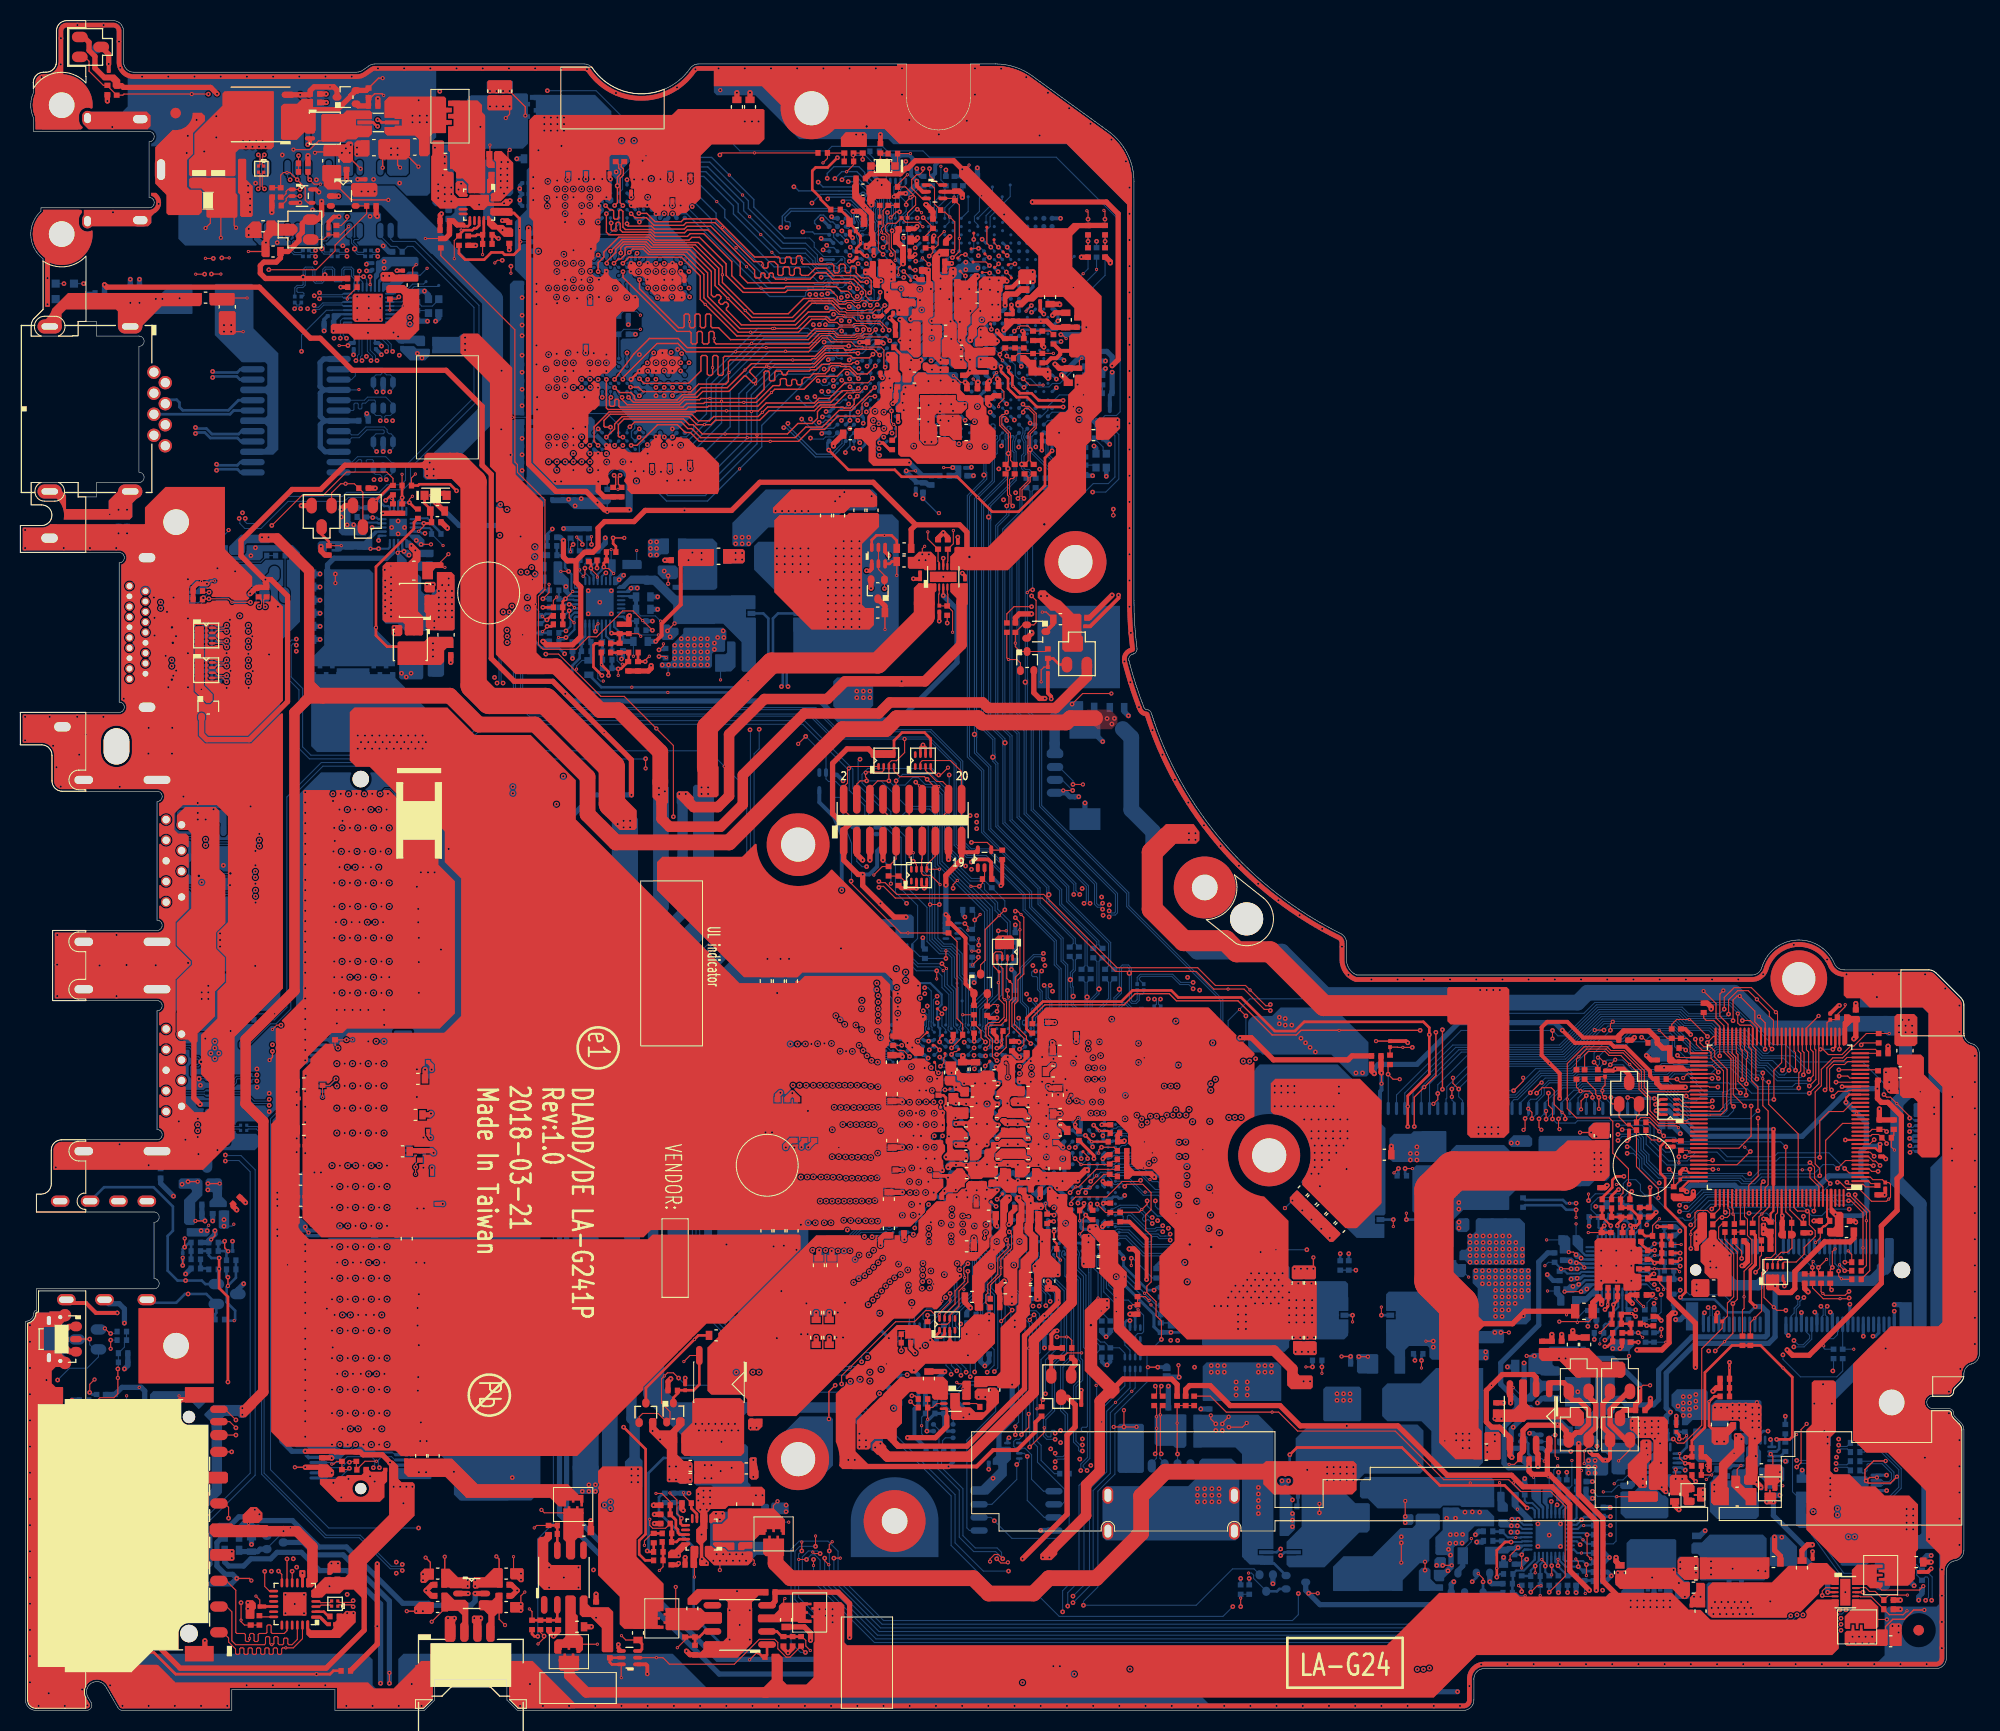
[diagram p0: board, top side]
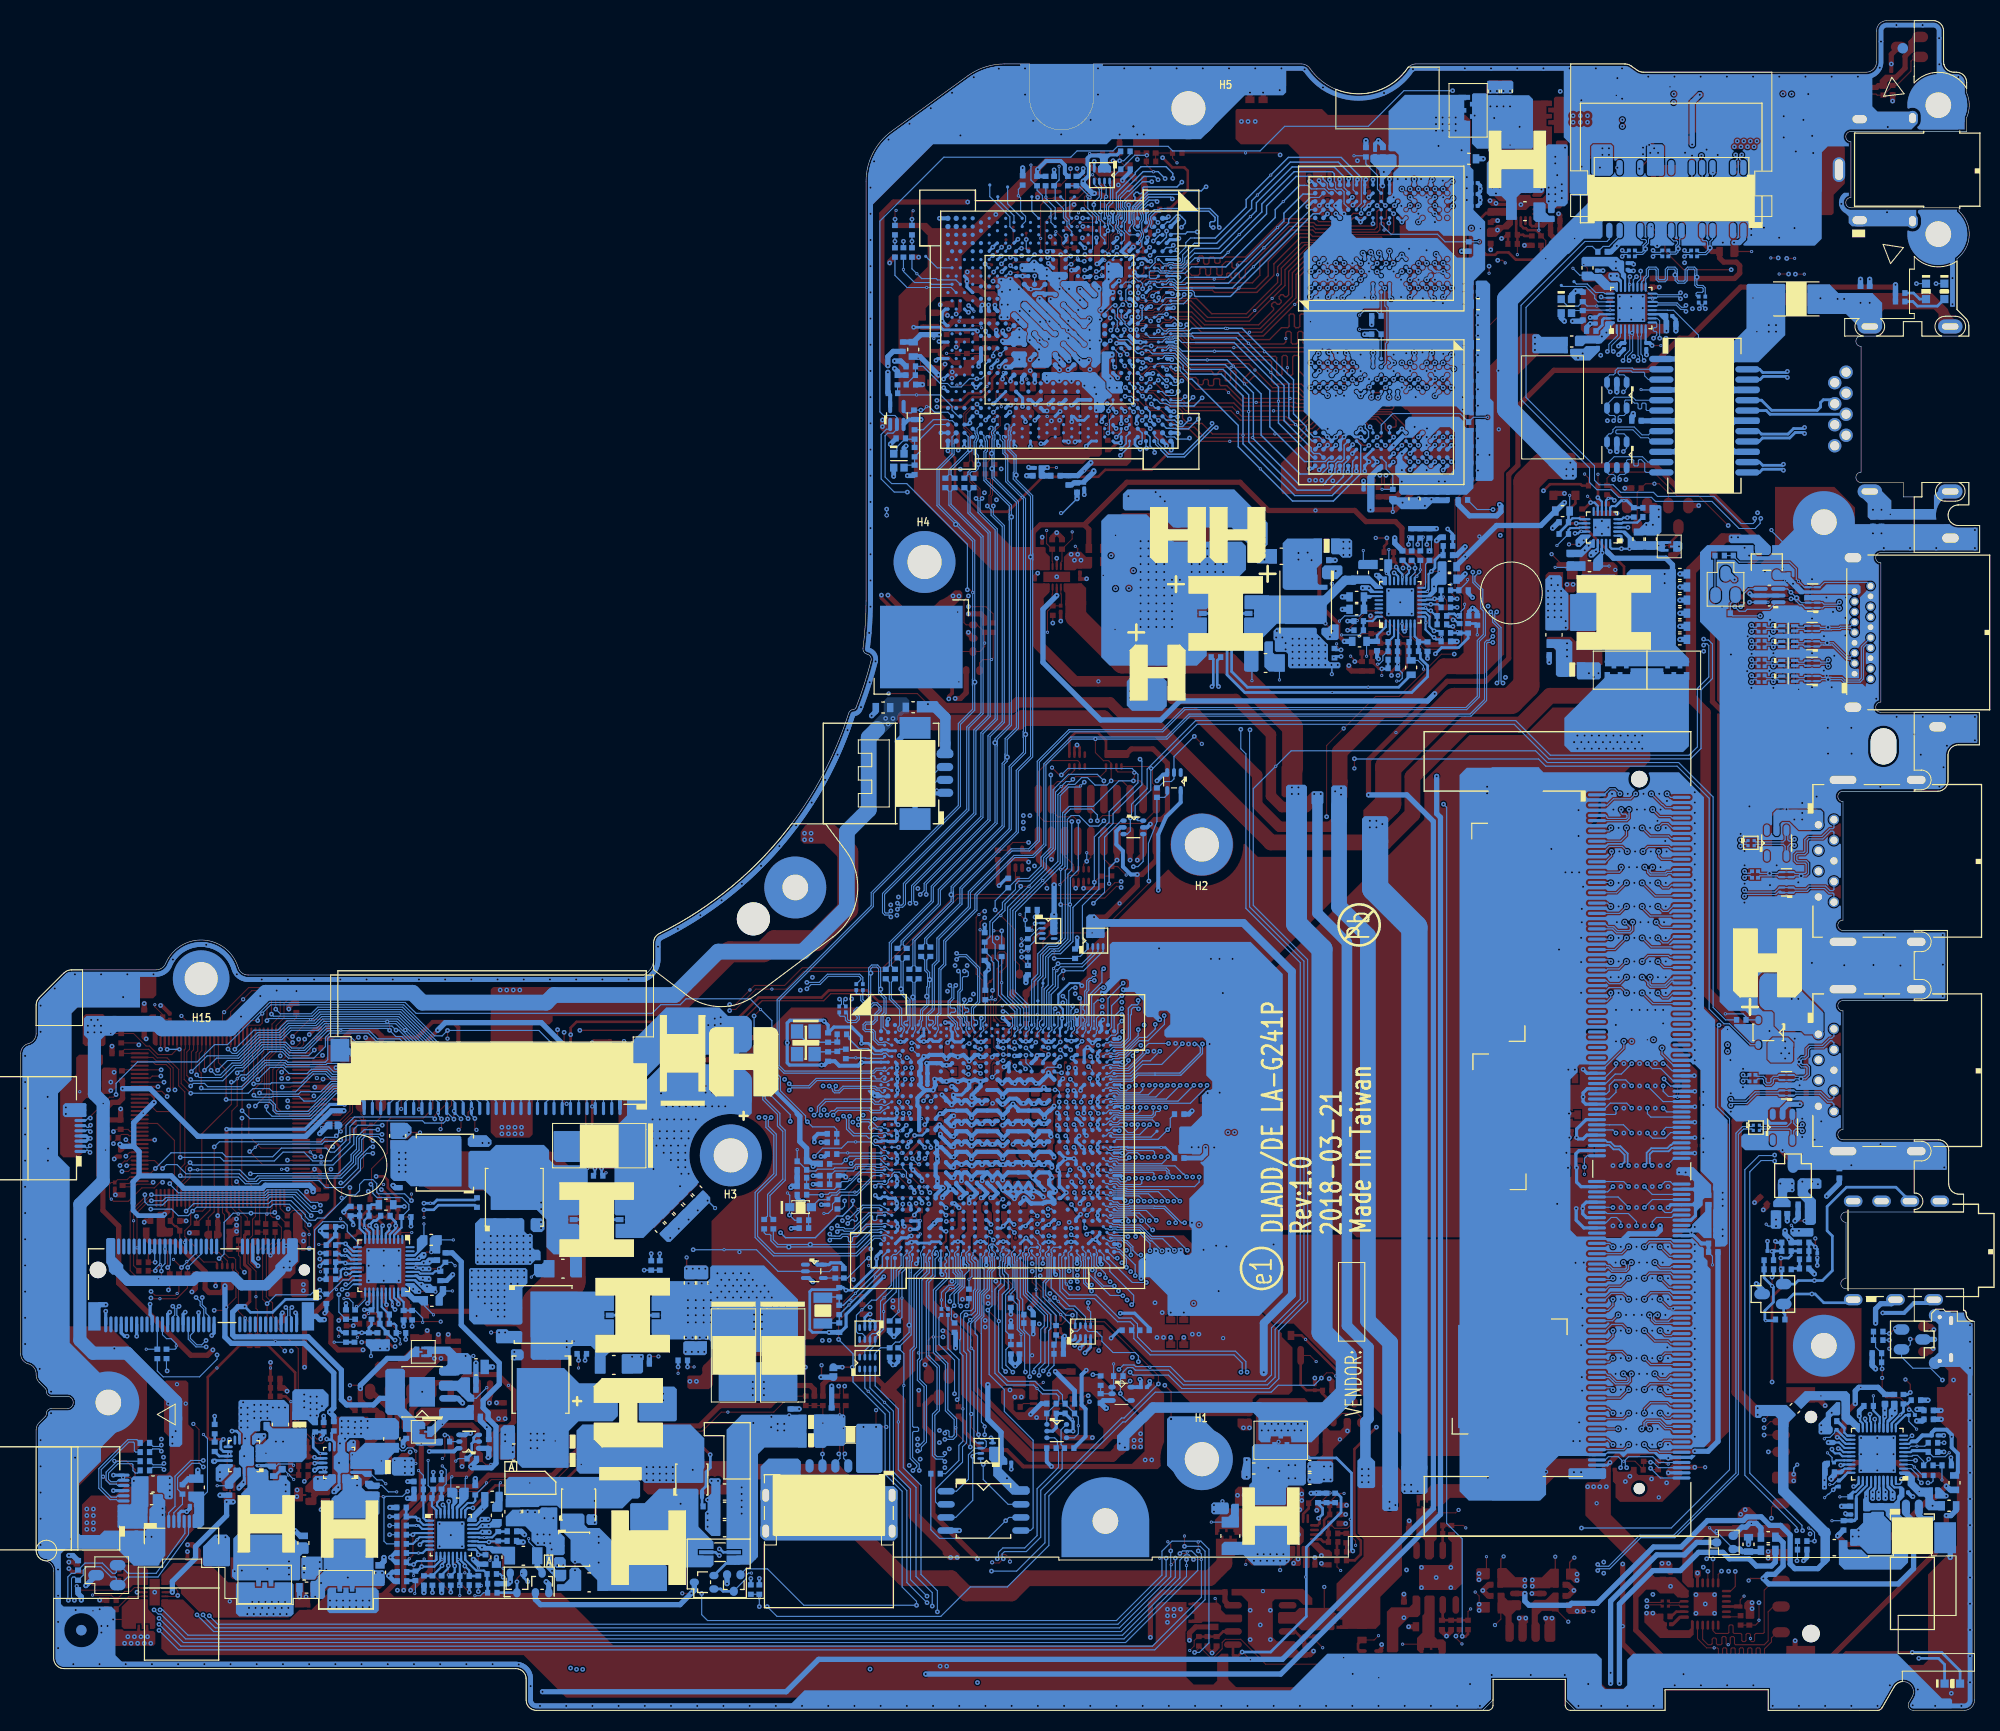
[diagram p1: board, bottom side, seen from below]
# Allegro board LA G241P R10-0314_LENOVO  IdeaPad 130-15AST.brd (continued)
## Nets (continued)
GND: C179.2 C180.2 C181.2 C182.2 C183.2 C187.1 C189.2 C190.2 C191.2 C193.2 C201.2 C202.2 C203.2 C204.2 C205.2 C216.1 C217.2 C232.2 C237.2 C238.2 C239.2 C243.2 C244.2 C271.2 C272.2 C275.2 C280.2 C281.2 C282.2 C303.2 C304.2 C305.2 C371.1 C823.2 C831.2 C832.2 C833.2 C834.2 C835.2 C836.2 C837.2 C838.1 C843.2 C844.2 C845.2 C846.2 C847.2 C848.2 C849.2 C850.2 C851.2 C852.2 C853.1 C854.1 C855.2 C856.2 C857.2 C858.2 C859.2 C860.2 C861.2 C2147.2 C2148.2 C2149.2 C2150.2 C2151.2 C2152.2 C2153.2 C2154.2 C2155.1 CA1.1 CA40.1 CA44.2 CA45.2 CA47.2 CA48.2 CA49.2 CA51.1 CA52.2 CA53.2 CA62.2 CA66.1 CA67.2 CA70.2 CA71.2 CC7.2 CC8.1 CC9.2 CC10.2 CC11.2 CC12.2 CC13.2 CC14.2 CC15.2 CC16.2 CC18.2 CC19.2 CC20.2 CC21.2 CC22.2 CC23.2 CC24.2 CC25.2 CC26.2 CC27.2 CC28.2 CC29.2 CC30.2 CC31.2 CC32.2 CC33.2 CC34.2 CC35.2 CC36.2 CC37.2 CC38.2 CC39.2 CC40.2 CC41.2 CC42.2 CC43.2 CC44.2 CC45.2 CC46.2 CC47.2 CC48.2 CC49.2 CC50.2 CC51.2 CC52.2 CC53.2 CC54.2 CC55.2 CC56.2 CC57.2 CC58.2 CC59.2 CC60.2 CC61.2 CC62.2 CC63.2 CC64.2 CC65.2 CC66.2 CC67.2 CC68.2 CC69.2 CC70.2 CC71.2 CC72.2 CC73.2 CC74.2 CC75.2 CC76.2 CC112.1 CC113.1 CC114.1 CC115.1 CC129.1 CC130.1 CC131.1 CC132.2 CC133.2 CC134.1 CC135.1 CC162.1 CD201.1 CD202.1 CD203.2 CD204.2 CD205.2 CD206.2 CD207.2 CD208.2 CD210.1 CD211.1 CD212.1 CD213.1 CD214.2 CD215.2 CD216.2 CD217.2 CD218.2 CD219.2 CD220.2 CD221.2 CD222.2 CD223.2 CD224.2 CD225.2 CD226.2 CD227.2 CD228.2 CD229.2 CD230.2 CD231.2 CH11.2 CH12.2 CL1.1 CL2.2 CL3.2 CL4.2 CL5.2 CL6.2 CL7.2 CL8.2 CL10.2 CL13.1 CL14.1 CL15.2 CL18.1 CL20.2 CL21.2 CLRP1.2 CR1.2 CR2.2 CR3.2 CR4.1 CR5.1 CR6.2 CR7.2 CV11.2 CV15.2 CV17.2 CV18.2 CV19.2 CV20.2 CV21.2 CV26.2 CV27.2 CV28.2 CV29.2 CV30.2 CV31.1 CV32.1 CV33.2 CV36.2 CV37.2 CV38.2 CV39.2 CV40.2 CV41.2 CV42.2 CV43.2 CV44.2 CV45.2 CV46.2 CV47.2 CV48.2 CV49.2 CV50.2 CV51.2 CV52.2 CV53.2 CV54.2 CV55.2 CV56.2 CV57.2 CV58.2 CV59.2 CV60.2 CV61.2 CV62.2 CV63.2 CV64.2 CV65.2 CV66.2 CV80.2 CV81.2 CV82.2 CV83.2 CV84.2 CV85.2 CV86.2 CV90.1 CV91.2 CV92.2 CV93.2 CV94.2 CV95.2 CV96.2 CV97.2 CV120.2 CV121.2 CV122.2 CV123.2 CV124.2 CV160.2 CV161.2 CV162.2 CV163.2 CV164.2 CV165.2 CV166.2 CV167.2 CV168.2 CV169.2 CV170.2 CV171.2 CV172.2 CV173.2 CV174.2 CV175.2 CV176.2 CV177.2 CV178.2 CV179.2 CV181.2 CV187.2 CV188.2 CV271.2 CV281.2 CV291.2 CV301.2 CV373.2 CV374.2 CV375.2 CV376.2 CV377.2 CV378.2 CV379.2 CV380.2 CV381.2 CV382.2 CV383.2 CV384.2 CV385.2 CV386.2 CV387.2 CV388.2 CV389.2 CV391.2 CV392.2 CV1380.2 D1.1 D281.1 D301.3 D302.2 D303.1 D304.3 D305.2 DA3.2 DA8.1 DA9.1 DH1.3 DH2.3 DH3.3 DL1.2 DL2.2 H1.1(TP-1) H2.1(TP-1) H3.1(TP-1) H4.1(TP-1) H5.1(TP-1) H6.1(TP-1) H7.1(TP-1) H8.1(TP-1) H10.1(TP-1) H12.1(TP-1) H13.1(TP-1) H15.1(TP-1) J1.1 J2.1 JBAT1.7 JBAT1.8 JBAT1.9 JBAT1.10 JBAT1.11 JBAT1.12 JDCIN1.2 JDCIN1.3 JDCIN1.4 JDCIN1.5 JDIMM1.1 JDIMM1.2 JDIMM1.5 JDIMM1.6 JDIMM1.9 JDIMM1.10 JDIMM1.14 JDIMM1.15 JDIMM1.18 JDIMM1.19 JDIMM1.22 JDIMM1.23 JDIMM1.26 JDIMM1.27 JDIMM1.30 JDIMM1.31 JDIMM1.35 JDIMM1.36 JDIMM1.39 JDIMM1.40 JDIMM1.43 JDIMM1.44 JDIMM1.47 JDIMM1.48 JDIMM1.51 JDIMM1.52 JDIMM1.56 JDIMM1.57 JDIMM1.60 JDIMM1.61 JDIMM1.64 JDIMM1.65 JDIMM1.68 JDIMM1.69 JDIMM1.72 JDIMM1.73 JDIMM1.77 JDIMM1.78 JDIMM1.81 JDIMM1.82 JDIMM1.85 JDIMM1.86 JDIMM1.89 JDIMM1.90 JDIMM1.93 JDIMM1.94 JDIMM1.98 JDIMM1.99 JDIMM1.102 JDIMM1.103 JDIMM1.106 JDIMM1.107 JDIMM1.167 JDIMM1.168 JDIMM1.171 JDIMM1.172 JDIMM1.175 JDIMM1.176 JDIMM1.180 JDIMM1.181 JDIMM1.184 JDIMM1.185 JDIMM1.188 JDIMM1.189 JDIMM1.192 JDIMM1.193 JDIMM1.196 JDIMM1.197 JDIMM1.201 JDIMM1.202 JDIMM1.205 JDIMM1.206 JDIMM1.209 JDIMM1.210 JDIMM1.213 JDIMM1.214 JDIMM1.217 JDIMM1.218 JDIMM1.222 JDIMM1.223 JDIMM1.226 JDIMM1.227 JDIMM1.230 JDIMM1.231 JDIMM1.234 JDIMM1.235 JDIMM1.238 JDIMM1.239 JDIMM1.243 JDIMM1.244 JDIMM1.247 JDIMM1.248 JDIMM1.251 JDIMM1.252 JDIMM1.261 JDIMM1.262 JEDP1.5 JEDP1.6 JEDP1.11 JEDP1.14 JEDP1.17 JEDP1.23 JEDP1.24 JEDP1.31 JEDP1.32 JFAN1.1 JFAN1.5 JFAN1.6 JHDD1.7 JHDD1.10 JHDD1.11 JHDD1.12 JHDMI1.2 JHDMI1.5 JHDMI1.8 JHDMI1.11 JHDMI1.17 JHDMI1.20 JHDMI1.21 JHDMI1.22 JHDMI1.23 JHDT1.3 JHDT1.5 JHDT1.7 JHDT1.17 JKB1.32 JKB1.33 JKB1.34 JODD2.3 JODD2.4 JODD2.11 JODD2.12 JRTC1.2 JRTC1.3 JRTC1.4 JSD1.3 JSD1.6 JSD1.12 JSD1.14 JSD1.15 JSPK1.5 JSPK1.6 JTP1.3 JTP1.7 JTP1.8 JUSB1.4 JUSB1.7 JUSB1.10 JUSB1.11 JUSB1.12 JUSB1.13 JUSB2.4 JUSB2.7 JUSB2.10 JUSB2.11 JUSB2.12 JUSB2.13 JWLAN1.1 JWLAN1.7 JWLAN1.18 JWLAN1.33 JWLAN1.39 JWLAN1.45 JWLAN1.51 JWLAN1.57 JWLAN1.63 JWLAN1.69 JWLAN1.75 JWLAN1.76 JWLAN1.77 L21.1 PC101.2 PC102.2 PC103.2 PC104.2 PC201.2 PC202.2 PC403.2 PC404.2 PC405.2 PC407.2 PC408.2 PC409.2 PC410.2 PC411.2 PC412.2 PC414.2 PC415.2 PC416.2 PC417.2 PC419.2 PC420.2 PC421.2 PC422.2 PC423.2 PC424.2 PC425.2 PC426.2 PC427.2 PC428.2 PC429.2 PC451.2 PC501.2 PC502.2 PC503.2 PC504.2 PC506.2 PC507.2 PC508.1 PC509.2 PC510.2 PC511.2 PC512.2 PC513.2 PC514.2 PC515.2 PC516.2 PC517.2 PC518.2 PC519.2 PC601.2 PC602.2 PC604.2 PC605.2 PC606.2 PC609.2 PC610.2 PC611.2 PC612.2 PC613.2 PC614.2 PC705.2 PC715.2 PC748.2 PC751.2 PC752.2 PC757.1 PC760.2 PC761.2 PC762.2 PC765.2 PC767.2 PC768.2 PC769.2 PC775.2 PC776.2 PC801.2 PC802.2 PC803.2 PC806.2 PC807.2 PC808.2 PC811.1 PC815.2 PC816.2 PC817.2 PC819.2 PC822.2 PC823.2 PC824.2 PC827.2 PC828.2 PC831.2 PC832.2 PC833.2 PC834.2 PC835.2 PC836.2 PC837.2 PC902.2 PC903.2 PC904.2 PC905.2 PC906.2 PC908.2 PC909.2 PC910.2 PC911.2 PC912.2 PC913.2 PC943.2 PC944.2 PC986.1 PC987.2 PC988.2 PC1001.2 PC1002.2 PC1003.2 PC1004.2 PC1005.2 PC1006.2 PC1007.2 PC1008.2 PC1009.2 PC1010.2 PC1012.2 PC1013.1 PC1014.1 PC1015.2 PC1016.2 PC1017.2 PC1018.2 PC1019.2 PC1020.2 PC1021.2 PC1022.2 PC1023.2 PC1025.2 PC1027.2 PC1028.2 PC1029.1 PC1030.2 PC1031.2 PC1032.1 PC1033.2 PC1034.2 PC1035.2 PC1037.2 PC1038.2 PC1039.2 PC1040.2 PC1041.2 PC1042.2 PC1043.2 PC1045.2 PC1046.2 PC1047.2 PC1048.2 PC1049.2 PC1050.2 PC1051.2 PC1052.2 PC1053.2 PC1054.2 PC1055.2 PC1056.2 PC2001.2 PC2002.2 PC2003.2 PC2006.2 PC2007.2 PC2008.2 PC2009.2 PC2010.2 PC9001.2 PC9002.2 PC9003.2 PC9004.2 PC9005.2 PC9006.2 PC9007.2 PC9008.2 PC9009.2 PC9010.2 PC9011.2 PC9012.2 PC9013.2 PC9014.2 PC9015.2 PC9016.2 PC9017.2 PC9018.2 PC9019.2 PC9020.2 PC9029.2 PC9030.2 PC9031.2 PC9033.2 PC9034.2 PC9038.2 PC9039.2 PC9040.2 PC9041.2 PC9042.2 PC9043.2 PC9044.2 PC9045.2 PC9056.2 PC9057.2 PC9058.2 PC9059.2 PC9060.2 PC9062.2 PC9063.2 PC9064.2 PC9065.2 PC9067.2 PC9068.2 PC9070.2 PC9071.2 PC9082.2 PC9084.2 PC9085.2 PC9086.2 PC9088.2 PC9089.2 PC11213.2 PC11214.2 PC11215.1 PC11216.2 PC11217.2 PC11224.2 PC11225.2 PC11226.2 PC11227.1 PD501.2 PQ502.1 PQ502.2 PQ502.3 PQ706.1 PQ706.2 PQ706.3 PQ711.3 PQ741.3 PQ802.1 PQ802.2 PQ802.3 PQ804.1 PQ804.2 PQ804.3 PQ1001.3 PQ1001.4 PQ1001.5 PR107.2 PR404.2 PR412.2 PR452.2 PR509.2 PR601.2 PR609.2 PR610.2 PR727.2 PR731.2 PR732.2 PR738.1 PR751.2 PR752.2 PR753.2 PR755.2 PR757.2 PR820.2 PR823.1 PR828.2 PR834.2 PR836.1 PR903.2 PR907.2 PR1007.1 PR1019.2 PR1023.1 PR1459.2 PR2002.2 PR2006.2 PR2007.2 PR2008.2 PU401.7 PU401.8 PU401.18 PU401.21 PU402.7 PU402.8 PU402.18 PU402.21 PU501.1 PU501.3 PU501.14 PU501.21 PU601.7 PU601.8 PU601.18 PU601.21 PU703.33 PU801.41 PU901.7 PU901.8 PU901.18 PU901.21 PU903.2 PU903.9 PU1001.33 PU2001.8 PU2001.9 PU2002.8 PU2002.9 Q83.3 Q84.3 Q401.1 Q401.4 Q411.3 Q412.3 QC22.4 QH17.3 QV11.3 QV17.3 QV18.3 QV21.1 QV21.4 R202.2 R205.1 R209.2 R210.1 R251.1 R930.2 R944.1 R948.1 R949.1 RA43.1 RA60.1 RA61.1 RA65.1 RA66.1 RC2.2 RC16.2 RC17.2 RC22.2 RC24.2 RC26.2 RC38.1 RC39.1 RC40.1 RC49.1 RC52.2 RC53.2 RC54.2 RC76.2 RC78.2 RC80.2 RC82.2 RC84.2 RC86.2 RC88.2 RC94.1 RC100.2 RC108.2 RC112.1 RC134.1 RC157.1 RC159.1 RC160.1 RC161.1 RD205.2 RD206.2 RD207.2 RD209.1 RD210.1 RH137.2 RH138.1 RL4.1 RL5.1 RL6.1 RL7.1 RL9.1 RL10.2 RP4.4 RPC2.1 RPC2.2 RPC2.3 RPC2.4 RPC3.6 RPC3.7 RPC5.2 RPC5.3 RPC5.4 RPC9.1 RPC9.2 RPC9.3 RPC11.4 RPC12.2 RPC12.4 RPC13.1 RPC13.2 RPV34.4 RR1.2 RV2.1 RV4.2 RV9.2 RV12.2 RV13.2 RV16.2 RV17.1 RV21.1 RV29.1 RV34.2 RV35.2 RV38.2 RV39.1 RV40.1 RV41.1 RV59.1 RV83.2 RV88.1 RV89.1 RV116.2 RV117.2 RV118.2 RV119.2 RV120.2 RV121.2 RV151.1 RV163.2 RV369.2 RV379.2 RV3152.1 RV3153.2 SW1.1 SW1.3 SW1.4 SW1.5 SW1.6 SW1.7 U11.11 U11.24 U11.35 U11.94 U11.113 U18.5 U18.9 U202.2 U203.3 U282.1 U301.2 U381.11 U381.15 U1895V.11 U1895V.15 UA1.41 UC1.A2 UC1.A8 UC1.A13 UC1.A18 UC1.A23 UC1.A32 UC1.A35 UC1.A39 UC1.AA1 UC1.AA2 UC1.AA3 UC1.AA5 UC1.AA10 UC1.AA39 UC1.AC3 UC1.AC7 UC1.AC10 UC1.AC11 UC1.AC13 UC1.AC15 UC1.AC17 UC1.AC19 UC1.AC21 UC1.AC23 UC1.AC25 UC1.AC27 UC1.AC29 UC1.AC31 UC1.AC38 UC1.AC39 UC1.AC41 UC1.AE3 UC1.AE5 UC1.AE10 UC1.AE39 UC1.AG3 UC1.AG7 UC1.AG10 UC1.AG11 UC1.AG13 UC1.AG15 UC1.AG17 UC1.AG19 UC1.AG21 UC1.AG23 UC1.AG25 UC1.AG27 UC1.AG29 UC1.AG31 UC1.AG39 UC1.AG41 UC1.AJ3 UC1.AJ5 UC1.AJ10 UC1.AJ29 UC1.AJ31 UC1.AJ39 UC1.AL1 UC1.AL2 UC1.AL3 UC1.AL7 UC1.AL10 UC1.AL31 UC1.AL39 UC1.AL41 UC1.AM25 UC1.AM27 UC1.AM29 UC1.AM31 UC1.AN3 UC1.AN5 UC1.AN39 UC1.AR3 UC1.AR11 UC1.AR19 UC1.AR23 UC1.AR27 UC1.AR31 UC1.AR39 UC1.AR41 UC1.AU3 UC1.AU9 UC1.AU21 UC1.AU25 UC1.AU29 UC1.AU39 UC1.AW3 UC1.AW5 UC1.AW7 UC1.AW9 UC1.AW11 UC1.AW13 UC1.AW15 UC1.AW17 UC1.AW19 UC1.AW21 UC1.AW23 UC1.AW25 UC1.AW27 UC1.AW29 UC1.AW31 UC1.AW33 UC1.AW35 UC1.AW37 UC1.AW39 UC1.AW41 UC1.AY1 UC1.AY11 UC1.B8 UC1.B13 UC1.B32 UC1.B39 UC1.BA7 UC1.BA11 UC1.BA15 UC1.BA19 UC1.BA23 UC1.BA31 UC1.BA35 UC1.BA39 UC1.C3 UC1.C5 UC1.C7 UC1.C9 UC1.C11 UC1.C13 UC1.C15 UC1.C17 UC1.C19 UC1.C21 UC1.C23 UC1.C25 UC1.C27 UC1.C29 UC1.C31 UC1.C33 UC1.C35 UC1.C37 UC1.C39 UC1.C41 UC1.E1 UC1.E2 UC1.E3 UC1.E21 UC1.E25 UC1.E29 UC1.E35 UC1.E38 UC1.E39 UC1.G1 UC1.G2 UC1.G3 UC1.G11 UC1.G13 UC1.G23 UC1.G27 UC1.G31 UC1.G35 UC1.G37 UC1.G39 UC1.G41 UC1.H23 UC1.J3 UC1.J8 UC1.J39 UC1.L3 UC1.L8 UC1.L13 UC1.L19 UC1.L21 UC1.L23 UC1.L25 UC1.L27 UC1.L29 UC1.L31 UC1.L39 UC1.L41 UC1.N1 UC1.N2 UC1.N3 UC1.N39 UC1.R3 UC1.R11 UC1.R13 UC1.R15 UC1.R17 UC1.R19 UC1.R21 UC1.R23 UC1.R25 UC1.R27 UC1.R29 UC1.R31 UC1.R39 UC1.R41 UC1.U1 UC1.U2 UC1.U3 UC1.U10 UC1.U39 UC1.W3 UC1.W10 UC1.W11 UC1.W13 UC1.W15 UC1.W17 UC1.W19 UC1.W21 UC1.W23 UC1.W25 UC1.W27 UC1.W29 UC1.W31 UC1.W39 UC1.W41 UC2.4 UC21.3 UC22.3 UC23.3 UC24.3 UC25.2 UC26.4 UH1.2 UL2.33 UR1.24 UR1.25 UV1.A3 UV1.A30 UV1.AA11 UV1.AA13 UV1.AA16 UV1.AA27 UV1.AB6 UV1.AB10 UV1.AB15 UV1.AB24 UV1.AB32 UV1.AC9 UV1.AC17 UV1.AC24 UV1.AC26 UV1.AC27 UV1.AD6 UV1.AD8 UV1.AD25 UV1.AD32 UV1.AE7 UV1.AE14 UV1.AE27 UV1.AF32 UV1.AG12 UV1.AG27 UV1.AH10 UV1.AH28 UV1.AH32 UV1.B6 UV1.B8 UV1.B10 UV1.B12 UV1.B14 UV1.B16 UV1.B18 UV1.B20 UV1.B22 UV1.B24 UV1.B26 UV1.C1 UV1.C32 UV1.E28 UV1.F2 UV1.F6 UV1.F8 UV1.F10 UV1.F12 UV1.F14 UV1.F16 UV1.F18 UV1.F20 UV1.F22 UV1.F24 UV1.F26 UV1.G8 UV1.G10 UV1.G27 UV1.G31 UV1.H2 UV1.H6 UV1.H14 UV1.H17 UV1.H20 UV1.J7 UV1.J27 UV1.J31 UV1.K2 UV1.K6 UV1.K11 UV1.K22 UV1.K28 UV1.K32 UV1.L27 UV1.M6 UV1.M12 UV1.M32 UV1.N11 UV1.N13 UV1.N16 UV1.N18 UV1.N21 UV1.N25 UV1.N27 UV1.P6 UV1.P9 UV1.P25 UV1.P32 UV1.R11 UV1.R12 UV1.R15 UV1.R17 UV1.R20 UV1.R27 UV1.T6 UV1.T11 UV1.T13 UV1.T16 UV1.T18 UV1.T21 UV1.T25 UV1.T32 UV1.U9 UV1.U15 UV1.U17 UV1.U20 UV1.U25 UV1.U27 UV1.V11 UV1.V13 UV1.V16 UV1.V18 UV1.V32 UV1.W25 UV1.W26 UV1.W27 UV1.Y10 UV1.Y15 UV1.Y17 UV1.Y20 UV1.Y25 UV1.Y32 UV2.3 UV7.A1 UV7.A3 UV7.A12 UV7.A14 UV7.B5 UV7.B10 UV7.C1 UV7.C3 UV7.C4 UV7.C11 UV7.C12 UV7.C14 UV7.D10 UV7.E1 UV7.E3 UV7.E12 UV7.E14 UV7.F5 UV7.F10 UV7.G5 UV7.G10 UV7.H1 UV7.H2 UV7.H13 UV7.H14 UV7.K1 UV7.K2 UV7.K13 UV7.K14 UV7.L5 UV7.L10 UV7.M5 UV7.M10 UV7.N1 UV7.N3 UV7.N12 UV7.N14 UV7.P10 UV7.R1 UV7.R3 UV7.R4 UV7.R11 UV7.R12 UV7.R14 UV7.T5 UV7.T10 UV7.U1 UV7.U3 UV7.U12 UV7.U14 UV8.A1 UV8.A3 UV8.A12 UV8.A14 UV8.B5 UV8.B10 UV8.C1 UV8.C3 UV8.C4 UV8.C11 UV8.C12 UV8.C14 UV8.D10 UV8.E1 UV8.E3 UV8.E12 UV8.E14 UV8.F5 UV8.F10 UV8.G5 UV8.G10 UV8.H1 UV8.H2 UV8.H13 UV8.H14 UV8.K1 UV8.K2 UV8.K13 UV8.K14 UV8.L5 UV8.L10 UV8.M5 UV8.M10 UV8.N1 UV8.N3 UV8.N12 UV8.N14 UV8.P10 UV8.R1 UV8.R3 UV8.R4 UV8.R11 UV8.R12 UV8.R14 UV8.T5 UV8.T10 UV8.U1 UV8.U3 UV8.U12 UV8.U14 YL1.2 YL1.4 YV2.2 YV2.4
GNDA: CA43.2 CA50.2 CA55.2 CA56.1 CA58.2 CA59.1 CA60.2 CA61.1 CA63.2 CA64.1 CA65.2 CA68.2 H9.1(TP-1) JHP1.5 JHP1.7 JSD1.13 RA44.1 RA47.2 RA57.1 RA60.2 RA61.2 RA62.2 RA65.2 RA66.2 UA1.19 UA1.31
PVCC_RT3661: PC801.1 PR801.1 PU801.34
PVCC_VGA: PC1043.1 PR1033.1 PU1001.27
VBAT_CHG: PR745.1 PU703.26
VCC_5V: PC419.1 PU402.16 PU402.17
VCC_RT3661: PC822.1 PR837.1 PU801.17
VCC_VGA: PC1047.1 PR1029.1 PU1001.5 PU1001.6 PU1001.14
VCCSENSE_VGA: PR1024.1 UV1.AC20
VDD_CHG: PC768.1 PR741.1 PR749.1 PR750.1 PR760.1 PU703.19
VDD_DDR: PC516.1 PR502.1 PR504.2 PU501.11
VDDIO_RT3661: PC816.1 PR818.1 PU801.22
VDDIO_VGA: PC1002.1 PR1005.2 PU1001.19
VDDP_CHG: PC769.1 PR760.2 PU703.20
VDDR4: UV1.U12 UV1.V12 UV1.Y12
VIN_0.775VALW: PC11215.2 PJ1000.2 PR1458.1 PU903.1
VIN_RT3661: PC808.1 PR806.2 PU801.28
VSS_MECH: UV1.A32 UV1.AM1 UV1.AM32
VSSSENSE_VGA: PR1014.1 UV1.AD20
32K_X1: CC11.1 RC87.2 UC1.BA2 YC32.1
32K_X2: CC12.1 RC87.1 UC1.AY2 YC32.2
48M_X1: RC104.2 UC1.F2
48M_X1_R: CC15.1 RC103.1 RC104.1 YC48.1
48M_X2: RC105.2 UC1.F1
48M_X2_R: CC16.1 RC103.2 RC105.1 YC48.3
+0.775MOS: QC22.1 R944.2 UC26.2 UC26.5
+APU_CORE: PC817.1 PC9001.1 PC9002.1 PC9003.1 PC9004.1 PC9005.1 PC9006.1 PC9007.1 PC9008.1 PC9009.1 PC9010.1 PC9029.1 PC9030.1 PC9031.1 PC9033.1 PC9034.1 PC9038.1 PC9056.1 PC9057.1 PC9058.1 PC9059.1 PC9060.1 PC9062.1 PC9063.1 PC9084.1 PC9085.1 PC9086.1 PL803.4 PR816.1 UC1.AA25 UC1.AA27 UC1.AA29 UC1.AA31 UC1.K21 UC1.K23 UC1.K25 UC1.K27 UC1.K29 UC1.K31 UC1.N21 UC1.N23 UC1.N25 UC1.N27 UC1.N29 UC1.N31 UC1.U23 UC1.U25 UC1.U27 UC1.U29 UC1.U31
+APU_CORE_NB: CC72.1 CC73.1 CC74.1 CC75.1 CC129.2 PC815.1 PC9011.1 PC9012.1 PC9013.1 PC9014.1 PC9015.1 PC9016.1 PC9017.1 PC9018.1 PC9019.1 PC9020.1 PC9039.1 PC9040.1 PC9041.1 PC9042.1 PC9043.1 PC9044.1 PC9045.1 PC9064.1 PC9065.1 PC9067.1 PC9068.1 PC9070.1 PC9071.1 PC9082.1 PC9088.1 PC9089.1 PC11213.1 PL804.4 PR812.2 QC18.1 UC1.AA11 UC1.AA13 UC1.AA15 UC1.AA17 UC1.AA19 UC1.AA21 UC1.AA23 UC1.AE11 UC1.AE13 UC1.AE15 UC1.AE17 UC1.AE19 UC1.AE21 UC1.AE23 UC1.AE25 UC1.AE27 UC1.AE29 UC1.AE31 UC1.E9 UC1.E11 UC1.E13 UC1.E15 UC1.E17 UC1.E19 UC1.G7 UC1.J7 UC1.K11 UC1.K13 UC1.K15 UC1.K17 UC1.K19 UC1.L7 UC1.L10 UC1.L15 UC1.L17 UC1.N7 UC1.N11 UC1.N13 UC1.N15 UC1.N17 UC1.N19 UC1.R7 UC1.U7 UC1.U11 UC1.U13 UC1.U15 UC1.U17 UC1.U19 UC1.U21 UC1.W7 UC26.3
+BIF_VDDC: CV80.1 CV122.1 CV181.1 RV31.2 UV1.R21 UV1.U21
+CARD_3V3: CR6.1 CR7.1 JSD1.4 UR1.7
+CHGRTC: PD101.2 PR107.1 PR108.1
+CHGRTC_R: JRTC1.1 PR109.2
+EC_VCCA: C184.1 L20.2 PR206.1 R364.1 R365.1 R368.1 U11.67
+FBA_VREFC0: CV391.1 CV392.1 RV379.1 RV380.2 UV7.J14 UV8.J14
+IOVDD_CODEC: CA48.1 RA6.1 UA1.8
+LAN_SROUT1.05: CL15.1 RL11.1 UL2.24
+LAN_VDD: CL4.1 CL5.1 CL6.1 CL7.1 CL8.1 RL11.2 UL2.3 UL2.8 UL2.22 UL2.30
+LAN_VDDREG: CL10.1 RL1.2 UL2.23
+LCDVDD: R211.1 U202.1
+LCDVDD_CONN: C201.1 JEDP1.18 JEDP1.20 R211.2
+LEDVDD: C205.1 JEDP1.28 JEDP1.30 R203.1
+LINE1-VREFO-R: RA36.1 RA49.1 UA1.24
+MIC2-VREFO: RA54.1 RA58.1 UA1.23
+MPLL_PVDD: CV81.1 CV82.1 CV124.1 LV6.2 UV1.L8
+MVREFDA: CV94.1 RV33.2 RV34.1 UV1.K26
+MVREFSA: CV95.1 RV32.2 RV35.1 UV1.J26
+RTC_BATT: CLRP1.1 RC111.2 RC113.1 UC1.AM11
+RTCBATT: CC19.1 PD101.1 UC25.1
+RTCBATT_R: CC18.1 RC113.2 UC25.3
+SPLL_PVDD: CV84.1 CV85.1 CV86.1 LV7.2 UV1.H7
+SPLL_VDDC: CV91.1 CV92.1 CV93.1 LV8.2 UV1.H8
+TP_VCC: C280.1 JTP1.6 R279.2
+TSVDD: CV19.1 CV20.1 CV21.1 LV2.2 UV1.AD17
+USB3_VCCA: C303.1 C304.1 D302.5 D305.5 JUSB1.1 JUSB2.1 U301.1
+V_DAC: CL18.2 TL1.1 TL1.4 TL1.7 TL1.10
+VGA_CORE: PC1001.1 PC1004.1 PC1005.1 PC1007.1 PC1009.1 PC1012.1 PC1015.1 PC1017.1 PC1018.1 PC1019.1 PC1022.1 PC1023.1 PC1025.1 PC1027.1 PC1028.1 PC1029.2 PC1030.1 PC1031.1 PC1033.1 PC1035.1 PC1037.1 PC1038.1 PC1039.1 PC1040.1 PC1041.1 PC1045.1 PC1046.1 PC1050.1 PC1051.1 PC1052.1 PC1053.1 PC1054.1 PC1055.1 PC1056.1 PL1001.4 PR1027.2 RV45.2 UV1.AA12 UV1.AA15 UV1.AB11 UV1.AB12 UV1.AB13 UV1.AC11 UV1.AC13 UV1.AC14 UV1.M11 UV1.M13 UV1.M15 UV1.M16 UV1.M17 UV1.M18 UV1.M20 UV1.M21 UV1.N12 UV1.N15 UV1.N17 UV1.N20 UV1.R13 UV1.R16 UV1.R18 UV1.T10 UV1.T12 UV1.T15 UV1.T17 UV1.T20 UV1.U10 UV1.U11 UV1.U13 UV1.U16 UV1.U18 UV1.V15 UV1.V17 UV1.V20 UV1.V21 UV1.W9 UV1.W10 UV1.Y9 UV1.Y13 UV1.Y16 UV1.Y18 UV1.Y21
+VL: PJP404.2 R376.2 R378.2 U381.4 U1895V.4
ACIN_CHG: PC715.1 PR729.2 PR732.1 PU703.1
ACLIM_CHG: PR749.2 PR751.1 PR779.2 PU703.16
ADP_I: PC748.1 PR780.1 U11.65
AGPIO3: RC81.2 RC82.1 UC1.AJ7
AGPIO11: RC69.2 UC1.AJ8
AMON_ISL95520: PR780.2 PU703.6
APDIN: JDCIN1.1 PF101.1
APU_ALERT#: RPC1.3 UC1.A30
APU_BT_OFF#: R247.2 RC41.2 RC129.2
APU_DBRDY: JHDT1.14 UC1.A26
APU_DBREQ#: JHDT1.16 RPC4.4 UC1.A25
APU_DGPU_PWRGD: RC164.1 UC1.BA16
APU_DP1_AUXN: QH15.4 RH30.2 UC1.H17
APU_DP1_AUXP: QH15.1 RH29.2 UC1.G17
APU_DP1_HPD: QH5.3 RH137.1 UC1.D17
APU_DP1_N0: CH20.1 UC1.B14
APU_DP1_N1: CH18.1 UC1.B15
APU_DP1_N2: CH16.1 UC1.B16
APU_DP1_N3: CH14.1 UC1.B17
APU_DP1_P0: CH19.1 UC1.A14
APU_DP1_P1: CH17.1 UC1.A15
APU_DP1_P2: CH15.1 UC1.A16
APU_DP1_P3: CH13.1 UC1.A17
APU_ENVDD: R202.1 RC20.2 U202.4
APU_FCH_PWRGD_R: RC63.2 RC64.2 UC1.AE2 UC24.4
APU_INVT_PWM: JEDP1.8 RC21.1 UC21.4
APU_MA_VREFDQ: T1.1(TP-1) UC1.Y41
APU_PCIE_RST#: R250.2 RC73.2 UC23.4 UL2.19 UV2.2
APU_PCIE_RST#_R: RC71.1 UC1.AE4
APU_PCIE_WAKE#: T31.1(TP-1) UC1.AE7
APU_PWRGD: CC114.2 JHDT1.10 PR835.1 PU801.18 RC13.2 UC1.G25
APU_RST#: CC115.2 JHDT1.12 RC14.2 RC30.1 UC1.D29 UC22.4
APU_RST#_EC: RC30.2 U11.25 UC22.2
APU_SCLK0: JDIMM1.253 RC163.1 UC1.AY33
APU_SDATA0: JDIMM1.254 RC162.1 UC1.BA32
APU_SIC: QC2.4 RPC1.4 UC1.B30
APU_SID: QC2.1 RPC1.2 UC1.B29
APU_SPI_CLK: RC102.2 UC1.AY17
APU_SPI_CLK_R: RC102.1 UC2.6
APU_SPI_CS1#: RPC11.6 UC1.AY21 UC2.1
APU_SPI_CS2#: RPC11.5 UC1.AY19
APU_SPI_HOLD#: RPC11.8 UC1.BA18 UC2.7
APU_SPI_MISO: UC1.BA17 UC2.2
APU_SPI_MOSI: UC1.AY20 UC2.5
APU_SPI_WP#: RPC11.7 UC1.BA20 UC2.3
APU_SPKR: RA55.1 UC1.AP29
APU_SVC: PR833.2 RPC14.2 UC1.E27
APU_SVD: PR829.2 RPC14.3 UC1.D27
APU_SVT: PC819.1 PR824.2 RPC14.1 UC1.H27
APU_TCK: JHDT1.2 RPC4.1 UC1.B27
APU_TDI: JHDT1.6 RPC4.3 UC1.B25
APU_TDO: JHDT1.8 UC1.A27
APU_TEST0: RC34.2 RC38.2 UC1.AF2
APU_TEST1: RC36.2 RC39.2 UC1.AE1
APU_TEST2: RC35.2 RC40.2 UC1.AC8
APU_TEST4: T2.1(TP-1) UC1.H29
APU_TEST5: T3.1(TP-1) UC1.G29
APU_TEST6: T4.1(TP-1) UC1.H25
APU_TEST9: T5.1(TP-1) UC1.R32
APU_TEST10: T6.1(TP-1) UC1.N32
APU_TEST14: RPC2.5 T7.1(TP-1) UC1.G21
APU_TEST15: T8.1(TP-1) UC1.H21
APU_TEST16: RPC2.6 T9.1(TP-1) UC1.D23
APU_TEST17: RPC2.7 T10.1(TP-1) UC1.E23
APU_TEST18: JHDT1.20 RPC3.2 T11.1(TP-1) UC1.A28
APU_TEST19: JHDT1.18 RPC3.3 T12.1(TP-1) UC1.B28
APU_TEST28_H: T13.1(TP-1) UC1.N8
APU_TEST28_L: T14.1(TP-1) UC1.N10
APU_TEST31: T16.1(TP-1) UC1.H31
APU_TEST36: RC25.1 RC26.1 UC1.D25
APU_TEST41: T18.1(TP-1) UC1.B31
APU_TMS: JHDT1.4 RPC4.2 UC1.B26
APU_TRST#: CC7.1 RC27.1 RPC3.4 UC1.A29
APU_TRST#_R: JHDT1.9 RC27.2
APU_VDD_RUN_FB_L: PR827.1 UC1.D33
APU_VDD_SEN: PR814.1 T15.1(TP-1) UC1.D31
APU_VDDNB_SEN: PR808.2 T19.1(TP-1) UC1.E33
APU_VDDP_RUN_FB_H: PR2222.2 T61.1(TP-1) UC1.AM21
APU_WL_OFF#: R248.2 RC130.2
ASGATE_CHG: PR762.2 PU703.30
ASGATE_CHG_R: PQ707.1 PQ712.4 PQ740.4 PR762.1
B+: PJ602.1 PJ901.1 PL301.1 PL401.1 PL403.1 PL501.1 PL801.2 PL802.2 PL1002.2 PQ705.5 PR402.1 PR703.4 R203.2
B+_1.35V: PC904.1 PC905.1 PC906.1 PJ901.2 PU901.2 PU901.3 PU901.4 PU901.5
BA: PD703.2 PQ710.1
BATT_CHG_LED#: LED3.1 U11.90
BATT_LOW_LED#: LED4.1 U11.93
BEEP#: RA41.1 U11.23
BEEP_N: CA43.1 CA69.2 RA41.2 RA47.1 RA55.2
BGATE_CHG: PC779.1 PQ705.4 PU703.25
BKOFF#: R204.1 U11.105 U203.1
BP_0: RV82.1 UV1.U1
BP_1: RV81.1 UV1.U3
BST1_APU: PR803.1 PU801.38
BST1_APU_R: PC804.1 PR803.2
BST1_VGA: PR1031.1 PU1001.23
BST1_VGA_R: PC1044.1 PR1031.2
BST_1.35V: PR901.1 PU901.1
BST_1.35V_R: PC901.1 PR901.2
BST_1V: PR606.1 PU601.1
BST_1V_R: PC603.1 PR606.2
BST_3V: PR401.1 PU401.1
BST_3V_R: PC401.1 PR401.2
BST_5V: PR408.1 PU402.1
BST_5V_R: PC418.1 PR408.2
BST_CHG: PR771.1 PU703.24
BST_CHG_R: PC721.1 PR771.2
BST_DDR: PR501.2 PU501.18
BST_DDR_R: PC505.1 PR501.1
BST_NB: PR841.1 PU801.30
BST_NB_R: PC825.1 PR841.2
BT_DISABLE_R: JWLAN1.54 R247.1
BT_OFF#: RC129.1 UC1.AY14
CAPS_LED#: C271.1 R274.1 U11.91
CAPS_LED#_R: JKB1.2 R274.2
CCLIM_CHG: PR750.2 PR752.1 PU703.11
CLK_PCIE_LAN: UC1.M2 UL2.15
CLK_PCIE_LAN#: UC1.M1 UL2.16
CLK_PCIE_WLAN: JWLAN1.47 UC1.K2
CLK_PCIE_WLAN#: JWLAN1.49 UC1.K1
CLK_PEG_VGA: UC1.H2 UV1.AK30
CLK_PEG_VGA#: UC1.H1 UV1.AK32
CLK_REQ3#: RPC12.5 UC1.AP31
CMOS_ON#: R201.1 U11.34
CMOS_ON#_R: C204.1 Q201.2 R201.2
CMSRC_CHG: PR763.2 PU703.29
COMP_APU: PC813.2 PR807.2 PU801.5
COMP_CHG: PC751.1 PR754.1 PU703.10
COMP_NB: PC809.1 PR810.1 PU801.27
COMP_VGA: PC1024.2 PR1028.2 PU1001.3
CORE_NB_GATE: QC18.2 QC19.2 RC150.2 UC26.1 UC26.6
CPVEE: CA70.1 UA1.27
CS_DDR: PR502.2 PU501.13
CSIN_CHG: PC747.2 PR740.2 PU703.31
CSIN_CHG_R: PR703.3 PR740.1
CSIP_CHG: PC747.1 PR772.2 PU703.32
CSIP_CHG_R: PR703.2 PR772.1
CSON_CHG: PC708.2 PR776.1 PU703.14
CSON_CHG_R: PR765.3 PR776.2
CSOP_CHG: PC708.1 PR742.1 PU703.15
CSOP_CHG_R: PR742.2 PR765.2
CUST_TEMP1: R364.2 R366.1 U11.73
CUST_TEMP2: R365.2 R367.1 U11.76
CUST_TEMP3: R368.2 R369.1 U11.66
DDR_A_ALERT#: JDIMM1.116 RD201.2
DDR_A_CKE0: JDIMM1.109 UC1.J38
DDR_A_CKE1: JDIMM1.110 UC1.J34
DDR_A_CLK0: JDIMM1.137 UC1.AC35
DDR_A_CLK0#: JDIMM1.139 UC1.AC34
DDR_A_CLK1: JDIMM1.138 UC1.AA34
DDR_A_CLK1#: JDIMM1.140 UC1.AA32
DDR_A_EVENT#: JDIMM1.134 RC4.2 UC1.AA41
DDR_A_ODT0: JDIMM1.155 UC1.AN37
DDR_A_ODT1: JDIMM1.161 UC1.AU38
DDR_A_PAR: JDIMM1.143 RD210.2
DDR_A_RST#: CC112.2 CD231.1 JDIMM1.108 UC1.G38
DDR_A_SACT#: JDIMM1.114 UC1.L35
DDR_A_SBG0: JDIMM1.115 UC1.N34
DDR_A_SBG1: JDIMM1.113 UC1.L38
DDR_A_SBS0#: JDIMM1.150 UC1.AJ38
DDR_A_SBS1#: JDIMM1.145 UC1.AG35
DDR_A_SCAS#: JDIMM1.156 UC1.AN38
DDR_A_SCS0#: JDIMM1.149 UC1.AL35
DDR_A_SCS1#: JDIMM1.157 UC1.AR37
DDR_A_SDM0: JDIMM1.12 UC1.B35
DDR_A_SDM1: JDIMM1.33 UC1.D40
DDR_A_SDM2: JDIMM1.54 UC1.K40
DDR_A_SDM3: JDIMM1.75 UC1.T41
DDR_A_SDM4: JDIMM1.178 UC1.AE41
DDR_A_SDM5: JDIMM1.199 UC1.AL40
DDR_A_SDM6: JDIMM1.220 UC1.AU40
DDR_A_SDM7: JDIMM1.241 UC1.BA37
DDR_A_SDQ0: JDIMM1.8 UC1.A34
DDR_A_SDQ1: JDIMM1.7 UC1.B34
DDR_A_SDQ2: JDIMM1.20 UC1.A38
DDR_A_SDQ3: JDIMM1.21 UC1.B38
DDR_A_SDQ4: JDIMM1.4 UC1.A33
DDR_A_SDQ5: JDIMM1.3 UC1.B33
DDR_A_SDQ6: JDIMM1.16 UC1.A37
DDR_A_SDQ7: JDIMM1.17 UC1.B37
DDR_A_SDQ8: JDIMM1.28 UC1.B41
DDR_A_SDQ9: JDIMM1.29 UC1.C40
DDR_A_SDQ10: JDIMM1.41 UC1.F41
DDR_A_SDQ11: JDIMM1.42 UC1.G40
DDR_A_SDQ12: JDIMM1.24 UC1.A40
DDR_A_SDQ13: JDIMM1.25 UC1.B40
DDR_A_SDQ14: JDIMM1.38 UC1.E41
DDR_A_SDQ15: JDIMM1.37 UC1.F40
DDR_A_SDQ16: JDIMM1.50 UC1.J40
DDR_A_SDQ17: JDIMM1.49 UC1.J41
DDR_A_SDQ18: JDIMM1.63 UC1.N40
DDR_A_SDQ19: JDIMM1.62 UC1.N41
DDR_A_SDQ20: JDIMM1.46 UC1.H40
DDR_A_SDQ21: JDIMM1.45 UC1.H41
DDR_A_SDQ22: JDIMM1.58 UC1.M40
DDR_A_SDQ23: JDIMM1.59 UC1.M41
DDR_A_SDQ24: JDIMM1.67 UC1.R40
DDR_A_SDQ25: JDIMM1.70 UC1.T40
DDR_A_SDQ26: JDIMM1.83 UC1.W40
DDR_A_SDQ27: JDIMM1.84 UC1.Y40
DDR_A_SDQ28: JDIMM1.66 UC1.P40
DDR_A_SDQ29: JDIMM1.71 UC1.P41
DDR_A_SDQ30: JDIMM1.79 UC1.V40
DDR_A_SDQ31: JDIMM1.80 UC1.V41
DDR_A_SDQ32: JDIMM1.174 UC1.AD41
DDR_A_SDQ33: JDIMM1.173 UC1.AD40
DDR_A_SDQ34: JDIMM1.187 UC1.AH41
DDR_A_SDQ35: JDIMM1.186 UC1.AH40
DDR_A_SDQ36: JDIMM1.170 UC1.AB40
DDR_A_SDQ37: JDIMM1.169 UC1.AC40
DDR_A_SDQ38: JDIMM1.183 UC1.AF40
DDR_A_SDQ39: JDIMM1.182 UC1.AG40
DDR_A_SDQ40: JDIMM1.195 UC1.AK41
DDR_A_SDQ41: JDIMM1.194 UC1.AK40
DDR_A_SDQ42: JDIMM1.207 UC1.AP41
DDR_A_SDQ43: JDIMM1.208 UC1.AP40
DDR_A_SDQ44: JDIMM1.191 UC1.AJ41
DDR_A_SDQ45: JDIMM1.190 UC1.AJ40
DDR_A_SDQ46: JDIMM1.203 UC1.AN41
DDR_A_SDQ47: JDIMM1.204 UC1.AN40
DDR_A_SDQ48: JDIMM1.216 UC1.AT40
DDR_A_SDQ49: JDIMM1.212 UC1.AU41
DDR_A_SDQ50: JDIMM1.228 UC1.AY40
DDR_A_SDQ51: JDIMM1.229 UC1.BA40
DDR_A_SDQ52: JDIMM1.211 UC1.AR40
DDR_A_SDQ53: JDIMM1.215 UC1.AT41
DDR_A_SDQ54: JDIMM1.224 UC1.AW40
DDR_A_SDQ55: JDIMM1.225 UC1.AY41
DDR_A_SDQ56: JDIMM1.237 UC1.BA38
DDR_A_SDQ57: JDIMM1.236 UC1.AY37
DDR_A_SDQ58: JDIMM1.249 UC1.BA34
DDR_A_SDQ59: JDIMM1.250 UC1.BA33
DDR_A_SDQ60: JDIMM1.232 UC1.AY39
DDR_A_SDQ61: JDIMM1.233 UC1.AY38
DDR_A_SDQ62: JDIMM1.245 UC1.AY35
DDR_A_SDQ63: JDIMM1.246 UC1.AY34
DDR_A_SDQS0: JDIMM1.13 UC1.B36
DDR_A_SDQS0#: JDIMM1.11 UC1.A36
DDR_A_SDQS1: JDIMM1.34 UC1.E40
DDR_A_SDQS1#: JDIMM1.32 UC1.D41
DDR_A_SDQS2: JDIMM1.55 UC1.L40
DDR_A_SDQS2#: JDIMM1.53 UC1.K41
DDR_A_SDQS3: JDIMM1.76 UC1.U41
DDR_A_SDQS3#: JDIMM1.74 UC1.U40
DDR_A_SDQS4: JDIMM1.179 UC1.AF41
DDR_A_SDQS4#: JDIMM1.177 UC1.AE40
DDR_A_SDQS5: JDIMM1.200 UC1.AM40
DDR_A_SDQS5#: JDIMM1.198 UC1.AM41
DDR_A_SDQS6: JDIMM1.221 UC1.AV40
DDR_A_SDQS6#: JDIMM1.219 UC1.AV41
DDR_A_SDQS7: JDIMM1.242 UC1.BA36
DDR_A_SDQS7#: JDIMM1.240 UC1.AY36
DDR_A_SMA0: JDIMM1.144 UC1.AG38
DDR_A_SMA1: JDIMM1.133 UC1.W35
DDR_A_SMA2: JDIMM1.132 UC1.W38
DDR_A_SMA3: JDIMM1.131 UC1.W34
DDR_A_SMA4: JDIMM1.128 UC1.U38
DDR_A_SMA5: JDIMM1.126 UC1.U37
DDR_A_SMA6: JDIMM1.127 UC1.U34
DDR_A_SMA7: JDIMM1.122 UC1.R35
DDR_A_SMA8: JDIMM1.125 UC1.R38
DDR_A_SMA9: JDIMM1.121 UC1.N38
DDR_A_SMA10: JDIMM1.146 UC1.AG34
DDR_A_SMA11: JDIMM1.120 UC1.R34
DDR_A_SMA12: JDIMM1.119 UC1.N37
DDR_A_SMA13: JDIMM1.158 UC1.AN35
DDR_A_SRAS#: JDIMM1.152 UC1.AJ37
DDR_A_SWE#: JDIMM1.151 UC1.AL38
DEVSLP0: RPC13.7 UC1.AV31
DEVSLP1: RPC13.8 UC1.AU31
DGPU_PWR_EN: PR902.2 PR1015.2 RV1642.2 RV1644.1 U11.71 UC1.BA29
DGPU_PWR_EN#: QV11.2 QV17.2 QV18.1 QV21.2 QV21.5 RV43.1 RV44.2
DGPU_PWR_EN_R: CV1380.1 RV1642.1 U1895V.3 U1895V.5
DGPU_PWRGD: PR1002.2 PR1098.1 PU1001.20 RC66.1 RC164.2
DGPU_PWRGD_R: RC66.2 UC1.AH1
DGPU_PWROK: PC11227.2 PR1098.2 PR1099.2 PU1001.15
DISPOFF#: JEDP1.10 R204.2 R205.2 U203.4
DMIC_CLK: C216.2 JEDP1.25 LA9.1
DMIC_CLK_R: LA9.2 UA1.3
DMIC_DAT: JEDP1.27 UA1.2
DP_AUX_ZVSS: RC16.1 UC1.D21
DP_VSSR: UV1.AF19 UV1.AF20 UV1.AF23 UV1.AG14 UV1.AG23 UV1.AH14 UV1.AM14 UV1.AM16 UV1.AM18 UV1.AM20 UV1.AM22 UV1.AM24
DP_ZVSS: RC17.1 UC1.B18
DRAM_RST: RV36.1 UV7.J2 UV8.J2
DRAM_RST_G: CV97.1 RV37.1 RV38.1 UV1.L10
EC_CLEAR_CMOS#: RC111.1 U11.15
EC_FAN_PWM1: JFAN1.2 U11.26
EC_FAN_SPEED1: JFAN1.3 R214.1 U11.28
EC_MUTE#: R198.1 RA43.2 RA46.2 U11.89
EC_ON: PR410.1 U11.112
EC_PCIE_WAKE#: R249.1 R931.1 U11.108 UL2.21
EC_RSMRST#: C835.1 DC3.1 RC59.1 U11.100
EC_RSMRST#_R: CC8.2 DC3.2 RC59.2 RC60.2 UC1.AG1
EC_RST#: C187.2 R192.1 U11.37
EC_RX: R244.2 U11.31
EC_SCI#: U11.20 UC1.AA8
EC_SMB_CK1: PR202.2 PR770.1 RP3.4 U11.77
EC_SMB_CK2: QC2.3 QV1.6 RP3.2 U11.79
EC_SMB_DA1: PR201.2 PR769.1 RP3.3 U11.78
EC_SMB_DA2: QC2.6 QV1.3 RP3.1 U11.80
EC_SMCA: JBAT1.3 PR202.1
EC_SMDA: JBAT1.4 PR201.1
EC_TX: R243.2 U11.30
ECAGND: C184.2 L21.2 PH201.2 R366.2 R367.2 R369.2 U11.69
EDP_AUXN: C206.1 UC1.H15
EDP_AUXN_C: C206.2 JEDP1.7
EDP_AUXP: C207.1 UC1.G15
EDP_AUXP_C: C207.2 JEDP1.9
EDP_HPD: R207.1 R209.1 UC1.D15
EDP_HPD_R: JEDP1.12 R207.2
EDP_TXN0: C209.1 UC1.B9
EDP_TXN0_C: C209.2 JEDP1.15
EDP_TXN1: C211.1 UC1.B10
EDP_TXN1_C: C211.2 JEDP1.21
EDP_TXP0: C208.1 UC1.A9
EDP_TXP0_C: C208.2 JEDP1.13
EDP_TXP1: C210.1 UC1.A10
EDP_TXP1_C: C210.2 JEDP1.19
EN_0.675VSP: PC519.1 PR510.2 PU501.7
EN_1.35V: PC902.1 PR902.1 PR903.1 PU901.11
EN_1V: PC601.1 PR601.1 PR603.2 PU601.11
EN_DDR: PC518.1 PR508.2 PU501.8
EN_RT3661: PC811.2 PR851.2 PU801.29
EN_VGA: PC1010.1 PR1015.1 PU1001.32
ENBKL: QC1.1 R210.2 RC18.1 U11.97 U203.2
ENBKL_R: QC1.3 RC22.1 UC1.B23
ENLDO_3V5V: PC429.1 PR402.2 PR404.1 PU401.11 PU402.11
ENVDD_R: RC20.1 UC1.B24
EXT_MIC_RING2: RA31.2 RA58.2 UA1.13
EXT_MIC_SLEEVE: RA42.2 RA54.2 UA1.14
FB_1.35V: PC907.2 PR905.2 PR907.1 PU901.14
FB_1V: PR608.2 PR610.1 PR612.2 PU601.14
FB_APU: PC812.2 PC813.1 PR807.1 PR809.2 PU801.6
FB_DDR: PR506.1 PR509.1 PU501.6
FB_NB: PC809.2 PC810.1 PR810.2 PR811.1 PU801.26
FB_VDDCI: T222.1(TP-1) UV1.W1
FB_VGA: PC1024.1 PC1026.1 PR1017.2 PR1028.1 PU1001.4
FSET_CHG: PR755.1 PU703.12
GATEA20: C836.1 RPC12.8 U11.1 UC1.AU35
GPIO19_CTF: RV151.2 RV152.1 UV1.M2
GPIO28: RV21.2 UV1.R5
GPU_GPIO5: DV1.2 RV195.2 RV3151.1 RV3152.2 UV1.T9
GPU_GPIO5_VGA#: DV1.1 RV195.1 U11.88
GPU_PROCHOT#: PR1016.1 PU1001.9 RV90.2 RV91.1
GPU_SVC: PC1014.2 PR1022.1 RV84.1 RV89.2 RV94.1 RV157.2
GPU_SVC_R: RV94.2 UV1.P8
GPU_SVC_RT3662: PR1022.2 PU1001.16
GPU_SVD: PC1013.2 PR1018.1 RV87.1 RV88.2 RV93.1 RV155.2
GPU_SVD_R: RV93.2 UV1.N1
GPU_SVD_RT3662: PR1018.2 PU1001.17
GPU_SVT: PC1032.2 PR1025.1 RV156.2
GPU_SVT_RT3662: PR1025.2 PU1001.18
H_PROCHOT#: C191.1 CC113.2 R923.2 R929.2 RPC1.1 UC1.A31
HDA_BITCLK: RC49.2 RPC6.5 UC1.AY6
HDA_BITCLK_AUDIO: RA50.1 RPC6.4 UA1.5
HDA_RST#: RPC9.6 UC1.AY4
HDA_SDIN0: RA52.2 RC54.1 UC1.BA6
HDA_SDIN0_AUDIO: RA52.1 UA1.7
HDA_SDIN1: RC52.1 UC1.AY5
HDA_SDIN2: RC53.1 UC1.BA5
HDA_SDOUT: RPC6.6 RPC9.8 UC1.BA4
HDA_SDOUT_AUDIO: RPC6.3 UA1.4
HDA_SYNC: RPC6.7 RPC9.7 UC1.BA3
HDA_SYNC_AUDIO: RPC6.2 UA1.9
HDD_ODD_DETECT: JODD2.7 RC158.2 RC159.2 UC1.BA14
HDMI_CLKN: CH14.2 LH1.1 RPH1.8
HDMI_CLKP: CH13.2 LH1.4 RPH1.7
HDMI_CTRL_CLK: DH1.1 DH1.9 JHDMI1.15 QH15.6 RH28.2
HDMI_CTRL_DAT: DH1.2 DH1.8 JHDMI1.16 QH15.3 RH27.2
HDMI_HPD: DH1.5 DH1.6 JHDMI1.19 RH133.2 RH138.2
HDMI_HPD_R: QH5.2 RH133.1
HDMI_L_CLKN: DH2.5 DH2.6 JHDMI1.12 LH1.2
HDMI_L_CLKP: DH2.4 DH2.7 JHDMI1.10 LH1.3
HDMI_L_TX_N0: DH3.2 DH3.8 JHDMI1.9 LH2.2
HDMI_L_TX_N1: DH2.2 DH2.8 JHDMI1.6 LH3.2
HDMI_L_TX_N2: DH3.5 DH3.6 JHDMI1.3 LH4.2
HDMI_L_TX_P0: DH3.1 DH3.9 JHDMI1.7 LH2.3
HDMI_L_TX_P1: DH2.1 DH2.9 JHDMI1.4 LH3.3
HDMI_L_TX_P2: DH3.4 DH3.7 JHDMI1.1 LH4.3
HDMI_TX_N0: CH16.2 LH2.1 RPH2.6
HDMI_TX_N1: CH18.2 LH3.1 RPH1.6
HDMI_TX_N2: CH20.2 LH4.1 RPH2.8
HDMI_TX_P0: CH15.2 LH2.4 RPH2.5
HDMI_TX_P1: CH17.2 LH3.4 RPH1.5
HDMI_TX_P2: CH19.2 LH4.4 RPH2.7
HDT_P11: JHDT1.11 RPC5.7
HDT_P13: JHDT1.13 RPC5.6
HDT_P15: JHDT1.15 RPC5.5
HGNDA: CA50.1 DA9.2 JHP1.3 RA31.1
HGNDB: CA65.1 DA9.3 JHP1.4 RA42.1 RA62.1
HP_OUTL: CA46.1 RA36.2 RA45.1 RA57.2 UA1.25
HP_OUTR: CA54.1 RA44.2 RA49.2 RA56.1 UA1.26
HPOUT_L: CA56.2 RA45.2 RA63.1
HPOUT_L1: DA8.2 JHP1.1 RA63.2
HPOUT_R: CA59.2 RA56.2 RA64.1
HPOUT_R1: DA8.3 JHP1.2 RA64.2
I2C0_SCL: C2150.1 QC17.1 RC146.2 UC1.AY22
I2C0_SCL_TP: C281.1 D281.2 JTP1.5 QC17.6 RC144.2
I2C0_SDA: C2151.1 QC17.4 RC147.2 UC1.BA22
I2C0_SDA_TP: C282.1 D281.3 JTP1.4 QC17.3 RC145.2
I2C1_SCL: RC160.2 UC1.AU19
I2C1_SDA: RC161.2 UC1.AV19
ILMT_1.35V: PR906.1 PU901.13
ILMT_1V: PR607.2 PR609.1 PU601.13
IMON_APU: PR843.1 PU801.14
IMON_NB: PR842.1 PU801.16
IMON_VGA: PR1009.2 PU1001.12
INVT_PWM_R: RC24.1 UC1.A24 UC21.2
ISEN1N_APU: PC805.2 PC807.1 PL803.3 PR852.2 PU801.10
ISEN1N_VGA: PC1020.1 PC1036.2 PL1001.3 PR1020.2 PU1001.8
ISEN1P_APU: PC805.1 PR805.2 PR852.1 PU801.9
ISEN1P_APU_R: PL803.2 PR805.1
ISEN1P_VGA: PC1036.1 PR1020.1 PR1030.2 PU1001.7
ISENN_NB: PC826.2 PC828.1 PL804.3 PR853.2 PU801.24
ISENP_NB: PC826.1 PR845.2 PR853.1 PU801.25
ISENP_NB_R: PL804.2 PR845.1
ISOLATE#: RL8.2 RL10.1 UL2.20
JTAG_TCK: RPV34.6 UV1.L3
JTAG_TDI_GPU: RPV34.8 UV1.L5
JTAG_TDO_GPU: RV369.1 UV1.K4
JTAG_TMS_GPU: RPV34.7 UV1.L1
JTAG_TRSTB: RPV34.5 UV1.L6
KBRST#: C2154.1 RC90.2 U11.2 UC1.BA30
KSI0: JKB1.15 U11.55
KSI1: JKB1.26 U11.56
KSI2: JKB1.19 U11.57
KSI3: JKB1.18 U11.58
KSI4: JKB1.22 U11.59
KSI5: JKB1.21 U11.60
KSI6: JKB1.24 U11.61
KSI7: JKB1.25 U11.62
KSO0: JKB1.20 U11.39
KSO1: JKB1.16 U11.40
KSO2: JKB1.14 U11.41
KSO3: JKB1.9 U11.42
KSO4: JKB1.13 U11.43
KSO5: JKB1.17 U11.44
KSO6: JKB1.10 U11.45
KSO7: JKB1.12 U11.46
KSO8: JKB1.11 U11.47
KSO9: JKB1.23 U11.48
KSO10: JKB1.4 U11.49
KSO11: JKB1.5 U11.50
KSO12: JKB1.8 U11.51
KSO13: JKB1.7 U11.52
KSO14: JKB1.6 U11.53
KSO15: JKB1.3 U11.54
KSO16: R275.1 U11.81
KSO16_R: JKB1.27 R275.2
KSO17: R276.1 U11.82
KSO17_R: JKB1.28 R276.2
LAN_CLKREQ#: RPC12.6 UC1.AY32 UL2.12
LAN_MDIN0: DL2.6 TL1.12 UL2.2
LAN_MDIN1: DL2.1 TL1.9 UL2.5
LAN_MDIN2: DL1.6 TL1.6 UL2.7
LAN_MDIN3: DL1.1 TL1.3 UL2.10
LAN_MDIP0: DL2.4 TL1.11 UL2.1
LAN_MDIP1: DL2.3 TL1.8 UL2.4
LAN_MDIP2: DL1.4 TL1.5 UL2.6
LAN_MDIP3: DL1.3 TL1.2 UL2.9
LANGAN: CL19.2 DL3.1 JLAN1.9 JLAN1.10 RL4.2 RL5.2
LANGAN1: JLAN1.11 JLAN1.12 RL6.2 RL7.2
LDO1: CA61.2 UA1.21
LDO2: CA64.2 UA1.32
LDO3: CA51.2 UA1.6
LDO_3V: PC613.1 PU601.16 PU601.17
LDO_3V_1.35V: PC912.1 PR906.2 PU901.16 PU901.17
LED1_GPIO: RL17.1 UL2.26
LG1_APU: PQ802.4 PU801.35
LG1_VGA: PQ1001.6 PU1001.26
LG_CHG: PQ706.4 PU703.21
LG_DDR: PQ502.4 PU501.15
LG_NB: PQ804.4 PU801.33
LID_SW#: C838.2 C2153.1 R273.1 U11.115 U282.3
LINE1-L: CA46.2 UA1.18
LINE1-R: CA54.2 UA1.17
LPC_AD0: U11.10 UC1.BA26
LPC_AD1: U11.8 UC1.AY28
LPC_AD2: U11.7 UC1.AY25
LPC_AD3: U11.5 UC1.AY23
LPC_CLK0_EC: R921.1 RC77.2 RC78.1 U11.12 UC1.BA25
LPC_CLK1: RC79.2 RC80.1 UC1.BA24
LPC_CLKRUN#: R428.1 UC1.AY26
LPC_FRAME#: RC75.2 RC76.1 U11.4 UC1.AY24
LPC_PD#: RC112.2 UC1.AC1
LPC_RST#: C833.1 CC13.1 RC93.1 RC94.2 U11.13
LPC_RST#_R: RC93.2 UC1.AY27
LX1_APU: PC804.2 PL803.1 PQ801.1 PQ801.2 PQ801.3 PQ802.5 PR804.1 PU801.36
LX1_VGA: PC1044.2 PL1001.1 PQ1001.7 PR1034.1 PU1001.25
LX1_VGA_1: PL1001.2 PR1030.1
LX_1.35V: PC901.2 PL901.1 PR904.1 PU901.6 PU901.19 PU901.20
LX_1V: PC603.2 PL602.1 PR605.1 PU601.6 PU601.19 PU601.20
LX_3V: PC401.2 PL402.1 PL402.2 PR405.1 PU401.6 PU401.19 PU401.20
LX_5V: PC418.2 PL404.1 PL404.2 PR409.1 PU402.6 PU402.19 PU402.20
LX_CHG: PC721.2 PL700.1 PQ704.1 PQ704.2 PQ704.3 PQ706.5 PR766.1 PU703.22
LX_DDR: PC505.2 PL502.3 PL502.4 PQ501.1 PQ501.2 PQ501.3 PQ502.5 PR503.1 PU501.16
LX_NB: PC825.2 PL804.1 PQ803.1 PQ803.2 PQ803.3 PQ804.5 PR844.1 PU801.32
M0_MA0: UV1.K17 UV7.H4
M0_MA1: UV1.J20 UV7.H5
M0_MA2: UV1.H23 UV7.H11
M0_MA3: UV1.G23 UV7.H10
M0_MA4: UV1.G24 UV7.K11
M0_MA5: UV1.H24 UV7.K10
M0_MA6: UV1.J19 UV7.K5
M0_MA7: UV1.K19 UV7.K4
M0_MA8: UV1.G20 UV7.J5
M1_MA0: UV1.J14 UV8.H4
M1_MA1: UV1.K14 UV8.H5
M1_MA2: UV1.J11 UV8.H11
M1_MA3: UV1.J13 UV8.H10
M1_MA4: UV1.H11 UV8.K11
M1_MA5: UV1.G11 UV8.K10
M1_MA6: UV1.J16 UV8.K5
M1_MA7: UV1.L15 UV8.K4
M1_MA8: UV1.G14 UV8.J5
M_ADBI0: UV1.L18 UV7.J4
M_ADBI1: UV1.K16 UV8.J4
M_CAS#0: UV1.G19 UV7.L3
M_CAS#1: UV1.G16 UV8.L3
M_CKE0: UV1.K20 UV7.J3
M_CKE1: UV1.J17 UV8.J3
M_CLK0: RV79.2 UV1.H26 UV7.J12
M_CLK1: RV86.2 UV1.G9 UV8.J12
M_CLK#0: RV80.2 UV1.H25 UV7.J11
M_CLK#1: RV85.2 UV1.H9 UV8.J11
M_CS0B#0: UV1.H22 UV7.G12
M_CS1B#0: UV1.G13 UV8.G12
M_DA0: UV1.K27 UV7.A2
M_DA1: UV1.J29 UV7.B2
M_DA2: UV1.H30 UV7.A4
M_DA3: UV1.H32 UV7.B4
M_DA4: UV1.G29 UV7.F2
M_DA5: UV1.F28 UV7.F4
M_DA6: UV1.F32 UV7.E4
M_DA7: UV1.F30 UV7.E2
M_DA8: UV1.C30 UV7.F11
M_DA9: UV1.F27 UV7.B13
M_DA10: UV1.A28 UV7.E11
M_DA11: UV1.C28 UV7.B11
M_DA12: UV1.E27 UV7.E13
M_DA13: UV1.G26 UV7.A13
M_DA14: UV1.D26 UV7.F13
M_DA15: UV1.F25 UV7.A11
M_DA16: UV1.A25 UV7.M4
M_DA17: UV1.C25 UV7.T4
M_DA18: UV1.E25 UV7.N4
M_DA19: UV1.D24 UV7.U4
M_DA20: UV1.E23 UV7.T2
M_DA21: UV1.F23 UV7.N2
M_DA22: UV1.D22 UV7.U2
M_DA23: UV1.F21 UV7.M2
M_DA24: UV1.E21 UV7.M11
M_DA25: UV1.D20 UV7.M13
M_DA26: UV1.F19 UV7.N13
M_DA27: UV1.A19 UV7.N11
M_DA28: UV1.D18 UV7.U13
M_DA29: UV1.F17 UV7.T13
M_DA30: UV1.A17 UV7.U11
M_DA31: UV1.C17 UV7.T11
M_DA32: UV1.E17 UV8.F4
M_DA33: UV1.D16 UV8.E4
M_DA34: UV1.F15 UV8.F2
M_DA35: UV1.A15 UV8.E2
M_DA36: UV1.D14 UV8.B4
M_DA37: UV1.F13 UV8.A2
M_DA38: UV1.A13 UV8.A4
M_DA39: UV1.C13 UV8.B2
M_DA40: UV1.E11 UV8.B11
M_DA41: UV1.A11 UV8.A11
M_DA42: UV1.C11 UV8.B13
M_DA43: UV1.F11 UV8.A13
M_DA44: UV1.A9 UV8.E11
M_DA45: UV1.C9 UV8.E13
M_DA46: UV1.F9 UV8.F11
M_DA47: UV1.D8 UV8.F13
M_DA48: UV1.E7 UV8.U2
M_DA49: UV1.A7 UV8.M2
M_DA50: UV1.C7 UV8.N2
M_DA51: UV1.F7 UV8.T2
M_DA52: UV1.A5 UV8.T4
M_DA53: UV1.E5 UV8.M4
M_DA54: UV1.C3 UV8.N4
M_DA55: UV1.E1 UV8.U4
M_DA56: UV1.G7 UV8.M11
M_DA57: UV1.G6 UV8.N11
M_DA58: UV1.G1 UV8.N13
M_DA59: UV1.G3 UV8.M13
M_DA60: UV1.J6 UV8.T13
M_DA61: UV1.J1 UV8.U13
M_DA62: UV1.J3 UV8.U11
M_DA63: UV1.J5 UV8.T11
M_DBI0#: UV1.H27 UV7.D2
M_DBI1#: UV1.A27 UV7.D13
M_DBI2#: UV1.C23 UV7.P2
M_DBI3#: UV1.C19 UV7.P13
M_DBI4#: UV1.C15 UV8.D2
M_DBI5#: UV1.E9 UV8.D13
M_DBI6#: UV1.C5 UV8.P2
M_DBI7#: UV1.H4 UV8.P13
M_EDC_0: UV1.H28 UV7.C2
M_EDC_1: UV1.C27 UV7.C13
M_EDC_2: UV1.A23 UV7.R2
M_EDC_3: UV1.E19 UV7.R13
M_EDC_4: UV1.E15 UV8.C2
M_EDC_5: UV1.D10 UV8.C13
M_EDC_6: UV1.D6 UV8.R2
M_EDC_7: UV1.G5 UV8.R13
M_RAS#0: UV1.G22 UV7.G3
M_RAS#1: UV1.G17 UV8.G3
M_WCKA0_0: UV1.E32 UV7.D4
M_WCKA0_0#: UV1.E30 UV7.D5
M_WCKA0_1: UV1.A21 UV7.P4
M_WCKA0_1#: UV1.C21 UV7.P5
M_WCKA1_0: UV1.E13 UV8.D4
M_WCKA1_0#: UV1.D12 UV8.D5
M_WCKA1_1: UV1.E3 UV8.P4
M_WCKA1_1#: UV1.F4 UV8.P5
M_WE#0: UV1.G25 UV7.L12
M_WE#1: UV1.H10 UV8.L12
MCT: DL3.2 RL19.1 TL1.15 TL1.18 TL1.21 TL1.24
MEM_MA_ZVDDIO: RC3.1 UC1.AB41
MODEL_ID#: RC156.2 RC157.2 UC1.AY16
NOVO#: D1.3 RP4.8 SW1.2 U11.68
NUM_LED#: R277.1 U11.117
NUM_LED#_R: C275.1 JKB1.29 R277.2
ON/OFF#: C837.1 J1.2 J2.2 R283.1 RP4.7 U11.114
OPCN_CHG: PC750.2 PU703.28
OPCP_CHG: PC750.1 PU703.27
P_ZVDDP: RC1.2 UC1.U8
P_ZVSS: RC2.1 UC1.W8
PBTN_OUT#: RC44.2 U11.122 UC1.AD2
PC_BEEP: CA69.1 UA1.11
PCC_GPIO_6: CV90.2 RV90.1 UV1.T8
PCIE_ARX_C_DTX_N0: CL12.1 UL2.18
PCIE_ARX_C_DTX_P0: CL11.1 UL2.17
PCIE_ARX_C_GTX_N0: CV2.1 UV1.AG31
PCIE_ARX_C_GTX_N1: CV4.1 UV1.AF28
PCIE_ARX_C_GTX_N2: CV6.1 UV1.AF26
PCIE_ARX_C_GTX_N3: CV8.1 UV1.AD26
PCIE_ARX_C_GTX_P0: CV1.1 UV1.AH30
PCIE_ARX_C_GTX_P1: CV3.1 UV1.AG29
PCIE_ARX_C_GTX_P2: CV5.1 UV1.AF27
PCIE_ARX_C_GTX_P3: CV7.1 UV1.AD27
PCIE_ARX_DTX_N0: CL12.2 UC1.U5
PCIE_ARX_DTX_N2: JWLAN1.43 UC1.R4
PCIE_ARX_DTX_P0: CL11.2 UC1.U4
PCIE_ARX_DTX_P2: JWLAN1.41 UC1.R5
PCIE_ARX_GTX_N0: CV2.2 UC1.L4
PCIE_ARX_GTX_N1: CV4.2 UC1.J4
PCIE_ARX_GTX_N2: CV6.2 UC1.G4
PCIE_ARX_GTX_N3: CV8.2 UC1.E7
PCIE_ARX_GTX_P0: CV1.2 UC1.L5
PCIE_ARX_GTX_P1: CV3.2 UC1.J5
PCIE_ARX_GTX_P2: CV5.2 UC1.G5
PCIE_ARX_GTX_P3: CV7.2 UC1.D7
PCIE_ATX_C_DRX_N0: CC2.2 UL2.14
PCIE_ATX_C_DRX_N2: CC4.2 JWLAN1.37
PCIE_ATX_C_DRX_P0: CC1.2 UL2.13
PCIE_ATX_C_DRX_P2: CC3.2 JWLAN1.35
PCIE_ATX_C_GRX_N0: CC105.2 UV1.AE31
PCIE_ATX_C_GRX_N1: CC107.2 UV1.AD28
PCIE_ATX_C_GRX_N2: CC109.2 UV1.AC31
PCIE_ATX_C_GRX_N3: CC111.2 UV1.AB28
PCIE_ATX_C_GRX_P0: CC104.2 UV1.AF30
PCIE_ATX_C_GRX_P1: CC106.2 UV1.AE29
PCIE_ATX_C_GRX_P2: CC108.2 UV1.AD30
PCIE_ATX_C_GRX_P3: CC110.2 UV1.AC29
PCIE_ATX_DRX_N0: CC2.1 UC1.D1
PCIE_ATX_DRX_N2: CC4.1 UC1.B1
PCIE_ATX_DRX_P0: CC1.1 UC1.D2
PCIE_ATX_DRX_P2: CC3.1 UC1.B2
PCIE_ATX_GRX_N0: CC105.1 UC1.B4
PCIE_ATX_GRX_N1: CC107.1 UC1.B5
PCIE_ATX_GRX_N2: CC109.1 UC1.B6
PCIE_ATX_GRX_N3: CC111.1 UC1.B7
PCIE_ATX_GRX_P0: CC104.1 UC1.A4
PCIE_ATX_GRX_P1: CC106.1 UC1.A5
PCIE_ATX_GRX_P2: CC108.1 UC1.A6
PCIE_ATX_GRX_P3: CC110.1 UC1.A7
PDB: RA46.1 UA1.40
PGOOD: PR603.1 PR2009.2 PU2001.1
PLL_ANALOG_IN: T221.1(TP-1) UV1.AA1
PLL_ANALOG_OUT: RV83.1 UV1.AA3
PLT_RST_VGA#: PR1006.1 PR1099.1 RV4.1 UV1.AL27 UV2.4
PLUG_IN: JHP1.6 RA23.2
PLUG_IN_R: RA23.1 RA51.1 UA1.12
PM_CLKRUN#: R428.2 U11.38
PM_SLP_S3#: U11.6 UC1.AC2
PM_SLP_S5#: PQ711.2 PR2003.1 U11.123 UC1.AG4
PROCHOT#: PR777.1 PU801.11 R929.1
PROG_CHG: PR753.1 PU703.9
PS_0: CV29.1 RV8.2 RV9.1 UV1.AC19
PS_1: CV28.1 RV11.2 RV12.1 UV1.AD19
PS_2: CV11.1 RV13.1 RV28.2 UV1.AE17
PS_3: CV15.1 RV15.2 RV16.1 UV1.AE20
PWR_CAPS_LED: JKB1.1 R271.1 R278.1
PWR_LED#: LED2.1 R272.1 U11.92
PX_EN: T218.1(TP-1) UV1.AB16
PXS_RST#: RV3153.1 UC1.AY15 UV2.1
RGND_RT3661: PC814.2 PC818.2 PC987.1 PR820.1 PR823.2 PR827.2 PU801.4
RGND_VGA: PC1006.1 PC1011.1 PR1014.2 PR1019.1 PU1001.2
RJ45_RX1+: JLAN1.3 TL1.17
RJ45_RX1-: JLAN1.6 TL1.16
RJ45_TX0+: JLAN1.1 TL1.14
RJ45_TX0-: JLAN1.2 TL1.13
RJ45_TX2+: JLAN1.4 TL1.20
RJ45_TX2-: JLAN1.5 TL1.19
RJ45_TX3+: JLAN1.7 TL1.23
RJ45_TX3-: JLAN1.8 TL1.22
RNC1N__NB: PH804.1 PR842.2 PR847.1
RNC1N_APU: PH803.1 PR843.2 PR846.1
RNC1P__NB: PH804.2 PR849.2
RNC1P_APU: PH803.2 PR848.1
RREF: RR1.1 UR1.2
RTC_CLK: R245.2 RC83.2 RC84.1 UC1.AN4
S5_MUX_CTRL: QC22.5 RC152.1 UC1.AA7
SA0_DIM1: JDIMM1.256 RD202.2 RD205.1
SA1_DIM1: JDIMM1.260 RD203.2 RD206.1
SA2_DIM1: JDIMM1.166 RD204.2 RD207.1
SATA_ACT#: RPC12.7 UC1.AY30
SATA_ARX_C_DTX_N0: C235.2 JHDD1.6
SATA_ARX_C_DTX_P0: C236.2 JHDD1.5
SATA_ARX_DTX_N0: C235.1 UC1.AY12
SATA_ARX_DTX_N1: JODD2.5 UC1.BA8
SATA_ARX_DTX_P0: C236.1 UC1.BA12
SATA_ARX_DTX_P1: JODD2.6 UC1.AY8
SATA_ATX_C_DRX_N0: C234.2 JHDD1.8
SATA_ATX_C_DRX_P0: C233.2 JHDD1.9
SATA_ATX_DRX_N0: C234.1 UC1.AY10
SATA_ATX_DRX_N1: JODD2.2 UC1.BA9
SATA_ATX_DRX_P0: C233.1 UC1.BA10
SATA_ATX_DRX_P1: JODD2.1 UC1.AY9
SATA_ZVDDP: RC89.1 UC1.AP11
SATA_ZVSS: RC88.1 UC1.AU11
SD_CD_N: JSD1.10 UR1.10
SD_CLK: CR3.1 JSD1.5 RR5.2
SD_CLK_R: RR5.1 UR1.18
SD_CMD: JSD1.2 UR1.20
SD_D0: JSD1.7 UR1.13
SD_D1: JSD1.8 UR1.12
SD_D2: JSD1.9 UR1.23
SD_D3: JSD1.1 UR1.22
SD_WP: JSD1.11 UR1.11
SDREG: CR4.2 UR1.16
SERIRQ: U11.3 UC1.AV27
SET1_RT3661: PR836.2 PR839.2 PU801.13
SET_VGA: PR1004.1 PR1013.2 PU1001.11
SNB_APU: PC806.1 PR804.2
SNB_APU_NB: PC827.1 PR844.2
SNB_VGA1: PC1042.1 PR1034.2
SNUB_1.35V: PC903.1 PR904.2
SNUB_1V: PC602.1 PR605.2
SPK_L1-: LA7.1 UA1.36
SPK_L1-_CONN: CA67.1 DA3.1 JSPK1.1 LA7.2
SPK_L2+: LA8.1 UA1.35
SPK_L2+_CONN: CA45.1 DA3.3 JSPK1.2 LA8.2
SPK_R1-: LA5.1 UA1.37
SPK_R1-_CONN: CA47.1 DA3.6 JSPK1.3 LA5.2
SPK_R2+: LA6.1 UA1.38
SPK_R2+_CONN: CA71.1 DA3.4 JSPK1.4 LA6.2
SUSCLK_R: JWLAN1.50 R245.1
SUSP: Q411.2 Q412.1 R934.2
SUSP#: PR510.1 Q412.2 R941.1 RP4.5 U11.116 U381.3 U381.5
SVC_RT3661: PC837.1 PR833.1 PU801.19
SVD_RT3661: PC836.1 PR829.1 PU801.20
SVT_RT3661: PR824.1 PU801.21
SYS_PWRGD_EC: C834.1 RC64.1 U11.32 UC24.2
SYS_RST#: CC162.2 RC85.2 RC86.1 UC1.AF1
SYSON: C193.1 PR508.1 PR2223.1 R948.2 U11.95
TESTEN: RV17.2 RV154.2 UV1.K7
TON_DDR: PR507.2 PU501.9
TP_DISABLE#: JTP1.1 U11.70
TP_INT#: JTP1.2 R280.2 UC1.AR29
TSEN_APU: PH802.1 PR830.1 PU801.12
TSEN_APU_R: PC835.1 PH802.2 PR830.2 PR832.2 PR834.1
TSEN_NB: PH801.1 PR821.1 PU801.23
TSEN_NB_R: PC834.1 PH801.2 PR821.2 PR825.1 PR828.1
TSEN_VGA: PH1002.1 PR1003.2 PU1001.10
TSEN_VGA_R: PH1002.2 PR1003.1 PR1021.1 PR1026.2
UG1_APU: PQ801.4 PU801.37
UG1_VGA: PQ1001.1 PU1001.24
UG_CHG: PQ704.4 PU703.23
UG_DDR: PQ501.4 PU501.17
UG_NB: PQ803.4 PU801.31
USB3_ARX_DTX_N1: D301.1 D301.9 JUSB1.5 UC1.W1
USB3_ARX_DTX_N2: D304.1 D304.9 JUSB2.5 UC1.Y1
USB3_ARX_DTX_P1: D301.2 D301.8 JUSB1.6 UC1.W2
USB3_ARX_DTX_P2: D304.2 D304.8 JUSB2.6 UC1.Y2
USB3_ATX_C_DRX_N1: C301.2 D301.4 D301.7 JUSB1.8
USB3_ATX_C_DRX_N2: C839.2 D304.4 D304.7 JUSB2.8
USB3_ATX_C_DRX_P1: C302.2 D301.5 D301.6 JUSB1.9
USB3_ATX_C_DRX_P2: C840.2 D304.5 D304.6 JUSB2.9
USB3_ATX_DRX_N1: C301.1 UC1.R2
USB3_ATX_DRX_N2: C839.1 UC1.P2
USB3_ATX_DRX_P1: C302.1 UC1.R1
USB3_ATX_DRX_P2: C840.1 UC1.P1
USB20_CR_N3: L308.2 UR1.3
USB20_CR_P3: L308.3 UR1.4
USB20_N1: JWLAN1.5 UC1.AV2
USB20_N2: R951.1 UC1.AU2
USB20_N2_L: JEDP1.2 L307.4
USB20_N2_R: L307.3 R951.2
USB20_N3: L308.1 UC1.AT2
USB20_N5: L301.1 UC1.AP2
USB20_N5_R: D302.4 JUSB1.2 L301.2
USB20_N6: L305.1 UC1.AN2
USB20_N6_R: D305.4 JUSB2.2 L305.2
USB20_P1: JWLAN1.3 UC1.AV1
USB20_P2: R950.1 UC1.AU1
USB20_P2_L: JEDP1.4 L307.1
USB20_P2_R: L307.2 R950.2
USB20_P3: L308.4 UC1.AT1
USB20_P5: L301.4 UC1.AP1
USB20_P5_R: D302.3 JUSB1.3 L301.3
USB20_P6: L305.4 UC1.AN1
USB20_P6_R: D305.3 JUSB2.3 L305.3
USB_EN#: R194.1 U11.72 U301.4
USB_OC0#: RC45.2 UC1.AB2
USB_OC1#: R301.2 RC46.2 UC1.AG2
USB_OC1#_U301: R301.1 U301.3
USB_ZVSS: RC108.1 UC1.AN7
USBSS_ZVDD: RC101.1 UC1.W5
USBSS_ZVSS: RC100.1 UC1.W4
VCIN0_PH1: PH201.1 PR206.2 U11.109
VCIN1_AC_IN: C190.1 PQ741.2 PR731.1 PR741.2 PU703.2 R930.1 U11.110
VCIN1_BATT_DROP: PC451.1 PR451.2 PR452.1 U11.64
VCIN1_BATT_TEMP: C189.1 PR205.2 PR778.2 U11.63
VCOUT0_MAIN_PWR_ON: PR411.1 U11.104
VCOUT1_PROCHOT#: R923.1 U11.103
VGA_B+: PC1021.1 PC1034.1 PC1048.1 PC1049.1 PL1002.1 PQ1001.2 PR1032.1
VGA_CLKREQ#: RC133.2 RC134.2 UC1.AV35 UV1.N7
VGA_SMB_CK3: QV1.1 RV6.2 UV1.U7
VGA_SMB_DA3: QV1.4 RV5.2 UV1.U8
VGATE: PR813.2 PU801.3 U11.74
VMB2: JBAT1.1 JBAT1.2 PF201.1
VR_ON: PR851.1 U11.121
VREF_0.775VALW: PC11214.1 PR1458.2 PR1459.1 PU903.3
VREF_PINSET_RT3661: PR826.2 PR831.1 PR838.1 PR846.2 PR847.2 PR848.2 PR849.1 PR850.1 PU801.15
VREF_VGA: PR1001.2 PR1008.1 PR1010.2 PR1011.1 PR1012.2 PU1001.13
VSEN_APU: PC812.1 PC818.1 PC988.1 PR809.1 PR814.2 PR816.2 PU801.8
VSEN_NB: PC810.2 PC814.1 PC986.2 PR808.1 PR811.2 PR812.1 PU801.7
VSEN_VGA: PC1003.1 PC1011.2 PC1026.2 PR1017.1 PR1024.2 PR1027.1 PU1001.21
VTTREF_DDR: PC515.1 PU501.4
WAKE#_R: JWLAN1.55 R249.2
WAKEB: RV162.2 RV163.1 UV1.AJ27
WL_OFF#: RC130.1 UC1.BA13
WL_RST#: JWLAN1.52 R250.1
WLAN_CLKREQ#: R246.1 RPC13.6 UC1.AV29
WLAN_CLKREQ#_R: JWLAN1.53 R246.2
WLAN_DISABLE_R: JWLAN1.56 R248.1
XTALIN: CV17.1 RV20.1 UV1.AM28 YV2.3
XTALOUT: RV1643.1 UV1.AK28
XTALOUT_R: CV18.1 RV20.2 RV1643.2 YV2.1
XTLI: CL14.2 UL2.29 YL1.3
XTLO: CL13.2 UL2.28 YL1.1
N14140561: PC508.2 PD501.1 PR505.2 PU501.12
N14166749: PC2009.1 PJ801.2 PU2001.3
N14166761: PC2002.1 PR2005.2 PR2006.1 PU2001.2
N14166787: PC2004.2 PR2001.2 PR2007.1 PU2001.7
N15305130: JBAT1.5 PR203.1 PR204.1 PR205.1
N16741477: T212.1(TP-1) UV1.AB8
N16741489: T208.1(TP-1) UV1.AD7
N16741505: T214.1(TP-1) UV1.AB4
N16741517: T206.1(TP-1) UV1.AD9
N16741525: T216.1(TP-1) UV1.Y8
N16741803: RV29.2 UV1.AC22
N16741825: RV59.2 UV1.AB22
N16751828: T209.1(TP-1) UV1.AC8
N16751830: T205.1(TP-1) UV1.AE8
N16751834: T203.1(TP-1) UV1.AE9
N16751836: T201.1(TP-1) UV1.N9
N16751838: T215.1(TP-1) UV1.AB2
N16751842: T211.1(TP-1) UV1.AB9
N16751844: T207.1(TP-1) UV1.AC10
N16751848: T202.1(TP-1) UV1.L9
N16751852: T213.1(TP-1) UV1.AB7
N16751854: T210.1(TP-1) UV1.AC7
N16751856: T204.1(TP-1) UV1.Y11
N16751858: T217.1(TP-1) UV1.Y7
N16808781: RV157.1 UV1.AJ11
N16808782: RV155.1 UV1.AK12
N16808783: RV156.1 UV1.AL11
N17005206: PD101.3 PR109.1
N17215242: PR769.2 PU703.3
N17215261: PR727.1 PU703.8
N17215273: PC757.2 PR743.1 PU703.18
N17215298: PR757.1 PU703.17
N17215363: PQ707.2 PR737.1 PR738.2
N17215386: PC767.1 PR766.2
N17215397: PD703.1 PR743.2
N17215405: PQ710.2 PQ711.1
N17215464: PC752.1 PR754.2
N17215501: PR778.1 PU703.13
N17215508: PQ741.1 PR779.1
N17225517: PC2001.1 PR2003.2 PR2008.1 PR2223.2 PU2002.2
N17225535: PC2008.1 PJ803.2 PU2002.3
N17225564: PC2005.2 PR2002.1 PR2004.2 PU2002.7
N17268367: PC608.2 PR612.1
N17268583: PR611.2 PU601.9
N17847259: T4935.1(TP-1) UV1.AL9
N17877344: T223.1(TP-1) UV1.R1
N17877347: T224.1(TP-1) UV1.R3
N20132221: C831.1 R921.2
N20280223: LED2.2 R377.1
N20455593: LED3.2 R376.1
N20455694: LED4.2 R378.1
N22463592: T26.1(TP-1) UC1.AP27
N22797561: T60.1(TP-1) UC1.D35
N22797567: UC1.AM23 VSS_SENSE1.1(TP-1)
N22799035: CV271.1 U1895V.10
N22799039: CV281.1 U1895V.12
N22800917: QV17.1 RV42.2
N22801416: QV21.6 RV57.1
N22801421: QV21.3 RV56.1
N22801431: QV11.1 RV45.1
N22840797: RV121.1 UV8.J13
N22840814: RV117.1 UV8.J1
N22840825: RV119.1 UV8.J10
N22841005: RV120.1 UV7.J13
N22841028: RV116.1 UV7.J1
N22841062: RV118.1 UV7.J10
N23123559: Q401.3 R946.2
N23712513: JWLAN1.38 R243.1 R251.2
N23727534: Q83.1 R935.2
N23728403: R937.2 R941.2 U18.3
N23728440: C860.1 U18.6
N24107383: RL9.2 UL2.31
N24107515: CL19.1 RL19.2
N24108268: TPL1.1(TP-1) UL2.25
N24108270: TPL2.1(TP-1) UL2.27
N24222879: JWLAN1.40 R244.1
N24293759: QC18.3 QC19.3
N24293761: QC20.3 QC21.3
N24299188: QC22.2 QC22.3 RC153.1
N24380776: PR608.1 PR2221.2 PR2222.1
N24409303: CA60.1 RA53.1 UA1.33
N24409452: CA52.1 RA50.2
N24409678: CA63.1 UA1.15
N24409882: CA68.1 UA1.22
N24410711: CA57.2 UA1.30
N24410726: CA57.1 UA1.28
N24468122: C272.1 D303.2 JKB1.30 R272.2
N24468142: D303.3 JKB1.31 R283.2
N25213376: QV18.2 RV1644.2
N25219617: CR5.2 UR1.1
N28714558: PR777.2 PU703.5
N31626633: PR831.2 PR832.1
N31626674: PR838.2 PR839.1
N31627184: PR825.2 PR826.1
N31646442: PC833.1 PR850.2
N33488216: PR770.2 PU703.4
N37640332: RV2.2 UV1.N10
N37640410: RV3.1 UV1.AA22
N37828209: RV1.1 UV1.Y22
N38038746: CV96.1 RV36.2 RV37.2
N38038992: CV98.2 UV1.K8
N38038994: CV99.2 UV1.L7
N38038995: CV98.1 RV40.2
N38038996: CV99.1 RV41.2
N38349725: RV39.2 UV1.K25
N72585933: PC517.1 PR503.2
N99502843: T28.1(TP-1) UC1.AU23
N99511855: CC9.1 RC71.2 RC73.1 UC23.1 UC23.2
N102084029: Q411.1 R933.2
N110838109: QH17.1 RPH1.1 RPH1.2 RPH1.3 RPH1.4 RPH2.1 RPH2.2 RPH2.3 RPH2.4
N115820979: C847.1 U381.12
N115820982: C848.1 U381.10
N119889933: PR1004.2 PR1010.1
N119889936: PR1012.1 PR1021.2
N119896729: PR1007.2 PR1013.1
N119896747: PR1023.2 PR1026.1
N119932245: PC1016.1 PR1032.2 PU1001.1
N119936487: PC1008.1 PR1001.1
N119936846: PH1001.1 PR1008.2 PR1009.1
N119936854: PH1001.2 PR1011.2

Pads without a net: D1 2; D302 1 6; D305 1 6; DL1 5; DL2 5; FD1 1; FD2 1; FD3 1; FD4 1; JBAT1 6; JDIMM1 87 88 91 92 95 96 97 100 101 104 105 162 165; JEDP1 3 16 22 26; JHDMI1 13 14; JWLAN1 6 8 9 10 11 12 13 14 15 16 17 19 20 21 22 23 32 34 36 42 44 46 48 58 59 60 61 62 64 65 66 67 68 70 71 73; PU401 10 15; PU402 10; PU501 10; PU601 10 12; PU703 7; PU801 1 2 39 40; PU901 9 10 12; PU1001 22 28 29 30 31; PU2001 5; PU2002 1 5; RPC2 8; RPC3 1 8; RPC5 1 8; RPC6 1 8; RPC9 4 5; RPC13 4 5; RPC14 4 5; U11 14 16 17 18 19 21 27 29 36 75 83 84 85 86 87 102 106 107 118 119 120 126 127 128; U202 3; UA1 10; UC1 A3 A11 A12 A19 A20 A21 A22 AA4 AA37 AA38 AA40 AB1 AC4 AC5 AD1 AE8 AE34 AE37 AE38 AG5 AG8 AH2 AJ1 AJ2 AJ4 AJ34 AK1 AK2 AL4 AL5 AL8 AL34 AM1 AM2 AM15 AM17 AM19 AN8 AN34 AP13 AP15 AP17 AP19 AP21 AP23 AP25 AR1 AR2 AR13 AR15 AR17 AR21 AR25 AR38 AU4 AU13 AU15 AU17 AU27 AU33 AV7 AV9 AV11 AV13 AV15 AV17 AV21 AV23 AV25 AV33 AW1 AW2 AY3 AY7 AY13 AY18 AY29 AY31 B3 B11 B12 B19 B20 B21 B22 BA21 BA27 BA28 C1 C2 D9 D11 D13 D19 E4 E31 G19 H11 H13 H19 J1 J2 J37 L1 L2 L11 L34 N4 N5 R8 R10 T1 T2 V1 V2; UC21 1; UC22 1; UC24 1; UR1 9 14 15 17 19 21; UV1 AA5 AA6 AA29 AA31 AB23 AB25 AB26 AB27 AB30 AC1 AC3 AC5 AC6 AC16 AC23 AC25 AD2 AD4 AD10 AD11 AD13 AD16 AD22 AD23 AD24 AE1 AE3 AE5 AE6 AE10 AE11 AE13 AE16 AE19 AE22 AE23 AE24 AE25 AE26 AF2 AF4 AF6 AF7 AF8 AF9 AF10 AF11 AF13 AF16 AF17 AF22 AF24 AF25 AG1 AG3 AG5 AG6 AG7 AG8 AG9 AG10 AG11 AG13 AG15 AG16 AG17 AG18 AG19 AG20 AG21 AG22 AG24 AG25 AG26 AH1 AH3 AH5 AH6 AH8 AH12 AH16 AH18 AH20 AH22 AH24 AH26 AJ7 AJ9 AJ13 AJ15 AJ17 AJ19 AJ21 AJ23 AJ25 AK1 AK3 AK5 AK6 AK8 AK10 AK14 AK16 AK18 AK20 AK22 AK24 AK26 AL7 AL13 AL15 AL17 AL19 AL21 AL23 AL25 AM3 AM5 AM6 AM8 AM10 AM12 AM26 J8 J22 J25 K13 K30 L16 L17 L29 L31 M4 M27 M28 M30 N3 N5 N6 N8 N26 N29 N31 P2 P4 P7 P10 P23 P24 P26 P27 P28 P30 R6 R29 R31 T2 T4 T7 T23 T24 T26 T27 T28 T30 U5 U6 U23 U24 U26 U29 U31 V2 V4 V6 V27 V28 V30 W3 W5 W6 W7 W8 W23 W24 W29 W31 Y2 Y4 Y6 Y23 Y24 Y26 Y27 Y28 Y30; UV7 A5 A10 U5 U10; UV8 A5 A10 U5 U10; YC48 2 4

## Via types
v1: diameter 0.457, hole 0.203, TOP to BOTTOM, 4328 vias
v2: diameter 0.305, hole 0.152, TOP to BOTTOM, 508 vias
v3: diameter 0.406, hole 0.203, TOP to BOTTOM, 232 vias
v4: diameter 0.508, hole 0.254, TOP to BOTTOM, 36 vias

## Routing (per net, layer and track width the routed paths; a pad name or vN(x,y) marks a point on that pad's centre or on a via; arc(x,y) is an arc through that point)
0.95VS_GATE: length 8.3
  TOP w0.102: v2(64.29,33.83) 64.88,34.41 Q19.4
  TOP w0.254: Q84.1 63.27,30.32 63.67,30.71 R947.2 63.69,31.04 C859.1 65.24,31.04 65.79,31.59 Q19.4
0.95VS_PWR_EN#: length 171
  TOP w0.102: Q83.2 59.96,28.46 60.29,28.8 61.79,28.8 Q84.2 62.94,28.28 62.94,28.96 62.13,29.77 62.13,32.16 v2(62.4,32.43) 62.7,32.73 63.27,32.73 v1(63.78,32.22) ; RP4.6 170.33,43.52 v1(170.63,43.82) ; U11.99 165.1,48.42 v1(165.24,48.29)
  IN1 w0.127: v1(167.54,48.22) 167.54,45.13 168.6,44.07 168.6,42.25 167.67,41.32 167.67,34.48 165.5,32.31 160.73,32.31 158.24,29.82 156.11,29.82 154.11,27.82 154.11,21.07 153.15,20.11 153.15,19.52 150.56,16.93 150.56,13.58 149.84,12.86 144.5,12.86 144,13.37 141.85,13.37 141.34,12.86 141.34,12.06 139.06,9.78 119.38,9.78 118.59,10.57 118.01,10.57 v1(117.5,10.06)
  BOTTOM w0.102: v1(117.5,10.06) 116.55,9.11 100.68,9.11 97.82,11.97 94.22,11.97 90.2,15.99 90.2,20.79 83.02,27.97 82.77,27.97 79.89,30.85 68.65,30.85 67.97,31.53 64.48,31.53 v1(63.78,32.22) ; v1(165.24,48.29) 165.31,48.22 v1(167.54,48.22) 169.27,48.22 170.15,47.33 170.15,44.25 170.58,43.82 v1(170.63,43.82)
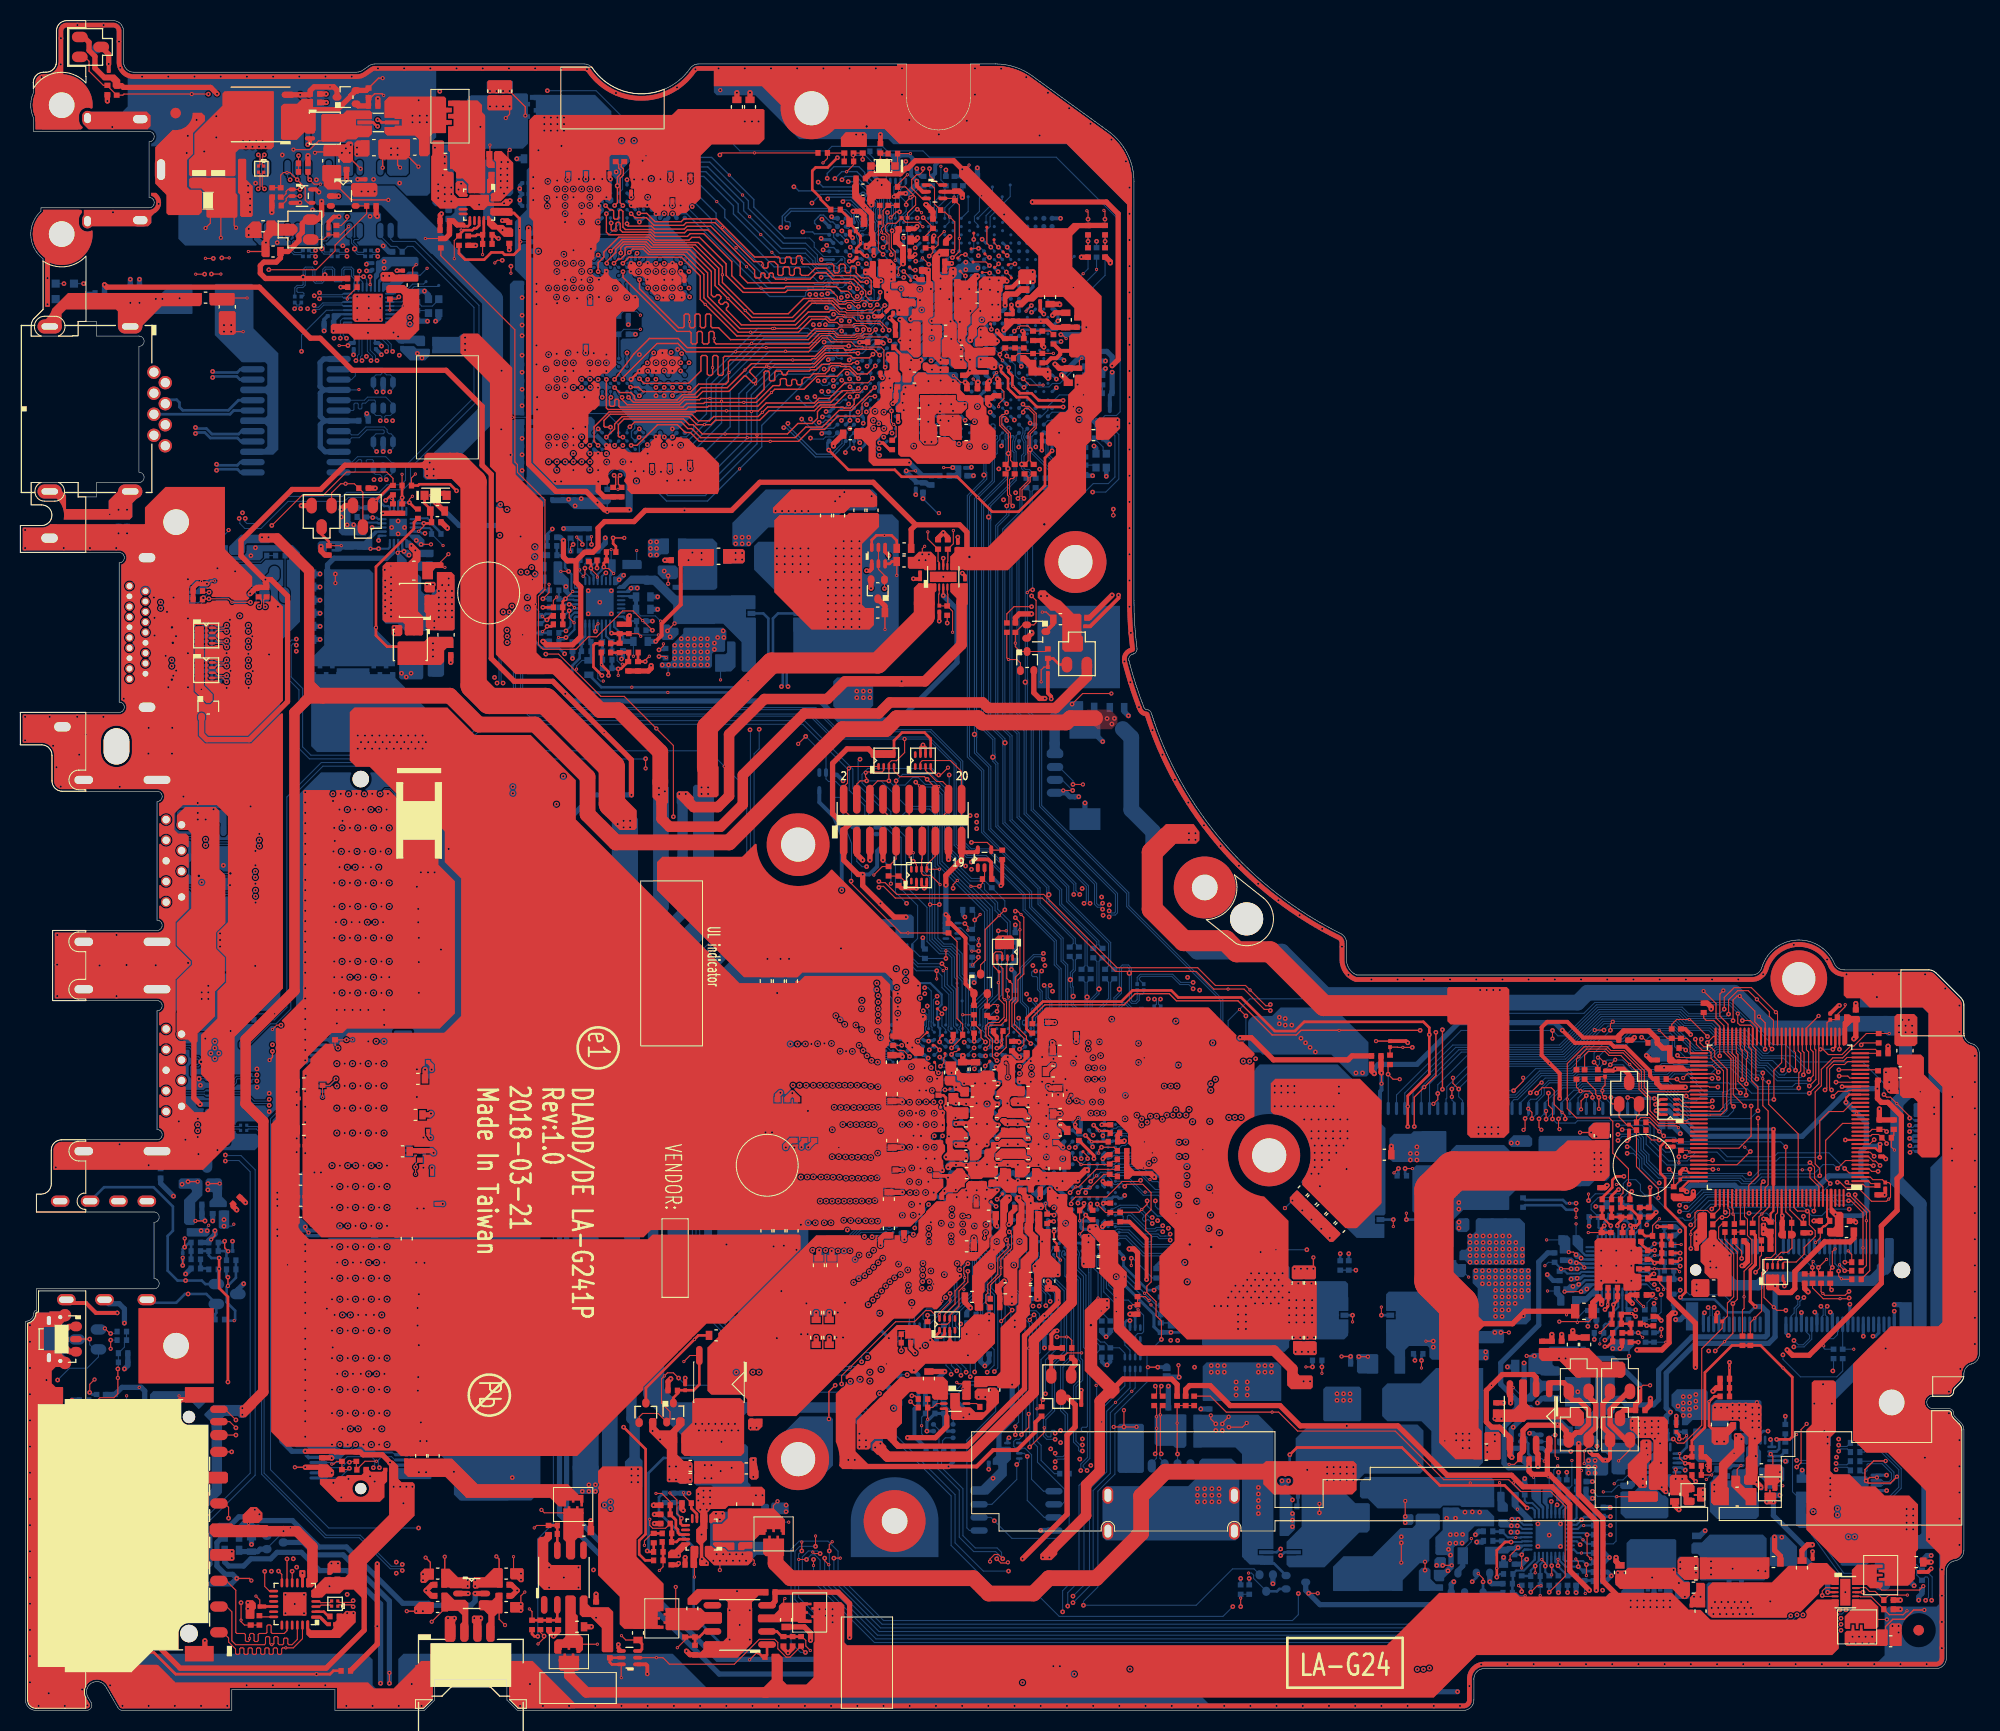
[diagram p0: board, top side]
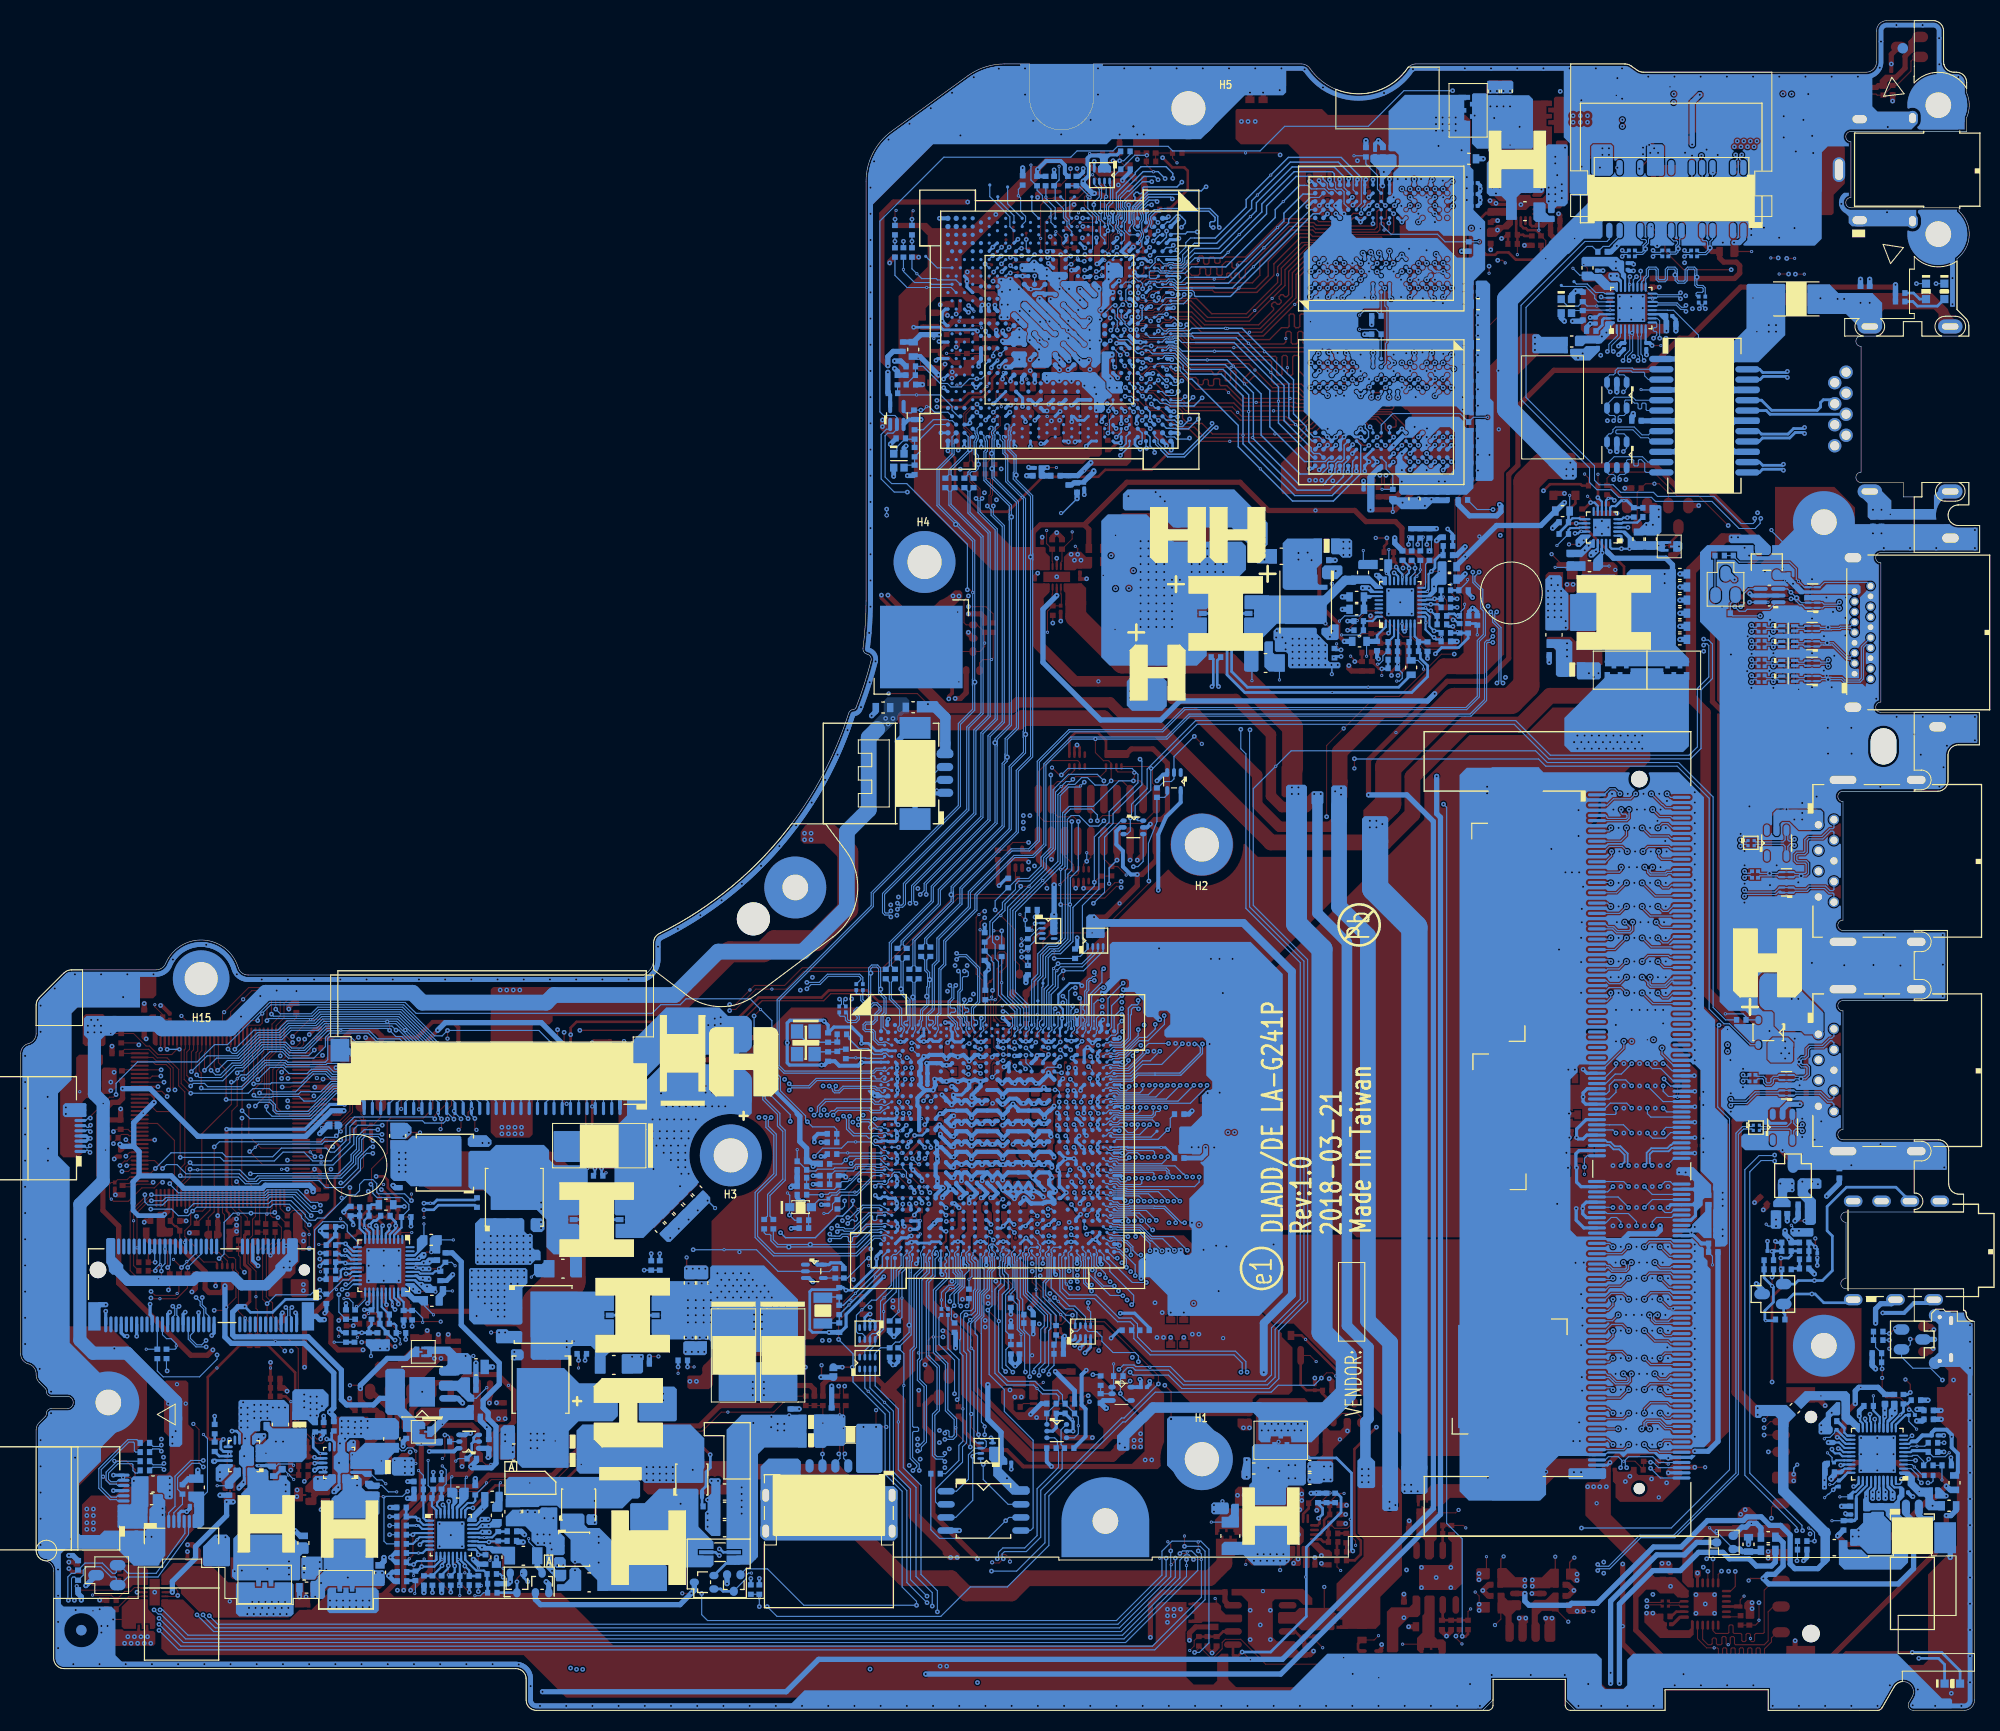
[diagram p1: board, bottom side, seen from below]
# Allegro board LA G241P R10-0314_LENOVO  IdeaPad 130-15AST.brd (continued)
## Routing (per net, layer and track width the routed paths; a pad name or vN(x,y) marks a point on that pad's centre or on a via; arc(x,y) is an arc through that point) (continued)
0.775VALW_GATE: length 19.4
  TOP w0.381: QC20.2 154.07,24.45 153.85,24.24 v2(153.61,24.24) 153.38,24.24 152.85,24.77 152.39,24.77 v1(152.11,25.05)
  TOP w0.508: QC20.2 154.07,26.78 153.38,27.46 153.38,29.75 154.07,30.43 QC21.2 ; UC26.7 146.9,25.05 147.08,24.87 RC151.2 v1(147.08,23.65)
  IN2 w0.508: v1(147.08,23.65) 147.08,24.15 149.57,26.64 151.48,26.64 151.92,26.19 151.92,25.24 v1(152.11,25.05)
1.8VALW_PWR_EN#: length 4
  TOP w0.102: Q401.6 v2(58.22,3.17)
  TOP w0.254: Q401.5 57.13,5.11 R945.2 57.11,4.67 57.32,4.46 Q401.6
1.8VS_PWR_EN: length 102.4
  TOP w0.102: U11.98 164.7,48.67 R949.2 163.99,47.99 163.5,48.48 162.55,48.48 162.31,48.24 162.31,46.91 161.9,46.5 v2(161.9,46.16) v1(161.9,44.79) ; R937.1 86.82,29.56 86.64,29.56 v1(86.26,29.94)
  IN1 w0.127: v1(86.26,29.94) 91.91,29.94 92.99,28.86 102.26,28.86 105.5,25.62 113.04,25.62 113.48,25.18 120.8,25.18 121.69,26.07 135.07,26.07 137.52,23.61 144.41,23.61 148.52,27.72 149,27.72 154.52,33.24 157.85,33.24 162.08,37.47 162.08,39.38 163.31,40.61 163.31,44.09 162.61,44.79 v1(161.9,44.79)
3V/5VALW_PG: length 180.3
  TOP w0.102: v1(76.07,5.62) 75.66,6.04 PR2005.1 74.58,5.16 74.21,5.16 73.4,5.98 73.4,6.59 73.09,6.89 71.59,6.89 69.18,4.48 62.89,4.48 62.26,5.11 v2(61.62,5.11) Q401.2 ; R922.2 164.91,47.16 164.59,46.84 164.59,45.76 166.06,44.3 166.06,40.11 165.45,39.5 165.45,38.23 C2155.2 164.94,37.05 162.96,35.07 162.96,27.64 161.23,25.91 160.6,25.91 v1(160.2,26.31)
  IN1 w0.254: v1(160.2,26.31) 160.2,27.04 160.87,27.72 165.51,27.72 165.74,27.49 167.1,27.49 167.79,26.79 169.09,26.79 v1(169.38,27.08)
  IN2 w0.127: v1(123.85,11.33) 124.51,10.68 133.07,10.68 134.33,11.94 142.51,11.94 142.92,12.35 145.94,12.35 146.2,12.1 150.76,12.1 151.67,11.18 153.55,11.18 154.9,12.53 160.23,12.53 160.56,12.86 160.68,12.86 161.38,13.56 161.38,14.44 161.95,15.02 161.95,20.8 161.57,21.18 161.57,22.53 161.21,22.89 161,22.89 160.56,23.33 160.56,25.37 160.2,25.72 v1(160.2,26.31)
  BOTTOM w0.102: v1(123.85,11.33) 123.85,9.28 123.28,8.71 83.65,8.71 79.24,13.12 79.24,15.44 78.26,16.41 75.47,16.41 74.68,15.63 74.68,6.55 75.6,5.62 v1(76.07,5.62)
  BOTTOM w0.254: v1(160.2,26.31) 160.13,26.24 159.72,26.24 ; v1(169.38,27.08) 168.92,27.08 168.65,26.82 PU402.9 ; PR406.2 159.72,26.89 159.72,26.24 ; PU401.9 159.46,25.98 159.72,26.24
3V/5VALW_PG_R: length 2.6
  TOP w0.102: U11.101 165.9,48.7 165.99,48.61 v2(165.99,48.13) 166.12,48 R922.1
3V_FB: length 2.8
  TOP w0.102: v2(160.82,24.91) 160.82,24.45 161.32,23.96 v1(161.36,23.96)
  TOP w0.254: PC402.1 161.76,23.96 v1(161.36,23.96)
  BOTTOM w0.254: PU401.13 161.29,24 161.33,23.96 v1(161.36,23.96)
3V_FB_1: length 1.9
  TOP w0.102: PR403.1 v2(163.92,22.83)
  TOP w0.254: PC402.2 PR403.1
3V_SN: length 2
  TOP w0.102: PR405.2 v2(154.73,20.73)
3VGS_EN#: length 4.9
  TOP w0.102: v2(98.92,99.74) 98.92,100.89 99.2,101.17 CV83.1
  TOP w0.254: CV83.1 RV43.2 100.09,102.01 100.69,101.41 QV16.2
5V_3V_EN: length 30.3
  TOP w0.254: v1(161.38,24.54) 161.44,24.6 PR412.1 PC428.1 162,26.18 163.26,27.44 163.26,32.76 165.89,35.39 PR411.2 PR410.2 168.66,35.39 v2(170.84,33.2) 171.73,32.31 171.73,26.52 171.49,26.28 v1(170.22,26.28)
  BOTTOM w0.254: PU402.12 170.21,25.11 170.46,25.35 170.46,26.04 v1(170.22,26.28) ; v1(161.38,24.54) 161.29,24.45 PU401.12
5V_FB: length 1.5
  BOTTOM w0.254: PC413.1 170.61,24.66 PU402.13
5V_FB_1: length 0.8
  BOTTOM w0.254: PR407.1 PC413.2
5V_SN: length 1.6
  TOP w0.102: PC426.1 166.4,23.39 v2(166.77,23.75)
+0.6V_DDR_VREFCA: length 0.7
  TOP w0.102: v1(27.59,46.88) 27.59,46.65 v3(27.9,46.33)
+0.6VS: length 97
  TOP w0.127: v1(27.59,23.58) v3(26.58,23.58)
  TOP w0.508: R933.1 29.5,112.03 29.11,112.43 v1(29.11,112.87) ; CD207.1 v1(27.59,23.58)
  IN1 w0.508: v1(27.59,23.58) 26.94,24.22 26.94,51.43 25.44,52.93 25.44,60.81 26.7,62.07 26.7,101.25 27.59,102.14 27.59,111.13 29.11,112.65 v1(29.11,112.87)
  BOTTOM w0.305: JDIMM1.258 v1(30.16,23.04)
+0.6VSP: length 4
  TOP w0.102: v3(33.91,112.65) v1(34.7,112.65)
  BOTTOM w0.203: PU501.20 35.79,112.79 35.65,112.65 v1(34.7,112.65) 33.27,112.65 PC507.1
+0.95VALW: length 137.7
  TOP w1.016: 83.47,25.18 84.04,24.6 91.98,24.6 98.21,30.84 98.21,35.91 101.88,39.58 101.88,42.13
  TOP w2.032: 87.59,107.35 87.59,106.08 83.09,101.57 72.8,101.57 66.58,95.34 66.58,91.34
  BOTTOM w0.4: v1(100.51,49.7) 100.51,49.82 UC1.AL11 100.16,50.16 v1(99.76,50.55) ; UC1.AL13 99.54,50.53 99.71,50.53 99.73,50.55 v1(99.76,50.55) ; UC1.AJ11 99.85,50.84 99.85,50.64 v1(99.76,50.55)
  BOTTOM w1.016: 81.05,28.41 80.1,29.37 69.75,29.37
  BOTTOM w2.032: 64,28.13 61.37,30.76 61.37,34.32 63.72,36.67 63.72,73.82 66.19,76.29 66.19,87.22
  vias: v1(65.43,27.78) v1(65.75,27.14) v1(66,89.5) v1(66,88.87) v1(66.07,27.78) v1(66.39,27.14) v1(66.64,89.5) v1(66.64,88.87) v1(66.7,27.78) v1(67.02,27.14) v1(67.34,27.78) v1(67.66,27.14) v1(67.97,27.78) v1(68.29,27.14) v1(68.61,27.78) v1(68.93,27.14) v1(69.24,27.78) v1(69.56,27.14) v1(82.83,25.49) v1(83.34,25.87) v3(67.93,26.04)
+0.95VALWP: length 14.4
  TOP w0.254: PC608.1 61.37,15.47 61.36,15.46 PR2221.1 60.82,15.37 v1(60.73,15.46)
  BOTTOM w0.254: 65.5,24.48 62.32,24.48 60.86,23.02 60.86,15.59 v1(60.73,15.46)
  vias: v1(66.32,23.78) v1(66.32,22.51) v1(66.96,23.78) v1(66.96,22.51) v1(68.93,23.53) v3(67.86,23.21)
+0.95VGS: length 32.6
  TOP w0.102: v2(87.63,112.88) 87.4,112.65 v1(87.4,112.11)
  TOP w0.254: LV8.1 77.56,146.51 77.56,146.65 76.74,147.48 76.74,149.29 77.07,149.62 78.23,149.62 v1(79.17,150.56)
  IN1 w0.254: v1(79.17,150.56) 79.81,150.56 81.43,148.94 83.4,148.94 84.7,147.64 97.53,147.64 98.73,146.44 98.73,144.14
  BOTTOM w0.381: v1(95.43,136.27) 95.43,135.93 UV1.AD14
  vias: v1(85.49,126.8) v1(85.62,127.65) v1(85.6,126.08) v1(85.76,128.29) v1(86.76,128.46) v1(87.09,111.54) v1(87.72,111.54) v1(88,128.9) v1(88.04,112.11) v1(89.18,128.96) v1(90.38,128.88)
+0.95VS: length 39.7
  TOP w0.305: v1(104.04,53.51) 104.04,53.8 RC1.1 ; v1(100.14,47.42) 99.72,47.42 RC89.2
  IN1 w0.381: v1(91.04,42.13) 91.29,41.88 92.1,41.88 92.43,42.2 92.43,43.88 93.4,44.85 95.71,44.85 96.19,45.33 96.19,45.7 97.46,46.97 99.19,46.97 99.64,47.42 v1(100.14,47.42)
  IN2 w0.254: v1(94.65,50.45) 94.97,50.77 99.27,50.77 100.35,51.85 102.52,51.85 102.87,52.2 102.87,52.7 103.09,52.93 103.85,52.93 104.04,53.12 v1(104.04,53.51)
  BOTTOM w0.381: v1(92.68,50.43) UC1.AL27 ; v1(92.68,50.43) UC1.AJ27 v1(91.67,50.41) ; v1(92.68,50.43) UC1.AJ25 v1(93.66,50.48) ; v1(92.68,50.43) UC1.AL25 ; UC1.AL27 v1(91.77,49.76) ; UC1.AL27 v1(91.67,50.41) ; v1(93.66,50.48) UC1.AL25 ; v1(93.66,50.48) UC1.AL23 ; v1(93.66,50.48) UC1.AJ23 v1(94.65,50.45) ; v1(94.65,50.45) UC1.AL23 ; v1(94.65,50.45) UC1.AJ21 ; UC1.AL23 v1(93.53,49.61) UC1.AL25 ; v1(91.67,50.41) UC1.AL29 v1(90.74,49.78)
  vias: v1(75.66,36.48) v1(76.16,39.46) v1(76.29,36.48) v1(79.09,36.16) v1(79.21,38.57) v1(79.72,36.16) v1(79.91,39.53) v1(88.23,47.34) v3(73.31,36.1)
+0.775VALW: length 25.6
  TOP w0.102: v1(156.94,31.21) 157.25,31.53 v3(157.95,31.53)
  TOP w0.508: QC20.1 155.03,28.73 155.41,29.11 CC130.2 156.54,29.67 156.94,30.07 v1(156.94,31.21)
  IN1 w0.381: v1(156.94,31.21) 155.41,31.21 151.67,27.46 151.67,25.56 151.22,25.11 v1(150.27,25.11)
  BOTTOM w0.381: v1(150.27,25.11) 147.86,25.11 147.55,25.42 QC22.6
  BOTTOM w0.508: v1(156.94,31.21) 156.94,31.53 154.33,34.13 152.49,34.13 151.86,34.76
+0.775VALWP: length 0.7
  TOP w0.102: v1(146.74,34.37) v3(145.99,34.37)
+1.2V: length 61.3
  BOTTOM w0.3: v1(87.12,60.11) 87.12,60.31 UC1.L37 ; v1(87.63,62.29) 87.57,62.23 UC1.J35
  BOTTOM w0.305: v1(87.99,51.26) 87.99,51.18 UC1.AJ35 ; JDIMM1.136 v1(27.59,55.54) ; v1(89.37,56.76) 89.17,56.55 UC1.W32 ; JDIMM1.160 27.96,47.54 27.52,47.97 27.52,48.99 ; JDIMM1.153 38.1,49.29 38.45,48.94 v1(38.45,48.67) 38.45,48.15 38.08,47.79 JDIMM1.159 ; JDIMM1.163 38.34,46.79 39.08,47.53 v1(39.08,48.67) ; v1(87.77,60.11) 87.57,59.91 UC1.N35 ; v1(88.6,53.49) 89.13,52.96 UC1.AE32 89.34,52.79 v1(89.34,52.37) 89.17,52.21 UC1.AG32 UC1.AJ32 89.06,50.76 v1(88.51,50.21) 89.05,49.66 UC1.AL32 ; v1(88.6,53.49) UC1.AC32 ; v1(88.6,53.49) 88.58,53.51 v1(87.77,53.51) 87.57,53.31 UC1.AE35 ; UC1.AG37 86.77,52.1 v1(87.22,52.55) ; v1(88.84,61.25) 89.17,60.92 UC1.L32 ; UC1.U35 87.48,57.36 87,56.87 v1(87,56.81) ; JDIMM1.117 38.01,60.29 38.41,59.88 v1(38.41,59.48) 38.41,59.04 38.16,58.78 JDIMM1.123 ; 27.73,49.03 JDIMM1.154 29.91,49.03 v1(30.18,48.76) ; JDIMM1.129 38.12,57.29 39.05,56.36 v1(39.05,55.55) 38.92,55.42 38.41,55.42 38.05,55.79 JDIMM1.135 ; JDIMM1.141 38.81,54.29 39.11,53.98 39.11,52.69 v1(39.05,52.63) 39.05,51.23 38.6,50.79 JDIMM1.147 ; v1(86.8,57.93) 86.8,58.43 UC1.R37 ; UC1.W37 86.77,55.95 v1(86.55,55.73) ; v1(87.19,49.13) 87.19,49.24 UC1.AL37 ; JDIMM1.112 27.65,61.54 v1(27.64,61.55) ; JDIMM1.148 27.55,50.54 27.52,50.51 ; v1(89.38,57.94) 89.17,57.72 UC1.U32 ; JDIMM1.118 v1(27.59,60.04) ; UC1.AR35 87.57,47.66 v1(87.12,48.11) ; UC1.AC37 86.77,54.41 v1(86.97,54.61) 87.52,55.16 UC1.AA35 87.57,55.41 v1(87.28,55.7) ; JDIMM1.142 v1(27.59,54.03) ; v1(38.41,62.16) 38.03,61.78 JDIMM1.111 ; JDIMM1.124 v1(27.59,58.54) ; JDIMM1.130 v1(27.59,57.03)
  BOTTOM w0.457: v1(75,54.58) 75,53.97 75.42,53.56 RC3.2 ; RC4.1 76.63,57.82 v1(76.32,58.13)
  vias: v1(28.48,52.16) v1(29.11,52.16) v1(30.18,50.79) v1(30.95,52.83) v1(31.41,62.72) v1(31.41,60.56) v1(31.41,58.4) v1(31.41,55.99) v1(31.71,50.79) v1(31.71,48.76) v1(32.47,46.98) v1(32.68,94.53) v1(32.68,93.26) v1(33,93.9) v1(32.94,62.72) v1(32.94,60.56) v1(32.94,58.4) v1(32.94,55.99) v1(33.23,52.83) v1(33.23,50.79) v1(33.23,48.76) v1(33.38,94.53) v1(33.38,93.26) v1(33.7,93.9) v1(33.7,64.88) v1(33.99,46.98) v1(34.08,94.53) v1(34.08,93.26) v1(34.39,93.9) v1(34.46,62.72) v1(34.46,60.56) v1(34.46,58.4) v1(34.46,55.99) v1(34.78,94.53) v1(34.78,93.26) v1(34.76,50.79) v1(34.76,48.76) v1(35.09,93.9) v1(35.47,94.53) v1(35.47,93.26) v1(35.52,52.83) v1(35.52,46.98) v1(35.79,93.9) v1(36.17,94.53) v1(36.17,93.26) v1(36.49,93.9) v1(36.87,94.53) v1(36.87,93.26) v1(37.19,93.9) v1(37.57,94.53) v1(37.57,93.26) v1(37.89,93.9) v1(38.27,94.53) v1(38.27,93.26) v1(38.59,93.9) v1(38.97,94.53) v1(38.97,93.26) v1(39.28,93.9) v1(72.2,56.05) v1(72.84,56.05) v1(75.63,47.09) v1(76.66,64.62) v1(77.92,64.68) v1(80.01,63.92) v3(41.49,83.53)
+1.2VP: length 17.3
  TOP w0.102: v1(30.51,110.2) v3(30.51,109.31)
  IN2 w0.203: v1(30.51,110.2) 33.11,112.81 33.11,115.16 33.62,115.66 v1(34.13,115.66)
  BOTTOM w0.203: v1(34.13,115.66) 34.51,115.66 34.66,115.51 PU501.5
  BOTTOM w0.254: v1(34.13,115.66) 34.08,115.71 PR506.2
  BOTTOM w0.508: PC514.1 29.75,111.09 30.38,111.73 35.46,111.73 35.94,112.21
+1.8VALW: length 165.6
  TOP w0.508: v1(98.77,49.69) 98.85,49.77 CC54.1 ; v1(99.6,41.62) 99.72,41.5 CC53.1 100.27,40.92 100.55,40.65 100.55,39.51 99.3,38.27 v1(99.25,38.27) 97.31,36.33 97.31,31.2 91.73,25.62 85.05,25.62 84.74,25.94
  TOP w1.016: 91.21,107.43 91.21,103.34 87.66,99.79 v3(85.4,99.79) 79.91,99.79 78.2,98.07 72.1,98.07 68.67,94.65 68.67,88.68 67.59,87.6 65.24,87.6 64.8,88.04
  IN1 w0.508: v1(99.25,38.27) 101.6,38.27 102.78,37.09 105.5,37.09 108.07,34.52 111.78,34.52 113.76,36.5 113.76,40.92 115.18,42.35 v1(115.18,46.73)
  BOTTOM w0.381: RC60.1 115.14,46.77 v1(115.18,46.73)
  BOTTOM w0.4: 98.26,50.16 98.73,49.69 v1(98.77,49.69) ; 98.26,50.16 98.34,50.16 99.17,50.99 UC1.AJ13 ; 98.26,50.16 UC1.AL15
  BOTTOM w1.016: 64.16,87.98 64.16,77.31 61.31,74.45 61.31,37.3 59.21,35.21 59.21,28.29 59.51,27.98 59.51,24.36
  vias: v1(59.21,23.4) v1(59.21,22.76) v1(59.21,22.13) v1(59.84,23.4) v1(59.84,22.76) v1(59.84,22.13) v1(63.85,88.87) v1(64.48,88.87) v1(81.31,26.83) v1(81.31,26.19) v1(81.31,25.56) v1(81.94,26.19) v1(81.94,25.56)
+1.8VALWP: length 2.3
  TOP w0.102: 63.5,9.71 v3(63.5,11.97)
+1.8VGS: length 105.7
  TOP w0.381: 101.88,131.79 101.83,131.84 100.77,131.84 ; 100.77,131.84 RV28.1 ; 100.77,131.84 100.77,131.5 100.39,131.12 99.88,131.12 99.44,130.68 RV11.1 ; v1(97.11,133.75) 97.24,133.62 RV8.1
  TOP w0.457: LV6.1 86.67,143.67 v1(86.9,143.9)
  TOP w0.508: 53.84,111.47 54.68,112.31 PR1005.1 55.48,112.31 55.97,112.81 55.97,114.65 56.61,115.28 59.46,115.28 60.54,116.36 v3(64.35,116.36) 68.93,116.36 71.66,119.09 82.64,119.09 86.77,114.97 ; 53.84,111.47 53.84,109.4 54.3,108.95 54.3,104.13 53.49,103.33 50.97,103.33 v1(50.64,103.66) ; 53.84,111.47 53,111.47 52.62,111.85 v1(52.62,113.43) ; RV57.2 86.32,114.52 86.77,114.97 ; 86.77,114.97 91.02,114.97 91.72,114.27 91.72,112.55 ; RV87.2 RV84.2 ; v1(91.28,149.45) 90.45,150.27 86.73,150.27 85.99,149.53 85.79,149.53 85.26,149 82.34,149 LV7.1
  IN1 w0.508: v1(95.34,145.06) 94.27,144 87,144 v1(86.9,143.9)
  BOTTOM w0.254: UV1.AM30 v1(100.66,123.89) ; v1(103.3,134.13) 100.69,134.13 100.44,133.88 97.24,133.88 v1(97.11,133.75)
  BOTTOM w0.305: v1(96.67,136.28) 96.78,136.17 UV1.AF14
  BOTTOM w0.381: RV152.2 88.65,149.05 88.65,149.84 89.05,150.25 90.48,150.25 v1(91.28,149.45) 91.34,149.38 RV81.2 RV82.2
  BOTTOM w0.508: PR1006.2 52.29,113.76 v1(52.62,113.43) ; RV15.1 v1(102.45,128.57) ; PR1016.2 v1(50.64,103.66)
+1.8VS: length 355.4
  TOP w0.254: RPC4.5 84.66,94.04 85.45,94.82 87.62,94.82 88.22,94.23 RPC3.5
  TOP w0.381: RC25.2 92.42,69.49 QC1.2 92.41,69.64 91.59,70.45 91.59,74.9 90.19,76.31 RC14.1 89.94,76.93 v1(89.69,77.18) ; 91.21,83.22 92.55,83.22 UC21.5
  TOP w0.508: JHDT1.19 91.21,82.49 89.69,80.97 v1(89.69,80.04) ; PR818.2 158.14,40.29 v1(158.19,40.34) ; 82.63,92.8 82.2,93.24 80.1,93.24 78.7,91.84 78.7,86.96 79.28,86.39 79.91,86.39 v1(80.36,85.95) 79.78,85.37 JHDT1.1 79.78,82.45 81.18,81.06 v1(81.63,81.06) 81.63,79.97 v3(83.34,78.25) 84.67,76.93 v1(85.82,76.93) ; v1(14.37,22.44) 14.32,22.44 13.6,23.16 12.84,23.16 11.97,24.03 7.97,24.03 6.76,22.83 3.9,22.83 3.2,22.13 v1(3.2,21.75) 4.28,20.67 4.73,20.67 9.3,16.1 12.92,16.1 v1(13.74,16.92)
  IN1 w0.508: v1(96.42,76.17) 95.47,76.17 94.01,77.63 90.13,77.63 v1(89.69,77.18) 89.44,76.93 v1(85.82,76.93) ; v1(113.79,33.28) 113.18,33.89 107.65,33.89 106.12,35.41 103.42,35.41 101.29,37.55 97.35,37.55 97.08,37.81 v1(96.37,37.81) ; v1(94.26,22.51) 92.42,22.51 v1(87.85,27.08) 87.72,27.21 83.89,27.21 82.75,28.34 82.08,28.34 79.53,30.89 78.58,30.89 77.62,31.84 70.31,31.84 v1(69.37,32.78) 69.17,32.99 62.19,32.99 59.21,30 59.21,27.27 57.62,25.68 57.62,21.49 58.57,20.54 58.57,18.06 56.45,15.94 23.31,15.94 21.05,13.68 15.2,13.68 13.74,15.14 v1(13.74,16.92)
  IN2 w0.508: v1(113.79,33.28) 115.98,35.46 125.95,35.46 126.39,35.02 126.39,34.53 127.81,33.11 133.4,33.11 135.11,31.4 146.57,31.4 147.84,32.67 154.78,32.67 156.3,34.19 157.59,34.19 158.33,34.94 158.33,38.07 157.66,38.74 157.66,39.81 v1(158.19,40.34)
  BOTTOM w0.203: 13.28,23.22 13.06,23.44 UA1.29
  BOTTOM w0.305: QC17.2 89.82,27.08 89.49,27.41 RC146.1 RC147.1 88.62,28.78 87.85,28.01 v1(87.85,27.08) QC17.5
  BOTTOM w0.381: v1(97.77,49.78) 97.92,49.62 v1(97.92,49.19) ; v1(80.36,85.95) 80.67,85.63 QC2.5 ; v1(81.63,81.06) 82.26,81.06 83.02,81.82 83.02,83.34 83.66,83.98 83.66,85.25 83.28,85.63 QC2.2 ; v1(98.9,48.73) 99.33,49.16 UC1.AM13 ; CA40.2 13.43,23.08 13.28,23.22 ; RC13.1 v1(96.42,76.17)
  BOTTOM w0.4: v1(97.77,49.78) 97.55,49.78 UC1.AL17 UC1.AJ15
  BOTTOM w0.508: v1(3.2,21.75) 2.84,21.38 RA6.2 ; v1(13.74,16.92) 13.62,17.05 13.6,17.05 RA53.2 ; v1(89.69,77.18) v1(89.69,80.04) ; v1(96.12,31.59) 96.12,28.24 94.83,26.95 94.83,24.8 ; v1(14.37,22.44) 14.38,22.45 14.38,22.51 14.05,22.84 CA40.2
  BOTTOM w0.762: v1(69.37,32.78) 69.37,37.56 66.64,40.29 66.64,71.66 71.34,76.36 85.12,76.36
  vias: v1(96.37,37.18)
+1.8VS_R: length 0.7
  TOP w0.102: 91.43,31.67 90.88,31.67 v2(90.74,31.81)
+1.35VGSP: length 18.3
  TOP w0.102: v1(47.4,155.54) 47.4,154.78 v3(47.03,154.41)
  TOP w0.254: PC907.1 PR905.1 45.81,143.1 46.17,142.73 v1(46.32,142.73)
  IN2 w0.203: v1(46.32,142.73) 47.35,142.73 49.18,144.56 49.18,153.76 v1(47.4,155.54)
  vias: v1(45.49,155.54) v1(46.13,155.54) v1(46.76,155.54)
+1.35VS_VRAM: length 30
  TOP w0.381: CV177.1 83.52,132.68 v1(83.63,132.57)
  TOP w0.508: v1(55.99,119.16) 55.99,118.25 56.56,117.68 RV80.1 RV79.1
  BOTTOM w0.127: UV7.L11 59.21,123.46 59.21,124.03 59.53,124.35 59.53,124.68 59.65,124.81
  BOTTOM w0.254: UV8.H12 58.78,146.33 v1(59.18,145.93) 59.58,145.53 UV8.G11 ; UV7.M14 60.38,120.18 v1(60.39,120.17) ; UV7.T14 63.97,120.3 63.99,120.3 v1(63.99,120.3) ; UV7.N5 v1(61.59,127.48) ; v1(60.78,121.87) 60.38,122.27 UV7.M12 ; UV8.D14 62.01,147.96 62.01,148.47 v1(62.02,148.48) ; v1(59.47,148.46) 59.58,148.35 UV8.G14 UV8.G13 ; v1(60.28,148.45) 60.35,148.38 60.35,147.96 UV8.F14 ; v1(64.01,148.36) 64.01,148.25 63.69,147.93 UV8.B14 ; UV7.T12 v1(63.18,122.69) ; UV7.N10 v1(61.59,123.48) UV7.P11 61.92,123.03 61.92,122.35 UV7.P12 ; UV7.P3 v1(61.58,129.89) ; UV8.B12 63.58,146.33 v1(63.98,145.93) ; UV8.F12 v1(60.74,145.98) ; v1(62.07,120.1) 62.07,120.19 61.98,120.28 UV7.P14 ; v1(59.58,120.17) 59.58,120.17 UV7.L14 59.2,121.07 v1(59.18,121.07) 59.58,121.47 UV7.L13 UV7.K12 ; UV7.L11 59.6,123.09 v1(59.96,123.45) 60,123.49 60.56,123.49 60.73,123.66 ; UV7.R5 v1(62.38,127.49)
  BOTTOM w0.3: UV1.H13 82.26,136.89 81.78,136.4 v1(81.78,136.28)
  BOTTOM w0.305: UV7.T3 v1(63.18,129.89) ; UV7.B12 v1(51.97,122.69) ; UV1.H19 82.86,132.57 v1(83.63,132.57)
  BOTTOM w0.381: v1(82.17,135.11) 82.17,134.7 UV1.H16
  BOTTOM w0.508: RV33.1 89.09,119.74 RV32.1 87.39,119.74 v1(86.13,121)
  vias: v1(49.68,148.68) v1(49.68,147.6) v1(49.68,146.46) v1(50,138.33) v1(50,137.57) v1(50,136.36) v1(50,132.36) v1(50,130.52) v1(50.07,127.35) v1(50.07,126.14) v1(50.19,151.29) v1(50.76,154.46) v1(50.76,153.83) v1(50.76,153.19) v1(51.4,154.46) v1(51.4,153.83) v1(51.4,153.19) v1(51.81,119.17) v1(52.01,148.35) v1(51.97,146.74) v1(52,136.46) v1(51.97,131.55) v1(52.03,154.46) v1(52.03,153.83) v1(52.03,153.19) v1(52.39,119.18) v1(52.67,154.46) v1(52.67,153.83) v1(52.67,153.19) v1(52.77,144.32) v1(52.78,138.73) v1(52.78,129.89) v1(52.78,128.29) v1(53.59,146.73) v1(53.59,141.59) v1(53.58,129.89) v1(53.55,124.31) v1(53.57,123.48) v1(53.59,122.68) v1(53.58,120.27) v1(53.95,136.93) v1(53.98,131.69) v1(54.12,148.5) v1(54.38,145.14) v1(54.36,138.73) v1(54.64,127.35) v1(54.74,124.46) v1(55.18,129.89) v1(55.28,141.73) v1(55.58,148.5) v1(55.56,131.61) v1(55.98,128.27) v1(55.98,121.87) v1(55.98,120.27) v1(56.03,145.89) v1(56.06,138.74) v1(56.06,137.05) v1(56.38,148.5) v1(56.78,146.73) v1(56.78,139.53) v1(56.78,131.47) v1(56.78,129.87) v1(56.78,122.67) v1(59.18,140.33) v1(59.16,139.53) v1(59.16,129.09) v1(59.58,137.01) v1(59.98,131.47) v1(59.98,129.87) v1(60.29,150.27) v1(60.78,140.33) v1(60.76,138.74) v1(61.59,145.12) v1(62.21,131.64) v1(62.3,136.99) v1(62.39,145.94) v1(62.39,138.72) v1(62.67,119.23) v1(63.18,140.33) v1(63.19,138.74) v1(63.18,124.28) v1(63.68,131.98) v1(63.76,119.29) v1(64.08,137) v1(64.34,119.29) v1(64.94,119.29) v1(70.2,154.08) v1(70.89,154.08) v1(71.53,154.08) v1(83.61,128.25) v1(84,137.52) v1(84.08,131.44) v1(84.23,129.16) v1(84.41,140.25) v1(84.41,139.51) v1(84.41,138.78) v1(84.33,128.26) v1(85.17,135.78) v3(52.43,151.71)
+2.5V:
  vias: v1(38.6,23.1) v1(39.3,23.1) v3(42,23.13)
+2.5VP: length 2.5
  TOP w0.102: v3(50.49,19.44) 50.76,19.16 52.86,19.16
+3V_LAN:
  vias: v1(30.33,133.77) v1(36.15,133.61) v1(36.59,133.23) v3(33.67,133.58)
+3VALW: length 466.5
  TOP w0.254: v1(160.89,40.06) 161.38,40.56 161.38,46.83 159.41,48.8 159.41,51.62 158.94,52.09 158.94,54.68 159.52,55.25 C832.1 160.91,55.25 R198.2
  TOP w0.305: R931.2 168.16,46.06 168.16,43.22 167.66,42.72 167.66,39.65 v1(168.15,39.16)
  TOP w0.381: v1(109.15,41.78) 109.15,45.73 107.48,47.39 RC83.1
  TOP w0.508: 105.69,31.08 105.76,31.02 106.86,32.12 111.58,32.12 112.11,31.6 PR204.2 ; v1(151.03,25.87) 151.03,20.97 153.38,18.62 153.38,12.54 154.71,11.21 ; v1(118.21,65.23) 119.29,65.23 121.44,63.09 128.68,63.09 129.06,63.47 R271.2 ; PR607.1 v1(61.43,19) ; 7.97,158.49 7.2,159.25 7.2,160.4 6.63,160.97 6.63,161.76 6.12,162.28 U282.2 ; v1(19.04,156.76) 18.42,157.38 9.96,157.38 9.79,157.55 R273.2 ; v1(64.23,19.4) 64.1,19.52 PR611.1
  TOP w1.016: 100.04,15.65 103.28,18.89 103.28,21.87 104.6,23.2 104.6,29.99 105.69,31.08 ; QV16.3 103.36,100.24 100.32,97.2 93.8,97.2 93.25,97.74 84.25,97.74 83.19,96.68 75.97,96.68 70,90.71 70,87.85 67.85,85.69 62.89,85.69 62.13,86.45 62.13,87.98 ; 72.29,1.74 54.83,1.74 53.18,3.4 53.18,4.41
  TOP w1.524: 49.18,101.25 51.91,101.25 56.16,96.99 57.94,96.99 62,92.93 62,90.01
  IN1 w0.127: v1(10.14,28.25) 10.14,28.02 10.57,27.59 12.08,27.59 12.85,26.81 12.85,25.24 13.24,24.86 18.57,24.86 24.35,19.08 55.78,19.08 v1(56.61,19.91)
  IN1 w0.508: 45.34,143.1 44.91,143.53 40.55,143.53 39.32,144.75 39.32,152.15 40.63,153.46 v1(40.63,157) ; 45.34,143.1 45.34,135.39 v1(43.08,133.13) ; 45.34,143.1 45.8,143.55 v1(46.71,143.55) ; v1(81.37,32.11) 81.37,31.15 82.78,29.74 83.33,29.74 84.4,28.67 88.59,28.67 91.28,25.98 94.72,25.98 95.85,24.85 95.85,18.95 99.21,15.59
  IN1 w1.016: 100.42,4.92 100.42,6.76 99.41,7.78 99.41,14.19
  IN2 w0.508: v1(40.63,157) 40.22,157.41 19.69,157.41 v1(19.04,156.76)
  BOTTOM w0.127: UA1.16 10.1,28.2 v1(10.14,28.25)
  BOTTOM w0.254: v1(168.15,39.16) 167.59,38.6 165.45,38.6 164.19,39.86 161.09,39.86 v1(160.89,40.06)
  BOTTOM w0.305: RC63.1 110.07,43.1 110.38,43.4 111.34,43.4 111.52,43.23 UC24.5
  BOTTOM w0.356: v1(81.37,32.11) 81.28,32.02 CC10.1 81.61,31.34 81.63,31.35 UC23.5
  BOTTOM w0.381: RC34.1 v1(113.06,51.85) ; 114.6,57.86 114.6,57.95 116.59,59.94 116.59,61.26 117.42,62.09 117.42,64.43 v1(118.21,65.23) ; RC46.1 114.59,49.7 114.26,49.37 v1(114.01,49.37) ; RC85.1 110.02,51.86 v1(109.88,51.72) ; UC24.5 112.63,43.23 v1(112.85,43.44)
  BOTTOM w0.4: UC1.AJ17 97.17,51.16 97.17,51.09 96.87,50.8 96.86,50.8 96.86,50.79 96.8,50.79 UC1.AL19 96.64,49.69 v1(96.77,49.69)
  BOTTOM w0.508: RC36.1 113.68,54.5 114.34,55.16 114.34,57.6 114.6,57.86 ; PU903.7 155.03,30.26 155.67,29.62 158.27,29.62 158.78,30.13 158.78,33 162,36.23 169.13,36.23 169.32,36.42 169.32,38.63 168.79,39.16 v1(168.15,39.16)
  BOTTOM w1.524: 57.11,21.81 57.11,35.65 59.27,37.81 59.27,75.15 62.07,77.94 62.07,87.72
  vias: v1(43.08,132.52) v1(43.08,131.92) v1(57.18,20.22) v1(57.18,19.59) v1(61.88,89.44) v1(61.88,88.8) v1(62.45,89.12) v1(63.78,15.02) v1(77.43,9.81) v1(78.07,9.81) v1(78.07,9.17) v1(78.7,9.81) v1(78.7,9.17) v1(78.7,8.54) v1(96.09,40.1) v1(96.09,39.46) v1(99.09,14.83) v1(99.72,14.83) v1(100.1,4.28) v1(100.74,4.28) v1(105.31,39.72) v1(105.31,39.08) v1(113.06,52.74) v1(156.07,10.65) v1(156.07,10.01) v1(156.71,10.65) v1(156.71,10.01) v1(157.34,10.65) v1(157.34,10.01) v1(157.98,10.65) v1(157.98,10.01) v1(158.61,10.65) v1(158.61,10.01) v1(159.25,10.65) v1(159.25,10.01) v1(159.88,10.65) v1(159.88,10.01) v3(46.59,124.22) v3(46.62,129.91) v3(48.47,113.84)
+3VALW_3VS: length 1.4
  TOP w0.102: 179.52,8.82 v3(180.9,8.82)
+3VALW_EC: length 74
  TOP w0.203: U11.22 177.25,59.72 176.94,59.4 v1(176.94,58.96) ; U11.96 162.67,51.31 161.67,51.31 160.94,50.58 C180.1 ; C181.1 180.01,54.3 179.79,54.52 U11.9
  TOP w0.381: C180.1 161.23,50.49 161.42,50.3 v1(161.52,50.3) ; v1(180.24,54.89) C181.1
  TOP w0.508: v1(177.7,65.12) 177.89,65.31 C182.1 ; v1(156.43,65.24) 156.18,64.99 L20.1
  IN2 w0.508: v1(176.94,58.96) 177.7,59.72 v1(177.7,65.12) 164.81,65.12 163.85,64.15 162.4,64.15 160.53,66.02 156.68,66.02 156.43,65.77 v1(156.43,65.24)
  BOTTOM w0.457: v1(175.92,48.1) 176.05,47.97 178.46,47.97 178.97,48.48 178.97,49.18
  BOTTOM w0.508: 178.97,49.18 178.97,51.25 178.39,51.83 ; 178.39,51.83 175.28,51.83 174.06,50.61 166.45,50.61 166.14,50.92 161.88,50.92 161.52,50.56 v1(161.52,50.3) ; 178.39,51.83 178.39,54.18 178.91,54.7 ; 178.91,54.7 178.91,56.99 v2(177.99,57.91) v1(176.94,58.96) ; 178.91,54.7 180.05,54.7 v1(180.24,54.89)
+3VALWP: length 21.8
  TOP w0.254: PR403.2 162,22.58 v1(162.37,22.21)
  IN1 w0.508: v1(160.24,13.62) 160.24,15.08 161.38,16.22 161.38,21.37 161.76,21.75 161.76,22.95 161.42,23.3 v1(161.36,23.3)
  IN2 w0.254: v1(160.75,12.35) 161.7,13.3 161.7,14.19 162.37,14.86 v1(162.37,22.21)
  vias: v1(154.83,13.34) v1(155.46,13.34) v1(161.32,11.02) v3(158.16,12.88)
+3VDD_CODEC: length 11.7
  IN1 w0.508: v1(4.54,19.84) 4.54,20.99 3.84,21.68 3.84,22.95 4.22,23.33 4.22,24.92 4.35,25.05 4.35,29.45 v1(4.98,30.08)
  BOTTOM w0.508: RA51.2 v1(4.98,30.08)
  vias: v2(5.83,21.23)
+3VGS: length 128.1
  TOP w0.127: v1(57.43,113.7) v3(58.51,113.7)
  TOP w0.254: PR1002.1 57.7,112.88 57.43,113.15 v1(57.43,113.7)
  TOP w0.381: RV154.1 85.18,147.11 v1(85.79,147.11) ; RV5.1 90.5,147.27 QV1.5 ; QV1.2 87.44,147.27 86.87,147.83 v1(86.87,148.29)
  TOP w0.508: RV5.1 91,147.33 91.29,147.04 v1(91.29,146.72) ; RV91.2 88.44,145.31 RV6.1 88.26,145.53 87.77,146.02 v1(87.76,146.02) ; v1(98.07,146.27) 105.25,146.27 106.39,145.13 106.39,130.98 v1(105.81,130.4)
  IN1 w0.508: v1(57.43,113.7) 57.77,114.04 65.84,114.04 67.21,115.41 84.74,115.41 85.82,114.33 85.82,110.99 86.24,110.57 90.39,110.57 91.16,111.35 97.5,111.35 ; v1(98.07,146.27) 97.63,146.72 v1(91.29,146.72) 88.46,146.72 v1(87.76,146.02) 86.65,147.13 85.82,147.13 v1(85.79,147.11)
  IN1 w1.016: 99.18,108.92 99.18,109.07 97.5,110.75 97.5,114.65 101.44,118.58 101.44,121.76 103.6,123.92 103.6,126.14 105.76,128.3 105.76,128.87
  BOTTOM w0.305: RV3151.2 83.58,150.84 84.36,150.84
  BOTTOM w0.381: UV2.5 105.58,127.54 RV162.1 ; v1(86.87,148.29) 86.32,148.84 86.32,149.76 86.45,149.89 86.45,150.51 86.18,150.78 85.18,150.78
  BOTTOM w0.508: v1(86.87,148.29) 86.87,148.01 85.97,147.11 v1(85.79,147.11) ; v1(105.81,129.76) 105.81,127.77 RV162.1 ; v1(105.81,130.4) 105.81,131.27 105.3,131.78 LV4.1
  vias: v1(98.91,108.06) v1(99.49,108.07)
+3VL: length 305.6
  TOP w0.203: C179.1 169.64,48.16 169.9,48.43 U11.111 169.9,51.02
  TOP w0.254: RP3.6 159.34,58.76 v1(158.48,58.76) 158.98,59.26 RP3.5
  TOP w0.381: v1(168.95,47.66) 169.22,47.66 169.4,47.48 169.51,47.48 C179.1 ; v1(169.9,56.35) 169.9,51.02
  TOP w0.508: v1(152.06,11.65) 150.17,13.55 150.17,19.97 148.45,21.68 145.63,21.68 144.52,22.8 138.29,22.8 133.51,27.59 v3(128.55,27.59) 124.04,27.59 122.07,29.56 117.25,29.56 115.31,31.5 113.31,31.5 112.93,31.12 PR203.2 ; v1(170.07,41.15) 170.07,40.92 170.47,40.52 171.6,40.52 171.99,40.9 171.99,42.55 174.87,45.43 177.33,45.43 177.7,45.8 R189.1
  IN1 w0.508: v1(107.53,4.01) 134.55,4.01 140.22,9.67 150.76,9.67 152.06,10.97 v1(152.06,11.65) 152.06,12.05 152.43,12.41 153.57,12.41 154.02,11.97 154.02,10.44 155.09,9.36 162.08,9.36 163.54,10.83 163.54,12.16 163.1,12.6 163.1,14.25 162.52,14.83 162.52,20.16 v1(163.1,20.73) ; v1(159.92,28.92) 159.38,28.38 159.38,26.01 160.02,25.37 161.7,25.37 163.07,24 v1(163.07,21.37)
  IN2 w0.508: v1(168.95,47.66) 168.94,47.67 168.61,47.67 168.1,47.16 168.1,45.04 170.07,43.07 v1(170.07,41.15) ; v1(34.89,2.63) 34.89,3.52 36.79,5.43 52.29,5.43 54.96,2.76 95.6,2.76 96.55,3.71 97.69,3.71 99.34,2.06 105.59,2.06 v1(107.53,4.01)
  BOTTOM w0.305: v1(169.9,56.35) 162.29,56.35 159.89,58.76 v1(158.48,58.76)
  BOTTOM w0.508: v1(34.89,2.63) 34.89,10.32 31.65,13.56 28.98,13.56 27.22,15.32 24.86,15.32 24.23,14.7 22.32,14.7 21.62,14 20.16,14 19.78,14.38 PR108.2 ; v1(170.07,41.15) 170.07,36.21 169.45,35.59 162.38,35.59 159.51,32.72 159.51,29.33 v1(159.92,28.92) 159.51,28.52 PR406.1
+3VLP: length 0.9
  TOP w0.102: v1(160.43,22.45) v3(160.43,23.36)
  vias: v1(161.06,22.45)
+3VS: length 517.6
  TOP w0.127: C852.1 180.77,8.13 181.47,8.83 182.59,8.83 183.49,9.73 v3(184.53,9.73)
  TOP w0.254: RP3.8 158.93,57.76 v1(158.54,58.15) 158.65,58.26 RP3.7 ; RPC13.3 90.07,35.84
  TOP w0.381: RC41.1 98.36,27.93 98.36,27.02 96.59,25.24 94.26,25.24 92.67,23.65 v1(89.94,23.65) ; U203.5 28.65,147.49 v1(28.92,147.22) ; v1(95.02,79.98) 95.15,80.1 RC21.2
  TOP w0.508: RL8.1 23.74,138.85 23.23,139.36 23.23,140.1 23.57,140.44 24.78,140.44 25.19,140.85 R212.1 25.92,141.47 26.98,142.52 26.98,143.01 27.29,143.33 27.29,144.18 27.69,144.57 Q201.3 28.76,144.57 29.17,144.99 v1(29.17,146.33) ; v1(160.39,38.52) 160.11,38.52 159.79,38.21 159.79,35.65 159.1,34.96 v1(156.68,34.96) ; v1(23.73,109.66) 23.73,109.34 23.84,109.23 RH29.1 RH30.1 23,108.82 22.78,108.82 v1(22.25,108.29) ; v1(23.73,109.66) 23.66,109.66 21.36,111.96 21.36,113.44 26.32,118.39 29.09,118.39 31.44,120.74 39.02,120.74 ; v1(23.73,109.66) 24.27,109.66 25.87,108.06 25.87,97.82 22.19,94.14 18.05,94.14 17.54,94.65 QH17.2 ; R214.2 179.99,61.04 v1(179.99,60.29) 179.99,59.34 180.37,58.96 181,58.96 182.31,57.65 182.31,51.97 181.89,51.55 181.89,48.48 180.37,46.96 180.37,41.43 173.37,34.43 171.76,34.43 v1(171.24,34.96) ; v1(89.94,23.65) 80.67,23.65 ; v1(27.59,25.13) 30.43,25.13 30.5,25.06 RD203.1 RD202.1 32.91,25.06 33.19,24.78 35.06,24.78 v1(35.81,24.04) ; v1(3.2,18.89) 3.2,16.35 15.46,4.09 29.62,4.09 33.3,7.78 33.3,11.08 32.73,11.65 ; RC156.1 108.27,44.39 107.91,44.75 v1(107.46,44.75)
  TOP w2.54: 41.62,120.68 42.32,120.68 43.91,119.09 43.91,99.41 45.43,97.88 50.89,97.88 57.3,91.47 57.3,87.91 57.56,87.66
  IN1 w0.305: v1(83.28,38.51) 83.28,36.99 v1(84.17,36.1)
  IN1 w0.381: v1(152.03,46.96) 152.03,46.72 152.68,46.07 154.65,46.07 155.41,45.31 155.41,40.8 155.14,40.53 155.14,36.49 v1(156.68,34.96)
  IN1 w0.457: 105.62,49.56 105.62,52.21 107.15,53.75 108.23,53.75 108.99,54.51 110.14,54.51 110.71,55.08 v1(112.3,55.08)
  IN1 w0.508: v1(59.08,85.63) 66.13,78.58 78.64,78.58 v1(79.59,79.53) 80.1,79.02 94.07,79.02 v1(95.02,79.98) ; v1(93.88,38.41) 93.88,41.88 95.85,43.85 96.04,43.85 96.69,44.49 97.09,44.49 97.45,44.85 102.09,44.85 102.5,44.43 107.14,44.43 v1(107.46,44.75) 107.46,47.72 105.62,49.56
  IN1 w0.762: v1(29.94,12.03) 28.6,12.03 v1(27.32,13.31)
  BOTTOM w0.254: v1(35.81,24.04) 36.06,23.79 JDIMM1.255 ; RPC12.1 87.65,36.07 87.81,35.91 v1(88.17,35.91) ; RPC12.3 86.65,35.66 v1(87.19,35.12)
  BOTTOM w0.305: RC162.2 83.4,36.86 v1(84.17,36.1) ; v1(83.28,38.51) 81.88,38.51 80.47,37.1 RC163.2 ; v1(95.02,79.98) 94.31,80.69 RC18.2
  BOTTOM w0.381: UC22.5 77.42,88.06 78.83,86.64 79.59,84.93 v1(79.59,79.53) ; PR813.1 v1(152.03,46.96) ; v1(91.71,36.49) RC77.1 ; RC75.1 v1(93.88,37.8) ; RC158.1 v1(112.3,55.08) ; QH15.2 QH15.5 22.07,108.11 v1(22.25,108.29) ; RC144.1 86.64,26.56 86.64,29.24 87.02,29.62 87.02,32.54 v1(86.58,32.99) ; RC79.1 v1(93.88,38.41) ; v1(160.39,38.52) 160.24,38.68 PR835.2 ; RC145.1 90.4,24.11 v1(89.94,23.65)
  BOTTOM w0.508: RD204.1 25.34,26.09 26.3,25.13 v1(27.59,25.13) ; QH5.1 24.34,110.23 23.76,109.66 v1(23.73,109.66) ; v1(158.54,58.15) 159.74,58.15 162.22,55.67 172.7,55.67 177.32,60.29 v1(179.99,60.29) ; R280.1 173.6,22.47 R279.1 172.7,22.62 v1(172.7,23.3) ; RA59.2 2.25,19.4 2.76,18.89 v1(3.2,18.89)
  BOTTOM w2.032: 40.86,121.32 45.75,126.2 45.75,136.82 39.83,142.74
  BOTTOM w2.54: 58.57,84.29 58.57,79.72 54.76,75.91 54.76,23.59
  vias: v1(33.05,147.29) v1(33.68,147.29) v1(34.32,147.29) v1(36.16,21.68) v1(36.79,21.68) v1(37.39,21.68) v1(37.98,21.68) v1(39.4,120.36) v1(39.4,119.73) v1(39.65,121) v1(40.03,120.36) v1(40.03,119.73) v1(54.45,21.24) v1(55.08,21.87) v1(55.08,21.24) v1(55.72,21.87) v1(55.72,21.24) v1(57.88,85.95) v1(58.45,86.26) v1(58.45,85.63) v1(59.08,86.26) v1(80.23,24.29) v1(80.86,24.29) v1(162.46,41.29) v1(162.46,40.71) v1(177.26,6.51) v1(177.57,7.14) v1(177.89,6.51) v1(178.21,7.14) v1(178.53,6.51) v1(178.84,7.14) v1(179.16,6.51) v1(179.48,7.14) v1(179.8,6.51) v3(37.1,20.08) v3(91.82,34.43)
+3VS_APU: length 2.3
  BOTTOM w0.4: v1(95.83,49.7) 95.63,49.7 UC1.AL21 95.82,50.81 95.87,50.81 96.17,51.1 96.17,51.16 UC1.AJ19
  vias: v2(94.34,44.66)
+3VS_CMOS: length 3.6
  TOP w0.127: R212.2 v2(22.08,141.47)
  BOTTOM w0.508: JEDP1.1 22.87,142.73 23.27,142.33 v1(23.78,142.33)
+3VS_WLAN: length 17.5
  BOTTOM w1.016: 164.67,42.64 166.08,41.23 168.46,41.23 169.27,42.04 172.81,42.04 173.19,41.66 179.47,41.66 180.62,42.82
  vias: v1(163.78,43.54) v1(163.79,42.95) v3(164.14,45.06) v3(164.37,42.94) v3(165.65,44.11)
+5V_DISPLAY: length 3.5
  TOP w0.102: v2(18.8,109.53) 18.46,109.53 18.18,109.25 v1(18.06,109.25)
  TOP w0.457: v1(18.06,109.25) 17.11,109.25 16.72,108.86 RH27.1 RH28.1
+5V_HDD: length 8
  TOP w0.127: v3(181.88,22.66) 181.26,22.04 179.11,22.04 v1(178.89,22.26) ; v3(179.94,22.59) 179.22,22.59 v1(178.89,22.26) ; v1(178.89,22.26) 178.78,22.37 178.78,23.35 179.62,24.19 v3(180.79,24.19)
+5V_ODD:
  vias: v1(185.49,58.47) v1(185.49,57.84) v2(184.14,59.99)
+5VALW: length 388
  TOP w0.127: v3(24.13,63.06) 24.41,63.34 v1(24.41,63.91)
  TOP w0.254: U18.4 89.68,29.25 89.78,29.15 C861.1
  TOP w0.381: v1(149.44,65.96) 150.68,64.72 154.09,64.72 154.46,64.36 155.58,64.36 157.95,61.99 157.95,61.53 158.26,61.22 R194.2
  TOP w0.508: R377.2 34.57,6.43 v3(34.57,8.16) v1(34.57,14.19) ; PU2001.4 72.74,10.19 73.13,10.58 PC2003.1 79.26,11.46 80.36,10.36 v1(80.36,7.08) ; v1(98,106.33) 96.8,106.33 96.42,105.95 RV44.1 ; v1(152.74,11.65) 152.74,18.33 148.26,22.8 148.26,22.81 148.19,22.89 147.92,22.89 ; v1(34.37,118.52) R934.1 ; R194.2 158.6,60.84 159.01,60.43 v1(161.36,60.43) ; 147.92,22.89 148,22.97 RC151.1 148,25.19 148.17,25.37 UC26.8 ; 147.92,22.89 146.52,22.89 146.22,23.2 v1(146.22,23.65) RC150.1 ; v1(162.35,33.28) 162.35,37.53 159.81,40.07 PR837.2 ; C861.1 89.78,27.55 88.67,26.44 v1(85.98,26.44) ; PR505.1 41.05,116.3 v1(40.22,117.12) ; R947.1 62.75,31.89 v1(63.02,32.16) ; v1(131.22,61.75) 130.95,62.02 R278.2
  IN1 w0.508: v1(98,106.33) 98,105.58 93.54,101.12 79.47,101.12 78.64,100.3 73.24,100.3 71.91,98.96 61.5,98.96 59.68,100.78 59.68,105.47 60.99,106.77 v1(61.75,106.77) 62.13,106.77 62.58,107.22 62.58,108.49 59.19,111.87 v1(49.83,111.87) ; v1(85.98,26.44) 83.75,26.44 82.49,27.7 81.77,27.7 79.28,30.19 78.26,30.19 77.43,31.02 63.65,31.02 63.08,31.59 63.08,32.1 v1(63.02,32.16) 62.51,32.16 59.97,29.62 59.97,27.02 58.32,25.37 58.32,21.81 59.34,20.79 59.34,16.67 56.29,13.62 v1(55.53,13.62) ; v1(161.36,60.43) 161.6,60.43 162.08,59.95 162.08,57.62 165.19,54.51 165.19,49.94 165.97,49.17 165.97,40.57 166.59,39.95 166.59,35.6 164.26,33.28 v1(162.35,33.28)
  IN1 w0.762: 24.41,65.31 24.41,75.32 24.88,75.79 24.88,97.53 25.43,98.07 25.43,104.26 26.82,105.66 26.82,111.49 27.57,112.23 27.57,115.04 29.77,117.24 33.09,117.24 v1(34.37,118.52) 38,118.52 39.4,117.12 v1(40.22,117.12)
  IN2 w0.508: v1(162.35,33.28) 161.74,33.28 159.3,30.84 159.3,28.66 159.73,28.22 159.73,26.83 159.54,26.64 159.54,25.43 159.73,25.24 159.73,22.28 161.48,20.52 161.48,15.94 159.67,14.13 154.14,14.13 153.35,13.33 v1(153.35,11.65)
  BOTTOM w0.508: PR1029.2 50.68,111.03 v1(49.83,111.87) 46.8,114.9 42.51,114.9 PR505.1 41.05,116.3 v1(40.22,117.12) ; RC153.2 145.68,24.19 v1(146.22,23.65) 146.09,23.53 144.24,23.53 143.79,23.97 143.79,27.53 144.55,28.29 144.55,28.86 145.04,29.34 145.04,30.06 143.47,31.63 143.47,33.69 147.16,37.37 147.16,43.49 148.03,44.37 PR801.2 ; PR1033.2 v1(61.75,106.77) ; v1(131.22,61.75) 131.22,62.26 131.6,62.64 135.35,62.64 139.4,66.69 148.71,66.69 v1(149.44,65.96)
  vias: v1(18.44,63.72) v1(18.82,64.86) v1(18.82,64.23) v1(18.82,63.21) v1(19.2,63.72) v1(24.41,64.55) v1(55.78,8.98) v1(163.92,9.94) v1(164.09,9.34) v1(164.24,10.51) v1(164.56,9.94) v1(164.72,9.34) v1(164.87,10.51) v1(165.19,9.94) v1(165.36,9.34) v1(165.51,10.51) v1(165.83,9.94) v1(165.99,9.34) v1(166.14,10.51) v1(166.46,9.94) v1(166.63,9.34) v1(166.78,10.51) v1(167.1,9.94) v1(167.26,9.34) v1(167.41,10.51) v1(167.73,9.94) v1(167.9,9.34) v3(169.6,10.57)
+5VALW_5VS: length 4.6
  TOP w0.102: v3(184.43,12.04) 184.05,11.66 180.41,11.66 180.14,11.93 180.05,11.93
+5VALWP: length 31.3
  IN1 w0.508: v1(168.43,13.56) 168.43,13.87 168.94,14.38 170.97,14.38 171.73,15.14 171.73,21.9 171.96,22.13 171.96,22.7 171.07,23.59 v1(171.07,24.16)
  IN2 w0.254: v1(169.13,13.49) 171.34,15.7 171.34,20.99 172.29,21.94 172.29,22.79 171.66,23.43 171.66,27.93 v1(171.06,28.53)
  BOTTOM w0.254: PR407.2 v1(171.06,28.53)
  vias: v1(163.86,14.44) v1(163.86,13.81) v1(163.86,13.17) v3(165.95,13.73)
+5VDDA_CODEC:
  vias: v2(15.36,30.5)
+5VLP: length 1.7
  TOP w0.102: v3(169.64,24.86) 169.85,24.64 169.85,23.3
  vias: v1(170.55,23.11) v1(170.55,22.45)
+5VS: length 460.5
  TOP w0.508: DA3.5 v1(44.06,11.33)
  TOP w1.016: 24.86,113.63 27.97,110.52 27.97,98.2 26.54,96.77 26.54,69.79 21.81,65.05 21.81,58.83 23.52,57.12 23.52,30.89 22.44,29.81
  TOP w1.524: 29.3,98.39 41.62,98.39 44.41,95.6 49.88,95.6 54.96,90.52 54.96,86.9 57.69,84.17 68.67,84.17 79.66,95.15 83.86,95.15 84.93,96.22 92.8,96.22 93.22,95.8 101.35,95.8 101.77,96.22 104.16,96.22
  IN2 w1.016: 181.17,66.39 170.16,66.39 166.94,69.6 145.61,69.6 144.68,68.67 127.6,68.67 122.7,73.58 116.73,73.58 111.72,78.58 111.72,87.98 107.63,94.66 106.84,95.45
  BOTTOM w0.508: 14.91,14.48 15.65,13.75 17.9,13.75 18.34,14.19 18.34,17.01 19.27,17.94 20.32,17.94 21.15,18.77 22.53,18.77 22.89,18.41 26.36,18.41 28.92,15.84 31.59,15.84 37.05,10.38 39.52,10.38 39.72,10.19 43.65,10.19 44.06,10.6 v1(44.06,11.33)
  BOTTOM w1.016: 19.01,27.78 19.01,21.3 14.91,17.2
  BOTTOM w1.27: 182.72,64.67 182.72,59.76 181.87,58.91 181.87,51.34 184.13,49.08 184.13,35.9 182.87,34.64 179.54,34.64 174.84,29.94 174.84,28.22
  BOTTOM w1.524: 180.94,66.58 176.6,66.58 176.15,66.13 169.57,66.13 166.11,69.59 151.88,69.59 150.93,68.64 138.92,68.64 138.18,69.37 126.47,69.37 122.27,73.58 114.05,73.58 109.78,77.84 109.78,85.21 107.66,87.33 107.66,94.34 106.83,95.17
  vias: v1(21.49,29.3) v1(21.49,28.67) v1(23.4,113.76) v1(24.03,113.76) v1(105.31,96.18) v1(105.78,95.65) v1(106.02,96.19) v1(174.84,27.08) v1(175.16,26.51) v1(175.16,25.87) v1(175.41,22.52) v1(175.41,21.93) v1(175.41,21.34) v1(175.41,20.74) v1(182.08,66.39) v1(182.08,65.75) v1(182.4,66.96) v1(182.72,66.39) v1(182.72,65.75) v1(182.82,19.52) v1(182.82,18.89) v1(182.82,18.19) v1(182.82,17.56) v1(183.03,66.96) v1(183.35,66.39) v1(183.35,65.75) v1(183.45,19.52) v1(183.45,18.89) v1(183.45,18.19) v1(183.45,17.56) v3(173.87,29.75) v3(174.72,31.63) v3(175.57,29.75)
+5VS_FAN: length 8.1
  TOP w0.102: v3(105.73,98.61) 102.95,98.61 v1(101.92,97.58)
  BOTTOM w1.016: 100.23,93.76 100.23,96.3 101.13,97.2
+5VS_PVDD: length 2.6
  BOTTOM w0.203: UA1.34 10.5,21.69 10.82,21.37 ; 7.52,21.49 7.65,21.62 8.23,21.62 8.5,21.88 UA1.39
  vias: v2(10.96,20.77)
+8.4V_VMB:
  vias: v2(110.1,28.47)
+12.6V_BATT+: length 34.9
  TOP w0.102: v1(115.85,27.78) 115.37,28.26 v3(115.37,28.61) ; v3(118.85,27.87) 118.44,27.46 v1(117.12,27.46) ; v1(116.49,27.78) 116.49,27.86 v3(117.1,28.47)
  IN2 w0.508: v1(145.8,22.47) 132.95,22.47 131.08,24.34 125.35,24.34 124.72,23.72 120.72,23.72 120.71,23.71
  BOTTOM w0.254: PR765.4 119.53,14.95 120.23,14.25 121.49,14.25 PQ710.3
  BOTTOM w0.508: PR745.2 v1(145.8,22.47)
  vias: v1(115.85,27.14) v1(116.49,27.14) v1(119.98,21.62) v1(119.98,20.99) v1(119.98,20.35) v1(119.98,19.72) v1(119.98,19.08)
+12.6VB_DDR: length 17.1
  TOP w0.254: PR507.1 38.13,115.21 38.13,114.58 34.44,110.9 v3(34.44,105) 34.44,104.23 35.52,103.15 37.11,103.15 PQ501.5
  vias: v1(39.97,103.47) v1(39.97,102.84) v1(39.97,102.2)
+17.4V_BATT_CHG: length 0.9
  TOP w0.102: v1(125.9,19.16) v3(125.9,20.03)
+19V_APDIN: length 5.4
  TOP w0.102: PC101.1 20.7,143.96 v3(20.88,143.78) ; v3(17.92,143.74) 18.39,144.21 18.39,145.03 ; v3(19.41,142.8) 19.41,145.09
+19V_P1: length 8.2
  TOP w0.127: PR737.2 34.7,158.29 v3(35.09,158.29)
  TOP w0.508: 28.2,155.22 30.7,155.22 31.99,156.51 31.99,156.56 PQ707.3 33.5,157.09 PR737.2
+19V_P2: length 3.3
  TOP w0.102: v3(26.44,151.35) 28.03,151.35 28.88,152.2 29.35,152.2
+19V_VIN: length 272.4
  IN1 w0.508: v1(152.35,22.19) 150.52,20.36 150.52,19.86 149.81,19.14 148.05,19.14 146.95,20.24 144.7,20.24 142.27,17.81 142.27,15.82 v1(138.93,12.48) 138.93,11.55 137.73,10.35 119.62,10.35 118.58,11.39 110.01,11.39 v1(102.14,3.52) ; v1(52.61,90.58) 52.16,90.58 44.77,97.97 44.77,120.11 43.65,121.22 43.65,129.27 42.13,130.79 42.13,133.82 42.83,134.52 42.83,139.85 38.62,144.07 27.07,144.07 24.73,146.41 24.73,151.07 24.17,151.63 v1(23.75,151.63)
  BOTTOM w0.457: PR729.1 v1(152.35,22.19)
  BOTTOM w0.508: v1(102.14,3.52) 67.72,3.52 52.24,19 52.24,86.59 52.61,86.96 v1(52.61,90.58) ; PD703.3 138.67,12.22 v1(138.93,12.48)
  vias: v1(21.56,152.17) v1(21.84,151.63) v1(22.2,152.17) v1(22.48,151.63) v1(22.83,152.17) v1(23.11,151.63) v1(23.47,152.17) v3(17.8,151.17) v3(18.96,154.59) v3(18.96,152.53)
+19VB_1V: length 1.2
  TOP w0.102: v3(73.37,20.27) 72.96,19.87 72.96,19.22
+19VB_3V: length 2.7
  BOTTOM w0.102: PC405.1 153.24,25.47 152.95,25.18 152.66,25.18 152.38,25.46 151.88,25.46 v2(151.56,25.14)
+19VB_5V: length 4.9
  TOP w0.254: PR451.1 164.18,30.45 v2(163.67,29.94) 163.67,27.59 164.39,26.87 PC415.1
  vias: v1(164.43,26.07) v1(165.13,26.07)
+19VB_APU: length 48.3
  TOP w0.508: PR806.1 145.82,38.7 144.62,37.5 139.41,37.5
  TOP w3.81: 150.45,53.15 149.61,52.32 138.93,52.32 137,50.39 137,41.69 139.41,39.27 139.41,29.49
  vias: v1(139.16,26.83) v1(139.16,26.19) v1(139.79,26.83) v1(139.79,26.19) v1(139.79,25.43) v1(140.43,26.83) v1(140.43,26.19) v1(140.43,25.43) v1(152.55,54.07) v1(152.55,53.46) v1(152.55,52.86) v1(152.55,52.23) v1(153.19,54.07) v1(153.19,53.46) v1(153.19,52.86) v1(153.19,52.23) v2(138.05,26.13)
+19VB_CHG:
  vias: v2(140.52,22.05)
+VCC_IO2: length 5.1
  TOP w0.102: R932.1 174.45,45.83 v2(173.99,45.38)
  TOP w0.203: U11.124 175.1,47.84 175.36,47.58 C823.1 175.36,47.41 174.91,46.96 174.78,46.96 174.45,46.63 R932.1
+VDD_CT: length 3.6
  TOP w0.102: v2(102.87,131.12) 102.63,130.88 LV3.2
  TOP w0.508: v1(100.27,130.55) 100.68,130.14 CV61.1 101.57,130.16 LV3.2
  vias: v1(93.06,131.01) v1(94.36,130.27)
+VDDCR_FCH_ALW: length 50.8
  TOP w1.016: 106.45,40.71 106.45,37.05 108.61,34.89 121.5,34.89 123.28,33.11 123.28,32.03
  IN1 w1.016: 125.88,31.91 129.12,31.91 130.33,30.7 147.47,30.7 149.32,32.54
  BOTTOM w0.305: UC1.AR5 UC1.AR7 102.77,46.86 UC1.AU7 102.98,46.65 v1(103.63,46.65) ; v1(104.21,46.93) 104.37,47.09 UC1.AR4
  vias: v1(124.36,31.91) v1(125,31.91) v1(149.13,34.13) v1(149.76,34.13) v2(107,42.03)
+VDDR3: length 10.9
  TOP w0.102: v2(101.34,133.03) 100.96,133.41 v1(100.83,133.41)
  IN1 w0.508: v1(94.67,132.78) 97.85,132.78 98.48,133.41 v1(100.83,133.41)
  BOTTOM w0.508: v1(100.83,133.41) 102.61,133.41 CV123.1 103.36,132.69 LV4.2
  vias: v1(93.06,133.9) v1(93.06,133.14)
GND: length 1655.4
  TOP w0.102: v1(105.92,116.49) v3(105.92,115.89)
  TOP w0.127: v1(125.31,42.83) v3(125.31,43.92) ; v1(78.96,31.53) 78.35,30.92 v3(78.35,28.25) ; v3(131.38,64.9) C271.2 ; v3(48.92,154.65) 48.92,155.5 v1(47.4,157.03) ; v1(152.24,56.04) v3(151.16,56.04) ; v1(128.92,34.32) v3(128.04,34.32) ; v3(112.23,33.47) 112.23,32.38 v1(112.3,32.31)
  TOP w0.203: v1(175.67,64.1) 175.9,64.34 U11.35 ; U381.11 v1(178.59,11.46) ; U1895V.11 v1(89.44,111.73) ; U11.11 v1(176.88,55.32) ; v1(176.56,60.48) 178.3,60.48 U11.24 ; v1(170.77,47.97) 170.7,48.04 U11.113 ; v1(161.38,52.48) 161.74,52.12 162.67,52.12 U11.94
  TOP w0.254: RPC3.6 87.72,93.37 v1(87.47,93.62) 87.22,93.37 RPC3.7 ; RPC5.2 v1(86.84,79.72) ; RPC13.1 89.07,36.68 v1(88.67,36.29) 88.8,36.16 89.25,36.16 89.57,36.48 RPC13.2 ; v1(89.69,58.61) 89.69,59.41 89.45,59.65 CC38.2 ; CV93.2 80.68,140.52 v1(80.33,140.52) ; RPC5.3 87.34,79.99 v1(87.6,79.73) 87.6,79.74 87.84,79.98 RPC5.4 ; PC1015.2 85.58,131.25 CV42.2 ; v1(170.97,41.15) 170.97,41.55 170.83,41.69 RP4.4
  TOP w0.305: CD226.2 39.49,55.8 v1(39.75,55.55) ; CV51.2 84.58,135.36 v1(84.25,135.03) ; v1(83.27,122.91) 83.58,122.91 84.24,122.26 RV39.1
  TOP w0.356: v1(80.64,142.81) 80.38,143.07 CV92.2 ; 87.19,109.71 CV32.1 ; 87.19,109.71 86.57,109.71 v1(86.54,109.73) ; 87.19,109.71 CV291.2 ; CV83.2 99.57,98.65 99.9,98.32 v1(99.9,98.09) ; QV21.4 83.8,112.35 v1(84.17,111.98) ; CV90.1 88.42,142.88 v1(88.53,142.99) ; CV177.2 81.33,132.68 v1(81.32,132.67) ; C2155.1 164.35,38.42 v1(164.49,38.56) ; CV301.2 91.54,110.01 v1(91.28,110.28) ; v1(173.7,15.4) 173.7,14.71 C843.2 ; v1(57.94,6.38) 57.94,6.04 Q401.4 ; Q401.1 60.62,4.46 60.75,4.34 v1(60.75,3.53) ; CV82.2 CV124.2 86.46,140.94 v1(86.71,141.18) ; v1(82.71,141.08) 82.68,141.11 CV86.2 ; CV31.1 v1(90.85,113.77) ; CV39.2 CV46.2 v1(98.99,122.2) ; v1(89.04,105.63) 89.05,105.64 CV1380.2 ; CV26.2 98.83,135.76 v1(99.19,135.41) ; UC21.3 94.09,82.22 93.79,82.52 92.42,82.52 v1(92.17,82.26) ; C271.2 134.3,64.9 v1(134.46,64.74) ; C2154.2 180.75,50.06 v1(180.69,49.99) ; CV37.2 103.69,105.12 106.43,107.87 v1(106.43,108.15) ; 90.71,28.48 C861.2 ; v1(36.48,139.62) CL10.2
  TOP w0.381: CV188.2 64.94,148.3 v1(64.92,148.28) ; v1(61.22,120.1) 61.22,120.11 CV164.2 ; RC134.1 86.27,35.1 v1(86.71,34.67) ; CV389.2 54.79,131.66 v1(54.77,131.64) ; v1(92.44,64.88) 92.42,64.9 RC26.2 ; RC22.2 93.93,67.15 v1(94.64,67.15) ; PC815.2 155.23,35.29 v1(155.03,35.08) ; RL10.2 v1(31.03,138.02) ; CC42.2 85.47,52.41 v1(85.47,52.41) ; C193.2 160.87,52.23 161.13,52.48 v1(161.38,52.48) ; CV171.2 62.99,148.45 v1(62.99,148.44) ; v1(185.19,13.75) 184.88,13.43 C846.2 ; C181.2 180.56,53.71 v1(180.8,53.47) ; CV176.2 84.86,128.21 CV175.2 84.86,127.03 v1(84.55,126.71) ; PR820.2 158.64,38.21 v1(159.03,37.81) ; CV21.2 CV20.2 96.17,135.78 96.04,135.91 v1(96.04,136.29) ; v1(57.18,148.5) 57.09,148.59 CV170.2 ; v1(76.35,54.61) 76.93,55.18 CC37.2 ; C272.2 155.91,55.43 v1(155.72,55.24) ; v1(53.03,148.46) 53.09,148.52 CV169.2 ; CD227.2 39.88,52.61 v1(39.87,52.62) ; PC817.2 158.07,47.83 v1(158.53,48.29) ; CV52.2 83.42,135.17 v1(82.75,135.17) ; v1(8.54,159.66) C2152.2 ; v1(154.59,62.2) 154.55,62.2 154.4,62.04 153.6,62.04 C275.2 ; CV388.2 55.21,137 v1(55.19,137.02) ; v1(170.77,47.97) C837.2 ; PC9064.2 100.59,55.06 v1(101.04,54.61) ; CV382.2 63.19,145.93 v1(63.18,145.93) ; PR2006.2 74.83,6 74.4,5.57 v1(74.38,5.57) 74.37,5.57 73.94,6 PC2002.2 ; CV383.2 54.8,148.51 v1(54.79,148.5) ; U203.3 v1(27.08,146.19) ; CV56.2 85.05,124.98 v1(85.06,124.97) ; v1(86.84,79.72) 85.36,79.72 CC7.2 ; C832.2 v1(159.62,54.67) ; C187.1 176.2,68.36 v1(176.3,68.36) ; CD229.2 v1(40.92,49.12) ; v1(161.89,65.54) 161.35,66.08 PC748.2 ; RC84.2 104.97,49.19 v1(104.94,49.16) ; PC1035.2 84.78,134.49 v1(84.25,135.03) ; RC108.2 103.72,48.68 v1(103.72,49.12) ; v1(32.67,148.47) C217.2 ; v1(160.49,28.54) PC429.2 ; CV380.2 v1(62.93,120.16) ; CD225.2 39.84,62.53 v1(39.84,62.13) ; v1(90.21,64.88) 90.4,65.07 CC115.1 ; v1(64.42,32.22) C859.2 ; v1(104.91,53.49) 105.31,53.89 RC40.1 ; CC34.2 75.69,54.98 v1(75.69,54.61) ; v1(63.98,139.53) 63.98,139.4 64.34,139.04 CV385.2 ; CV53.2 83.35,129.39 v1(83.53,129.21) ; v1(104.8,56.79) CC75.2 ; RC82.2 105.14,51.07 v1(104.91,51.3) ; v1(82.01,110.52) 82.32,110.52 82.5,110.7 QV21.1 ; v1(59.18,146.73) 59.17,146.74 CV173.2 ; v1(30.87,144.85) 30.36,144.85 29.85,144.34 C204.2 ; CC19.2 v1(102.81,31.04) ; v1(94.62,64.87) 94.62,65.33 94.31,65.64 RC16.2 ; v1(64.92,120.42) 64.9,120.44 CV379.2
  TOP w0.406: 95.31,133.03 94.67,133.67 v1(94.67,133.78) ; RC24.2 94.09,80.74 UC21.3
  TOP w0.457: v1(177.89,47.34) 177.76,47.46 C183.2 ; PC912.2 47.19,144.47 v1(46.7,144.47) ; CC72.2 100.22,66.72 v1(100.23,66.71) ; 95.31,133.03 CV29.2 RV9.2 ; v1(83.34,152.81) RV3152.1 ; v1(104.87,46.91) 105.18,47.22 CC57.2 ; PR2008.2 51.21,7.65 v1(51.65,7.21) 52.1,7.65 PC2001.2 ; CC74.2 96.71,64.88 v1(96.78,64.81) ; v1(94.62,46.96) 94.52,47.06 CC67.2 ; v1(102.32,64.86) 102.34,64.88 CC73.2 ; PC614.2 63.64,14.11 v1(63.78,14.25) ; C823.2 v1(173.83,47.46) ; v1(40.79,145.13) 40.66,144.99 PC902.2 PR903.2 ; v1(90.25,140.32) 89.74,140.32 PC1001.2 PC1018.2 ; v1(92.62,49.71) 92.62,49.71 CC63.2 ; CV271.2 89.88,113.76 v1(89.44,114.2) 88.93,113.7 CV281.2 ; v1(106.99,55.22) 106.91,55.15 RC2.2 106.34,55.78 RC100.2 ; v1(95.81,47.12) 95.96,47.28 CC52.2 95.96,48.15 96.37,48.56 CC76.2 ; v1(154.59,62.2) 155.36,62.2 155.92,61.64 D303.1 ; v1(99.19,132.2) 99.04,132.35 RV13.2 CV11.2 ; PC1007.2 84.78,133.42 PC1035.2 ; C191.2 167.41,45.15 167.41,43.53 166.99,43.11 v1(166.86,43.11) ; PC913.2 v1(47.37,141.64) ; PC613.2 64.4,14.81 v1(64.42,14.83) ; L21.1 158.04,63.07 v1(157.6,63.51)
  TOP w0.508: UC25.2 101.83,33.15 v1(102.2,33.52) 102.2,33.89 CC18.2 ; C2153.2 v1(8.41,156.06) ; PC1021.2 v1(62.45,111.54) ; CC65.2 77.37,44.58 v1(77.41,44.62) ; CA45.2 39.83,11.1 v1(39.31,11.63) 39.87,12.18 CA67.2 ; PC451.2 PR452.2 164.37,31.27 v1(164.05,30.95) ; C201.2 v1(31.59,148.43) ; v1(100.9,129.49) 101.55,128.85 CV61.2 ; v1(148.43,36.45) CC135.1 CC131.1 ; v1(105.63,140.37) 105.63,140.49 105.2,140.92 RV88.1 ; v1(162.14,50.3) 162.14,49.88 161.89,49.62 161.51,49.62 ; CV44.2 v1(69.43,156.88) ; CC22.2 84.5,54.61 v1(85.47,54.61) ; R202.2 34.46,145.04 34.57,144.93 v1(34.57,144.89) ; v1(59.02,106.14) 58.96,106.08 PR1019.2 PC1006.2 ; v1(173.51,46.31) C838.1 ; PR738.1 v1(34.63,156.29) ; v1(157.99,30.26) 157.99,29.64 CC130.1 ; CC33.2 74.68,55.26 74.17,54.75 v1(74.17,54.59) ; CC23.2 84.19,50.24 v1(85.47,50.24) ; CD216.2 39.21,61.31 v1(39.21,62.13) ; C834.2 v1(181.02,64.41) ; C836.2 v1(180.69,49.99) ; v1(80.7,145.37) 81.35,145.37 81.75,144.97 CV91.2 ; CC44.2 91.53,39.58 v1(92.08,39.03) ; v1(100.8,56.79) 100.91,56.79 PC9016.2 ; Q412.3 31.46,116.83 v1(31.08,116.45) ; CC66.2 92.41,45.02 v1(92.41,45.8) ; CA71.2 47.61,11.1 v1(48.14,11.63) 47.58,12.18 CA47.2 ; CC62.2 78.64,44.53 v1(78.62,44.55) ; v1(100.12,62.56) 100,62.56 PC9012.2 ; CV45.2 v1(70.7,156.88) ; CC129.1 v1(143.74,29.82) ; R209.2 v1(27.85,150.77) ; U282.1 8.54,160.59 v1(8.54,159.66) ; v1(160.75,19.46) 160.33,19.88 PC411.2 ; v1(21.8,49.24) 21.28,49.76 RA65.1 ; PC518.2 PC519.2 v1(35.13,116.08) ; JHDT1.5 v1(82.32,82.45) ; v1(100.03,135.28) 100.28,135.53 CV19.2 ; v1(180.18,58.32) C833.2 C831.2 ; v1(150.46,36.84) CC133.2 CC132.2 ; v1(30.16,24.46) 30.13,24.49 CD207.2 ; v1(105.79,108.15) 103.6,105.95 CV36.2 ; SW1.1 4.72,37.23 v1(4.41,36.92) ; UC26.4 144.36,30.51 144.43,30.45 v1(144.43,29.81) ; PC9013.2 99.77,60.35 v1(99.62,60.5) ; v1(98.01,104.54) 98.01,104.44 QV17.3 ; v1(93.91,126.57) 93.74,126.74 RV59.1 94.11,127.26 94.34,127.49 RV29.1 ; QV11.3 v1(82.44,108.82) ; C844.2 172.67,15.51 173.22,16.06 v1(173.69,16.06) ; v1(41.37,114.65) 40.79,115.22 PC508.1 ; v1(64.54,5.75) 64.89,5.4 PR2007.2 ; v1(85.47,59.01) 85.39,59.09 CC21.2 ; PR610.2 v1(61.43,18.12) ; C189.2 163.49,68.59 163.87,68.2 v1(163.87,68.01) ; v1(40.22,118.01) 41.1,118.01 PD501.2 ; v1(107.53,38.42) RC157.1 ; 99.79,136.36 100.68,136.36 v1(100.72,136.32) ; PC2010.2 v1(55.27,18.38) ; J1.1 170.74,47.25 C837.2 ; JHDT1.3 81.05,83.02 v1(81.63,82.45) ; CV43.2 78.79,122.81 v1(78.79,122.61) ; PC9007.2 v1(132.87,54.7) ; v1(173.27,40.58) 172.94,40.91 R251.1 ; JSD1.12 17.86,6.04 v1(17.86,6.75) ; v1(24.35,145.27) R210.1 24.35,146.7 R205.1 ; PC831.2 153.56,50.69 v1(153.77,50.91) ; CC20.2 85.34,63.54 v1(85.47,63.41) ; v1(4.47,35.08) 4.78,34.78 SW1.3 ; CD218.2 37.77,54.27 RD210.1 39.83,54.27 v1(40.03,54.07) ; CC24.2 83.69,46.07 83.35,45.73 v1(83.35,45.09) ; PC425.2 170.59,14.95 170.02,15.52 v1(170.02,16.79) ; PC407.2 154.65,14.44 v1(154.65,14.83) ; PC2009.2 75.97,8.09 76.57,7.5 v1(76.57,6.8) ; v1(95.34,41.62) 94.77,41.05 CC51.2 94.77,40.54 94.91,40.4 RC160.1 RC161.1 ; CC43.2 85.63,45.7 v1(85.67,45.66) ; PR609.2 61.4,19.89 61.4,19.89 v1(61.34,19.89) ; CC64.2 v1(77.12,38.57) ; CC59.2 v1(77.12,36.16) ; CC32.2 75.28,59.39 v1(74.81,59.86) 74.32,59.37 CC36.2 ; C848.2 v1(182.21,9.81) ; PC1003.2 PC1029.1 60.85,100.79 61.11,101.06 v1(61.11,101.31) ; v1(27.21,116.83) Q411.3 ; v1(99.28,98.13) 98.77,98.13 98.21,98.68 QV18.3 ; JHDT1.7 v1(83.59,82.45) ; v1(86.95,142.79) 86.74,142.59 CV81.2 ; v1(73.64,59.9) 73.37,59.63 CC35.2 ; PC9017.2 100.1,57.86 v1(100.75,57.86) ; PC1012.2 89.69,142.52 v1(90.07,142.91) ; PC9033.2 PC9031.2 91.32,62.87 91.32,63.48 91.34,63.5 v1(91.34,63.5) ; C182.2 v1(177.89,68.55) ; v1(39.78,57.88) 39.65,57.75 CD217.2 ; CC60.2 v1(78.39,38.57) ; PC428.2 PR412.2 163.31,24.6 163.68,24.23 v1(163.68,23.3) ; v1(100.02,64.75) 100.05,64.71 PC9011.2 ; DA3.2 v1(43.37,11.33) ; C845.2 v1(185.19,14.38) ; PC502.2 v1(41.7,101.63) ; C847.2 v1(182.21,10.7) ; C856.2 v1(89.58,32.86) ; PR907.2 v1(44.1,142.07) ; v1(89.94,82.52) JHDT1.17 ; PC2006.2 v1(55.78,11.27) ; RV89.1 v1(102.82,140.92) ; U202.2 v1(30.83,146.84) ; PC2008.2 v1(55.32,8.11) ; CC58.2 v1(78.39,36.16) ; CC134.1 v1(149.38,36.45)
  VCC w0.203: 10.52,155.09 JDCIN1.2 ; JDCIN1.2 12.68,154.31 ; JDCIN1.2 11.6,155.09 ; JDCIN1.2 10.52,153.53 ; JDCIN1.2 10.52,154.31 ; JDCIN1.2 12.68,155.09 ; JDCIN1.2 12.68,153.53 ; JDCIN1.2 11.6,153.53 ; 2.21,34.98 SW1.5 ; SW1.5 3.28,34.98 ; SW1.5 2.21,33.43 ; SW1.5 2.21,34.21 ; JUSB1.11 7.49,54.23 ; JUSB1.11 6.12,53.35 ; JUSB1.11 4.75,53.35 ; JUSB1.11 7.49,53.35 ; JUSB1.11 4.75,54.23 ; 4.75,69.93 JUSB1.13 ; JUSB1.13 7.49,70.81 ; JUSB1.13 4.75,70.81 ; JUSB1.13 7.49,69.93 ; JUSB1.13 6.12,70.81 ; SW1.4 3.28,37.03 ; SW1.4 2.21,37.03 ; SW1.4 2.21,37.81 ; JUSB2.12 15,91.11 ; JUSB2.12 15,90.23 ; JUSB2.12 15,89.35 ; JUSB2.12 11.44,91.11 ; JUSB2.12 11.44,90.23 ; JUSB2.12 13.22,91.11 ; JDCIN1.5 12.68,144.51 ; JDCIN1.5 10.52,144.51 ; JDCIN1.5 12.68,143.73 ; JDCIN1.5 11.6,145.29 ; JDCIN1.5 10.52,145.29 ; JDCIN1.5 12.68,145.29 ; JDCIN1.5 11.6,143.73 ; JDCIN1.5 10.52,143.73 ; JUSB2.13 7.49,90.23 ; JUSB2.13 6.12,91.11 ; JUSB2.13 4.75,91.11 ; JUSB2.13 4.75,90.23 ; JUSB2.13 7.49,91.11 ; 2.3,155.66 H6.1 ; H6.1 5.22,154.42 ; H6.1 3.98,157.34 ; H6.1 2.74,156.9 ; H6.1 5.22,156.9 ; H6.1 5.66,155.66 ; H6.1 3.98,153.98 ; H6.1 2.74,154.42 ; JBAT1.9 118.34,21.86 ; JBAT1.9 118.34,20.86 ; JBAT1.9 117.64,21.86 ; JBAT1.9 116.95,21.86 ; JBAT1.9 116.95,20.86 ; JHDMI1.17 11.01,108.49 ; JHDMI1.17 11.13,108.03 ; JHDMI1.17 10.09,108.49 ; JHDMI1.17 11.01,107.57 ; JHDMI1.17 9.97,108.03 ; JHDMI1.17 10.09,107.57 ; H4.1 103.77,112.88 ; H4.1 102.25,113.44 ; H4.1 104.33,111.36 ; H4.1 100.17,111.36 ; H4.1 100.73,109.84 ; H4.1 102.25,109.28 ; H4.1 100.73,112.88 ; H4.1 103.77,109.84 ; 104.7,21.86 JBAT1.11 ; JBAT1.11 104.7,20.86 ; JBAT1.11 106.09,20.86 ; JBAT1.11 106.09,21.86 ; JBAT1.11 105.39,21.86 ; 10.09,102.49 JHDMI1.5 ; JHDMI1.5 9.97,102.03 ; JHDMI1.5 11.01,101.57 ; JHDMI1.5 11.01,102.49 ; JHDMI1.5 10.09,101.57 ; JHDMI1.5 11.13,102.03 ; 15.07,113.55 H8.1 ; H8.1 16.75,115.23 ; H8.1 13.83,113.99 ; H8.1 16.31,116.47 ; H8.1 16.31,113.99 ; H8.1 13.39,115.23 ; 2.74,144.4 H7.1 ; H7.1 5.22,144.4 ; H7.1 2.3,143.16 ; H7.1 3.98,144.84 ; H7.1 5.66,143.16 ; H7.1 2.74,141.92 ; H7.1 5.22,141.92 ; H7.1 3.98,141.48 ; JUSB2.4 16.13,78.35 ; JUSB2.4 16.13,79.41 ; JUSB2.4 14.93,78.88 ; JUSB2.4 15.6,78.21 ; JUSB2.4 15.07,78.35 ; JUSB2.4 15.6,79.55 ; JUSB2.4 15.07,79.41 ; JUSB2.4 16.27,78.88 ; H2.1 76.89,82.44 ; H2.1 73.29,83.96 ; H2.1 75.37,86.04 ; H2.1 76.89,85.48 ; H2.1 73.85,85.48 ; H2.1 77.45,83.96 ; H2.1 73.85,82.44 ; H2.1 75.37,81.88 ; JUSB1.10 15,53.35 ; JUSB1.10 13.22,53.35 ; JUSB1.10 15,55.11 ; JUSB1.10 11.44,53.35 ; JUSB1.10 11.44,54.23 ; JUSB1.10 15,54.23 ; JHDMI1.21 5.33,94.45 ; JHDMI1.21 2.77,95.38 ; JHDMI1.21 4.05,96.31 ; JHDMI1.21 4.05,94.45 ; JHDMI1.21 5.33,96.31 ; JHDMI1.21 2.77,94.45 ; JHDMI1.21 5.33,95.38 ; JHDMI1.21 2.77,96.31 ; JUSB1.12 15,69.05 ; JUSB1.12 13.22,70.81 ; JUSB1.12 15,69.93 ; JUSB1.12 15,70.81 ; JUSB1.12 11.44,70.81 ; JUSB1.12 11.44,69.93 ; JHDMI1.22 13.53,110.85 ; JHDMI1.22 12.25,112.71 ; JHDMI1.22 10.97,112.71 ; JHDMI1.22 13.53,111.78 ; JHDMI1.22 10.97,111.78 ; JHDMI1.22 10.97,110.85 ; JHDMI1.22 13.53,112.71 ; JHDMI1.22 12.25,110.85 ; JHDMI1.8 12.68,103.53 ; JHDMI1.8 12.56,103.99 ; JHDMI1.8 11.52,103.53 ; JHDMI1.8 12.56,103.07 ; JHDMI1.8 11.64,103.07 ; JHDMI1.8 11.64,103.99 ; JDCIN1.3 7.18,154.41 ; JDCIN1.3 7.18,155.29 ; JDCIN1.3 5.78,155.29 ; JDCIN1.3 6.48,155.29 ; JDCIN1.3 6.48,153.53 ; JDCIN1.3 7.18,153.53 ; JDCIN1.3 5.78,154.41 ; JDCIN1.3 5.78,153.53 ; 172.37,68.93 H15.1 ; H15.1 170.34,70.96 ; H15.1 170.88,72.45 ; H15.1 172.37,72.99 ; H15.1 173.86,69.47 ; H15.1 174.4,70.96 ; H15.1 170.88,69.47 ; H15.1 173.86,72.45 ; 15.07,58.05 JUSB1.4 ; JUSB1.4 16.13,59.11 ; JUSB1.4 16.27,58.58 ; JUSB1.4 15.6,59.25 ; JUSB1.4 14.93,58.58 ; JUSB1.4 15.6,57.91 ; JUSB1.4 15.07,59.11 ; JUSB1.4 16.13,58.05 ; 5.78,143.53 JDCIN1.4 ; JDCIN1.4 6.48,143.53 ; JDCIN1.4 5.78,145.29 ; JDCIN1.4 7.18,145.29 ; JDCIN1.4 7.18,143.53 ; JDCIN1.4 5.78,144.41 ; JDCIN1.4 7.18,144.41 ; JDCIN1.4 6.48,145.29 ; JUSB1.7 14.1,62.75 ; JUSB1.7 14.63,62.61 ; JUSB1.7 14.63,61.55 ; JUSB1.7 14.1,61.41 ; JUSB1.7 13.57,61.55 ; JUSB1.7 13.57,62.61 ; JUSB1.7 14.77,62.08 ; 2.17,36.98 SW1.6 ; SW1.6 2.17,38.13 ; SW1.6 4.62,38.13 ; SW1.6 3.85,36.98 ; SW1.6 4.62,36.98 ; JUSB2.11 7.49,74.53 ; JUSB2.11 4.75,74.53 ; JUSB2.11 7.49,73.65 ; JUSB2.11 4.75,73.65 ; JUSB2.11 6.12,73.65 ; H12.1 182.61,31.1 ; H12.1 179.69,29.86 ; H12.1 180.13,28.62 ; H12.1 181.37,31.54 ; H12.1 183.05,29.86 ; H12.1 180.13,31.1 ; H12.1 181.37,28.18 ; H12.1 182.61,28.62 ; JHDMI1.23 2.8,114.61 ; JHDMI1.23 4.08,114.61 ; JHDMI1.23 1.52,113.68 ; JHDMI1.23 1.52,112.75 ; JHDMI1.23 4.08,112.75 ; JHDMI1.23 4.08,113.68 ; JHDMI1.23 2.8,112.75 ; 10.97,96.35 JHDMI1.20 ; JHDMI1.20 10.97,98.21 ; JHDMI1.20 13.53,98.21 ; JHDMI1.20 10.97,97.28 ; JHDMI1.20 13.53,96.35 ; JHDMI1.20 12.25,98.21 ; JHDMI1.20 12.25,96.35 ; JHDMI1.20 13.53,97.28 ; H5.1 76.67,157.44 ; H5.1 75.15,156.88 ; H5.1 74.59,155.36 ; H5.1 76.67,153.28 ; H5.1 78.75,155.36 ; H5.1 78.19,153.84 ; H5.1 75.15,153.84 ; H5.1 78.19,156.88 ; 13.57,82.91 JUSB2.7 ; JUSB2.7 14.1,81.71 ; JUSB2.7 14.77,82.38 ; JUSB2.7 13.57,81.85 ; JUSB2.7 14.1,83.05 ; JUSB2.7 14.63,81.85 ; JUSB2.7 14.63,82.91 ; 13.22,73.65 JUSB2.10 ; JUSB2.10 15,75.41 ; JUSB2.10 11.44,73.65 ; JUSB2.10 15,73.65 ; JUSB2.10 11.44,74.53 ; JUSB2.10 15,74.53 ; 11.52,100.53 JHDMI1.2 ; JHDMI1.2 12.56,100.99 ; JHDMI1.2 12.56,100.07 ; JHDMI1.2 12.1,99.95 ; JHDMI1.2 11.64,100.07 ; JHDMI1.2 12.68,100.53 ; JHDMI1.2 11.64,100.99 ; 2.17,33.1 SW1.7 ; SW1.7 4.62,33.1 ; SW1.7 2.17,33.88 ; SW1.7 4.62,33.88 ; SW1.7 4.62,35.03 ; SW1.7 2.17,35.03 ; SW1.7 3.85,35.03 ; SW1.7 3.85,33.1 ; 10.09,104.57 JHDMI1.11 ; JHDMI1.11 10.09,105.49 ; JHDMI1.11 11.01,105.49 ; JHDMI1.11 11.01,104.57 ; JHDMI1.11 11.13,105.03 ; JHDMI1.11 9.97,105.03
  GND w0.203: 2.74,156.9 H6.1 ; H6.1 5.22,156.9 ; H6.1 3.98,153.98 ; H6.1 5.22,154.42 ; H6.1 2.74,154.42 ; H6.1 5.66,155.66 ; H6.1 2.3,155.66 ; H6.1 3.98,157.34 ; 12.25,96.35 JHDMI1.20 ; JHDMI1.20 13.53,98.21 ; JHDMI1.20 10.97,97.28 ; JHDMI1.20 10.97,96.35 ; JHDMI1.20 12.25,98.21 ; JHDMI1.20 10.97,98.21 ; JHDMI1.20 13.53,97.28 ; JHDMI1.20 13.53,96.35 ; 11.44,70.81 JUSB1.12 ; JUSB1.12 15,70.81 ; JUSB1.12 15,69.05 ; JUSB1.12 15,69.93 ; JUSB1.12 13.22,70.81 ; JUSB1.12 11.44,69.93 ; JUSB2.10 15,73.65 ; JUSB2.10 11.44,74.53 ; JUSB2.10 13.22,73.65 ; JUSB2.10 15,74.53 ; JUSB2.10 15,75.41 ; JUSB2.10 11.44,73.65 ; 118.95,53.82 H3.1 ; H3.1 121.03,51.74 ; H3.1 123.11,53.82 ; H3.1 122.55,52.3 ; H3.1 121.03,55.9 ; H3.1 119.51,55.34 ; H3.1 122.55,55.34 ; H3.1 119.51,52.3 ; 4.75,90.23 JUSB2.13 ; JUSB2.13 7.49,90.23 ; JUSB2.13 7.49,91.11 ; JUSB2.13 4.75,91.11 ; JUSB2.13 6.12,91.11 ; JDCIN1.4 6.48,145.29 ; JDCIN1.4 7.18,143.53 ; JDCIN1.4 6.48,143.53 ; JDCIN1.4 7.18,144.41 ; JDCIN1.4 5.78,144.41 ; JDCIN1.4 7.18,145.29 ; JDCIN1.4 5.78,143.53 ; JDCIN1.4 5.78,145.29 ; 11.44,90.23 JUSB2.12 ; JUSB2.12 11.44,91.11 ; JUSB2.12 15,90.23 ; JUSB2.12 15,91.11 ; JUSB2.12 13.22,91.11 ; JUSB2.12 15,89.35 ; 11.44,53.35 JUSB1.10 ; JUSB1.10 13.22,53.35 ; JUSB1.10 15,53.35 ; JUSB1.10 15,54.23 ; JUSB1.10 11.44,54.23 ; JUSB1.10 15,55.11 ; JDCIN1.5 11.6,145.29 ; JDCIN1.5 12.68,144.51 ; JDCIN1.5 10.52,143.73 ; JDCIN1.5 12.68,143.73 ; JDCIN1.5 10.52,144.51 ; JDCIN1.5 10.52,145.29 ; JDCIN1.5 12.68,145.29 ; JDCIN1.5 11.6,143.73 ; 100.73,112.88 H4.1 ; H4.1 100.73,109.84 ; H4.1 102.25,109.28 ; H4.1 103.77,112.88 ; H4.1 100.17,111.36 ; H4.1 102.25,113.44 ; H4.1 103.77,109.84 ; H4.1 104.33,111.36 ; 14.93,78.88 JUSB2.4 ; JUSB2.4 16.27,78.88 ; JUSB2.4 16.13,79.41 ; JUSB2.4 15.6,78.21 ; JUSB2.4 15.6,79.55 ; JUSB2.4 16.13,78.35 ; JUSB2.4 15.07,78.35 ; JUSB2.4 15.07,79.41 ; 2.77,94.45 JHDMI1.21 ; JHDMI1.21 5.33,95.38 ; JHDMI1.21 2.77,95.38 ; JHDMI1.21 5.33,96.31 ; JHDMI1.21 2.77,96.31 ; JHDMI1.21 5.33,94.45 ; JHDMI1.21 4.05,94.45 ; JHDMI1.21 4.05,96.31 ; JHDMI1.23 4.08,113.68 ; JHDMI1.23 1.52,112.75 ; JHDMI1.23 1.52,113.68 ; JHDMI1.23 2.8,112.75 ; JHDMI1.23 2.8,114.61 ; JHDMI1.23 4.08,114.61 ; JHDMI1.23 4.08,112.75 ; JBAT1.12 105.39,18.39 ; JBAT1.12 106.09,17.38 ; JBAT1.12 106.09,16.38 ; JBAT1.12 104.7,17.38 ; JBAT1.12 105.39,16.38 ; JBAT1.12 106.09,18.39 ; JBAT1.12 104.7,16.38 ; JBAT1.12 104.7,18.39 ; H12.1 182.61,28.62 ; H12.1 183.05,29.86 ; H12.1 182.61,31.1 ; H12.1 180.13,28.62 ; H12.1 181.37,28.18 ; H12.1 181.37,31.54 ; H12.1 180.13,31.1 ; H12.1 179.69,29.86 ; H1.1 76.89,25.88 ; H1.1 73.85,22.84 ; H1.1 76.89,22.84 ; H1.1 75.37,22.28 ; H1.1 77.45,24.36 ; H1.1 73.85,25.88 ; H1.1 75.37,26.44 ; H1.1 73.29,24.36 ; JUSB1.11 7.49,53.35 ; JUSB1.11 4.75,54.23 ; JUSB1.11 7.49,54.23 ; JUSB1.11 4.75,53.35 ; JUSB1.11 6.12,53.35 ; JHDMI1.5 11.01,102.49 ; JHDMI1.5 9.97,102.03 ; JHDMI1.5 11.13,102.03 ; JHDMI1.5 10.09,101.57 ; JHDMI1.5 11.01,101.57 ; JHDMI1.5 10.09,102.49 ; JUSB2.11 7.49,73.65 ; JUSB2.11 7.49,74.53 ; JUSB2.11 6.12,73.65 ; JUSB2.11 4.75,73.65 ; JUSB2.11 4.75,74.53 ; 13.57,82.91 JUSB2.7 ; JUSB2.7 14.63,82.91 ; JUSB2.7 14.1,81.71 ; JUSB2.7 14.77,82.38 ; JUSB2.7 13.57,81.85 ; JUSB2.7 14.63,81.85 ; JUSB2.7 14.1,83.05 ; JHDMI1.2 12.56,100.07 ; JHDMI1.2 12.56,100.99 ; JHDMI1.2 11.64,100.07 ; JHDMI1.2 11.52,100.53 ; JHDMI1.2 11.64,100.99 ; JHDMI1.2 12.1,99.95 ; JHDMI1.2 12.68,100.53 ; JUSB1.13 7.49,69.93 ; JUSB1.13 7.49,70.81 ; JUSB1.13 4.75,70.81 ; JUSB1.13 4.75,69.93 ; JUSB1.13 6.12,70.81 ; 3.98,141.48 H7.1 ; H7.1 2.3,143.16 ; H7.1 3.98,144.84 ; H7.1 5.22,144.4 ; H7.1 2.74,144.4 ; H7.1 5.66,143.16 ; H7.1 5.22,141.92 ; H7.1 2.74,141.92 ; 11.52,103.53 JHDMI1.8 ; JHDMI1.8 11.64,103.99 ; JHDMI1.8 12.56,103.07 ; JHDMI1.8 11.64,103.07 ; JHDMI1.8 12.68,103.53 ; JHDMI1.8 12.56,103.99 ; H5.1 76.67,157.44 ; H5.1 75.15,156.88 ; H5.1 76.67,153.28 ; H5.1 78.19,156.88 ; H5.1 78.19,153.84 ; H5.1 78.75,155.36 ; H5.1 75.15,153.84 ; H5.1 74.59,155.36 ; JUSB1.7 14.63,62.61 ; JUSB1.7 13.57,61.55 ; JUSB1.7 14.77,62.08 ; JUSB1.7 14.63,61.55 ; JUSB1.7 14.1,61.41 ; JUSB1.7 14.1,62.75 ; JUSB1.7 13.57,62.61 ; 2.17,33.1 SW1.7 ; SW1.7 3.85,35.03 ; SW1.7 4.62,33.88 ; SW1.7 2.17,33.88 ; SW1.7 4.62,35.03 ; SW1.7 3.85,33.1 ; SW1.7 2.17,35.03 ; SW1.7 4.62,33.1 ; JHDMI1.22 13.53,110.85 ; JHDMI1.22 10.97,111.78 ; JHDMI1.22 10.97,110.85 ; JHDMI1.22 10.97,112.71 ; JHDMI1.22 13.53,112.71 ; JHDMI1.22 12.25,110.85 ; JHDMI1.22 13.53,111.78 ; JHDMI1.22 12.25,112.71 ; 2.21,33.43 SW1.5 ; SW1.5 2.21,34.98 ; SW1.5 3.28,34.98 ; SW1.5 2.21,34.21 ; 6.48,153.53 JDCIN1.3 ; JDCIN1.3 7.18,154.41 ; JDCIN1.3 6.48,155.29 ; JDCIN1.3 5.78,155.29 ; JDCIN1.3 7.18,153.53 ; JDCIN1.3 5.78,154.41 ; JDCIN1.3 5.78,153.53 ; JDCIN1.3 7.18,155.29 ; JUSB1.4 16.13,58.05 ; JUSB1.4 14.93,58.58 ; JUSB1.4 16.27,58.58 ; JUSB1.4 15.07,58.05 ; JUSB1.4 15.6,59.25 ; JUSB1.4 15.6,57.91 ; JUSB1.4 16.13,59.11 ; JUSB1.4 15.07,59.11 ; JDCIN1.2 12.68,155.09 ; JDCIN1.2 11.6,155.09 ; JDCIN1.2 11.6,153.53 ; JDCIN1.2 10.52,154.31 ; JDCIN1.2 12.68,153.53 ; JDCIN1.2 12.68,154.31 ; JDCIN1.2 10.52,155.09 ; JDCIN1.2 10.52,153.53 ; 9.97,108.03 JHDMI1.17 ; JHDMI1.17 11.01,107.57 ; JHDMI1.17 11.01,108.49 ; JHDMI1.17 10.09,108.49 ; JHDMI1.17 11.13,108.03 ; JHDMI1.17 10.09,107.57 ; JBAT1.9 117.64,21.86 ; JBAT1.9 117.64,19.86 ; JBAT1.9 116.95,20.86 ; JBAT1.9 116.95,19.86 ; JBAT1.9 118.34,21.86 ; JBAT1.9 118.34,19.86 ; JBAT1.9 118.34,20.86 ; JBAT1.9 116.95,21.86 ; JHDMI1.11 11.01,105.49 ; JHDMI1.11 10.09,105.49 ; JHDMI1.11 11.01,104.57 ; JHDMI1.11 9.97,105.03 ; JHDMI1.11 11.13,105.03 ; JHDMI1.11 10.09,104.57 ; 116.95,17.38 JBAT1.10 ; JBAT1.10 117.64,16.38 ; JBAT1.10 117.64,18.39 ; JBAT1.10 116.95,18.39 ; JBAT1.10 118.34,16.38 ; JBAT1.10 118.34,18.39 ; JBAT1.10 118.34,17.38 ; JBAT1.10 116.95,16.38 ; 2.21,37.81 SW1.4 ; SW1.4 2.21,37.03 ; SW1.4 3.28,37.03 ; 114.78,78.12 H13.1 ; H13.1 113.54,78.56 ; H13.1 116.46,79.8 ; H13.1 116.02,78.56 ; H13.1 113.1,79.8 ; H13.1 114.78,81.48 ; H13.1 116.02,81.04 ; H13.1 113.54,81.04 ; JBAT1.11 106.09,20.86 ; JBAT1.11 104.7,20.86 ; JBAT1.11 104.7,19.86 ; JBAT1.11 105.39,21.86 ; JBAT1.11 106.09,19.86 ; JBAT1.11 104.7,21.86 ; JBAT1.11 106.09,21.86 ; JBAT1.11 105.39,19.86 ; 15.07,113.55 H8.1 ; H8.1 16.75,115.23 ; H8.1 16.31,113.99 ; H8.1 16.31,116.47 ; H8.1 13.39,115.23 ; H8.1 13.83,113.99 ; H15.1 172.37,72.99 ; H15.1 174.4,70.96 ; H15.1 172.37,68.93 ; H15.1 170.88,69.47 ; H15.1 170.88,72.45 ; H15.1 173.86,72.45 ; H15.1 173.86,69.47 ; H15.1 170.34,70.96 ; 3.85,36.98 SW1.6 ; SW1.6 2.17,36.98 ; SW1.6 4.62,38.13 ; SW1.6 2.17,38.13 ; SW1.6 4.62,36.98 ; 75.37,81.88 H2.1 ; H2.1 76.89,85.48 ; H2.1 73.85,82.44 ; H2.1 75.37,86.04 ; H2.1 73.29,83.96 ; H2.1 77.45,83.96 ; H2.1 73.85,85.48 ; H2.1 76.89,82.44 ; 84.72,16.68 H10.1 ; H10.1 86.4,18.36 ; H10.1 85.96,19.6 ; H10.1 85.96,17.12 ; H10.1 83.04,18.36 ; H10.1 83.48,19.6 ; H10.1 83.48,17.12 ; H10.1 84.72,20.04
  BOTTOM w0.102: v3(20.16,114.46) 20.16,114.39 18.95,113.19 ; v1(105.92,116.49) v3(105.92,115.89)
  BOTTOM w0.127: v1(83.59,82.45) 84.36,81.69 v3(84.36,80.17) ; RV120.2 v3(56.86,116.22) ; v3(17.66,23.83) 18,23.49 v1(18,22.89) ; v1(62.8,101.38) 62.77,101.34 v3(62.77,100.49) ; v3(155.91,34.36) 155.91,34.94 155.72,35.13 ; v1(175.67,64.1) v3(174.48,64.1) ; v1(87.47,117.51) 88.87,116.11 v3(89.02,116.11) ; v3(122.56,48.71) v1(123.28,49.43)
  BOTTOM w0.152: v1(51.98,139.53) 52.21,139.53 52.78,139.53 ; UC1.A18 96.82,67.06 v1(96.75,67.13) ; UC1.AY11 UC1.BA11
  BOTTOM w0.178: v1(80.39,125.09) 80.39,125.32 80.39,125.33 80.39,125.65 80.39,125.65 80.39,125.9 UV1.F26 ; UV1.B10 77.71,139.09 v1(77.6,138.97)
  BOTTOM w0.203: UC1.BA7 102.87,43.49 v1(103.05,43.31) ; v1(87,70.27) 87.25,70.52 88.18,70.52 89.28,69.42 89.28,68.44 88.84,68 88.84,67.18 v1(88.92,67.1) 88.95,67.08 88.95,66.28 UC1.A32 UC1.B32 ; PU501.3 v1(34.06,114.71) ; UC1.B13 99.72,65.91 99.72,66.31 UC1.A13 99.82,66.71 v1(100.23,66.71) ; v1(91.95,137.83) 91.04,137.83 UV1.V11 ; PU501.1 34.83,113.91 34.7,113.78 v1(34.7,113.45) ; PU501.14 38.72,114.31 38.89,114.14 v1(39.19,114.14) ; UV1.K2 83.98,145.21 v1(84.03,145.25) ; UV1.F2 80.78,145.29 v1(80.7,145.37) ; v1(82.47,145.99) 82.4,145.92 82.4,144.31 UV1.H2 ; v1(96.75,122.51) 96.75,123.06 UV1.AF32
  BOTTOM w0.254: UV8.A3 64.38,139.13 v1(63.98,139.53) ; UV7.H1 57.18,131.08 v1(56.78,130.67) 57.16,130.29 UV7.H2 ; UC1.BA31 89.67,42.39 v1(89.54,42.26) ; v1(92.46,124.96) 92.46,125.15 92.78,125.47 UV1.AA27 ; v1(81.68,124.81) 81.72,124.86 81.72,125.35 UV1.G27 ; v1(87.7,35.4) 87.15,35.95 RPC12.2 ; v1(80.38,137.96) 80.38,137.89 UV1.F12 ; v1(85.58,142.8) 85.58,142.8 UV1.M6 ; v1(83.27,122.91) 83.81,122.91 UV1.K32 ; v1(98.33,43.08) 98.47,43.23 UC1.BA15 ; v1(58.78,131.64) 58.78,131.64 UV7.K1 UV7.K2 ; UV7.N12 61.16,122.29 60.75,122.71 v1(60.75,122.75) ; UV8.P10 v1(54.38,144.33) ; v1(54.77,131.64) 54.78,131.64 UV7.E1 ; v1(64.08,131.57) 64.38,131.27 UV7.U1 ; UV8.C4 v1(62.37,139.52) 62.39,139.52 UV8.C3 ; UV8.B5 v1(63.98,140.33) ; UV1.F18 81.3,132.69 v1(81.32,132.67) ; v1(108.36,62.83) 107.53,62.83 107.51,62.86 UC1.G1 UC1.G2 ; UV1.G8 81.48,140.79 80.88,140.79 UV1.F8 80.62,140.52 v1(80.33,140.52) ; v1(57.18,148.5) 57.18,148.5 UV8.K14 UV8.K13 ; v1(59.18,146.73) 59.18,146.73 UV8.H13 ; UC1.AW17 97.17,45.46 v1(96.82,45.46) 96.47,45.46 UC1.AW19 ; UV7.K13 58.78,121.47 v1(58.38,121.07) 58.76,120.69 UV7.K14 ; UV7.H14 v1(56.81,121.06) ; v1(88.53,142.99) 88.53,142.54 UV1.T6 ; v1(55.22,128.31) 55.58,127.95 UV7.F5 ; UV7.R4 63.17,128.3 63.21,128.3 63.21,128.29 v1(63.2,128.29) ; v1(83.68,124.31) 83.68,124.31 83.98,124.62 UV1.K28 ; UC1.AW25 92.43,45.8 v1(92.41,45.8) UC1.AW27 ; UC1.AA2 105.8,55.16 105.87,55.22 106.37,55.22 106.39,55.21 106.42,55.21 UC1.AA1 106.92,55.16 v1(106.99,55.22) ; UV7.H13 57.16,121.49 v1(56.78,121.87) ; UV1.B12 78.33,137.49 v1(78.22,137.38) ; UC1.AR19 96.21,47.56 95.81,47.16 v1(95.81,47.12) ; UV8.C1 62.99,137.32 62.99,137.29 63.12,137.16 v1(63.12,137.06) ; UV7.E14 54.8,120.69 v1(55.18,120.31) ; RPV34.4 v1(85.8,150.21) ; UV8.E14 61.14,147.97 61.14,148.53 v1(61.13,148.54) ; UV8.H2 UV8.H1 58.78,137.04 v1(58.75,137.01) ; UV7.C4 53.17,128.69 v1(52.78,129.09) UV7.C3 ; UC1.AW31 89.79,45.38 89.84,45.43 v1(90.22,45.43) 90.6,45.43 UC1.AW29 ; v1(78.3,127.91) 78.32,127.89 UV1.B24 ; UV1.AH28 98,124.69 v1(97.85,124.84) 97.85,124.83 97.85,125.22 UV1.AG27 ; UC1.U3 104.92,57.51 v1(104.92,57.92) ; UC1.U3 105.07,57.04 104.82,56.79 v1(104.8,56.79) ; UC1.U3 UC1.U2 UC1.U1 v1(107.06,57.36) ; UV8.E1 v1(61.72,136.99) ; v1(98.4,122.52) 98.38,122.54 UV1.AH32 ; UV1.R27 87.81,125.49 87.42,125.09 86.78,125.09 UV1.N27 ; UV7.A1 51.56,131.09 v1(51.18,131.47) ; UV8.R4 52.78,139.53 ; v1(82.75,135.17) 82.75,135.32 UV1.H14 ; UV1.J27 v1(83.18,124.77) ; UV1.F10 UV1.G10 81.58,139.13 v1(81.9,139.45) ; v1(60.78,146.73) 61.18,146.33 UV8.E12 ; UV7.N14 61.18,120.14 v1(61.22,120.1) ; UV8.T10 v1(52.78,145.13) UV8.R11 ; UC1.BA11 100.67,42.38 v1(100.55,42.26) ; UV8.G5 59.58,141.14 v1(59.75,141.31) ; UV7.L10 59.6,123.89 v1(59.98,124.27) 60.36,123.89 UV7.M10 ; UV8.K2 UV8.K1 57.18,137.03 v1(57.03,136.88) ; UV8.R12 53.18,146.33 v1(52.78,146.73) ; UV1.AD8 95.17,140.69 v1(94.82,141.04) ; UV7.R14 62.78,120.31 v1(62.93,120.16) ; v1(82.05,130.35) 82.38,130.68 UV1.H20 ; v1(52.78,127.47) 52.38,127.87 UV7.B5 ; v1(93.2,142.66) 93.57,142.29 UV1.AB6 ; UV7.U14 64.65,120.42 v1(64.92,120.42) ; v1(106.9,43.8) 106.9,43.1 109.26,40.75 v1(109.87,40.75) 110.12,41 CC12.2 110.72,40.8 113.18,40.8 113.38,40.61 113.38,36.92 113.11,36.66 v1(111.51,36.66) ; UV8.C11 62.78,145.53 v1(63.18,145.93) 62.78,146.33 UV8.C12 ; UV8.R3 53.18,139.13 v1(53.58,138.73) ; UV1.G31 81.85,123.22 81.85,122.74 81.41,122.3 v1(81.34,122.3) ; UC1.AU21 94.82,46.76 v1(94.62,46.96) 94.07,47.51 UC1.AR23 93.63,47.12 v1(93.57,47.12) ; UV7.U12 v1(63.98,122.69) ; UV8.R14 53.18,148.32 v1(53.03,148.46) ; UV1.Y32 v1(91.98,122.57) ; UV7.P10 v1(62.39,123.48) UV7.R11 v1(63.19,123.5) UV7.T10 ; v1(77.61,140.68) 77.69,140.68 77.7,140.69 UV1.B8 ; UV8.N12 v1(55.18,146.73) ; UV1.B18 v1(77.88,132.69) ; UV1.J31 83.18,123 83.23,122.95 ; UV8.U1 51.58,137.42 v1(51.95,137.05) ; UV7.T5 v1(63.18,127.49) ; UV8.A1 64.38,137.53 v1(64.85,137.07) ; v1(83.08,54.04) 83.1,54.06 UC1.AC41 ; UV7.C1 53.18,131.53 v1(53.07,131.64) ; UV8.A12 64.6,146.33 v1(65.1,145.83) ; v1(88.29,123) 88.38,123.09 UV1.T32 ; UC1.AW13 99.37,45.46 v1(99.02,45.46) 98.67,45.46 UC1.AW15 ; UC1.E3 UC1.E2 105.87,64.06 106.36,64.06 106.45,63.96 UC1.E1 106.97,63.96 107.7,64.69 v1(108.36,64.69) ; v1(51.01,146.63) 51.31,146.33 UV8.U12 ; UV8.T5 52.38,140.92 v1(52.66,141.2) ; UV8.U14 51.58,147.93 51.24,148.27 v1(51.1,148.27) ; v1(95.81,26.43) 95.66,26.28 RPC11.4 ; v1(80.39,128.35) 80.39,128.33 80.78,127.94 UV1.F24 ; UV7.L5 59.58,127.87 v1(59.98,127.47) 60.38,127.87 UV7.M5 ; UV1.AD32 95.18,122.72 v1(95.08,122.62) ; v1(95.58,126.69) UV1.AD25 UV1.AC24 ; v1(83.07,62.86) UC1.G41 ; RPC9.2 107.54,37.8 v1(107.53,37.8) 107.22,37.8 107.04,37.62 RPC9.1 ; UC1.A8 UC1.B8 102.52,65.41 UC1.C7 ; v1(83.12,58.49) 83.12,58.52 83.17,58.57 83.76,58.57 UC1.R41 ; UV1.P32 87.57,123.09 v1(87.66,123) ; UV1.M32 86.08,123.09 v1(86.57,122.6) ; UV8.U3 v1(51.98,139.53) ; UV8.A14 64.74,148.28 v1(64.92,148.28) ; v1(86.71,141.82) UV1.P6 ; UV7.N3 61.16,129.49 v1(60.78,129.87) ; UV1.AE27 95.98,125.47 v1(96.32,125.13) ; UV7.A14 51.58,120.67 v1(51.98,120.27) ; UV1.AE7 95.98,141.54 v1(95.63,141.89) 95.23,142.29 UV1.AD6 ; v1(55.19,138.72) 54.78,139.13 UV8.N3 ; UV7.E12 v1(55.19,121.88) ; v1(83.37,56.21) 83.42,56.26 UC1.W41 ; UV7.R1 62.78,131.42 v1(63.05,131.69) ; RPC9.3 108.04,38.1 107.71,38.42 v1(107.53,38.42) ; UV7.E3 v1(55.19,129.08) ; UV8.F10 v1(59.98,144.33) 59.58,144.73 UV8.G10 ; UV1.B22 78.48,129.49 v1(77.92,128.93) ; UV8.H14 v1(58.78,148.43) ; UV7.G5 56.38,127.33 v1(56.38,127.33) ; UC1.C13 99.7,65.06 v1(100.02,64.75) ; v1(55.19,137.02) 54.78,137.43 UV8.N1 ; v1(62.99,148.44) 62.93,148.38 62.93,148.08 UV8.C14 ; UV1.L27 85.06,125.21 v1(85.06,124.97) ; UC1.AW21 94.97,45.46 v1(94.62,45.46) 94.27,45.46 UC1.AW23 ; UV8.L5 56.38,140.73 v1(55.98,141.13) UV8.M5 ; UV7.F10 55.6,123.89 v1(55.98,124.27) 56.36,123.89 UV7.G10 ; UV8.E3 61.18,139.13 v1(60.78,139.53) ; UV8.B10 v1(63.19,145.12) ; UV8.M10 55.58,144.73 v1(55.98,144.33) UV8.L10 ; UC1.AW11 100.67,45.31 100.8,45.44 101.59,45.44 UC1.AW9 101.83,45.32 102.81,45.32 UC1.AW7 ; v1(107.03,49.94) 106.74,49.66 UC1.AL1 106.33,49.8 105.91,49.8 UC1.AL2 ; UV7.B10 v1(52.79,123.48) ; v1(83.11,60.47) 83.29,60.66 UC1.L41 ; v1(78.01,134.38) 78.1,134.29 UV1.B16 ; UC1.AR31 89.74,47.56 v1(90.22,47.08) 90.27,47.03 90.5,47.03 UC1.AU29 ; UC1.AU25 92.76,46.97 v1(92.46,46.97) 92.46,46.97 UC1.AR27 ; UV1.AB32 93.58,122.65 v1(93.47,122.55) ; UV7.A3 v1(51.99,129.08) ; v1(62.38,145.13) UV8.D10 ; v1(52.91,136.91) 53.18,137.19 UV8.R1 ; UV1.E28 79.99,124.69 v1(80.39,125.09) ; UV1.F16 80.78,134.21 v1(81.1,133.89) ; v1(86.71,34.67) 86.15,35.23 RPC12.4 ; UV7.R12 v1(62.38,122.69) ; UV7.N1 61.18,131.45 v1(61.37,131.64) ; UV8.F5 v1(59.97,140.32) ; UV7.C14 v1(52.79,121.08) ; UV7.D10 v1(54.38,123.49)
  BOTTOM w0.3: v1(86.17,54.61) 86.17,54.26 UC1.AC38 ; 92.44,64.86 92.07,64.86 UC1.C27 ; 92.44,64.86 92.77,64.86 UC1.C25 ; 92.44,64.86 v1(92.44,64.88) ; UC1.E38 86.31,64.3 86.36,64.3 86.38,64.28 v1(86.43,64.28) 86.43,64.29 86.45,64.31 86.49,64.31 86.77,64.03 UC1.G37 ; UC1.AN3 104.92,48.71 104.92,49.14 v1(104.94,49.16) 104.94,49.38 105.07,49.51 UC1.AL3 UC1.AL2 ; UC1.G39 85.47,63.06 v1(85.47,63.41) 85.47,63.76 UC1.E39 ; UC1.C19 96.52,64.81 v1(96.78,64.81) 97.12,64.81 UC1.C17 ; UC1.AE3 104.91,53.12 v1(104.91,53.49) 104.91,53.89 UC1.AC3 ; UC1.AN5 103.57,48.96 v1(103.72,49.12) ; UC1.U39 85.47,57.16 v1(85.47,56.81) 85.47,56.46 UC1.W39 ; UC1.L39 85.47,60.86 v1(85.47,61.21) 85.47,61.56 UC1.J39 ; v1(103.24,50.2) 103.24,50.43 UC1.AJ5 ; v1(90.97,122.83) 90.64,122.83 UV1.V32 ; v1(102.49,51.35) 102.49,51.58 UC1.AG7 102.82,51.86 v1(103.37,52.41) 103.57,52.61 UC1.AE5 ; UC1.W3 104.93,56.12 104.93,55.93 104.92,55.92 104.92,55.74 v1(104.91,55.73) 104.92,55.71 104.92,55.5 104.93,55.49 104.93,55.3 UC1.AA3 UC1.AA2 ; UC1.AN39 85.47,48.36 v1(85.47,48.01) 85.47,47.66 UC1.AR39 ; UC1.R13 99.19,58.18 100.15,58.18 UC1.R11 ; UC1.C3 104.84,64.83 v1(104.57,64.83) 104.2,64.83 UC1.C5 ; UC1.B13 UC1.C13 99.34,64.83 98.7,64.83 UC1.C15 ; UC1.AJ39 85.47,50.56 v1(85.47,50.24) 85.47,49.86 UC1.AL39 ; UC1.AU3 104.87,46.56 v1(104.87,46.91) 104.87,47.26 UC1.AR3 ; UC1.C37 86.03,64.72 v1(85.97,64.72) 85.88,64.72 85.54,65.06 UC1.C39 ; UC1.U10 101.17,57.44 v1(100.75,57.86) ; UC1.AW3 104.51,45.82 103.91,45.82 ; UC1.C11 100.86,64.87 101.41,64.87 101.6,65.06 UC1.C9 101.97,64.86 v1(102.32,64.86) 102.67,64.86 UC1.C7 ; UC1.E35 87.62,63.56 87.93,63.26 v1(87.97,63.26) UC1.G35 ; UC1.AA39 85.47,54.96 v1(85.47,54.61) 85.47,54.26 UC1.AC39 ; UC1.AW39 v1(85.67,45.66) ; v1(85.67,45.66) 85.97,45.66 UC1.AW37 ; v1(85.67,45.66) 85.67,45.77 85.27,46.17 UC1.AU39 ; UC1.AW5 103.83,45.26 103.7,45.39 v1(103.51,45.39) 103.49,45.39 103.45,45.44 103.05,45.44 UC1.AW7 ; UC1.C33 88.45,64.94 88.07,64.94 v1(88.02,64.89) 87.97,64.94 87.59,64.94 UC1.C35 ; UC1.C29 90.5,64.79 90.29,64.79 90.21,64.86 v1(90.21,64.88) 90.19,64.88 90.09,64.79 89.94,64.79 UC1.C31 ; UC1.C23 94.26,64.87 v1(94.62,64.87) 94.98,64.87 UC1.C21 ; UC1.G3 104.92,62.71 104.92,62.32 v1(104.91,62.3) 104.92,62.28 104.92,61.9 UC1.J3 104.87,61.57 v1(104.87,61.24) 104.87,60.86 UC1.L3 104.87,60.46 v1(104.87,60.13) 104.87,59.76 UC1.N3 ; v1(83.59,142.77) 83.61,142.74 83.61,142.62 83.95,142.29 UV1.K6 ; UC1.AG3 104.92,51.71 104.92,51.32 v1(104.91,51.3) 104.91,50.92 UC1.AJ3 ; UC1.AE39 85.47,52.76 v1(85.47,52.41) 85.47,52.06 UC1.AG39 ; UC1.AL7 102.49,49.38 v1(102.49,49.19) ; UC1.R39 85.47,58.66 v1(85.47,59.01) 85.47,59.36 UC1.N39 ; UC1.R3 104.92,58.31 v1(104.92,57.92) ; v1(95.69,63.35) 95.7,63.35 95.49,63.56 UC1.E21 ; v1(98.13,138.58) 98.13,138.84 UV1.AH10 ; UC1.G31 89.67,62.84 89.16,63.35 v1(89.09,63.35)
  BOTTOM w0.305: UV1.W25 91.06,127.09 v1(91.51,126.64) 91.96,127.09 UV1.Y25 ; v1(92.75,126.44) 92.75,127.26 UV1.AB24 ; v1(158.37,59.34) 156.92,59.34 156.57,58.99 JKB1.32 ; UV1.U27 v1(89.11,125.96) ; JODD2.4 183.5,55.7 183.26,55.47 183.25,55.47 ; v1(106.2,42.05) 109.86,38.4 109.86,37.2 110.4,36.66 CC11.2 ; v1(83.39,138.63) 83.44,138.63 UV1.K11 ; UC1.AW33 88.4,45.43 v1(88.05,45.43) 87.64,45.43 UC1.AW35 ; v1(91.55,125.11) 91.18,125.48 UV1.W27 ; UC1.AA5 103.91,54.82 v1(103.91,54.64) ; v1(183.11,55.47) 183.25,55.47 ; 183.25,55.47 183.51,55.2 JODD2.3 ; v1(164.49,38.56) 164.62,38.43 JWLAN1.7 ; UV1.AG12 98.13,138.04 v1(98.13,138.58) ; v1(51.18,122.67) 51.56,122.29 UV7.A12 ; v1(87.98,124.96) UV1.R27 ; UV7.C12 v1(52.78,122.69) ; v1(54.79,148.5) 54.78,148.49 UV8.N14 ; v1(52.79,123.48) UV7.C11 ; JWLAN1.45 174.12,38.41 v1(173.92,38.62) ; UV7.R3 v1(62.38,129.89) ; JWLAN1.69 180.12,36.61 179.8,36.28 v1(179.56,36.28) ; JWLAN1.33 171.12,36.58 v1(171.35,36.35) ; UV1.AE14 96.04,135.75 v1(96.04,136.29) ; 103.91,45.82 103.73,46 v1(103.53,46) ; JHDD1.10 v1(180.88,22.81) ; v1(175.41,38.62) 175.62,38.41 JWLAN1.51 ; UV1.Y10 92.19,139.08 v1(92.75,139.08) 92.77,139.11 93.36,139.11 UV1.AB10 ; UV1.A3 77.67,144.6 77.67,144.61 v1(77.67,144.61) ; JWLAN1.39 v1(172.62,38.57) ; JWLAN1.18 167.37,43.62 v1(166.86,43.11) ; v1(108.36,64.69) 108.36,65.31 109.31,66.26 111.04,66.26 CC15.2 111.6,66.45 v1(111.98,66.83) 112.07,66.92 115.29,66.92 115.56,66.65 v1(115.56,64.74) 115.56,62.79 115.34,62.58 v1(112.23,62.58) ; UV1.U9 89.82,139.89 v1(90.25,140.32) ; v1(177.32,39.39) 177.32,38.38 177.12,38.18 JWLAN1.57 ; v1(77.6,142.74) 77.72,142.62 78.46,142.62 UV1.B6 ; JHDD1.7 v1(180.88,21.31) ; UC1.AC7 102.77,53.55 v1(102.81,53.51) ; UV1.AC27 v1(93.98,125.89) ; JTP1.3 174.52,19.09 174.3,19.3 173.8,19.3 v1(173.76,19.27) ; UC1.H23 UC1.G23 ; v1(94.76,139.51) UV1.AC9 ; JWLAN1.75 v1(181.62,38.71) ; JWLAN1.63 v1(178.62,36.28) ; UV7.U3 v1(63.98,129.89) ; JWLAN1.1 163.12,38.45 v1(163.22,38.56) ; UV1.AC26 94.1,126.57 v1(93.91,126.57)
  BOTTOM w0.33: UV1.F14 80.54,136.13 v1(80.32,136.13) ; UV1.F22 80.65,129.62 80.14,129.62 80.14,129.65 v1(80.11,129.65) ; UV1.F6 80.64,142.43 v1(80.64,142.81) ; v1(94.07,43.06) UC1.BA23 ; v1(82.71,141.08) 83.12,141.49 UV1.J7 UV1.H6 ; v1(96.27,43.18) UC1.BA19 ; UV1.B20 78.75,131.09 78.72,131.06 78.36,131.06 v1(78.28,130.98) ; UV1.C1 78.77,144.69 v1(78.61,144.85) ; v1(83.53,129.21) 83.53,129.24 UV1.K22 ; v1(94.64,67.15) 94.07,66.58 UC1.A23 ; UC1.A2 105.87,66.92 v1(105.77,67.02) ; UC1.C41 83.48,65.11 v1(83.35,65.23) ; UC1.BA39 85.22,43.39 v1(85.1,43.28) ; v1(84.97,66.97) 85.22,66.71 UC1.A39 85.09,66.33 85.09,65.94 UC1.B39 ; UC1.AY1 106.9,44.03 v1(106.9,43.8) ; v1(83.35,45.09) 83.47,45.21 UC1.AW41 ; v1(87.47,43.34) UC1.BA35 ; v1(83.08,47.44) 83.1,47.46 UC1.AR41 ; v1(77.66,123.82) 77.73,123.89 UV1.A30 ; v1(78.79,122.61) 78.79,122.7 UV1.C32 ; 83.23,122.95 v1(83.27,122.91) ; v1(80.32,130.95) 80.36,130.95 80.5,131.09 UV1.F20 ; v1(78.12,136.02) 78.17,135.97 78.7,135.97 UV1.B14 ; v1(78.07,125.95) 78.18,125.95 78.19,125.96 78.45,125.96 UV1.B26 ; UC1.AL41 83.04,49.66 v1(82.81,49.43) ; v1(83.02,51.64) 83.02,51.64 83.24,51.86 UC1.AG41 ; v1(87.47,67.26) UC1.A35
  BOTTOM w0.35: UC1.G13 99.77,62.56 v1(100.12,62.56)
  BOTTOM w0.356: CL2.2 29.42,134.87 CL20.2 ; CC8.1 v1(112.26,49.04) ; UV1.W26 90.71,126.01 v1(90.38,126.01) ; v1(94.55,62.4) 94.43,62.4 UC1.G23 ; v1(91.95,137.83) 92.12,137.83 UV1.AA11 ; v1(88.02,126.57) 87.9,126.57 UV1.P25 UV1.N25 ; v1(80.42,31.91) 80.42,31.62 CC10.2 ; UV1.U25 90.21,126.66 v1(90.21,126.66) ; v1(92.02,130.98) 92.02,131.05 UV1.Y20 ; CV387.2 48.38,146.14 v1(48.38,146.46) 48.38,146.78 CV386.2 48.38,147.29 v1(48.38,147.57) 48.38,147.86 CV187.2 ; CL10.2 v1(36.48,139.62) ; v1(89.18,126.71) 88.96,126.71 UV1.T25 ; CC14.2 v1(93.84,23.39)
  BOTTOM w0.381: CV391.2 58.57,151.9 v1(58.26,152.22) ; v1(158.53,48.29) 158.59,48.35 158.59,48.37 158.08,48.87 PC807.2 ; v1(32.26,131.45) 32.29,131.48 CL5.2 ; v1(112.23,62.58) 111.97,62.58 CC16.2 110.95,62.95 110.52,62.51 108.68,62.51 v1(108.36,62.83) ; PC1008.2 49.55,108.34 v1(49.13,107.92) ; CL7.2 37.71,134.49 v1(37.73,134.46) ; v1(58.24,101.96) 58.38,102.1 PC1016.2 ; RC17.2 96.36,71.53 v1(96.04,71.85) 96.04,72.34 CC114.1 ; UV1.AC17 94.67,133.57 v1(94.67,133.78) ; UC1.R25 93.17,58.3 v1(93.68,58.8) 94.17,58.31 UC1.R23 ; v1(88.01,139.66) 87.61,139.66 UV1.P9 ; v1(6.44,20.73) 6.53,20.73 6.91,21.11 CA49.2 ; RC38.1 v1(113.06,51.02) ; CL6.2 33.98,139.59 v1(33.53,139.59) ; CV94.2 92.1,120.49 v1(92.17,120.55) ; PR1007.1 49.48,106.55 v1(49.13,106.9) 49.05,106.9 48.67,106.52 PR1023.1 ; v1(81.32,132.67) 81.37,132.72 81.84,132.72 82.38,133.25 UV1.H17 ; PR753.2 153.56,14.37 v1(154.02,14.83) 153.58,15.26 PR727.2 ; v1(112.93,55.11) 112.93,55.55 112.58,55.91 RC159.1 ; UC1.L29 90.95,60.16 v1(90.68,60.43) ; UC24.3 113.45,41.93 v1(113.08,41.56) ; v1(87.45,74.92) 87.45,74.03 CC113.1 ; PC835.2 160.43,46.07 160.84,46.48 v1(160.84,46.5) 160.84,46.55 160.49,46.89 PR834.2 ; PR404.2 v1(160.49,28.54) ; CV392.2 v1(59.69,119.22) ; UC1.W21 95.17,56.09 94.67,55.59 v1(94.67,55.46) 94.17,55.96 UC1.W23 ; v1(2.76,24.5) 2.76,24.15 2.71,24.1 CA52.2 ; RC112.1 111.9,53.71 v1(112.3,53.71) ; CV95.2 v1(86.77,117.89) ; CL8.2 33.62,140.34 v1(33.52,140.24) ; v1(173.76,19.27) 173.47,19.56 C280.2 ; CA51.1 v1(3.43,25.06) ; PC1020.2 v1(53.49,102.01) ; RV4.2 103.8,125.18 UV2.3 ; RC49.1 105.63,33.81 v1(105.31,33.49) 105.12,33.49 104.8,33.81 RC54.2 ; 18.7,60.62 v1(17.43,60.62) ; v1(83.06,148.35) 83.06,148.46 82.31,149.2 RV369.2 ; UC22.3 78.92,90.74 79.12,90.74 v1(79.72,90.14) ; CL4.2 34.43,132 v1(34.97,131.46) ; v1(86.87,149.51) 86.87,149.15 87.26,148.76 RV151.1 ; RC78.2 91.71,38.66 v1(92.08,39.03) ; PC819.2 v1(158.33,39.46) ; UC1.L19 UC1.L21 ; PC1010.2 v1(61.24,105.63) ; 18.7,80.29 v1(17.55,80.29) ; UC1.G27 91.87,62.77 91.45,63.19 91.34,63.5 v1(91.34,63.5) 91.34,63.5 91.28,63.56 UC1.E29 ; RC52.2 105.63,36.63 v1(105.22,36.23) 104.8,36.64 RC53.2 ; CA48.2 v1(3.46,26.66) ; PC837.2 91.33,77.13 v1(91.53,76.93) ; RV21.1 v1(89.69,149.38) ; PC811.1 v1(152.75,37.24)
  BOTTOM w0.4: v1(100.12,62.56) 100.47,62.56 UC1.G11 101.08,62.76 101.08,62.77 v1(102.04,62.77) 102.04,62.69 101.97,62.62 UC1.J8 101.96,61.75 101.96,61 101.97,60.99 UC1.L8 ; v1(101.04,54.61) 100.62,54.61 UC1.AC11 99.67,53.66 v1(99.43,53.66) 99.17,53.92 UC1.AC13 UC1.AC15 97.71,53.7 97.71,53.62 ; v1(101.04,54.61) 101.04,54.19 UC1.AC10 101.02,53.91 101.02,53.49 ; v1(101.04,54.61) 101.04,55.03 UC1.AA10 ; UC1.W23 UC1.W25 UC1.W27 91.64,55.63 v1(91.64,55.49) 91.17,55.96 UC1.W29 UC1.W31 90.04,56.03 90.04,55.73 89.98,55.67 v1(89.98,55.66) ; 95.67,51.65 v1(95.67,51.4) ; 95.67,51.65 UC1.AG19 ; 95.67,51.65 95.67,51.66 UC1.AG21 94.67,51.66 ; 97.71,53.62 UC1.AC17 UC1.AC19 UC1.AC21 94.67,53.66 ; 97.71,53.62 v1(97.71,53.48) ; 101.02,53.49 100.98,53.46 100.98,53.14 UC1.AE10 UC1.AG10 101,51.69 v1(101,51.32) 101,50.93 UC1.AJ10 100.55,50.76 v1(100.46,50.67) 101.17,49.96 UC1.AL10 ; 101.02,53.49 v1(101.02,53.49) ; 94.67,51.66 UC1.AG23 UC1.AG25 UC1.AG27 92.17,52.07 v1(91.74,51.64) 91.72,51.62 ; 94.67,51.66 v1(94.67,51.42) ; UC1.L21 94.68,59.67 94.68,59.65 ; UC1.E25 93.07,63.46 v1(93.54,63.46) ; UC1.L13 99.51,60.5 v1(99.62,60.5) ; UC1.W21 UC1.W19 UC1.W17 97.68,55.65 ; 98.67,51.92 v1(98.67,51.35) ; 98.67,51.92 98.43,52.16 UC1.AG15 97.71,51.7 97.71,51.62 ; 98.67,51.92 98.91,52.16 UC1.AG13 v1(99.43,51.66) 99.67,51.66 UC1.AG11 ; UC1.AU9 v1(101.3,47.23) 100.97,47.56 UC1.AR11 ; UC1.R11 100.47,57.86 v1(100.75,57.86) ; 94.68,59.65 v1(94.68,59.46) ; 94.68,59.65 UC1.L23 UC1.L25 UC1.L27 UC1.L29 ; 91.72,51.62 91.18,52.16 UC1.AG29 UC1.AG31 v1(89.9,51.66) 90.17,51.39 UC1.AJ31 90.17,51.02 89.66,50.51 89.66,50.51 89.55,50.4 v1(89.55,50.37) 89.55,50.33 89.68,50.2 90.13,50.2 UC1.AL31 90.17,49.95 89.67,49.45 UC1.AM31 89.77,49.16 89.93,49.32 90.45,49.32 90.52,49.25 90.68,49.25 UC1.AM29 UC1.AM27 91.93,49.16 91.96,49.19 91.98,49.19 92.5,49.71 v1(92.62,49.71) 92.62,49.51 UC1.AM25 ; 91.72,51.62 91.26,51.16 UC1.AJ29 91.17,51 v1(90.65,50.48) ; v1(89.69,58.61) 89.69,58.56 90.09,58.16 UC1.R31 90.62,57.71 90.62,57.61 ; UC1.AG19 96.67,51.66 v1(96.67,51.36) ; UC1.AG19 UC1.AG17 97.71,51.62 ; 97.69,57.64 v1(97.69,57.46) ; 97.69,57.64 97.69,57.68 UC1.R15 UC1.R13 ; 97.69,57.64 UC1.R17 UC1.R19 UC1.R21 94.65,57.65 ; v1(89.7,53.65) 89.7,53.76 90.1,54.16 UC1.AC31 UC1.AC29 91.64,53.69 91.64,53.63 ; 90.62,57.61 UC1.R29 UC1.R27 UC1.R25 ; 90.62,57.61 v1(90.62,57.47) ; v1(90.68,60.43) 90.41,60.16 UC1.L31 ; 97.71,51.62 v1(97.71,51.5) ; UC1.R23 94.65,57.68 94.65,57.65 ; 94.67,53.66 UC1.AC23 UC1.AC25 UC1.AC27 91.64,53.63 ; 94.67,53.66 v1(94.67,53.52) ; v1(97.68,55.44) 97.68,55.65 ; 97.68,55.65 97.68,55.67 UC1.W15 UC1.W13 99.17,55.94 v1(99.44,55.67) 99.68,55.67 UC1.W11 v1(100.8,56.79) 101.17,56.42 UC1.W10 ; 94.65,57.65 v1(94.65,57.46) ; 91.64,53.63 v1(91.64,53.53)
  BOTTOM w0.457: v1(104.04,122.61) 104.24,122.41 YV2.4 ; RL9.1 38.08,134.12 v1(37.73,134.46) ; YV2.2 v1(105.24,119.67) ; RV3153.2 99.24,36.56 v1(99.24,35.15) ; PC11217.2 152.8,26.07 v1(152.8,25.62) ; JEDP1.17 30.87,142.39 v1(31.23,142.03) ; RC94.1 CC13.2 88.79,36.17 v1(88.67,36.29) ; QC22.4 146.76,26.72 146.6,26.88 v1(146.26,26.88) ; CC9.2 84.93,30.05 UC23.3 ; C2151.2 87.71,30.99 v1(89.58,32.86) ; v1(111.51,36.66) CC11.2 ; PC751.2 153.82,13.42 v1(154.19,13.05) 153.67,12.53 PC752.2 ; CV17.2 103.33,119.73 v1(103.91,119.73) ; v1(17.05,14.51) 16.72,14.84 RA43.1 ; v1(147.98,42.26) 148.57,41.67 PC801.2 ; v1(91.96,28.72) 90.93,29.75 C2150.2 ; v1(105.57,122.78) CV18.2 ; v1(64.79,21.06) PC601.2 PR601.2 ; RC80.2 93.06,33.82 v1(93.47,33.41) 93.88,33.82 RC76.2
  BOTTOM w0.508: PC1032.1 PC1013.1 PC1014.1 v1(52.63,114.6) ; PC502.2 v1(41.7,101.63) ; PR752.2 v1(150.78,11.42) ; RV16.2 104.84,129.48 RV163.2 104.87,129.82 v1(105.16,130.12) ; PQ711.3 v1(121.39,12.29) ; CL14.1 38.56,134.71 v1(39.44,134.71) ; YL1.4 39.53,137.25 v1(39.14,137.63) 38.56,137.63 CL13.1 ; v1(107.38,96.45) 106.97,96.86 C371.1 ; PR732.2 PC715.2 v1(152.36,20.57) ; RV379.2 57.81,151.77 v1(58.26,152.22) ; JWLAN1.77 182.72,38.81 182.18,39.34 v1(181.62,39.34) ; PC831.2 153.56,50.69 v1(153.77,50.91) ; PC419.2 v1(170.54,20.87) ; JRTC1.2 5.87,18.95 5.51,18.59 v1(4.6,18.59) ; RV121.2 v1(59.46,152.22) ; PR757.2 145.52,14.18 v1(145.99,14.65) ; v1(92.42,70.58) 92.42,71.14 PC836.2 ; J2.1 160.07,56.74 v1(160.88,55.93) ; v1(84.62,29.31) 84.69,29.31 CC9.2 ; 28.35,108.93 v1(29.02,108.93) ; DL1.2 v1(35.14,127.86) ; 28.35,106.39 v1(29.02,106.39) ; v1(141.15,16.32) 141.68,16.32 PC768.2 ; v1(145.74,33.69) PC11214.2 PR1459.2 ; v1(147.03,29.81) 147.47,30.26 PU903.2 ; DA8.1 21.05,40.81 v1(21.62,41.37) ; 28.35,110.2 v1(29.02,110.2) ; v1(102.61,125.18) RV4.2 ; RV119.2 v1(50.19,141.5) ; v1(100.9,129.49) 102.7,131.28 CV123.2 ; RL5.1 v1(10.63,138.78) ; C282.2 184.8,15.02 v1(185.19,15.02) ; v1(49.85,110.2) 50.36,109.69 PC1047.2 ; JFAN1.6 103.56,95.28 v1(104.89,93.95) ; PC202.2 v1(114.4,29.23) ; 28.35,105.12 v1(29.02,105.12) ; 28.35,103.85 v1(29.02,103.85) ; PC420.2 162.78,16.92 v1(163.29,17.43) ; RL7.1 v1(10.31,114.14) ; PC1043.2 v1(61.75,107.98) ; PC11215.1 145.3,28.08 v1(144.68,27.46) 144.49,27.27 R944.1 ; C281.2 184.3,11.33 183.99,11.02 v1(183.99,10.7) ; v1(141.02,17.04) 141.35,17.37 PC769.2 ; RV83.2 v1(92.74,149.57) ; PC11216.2 v1(144.12,33.3) ; v1(33.56,125.76) 33.56,125.57 33.7,125.43 CL18.1 ; PR107.2 v1(22.38,16.1) ; RV34.2 v1(92.36,119.73) ; v1(183.54,12.1) 182.55,13.09 D281.1 ; JEDP1.32 v1(36.74,148.11) ; PC508.1 40.79,115.22 v1(41.37,114.65) ; CV381.2 v1(48.1,150.46) ; PC757.1 v1(143.75,14.84) ; v1(40.22,134.71) 40.53,135.02 YL1.2 ; DL2.2 v1(35.14,122.08) ; JFAN1.1 101.32,88.98 101.71,88.6 102.18,88.6 102.19,88.6 v1(102.57,88.6) ; PR755.2 v1(149.06,11.42) ; PC409.2 v1(162.84,11.02) ; D1.1 v1(4.35,35.97) ; RC39.1 RC86.2 CC162.1 115.09,50.83 v1(115.22,50.7) ; PC407.2 154.65,14.44 v1(154.65,14.83) ; PR751.2 142.6,12.29 v1(142.41,12.48) PQ741.3 ; JFAN1.5 103.17,87.99 v1(103.17,87.99) ; RV117.2 v1(58.91,134.38) ; D305.2 v1(19.65,81.95) ; v1(35.14,142.02) 35.71,141.44 C216.1 ; JRTC1.3 2.82,16.25 v1(2.82,14.83) ; RL6.1 v1(9.49,114.14) ; v1(34.76,44.95) 34.76,45.42 33.97,46.21 31.3,46.21 30.95,46.57 v1(30.95,46.98) ; RA60.1 v1(3.72,29.09) ; UC2.4 v1(98.88,17.44) ; PC1002.2 56.67,113.19 v1(56.67,113.7) ; v1(49.85,112.83) 50.66,112.02 PC11227.1 ; v1(29.42,133.77) CL20.2 ; RA66.1 v1(3.7,28.22) ; PC1021.2 v1(62.45,111.54) ; PC201.2 v1(111.25,31.44) ; JWLAN1.76 161.2,38.21 160.88,37.89 v1(160.43,37.89) ; 77.11,56.23 77.11,55.34 77.09,55.34 77.09,55.12 76.58,54.61 v1(76.35,54.61) ; CLRP1.2 v1(112.3,32.31) ; JEDP1.5 v1(24.87,142.33) ; v1(105.16,130.85) 104.56,130.85 CV15.2 ; RV116.2 v1(59.59,133.44) ; RL4.1 v1(11.52,138.78) ; PR731.2 v1(154.08,19.68) ; v1(157.6,63.51) 158.11,64.02 JKB1.34 ; RV35.2 v1(87.47,117.51) ; 28.35,107.66 v1(29.02,107.66) ; PC827.2 v1(128.92,34.32) ; D302.2 v1(19.08,54.33)
  vias: v1(0.43,114.47) v1(0.43,112.71) v1(0.43,96.34) v1(0.43,94.06) v1(0.9,37.36) v1(0.9,35.74) v1(0.9,33.2) v1(0.9,30.66) v1(0.9,28.12) v1(0.9,25.58) v1(0.9,23.04) v1(0.9,20.5) v1(0.9,17.96) v1(0.9,15.42) v1(0.9,12.88) v1(0.9,10.34) v1(0.9,7.8) v1(0.9,5.26) v1(0.9,2.72) v1(1.74,0.43) v1(2.03,158.39) v1(2.5,32.03) v1(2.6,138.89) v1(2.6,136.35) v1(2.72,1.66) v1(2.82,96.35) v1(3.15,93.54) v1(3.2,20.79) v1(3.4,52.65) v1(3.47,91.46) v1(3.55,75.19) v1(3.54,72.32) v1(3.55,69.27) v1(3.9,162.16) v1(3.88,159.62) v1(3.88,89.59) v1(4.18,112.71) v1(4.28,0.43) v1(5.5,163.43) v1(5.48,96.35) v1(5.68,92.68) v1(5.97,2.02) v1(6.31,94.65) v1(6.47,0.49) v1(6.72,112.71) v1(7.65,72.23) v1(8.04,163.43) v1(8.02,96.35) v1(8.32,26.42) v1(8.32,24.84) v1(8.32,23.27) v1(8.67,2.43) v1(8.88,153.54) v1(8.95,145.28) v1(9.26,112.71) v1(9.29,75.2) v1(9.29,69.26) v1(9.54,161.83) v1(9.6,89.56) v1(9.59,54.9) v1(9.65,159.29) v1(9.9,26.42) v1(9.9,24.84) v1(9.9,23.27) v1(9.87,0.44) v1(10,98.1) v1(10.26,72.28) v1(11.47,26.42) v1(11.47,24.84) v1(11.47,23.27) v1(11.71,17.45) v1(11.7,16.86) v1(11.78,158.43) v1(12.28,16.86) v1(12.41,95.28) v1(12.39,92.78) v1(12.41,52.86) v1(12.41,0.43) v1(12.92,107.92) v1(12.98,105.95) v1(12.98,104.23) v1(13.38,146.09) v1(14.06,102.27) v1(14.19,106.52) v1(14.32,158.43) v1(14.32,99.22) v1(14.7,95.28) v1(14.67,92.78) v1(14.82,107.92) v1(15.01,22.32) v1(15.01,21.68) v1(14.95,0.43) v1(15.06,104.17) v1(15.08,100.83) v1(15.33,57.12) v1(15.78,88.61) v1(15.97,55.34) v1(16.22,109.69) v1(16.22,105.88) v1(16.22,102.52) v1(16.22,99.22) v1(16.86,158.43) v1(17.17,87.99) v1(17.17,57.38) v1(17.17,55.6) v1(17.24,53.94) v1(17.49,0.43) v1(17.9,65.14) v1(18,22.26) v1(19.08,110.75) v1(19.4,158.43) v1(19.33,75.34) v1(19.33,74.71) v1(19.33,74.07) v1(19.97,102.52) v1(19.97,99.15) v1(20.03,0.44) v1(20.28,105.76) v1(20.3,80.03) v1(20.35,104.17) v1(20.35,100.8) v1(20.35,65.88) v1(20.47,15.4) v1(20.47,14.76) v1(20.79,110.46) v1(21.5,116.13) v1(21.91,2.43) v1(21.94,158.43) v1(22.05,147.85) v1(22.05,147.21) v1(22.11,143.67) v1(22.11,143.07) v1(22.08,102.46) v1(22.1,99.15) v1(22.04,10.44) v1(22.04,9.86) v1(22.24,146.58) v1(22.24,145.94) v1(22.24,145.31) v1(22.32,111.98) v1(22.46,104.16) v1(22.51,100.78) v1(22.7,19.46) v1(22.77,148.1) v1(22.76,112.74) v1(22.76,83.34) v1(22.76,81.95) v1(22.76,80.17) v1(22.77,78.34) v1(22.91,62.21) v1(22.92,60.43) v1(23.14,84.99) v1(23.14,19.02) v1(24.09,59.84) v1(24.09,58.06) v1(24.31,13.49) v1(24.48,158.43) v1(24.45,2.43) v1(24.88,50.2) v1(24.88,49.56) v1(24.88,48.93) v1(24.88,46.64) v1(24.88,46) v1(24.95,107.03) v1(25.36,150.83) v1(25.67,11.22) v1(25.67,9.42) v1(26.43,14.7) v1(26.57,10.32) v1(26.72,102.71) v1(26.76,59.97) v1(26.76,58.7) v1(26.76,55.47) v1(26.76,54.13) v1(26.76,13.89) v1(27.02,158.43) v1(26.99,2.43) v1(27.47,11.22) v1(27.47,9.42) v1(27.59,89.04) v1(27.59,88.04) v1(27.59,87.04) v1(27.59,86.04) v1(27.59,85.04) v1(27.59,84.04) v1(27.59,83.04) v1(27.59,82.04) v1(27.59,80.54) v1(27.59,79.54) v1(27.59,78.54) v1(27.59,77.54) v1(27.59,76.54) v1(27.59,75.54) v1(27.59,74.54) v1(27.59,73.54) v1(27.59,72.54) v1(27.59,71.54) v1(27.59,70.04) v1(27.59,69.04) v1(27.59,68.04) v1(27.59,67.04) v1(27.59,66.04) v1(27.59,65.04) v1(27.59,64.04) v1(27.59,63.04) v1(27.59,45.18) v1(27.59,44.54) v1(27.59,43.54) v1(27.59,42.54) v1(27.59,41.54) v1(27.59,40.54) v1(27.59,39.54) v1(27.59,38.54) v1(27.59,37.03) v1(27.59,36.03) v1(27.59,35.03) v1(27.59,34.03) v1(27.59,33.03) v1(27.59,32.03) v1(27.59,31.03) v1(27.59,30.03) v1(27.59,29.03) v1(27.59,28.03) v1(27.59,26.54) v1(27.82,135.92) v1(28.29,145.51) v1(28.46,137.18) v1(28.58,140.38) v1(28.67,148.43) v1(29.56,158.43) v1(29.53,2.43) v1(30.18,44.95) v1(30.18,41.9) v1(30.18,39.87) v1(30.18,36.82) v1(30.18,34.16) v1(30.18,31.11) v1(30.18,28.82) v1(30.18,25.77) v1(30.13,14.25) v1(30.28,88.19) v1(30.25,35.2) v1(30.32,22.06) v1(30.38,133.06) v1(30.4,85.58) v1(30.32,83.29) v1(30.4,80.24) v1(30.4,77.96) v1(30.4,74.91) v1(30.4,72.62) v1(30.4,71.1) v1(30.4,69.57) v1(30.45,84.31) v1(30.44,38.35) v1(30.56,76.43) v1(30.65,67.92) v1(30.65,66.62) v1(30.69,43.43) v1(30.69,32.63) v1(30.76,14.25) v1(30.91,87.35) v1(30.91,81.77) v1(31.08,115.73) v1(31.03,88.88) v1(31.2,86.26) v1(31.16,71.1) v1(31.2,27.3) v1(31.41,67.92) v1(31.57,0.43) v1(31.65,114.97) v1(31.71,44.95) v1(31.71,41.9) v1(31.71,39.87) v1(31.71,36.82) v1(31.71,34.16) v1(31.71,31.11) v1(31.71,28.82) v1(31.71,25.77) v1(31.65,11.24) v1(31.65,9.43) v1(31.78,22.45) v1(31.85,83.29) v1(31.92,85.58) v1(31.92,80.24) v1(31.92,77.96) v1(31.92,74.91) v1(31.92,72.62) v1(31.92,69.57) v1(32.1,158.43) v1(32.09,76.43) v1(32.18,67.92) v1(32.22,43.43) v1(32.22,32.63) v1(32.29,114.97) v1(32.26,9.43) v1(32.43,87.35) v1(32.6,151.54) v1(32.6,150.91) v1(32.56,88.88) v1(32.63,137.1) v1(32.63,135.98) v1(32.63,134.87) v1(32.72,38.35) v1(32.85,76.43) v1(32.94,67.92) v1(32.98,43.43) v1(32.98,32.63) v1(33.19,87.35) v1(33.19,81.77) v1(33.23,44.95) v1(33.23,41.9) v1(33.23,39.87) v1(33.23,36.82) v1(33.23,34.16) v1(33.23,31.11) v1(33.23,28.82) v1(33.23,25.77) v1(33.37,83.29) v1(33.52,131.3) v1(33.45,85.58) v1(33.45,80.24) v1(33.45,77.96) v1(33.45,74.91) v1(33.45,72.62) v1(33.45,71.1) v1(33.45,69.57) v1(33.49,38.35) v1(33.7,67.92) v1(33.75,137.1) v1(33.75,135.98) v1(33.75,134.87) v1(33.87,144.88) v1(33.87,22.7) v1(33.95,81.77) v1(34.08,88.88) v1(34.11,0.43) v1(34.2,148.47) v1(34.25,119.35) v1(34.25,38.35) v1(34.25,27.3) v1(34.32,22.19) v1(34.64,159.23) v1(34.76,41.9) v1(34.76,39.87) v1(34.76,36.82) v1(34.76,34.16) v1(34.76,31.11) v1(34.76,28.82) v1(34.76,25.77) v1(34.86,137.1) v1(34.86,135.98) v1(34.86,134.87) v1(34.89,83.29) v1(34.97,85.58) v1(34.97,80.24) v1(34.97,77.96) v1(34.97,74.91) v1(34.97,72.62) v1(34.97,71.1) v1(34.97,69.57) v1(35.14,76.43) v1(35.22,67.92) v1(35.24,66.47) v1(35.22,64.88) v1(35.26,43.43) v1(35.26,32.63) v1(35.48,87.35) v1(35.61,88.88) v1(35.73,71.1) v1(35.97,114.71) v1(36.06,125.06) v1(36.41,14.38) v1(36.41,13.3) v1(36.59,115.33) v1(36.59,114.09) v1(36.71,131.41) v1(36.65,0.43) v1(37.18,159.23) v1(37.21,114.71) v1(37.91,2.56) v1(38.41,79.87) v1(38.35,43.43) v1(38.46,131.59) v1(38.48,39.02) v1(38.48,37.32) v1(38.51,31) v1(38.54,77.72) v1(38.54,76.43) v1(38.6,74.91) v1(38.6,72.57) v1(38.6,69.58) v1(38.6,40.36) v1(38.6,35.42) v1(38.54,32.32) v1(38.79,81.26) v1(38.79,27.92) v1(38.73,26.12) v1(38.9,131.15) v1(38.86,87.3) v1(38.86,84.79) v1(38.86,0.43) v1(39.14,43.4) v1(39.36,26.12) v1(39.49,81.26) v1(39.72,159.23) v1(40.1,105.63) v1(40.1,105) v1(40.16,151.54) v1(40.13,81.26) v1(40.19,3.43) v1(40.48,147.99) v1(40.48,147.35) v1(40.48,146.65) v1(40.54,108.55) v1(40.54,107.92) v1(40.54,107.28) v1(40.54,106.65) v1(40.54,106.01) v1(40.86,109.12) v1(40.92,148.87) v1(41.11,150.65) v1(41.11,150.02) v1(41.11,147.67) v1(41.11,147.03) v1(41.11,146.33) v1(41.18,108.55) v1(41.18,107.92) v1(41.18,107.28) v1(41.18,106.65) v1(41.18,106.01) v1(41.49,109.76) v1(41.49,109.12) v1(41.75,147.67) v1(41.75,147.03) v1(41.75,146.33) v1(41.81,108.55) v1(41.81,107.92) v1(41.81,107.28) v1(41.81,106.65) v1(41.81,106.01) v1(42.26,159.23) v1(43.49,3.43) v1(44.45,146.02) v1(44.8,159.23) v1(45.49,157.03) v1(45.94,100.17) v1(46.13,157.03) v1(46.76,157.03) v1(46.86,146.14) v1(47.14,104.74) v1(47.27,3.43) v1(47.34,159.23) v1(47.43,146.4) v1(47.63,107.08) v1(47.72,89.57) v1(47.72,88.93) v1(47.65,22.57) v1(48.41,0.43) v1(48.61,137) v1(48.61,135.29) v1(48.61,134.33) v1(48.61,133.32) v1(48.61,131.41) v1(48.61,129.76) v1(48.61,128.11) v1(48.61,126.52) v1(48.61,123.35) v1(48.61,121.76) v1(48.61,120.24) v1(49.37,2.56) v1(49.53,110.81) v1(49.88,159.23) v1(50.62,0.43) v1(51.23,13.86) v1(51.23,11.9) v1(52.42,159.23) v1(52.66,12.88) v1(53.11,117.44) v1(53.16,0.43) v1(53.75,116.81) v1(54.08,13.86) v1(54.08,11.9) v1(54.34,117.5) v1(54.9,159.15) v1(55.02,108.57) v1(55.02,106.34) v1(55.7,0.43) v1(56.14,107.45) v1(57.26,108.57) v1(57.26,106.34) v1(57.71,156.84) v1(58.24,0.43) v1(60.78,0.43) v1(61.26,27.1) v1(62.19,101.38) v1(62.89,23.65) v1(62.89,22.38) v1(63.4,103.28) v1(63.4,102.65) v1(63.4,102.01) v1(63.4,101.38) v1(63.32,0.43) v1(63.53,23.65) v1(63.53,22.38) v1(63.63,157.39) v1(64.04,103.92) v1(64.04,103.28) v1(64.04,102.65) v1(64.04,102.01) v1(64.04,101.38) v1(64.67,103.92) v1(64.67,103.28) v1(64.67,102.65) v1(64.67,102.01) v1(64.67,101.38) v1(64.9,23.65) v1(64.9,22.38) v1(65.31,103.92) v1(65.31,103.28) v1(65.31,102.65) v1(65.31,102.01) v1(65.31,101.38) v1(65.41,159.14) v1(65.69,20.99) v1(65.69,20.35) v1(65.88,19.46) v1(65.86,0.43) v1(65.94,103.92) v1(65.94,103.28) v1(65.94,102.65) v1(65.94,102.01) v1(65.94,101.38) v1(66,17.05) v1(66.04,14.67) v1(66.19,21.3) v1(66.19,20.67) v1(66.19,20.03) v1(66.51,19.46) v1(66.47,14.27) v1(66.58,103.92) v1(66.58,103.28) v1(66.58,102.65) v1(66.58,102.01) v1(66.58,101.38) v1(66.83,21.3) v1(66.83,20.67) v1(66.83,20.03) v1(67.25,103.5) v1(67.25,102.89) v1(67.57,104.04) v1(67.66,159.23) v1(68.1,104.68) v1(68.16,104.04) v1(68.4,0.43) v1(68.73,9.71) v1(68.73,6.86) v1(69.31,113.76) v1(69.31,113.12) v1(69.31,112.23) v1(69.31,111.6) v1(69.7,8.29) v1(69.94,113.76) v1(69.94,113.12) v1(69.94,112.23) v1(69.94,111.6) v1(70.2,159.23) v1(70.58,113.76) v1(70.58,113.12) v1(70.68,9.71) v1(70.68,6.86) v1(70.75,27.4) v1(70.94,0.43) v1(71.02,24.29) v1(71.02,22.64) v1(71.27,20.86) v1(71.34,27.4) v1(71.91,20.86) v1(72.39,72.87) v1(72.74,159.23) v1(72.99,44.99) v1(73.18,116.3) v1(73.48,0.43) v1(73.66,72.87) v1(73.81,116.3) v1(73.98,45.06) v1(74.2,19.91) v1(74.2,19.27) v1(74.45,116.3) v1(74.49,72.87) v1(74.62,64.62) v1(75.08,116.3) v1(75.2,44.66) v1(75.28,159.23) v1(75.5,60.62) v1(75.72,116.3) v1(76.02,0.43) v1(76.25,51.72) v1(76.35,116.3) v1(76.33,47.28) v1(76.84,60.62) v1(77.59,51.72) v1(77.82,159.23) v1(78.11,60.62) v1(78.08,49.38) v1(78.55,47.28) v1(78.56,0.43) v1(78.86,58.48) v1(78.96,117.25) v1(79.31,60.62) v1(79.31,53.7) v1(79.25,49.38) v1(79.4,117.7) v1(79.38,51.7) v1(79.44,66.97) v1(79.81,44.55) v1(79.85,118.14) v1(80.36,159.23) v1(80.39,49.38) v1(80.46,60.62) v1(80.46,47.5) v1(80.57,53.63) v1(80.58,51.6) v1(80.76,58.46) v1(80.89,43.72) v1(80.99,152.81) v1(80.97,66.46) v1(81,56.81) v1(81.05,98.84) v1(81.05,98.2) v1(81.1,0.43) v1(81.28,64.49) v1(81.25,41.88) v1(81.55,49.4) v1(81.63,152.81) v1(81.69,98.84) v1(81.69,98.2) v1(81.79,60.62) v1(81.82,53.64) v1(81.79,51.6) v1(81.79,45.95) v1(81.91,47.48) v1(81.98,58.46) v1(82.04,63.48) v1(82.17,56.81) v1(82.27,42.55) v1(82.32,98.84) v1(82.32,98.2) v1(82.62,39.79) v1(82.68,44.62) v1(82.9,159.23) v1(83,69.89) v1(83.12,68.68) v1(83.12,67.48) v1(83.12,43.41) v1(83.47,147.92) v1(83.45,40.67) v1(83.64,0.43) v1(84.27,41.57) v1(85.03,69.51) v1(85.03,68.24) v1(85.28,42.27) v1(85.44,159.23) v1(85.44,156.69) v1(86.15,154.23) v1(86.21,130.03) v1(86.18,0.43) v1(86.28,134.92) v1(86.32,130.93) v1(87.18,136.75) v1(87.24,130.95) v1(87.38,40.93) v1(87.44,42.17) v1(87.65,69.5) v1(88.08,41.57) v1(88.24,137.84) v1(88.31,133.85) v1(88.72,0.43) v1(88.85,68.62) v1(89,152.83) v1(89.18,130.96) v1(89.44,109.92) v1(91.1,136.89) v1(91.04,134.65) v1(91.1,132.88) v1(91.26,0.43) v1(91.39,28.4) v1(91.72,154.14) v1(92.01,129.92) v1(92.07,135.7) v1(92.04,86.77) v1(92.51,159.22) v1(92.5,156.68) v1(92.86,30.38) v1(93.18,134.85) v1(93.5,30.38) v1(93.8,0.43) v1(93.97,31.07) v1(94.82,120.39) v1(95.05,159.2) v1(95.21,74.9) v1(95.28,117.39) v1(95.65,58.87) v1(96.34,0.43) v1(96.45,118.08) v1(97.48,158.38) v1(97.51,69.46) v1(98.1,139.49) v1(98.12,72.23) v1(98.58,39.87) v1(98.78,120.36) v1(98.88,0.43) v1(99.29,72.23) v1(99.58,156.86) v1(99.57,129.79) v1(99.6,129.19) v1(99.85,25.36) v1(100.03,69.74) v1(100.28,23.54) v1(100.81,27.14) v1(100.81,25.97) v1(101.42,0.43) v1(101.64,155.36) v1(102.67,24.37) v1(102.9,79.7) v1(102.92,26.32) v1(103.71,153.86) v1(103.74,23.75) v1(103.96,0.43) v1(104.78,78.87) v1(104.93,77.11) v1(105.53,78.11) v1(105.74,152.32) v1(106.33,125.13) v1(106.33,124.49) v1(106.5,0.43) v1(107,101.72) v1(107.08,59.64) v1(107.14,150.21) v1(107.49,147.67) v1(107.49,145.13) v1(107.49,142.59) v1(107.49,140.05) v1(107.49,137.51) v1(107.49,134.97) v1(107.49,132.43) v1(107.49,129.89) v1(107.49,127.35) v1(107.49,124.81) v1(107.49,122.27) v1(107.49,119.73) v1(107.49,117.19) v1(107.49,114.65) v1(107.49,112.11) v1(107.49,109.57) v1(107.49,107.03) v1(107.62,104.49) v1(107.57,99.7) v1(108.21,57.72) v1(108.41,97.29) v1(109.04,0.43) v1(109.2,57.04) v1(109.31,68.99) v1(109.72,95.05) v1(110.21,47.49) v1(110.68,92.68) v1(110.67,57.32) v1(111.25,46.75) v1(111.58,0.43) v1(111.89,90.24) v1(111.99,58.23) v1(112.08,60.55) v1(113.12,71.09) v1(113.19,88.03) v1(113.26,58.26) v1(114.07,21.49) v1(114.07,20.86) v1(114.07,20.22) v1(114.12,0.43) v1(114.29,69.84) v1(114.7,85.83) v1(114.77,21.49) v1(114.77,20.86) v1(114.77,20.22) v1(115.41,33.43) v1(115.41,32.8) v1(115.47,21.49) v1(115.47,20.86) v1(115.47,20.22) v1(115.81,61.19) v1(116.04,33.43) v1(116.04,32.8) v1(116.17,21.49) v1(116.17,20.86) v1(116.17,20.22) v1(116.32,83.81) v1(116.68,33.43) v1(116.68,32.8) v1(116.66,0.43) v1(117.82,31.84) v1(117.82,31.21) v1(117.82,30.57) v1(118.1,81.9) v1(118.3,57.5) v1(118.9,31.84) v1(118.9,31.21) v1(118.9,30.57) v1(119.2,0.43) v1(119.71,63.19) v1(119.96,80.15) v1(119.98,33.43) v1(119.98,32.8) v1(120.61,33.43) v1(120.61,32.8) v1(121.25,33.43) v1(121.25,32.8) v1(121.74,0.43) v1(121.92,78.55) v1(122.01,67.21) v1(122.01,66.58) v1(122.27,22.26) v1(122.58,67.09) v1(122.58,66.45) v1(122.9,22.26) v1(123.22,66.45) v1(123.28,20.41) v1(123.28,19.08) v1(123.28,18.45) v1(123.28,17.81) v1(123.5,42.83) v1(123.6,34.76) v1(123.98,77.11) v1(124.11,65.18) v1(124.11,42.83) v1(124.2,34.76) v1(124.23,48.48) v1(124.28,0.43) v1(124.55,64.74) v1(124.72,42.83) v1(124.81,34.76) v1(125,64.29) v1(125.12,47.59) v1(125.4,34.76) v1(125.5,63.85) v1(126.08,46.7) v1(126.16,75.79) v1(126.9,45.81) v1(126.82,0.43) v1(127.6,30.7) v1(127.6,30.07) v1(128.09,74.06) v1(128.23,30.7) v1(128.23,30.07) v1(128.71,71.33) v1(128.87,30.7) v1(128.87,30.07) v1(129.36,0.43) v1(129.44,61.82) v1(130.08,61.82) v1(130.94,70.88) v1(131.9,0.43) v1(133.48,70.88) v1(134.44,0.43) v1(134.71,54.01) v1(134.71,53.37) v1(135.35,54.64) v1(135.35,54.01) v1(135.35,53.37) v1(136.02,70.88) v1(136.98,0.43) v1(138.23,18.64) v1(138.41,15.61) v1(138.36,13.53) v1(138.56,70.88) v1(138.58,17.04) v1(138.53,16.2) v1(138.61,15.05) v1(139.09,18.64) v1(139.12,16.22) v1(139.17,17.06) v1(139.52,0.43) v1(139.78,17.06) v1(139.73,16.22) v1(140.01,19.22) v1(140.49,46) v1(140.49,45.37) v1(140.49,44.73) v1(140.49,44.1) v1(140.49,43.46) v1(140.44,2.35) v1(140.72,19.25) v1(141.1,70.88) v1(141.06,42.64) v1(141.06,42) v1(141.12,46) v1(141.12,45.37) v1(141.12,44.73) v1(141.12,44.1) v1(141.12,43.46) v1(141.43,19.22) v1(141.58,4.45) v1(141.7,42.64) v1(141.7,42) v1(141.7,41.37) v1(141.76,46) v1(141.76,45.37) v1(141.76,44.73) v1(141.76,44.1) v1(141.76,43.46) v1(142.17,25.68) v1(142.17,25.05) v1(142.39,46) v1(142.39,45.37) v1(142.39,44.73) v1(142.39,44.1) v1(142.39,43.46) v1(142.33,42.64) v1(142.33,42) v1(142.33,41.37) v1(142.9,26.74) v1(142.9,26.1) v1(142.97,42.64) v1(142.97,42) v1(142.97,41.37) v1(142.97,40.73) v1(142.97,40.1) v1(142.97,39.46) v1(142.97,38.83) v1(142.97,38.19) v1(143.03,46) v1(143.03,45.37) v1(143.03,44.73) v1(143.03,44.1) v1(143.03,43.46) v1(143.6,42.64) v1(143.6,42) v1(143.6,41.37) v1(143.6,40.73) v1(143.6,40.1) v1(143.6,39.46) v1(143.6,38.83) v1(143.6,38.19) v1(143.64,70.88) v1(143.66,46) v1(143.66,45.37) v1(143.66,44.73) v1(143.66,44.1) v1(143.66,43.46) v1(144.12,4.48) v1(144.3,46) v1(144.3,45.37) v1(144.3,44.73) v1(144.3,44.1) v1(144.3,43.46) v1(144.24,42.64) v1(144.24,42) v1(144.24,41.37) v1(144.24,40.73) v1(144.24,40.1) v1(144.24,39.46) v1(144.24,38.83) v1(144.87,42.64) v1(144.87,42) v1(144.87,41.37) v1(144.87,40.73) v1(144.87,40.1) v1(144.87,39.46) v1(144.93,45.37) v1(144.93,44.73) v1(144.93,44.1) v1(144.93,43.46) v1(145.51,42.64) v1(145.51,42) v1(145.51,41.37) v1(145.51,40.73) v1(145.51,40.1) v1(145.57,44.73) v1(145.57,44.1) v1(145.57,43.46) v1(146.18,70.88) v1(146.14,42.64) v1(146.14,42) v1(146.14,41.37) v1(146.14,40.73) v1(146.66,4.48) v1(147.08,18.09) v1(147.08,15.9) v1(148.17,16.99) v1(148.72,70.88) v1(149.2,4.48) v1(149.26,18.09) v1(149.26,15.9) v1(150.95,30.89) v1(151.26,70.88) v1(151.74,4.48) v1(152.75,55.66) v1(153.21,44.58) v1(153.21,43.12) v1(153.21,41.66) v1(153.8,70.88) v1(154.28,4.48) v1(154.33,35.08) v1(154.67,44.58) v1(154.67,43.12) v1(154.67,41.66) v1(156.13,44.58) v1(156.13,43.12) v1(156.13,41.66) v1(156.24,28.06) v1(156.24,27.4) v1(156.34,70.88) v1(156.87,28.06) v1(156.87,27.41) v1(156.87,26.83) v1(156.82,4.48) v1(157.48,27.4) v1(157.48,26.79) v1(158.12,28.06) v1(158.12,27.46) v1(158.12,26.85) v1(158.42,26.34) v1(158.75,28.06) v1(158.75,27.46) v1(158.75,26.85) v1(158.88,70.88) v1(159.01,24) v1(159.08,21.63) v1(159.36,4.48) v1(159.49,21.2) v1(160.87,14.38) v1(160.87,13.75) v1(161.42,70.88) v1(161.9,4.48) v1(162.21,11.02) v1(162.4,14) v1(162.4,13.37) v1(162.45,46.14) v1(162.45,45.51) v1(163.63,34.85) v1(163.96,70.88) v1(164.24,29.37) v1(164.44,4.48) v1(164.84,29.37) v1(165.42,29.37) v1(165.95,29.62) v1(165.95,28.99) v1(165.95,28.35) v1(166.5,70.88) v1(166.59,29.62) v1(166.59,28.99) v1(166.59,28.35) v1(166.98,4.48) v1(167.22,29.62) v1(167.22,28.99) v1(167.22,28.35) v1(167.87,29.34) v1(167.87,28.71) v1(167.87,28.07) v1(167.87,27.44) v1(168.2,24.66) v1(168.26,22.12) v1(168.51,29.34) v1(168.51,28.71) v1(168.51,28.07) v1(168.51,27.44) v1(168.68,21.61) v1(168.91,71.38) v1(168.94,47.05) v1(168.94,46.45) v1(169.52,4.48) v1(170.72,16.79) v1(171.88,74.24) v1(172.06,4.48) v1(174.6,4.48) v1(175.11,72.81) v1(176.02,24.55) v1(176.11,19.58) v1(176.11,18.95) v1(176.23,26.31) v1(176.88,11.46) v1(176.99,71.38) v1(177.18,16.83) v1(177.14,4.48) v1(177.78,16.83) v1(179.53,71.38) v1(179.68,4.48) v1(180.81,61.88) v1(181.13,60.93) v1(181.13,60.1) v1(181.45,8.18) v1(182.07,71.38) v1(182.04,8.18) v1(182.04,7.55) v1(182.22,4.48) v1(184.61,71.38) v1(184.59,24.51) v1(184.76,4.48) v1(185,16.61) v1(186.24,13.66) v1(186.24,11.12) v1(186.24,8.58) v1(186.24,6.04) v1(186.57,70) v1(186.92,30.9) v1(186.92,28.82) v1(187.21,54.48) v1(187.25,59.49) v1(187.23,53.31) v1(187.94,68.34) v1(187.94,65.8) v1(187.94,26.21) v1(187.94,23.67) v1(187.94,21.13) v1(187.94,18.59) v1(187.94,16.05) v1(188.02,33.11) v1(189.44,63.47) v1(189.44,60.93) v1(189.44,58.39) v1(189.44,55.85) v1(189.44,53.31) v1(189.44,50.77) v1(189.44,48.23) v1(189.44,45.69) v1(189.44,43.15) v1(189.44,40.61) v1(189.44,38.07) v1(189.44,35.53) v3(13.1,72.26) v3(14.8,100.34) v3(16.23,72.48) v3(22.29,87.66) v3(22.74,72.19) v3(24.08,102.39) v3(29.68,38.96) v3(31.08,20.66) v3(40.74,73.78) v3(47.49,121.75) v3(61.99,26.28) v3(67.82,157.12) v3(68.42,45.18) v3(69.45,11.56) v3(73.33,69.56) v3(73.74,40.66) v3(79.52,73.89) v3(82.01,153.6) v3(82.01,153.6) v3(82.49,117.75) v3(98.77,152.72) v3(145.67,38.24) v3(157.44,27.97) v3(158.92,25.89) v3(168.11,26.37) v3(168.3,29.88) v3(179.94,69.17) v3(180.79,35.1)
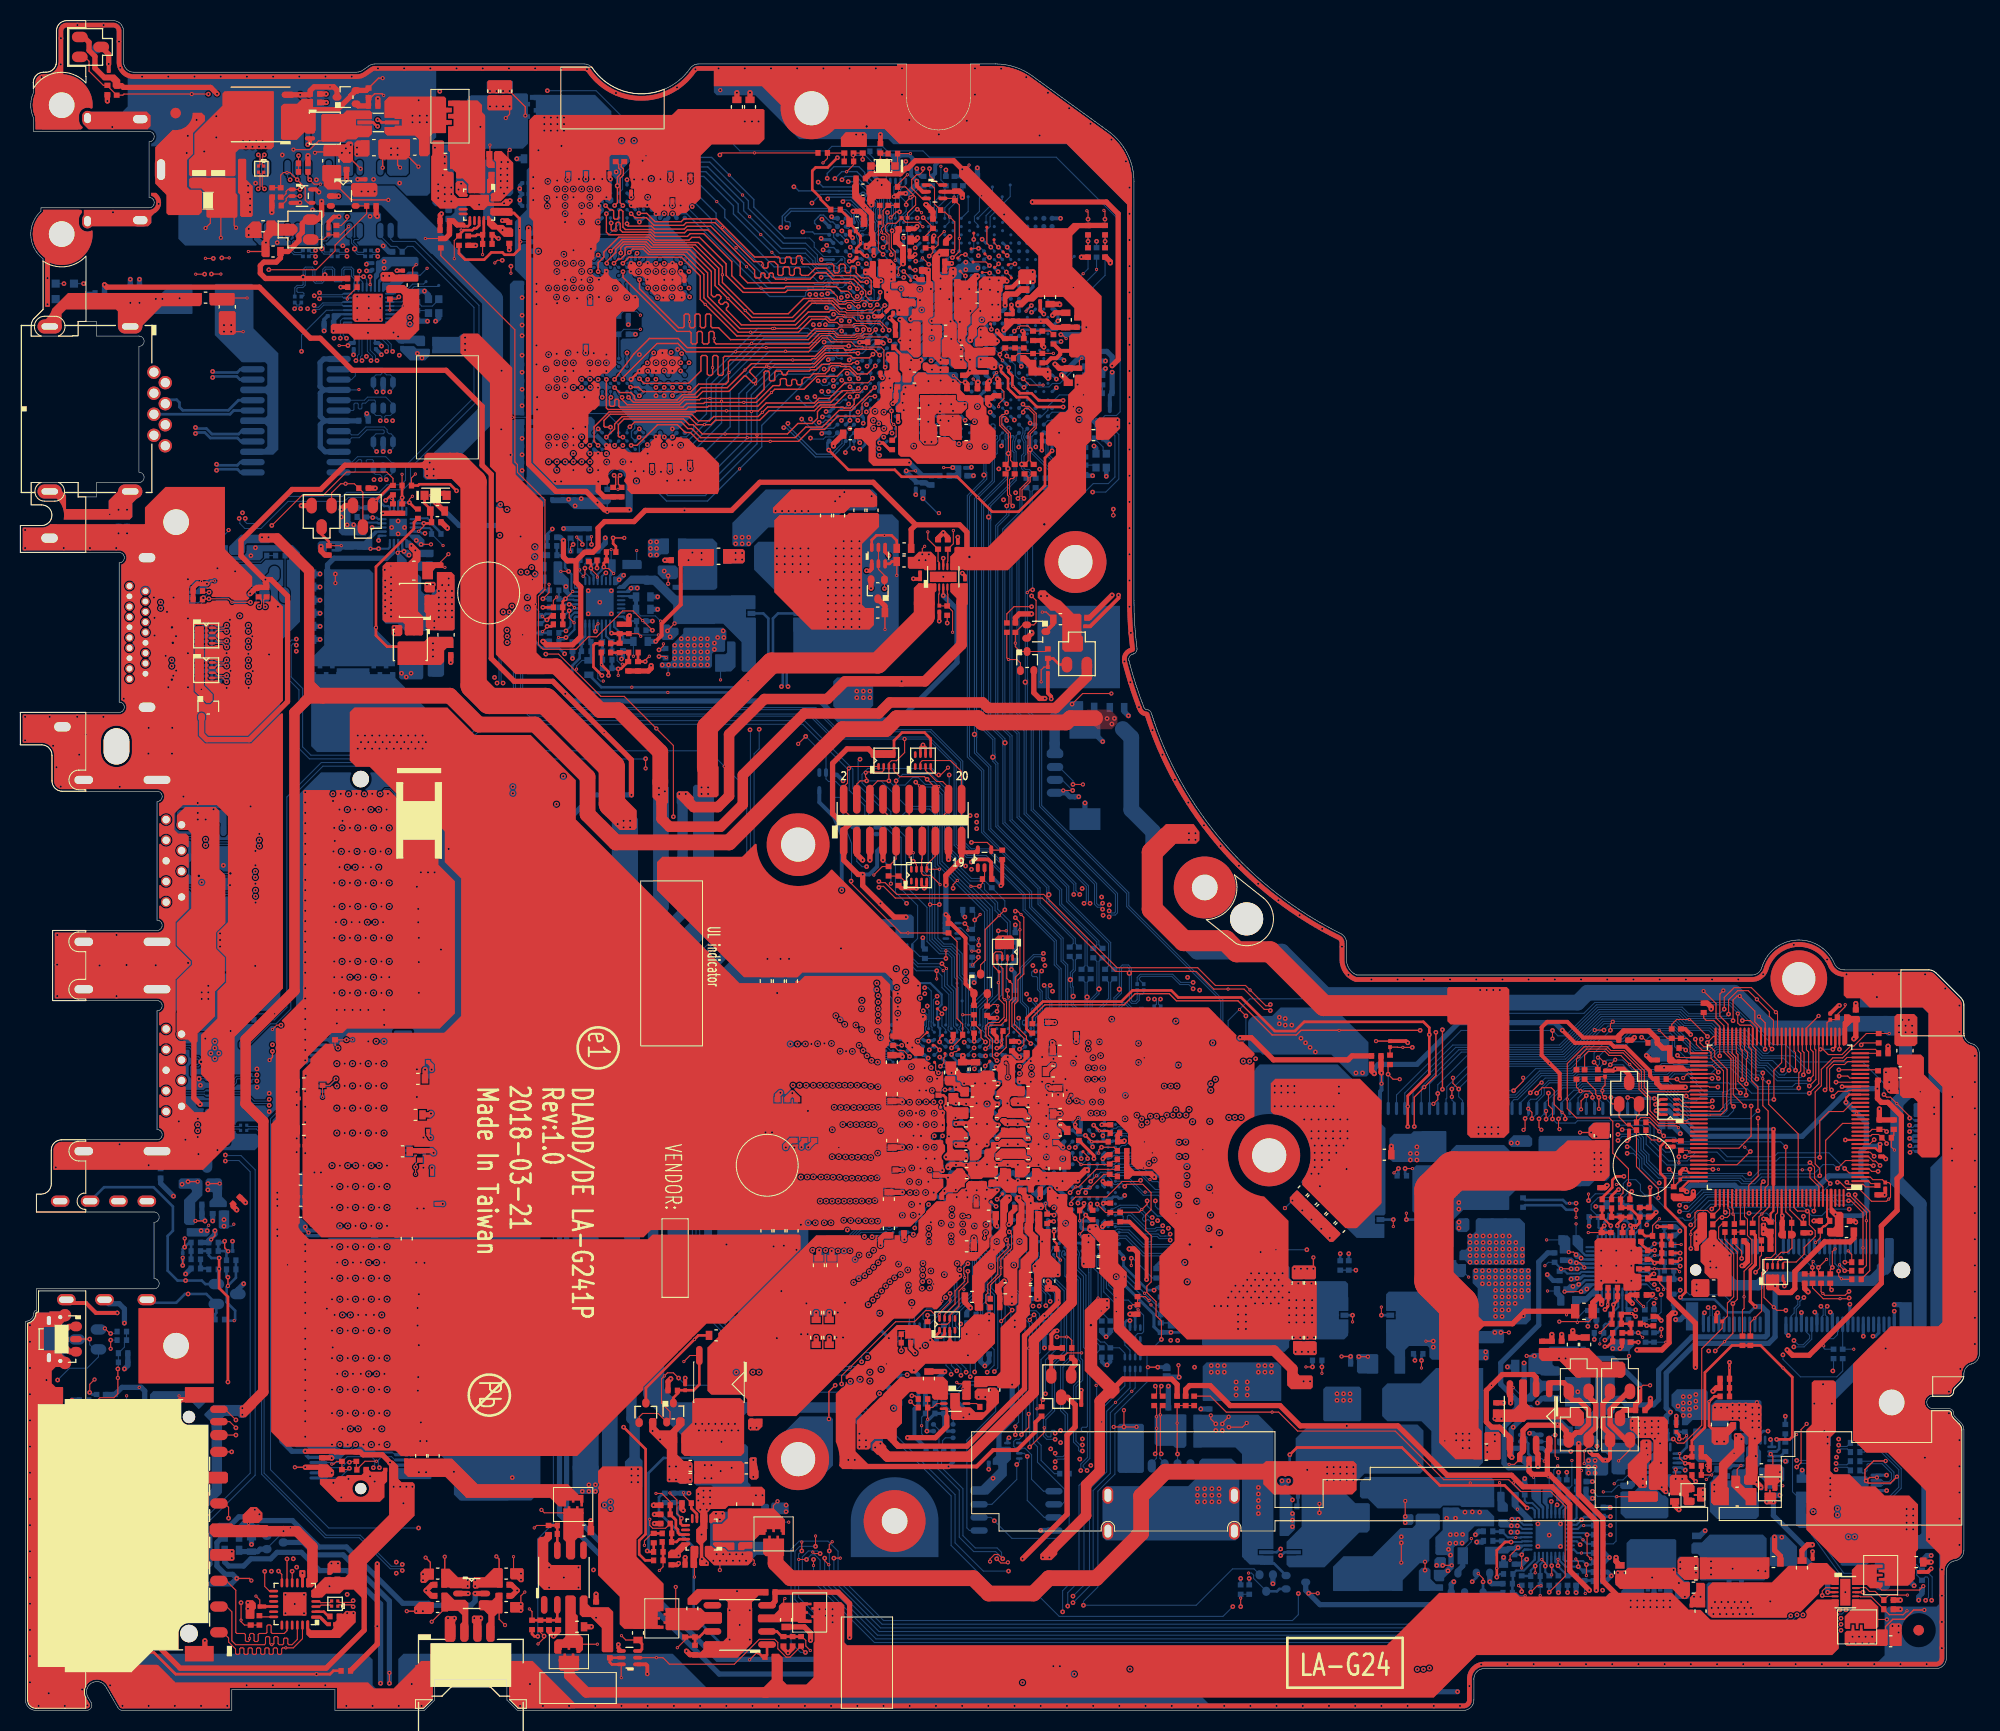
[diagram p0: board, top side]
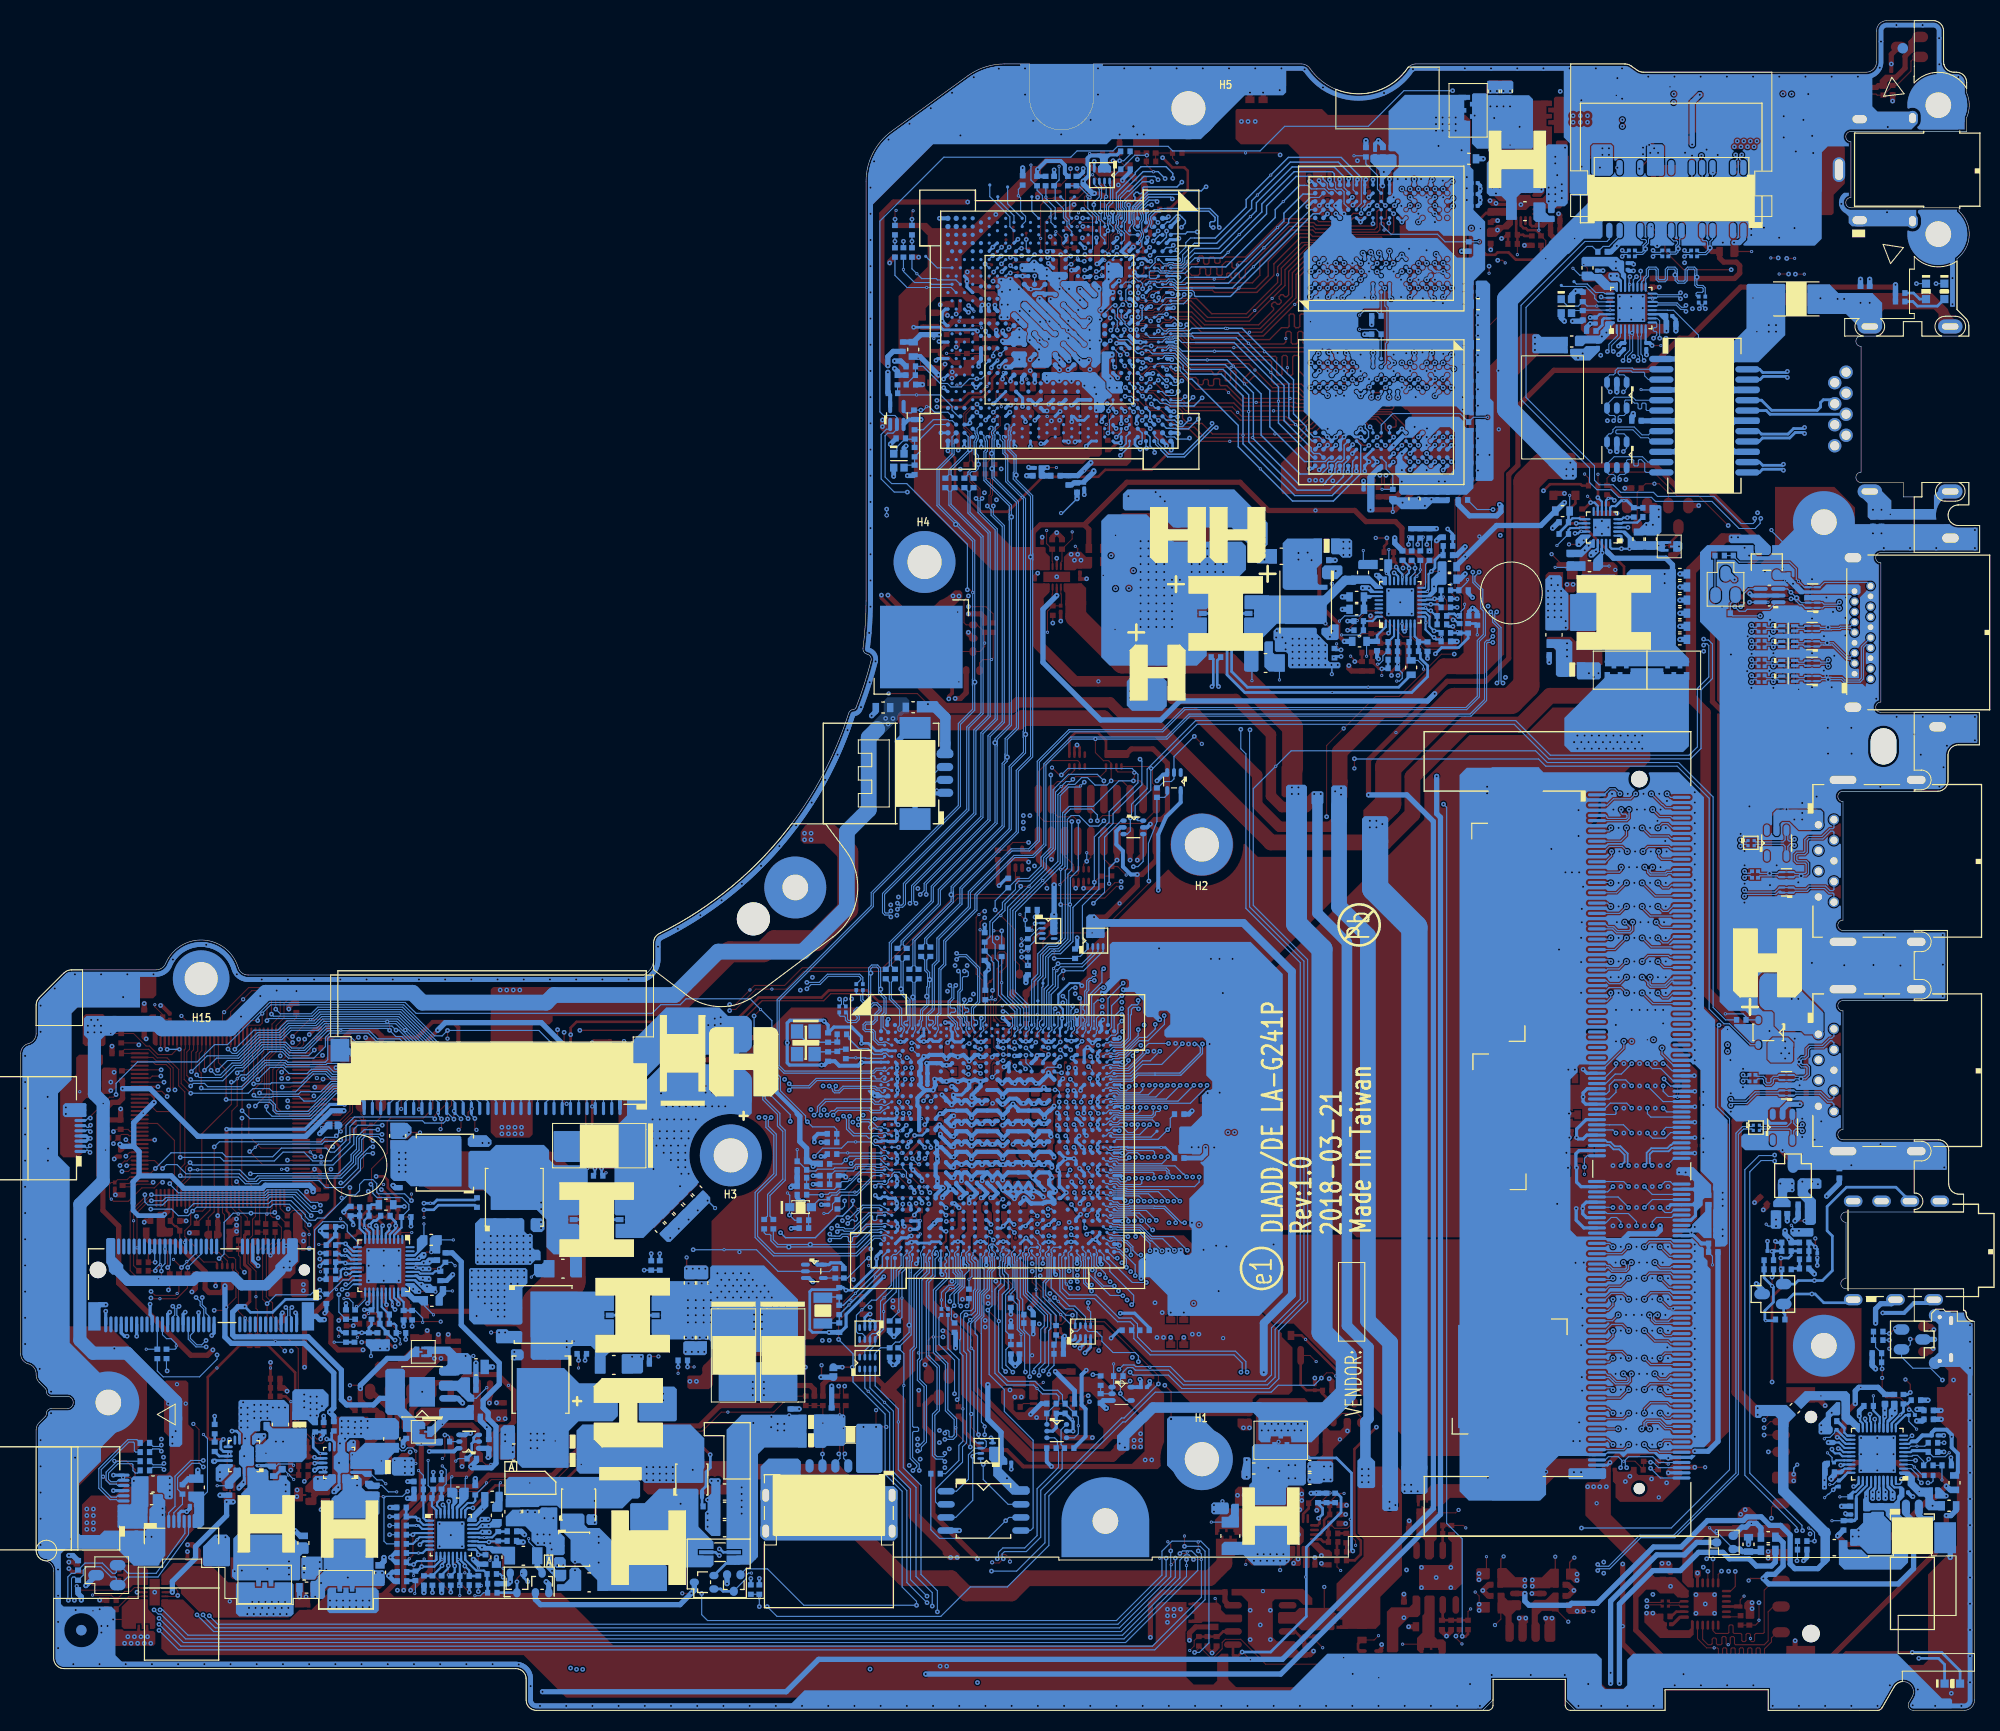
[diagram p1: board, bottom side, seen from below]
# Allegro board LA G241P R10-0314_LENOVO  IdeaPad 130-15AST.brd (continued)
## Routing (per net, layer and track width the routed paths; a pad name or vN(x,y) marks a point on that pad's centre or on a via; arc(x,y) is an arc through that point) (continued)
GNDA: length 89
  TOP w0.127: v3(18.47,45.66) 18.84,46.03 v1(18.84,46.51) ; v1(20.09,42) v3(20.09,41.15) ; v1(17.87,47.46) v3(16.94,47.46)
  TOP w0.508: v1(20.95,48.54) 20.6,48.88 RA65.2 ; v1(14.95,29.56) 15.52,30.13 16.85,30.13 JSD1.13
  VCC w0.203: 7.05,39.1 JHP1.7 ; JHP1.7 9.21,39.83 ; JHP1.7 7.05,39.83 ; JHP1.7 9.21,39.1 ; JHP1.7 8.13,40.55 ; JHP1.7 7.05,40.55 ; JHP1.7 8.13,39.1 ; JHP1.7 9.21,40.55 ; 12.23,48.65 JHP1.5 ; JHP1.5 11.15,48.65 ; JHP1.5 12.23,50.1 ; JHP1.5 13.31,48.65 ; JHP1.5 13.31,49.38 ; JHP1.5 11.15,49.38 ; JHP1.5 11.15,50.1 ; JHP1.5 13.31,50.1 ; H9.1 16.31,34.12 ; H9.1 13.83,36.6 ; H9.1 16.75,35.36 ; H9.1 16.31,36.6 ; H9.1 13.83,34.12 ; H9.1 15.07,33.68 ; H9.1 15.07,37.04 ; H9.1 13.39,35.36
  GND w0.203: 15.07,33.68 H9.1 ; H9.1 13.83,36.6 ; H9.1 16.75,35.36 ; H9.1 13.39,35.36 ; H9.1 16.31,34.12 ; H9.1 15.07,37.04 ; H9.1 13.83,34.12 ; H9.1 16.31,36.6 ; 11.15,50.1 JHP1.5 ; JHP1.5 11.15,48.65 ; JHP1.5 13.31,50.1 ; JHP1.5 13.31,49.38 ; JHP1.5 11.15,49.38 ; JHP1.5 13.31,48.65 ; JHP1.5 12.23,50.1 ; JHP1.5 12.23,48.65 ; 7.05,39.83 JHP1.7 ; JHP1.7 9.21,40.55 ; JHP1.7 7.05,40.55 ; JHP1.7 9.21,39.83 ; JHP1.7 7.05,39.1 ; JHP1.7 8.13,39.1 ; JHP1.7 8.13,40.55 ; JHP1.7 9.21,39.1
  BOTTOM w0.203: UA1.31 11.7,22.02 12,21.71 v1(12.19,21.71) ; UA1.19 11.3,27.81 11.56,28.07 11.56,28.45 v1(11.65,28.54)
  BOTTOM w0.254: v1(20.09,42) 19.95,42.14 CA56.1
  BOTTOM w0.381: CA60.2 12.89,18.99 v1(12.98,19.08)
  BOTTOM w0.457: CA63.2 11.65,29.06 v1(11.65,28.54)
  BOTTOM w0.508: v1(6.04,29.19) 5.48,29.19 RA60.2 ; v1(10.06,33.11) 10.39,33.44 RA47.2 CA43.2 ; JHP1.7 8.52,39.44 9.55,39.44 10.06,38.93 v1(10.06,37.56) ; v1(18.84,46.51) 18.84,46.18 18.24,45.58 RA57.1 RA44.1 ; CA65.2 RA62.2 17.57,47.77 v1(17.87,47.46) ; v1(15.99,42.32) CA59.1 ; RA66.2 5.53,28.07 v1(6.08,28.07) ; v1(18.62,47.46) CA50.2 ; v1(14.81,49.87) 13.57,51.11 RA61.2 ; CA64.1 v1(13.36,19.79)
  vias: v1(14.32,28.86) v1(15.33,27.65) v1(15.33,27.02)
PVCC_RT3661: length 5.2
  BOTTOM w0.102: PR801.1 148.08,43.45 v2(147.75,43.12)
  BOTTOM w0.203: PR801.1 149.19,42.96 PC801.1 149.68,42.59 149.91,42.36 151.13,42.36 151.29,42.52 PU801.34
PVCC_VGA: length 5.6
  BOTTOM w0.102: v2(62.03,105.63) 61.52,106.14 60.1,106.14 59.65,106.58 PR1033.1
  BOTTOM w0.203: 59.08,107.98 59.01,108.05 PU1001.27
  BOTTOM w0.381: 59.08,107.98 PC1043.1 PR1033.1
VBAT_CHG: length 4.3
  BOTTOM w0.102: PR745.1 144.72,21.98 v2(144.72,22.06)
  BOTTOM w0.203: PR745.1 145.8,20.31 146,20.11 146.53,20.11 147.17,19.47 PU703.26
VCC_5V: length 1.2
  BOTTOM w0.102: PC419.1 v2(170.82,21.79)
VCC_RT3661: length 4.5
  TOP w0.102: PR837.1 158.89,41.39 159.25,41.03 v2(159.25,40.81)
  TOP w0.254: PR837.1 158.79,41.78 157.81,41.78 PC822.1 158.18,42.34 158.31,42.34 v1(158.33,42.33)
  BOTTOM w0.203: PU801.17 157.74,42.52 157.93,42.33 v1(158.33,42.33)
VCC_VGA: length 8.9
  TOP w0.102: v2(55.97,105.38) 55.72,105.12 v1(55.72,104.64)
  IN1 w0.381: v1(55.72,104.64) 54.29,104.64 53.98,104.96 53.98,107.87 v1(52.86,108.98)
  BOTTOM w0.203: PU1001.6 55.54,104.82 v1(55.72,104.64) 55.77,104.64 55.94,104.81 PU1001.5
VCCSENSE_VGA: length 76.6
  TOP w0.254: v1(101.06,126.4) 98.52,126.4 97.56,127.35 96.55,127.35 95.71,128.18 95.71,129.15 95.03,129.84 v1(95.03,130.3) ; PR1024.1 56.28,101.43 v2(56.3,101.4) 56.99,100.72 v1(56.99,100.36)
  IN2 w0.254: v1(101.06,126.4) 101.31,126.14 101.31,117.12 93.88,109.69 93.88,103.28 92.52,101.92 75.39,101.92 74.34,100.87 72.99,100.87 72.16,100.04 57.3,100.04 v1(56.99,100.36)
  BOTTOM w0.254: v1(95.03,130.3) 94.45,130.89 UV1.AC20
VDD_CHG: length 26.6
  TOP w0.254: v1(144.48,16.32) 143.89,16.32 143.09,15.52 v2(143.09,13.77) v1(143.09,12.92)
  IN1 w0.254: v1(143.09,12.92) 143.94,12.07 149.1,12.07 149.75,11.42 v1(149.95,11.42) 152.68,14.15 152.68,17.37 v1(154.1,18.79)
  BOTTOM w0.203: v1(143.09,12.92) 143.4,13.23 PR749.1 ; PR760.1 143.61,16.39 144.41,16.39 v1(144.48,16.32) 145.48,16.32 145.55,16.39 PU703.19
  BOTTOM w0.254: PR741.1 v1(154.1,18.79) ; PC768.1 142.73,16.43 PR760.1 ; PR750.1 v1(149.95,11.42)
VDD_DDR: length 6.1
  BOTTOM w0.102: v2(39.72,117.82) PR504.2
  BOTTOM w0.203: PU501.11 38.67,115.51 38.76,115.6 39.45,115.6 PC516.1
  BOTTOM w0.254: PR504.2 39.83,116.18 PC516.1 39.83,115.1 40.74,114.18 PR502.1
VDDIO_RT3661: length 4.3
  TOP w0.102: v2(157.32,39.17) 156.67,39.82 PR818.1
  TOP w0.457: PR818.1 156,40.29 PC816.1 155.79,39.91 v1(156.24,39.46)
  BOTTOM w0.203: v1(156.24,39.46) 156.07,39.63 PU801.22
VDDIO_VGA: length 4.2
  TOP w0.102: v1(55.29,110.76) 55.29,110.67 55.91,110.05 v2(55.91,109.9)
  TOP w0.254: v1(55.29,110.76) 55.29,111.19 PR1005.2
  BOTTOM w0.203: PC1002.1 55.89,111.52 55.29,110.92 v1(55.29,110.76) 55.29,110.32 55.54,110.06 PU1001.19
VDDP_CHG: length 3.7
  BOTTOM w0.203: PU703.20 145.46,16.79 145.42,16.76 v2(144.93,16.76) 144.68,16.76 144.65,16.78 144.16,16.78 143.6,17.34 PR760.2
  BOTTOM w0.254: PC769.1 142.73,17.34 PR760.2
VDDR4: length 2.2
  BOTTOM w0.356: UV1.U12 89.68,137.38 90.49,137.38 UV1.V12 90.73,137.43 91.44,137.43 UV1.Y12
VIN_0.775VALW:
  vias: v2(148.99,27.74)
VIN_RT3661: length 7.8
  TOP w0.102: v3(149.15,37.7) 152.01,37.7 152.39,38.08 PR806.2
  TOP w0.508: v1(153.25,39.4) 153.25,39.77 PC808.1 152.39,39.54 PR806.2
  BOTTOM w0.203: PU801.28 153.67,40.01 153.25,39.59 v1(153.25,39.4)
VSS_MECH: length 56.5
  TOP w0.254: v1(99.98,122.14) 99.29,121.45 99.29,118.79 96.74,116.24 94.17,116.24 v2(92.76,117.65) 90.78,119.63 85.41,119.63 84.74,120.3 80.25,120.3 v1(78.34,122.21)
  IN1 w0.254: v1(100.8,144.69) 100.8,138.71 103.83,135.69 103.83,128.44 101.7,126.32 101.7,123.49 100.36,122.14 v1(99.98,122.14)
  BOTTOM w0.254: UV1.A32 78.21,122.91 78.21,122.34 v1(78.34,122.21)
  BOTTOM w0.305: UV1.AM32 v1(99.98,122.14)
  BOTTOM w0.381: UV1.AM1 v1(100.8,144.69)
VSSSENSE_VGA: length 80
  TOP w0.254: v1(56.35,100.36) 55.53,101.19 55.53,103.28 55.72,103.47 PR1014.1 ; v1(95.77,130.2) 95.77,129.77 96.14,129.41 96.14,128.45 v2(96.2,128.39) 96.86,127.73 97.98,127.73 98.68,127.03 v1(101.06,127.03)
  IN2 w0.254: v1(56.35,100.36) 56.35,100.04 56.86,99.53 72.48,99.53 73.31,100.36 74.64,100.36 75.64,101.36 92.85,101.36 94.39,102.9 94.39,109.44 101.82,116.87 101.82,126.46 101.25,127.03 v1(101.06,127.03)
  BOTTOM w0.254: v1(95.77,130.2) 95.77,130.3 UV1.AD20
32K_X1: length 9.8
  BOTTOM w0.127: UC1.BA2 105.87,43.02 v2(109.57,39.32) RC87.2 CC11.1 112.05,37.57 YC32.1
32K_X2: length 9.9
  BOTTOM w0.127: UC1.AY2 106.33,44 106.33,43.06 v2(108.95,40.45) 110.11,39.29 RC87.1 CC12.1 112.03,40.09 YC32.2
48M_X1: length 5.5
  BOTTOM w0.127: RC104.2 109.57,65.32 109.57,65.12 108.61,64.17 107.72,64.17 107.17,63.61 106.37,63.61 106.25,63.73 105.99,63.73 105.67,63.41 UC1.F2
48M_X1_R: length 5.2
  BOTTOM w0.127: YC48.1 114.61,65.71 113.68,64.79 CC15.1 110.73,64.79 RC103.1 110.71,65.55 RC104.1
48M_X2: length 3.9
  BOTTOM w0.127: UC1.F1 106.12,63.35 106.25,63.22 107.92,63.22 107.98,63.28 v2(108.92,63.28) 109.81,63.28 RC105.2
48M_X2_R: length 3.2
  BOTTOM w0.127: RC105.1 110.49,64.11 RC103.2 110.75,63.86 CC16.1 112.68,63.86 YC48.3
+0.775MOS: length 16.5
  TOP w0.508: UC26.2 146.9,32.29 146.62,32.57 143.63,32.57 v2(142.58,31.52) 142.08,31.02 142.08,27.97 142.59,27.46 143.35,27.46 144.36,26.45 UC26.5 144.36,24.73 v1(144.55,24.54)
  BOTTOM w0.508: v1(144.55,24.54) 144.49,24.6 R944.2 144.55,25.42 QC22.1
+APU_CORE: length 68.6
  TOP w0.254: v1(157.95,50.7) 157.95,48.87 PC817.1 PR816.1
  IN2 w0.254: v1(125.95,50.83) 125.95,50.96 132.55,57.56 136.93,57.56 138.51,59.13 148.3,59.13 149,59.83 149.37,59.83 149.8,59.41 149.8,59.04 151.29,57.55 153.71,57.55 153.95,57.31 155.01,57.31 157.95,54.36 v1(157.95,50.7)
  BOTTOM w0.381: UC1.N25 93.33,59.32 94.01,59.32 UC1.N23
  BOTTOM w0.4: UC1.AA31 90.41,55.16 v1(90.67,54.9) 90.93,55.16 UC1.AA29 91.55,54.78 v1(91.64,54.78) 91.79,54.78 UC1.AA27 92.43,54.9 v1(92.67,54.9) 92.93,55.16 UC1.AA25 93.4,55.16 v1(93.67,54.89) ; UC1.U31 90.46,56.87 v1(90.68,56.87) 90.88,56.87 UC1.U29 91.58,56.75 v1(91.64,56.75) 91.76,56.75 UC1.U27 92.38,57.16 v1(92.66,56.88) 92.94,57.16 UC1.U25 93.38,57.16 v1(93.68,56.86) 93.87,56.86 UC1.U23 94.17,57.16 94.59,56.74 v1(94.68,56.74) ; UC1.N21 94.77,58.76 v1(94.66,58.76) 94.59,58.83 94.5,58.83 UC1.N23 ; UC1.K31 90.17,61.66 90.17,61.76 v1(90.24,61.83) 90.24,61.69 UC1.K29 91.13,60.8 v1(91.46,60.8) 91.82,61.16 UC1.K27 92.17,61.16 v1(92.52,60.81) 92.57,60.86 92.67,60.86 UC1.K25 93.2,61.16 93.5,60.87 v1(93.5,60.8) 93.56,60.87 93.78,60.87 UC1.K23 94.33,61.16 94.7,60.8 v1(94.73,60.8) 94.95,61.02 94.96,61.02 95.1,61.16 UC1.K21 ; UC1.N25 92.88,58.87 v1(92.67,58.87) 92.46,58.87 UC1.N27 91.83,58.82 v1(91.65,58.82) 91.51,58.82 UC1.N29 90.88,58.87 v1(90.65,58.87) 90.46,58.87 UC1.N31
  vias: v1(121.57,60.55) v1(121.57,59.91) v1(121.57,58.58) v1(122.2,60.55) v1(122.2,59.91) v1(122.2,58.58) v1(122.84,60.55) v1(122.84,59.91) v1(122.84,58.58) v1(123.47,60.55) v1(123.47,59.91) v1(123.47,58.58) v1(124.11,58.58) v1(124.42,57.31) v1(124.74,58.58) v1(125.12,57.31) v1(125.12,56.16) v1(125.12,55.47) v1(125.12,52.04) v1(125.38,58.58) v1(125.44,54.77) v1(125.44,54.07) v1(125.44,53.37) v1(125.44,52.67) v1(125.82,57.31) v1(125.82,56.16) v1(125.82,55.47) v1(125.82,52.04) v1(126.01,58.58) v1(126.14,54.77) v1(126.14,54.07) v1(126.14,53.37) v1(126.14,52.67) v1(126.52,57.31) v1(126.52,56.16) v1(126.52,55.47) v1(126.65,58.58) v1(126.84,54.77) v1(126.84,54.07) v1(126.84,53.37) v1(127.22,57.31) v1(127.22,56.16) v1(127.22,55.47) v1(127.28,58.58) v1(127.54,54.77) v1(127.54,54.07) v1(127.79,60.48) v1(127.79,59.83) v1(127.92,57.31) v1(127.92,56.16) v1(127.92,55.47) v1(128.23,54.77) v1(128.62,57.31) v1(128.62,56.16) v1(128.62,55.47) v3(128.53,52.49)
+APU_CORE_NB: length 132.3
  TOP w0.254: v1(153.57,35.27) 153.81,35.27 PC815.1 PR812.2
  TOP w0.457: v1(96.82,63.36) 96.71,63.36 CC74.1
  IN1 w0.254: v1(123.41,36.16) 123.41,35.65 123.09,35.34 123.09,30.89 124.68,29.3 148.11,29.3 149.57,30.76 149.57,31.59 152.24,34.26 152.55,34.26 v1(153.57,35.27)
  IN1 w1.016: 142.2,28.35 123.98,28.35 122.2,30.13 122.2,35.84
  BOTTOM w0.3: 101.25,61.22 100.72,61.22 UC1.K11 ; UC1.L15 98.64,59.68 99.45,59.68 v1(99.46,59.68)
  BOTTOM w0.4: v1(97.92,60.96) 97.92,60.41 UC1.L15 ; v1(97.92,60.96) UC1.K15 v1(99.02,60.96) UC1.K13 v1(100.12,60.99) 100.5,60.99 UC1.K11 ; v1(97.92,60.96) UC1.K17 v1(96.82,60.96) ; 102.25,60.14 102.25,60.08 UC1.N7 102.94,59.39 102.94,58.63 UC1.R7 UC1.U7 UC1.W7 ; 102.25,60.14 v1(101.41,60.14) UC1.L10 101.25,60.74 101.25,61.22 v1(101.27,61.22) ; 102.25,60.14 UC1.L7 102.62,60.81 102.62,61.44 102.77,61.6 UC1.J7 102.77,61.93 102.62,62.08 102.62,62.71 UC1.G7 102.32,63.31 v1(102.32,63.42) 102.31,63.42 101.91,63.42 UC1.E9 UC1.E11 100.49,63.56 v1(100.12,63.18) 99.74,63.56 UC1.E13 v1(99.02,63.36) UC1.E15 97.92,63.01 ; UC1.N19 96.4,59.16 v1(96.69,58.87) 96.98,59.16 UC1.N17 ; v1(99.42,57.65) 99.6,57.65 100.09,57.16 UC1.U11 99.67,56.66 v1(99.42,56.66) 99.42,56.91 UC1.U13 98.94,57.16 v1(98.67,56.89) 98.4,57.16 UC1.U15 97.76,56.75 v1(97.69,56.75) 97.58,56.75 UC1.U17 96.88,56.87 v1(96.66,56.87) 96.37,57.16 UC1.U19 95.97,57.16 v1(95.67,56.86) 95.37,57.16 UC1.U21 ; UC1.AA23 94.53,54.8 94.62,54.8 v1(94.66,54.76) 94.77,54.76 UC1.AA21 95.44,54.89 95.67,54.89 v1(95.67,54.9) 95.91,54.9 UC1.AA19 96.43,54.9 v1(96.67,54.9) 96.93,55.16 UC1.AA17 97.6,54.73 97.69,54.73 v1(97.69,54.73) 97.76,54.73 98.17,55.13 UC1.AA15 98.41,55.16 v1(98.67,54.9) 98.93,55.16 UC1.AA13 99.44,54.89 v1(99.44,54.66) 99.67,54.66 UC1.AA11 100.71,55.7 v1(100.71,55.88) ; 97.92,63.01 v1(97.92,62.97) ; 97.92,63.01 97.88,63.01 97.37,63.52 UC1.E17 97.02,63.56 v1(96.82,63.36) 96.47,63.36 UC1.E19 ; UC1.AE11 100.17,53.13 99.7,52.66 v1(99.44,52.66) 99.44,52.89 UC1.AE13 98.69,52.91 v1(98.67,52.91) 98.65,52.91 UC1.AE15 97.84,52.83 97.71,52.83 v1(97.67,52.78) 97.55,52.78 UC1.AE17 96.94,53.16 96.69,52.91 v1(96.67,52.91) 96.65,52.91 96.4,53.16 UC1.AE19 95.93,52.92 v1(95.68,52.92) 95.63,52.92 95.4,53.16 UC1.AE21 94.92,52.91 v1(94.64,52.91) 94.42,52.91 UC1.AE23 93.96,52.95 v1(93.68,52.95) 93.62,52.95 93.41,53.16 UC1.AE25 92.93,53.16 v1(92.67,52.9) 92.41,53.16 UC1.AE27 91.91,52.9 v1(91.66,52.9) 91.43,52.9 UC1.AE29 90.91,52.9 v1(90.67,52.9) 90.41,53.16 UC1.AE31 89.9,52.89 v1(89.9,52.66) ; UC1.N13 99.46,59.45 v1(99.46,59.68) ; UC1.N13 98.96,59.16 v1(98.67,58.87) 98.38,59.16 UC1.N15 97.72,58.71 v1(97.67,58.71) 97.62,58.71 UC1.N17 ; UC1.N13 v1(99.62,58.71) 100.06,59.16 UC1.N11 100.17,59.3 v1(100.57,59.7) ; UC1.N17 97.45,59.44 v1(97.67,59.44) 97.67,59.66 UC1.L17 96.82,60.51 v1(96.82,60.96) ; v1(96.82,60.96) UC1.K19
  vias: v1(115.72,39.21) v1(116.36,39.21) v1(116.99,39.21) v1(117.06,40.04) v1(117.38,40.61) v1(117.76,41.18) v1(117.76,40.04) v1(118.01,39.21) v1(118.01,38.38) v1(118.01,37.69) v1(118.01,36.99) v1(118.14,40.61) v1(118.52,41.18) v1(118.52,40.04) v1(118.77,39.21) v1(118.77,38.38) v1(118.77,37.69) v1(118.77,36.99) v1(118.9,41.75) v1(118.9,40.61) v1(119.28,42.38) v1(119.28,41.18) v1(119.28,40.04) v1(119.66,41.75) v1(119.66,40.61) v1(119.66,39.46) v1(120.04,42.38) v1(120.04,41.18) v1(120.04,40.04) v1(120.42,41.75) v1(120.42,40.61) v1(120.42,39.46) v1(120.8,42.38) v1(120.8,41.18) v1(120.8,40.04) v1(121.19,41.75) v1(121.19,40.61) v1(121.19,39.46) v1(121.57,42.38) v1(121.57,41.18) v1(121.57,40.04) v1(121.95,41.75) v1(121.95,40.61) v1(121.95,39.46) v1(122.33,42.38) v1(122.33,41.18) v1(122.33,40.04) v1(122.96,40.54) v1(122.96,39.78) v1(122.96,39.02) v1(122.96,38.32) v1(122.96,37.62) v1(123.22,41.41) v1(123.66,39.78) v1(123.66,39.02) v1(123.66,38.32) v1(123.66,37.62) v1(123.85,41.41) v1(124.04,36.16) v1(124.49,41.41) v1(124.42,39.78) v1(124.42,39.02) v1(124.42,38.32) v1(124.42,37.62) v1(124.74,36.16) v1(125.12,41.41) v1(125.19,39.78) v1(125.19,39.02) v1(125.19,38.32) v1(125.19,37.62) v1(125.38,36.16) v1(142.9,28.29) v1(143.54,28.29) v3(120.2,44.44)
+BIF_VDDC: length 1.4
  BOTTOM w0.356: UV1.R21 88.26,130.01 v1(88.34,130.01)
  BOTTOM w0.381: v1(89.16,129.98) 89.58,130.4 UV1.U21
  vias: v1(89.16,125.11) v1(89.95,125.04) v2(90.36,125.47)
+CARD_3V3: length 7.6
  TOP w1.016: 23.75,17.38 v3(25.48,17.38) 26.77,17.38 28.29,15.87 28.29,13.43
+CHGRTC: length 6
  BOTTOM w0.102: v2(26.15,17.7) 25.5,17.06 25.22,17.06 23.87,15.7 PD101.2
  BOTTOM w0.508: PR108.1 21.3,15.4 PR107.1 22.98,15.4 23.22,15.64 PD101.2
+CHGRTC_R: length 28.8
  TOP w0.127: v1(20.94,12.79) 22.16,12.79 v3(22.37,12.59)
  BOTTOM w0.508: PR109.2 19.55,16.79 19.03,16.27 19.03,14 19.84,13.19 20.55,13.19 v1(20.94,12.79) 20.41,12.26 7.86,12.26 6.38,13.75 6.38,18.32 7.12,19.06 JRTC1.1
+EC_VCCA: length 109.1
  TOP w0.203: U11.67 160.76,62.92 C184.1
  TOP w0.381: L20.2 154.67,65.24 151.45,65.24 149.93,66.77 147.97,66.77 147.44,66.24 147.44,63.52 v2(148.2,62.76) 149.19,61.77 v1(149.19,59.34)
  TOP w0.508: L20.2 154.92,65.42 155.4,65.89 157.84,65.89 158.65,65.08 158.65,64.75 R365.1 159.17,64.23 PR206.1 159.84,63.24 159.98,63.1
  IN2 w0.254: v1(149.19,59.34) 148.54,58.69 138.64,58.69 137.06,57.12 133.06,57.12 127.92,51.97 v1(127.92,44.29) 127.73,44.1 117.73,44.1 115.17,41.54 115.17,40.75 114.75,40.33 114.75,36.45 111.04,32.75 109.96,32.75 108.36,31.15 108.36,22.7 v1(118.26,12.79)
  BOTTOM w0.254: R368.1 v1(127.92,44.29) ; R364.1 v1(118.26,12.79)
+FBA_VREFC0: length 48.1
  TOP w0.508: v1(49.24,143.73) 49.24,120.87 51.91,118.2 54.83,118.2 v3(55.91,117.12) 56.61,116.43 v1(59.02,116.43)
  IN1 w0.508: v1(57.73,149.19) 56.95,149.96 51.72,149.96 50.38,148.62 50.38,144.87 v1(49.24,143.73)
+IOVDD_CODEC: length 9.9
  BOTTOM w0.203: 6.56,26.09 6.8,25.84 UA1.8
  BOTTOM w0.381: 6.56,26.09 6.1,26.09 5.53,26.66 CA48.1 4.62,26.92 4.32,27.22 3.18,27.22 2.68,26.73 v3(2.68,26.54) 2.68,25.5 2.09,24.9 2.09,23.1 RA6.1
+LAN_SROUT1.05: length 1.7
  BOTTOM w0.102: v2(39.4,139.84) 38.73,139.17 RL11.1
+LAN_VDD: length 7.1
  TOP w0.102: v1(31.73,132.35) v2(30.88,132.35)
  BOTTOM w0.203: 34.38,132.59 34.35,132.63 UL2.3 ; UL2.8 32.35,132.65 CL5.1 ; UL2.30 36.82,135.38 37.14,135.07 CL7.1
  BOTTOM w0.381: CL5.1 31.97,132.59 v1(31.73,132.35) ; v1(37.73,135.07) CL7.1 ; v1(34.98,132.3) 34.69,132.59 CL4.1 34.38,132.59
  vias: v1(35.23,140.49) v1(35.23,139.86)
+LAN_VDDREG: length 1.4
  TOP w0.102: RL1.2 38,139.86 v2(38.34,140.2)
  vias: v1(35.14,139.11) v1(35.73,139.11)
+LCDVDD: length 5.5
  TOP w0.127: 30.72,147.78 32.03,146.47 v3(35.64,146.47)
+LCDVDD_CONN: length 3.3
  TOP w0.127: v3(32.96,149.5) 32.11,150.35 C201.1 ; v3(28.53,151.05) 28.6,151.12 R211.2
  vias: v1(31.14,151.03) v1(31.52,151.48) v1(31.9,151.03) v3(32.01,151.81)
+LEDVDD: length 4.8
  TOP w0.127: v3(38.56,149.7) 37.63,150.63 37.42,150.63 ; v3(36.78,149.61) 36.54,149.85 v1(36.54,150.84) ; C205.1 v3(35.09,149.6)
  vias: v1(35.91,151.48) v1(35.91,150.84) v1(36.54,151.48)
+LINE1-VREFO-R: length 26.4
  TOP w0.254: v1(19.24,43.86) v3(19.24,42.82) 19.24,40.95 20.09,40.1 v1(20.09,31.84)
  IN1 w0.381: v1(20.09,31.84) 19.35,31.84 17.4,29.89 16.17,29.89 14.64,28.36 v1(14.64,25.98)
  BOTTOM w0.203: 14.15,25.98 13.6,25.98 13.07,25.44 UA1.24
  BOTTOM w0.254: RA49.1 RA36.1 18.24,44.11 18.49,43.86 v1(19.24,43.86)
  BOTTOM w0.508: 14.15,25.98 v1(14.64,25.98)
+MIC2-VREFO: length 11
  TOP w0.508: v1(13.78,26.48) 13.78,26.66 13.11,27.34 13.11,28.67 v1(12.03,29.75)
  BOTTOM w0.203: v1(13.78,26.48) 13.77,26.47 13.6,26.47 13.23,26.11 13.04,25.91 13.02,25.91 12.95,25.84 UA1.23
  BOTTOM w0.508: RA58.1 RA54.1 9.83,31.32 v2(11.5,31.32) 11.69,31.32 12.03,30.98 v1(12.03,29.75)
+MPLL_PVDD: length 2
  TOP w0.102: v1(85.53,140.27) 85.5,140.27 85.08,139.84 v2(85.08,139.21)
  BOTTOM w0.381: v1(85.53,140.27) 85.4,140.27 UV1.L8
+MVREFDA: length 11.9
  TOP w0.102: v1(90.36,120.52) v2(89.47,120.52)
  IN1 w0.381: v1(83.68,125.88) 84.08,125.49 85.37,125.49 85.91,124.95 85.91,122.23 86.8,121.34 89.53,121.34 v1(90.36,120.52)
  BOTTOM w0.254: UV1.K26 83.98,126.19 v1(83.68,125.88)
+MVREFSA: length 9.5
  TOP w0.102: v1(85.85,120.2) v2(86.76,120.2)
  IN1 w0.508: v1(85.85,120.2) 85.18,120.86 85.18,123.98 84.26,124.9 83.88,124.9 83.42,125.36 83.38,125.36 82.82,125.92 v1(82.82,125.96)
  BOTTOM w0.254: v1(82.82,125.96) 83.14,126.29 UV1.J26
  BOTTOM w0.508: v1(85.85,120.2) 85.85,120.09 86.36,119.58
+RTC_BATT: length 29.6
  TOP w0.127: v1(110.23,33.28) v3(109.27,33.28)
  TOP w0.381: v1(100.47,36.81) 100.28,36.81 99.91,36.44 RC113.1 99.93,35.15 RC111.2
  IN1 w0.381: v1(100.47,36.81) 100.85,36.81 102.96,34.7 105.69,34.7 107.11,33.28 v1(110.23,33.28)
  IN2 w0.381: v1(100.17,48.73) 100.48,48.73 100.72,48.5 100.72,48.26 100.72,48.25 100.72,47.8 100.72,47.8 100.72,46.77 101.12,46.37 101.12,41.94 100.38,41.2 100.38,36.9 v1(100.47,36.81)
  BOTTOM w0.254: UC1.AM11 100.57,49.16 100.17,48.76 v1(100.17,48.73)
  BOTTOM w0.381: CLRP1.1 v1(110.23,33.28)
+RTCBATT: length 116.3
  TOP w0.127: v1(35.75,2.63) v3(35.75,3.64)
  TOP w0.508: UC25.1 101.49,30.36 CC19.1 102.22,27.49 101.44,26.7 101.44,19.02 v1(97.12,14.7)
  IN1 w0.508: v1(97.12,2.7) v1(97.12,14.7)
  IN2 w0.508: v1(97.12,2.7) 96.42,2 54.64,2 51.84,4.79 37.37,4.79 35.75,3.17 v1(35.75,2.63)
  BOTTOM w0.508: v1(35.75,2.63) 35.75,10.6 31.27,15.08 28.6,15.08 27.4,16.29 PD101.1
+RTCBATT_R: length 5
  TOP w0.102: v2(102.85,34.66) 101.46,34.66 100.99,34.19 CC18.1
  TOP w0.381: UC25.3 99.9,34.23 RC113.2 99.93,34.26 100.92,34.26 CC18.1
+SPLL_PVDD: length 4.8
  TOP w0.508: LV7.2 80.98,147.53 CV84.1 ; 81.65,145.94 v2(81.88,145.7) 82.49,145.1 82.49,143.19
  BOTTOM w0.381: UV1.H7 82.38,141.54 v1(82.01,141.92)
+SPLL_VDDC: length 6.7
  TOP w0.254: LV8.2 80.36,144.63 CV91.1 80.36,144.2 80.97,143.59 CV92.1 81.41,142.97 v2(81.41,142.46) 81.41,142.17 81.02,141.79 CV93.1 81.37,141.45 81.77,141.04 v1(82.03,141.04)
  BOTTOM w0.305: UV1.H8 v1(82.03,141.04)
+TP_VCC: length 7.1
  BOTTOM w0.102: v2(172.15,26.75) 171.76,26.36 171.76,21.2 172.19,20.77 R279.2 172.93,20.77
+TSVDD: length 6.5
  TOP w0.508: LV2.2 102.39,134.13 CV19.1 101.29,134.1 100.08,134.1 99.47,134.71 v2(98.9,134.71) 96.74,134.71
  BOTTOM w0.381: UV1.AD17 95.3,133.41 v1(95.3,133.84)
+USB3_VCCA: length 9
  TOP w0.508: 16.79,65.19 16.79,59.39 v1(17.4,58.78)
  BOTTOM w0.508: v1(17.4,58.78) 18.57,58.78 19.08,58.27 D302.5
  vias: v1(17.17,87.03) v1(17.17,86.39) v1(17.55,69.63) v1(17.55,68.99) v1(17.93,86.39) v1(18.19,70.26) v1(18.19,69.63) v1(18.19,68.99) v3(18.7,87.38)
+V_DAC: length 19.5
  BOTTOM w0.102: TL1.4 32.76,128.05 v2(32.79,128.08)
  BOTTOM w0.508: TL1.1 29.38,131.05 29.02,130.69 29.02,128.39 29.36,128.05 ; CL18.2 32.77,125.05 TL1.7 29.47,125.05 ; 29.36,128.05 TL1.4 ; 29.36,128.05 29.05,127.73 29.05,125.47 29.47,125.05 ; TL1.10 29.52,122.05 29.05,122.52 29.05,124.68 29.42,125.05 29.47,125.05
+VGA_CORE: length 26.2
  TOP w0.127: v2(60.95,102.23) 60.54,101.82 v1(60.54,101.71)
  TOP w0.254: v1(60.54,101.71) PC1029.2 59.84,102.57 PR1027.2
  IN1 w0.254: v1(60.54,101.71) 60.54,101 61.81,99.73 71.4,99.73 72.86,101.19 78.07,101.19 79.78,102.9 v1(79.78,105.06)
  vias: v1(73.31,112.68) v1(73.31,111.92) v1(73.31,111.16) v1(73.31,110.39) v1(74.07,112.68) v1(74.07,111.92) v1(74.07,111.16) v1(74.07,110.39) v1(74.83,112.68) v1(74.83,111.92) v1(74.83,111.16) v1(74.83,110.39) v1(75.59,112.68) v1(75.59,111.92) v1(75.59,111.16) v1(75.59,110.39) v1(76.35,112.68) v1(76.35,111.92) v1(76.35,111.16) v1(76.35,110.39) v1(77.5,109.63) v1(78.26,109.63) v1(78.26,108.87) v1(78.26,108.11) v1(78.26,107.35) v1(78.26,106.58) v1(78.26,105.82) v1(78.26,105.06) v1(79.02,112.68) v1(79.02,111.92) v1(79.02,111.16) v1(79.02,110.39) v1(79.02,109.63) v1(79.02,108.87) v1(79.02,108.11) v1(79.02,107.35) v1(79.02,106.58) v1(79.02,105.82) v1(79.02,105.06) v1(79.78,113.38) v1(79.78,112.68) v1(79.78,111.92) v1(79.78,111.16) v1(79.78,110.39) v1(79.78,109.63) v1(79.78,108.87) v1(79.78,108.11) v1(79.78,107.35) v1(79.78,106.58) v1(79.78,105.82) v1(80.55,113.38) v1(80.55,112.68) v1(80.55,111.92) v1(80.55,111.16) v1(80.55,110.39) v1(80.55,109.63) v1(80.55,108.87) v1(80.55,108.11) v1(80.55,107.35) v1(80.55,106.58) v1(80.55,105.82) v1(80.55,105.06) v1(81.31,113.38) v1(81.31,112.68) v1(81.31,111.92) v1(81.31,111.16) v1(81.31,110.39) v1(81.31,109.63) v1(81.31,108.87) v1(81.31,108.11) v1(81.31,107.35) v1(81.31,106.58) v1(81.31,105.82) v1(81.31,105.06) v1(85.24,134.87) v1(85.27,132.84) v1(85.34,137.85) v1(86.21,132.04) v1(86.26,133.88) v1(86.23,132.86) v1(87.16,137.81) v1(87.35,135.81) v1(88.31,134.74) v1(88.31,133.07) v1(88.25,130.88) v1(89.05,141.17) v1(89.18,138.86) v1(89.16,137.84) v1(90.02,136.85) v1(90.14,134.69) v1(90.2,132.99) v1(90.4,139.72) v1(90.4,139.11) v1(91.15,131.99) v1(91.16,130.98) v1(91.62,140.43) v1(91.62,139.71) v1(92.05,132.88) v1(92.79,139.87) v1(92.84,141.07) v1(93.02,135.7) v1(93.11,137.82) v1(93.93,138.78) v1(93.97,137.75) v1(94.18,136.32) v1(94.21,135.1) v1(94.82,138.67) v1(94.74,137.56) v1(94.77,136.32) v1(94.82,135.1) v1(95.61,138.6)
+VL: length 361.1
  TOP w0.203: U1895V.4 v1(89.44,108.11) ; U381.4 v1(175.16,11.46)
  TOP w0.508: v1(59.21,88.78) 59.21,92.17 v2(56.56,94.82) v1(52.8,98.58) 51.59,99.79 47.84,99.79 45.62,102.01 45.62,119.85 44.73,120.74 44.73,126.46 41.24,129.95 32.16,129.95 29.05,133.06 28.09,133.06 23.14,138.02 8.36,138.02 v1(8.13,138.24)
  IN1 w0.508: v1(139.28,1.81) 139.28,4.89 140.14,5.75 171.41,5.75 175.35,9.68 175.35,11.27 v1(175.16,11.46)
  BOTTOM w0.508: R376.2 R378.2 v1(8.13,138.24) ; v1(59.21,88.78) 55.5,88.78 52.92,86.2 52.92,19.59 67.57,4.95 112.52,4.95 115.66,1.81 v1(139.28,1.81) ; v1(52.8,98.58) 53.49,97.88 77.5,97.88 79.34,96.04 85.18,96.04 90.77,101.63 90.77,106.77 v1(89.44,108.11) ; v1(175.16,11.46) 175.16,12.51 172.91,14.75 172.91,15.88 169.9,18.89 v1(169.9,20.22) v1(169.27,20.22)
ACIN_CHG: length 5.5
  BOTTOM w0.102: PR729.2 150.83,22.79 v2(151.3,23.26)
  BOTTOM w0.203: PU703.1 150.56,18.39 150.83,18.66 PC715.1
  BOTTOM w0.254: PR729.2 PR732.1 PC715.1
ACLIM_CHG: length 6.2
  BOTTOM w0.102: v2(145.84,11.12) 145.3,11.12 145.01,11.41 PR779.2
  BOTTOM w0.203: PR749.2 144.66,13.25 144.96,13.56 145.71,13.56 146.77,14.62 PU703.16
  BOTTOM w0.254: PR749.2 144.66,12.34 PR751.1 PR779.2
ADP_I: length 5.4
  TOP w0.102: U11.65 161.96,63.72 161.83,63.85 161.83,64.86 161.52,65.17 PC748.1 PR780.1 159.62,65.17 v2(158.83,65.96)
AGPIO3: length 5.3
  TOP w0.102: v1(102.52,50.21) 102.91,50.6 103.6,50.6 v2(103.66,50.66) 104.99,51.99 RC82.1 105.77,51.78 RC81.2
  BOTTOM w0.102: v1(102.52,50.21) 102.77,50.46 UC1.AJ7
AGPIO11: length 6.2
  TOP w0.102: RC69.2 106.17,52.47 104.24,52.47 102.54,50.77 v2(102.29,50.77) v1(101.73,50.2)
  BOTTOM w0.102: UC1.AJ8 101.97,50.45 v1(101.73,50.2)
AMON_ISL95520: length 69.4
  TOP w0.102: PR780.2 160.05,66.51 160.53,67 v2(161.75,67) 161.86,67 v1(163.51,65.35)
  IN1 w0.127: v1(163.51,65.35) 163.98,64.88 163.98,63.15 163.29,62.45 163.29,58.14 166.4,55.03 166.4,50.57 168.01,48.96 168.01,45.6 168.98,44.63 168.98,42.09 168.58,41.7 168.58,34.85 165.66,31.93 160.89,31.93 158.4,29.44 156.27,29.44 154.49,27.66 154.49,20.91 153.53,19.95 153.53,19.36 151.17,17 v1(151.17,16.07)
  BOTTOM w0.203: v1(151.17,16.07) 150.85,16.39 PU703.6
APDIN:
  vias: v3(16.11,151.02) v3(16.21,152.68) v3(17.06,154.23)
APU_ALERT#: length 11.2
  BOTTOM w0.102: RPC1.3 85.44,73.62 86.95,72.1 89.05,72.1 v2(89.43,71.73) 89.56,71.59 89.56,70.25 90.19,69.62 90.19,66.14 UC1.A30
APU_BT_OFF#: length 117.5
  TOP w0.102: v1(99.09,30.13) 98.96,30 RC41.2 ; v1(177.19,50) 177.22,50 178.92,48.3 v2(178.92,47.48) 178.92,43.14 R247.2
  IN1 w0.127: v1(99.09,30.13) 102.24,30.13 105.99,26.38 113.63,26.38 114.07,25.94 120.38,25.94 121.27,26.83 135.39,26.83 137.84,24.38 142.93,24.38 145.96,27.41 147.01,27.41 148.07,28.48 148.62,28.48 150.46,30.32 150.46,31.21 152.62,33.37 153.19,33.37 153.82,34 157.53,34 161.32,37.79 161.32,39.02 160.42,39.92 160.42,46.82 161.25,47.66 161.25,48.63 v1(161.42,48.8)
  BOTTOM w0.102: RC129.2 99.98,35.08 98.91,34.02 98.91,30.31 v1(99.09,30.13) ; v1(177.19,50) 177.14,49.95 166.17,49.95 165.88,50.25 163.15,50.25 161.7,48.8 v1(161.42,48.8)
APU_DBRDY: length 29.8
  TOP w0.102: v1(86.77,90.01) 87.4,89.37 JHDT1.14
  BOTTOM w0.102: v1(86.77,90.01) 87.13,89.65 v2(87.13,89.65) 87.13,89.65 87.24,89.54 88.26,89.54 89.1,88.71 89.1,82.16 93.69,77.56 93.69,69.5 92.38,68.19 92.38,66.32 92.42,66.27 UC1.A26
APU_DBREQ#: length 33.4
  TOP w0.102: RPC4.4 84.66,91.1 85.22,90.54 87.62,90.54 v1(87.87,90.29) 88.67,89.48 JHDT1.16
  BOTTOM w0.102: UC1.A25 92.97,68.02 94.2,69.25 94.2,77.88 90.45,81.63 90.45,82.6 89.55,83.5 89.55,89.04 v2(89,89.59) 88.52,90.07 88.08,90.07 v1(87.87,90.29)
APU_DGPU_PWRGD: length 3.6
  BOTTOM w0.102: RC164.1 v2(97.94,41.8) 97.65,42.09 97.65,43.35 97.92,43.62 UC1.BA16
APU_DP1_AUXN: length 122.5
  TOP w0.102: v1(23.13,107.03) 23.36,107.26 23.36,107.7 RH30.2
  IN2 w0.127: v1(23.13,107.03) 23.29,106.87 23.29,106.49 24.72,105.06 24.72,103.75 29.07,99.4 43.23,99.4 48.25,94.37 51.96,94.37 54.74,91.58 77.67,91.58 78.81,92.73 85.73,92.73 87.07,94.06 96.06,94.06 100.45,89.67 100.45,69.5 96.12,65.17 96.12,62.52 96.82,61.82 v1(96.82,61.77)
  BOTTOM w0.102: v1(96.82,61.77) 97.01,61.96 UC1.H17 ; v1(23.13,107.03) 22.82,107.33 22.82,108.3 22.36,108.76 QH15.4
APU_DP1_AUXP: length 123.5
  TOP w0.102: v1(23.71,107.03) 23.56,107.18 23.56,107.7 RH29.2
  IN2 w0.127: v1(23.71,107.03) 23.55,106.87 23.55,106.6 24.98,105.17 24.98,103.86 29.18,99.66 43.33,99.66 48.36,94.63 52.07,94.63 54.85,91.85 77.56,91.85 78.7,92.99 85.62,92.99 86.96,94.33 96.17,94.33 100.71,89.78 100.71,69.39 96.38,65.06 96.38,62.63 96.56,62.46 v1(96.83,62.46)
  BOTTOM w0.102: v1(23.71,107.03) 23.27,106.58 22.7,106.58 22.51,106.77 20.35,106.77 19.66,107.46 QH15.1 ; UC1.G17 97.23,62.76 96.93,62.46 v1(96.83,62.46)
APU_DP1_HPD: length 118.3
  TOP w0.102: v1(96.83,64.13) 97.25,64.55 97.25,65.18 96.09,66.34 96.09,68.6 96.42,68.93 96.42,71.09 96.87,71.53 v2(96.87,75.7) 96.87,76.42 v1(96.42,76.87)
  IN2 w0.127: v1(96.42,76.87) 95.91,77.37 95.91,84.93 93.25,87.6 90.71,87.6 90.45,87.34 72.63,87.34 70.15,84.87 53.95,84.87 48.49,90.33 46.36,90.33 41.37,95.31 24.21,95.31 21.05,98.47 21.05,105.74 21.24,105.93 v1(21.24,106.14)
  BOTTOM w0.102: QH5.3 23.64,107.8 24.15,107.29 RH137.1 23.89,106.14 v1(21.24,106.14) ; v1(96.83,64.13) 97.14,64.13 UC1.D17
APU_DP1_N0: length 108.5
  IN2 w0.127: v1(22.08,101.86) 23.17,101.86 27.85,97.19 42.19,97.19 47.2,92.18 50.06,92.18 54.07,88.17 70.38,88.17 71.48,89.26 89.51,89.26 90.08,89.83 94.95,89.83 98.31,86.47 98.31,75.32 97.69,74.71 97.69,71.62 98.04,71.28 99.48,71.28 99.8,70.95 v1(99.8,70.31)
  BOTTOM w0.102: CH20.1 21.62,101.67 21.89,101.67 v1(22.08,101.86) ; UC1.B14 99.33,66.04 99.33,66.18 99.26,66.33 99.26,66.58 99.96,67.29 99.96,68.77 99.61,69.13 99.61,70.12 v1(99.8,70.31)
APU_DP1_N1: length 108
  IN2 w0.127: v1(22.08,103.7) 22.24,103.54 23.04,103.54 28.57,98.01 42.51,98.01 47.55,92.97 51.39,92.97 54.16,90.21 78.53,90.21 79.22,90.91 87.42,90.91 88.25,91.73 94.31,91.73 99.1,86.94 99.1,74.53 98.61,74.03 98.61,72.74 98.81,72.53 98.81,71.86 v1(98.97,71.7)
  BOTTOM w0.102: UC1.B15 98.8,66.42 98.8,67.01 99.02,67.23 99.02,69.73 98.78,69.97 98.78,71.5 v1(98.97,71.7) ; v1(22.08,103.7) 21.89,103.51 21.62,103.51 CH18.1
APU_DP1_N2: length 105.2
  IN2 w0.127: v1(98.4,68.91) 98.4,69.69 96.89,71.2 96.89,75.12 97.51,75.73 97.51,86.08 94.84,88.75 90.22,88.75 89.9,88.43 71.93,88.43 70.85,87.35 53.48,87.35 49.45,91.38 46.79,91.38 41.81,96.36 27.54,96.36 23.73,100.18 22.24,100.18 v1(22.08,100.34)
  BOTTOM w0.102: v1(98.4,68.91) 98.4,68.62 98.56,68.46 98.56,67.37 98.36,67.17 98.36,66.79 98.15,66.58 98.15,66.35 98.23,66.19 98.23,66.01 UC1.B16 ; v1(22.08,100.34) 21.89,100.14 21.62,100.14 CH16.1
APU_DP1_N3: length 113.6
  IN2 w0.127: v1(99.14,72.83) 99.3,72.99 99.61,72.99 99.9,73.28 99.9,89.45 96.6,92.75 88.11,92.75 87.08,91.72 78.77,91.72 78.09,91.05 54.49,91.05 51.77,93.77 47.96,93.77 42.89,98.84 28.88,98.84 24.19,103.53 24.19,104.84 23.8,105.22 v1(22.08,105.22)
  BOTTOM w0.102: v1(22.08,105.22) 21.89,105.03 21.62,105.03 CH14.1 ; v1(99.14,72.83) 98.88,73.08 98.26,73.08 97.11,71.93 97.11,68.75 97.7,68.15 97.7,66.38 UC1.B17
APU_DP1_P0: length 108.5
  IN2 w0.127: v1(22.08,101.27) 22.16,101.19 22.4,101.19 22.52,101.32 22.52,101.48 22.64,101.59 23.06,101.59 27.74,96.92 42.08,96.92 47.09,91.91 49.95,91.91 53.96,87.9 70.49,87.9 71.59,88.99 89.62,88.99 90.19,89.57 94.84,89.57 98.04,86.37 98.04,75.43 97.43,74.82 97.43,71.51 97.93,71.01 99.37,71.01 99.53,70.85 99.53,70.64 99.21,70.32 v1(99.21,70.31)
  BOTTOM w0.102: UC1.A14 99.06,66.15 99.06,66.67 99.76,67.37 99.76,67.6 99.66,67.7 99.34,67.7 99.24,67.8 99.24,68 99.34,68.1 99.66,68.1 99.76,68.21 99.76,68.69 99.41,69.04 99.41,70.12 v1(99.21,70.31) ; CH19.1 21.62,101.47 21.89,101.47 v1(22.08,101.27)
APU_DP1_P1: length 107.9
  IN2 w0.127: v1(22.08,103.12) 22.08,103 22.24,102.84 22.47,102.84 22.56,102.93 22.56,103.18 22.66,103.28 22.93,103.28 28.46,97.75 42.4,97.75 47.44,92.71 51.28,92.71 54.05,89.95 78.64,89.95 79.33,90.64 87.53,90.64 88.36,91.47 94.2,91.47 98.84,86.83 98.84,74.64 98.34,74.14 98.34,72.63 98.55,72.42 98.55,71.86 v1(98.39,71.7)
  BOTTOM w0.102: v1(22.08,103.12) 21.89,103.31 21.62,103.31 CH17.1 ; v1(98.39,71.7) 98.11,71.7 98.01,71.59 98.01,71.26 98.12,71.15 98.48,71.15 98.58,71.05 98.58,69.89 98.82,69.64 98.82,67.32 98.6,67.09 98.6,66.59 UC1.A15
APU_DP1_P2: length 105.2
  IN2 w0.127: v1(22.08,99.75) 22.09,99.75 22.33,99.5 22.57,99.5 22.7,99.63 22.7,99.82 22.79,99.91 23.62,99.91 27.44,96.1 41.7,96.1 46.68,91.11 49.34,91.11 53.37,87.09 70.96,87.09 72.04,88.17 90.01,88.17 90.32,88.49 94.73,88.49 97.24,85.97 97.24,75.84 96.63,75.22 96.63,71.09 98.14,69.58 98.14,69.24 97.82,68.92 v1(97.82,68.91)
  BOTTOM w0.102: v1(97.82,68.91) 98.36,68.37 98.36,68.16 98.3,68.1 98.07,68.1 97.97,68 97.97,67.8 98.05,67.71 98.26,67.71 98.36,67.61 98.36,67.45 98.16,67.25 98.16,66.87 97.95,66.66 97.95,66.14 UC1.A16 ; CH15.1 21.62,99.94 21.89,99.94 v1(22.08,99.75)
APU_DP1_P3: length 113.6
  IN2 w0.127: v1(22.08,104.64) 22.09,104.64 22.41,104.96 22.63,104.96 22.76,104.83 22.76,104.52 22.83,104.45 23.1,104.45 23.23,104.57 23.23,104.83 23.36,104.96 23.69,104.96 23.92,104.73 23.92,103.42 28.77,98.57 42.78,98.57 47.85,93.51 51.66,93.51 54.38,90.79 78.2,90.79 78.87,91.46 87.19,91.46 88.22,92.49 96.49,92.49 99.64,89.34 99.64,73.39 99.5,73.25 99.3,73.25 v1(99.14,73.41)
  BOTTOM w0.102: CH13.1 21.62,104.83 21.89,104.83 v1(22.08,104.64) ; v1(99.14,73.41) 99.01,73.29 98.18,73.29 96.9,72.01 96.9,68.67 97.5,68.07 97.5,67.03 97.39,66.92 97.21,66.92 97.11,66.82 97.11,66.56 97.21,66.46 UC1.A17
APU_ENVDD: length 155.8
  TOP w0.102: v1(24.06,139.71) 28.65,139.71 30.48,141.53 30.48,142.08 33.54,145.14 R202.1 32.47,145.89 U202.4 ; v1(94.77,75.6) v2(95.53,75.6)
  IN2 w0.127: v1(94.77,75.6) 94.77,77.82 95.66,78.71 95.66,84.8 93.12,87.34 90.83,87.34 90.58,87.09 72.74,87.09 70.26,84.61 53.83,84.61 48.36,90.07 46.25,90.07 41.27,95.05 24.1,95.05 20.79,98.37 20.79,106.46 21.55,107.22 21.55,108.62 26,113.06 26,116.74 29.56,120.3 29.56,130.1 24.48,135.18 24.48,139.29 v1(24.06,139.71)
  BOTTOM w0.102: v1(94.77,75.6) RC20.2
APU_FCH_PWRGD_R: length 19.8
  TOP w0.102: v1(107.66,43.85) v2(107.66,43.13)
  IN1 w0.127: v1(107.66,43.85) 108.12,44.3 108.12,49.94 109.07,50.89 109.07,52.11 109.37,52.42 v1(109.37,53.03)
  BOTTOM w0.102: v1(109.37,53.03) 108.89,53.51 106.59,53.51 106.04,52.96 UC1.AE2 ; v1(107.66,43.85) 107.8,43.85 109.72,41.93 RC63.2 RC64.2 111.16,41.93 UC24.4
APU_INVT_PWM: length 122
  TOP w0.102: RC21.1 94.12,83.42 UC21.4 94.09,83.77 93.69,84.17 v1(92.17,84.17) ; v1(63.27,86.66) 63.27,93.57 v3(61.62,95.22) 58.51,98.33 56.25,98.33 52.15,102.43 v1(50.9,102.43)
  IN1 w0.127: v1(63.27,86.66) 63.58,86.96 88.1,86.96 90.9,84.17 v1(92.17,84.17)
  IN2 w0.127: v1(50.9,102.43) 51.16,102.68 51.16,104.16 50.57,104.74 50.57,105.91 51.36,106.7 51.36,114.01 50.69,114.69 50.69,116.31 47.73,119.27 47.73,136.36 39.71,144.38 27.79,144.38 26.15,146.02 26.15,148.41 v1(26.13,148.43)
  BOTTOM w0.102: v1(26.13,148.43) 25.87,148.69 JEDP1.8
APU_MA_VREFDQ: length 4.8
  BOTTOM w0.102: UC1.Y41 84.09,55.58 82.07,55.58 82.05,55.59 80.29,55.59 T1.1
APU_PCIE_RST#: length 413.5
  TOP w0.102: v2(97.58,108.4) 97.84,108.67 v1(98.1,108.67) ; v1(177.83,50) 177.83,49.78 179.25,48.35 179.25,42.64 R250.2
  IN1 w0.127: v1(98.1,108.67) 98.41,108.35 98.41,106.68 98.44,106.65 98.44,96.22 97.75,95.53 75.72,95.53 74.89,94.71 71.08,94.71 v1(70.7,95.09) ; v1(161.7,47.97) 163.41,46.26 163.41,45.45 164.21,44.65 164.21,41.04 162.33,39.16 162.33,37.37 157.96,32.99 154.65,32.99 149.13,27.46 148.62,27.46 144.52,23.36 137.42,23.36 134.97,25.81 121.82,25.81 120.93,24.92 113.38,24.92 112.93,25.37 105.25,25.37 102.07,28.54 92.86,28.54 91.91,29.49 85.94,29.49 84.71,30.73 v1(83.26,30.73)
  IN2 w0.127: v1(32.83,139.58) 32.21,138.96 28.48,138.96 25.53,141.9 21.81,141.9 20.74,142.97 20.74,147.99 21.67,148.91 36.91,148.91 44.45,156.46 50.45,156.46 v1(51.06,157.07)
  BOTTOM w0.102: v1(98.1,108.67) 98.1,113.09 103.98,118.97 105.44,118.97 106.07,119.6 106.07,123.6 105.82,123.86 105.31,123.86 104.93,124.24 UV2.2 104.93,125.38 105.12,125.57 106.23,125.57 106.58,125.93 106.58,144.42 100.38,150.61 88.08,150.61 87.47,151.22 83.99,151.22 83.54,151.67 78.64,151.67 78.2,151.22 69.73,151.22 67.34,153.61 59.24,153.61 55.78,157.07 v1(51.06,157.07) ; v1(32.83,139.58) 32.83,138.83 33.15,138.51 UL2.19 ; v1(161.7,47.97) 163.52,49.79 165.69,49.79 165.99,49.5 175.62,49.5 176.1,49.01 177.54,49.01 177.83,49.31 v1(177.83,50) ; v1(70.7,95.09) 70.74,95.05 70.74,77.92 65.47,72.65 65.47,39.74 68.27,36.94 68.27,32.31 69.01,31.56 77.16,31.56 78.58,32.99 81.82,32.99 82.07,33.24 82.58,33.24 83.01,32.81 RC73.2 83.26,32.16 v1(83.26,30.73) 83.26,30.63 82.69,30.05 UC23.4
APU_PCIE_RST#_R: length 34
  TOP w0.102: v1(103.73,51.3) 103.74,51.3 v2(104.28,51.84)
  IN1 w0.127: v1(103.73,51.3) 103.73,50.99 103.51,50.77 101.45,50.77 101.12,50.44 101.12,49.27 100.74,48.89 100.74,47.34 100.38,46.98 99.83,46.98 99.37,46.52 98.48,46.52 96.94,44.99 96.5,44.99 95.92,44.41 93.59,44.41 92.87,43.69 92.87,40.99 89.44,37.56 89.44,35.72 87.34,33.62 86.2,33.62 85.93,33.36 v1(85.93,32.55)
  BOTTOM w0.102: RC71.1 85.31,32.55 v1(85.93,32.55) ; UC1.AE4 104.37,52.61 104.01,52.25 104.01,51.71 103.73,51.43 v1(103.73,51.3)
APU_PCIE_WAKE#: length 1.8
  TOP w0.102: v1(103.43,53.51) 103.43,53.73 T31.1
  BOTTOM w0.102: v1(103.43,53.51) 102.88,52.96 UC1.AE7
APU_PWRGD: length 190.6
  TOP w0.102: v1(95.66,69.82) 95.66,69.26 v2(95.75,69.17) ; v1(84.86,90.14) JHDT1.10
  IN1 w0.127: v1(155.73,54.65) 154.76,54.65 154.33,55.08 154.33,55.4 152.83,56.9 144.52,56.9 143.92,57.5 134.27,57.5 132.11,55.34 132.11,53.69 128.74,50.32 128.74,46.19 127.28,44.73 126.2,44.73 125.69,45.24 119.22,45.24 114.05,50.41 114.05,52.38 113.25,53.18 110.64,53.18 109.37,51.91 109.37,50.84 108.37,49.84 108.37,43.9 107.84,43.36 105.22,43.36 104.75,42.89 102.81,42.89 101.36,44.34 97.78,44.34 96.79,43.35 96.79,42.78 96.4,42.38 95.37,42.38 94.73,41.75 94.73,37.56 94.41,37.24 91.36,37.24 v1(91.13,37.48)
  IN2 w0.127: v1(158.84,51.15) 159.98,51.15 162.33,48.8 162.33,46.83 161.39,45.89 161.39,41.27 v1(160.87,40.75) ; v1(95.66,69.82) 95.4,69.56 95.4,64.48 95.15,64.23 95.15,62.26 94.77,61.88 92.79,61.88 v1(92.46,62.21) 92.46,62.22 92.1,62.58 90.07,62.58 89.69,62.2 89.69,60.74 90.13,60.29 90.13,56.14 90.4,55.87 90.4,55.42 90.02,55.03 90.02,54.22 91.14,53.1 91.14,51.88 90.07,50.82 90.07,49.8 89.16,48.89 89.16,48.05 88.72,47.62 88.72,46.68 89.26,46.14 89.26,43.35 90.02,42.59 90.02,41.74 91.13,40.63 v1(91.13,37.48)
  BOTTOM w0.102: PU801.18 157.71,42.12 158.08,41.75 158.62,41.75 160,40.37 PR835.1 160.49,40.37 v1(160.87,40.75) ; v1(158.84,51.15) 158.6,51.15 157.15,52.59 157.15,53.54 156.03,54.65 v1(155.73,54.65) ; UC1.G25 92.46,62.25 v1(92.46,62.21) ; v1(84.86,90.14) 85.5,90.77 88.29,90.77 89.78,89.28 89.78,83.6 90.71,82.67 90.71,81.75 92.04,80.42 93.12,80.42 93.44,80.1 93.44,79.6 94.71,78.33 94.71,77.69 95.91,76.48 95.91,75.01 RC13.2 CC114.2 95.79,73 95.79,72.74 95.53,72.48 95.53,69.94 v1(95.66,69.82)
APU_RST#: length 46.1
  TOP w0.102: v1(90.24,64.24) 91.32,65.32 CC115.2 91.32,66.54 90.77,67.09 90.77,74.57 RC14.2 v2(86.01,75.39) 85.31,75.39 80.5,80.2 v1(80.5,80.42) ; JHDT1.12 v1(86.13,86.26)
  IN1 w0.127: v1(80.5,80.42) 80.5,83.36 82.2,85.06 84.93,85.06 v1(86.13,86.26)
  BOTTOM w0.102: UC22.4 78.72,88.79 78.97,88.54 RC30.1 79.72,86.18 80.55,84.08 80.55,80.47 v1(80.5,80.42) ; UC1.D29 90.65,64.24 v1(90.24,64.24)
APU_RST#_EC: length 126.2
  TOP w0.102: v1(175.97,60.92) U11.25 ; v1(76.1,94.45) v3(75.37,93.72)
  IN1 w0.127: v1(76.1,94.45) 76.46,94.81 95.76,94.81 110.83,79.74 110.83,78.73 113.31,76.25 115.38,76.25 117.68,73.95 122.43,73.95 127.5,68.88 139.59,68.88 139.92,68.55 165.89,68.55 168.02,66.42 168.02,64.4 168.72,63.69 173.2,63.69 v1(175.97,60.92)
  BOTTOM w0.102: v1(76.1,94.45) 78.07,92.49 UC22.2 78.07,90.33 78.32,90.07 79.02,90.07 79.64,89.45 RC30.2
APU_SCLK0: length 71.6
  IN2 w0.127: v1(34.78,23.53) 34.67,23.43 34.67,23.07 35.11,22.64 46.48,22.64 55.56,31.72 70.48,31.72 71.09,32.33 71.09,32.69 v1(70.98,32.8)
  BOTTOM w0.102: v1(34.78,23.53) 34.67,23.63 34.67,24.27 35.01,24.6 35.95,24.6 36.27,24.28 JDIMM1.253 ; UC1.AY33 88.74,44.39 88.74,44.15 88.95,43.93 88.95,42.92 88.87,42.83 88.87,40.93 88.22,40.28 85.63,40.28 83.38,38.04 82.17,38.04 81.61,37.48 81.61,37.08 RC163.1 81.61,36.64 81.61,36.21 80.23,34.83 72.11,34.83 71.1,33.83 71.1,32.92 v1(70.98,32.8)
APU_SDATA0: length 75.6
  IN2 w0.127: v1(71.58,32.8) 71.47,32.69 71.47,32.17 70.64,31.34 55.72,31.34 46.64,22.26 34.95,22.26 34.29,22.92 34.29,23.43 v1(34.19,23.53)
  BOTTOM w0.102: UC1.BA32 89.25,44.08 89.25,42.77 89.13,42.65 89.13,40.66 88.4,39.93 85.77,39.93 83.53,37.69 82.32,37.69 81.96,37.33 81.96,37.08 RC162.1 81.96,36.64 81.96,36.06 80.38,34.47 72.25,34.47 71.46,33.68 71.46,32.92 v1(71.58,32.8) ; JDIMM1.254 31.09,24.04 31.66,24.6 34,24.6 34.32,24.29 34.32,23.66 v1(34.19,23.53)
APU_SIC: length 30.9
  TOP w0.102: v1(88.8,71.72) v2(88.8,70.93)
  IN2 w0.127: v1(88.8,71.72) 88.75,71.77 88.75,75.2 86.26,77.69 85.75,77.69 84.55,78.9 82.77,78.9 82.2,79.47 82.2,81.63 v1(82.01,81.82)
  BOTTOM w0.102: QC2.4 81.06,82.32 81.56,81.82 v1(82.01,81.82) ; UC1.B30 90.22,65.66 89.91,65.98 89.91,66.25 89.97,66.32 89.97,69.43 89.31,70.1 89.31,71.21 v1(88.8,71.72) 86.83,71.72 84.94,73.61 RPC1.4
APU_SID: length 29.2
  TOP w0.102: v2(89.74,71.94) 89.31,72.37 v1(89.31,72.41)
  IN2 w0.127: v1(89.31,72.41) 89.13,72.59 89.13,75.39 86.26,78.26 v1(85.88,78.26)
  BOTTOM w0.102: v1(85.88,78.26) 84.8,79.34 84.8,84.68 83.2,86.28 QC2.1 ; UC1.B29 90.77,65.93 90.75,65.94 90.75,66.03 90.42,66.37 90.42,69.78 89.82,70.38 89.82,71.9 v1(89.31,72.41) 87,72.41 85.94,73.47 RPC1.2
APU_SPI_CLK: length 24.2
  BOTTOM w0.102: RC102.2 100.21,22.95 98.92,24.24 98.92,25.71 98.53,26.1 v2(98.53,29.24) 98.53,34.4 98.82,34.69 98.82,35.95 98.76,36.01 98.76,38.44 98.44,38.75 97.73,38.75 97.51,38.97 97.51,40.7 97.35,40.85 97.35,43.41 97.69,43.74 97.69,43.99 97.54,44.13 97.54,44.39 UC1.AY17
APU_SPI_CLK_R: length 15.4
  BOTTOM w0.102: RC102.1 101.64,17.52 100.8,16.68 96.09,16.68 v1(94.38,18.39) 94.06,18.71 UC2.6
APU_SPI_CS1#: length 31.6
  TOP w0.102: v1(97.02,26.74) 97.72,27.44 v3(97.72,28.75)
  BOTTOM w0.102: UC1.AY21 95.17,44.82 95.56,45.21 95.87,45.21 96.06,45.03 96.06,44.8 95.96,44.69 95.96,44.42 96.04,44.34 96.04,44.08 95.96,44 95.96,43.99 95.91,43.95 95.91,43.52 95.87,43.48 95.87,42.92 96.17,42.63 96.17,40.88 96.7,40.35 96.7,38.31 97.35,37.66 97.35,36.54 97.11,36.3 97.11,26.83 v1(97.02,26.74) 97.02,26.5 96.8,26.28 96.46,26.28 96.27,26.09 96.27,25.61 96.45,25.43 RPC11.6 97.36,25.43 98,24.79 98,22.41 99.15,21.25 UC2.1
APU_SPI_CS2#: length 20
  BOTTOM w0.102: RPC11.5 97.16,25.93 97.46,26.23 97.46,34.87 v2(97.72,35.13) 97.78,35.19 97.78,37.52 96.9,38.39 96.9,40.43 96.47,40.86 96.47,42.77 96.65,42.95 96.65,43.93 96.42,44.16 96.42,44.41 UC1.AY19
APU_SPI_HOLD#: length 31.5
  TOP w0.102: v2(99.23,27.4) 99.23,26.95 v1(97.82,25.54)
  IN2 w0.127: v1(97.82,25.54) 98.05,25.31 98.05,24.26 97.63,23.84 v1(96.56,23.84)
  BOTTOM w0.102: UC2.7 94.15,19.98 96.56,22.4 v1(96.56,23.84) 96.81,24.09 RPC11.8 ; v1(97.82,25.54) 97.82,34.72 98.06,34.96 98.06,37.56 97.11,38.51 97.11,40.52 96.87,40.76 96.87,44.17 96.82,44.21 UC1.BA18
APU_SPI_MISO: length 27.8
  TOP w0.102: v1(98.23,38.35) 97.83,37.95 v3(97.83,37.86)
  BOTTOM w0.102: UC1.BA17 97.08,43.57 97.08,40.84 97.31,40.61 97.31,38.74 97.7,38.35 v1(98.23,38.35) 98.45,38.13 98.45,34.85 98.17,34.57 98.17,25.95 98.57,25.56 98.57,24.07 101.18,21.46 101.18,20.22 100.94,19.98 UC2.2
APU_SPI_MOSI: length 32.3
  TOP w0.102: v1(96.12,38.82) v3(95.05,37.75)
  BOTTOM w0.102: UC2.5 91.98,17.44 91.72,17.7 91.72,26.19 94.52,28.99 94.52,31.11 95.99,32.58 95.99,38.69 v1(96.12,38.82) 95.71,39.22 95.71,40.65 95.72,40.66 95.72,42.49 95.46,42.75 95.46,43.64 95.48,43.67 95.48,43.99 95.37,44.1 95.37,44.31 95.72,44.66 UC1.AY20
APU_SPI_WP#: length 29.9
  TOP w0.102: v3(96.42,27.53) v1(96.42,26.73)
  IN2 w0.127: v1(97.58,24.63) 96.42,25.79 v1(96.42,26.73)
  BOTTOM w0.102: v1(96.42,26.73) 96.42,27.64 96.74,27.96 96.74,36.53 96.75,36.54 96.75,37.97 96.5,38.22 96.5,40.26 95.96,40.8 95.96,42.54 95.67,42.84 95.67,43.56 95.71,43.6 95.71,44.03 95.72,44.05 UC1.BA20 ; RPC11.7 97.28,24.93 v1(97.58,24.63) 97.58,20.36 99.23,18.71 UC2.3
APU_SPKR: length 137.4
  TOP w0.102: v1(8.73,35.91) v3(8.73,35.07)
  IN1 w0.127: v1(16.41,17.11) 17,16.53 56.19,16.53 57.81,18.15 57.81,20.29 56.8,21.3 56.8,29.34 62.29,34.83 79.66,34.83 82.51,37.69 82.51,38.51 84.04,40.04 86.9,40.04 87.34,39.59 89.92,39.59 90.52,40.19 90.52,41.02 89.97,41.57 89.97,42.42 89.63,42.77 89.63,46.54 89.78,46.7 89.78,47.49 v1(90.27,47.98)
  IN2 w0.127: v1(16.41,17.11) 16.41,16.1 15.93,15.61 8.7,15.61 7.01,17.3 7.01,26.83 6.7,27.14 4.85,27.14 4.35,27.65 4.35,30.57 8.41,34.64 8.41,35.59 v1(8.73,35.91)
  BOTTOM w0.102: UC1.AP29 90.39,47.98 v1(90.27,47.98) ; RA55.1 v1(8.73,35.91)
APU_SVC: length 15
  TOP w0.102: v1(92.87,74.21) v2(92.87,74.82)
  IN2 w0.127: v1(92.42,64.24) 92.83,64.65 92.83,69.46 93.51,70.15 93.51,73.57 v1(92.87,74.21)
  BOTTOM w0.102: UC1.E27 91.87,63.69 v1(92.42,64.24) ; RPC14.2 91.17,75.85 92.2,74.82 PR833.2 92.47,74.82 92.87,74.42 v1(92.87,74.21)
APU_SVD: length 14.1
  TOP w0.102: v1(92.86,73.63) v2(92.2,73.63)
  IN2 w0.127: v1(92.86,73.63) 93.26,73.23 93.26,70.34 92.41,69.49 92.41,66.41 91.34,65.34 91.34,64.93 v1(91.46,64.8)
  BOTTOM w0.102: UC1.D27 91.46,64.76 v1(91.46,64.8) ; v1(92.86,73.63) 92.61,73.63 92.28,73.96 PR829.2 91.54,74.64 91.54,75.01 91.21,75.35 RPC14.3
APU_SVT: length 132.5
  TOP w0.102: v1(91.53,76.29) 91.82,76 v2(91.82,75.66)
  IN1 w0.127: v1(92.67,86.77) 95.07,86.77 99.5,82.34 99.5,79.57 103.45,75.62 105.83,75.62 110.8,70.66 111.47,70.66 114.05,68.08 118.63,68.08 124.22,62.49 133.16,62.49 133.83,61.82 136.15,61.82 136.44,62.11 138.86,62.11 138.96,62.01 151.28,62.01 152.42,60.86 154.99,60.86 156.87,58.98 156.87,57.65 157.44,57.07 157.44,50 157.95,49.5 158.96,49.5 159.65,48.8 159.65,40.95 v1(159.02,40.31)
  IN2 w0.127: v1(92.67,86.77) 91.91,86.01 91.91,85.06 92.36,84.61 92.67,84.61 93.82,83.47 93.82,79.91 91.02,77.12 91.02,76.8 v1(91.53,76.29) 91.53,75.47 91.72,75.28 91.72,66.13 90.9,65.31 90.9,64.17 91.12,63.94 92.01,63.94 v1(92.42,63.53)
  BOTTOM w0.102: v1(159.02,40.31) 159.02,38.61 PC819.1 PR824.2 ; UC1.H27 91.87,62.25 92.42,62.8 v1(92.42,63.53)
  BOTTOM w0.127: v1(91.53,76.29) 91.48,76.35 RPC14.1
APU_TCK: length 39.8
  TOP w0.102: RPC4.1 80.47,91.53 v3(80.29,91.35) 80.15,91.22 80.15,89.93 79.78,89.57 JHDT1.2 79.78,87.34 81.12,86.01 84.61,86.01 v1(84.86,86.26)
  BOTTOM w0.102: UC1.B27 91.87,66.01 91.57,66.32 91.57,66.58 91.62,66.63 91.62,70.68 91.02,71.28 91.02,73.26 90.2,74.08 89.41,74.08 88.61,74.88 88.61,81.45 88.41,81.65 88.41,86.4 88.04,86.77 87.28,86.77 86.26,85.76 85.37,85.76 v1(84.86,86.26)
APU_TDI: length 40.1
  TOP w0.102: JHDT1.6 82.32,89.37 83.09,90.14 v1(84.16,90.14) RPC4.3 84.16,91.85 84.41,92.09 84.9,92.09 85.69,92.88 v3(85.69,94.2)
  BOTTOM w0.102: UC1.B25 92.97,66.01 92.64,66.35 92.64,68.05 93.94,69.36 93.94,77.69 89.32,82.31 89.32,88.8 88.33,89.79 87.68,89.79 87.02,90.45 86.45,90.45 85.73,89.73 84.57,89.73 v1(84.16,90.14)
APU_TDO: length 30.8
  TOP w0.102: JHDT1.8 83.59,87.28 84.1,86.77 84.99,86.77 v1(85.5,86.26) ; v1(89.05,78.15) v3(88.15,78.15)
  BOTTOM w0.102: v1(85.5,86.26) 85.5,86.83 86.07,87.41 88.1,87.41 88.64,86.87 88.64,81.83 89.05,81.41 v1(89.05,78.15) 88.92,78.01 88.92,74.91 89.51,74.31 90.32,74.31 91.28,73.36 91.28,71.4 91.87,70.81 UC1.A27
APU_TEST0: length 7.5
  BOTTOM w0.102: RC38.2 RC34.2 111.41,51.85 110.95,52.3 109.13,52.3 v2(108.83,52.6) 108.68,52.76 107.03,52.76 106.91,52.64 106.34,52.64 106.26,52.72 105.99,52.72 105.67,52.41 UC1.AF2
APU_TEST1: length 9.9
  BOTTOM w0.102: v2(114.59,54.37) RC36.2 114.51,53.24 RC39.2 113.57,52.3 112.79,52.3 112.61,52.48 111.09,52.48 110.96,52.61 109.25,52.61 108.9,52.96 UC1.AE1
APU_TEST2: length 5.2
  TOP w0.102: v1(102.21,53.51) v2(102.8,52.93) 105.51,52.93 RC40.2 105.83,53.24 106.12,53.24 RC35.2
  BOTTOM w0.102: v1(102.21,53.51) 101.97,53.75 UC1.AC8
APU_TEST4: length 3.2
  TOP w0.102: T2.1 89.6,63.39 89.49,63.28 89.49,62.79 v1(89.16,62.46)
  BOTTOM w0.102: UC1.H29 90.37,62.36 89.25,62.36 v1(89.16,62.46)
APU_TEST5: length 2
  TOP w0.102: v1(90.24,63.6) 90.52,63.88 90.72,63.88 T3.1
  BOTTOM w0.25: v1(90.24,63.6) 90.24,63.48 90.77,62.94 UC1.G29
APU_TEST6: length 1.6
  TOP w0.102: T4.1 93.94,62.93 v1(93.5,62.49)
  BOTTOM w0.102: UC1.H25 93.29,61.96 93.5,62.17 v1(93.5,62.49)
APU_TEST9: length 1.1
  TOP w0.102: v1(89.19,59.01) 89.18,58.99 T5.1
  BOTTOM w0.102: UC1.R32 89.17,58.88 89.19,58.9 v1(89.19,59.01)
APU_TEST10: length 1.5
  TOP w0.102: T6.1 89.99,60.17 v1(89.6,60.17)
  BOTTOM w0.102: UC1.N32 89.17,59.96 89.38,60.17 v1(89.6,60.17)
APU_TEST14: length 12.7
  TOP w0.102: v1(94.64,63.01) 94.59,63.01 94.2,63.4 94.2,65.12 93.82,65.5 93.82,66.26 94.01,66.45 95.02,66.45 T7.1 95.57,67 95.57,68.72 95.21,69.08 95.21,71.93 94.66,72.48 RPC2.5
  BOTTOM w0.102: v1(94.64,63.01) 94.92,63.01 UC1.G21
APU_TEST15: length 2.2
  TOP w0.102: v1(95.7,61.4) 95.7,62.6 T8.1
  BOTTOM w0.102: v1(95.7,61.4) 95.66,61.44 95.63,61.44 95.17,61.91 UC1.H21
APU_TEST16: length 13.3
  TOP w0.102: RPC2.6 95.16,73.43 95.02,73.56 94.52,73.56 94.33,73.37 94.33,72.14 T9.1 94.85,68.97 95.33,68.48 95.33,67.2 94.83,66.71 93.88,66.71 93.56,66.39 93.56,65.37 93.94,64.99 93.94,64.57 v1(93.53,64.15)
  BOTTOM w0.102: UC1.D23 93.86,64.15 v1(93.53,64.15)
APU_TEST17: length 10.9
  TOP w0.102: v1(94.61,63.6) 94.84,63.6 95.53,64.29 95.53,65.37 95.84,65.68 95.84,68.72 96.12,69.01 96.12,70.45 T10.1 95.6,70.97 95.6,72.23 95.65,72.29 RPC2.7
  BOTTOM w0.102: v1(94.61,63.6) 94.57,63.56 UC1.E23
APU_TEST18: length 34.6
  TOP w0.102: v1(87.98,86.2) 90.64,86.2 91.21,86.77 JHDT1.20 91.21,91.04 90.15,92.11 87.4,92.11 87.22,91.92 RPC3.2
  BOTTOM w0.102: UC1.A28 91.32,66.97 91.26,67.02 T11.1 91.26,70.72 90.77,71.21 90.77,73.18 90.1,73.86 89.28,73.86 88.36,74.78 88.36,81.09 87.98,81.48 v1(87.98,86.2)
APU_TEST19: length 31.6
  TOP w0.102: v1(87.34,86.2) 87.78,86.64 89.31,86.64 89.94,87.28 JHDT1.18 89.94,89.5 89.37,90.07 88.8,90.07 87.72,91.16 RPC3.3
  BOTTOM w0.102: UC1.B28 91.32,65.66 90.96,66.03 90.96,66.22 91.11,66.37 91.11,66.77 90.88,67 90.88,70.1 90.77,70.21 T12.1 90.77,70.83 90.52,71.09 90.52,73.06 89.94,73.63 89.18,73.63 88.12,74.69 88.12,80.74 87.34,81.51 v1(87.34,86.2)
APU_TEST28_H: length 1.2
  TOP w0.102: T13.1 102.77,59.1 v1(102.35,59.1)
  BOTTOM w0.102: UC1.N8 101.97,59.49 v1(102.35,59.1)
APU_TEST28_L: length 1.3
  TOP w0.102: T14.1 101.62,59.46 v1(101.62,59.07)
  BOTTOM w0.102: UC1.N10 101.62,59.11 v1(101.62,59.07)
APU_TEST31: length 1.9
  TOP w0.102: T16.1 88.7,62.73 88.7,62.09 v1(88.97,61.83)
  BOTTOM w0.102: v1(88.97,61.83) 89.54,61.83 UC1.H31
APU_TEST36: length 4.9
  TOP w0.102: v2(91.33,67.45) RC25.1 RC26.1 93.09,65.92 93.09,65.25 v1(93.53,64.81)
  BOTTOM w0.102: v1(93.53,64.81) 93.42,64.81 UC1.D25
APU_TEST41: length 2.6
  TOP w0.102: v1(89.31,67.54) 89.31,67.61 88.87,68.04 T18.1
  BOTTOM w0.102: UC1.B31 89.67,66.01 89.31,66.37 v1(89.31,67.54)
APU_TMS: length 38
  TOP w0.102: JHDT1.4 81.05,89.82 81.37,90.14 v1(82.01,90.14) 82.01,90.42 81.89,90.53 81.89,90.91 v3(81.92,90.94) 81.98,91 83.51,91 83.66,91.16 RPC4.2
  BOTTOM w0.102: v1(82.01,90.14) 83.4,90.14 85.88,87.66 88.23,87.66 88.87,87.02 88.87,82.01 93.44,77.44 93.44,69.67 92.12,68.36 92.12,66.81 92.17,66.76 92.17,66.33 92.1,66.26 92.1,65.98 92.42,65.66 UC1.B26
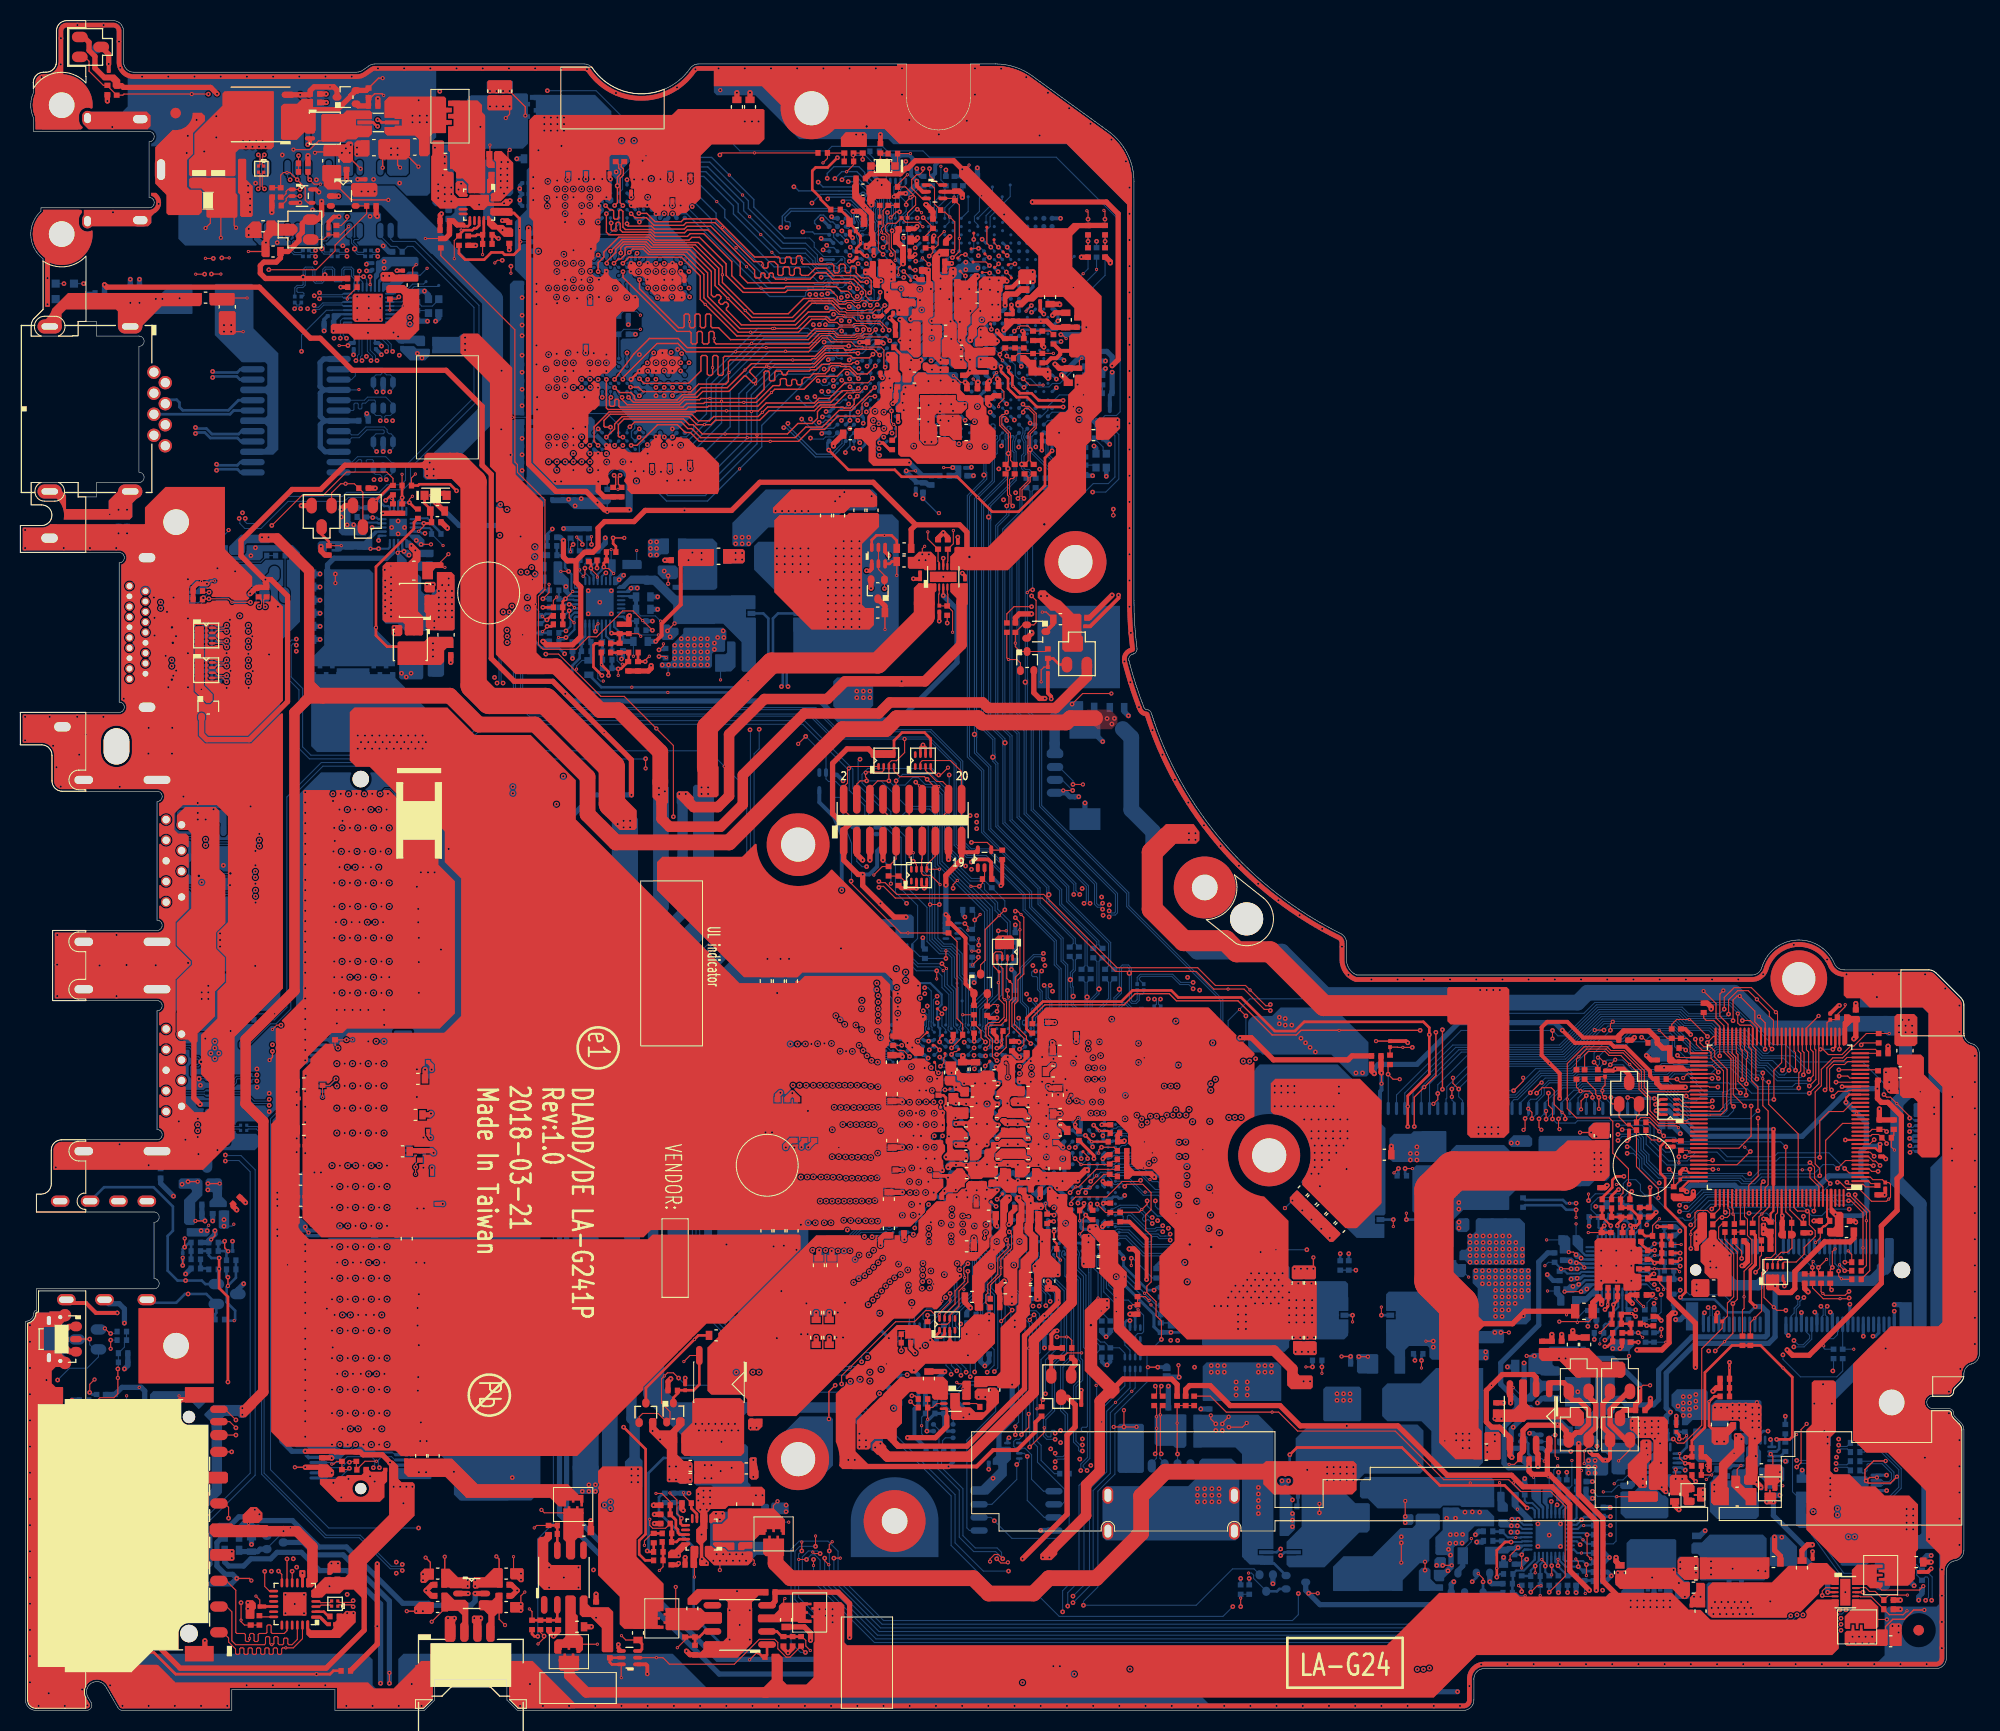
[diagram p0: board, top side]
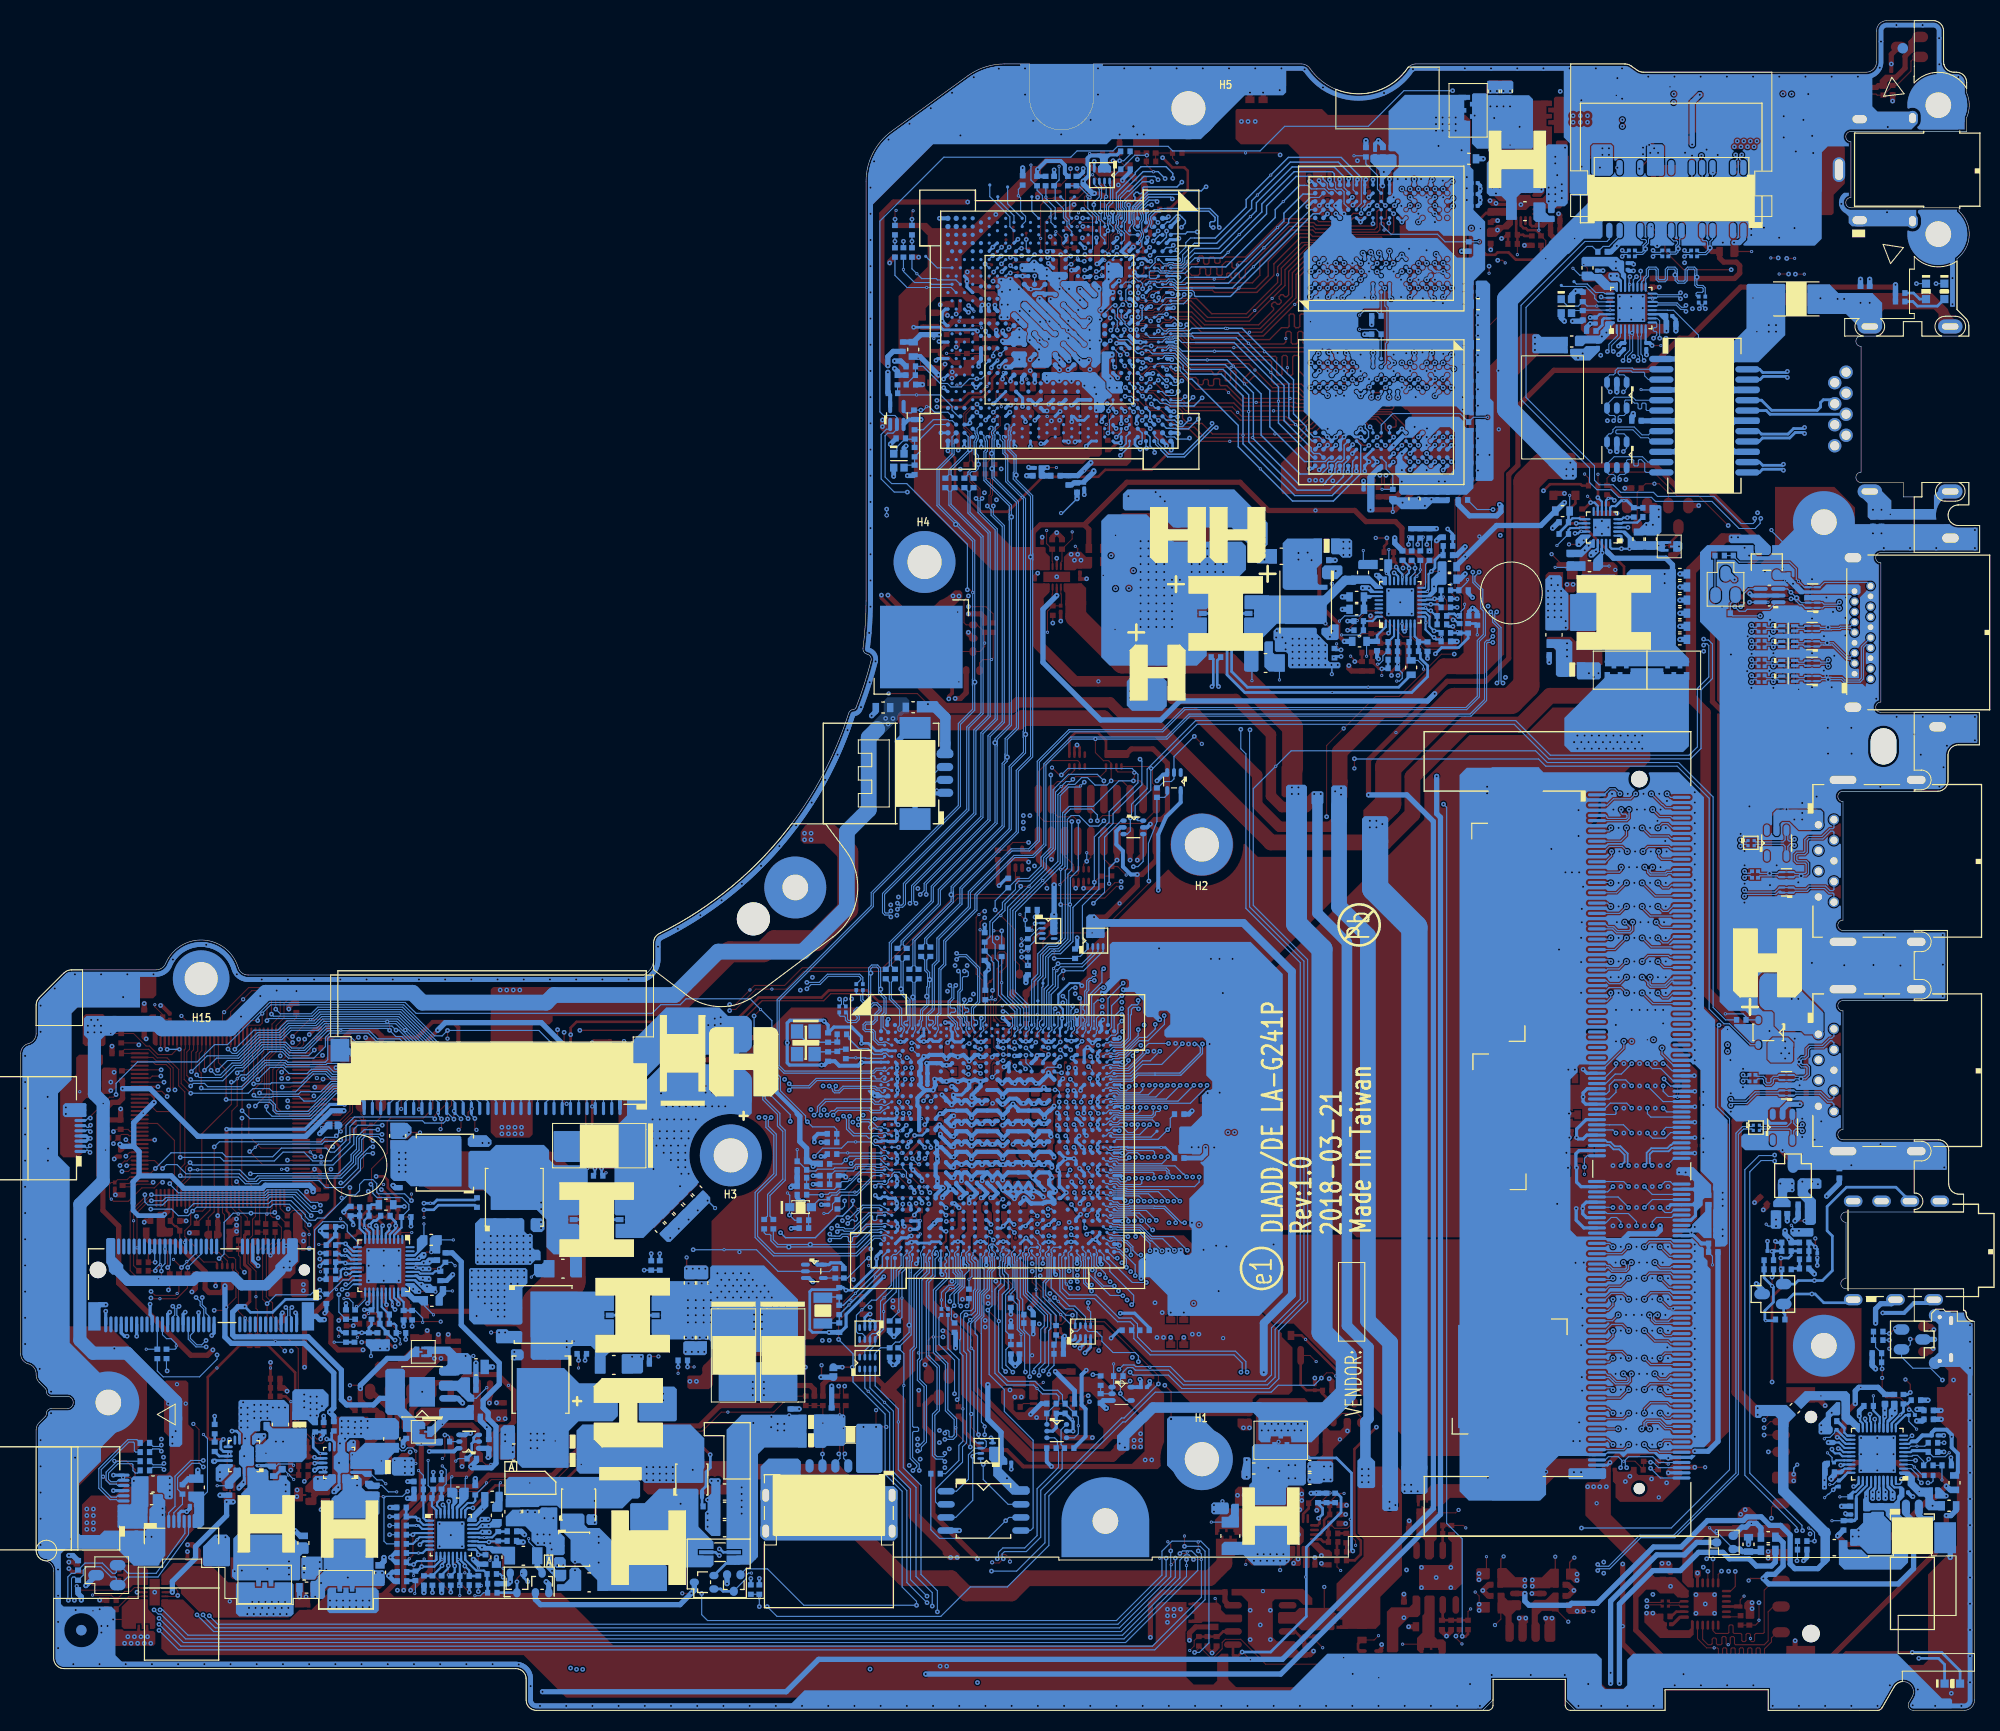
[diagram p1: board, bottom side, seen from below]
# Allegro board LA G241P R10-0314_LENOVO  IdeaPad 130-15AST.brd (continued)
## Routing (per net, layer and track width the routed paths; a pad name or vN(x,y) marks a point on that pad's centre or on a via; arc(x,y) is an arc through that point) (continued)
APU_TRST#: length 40.9
  TOP w0.102: RPC3.4 88.22,91.23 88.74,90.71 v1(88.99,90.71) 89.18,90.71 v3(89.89,91.42) ; v1(85.79,80.31) 85.19,80.9 CC7.1 84.14,80.9 RC27.1
  BOTTOM w0.102: UC1.A29 90.66,66.57 90.66,69.94 90.26,70.34 90.26,72.99 89.88,73.37 89.05,73.37 87.86,74.57 87.86,77.87 85.79,79.94 v1(85.79,80.31) 85.79,84.7 84.36,86.14 84.36,87.15 81.56,89.95 81.56,90.77 82.13,91.34 88.36,91.34 v1(88.99,90.71)
APU_TRST#_R: length 4.5
  TOP w0.102: JHDT1.9 84.86,82.57 RC27.2 83.53,81.83 v2(82.7,81.01)
APU_VDD_RUN_FB_L: length 104
  TOP w0.102: v1(90.39,79.72) 90.39,80.08 v2(90.79,80.48)
  TOP w0.254: v1(155.41,51.78) 154.65,51.78 154.28,51.41 154.28,50.7 153.3,49.72 PR827.1
  IN1 w0.127: v1(155.41,51.78) 156.15,52.52 156.15,56.5 153.89,58.77 151.23,58.77 149.27,60.74 138.39,60.74 138.29,60.84 136.97,60.84 136.49,60.36 128.89,60.36 128.02,61.22 123.69,61.22 119.02,65.89 118.19,65.89 117.27,66.81 113.48,66.81 110.9,69.39 110.26,69.39 105.29,74.35 102.85,74.35 96.53,80.68 91.34,80.68 v1(90.39,79.72)
  IN2 w0.127: v1(90.39,79.72) 90.39,78.88 90.15,78.63 90.15,75.19 90.96,74.38 90.96,67.44 88.49,64.97 88.49,64.46 v1(88.08,64.05)
  BOTTOM w0.127: v1(88.08,64.05) 88.39,64.36 UC1.D33
APU_VDD_SEN: length 103.5
  TOP w0.127: v1(89.08,64.82) 89.08,65.18 T15.1
  TOP w0.254: PR814.1 156,50.14 v1(156.17,50.32)
  IN1 w0.127: v1(91.59,81.88) 91.59,81.37 91.91,81.06 96.51,81.06 102.96,74.61 105.4,74.61 110.36,69.65 111.01,69.65 113.59,67.06 117.38,67.06 118.29,66.15 119.12,66.15 123.8,61.47 128.13,61.47 128.99,60.61 136.38,60.61 136.87,61.09 138.42,61.09 138.52,60.99 149.53,60.99 151.5,59.02 153.99,59.02 156.4,56.61 156.4,50.55 v1(156.17,50.32)
  IN2 w0.127: v1(89.08,64.82) 89.08,65.18 91.21,67.31 91.21,74.46 90.4,75.28 90.4,78.53 91.09,79.22 91.09,81.37 v1(91.59,81.88)
  BOTTOM w0.127: v1(89.08,64.82) 89.54,64.36 UC1.D31
APU_VDDNB_SEN: length 121.2
  TOP w0.127: T19.1 88.63,64.5 v1(89.08,64.04)
  TOP w0.254: PR808.2 v1(156.81,35.7)
  IN1 w0.127: v1(92.17,81.56) 96.38,81.56 103.08,74.86 105.52,74.86 110.48,69.9 111.13,69.9 113.72,67.32 117.48,67.32 118.4,66.4 119.23,66.4 123.9,61.73 128.24,61.73 129.1,60.86 136.28,60.86 136.76,61.35 138.55,61.35 138.65,61.24 150.61,61.24 151.76,60.1 154.42,60.1 154.78,59.74 154.78,58.59 156.68,56.69 156.68,48.99 158.05,47.62 158.05,46.4 158.89,45.56 158.89,43.07 158.65,42.83 158.19,42.83 157.44,42.09 157.44,39.46 158.04,38.87 158.04,36.86 157.38,36.2 157.3,36.2 v1(156.81,35.7)
  IN2 w0.127: v1(92.17,81.56) 91.4,80.8 91.4,79.17 90.67,78.43 90.67,75.38 91.47,74.58 91.47,66.88 89.54,64.95 89.54,64.51 89.08,64.05 v1(89.08,64.04)
  BOTTOM w0.125: v1(89.08,64.04) 88.6,63.56 UC1.E33
APU_VDDP_RUN_FB_H: length 68.2
  TOP w0.102: v1(94.65,49.56) 94.96,49.87 94.96,49.88 T61.1
  TOP w0.254: v1(58.45,27.46) 60.58,25.33 60.58,17.09 59.96,16.46 59.96,15.13 60.54,14.55 PR2222.2
  IN1 w0.127: v1(94.65,49.56) 94.65,49.56 93.06,47.97 92.67,47.97 91.79,47.08 91.79,45.52 90.44,44.17 90.26,43.99 90.26,43.03 90.6,42.69 90.6,41.85 91.15,41.31 91.15,39.88 90.2,38.93 87.82,38.93 84.23,35.34 80.74,35.34 79.78,34.38 62.51,34.38 58.45,30.32 v1(58.45,27.46)
  BOTTOM w0.102: UC1.AM21 95.15,49.16 94.75,49.56 v1(94.65,49.56)
APU_WL_OFF#: length 112.9
  TOP w0.102: R248.2 178.59,43.64 v2(178.59,44.85) 178.59,48.25 177.42,49.42 v1(177.19,49.42)
  IN1 w0.127: v1(99.34,30.7) 102.26,30.7 106.33,26.64 113.76,26.64 114.2,26.19 120.28,26.19 121.48,27.4 143.47,27.4 143.89,26.98 145.09,26.98 145.77,27.67 146.9,27.67 147.97,28.73 148.49,28.73 150.21,30.45 150.21,31.34 152.49,33.62 153.06,33.62 153.7,34.26 157.43,34.26 161.06,37.89 161.06,38.8 160.16,39.71 160.16,47.73 v1(160.81,48.38)
  BOTTOM w0.102: v1(177.19,49.42) 176.1,49.42 175.8,49.73 166.08,49.73 165.79,50.02 163.3,50.02 161.66,48.38 v1(160.81,48.38) ; RC130.2 100.85,38.11 100.85,35.48 99.34,33.96 v1(99.34,30.7)
ASGATE_CHG: length 277.3
  TOP w0.102: v1(17.83,139.27) v2(16.97,139.27)
  TOP w0.508: PR762.2 v1(29.61,156.75)
  IN1 w0.127: v1(148.94,19.93) 148.94,21.68 148.43,22.19 148.43,25.27 149.51,26.35 149.51,27.12 154.8,32.42 158.1,32.42 162.74,37.05 164.38,37.05 165.04,37.71 165.04,38.64 164.72,38.96 164.72,44.87 163.98,45.6 163.98,46.45 162.46,47.97 162.46,48.93 161.76,49.62 161.38,49.62 157.95,53.05 157.95,57.33 157.41,57.88 157.41,59.19 155.22,61.37 152.67,61.37 151.53,62.51 139.18,62.51 139.07,62.62 136.23,62.62 135.94,62.32 134.04,62.32 133.37,63 124.43,63 118.84,68.59 114.31,68.59 111.72,71.17 111.01,71.17 106.04,76.13 103.66,76.13 100.01,79.78 100.01,82.55 94.58,87.98 90.14,87.98 89.64,87.47 59.35,87.47 59.24,87.36 51.65,87.36 42.48,96.52 42.48,115.56 41.24,116.81 41.24,129.25 40.35,130.14 31.12,130.14 21.53,139.73 18.29,139.73 v1(17.83,139.27)
  IN2 w0.127: v1(29.61,156.75) 29.12,156.25 19.05,156.25 17.83,155.03 v1(17.83,139.27)
  BOTTOM w0.203: v1(148.94,19.93) 148.93,19.93 148.77,19.77 PU703.30
ASGATE_CHG_R: length 11.9
  TOP w0.381: PQ712.4 28.05,152.06 v1(27.84,151.84)
  TOP w0.508: PQ740.4 v1(27.1,156.67) 28,156.67 PR762.1 28.08,157.07 28.44,157.44 v2(29.99,157.44) 30.35,157.44 30.67,157.12 PQ707.1
  BOTTOM w0.508: v1(27.1,156.67) 27.84,155.93 v1(27.84,151.84)
B+: length 106.5
  TOP w1.524: 121.06,23.14 110.96,23.14 108.61,20.79 108.61,17.18 104.26,12.82 99.67,12.82 98.19,11.33 93.83,11.33 92.34,12.82 74.62,12.82 73.18,14.25 73.18,15.71
  TOP w2.032: 111.13,84.65 109.69,83.22 109.69,77.69 112.74,74.64 116.8,74.64 117.88,73.56 121.11,73.56 126.33,68.34 138.94,68.34 138.95,68.33
  TOP w4.064: 142.27,58.89 142.27,67.15
  vias: v1(36.92,100.58) v1(37.38,100.21) v1(37.85,100.58) v1(37.98,154.64) v1(37.98,154) v1(38.68,154.64) v1(38.68,154) v1(39.38,154.64) v1(39.38,154) v1(61.05,113.31) v1(61.05,112.68) v1(61.05,112.04) v1(61.65,113.31) v1(61.65,112.68) v1(61.65,112.04) v1(113.25,85.06) v1(113.25,84.42) v1(113.88,85.06) v1(113.88,84.42) v1(126.65,23.59) v1(126.65,22.95) v1(126.65,22.32) v1(127.28,23.59) v1(127.28,22.95) v1(127.28,22.32) v1(127.92,23.59) v1(127.92,22.95) v1(127.92,22.32) v1(128.55,23.59) v1(128.55,22.95) v1(128.55,22.32) v1(129.19,23.59) v1(129.19,22.95) v1(129.19,22.32) v1(141.32,56.55) v1(141.32,55.91) v1(141.48,69.86) v1(141.95,56.55) v1(141.95,55.91) v1(142.12,69.86) v1(142.59,56.55) v1(142.59,55.91) v1(142.75,69.86) v1(143.22,56.55) v1(143.22,55.91) v1(143.39,69.86) v1(151.98,24.22) v1(151.98,23.61) v1(151.98,23.02) v1(152.62,24.22) v1(152.62,23.61) v1(152.62,23.02) v1(160.66,29.51) v1(161.17,30.42) v1(161.17,29.81) v1(161.17,29.2) v1(161.17,28.59) v1(161.78,30.42) v1(161.78,29.81) v1(161.78,29.2) v1(161.78,28.59) v1(162.38,30.62) v1(162.38,29.99) v1(162.38,29.38) v3(38.59,156.14) v3(124.72,23.32)
B+_1.35V:
  vias: v3(44.57,153.56)
BA: length 18.5
  TOP w0.102: v1(124.85,11.35) v3(125.73,11.35)
  BOTTOM w0.508: PD703.2 139.97,10.75 139.47,10.25 125.95,10.25 v1(124.85,11.35) 124.57,11.64 PQ710.1
BATT_CHG_LED#: length 228.5
  TOP w0.102: U11.90 161.38,53.72 v1(161.35,53.69)
  IN1 w0.127: v1(4.2,138.35) 4.66,137.89 6.38,137.89 7.9,139.41 14.68,139.41 16.72,141.46 25.68,141.46 27.47,143.24 38.36,143.24 42.13,139.47 42.13,134.87 41.43,134.17 41.43,130.5 42.95,128.98 42.95,120.93 44.07,119.82 44.07,97.49 51.94,89.63 54.17,89.63 55.06,90.52 68.49,90.52 69.95,89.06 89.03,89.06 89.95,89.98 95.46,89.98 107.14,78.31 107.14,77.23 111.67,72.69 113.76,72.69 116.34,70.11 121.23,70.11 126.44,64.9 133.68,64.9 134.74,63.85 135.31,63.85 135.6,64.14 139.71,64.14 139.81,64.04 155.02,64.04 156.99,62.07 157.38,62.07 159.81,59.64 159.81,58.07 161.35,56.54 v1(161.35,53.69)
  BOTTOM w0.102: LED3.1 v1(4.2,138.35) ; v1(161.35,53.69) v2(161.81,54.15)
BATT_LOW_LED#: length 229.4
  TOP w0.102: v1(164.04,52.47) 163.99,52.52 U11.93
  IN1 w0.127: v1(164.04,52.47) 164.49,52.93 164.49,54.11 160.32,58.28 160.32,59.85 157.59,62.58 157.2,62.58 155.23,64.55 140.02,64.55 139.92,64.65 135.18,64.65 134.67,65.16 126.54,65.16 121.33,70.37 116.45,70.37 113.87,72.95 111.78,72.95 107.39,77.33 107.39,78.41 95.57,90.24 89.85,90.24 88.92,89.31 70.05,89.31 68.59,90.77 54.95,90.77 54.06,89.88 52.04,89.88 44.33,97.6 44.33,119.92 43.21,121.04 43.21,129.08 41.68,130.61 41.68,134.02 42.38,134.71 42.38,139.67 38.55,143.5 27.37,143.5 25.58,141.71 16.53,141.71 14.54,139.73 7.48,139.73 v1(6.1,138.35)
  BOTTOM w0.102: v1(164.04,52.47) v2(164.58,52.47) ; LED4.1 v1(6.1,138.35)
BEEP#: length 259.5
  TOP w0.102: v1(175.67,59.53) 176.18,60.04 177.09,60.04 177.17,60.12 U11.23 ; v3(8.17,37.04) 8.66,36.54 v1(8.73,36.54)
  IN1 w0.127: v1(136.56,4.11) 139.53,7.08 167.06,7.08 173.07,13.09 173.07,20.14 173.7,20.78 173.7,24.67 172.75,25.62 172.75,34.76 176.43,38.45 176.43,41.18 174.84,42.77 174.84,51.4 175.06,51.62 175.06,58.92 v1(175.67,59.53)
  IN2 w0.127: v1(136.56,4.11) 136.01,4.65 109.11,4.65 108.4,5.36 95.47,5.36 93.75,3.65 62.07,3.65 61.31,4.41 54.64,4.41 52.86,6.19 21.3,6.19 18.25,9.24 8.39,9.24 5.28,12.35 3.94,12.35 1.96,14.34 1.96,28.78 7.97,34.79 7.97,35.84 8.66,36.54 v1(8.73,36.54)
  BOTTOM w0.102: RA41.1 9.16,36.54 v1(8.73,36.54)
BEEP_N: length 10.7
  TOP w0.102: v1(9.43,33.11) v3(9.43,32.24) 9.43,30.7 9.04,30.32 7.67,30.32 6.81,29.46 v1(6.81,29.16)
  BOTTOM w0.102: v1(9.43,33.11) 9.48,33.16 RA47.1 CA43.1 10.06,35.22 10.06,35.7 RA55.2 RA41.2 ; v1(6.81,29.16) 6.67,29.16 6.25,28.75 CA69.2
BGATE_CHG: length 32.3
  TOP w0.254: v1(146.03,19.63) 143.85,21.81 137.57,21.81 v2(135.53,23.85) 133.89,25.49 123.73,25.49 v1(123.03,24.8)
  BOTTOM w0.203: v1(146.03,19.63) 146.53,19.63 146.77,19.39 PU703.25
  BOTTOM w0.254: v1(123.03,24.8) 123.01,24.78 123.01,23.54 123.43,23.12 123.43,21.75 123.82,21.37 PQ705.4 123.82,19.88 PC779.1
BKOFF#: length 219.3
  TOP w0.102: U11.105 167.5,50.91 168.43,51.83 168.43,56.8 168.42,56.81 v1(168.42,57.43) ; v1(46.69,140.62) 46.22,140.62 v2(45.96,140.37) ; R204.1 25.4,146.74 25.73,147.07 25.73,147.31 25.91,147.49 U203.1 v1(27.08,147.49)
  IN1 w0.127: v1(168.42,57.43) 167.03,57.43 166.56,57.9 166.56,59.26 166.29,59.53 166.29,64.48 162.86,67.91 139.34,67.91 139.01,68.24 127.23,68.24 122.16,73.31 117.42,73.31 115.11,75.62 113.05,75.62 110.24,78.43 110.2,78.47 110.2,79.48 95.5,94.18 80.74,94.18 80.22,93.65 52.73,93.65 48.58,97.81 48.58,105.15 48.45,105.29 48.45,107.99 47.14,109.3 47.14,113.14 47.98,113.98 47.98,118.28 47.46,118.8 47.46,138.65 46.69,139.43 v1(46.69,140.62)
  IN2 w0.127: v1(46.69,140.62) 44.56,140.62 39.37,145.81 28.76,145.81 v1(27.08,147.49)
BP_0: length 3.5
  BOTTOM w0.102: UV1.U1 89.58,145.71 90.49,146.62 v2(90.49,146.74) 90.49,147.82 RV82.1
BP_1: length 7
  BOTTOM w0.102: v2(91.94,149.85) 91.94,148.4 91.38,147.85 RV81.1 91.34,147.41 90.83,146.9 90.83,146.43 90,145.59 90,144.31 UV1.U3
BST1_APU: length 1.5
  BOTTOM w0.102: PR803.1 v2(150.78,47.17)
BST1_APU_R: length 1.5
  BOTTOM w0.102: PR803.2 v2(147.92,45.62)
BST1_VGA: length 1.5
  BOTTOM w0.102: 57.24,111.03 v2(57.24,112.57)
BST1_VGA_R: length 1.5
  BOTTOM w0.102: 59.72,110.96 v2(59.72,112.48)
BST_1.35V_R: length 0.9
  TOP w0.102: PC901.1 45.41,150.96 45.49,151.03 v2(45.49,151.8)
BST_3V: length 2.1
  BOTTOM w0.102: v2(154.47,21.98) 154.84,22.34 155.32,22.34 155.88,22.9 PR401.1
BST_3V_R: length 2.2
  BOTTOM w0.102: PC401.1 154.85,21.82 154.22,21.19 v2(153.42,21.19)
BST_5V: length 2.2
  BOTTOM w0.102: PR408.1 165.15,23.64 164.9,23.89 163.54,23.89 v2(163.41,23.77)
BST_5V_R: length 1.5
  BOTTOM w0.102: v2(163.4,22.4) 164.43,23.42 PC418.1
BST_CHG:
  vias: v2(145.09,19.51)
BST_CHG_R: length 1.4
  BOTTOM w0.102: v2(143.36,22.08) 143.47,21.96 PR771.2
BST_DDR: length 1.2
  BOTTOM w0.102: PR501.2 v2(35.89,110.96)
BST_DDR_R: length 1.7
  BOTTOM w0.102: v2(41.13,110.84) 39.84,110.84 39.59,111.09 PC505.1
BST_NB: length 1.7
  BOTTOM w0.102: v2(149.85,38.36) 150.71,39.22 PR841.1
BST_NB_R: length 1
  BOTTOM w0.102: PC825.1 148.77,40.67 v2(148.01,40.67)
BT_DISABLE_R: length 4
  TOP w0.102: R247.1 v1(176.81,42.63) 176.32,43.13 v2(176.32,43.21)
  BOTTOM w0.102: v1(176.81,42.63) 176.81,42.87 176.37,43.32 JWLAN1.54
BT_OFF#: length 7
  BOTTOM w0.102: RC129.1 100.22,39.17 100.22,40.44 v2(99.75,40.91) 99.42,40.91 99.01,41.32 99.01,42.31 99.23,42.53 99.23,43.97 99.34,44.08 99.34,44.34 99.02,44.66 UC1.AY14
CAPS_LED#: length 39.4
  TOP w0.102: U11.91 163.97,53.32 v1(164.01,53.36) ; v1(134.9,64.29) v2(133.99,64.29) 133.5,64.29 133.48,64.32 C271.1 R274.1
  IN1 w0.127: v1(134.9,64.29) 135.39,64.29 135.5,64.39 139.81,64.39 139.91,64.29 155.12,64.29 157.09,62.32 157.48,62.32 160.06,59.74 160.06,58.18 164.01,54.23 v1(164.01,53.36)
CAPS_LED#_R: length 5.7
  TOP w0.102: R274.2 132.55,62.44 v1(132.55,61.69) 133.04,61.21 v3(133.68,61.21)
  BOTTOM w0.102: JKB1.2 132.57,61.67 v1(132.55,61.69)
CCLIM_CHG: length 3.8
  TOP w0.102: v1(149.02,14.03) v2(149.02,14.65)
  BOTTOM w0.203: PU703.11 148.77,14.41 149.02,14.15 v1(149.02,14.03) 149.02,13.98 PR750.2
  BOTTOM w0.254: PR752.1 PR750.2
CLK_PCIE_LAN: length 153.7
  IN2 w0.127: v1(28.97,136.89) 29.15,137.06 30.71,137.06 31.37,136.41 35.43,136.41 36.09,135.74 37.73,135.74 38.16,135.32 38.16,133.77 42.94,128.98 42.94,116.32 45.48,113.78 45.48,104.12 51.91,97.69 53.49,97.69 55.6,95.59 75.07,95.59 76.04,96.55 83.98,96.55 84.92,97.49 97.61,97.49 108.67,86.43 108.67,73.5 110,72.18 110,71.03 110.94,70.09 110.94,68.58 109.81,67.45 109.81,62.79 111.14,61.45 111.14,61.18 111.02,61.05 110.81,61.05 110.68,60.93 110.68,60.72 v1(110.85,60.54)
  BOTTOM w0.102: UC1.M2 106.04,60.41 106.26,60.41 106.41,60.36 106.85,60.36 107.01,60.52 110.16,60.52 110.59,60.09 110.89,60.09 110.97,60.16 110.97,60.43 v1(110.85,60.54) ; UL2.15 31.29,136.98 31.19,137.08 29.16,137.08 v1(28.97,136.89)
CLK_PCIE_LAN#: length 153.7
  IN2 w0.127: v1(28.97,137.47) 29.11,137.33 30.82,137.33 31.48,136.67 35.54,136.67 36.2,136.01 37.84,136.01 38.42,135.43 38.42,133.88 43.21,129.09 43.21,116.43 45.75,113.89 45.75,104.23 52.02,97.96 53.6,97.96 55.7,95.85 74.97,95.85 75.93,96.82 83.87,96.82 84.81,97.76 97.72,97.76 108.94,86.54 108.94,73.61 110.26,72.29 110.26,71.14 111.2,70.2 111.2,68.47 110.07,67.34 110.07,62.9 111.41,61.56 111.41,60.62 v1(111.49,60.54)
  BOTTOM w0.102: v1(28.97,137.47) 29.16,137.28 31.17,137.28 31.27,137.38 UL2.16 ; v1(111.49,60.54) 111.17,60.23 111.17,60.08 110.98,59.89 110.51,59.89 110.08,60.32 107.1,60.32 106.93,60.15 106.63,60.15 106.37,59.88 106.22,59.88 106.12,59.98 UC1.M1
CLK_PCIE_WLAN: length 91.4
  IN2 w0.127: v1(174.51,39.19) 174.51,39.36 174.61,39.46 174.79,39.46 174.86,39.53 174.86,39.77 174.69,39.93 174.13,39.93 173.25,39.05 171.9,39.05 171.45,39.5 171.45,45.95 169.91,47.5 169.91,51.78 168.56,53.12 167.74,53.12 164.02,56.84 163.19,56.84 158.47,61.56 157.29,61.56 156.36,62.49 155.19,62.49 153.59,64.09 139.27,64.09 138.59,63.42 136.37,63.42 135.21,62.26 120.98,62.26 119.22,60.5 115.73,60.5 v1(115.37,60.14)
  BOTTOM w0.102: v1(115.37,60.14) 115.14,60.37 113.39,60.37 112.68,61.08 107.41,61.08 107.36,61.03 106.48,61.03 106.25,60.91 105.96,60.91 105.78,61.01 UC1.K2 ; JWLAN1.47 174.62,38.21 174.73,38.32 174.73,38.97 v1(174.51,39.19)
CLK_PCIE_WLAN#: length 91.5
  IN2 w0.127: v1(175.12,39.19) 175.12,39.88 174.8,40.2 174.02,40.2 173.14,39.31 172.01,39.31 171.72,39.61 171.72,46.06 170.17,47.6 170.17,51.88 168.67,53.38 167.85,53.38 164.13,57.1 163.3,57.1 158.58,61.83 157.4,61.83 156.47,62.76 155.3,62.76 153.7,64.36 139.16,64.36 138.48,63.68 136.26,63.68 135.1,62.52 120.87,62.52 119.11,60.76 v1(115.37,60.76)
  BOTTOM w0.102: UC1.K1 106,61.33 106,61.43 106.09,61.52 106.26,61.52 106.56,61.23 106.93,61.23 107.03,61.33 107.03,61.43 107.14,61.53 107.34,61.53 107.44,61.43 107.44,61.33 107.49,61.28 112.76,61.28 113.47,60.57 115.18,60.57 v1(115.37,60.76) ; JWLAN1.49 175.12,38.16 174.93,38.35 174.93,39 v1(175.12,39.19)
CLK_PEG_VGA: length 83.2
  BOTTOM w0.102: UC1.H2 105.67,62.31 105.97,62.01 105.99,62.01 105.99,62.01 106.25,62.01 106.25,62.01 106.27,62.01 106.33,62.07 106.89,62.07 107.17,61.79 115.88,61.79 116.54,62.45 116.54,68.91 107.42,78.03 107.42,79.3 98.97,87.74 98.97,95.69 97.59,97.08 97.59,99.4 97.61,99.43 97.61,100 97.59,100.02 97.59,113.37 v4(99.23,115.01) 101.04,116.82 101.04,120.4 99.59,121.86 99.59,123.48 UV1.AK30
CLK_PEG_VGA#: length 81.1
  BOTTOM w0.102: UV1.AK32 99.39,122.89 99.39,121.77 100.84,120.32 100.84,116.91 99.31,115.37 99.25,115.37 98.87,114.99 98.87,114.94 97.39,113.45 v4(97.39,99.71) 97.39,96.99 98.77,95.61 98.77,87.66 107.22,79.21 107.22,77.94 116.34,68.82 116.34,62.54 115.79,61.99 107.25,61.99 106.97,62.27 106.16,62.27 UC1.H1
CLK_REQ3#: length 17.5
  IN1 w0.127: v1(86.38,39.54) 86.74,39.18 90.07,39.18 90.9,40.01 90.9,41.18 90.35,41.72 90.35,42.58 90.01,42.92 90.01,44.1 90.73,44.82 90.73,48.18 v1(90.27,48.63)
  BOTTOM w0.102: RPC12.5 86.15,38.64 86.38,38.87 v2(86.38,39.01) v1(86.38,39.54) ; UC1.AP31 89.94,48.63 v1(90.27,48.63)
CMOS_ON#: length 208.4
  TOP w0.102: R201.1 31.08,144 31.65,144.57 v1(31.65,144.85) ; U11.34 v1(176.3,64.11) ; v1(47.53,140.05) v2(47.53,139.36)
  IN1 w0.127: v1(47.53,140.05) 48.1,139.48 48.1,119.09 48.62,118.57 48.62,113.58 48.03,113 48.03,109.95 49.89,108.09 49.89,106.88 49.09,106.08 49.09,98.02 52.65,94.45 75.02,94.45 75.76,95.19 97.28,95.19 111.72,80.76 111.72,79.1 113.68,77.14 115.75,77.14 118.05,74.84 122.8,74.84 127.87,69.77 140.1,69.77 140.43,69.44 166.26,69.44 170.96,64.74 175.67,64.74 176.29,64.11 v1(176.3,64.11)
  IN2 w0.127: v1(47.53,140.05) 44.67,140.05 39.41,145.31 32.11,145.31 v1(31.65,144.85)
CMOS_ON#_R: length 4.2
  TOP w0.102: Q201.2 29.36,142.64 C204.1 29.89,143.08 R201.2 31,143.08 v2(31.8,143.88)
CMSRC_CHG: length 274.2
  TOP w0.102: v1(18.49,139.29) v2(19.41,139.29)
  TOP w0.508: PR763.2 v1(29.63,155.92)
  IN1 w0.127: v1(18.49,139.29) 21.62,139.29 31.02,129.89 40.22,129.89 40.99,129.12 40.99,116.68 42.23,115.44 42.23,96.39 51.53,87.09 59.4,87.09 59.53,87.22 89.74,87.22 90.25,87.72 94.47,87.72 99.75,82.45 99.75,79.68 103.55,75.88 105.94,75.88 110.9,70.92 111.6,70.92 114.18,68.33 118.73,68.33 124.32,62.74 133.26,62.74 133.94,62.07 136.05,62.07 136.34,62.36 138.97,62.36 139.07,62.26 151.38,62.26 152.52,61.12 155.09,61.12 157.13,59.09 157.13,57.75 157.7,57.18 157.7,52.93 161.25,49.37 161.66,49.37 162.14,48.88 162.14,47.91 163.73,46.32 163.73,45.5 164.47,44.76 164.47,40.84 162.59,38.96 162.59,37.26 158,32.67 154.69,32.67 149.25,27.23 149.25,26.45 148.17,25.38 148.17,22.09 148.37,21.89 v1(148.37,20.26)
  IN2 w0.127: v1(18.49,139.29) 18.09,139.69 18.09,154.93 19.16,156 29.56,156 v1(29.63,155.92)
  BOTTOM w0.203: PU703.29 v1(148.37,20.26)
COMP_APU: length 4.6
  TOP w0.102: v2(152.21,47.85) PR807.2
  TOP w0.203: PR807.2 153.3,47.84 154.14,47.01 v1(154.14,47)
  TOP w0.254: PR807.2 PC813.2
  BOTTOM w0.203: v1(154.14,47) 154.14,46.56 154.47,46.23 PU801.5
COMP_CHG: length 5
  TOP w0.102: v2(150.75,14.67) 150.99,14.43 v1(150.99,13.94)
  BOTTOM w0.203: v1(150.99,13.94) 149.76,13.94 149.17,14.53 PU703.10
  BOTTOM w0.254: PC751.1 152.36,13.51 PR754.1 151.42,13.51 v1(150.99,13.94)
COMP_NB: length 4.1
  TOP w0.254: PR810.1 PC809.1 153.88,39.2 153.82,39.15 153.82,39.12 v1(153.58,38.87)
  BOTTOM w0.203: PU801.27 154.07,39.9 153.84,39.67 v2(153.84,39.39) 153.84,39.13 v1(153.58,38.87)
COMP_VGA: length 4.7
  BOTTOM w0.102: PR1028.2 57.36,102.71 57.83,102.24 57.83,101.8 58.18,101.45 v2(58.33,101.45)
  BOTTOM w0.203: PC1024.2 56.74,104.18 PU1001.3
  BOTTOM w0.254: PC1024.2 PR1028.2
CORE_NB_GATE: length 19.5
  TOP w0.102: RC150.2 144.81,23.86 v2(144.29,23.86)
  TOP w0.508: UC26.1 148.17,31.53 148.43,31.78 149.57,31.78 150.07,31.29 QC19.2 150.07,30.46 150.46,30.07 151.07,30.07 151.98,29.15 151.98,27.74 151.2,26.95 150.79,26.95 QC18.2 149.82,26.56 149.82,27.08 149.25,27.65 146.14,27.65 145.63,27.14 UC26.6 145.63,25.11 145.3,24.78 RC150.2
CPVEE: length 3
  BOTTOM w0.102: CA70.1 14.2,24.03 14.28,24.11 14.28,24.53 v2(14.72,24.97)
  BOTTOM w0.203: CA70.1 13.88,24.25 13.1,24.25 13.09,24.24 UA1.27
CS_DDR: length 3.8
  BOTTOM w0.102: v2(40.95,112.96) PR502.2
  BOTTOM w0.203: PU501.13 38.76,114.71 38.83,114.65 39.65,114.65 39.83,114.47 PR502.2
CSIN_CHG: length 5.3
  BOTTOM w0.102: PR740.2 149.08,21.52 148.62,21.98 148.62,23.32 v2(149,23.7)
  BOTTOM w0.203: PC747.2 149.09,20.55 149.5,20.14 149.5,19.85 149.17,19.51 PU703.31
  BOTTOM w0.254: PR740.2 149.08,20.59 PC747.2
CSIN_CHG_R: length 284.6
  TOP w0.102: v1(18.67,140.8) 17.92,140.8 v2(17.91,140.81)
  TOP w0.254: v1(34.61,154.24) 34.73,154.24 34.99,153.99 PR703.3
  IN1 w0.254: v1(149.08,23.09) 149.32,23.33 149.32,25.65 149.89,26.22 149.89,26.95 155.03,32.1 158.23,32.1 162.81,36.67 164.45,36.67 165.36,37.58 165.36,38.79 165.04,39.11 165.04,45 164.3,45.74 164.3,46.64 162.84,48.1 162.84,50.48 162.11,51.21 160.97,51.21 160.49,51.69 160.49,52.52 159.86,53.15 159.86,54.16 160.1,54.4 160.1,55.02 159.79,55.33 159.79,57.02 159.03,57.78 159.03,59.43 157.09,61.37 156.62,61.37 154.65,63.34 139.52,63.34 139.42,63.44 135.89,63.44 135.6,63.15 134.43,63.15 133.37,64.21 126.15,64.21 120.94,69.41 116.05,69.41 113.47,72 111.35,72 106.39,76.95 106.39,78.01 95.43,88.97 89.92,88.97 89.25,88.3 69.94,88.3 54.49,88.3 53.96,88.82 51.68,88.82 43.37,97.12 43.37,119.18 41.56,121 41.56,129.38 40.73,130.21 40.73,134.46 41.43,135.16 41.43,139.19 38.1,142.51 27.98,142.51 25.83,140.37 19.11,140.37 v1(18.67,140.8)
  IN2 w0.254: v1(34.61,154.24) 33.41,155.44 19.34,155.44 18.4,154.5 18.4,141.07 v1(18.67,140.8)
  BOTTOM w0.254: PR740.1 v1(149.08,23.09)
CSIP_CHG: length 5.7
  BOTTOM w0.102: v2(150.37,24.24) 150.37,21.8 150.01,21.44 PR772.2
  BOTTOM w0.203: PC747.1 150,19.82 149.57,19.39 PU703.32
  BOTTOM w0.254: PR772.2 149.88,20.71 PC747.1
CSIP_CHG_R: length 284.4
  TOP w0.102: v1(19.5,140.85) v2(20.22,140.85)
  TOP w0.254: v1(34.61,153.61) 34.54,153.61 34.16,153.99 PR703.2
  IN1 w0.254: v1(19.5,140.85) 25.78,140.85 27.82,142.89 38.26,142.89 41.81,139.34 41.81,135 41.11,134.31 41.11,130.37 41.94,129.54 41.94,121.19 43.75,119.37 43.75,97.28 51.78,89.25 54.51,89.25 55.46,90.2 68.35,90.2 69.81,88.74 89.16,88.74 89.77,89.35 95.62,89.35 106.77,78.2 106.77,77.15 111.54,72.38 113.63,72.38 116.21,69.79 121.1,69.79 126.3,64.59 133.53,64.59 134.58,63.53 135.44,63.53 135.73,63.82 139.57,63.82 139.68,63.72 154.84,63.72 156.81,61.75 157.24,61.75 159.41,59.58 159.41,57.94 160.17,57.18 160.17,55.48 160.48,55.18 160.48,54.25 160.24,54.01 160.24,53.35 160.87,52.71 160.87,51.85 161.13,51.59 162.27,51.59 163.22,50.64 163.22,48.29 164.68,46.83 164.68,45.89 165.43,45.14 165.43,39.29 165.74,38.98 165.74,37.42 164.59,36.28 162.95,36.28 158.39,31.72 155.22,31.72 150.27,26.76 150.27,26.07 149.7,25.49 149.7,23.27 v1(149.88,23.09)
  IN2 w0.254: v1(34.61,153.61) 34.32,153.61 32.87,155.06 19.5,155.06 18.79,154.35 18.79,141.56 v1(19.5,140.85)
  BOTTOM w0.254: PR772.1 v1(149.88,23.09)
CSON_CHG: length 3.9
  BOTTOM w0.102: PR776.1 v2(147.3,11.14)
  BOTTOM w0.203: PU703.14 147.57,14.43 147.3,14.15 PC708.2
  BOTTOM w0.254: PC708.2 PR776.1
CSON_CHG_R: length 33
  TOP w0.102: v1(146.38,11.46) 147.02,12.1 v2(147.37,12.1)
  IN2 w0.254: v1(146.38,11.46) 145.81,12.03 143.05,12.03 142.64,11.63 134.46,11.63 133.2,10.36 123.81,10.36 122.77,11.4 122.77,15.08 122.2,15.65 v1(122.14,15.65)
  BOTTOM w0.254: v1(122.14,15.65) 122.07,15.65 121.76,15.33 PR765.3 ; PR776.2 v1(146.38,11.46)
CSOP_CHG: length 3.8
  TOP w0.102: v1(146.81,14) v2(146.81,13.34)
  BOTTOM w0.203: PC708.1 146.38,13.57 v1(146.81,14) 146.81,14.15 147.17,14.51 PU703.15
  BOTTOM w0.254: PR742.1 145.52,13.04 PC708.1
CSOP_CHG_R: length 31
  TOP w0.102: v1(145.51,11.52) 145.51,11.79 v2(145.2,12.1)
  IN2 w0.254: v1(122.14,15.02) 122.33,14.83 122.33,11.27 123.62,9.98 133.36,9.98 134.62,11.25 142.81,11.25 143.22,11.65 145.38,11.65 v1(145.51,11.52)
  BOTTOM w0.102: PR742.2 v1(145.51,11.52)
  BOTTOM w0.254: v1(122.14,15.02) 122.2,15.02 122.52,15.33 PR765.2
CUST_TEMP1: length 102
  TOP w0.102: U11.73 163.63,60.52 163.71,60.44 v1(164.52,60.44) ; v1(118.26,10.06) v2(118.26,10.89)
  IN1 w0.127: v1(164.52,60.44) 164.4,60.33 164.4,57.75 166.91,55.24 166.91,50.78 168.52,49.17 168.52,45.81 169.48,44.84 169.48,41.88 169.09,41.49 169.09,34.41 166.1,31.42 161.1,31.42 158.61,28.93 156.48,28.93 155,27.45 155,16.76 153.29,15.05 153.29,13.91 151.54,12.16 151.54,11.17 150.48,10.11 140.03,10.11 139.31,9.4 118.93,9.4 v1(118.26,10.06)
  BOTTOM w0.102: R366.1 R364.2 v1(118.26,10.06)
CUST_TEMP2: length 157.4
  TOP w0.102: v1(157.13,65.27) 157.22,65.27 R365.2 ; v1(161.44,59.58) 161.71,59.32 U11.76
  IN1 w0.127: v1(47.14,116.45) 47.14,115.66 46.02,114.54 46.02,103.4 47.56,101.85 47.56,97.38 53.17,91.78 69.22,91.78 69.66,91.33 87.91,91.33 88.18,91.6 95.46,91.6 108.28,78.78 108.28,77.7 112.15,73.84 114.24,73.84 116.82,71.26 121.7,71.26 126.51,66.45 138.22,66.45 138.6,66.07 147.4,66.07 147.97,65.5 155.03,65.5 155.2,65.66 156.73,65.66 v1(157.13,65.27) 158.65,65.27 160.02,63.9 160.02,61 v1(161.44,59.58)
  BOTTOM w0.102: R367.1 48.68,116.45 v1(47.14,116.45)
CUST_TEMP3: length 56.8
  TOP w0.102: v1(160.61,63.52) 160.81,63.32 U11.66
  TOP w0.127: v1(137.19,65.75) 137.19,61.56 v3(136.06,60.43) 135.09,59.47 v1(135.09,56.61)
  IN2 w0.127: v1(160.61,63.52) 159.9,64.23 155.98,64.23 154.98,65.23 154.98,66.04 154.57,66.45 147.86,66.45 147.35,65.94 138.52,65.94 138.14,65.56 137.38,65.56 v1(137.19,65.75) ; v1(129.43,42.69) 129.43,44.3 128.68,45.05 128.68,51.34 133.44,56.1 134.58,56.1 v1(135.09,56.61)
  BOTTOM w0.127: v1(129.43,42.69) R369.1 R368.2
DDR_A_ALERT#: length 4.7
  TOP w0.102: v1(30.57,61.23) 29.95,60.61 RD201.2 v2(29.27,59.46)
  BOTTOM w0.102: v1(30.57,61.23) 30.57,61.16 29.94,60.54 JDIMM1.116
DDR_A_CKE0: length 64.1
  IN1 w0.102: 79.91,65.51 81.92,65.51 84.78,62.65 86.13,62.65 v1(86.36,62.42)
  IN1 w0.211: v1(34.46,64.88) 34.92,64.41 36.72,64.41 37.4,65.09 57.58,65.09 57.8,64.88 57.8,64.54 58.01,64.33 58.43,64.33 58.64,64.54 58.64,64.88 58.85,65.09 59.27,65.09 59.48,64.88 59.48,64.54 59.69,64.33 60.11,64.33 60.33,64.54 60.33,64.88 60.54,65.09 60.96,65.09 61.17,64.88 61.17,64.54 61.38,64.33 61.8,64.33 62.01,64.54 62.01,64.88 62.22,65.09 62.64,65.09 62.86,64.88 62.86,64.54 63.07,64.33 63.49,64.33 63.7,64.54 63.7,64.88 63.91,65.09 64.33,65.09 64.54,64.88 64.54,64.54 64.75,64.33 65.17,64.33 65.38,64.54 65.38,64.88 65.6,65.09 66.02,65.09 66.37,64.74 74.08,64.74 74.43,65.09 76.13,65.09 76.55,65.51 79.91,65.51
  BOTTOM w0.102: JDIMM1.109 36.38,62.29 34.46,64.2 v1(34.46,64.88) ; UC1.J38 85.97,62.04 v1(86.36,62.42)
DDR_A_CKE1: length 64.2
  IN1 w0.102: v1(88.27,62.33) 87.59,63.01 85.04,63.01 82.55,65.49
  IN1 w0.211: 82.55,65.49 82.55,65.62 81.27,66.9 80.78,66.9 80.42,66.53 80.42,66.44 80.05,66.07 77.52,66.07 77.33,66.26 61.59,66.26 60.88,65.55 33.49,65.55 v1(30.65,62.72)
  BOTTOM w0.102: JDIMM1.110 29.79,62.04 30.47,62.72 v1(30.65,62.72) ; v1(88.27,62.33) 88.37,62.23 UC1.J34
DDR_A_CLK0: length 67.7
  IN1 w0.102: 84.03,53.43 84.03,53.43 84.04,53.44 84.12,53.44 84.59,53.91 85.52,53.91 85.7,54.09 87.37,54.09 87.77,54.5 v1(87.77,54.61)
  IN1 w0.211: v1(33.99,52.83) 34.21,53.05 34.21,53.31 34.65,53.75 35.9,53.75 36.39,53.26 37.33,53.26 37.68,53.61 41.4,53.61 41.84,53.17 41.84,52.49 42.05,52.28 42.68,52.28 42.9,52.49 42.9,53.17 43.33,53.61 44.29,53.61 44.73,53.17 44.73,52.49 44.94,52.28 45.57,52.28 45.78,52.49 45.78,53.17 46.23,53.62 47.32,53.62 47.78,53.15 47.78,52.46 47.96,52.28 49.04,52.28 49.26,52.49 49.26,53.18 49.69,53.62 50.65,53.62 51.09,53.18 51.09,52.49 51.3,52.28 54.5,52.28 55,52.78 74.89,52.78 74.9,52.78 83.37,52.78 84.03,53.43
  BOTTOM w0.14: UC1.AC35 87.57,54.41 v1(87.77,54.61)
  BOTTOM w0.163: v1(33.99,52.83) 34.09,52.93 34.09,54 34.8,54.7 35.34,54.7 35.75,55.11 36.05,55.11 36.23,55.29 JDIMM1.137
DDR_A_CLK0#: length 67.6
  IN1 w0.102: v1(88.57,54.61) 88.25,54.61 88.15,54.51 88.15,54.32 88.02,54.19 87.86,54.19 87.48,53.81 85.82,53.81 85.63,53.63 84.7,53.63 84.31,53.24 84.31,53.17 84.2,53.06
  IN1 w0.211: 84.2,53.06 83.53,52.39 75.06,52.39 75.06,52.39 55.16,52.39 54.66,51.89 51.14,51.89 50.7,52.33 50.7,53.02 50.49,53.23 49.85,53.23 49.64,53.02 49.64,52.33 49.21,51.89 47.8,51.89 47.39,52.3 47.39,52.99 47.15,53.23 46.39,53.23 46.17,53.01 46.17,52.33 45.73,51.89 44.78,51.89 44.34,52.33 44.34,53.01 44.13,53.22 43.49,53.22 43.28,53.01 43.28,52.33 42.85,51.89 41.89,51.89 41.45,52.33 41.45,53.01 41.24,53.22 37.84,53.22 37.49,52.87 36.23,52.87 35.74,53.36 34.81,53.36 34.6,53.15 34.6,52.98 v1(34.76,52.83)
  BOTTOM w0.14: UC1.AC34 88.37,54.41 v1(88.57,54.61)
  BOTTOM w0.163: v1(34.76,52.83) 34.39,53.19 34.39,53.88 34.92,54.4 35.47,54.4 35.87,54.81 36.1,54.81 36.13,54.79 JDIMM1.139
DDR_A_CLK1: length 66.5
  IN1 w0.102: v1(88.57,55.71) 88.84,55.71 88.94,55.81 88.94,56 88.81,56.12 88.18,56.12 88.05,56 88.05,55.51 87.57,55.03 84.39,55.03 83.95,54.59 82.93,54.59 82.67,54.32 82.28,54.32 82.18,54.21 82.18,54.18 82.17,54.16 82.15,54.16
  IN1 w0.211: 82.15,54.16 79.56,54.16 79.53,54.16 78.45,54.16 77.99,53.7 51.96,53.7 51.12,54.54 38.76,54.54 38.62,54.67 34.68,54.67 34.68,54.68 32.76,54.68 32.16,54.08 32.16,53.14 v1(32.47,52.83)
  BOTTOM w0.14: UC1.AA34 88.37,55.51 v1(88.57,55.71)
  BOTTOM w0.163: JDIMM1.138 29.65,55.03 29.86,54.83 29.93,54.83 30.25,54.51 31.8,54.51 32.25,54.06 32.25,53.04 v1(32.47,52.83)
DDR_A_CLK1#: length 66.6
  IN1 w0.102: v1(89.37,55.71) 89.32,55.71 89.14,55.88 89.14,56.08 88.9,56.33 88.09,56.33 87.85,56.08 87.85,55.6 87.48,55.23 84.31,55.23 83.87,54.79 82.85,54.79 82.58,54.52 82.18,54.52 82.15,54.55
  IN1 w0.211: 82.15,54.55 79.56,54.55 79.53,54.55 78.28,54.55 77.82,54.09 52.12,54.09 51.28,54.93 38.92,54.93 38.78,55.06 34.84,55.06 32.59,55.06 31.77,54.24 31.77,52.89 v1(31.71,52.83)
  BOTTOM w0.14: UC1.AA32 89.17,55.51 v1(89.37,55.71)
  BOTTOM w0.163: JDIMM1.140 29.81,54.54 30.13,54.21 31.68,54.21 31.96,53.94 31.96,53.51 31.95,53.5 31.95,53.07 v1(31.71,52.83)
DDR_A_EVENT#: length 58.3
  IN1 w0.127: v1(78.68,56.31) 73.39,56.31 72.8,56.9 33.09,56.9 v1(32.18,55.99)
  BOTTOM w0.102: RC4.2 78.43,57.4 78.43,56.55 v1(78.68,56.31) 79.61,55.37 83.66,55.37 UC1.AA41 ; JDIMM1.134 29.92,56.03 30.47,55.48 31.67,55.48 v1(32.18,55.99)
DDR_A_ODT0: length 65.2
  IN1 w0.211: v1(86.36,49.06) 85.91,49.06 84.62,47.77 84.62,47.53 83.59,46.51 80.68,46.51 80.32,46.15 75.26,46.15 74.5,46.91 66.11,46.91 66,47.02 54.96,47.02 54.67,47.3 54.67,47.77 54.46,47.98 54.04,47.98 53.83,47.77 53.83,47.23 53.62,47.02 53.2,47.02 52.99,47.23 52.99,47.77 52.78,47.98 52.36,47.98 52.14,47.77 52.14,47.23 51.93,47.02 51.51,47.02 51.3,47.23 51.3,47.77 51.09,47.98 50.67,47.98 50.46,47.77 50.46,47.38 50.25,47.17 49.83,47.17 49.61,47.38 49.61,47.77 49.4,47.98 48.98,47.98 48.77,47.77 48.77,47.38 48.56,47.17 48.14,47.17 47.93,47.38 47.93,47.77 47.72,47.98 47.3,47.98 47.08,47.77 47.08,47.38 46.87,47.17 46.45,47.17 46.24,47.38 46.24,47.77 46.03,47.98 45.61,47.98 45.4,47.77 45.4,47.38 45.19,47.17 44.77,47.17 44.56,47.38 44.56,47.77 44.34,47.98 43.92,47.98 43.71,47.77 43.71,47.38 43.5,47.17 43.04,47.17 42.83,47.38 42.83,47.77 42.61,47.98 42.19,47.98 41.98,47.77 41.98,47.38 41.77,47.17 40.79,47.17 39.93,48.04 38.35,48.04 37.63,48.76 v1(35.52,48.76)
  BOTTOM w0.102: JDIMM1.155 35.54,48.79 v1(35.52,48.76) ; v1(86.36,49.06) 86.36,48.97 UC1.AN37
DDR_A_ODT1: length 65.1
  IN1 w0.102: v1(86.53,46.17) 86.53,45.99 85.26,44.71 83.33,44.71 81.91,43.28
  IN1 w0.211: v1(34.76,46.98) 34.83,46.91 34.83,46.91 35,46.74 35.29,46.45 38.74,46.45 39.93,45.26 65.79,45.26 66,45.05 66,44.16 66.21,43.95 66.63,43.95 66.85,44.16 66.85,45.03 67.06,45.24 67.48,45.24 67.69,45.03 67.69,44.18 67.9,43.97 68.32,43.97 68.53,44.18 68.53,44.97 68.74,45.18 69.16,45.18 69.38,44.97 69.38,44.16 69.59,43.95 69.94,43.95 70.22,44.22 70.22,45.03 70.43,45.24 70.85,45.24 71.06,45.03 71.06,44.19 71.3,43.95 74.44,43.95 75.29,43.1 77.75,43.1 77.93,43.28 81.91,43.28
  BOTTOM w0.102: v1(86.53,46.17) 86.34,46.36 UC1.AU38 ; v1(34.76,46.98) 34.76,47.39 35.17,47.8 35.68,47.8 36.2,47.29 JDIMM1.161
DDR_A_PAR: length 3.7
  TOP w0.102: v2(38.28,51.99) v1(38.28,52.69) 38.28,52.94 RD210.2
  BOTTOM w0.102: v1(38.28,52.69) 38.28,53.52 38.01,53.79 JDIMM1.143
DDR_A_RST#: length 65.4
  TOP w0.102: v1(85.41,64.49) 84.6,64.49 CC112.2 85.08,63.98 85.6,63.98 v1(86.17,63.41) ; v1(30.76,64.23) 30.48,64.51 CD231.1 v1(31.59,65.03) v2(32.18,65.03)
  IN1 w0.127: v1(85.41,64.49) 85.41,64.49 83.63,66.27 82.63,66.27 81.14,67.77 78.86,67.77 77.77,66.68 61.41,66.68 60.7,65.98 32.53,65.98 v1(31.59,65.03)
  BOTTOM w0.102: v1(86.17,63.41) 85.97,63.21 UC1.G38 ; v1(30.76,64.23) 30.76,63.66 29.64,62.54 JDIMM1.108
DDR_A_SACT#: length 64
  IN1 w0.102: 77.58,63.87 78.41,63.87 79.72,65.18 81.8,65.18 84.71,62.27 85.97,62.27 86.2,62.04 86.21,62.04 86.38,61.87 87.08,61.87 87.74,61.21 v1(88.12,61.21)
  IN1 w0.211: v1(32.18,62.72) 33.11,63.65 36.61,63.65 37.59,64.62 56.76,64.62 57.52,63.87 77.58,63.87
  BOTTOM w0.102: UC1.L35 v1(88.12,61.21) ; JDIMM1.114 29.68,61.04 30.88,62.23 31.69,62.23 v1(32.18,62.72)
DDR_A_SBG0: length 64.2
  IN1 w0.102: v1(88.37,60.11) 88.37,60.24 87.62,60.99 87.39,60.99 86.71,61.67 86.2,61.67 85.85,62.02 84.52,62.02 81.66,64.87 79.85,64.87 78.38,63.4 77.58,63.4
  IN1 w0.211: 77.58,63.4 56.99,63.4 56.78,63.61 56.78,63.95 56.57,64.16 56.15,64.16 55.94,63.95 55.94,63.61 55.72,63.4 55.3,63.4 55.09,63.61 55.09,63.95 54.88,64.16 37.78,64.16 36.8,63.18 34.17,63.18 v1(33.7,62.72)
  BOTTOM w0.102: v1(33.7,62.72) 34.71,61.71 35.3,61.71 36.22,60.78 JDIMM1.115 ; UC1.N34 v1(88.37,60.11)
DDR_A_SBG1: length 63.7
  IN1 w0.102: v1(86.22,61.29) 85.87,61.63 84.46,61.63 83.69,62.41 82.32,62.41 81.78,62.94 81.31,62.94
  IN1 w0.211: 81.31,62.94 54.57,62.94 54.36,63.15 54.36,63.48 54.15,63.69 53.72,63.69 53.51,63.48 53.51,63.15 53.3,62.94 52.88,62.94 52.67,63.15 52.67,63.48 52.46,63.69 52.04,63.69 51.83,63.48 51.83,63.15 51.62,62.94 51.19,62.94 50.98,63.15 50.98,63.48 50.77,63.69 50.35,63.69 50.14,63.48 50.14,63.15 49.93,62.94 49.51,62.94 49.3,63.15 49.3,63.48 49.09,63.69 48.66,63.69 48.45,63.48 48.45,63.15 48.24,62.94 47.82,62.94 47.61,63.15 47.61,63.48 47.4,63.69 46.98,63.69 46.77,63.48 46.77,63.15 46.56,62.94 46.13,62.94 45.92,63.15 45.92,63.48 45.71,63.69 45.29,63.69 45.08,63.48 45.08,63.15 44.87,62.94 44.45,62.94 44.24,63.15 44.24,63.48 44.03,63.69 43.6,63.69 43.39,63.48 43.39,63.15 43.18,62.94 42.76,62.94 42.55,63.15 42.55,63.48 42.34,63.69 41.92,63.69 41.71,63.48 41.71,63.21 41.5,63 41.2,63 40.64,63.55 37.83,63.55 37,62.72 v1(35.22,62.72)
  BOTTOM w0.102: v1(86.22,61.29) 86.17,61.24 86.17,60.86 UC1.L38 ; JDIMM1.113 36.36,61.29 35.22,62.42 v1(35.22,62.72)
DDR_A_SBS0#: length 63.5
  IN1 w0.102: 84.12,49.48 85.47,50.84 85.73,50.84 v1(86.17,51.28)
  IN1 w0.211: v1(32.47,50.79) 32.47,50.57 33.28,49.76 39.52,49.76 40.63,48.65 41.49,48.65 41.75,48.91 62.56,48.91 62.77,48.7 62.77,48.31 62.98,48.1 63.49,48.1 63.7,48.31 63.7,48.7 63.91,48.91 64.33,48.91 64.54,48.7 64.54,48.31 64.75,48.1 65.17,48.1 65.38,48.31 65.38,48.7 65.59,48.91 66.02,48.91 66.23,48.7 66.23,48.31 66.44,48.1 82.73,48.1 84.12,49.48
  BOTTOM w0.102: v1(32.47,50.79) 31.71,50.03 JDIMM1.150 ; v1(86.17,51.28) 86.17,50.96 UC1.AJ38
DDR_A_SBS1#: length 64.1
  IN1 w0.102: 82.66,48.56 85.3,51.21 85.55,51.21 85.83,51.49 85.83,51.49 86.01,51.66 86.62,51.66 v1(87.06,51.22)
  IN1 w0.211: v1(33.99,50.79) 34.49,50.3 34.49,50.3 34.56,50.23 39.71,50.23 40.36,49.58 41.11,49.58 41.31,49.38 66.69,49.38 66.9,49.16 66.9,48.78 67.11,48.56 67.53,48.56 67.75,48.78 67.75,49.16 67.96,49.38 68.38,49.38 68.59,49.16 68.59,48.78 68.8,48.56 69.22,48.56 69.43,48.78 69.43,49.16 69.64,49.38 70.06,49.38 70.28,49.16 70.28,48.78 70.49,48.56 70.91,48.56 71.12,48.78 71.12,49.16 71.33,49.38 71.75,49.38 71.96,49.16 71.96,48.78 72.17,48.56 72.59,48.56 72.81,48.78 72.81,49.16 73.02,49.38 73.5,49.38 74.31,48.56 82.66,48.56
  BOTTOM w0.102: v1(33.99,50.79) 34.49,51.29 JDIMM1.145 ; UC1.AG35 87.06,51.35 v1(87.06,51.22)
DDR_A_SCAS#: length 63.1
  IN1 w0.102: 80.6,44.09 81.18,44.67 82.19,44.67 83.32,45.8 84.97,45.8 86.52,47.35 v1(86.52,48.01)
  IN1 w0.211: v1(30.95,48.76) 32.1,47.61 36.97,47.61 37.47,47.11 39.5,47.11 40.88,45.73 74.16,45.73 74.45,45.43 74.45,44.76 75.12,44.09 80.6,44.09
  BOTTOM w0.102: v1(86.52,48.01) UC1.AN38 ; JDIMM1.156 29.61,48.54 29.87,48.28 30.46,48.28 v1(30.95,48.76)
DDR_A_SCS0#: length 64.1
  IN1 w0.102: v1(87.72,50.22) 87.57,50.37 87.57,51.54 87.14,51.97 85.97,51.97 85.47,51.47 84.9,51.47 83.27,49.84 82.64,49.84
  IN1 w0.211: 82.64,49.84 77.04,49.84 76.83,49.63 76.83,49.24 76.62,49.03 76.19,49.03 75.98,49.24 75.98,49.63 75.77,49.84 75.35,49.84 75.14,49.63 75.14,49.24 74.93,49.03 74.51,49.03 74.3,49.24 74.3,49.63 74.09,49.84 65.54,49.84 65.33,50.05 65.33,50.25 65.12,50.46 64.7,50.46 64.49,50.25 64.49,50.05 64.28,49.84 63.86,49.84 63.65,50.05 63.65,50.25 63.43,50.46 63.01,50.46 62.8,50.25 62.8,50.05 62.59,49.84 62.17,49.84 61.96,50.05 61.96,50.25 61.75,50.46 61.33,50.46 61.12,50.25 61.12,50.05 60.91,49.84 60.48,49.84 60.27,50.05 60.27,50.25 60.06,50.46 59.64,50.46 59.43,50.25 59.43,50.05 59.22,49.84 58.8,49.84 58.59,50.05 58.59,50.25 58.38,50.46 57.95,50.46 57.74,50.25 57.74,50.05 57.53,49.84 57.11,49.84 56.9,50.05 56.9,50.25 56.69,50.46 56.27,50.46 56.06,50.25 56.06,50.05 55.85,49.84 41.51,49.84 41.3,50.04 40.55,50.04 39.64,50.95 35.68,50.95 v1(35.52,50.79)
  BOTTOM w0.102: UC1.AL35 87.57,50.01 87.7,50.14 87.7,50.2 v1(87.72,50.22) ; v1(35.52,50.79) 36.03,50.29 JDIMM1.149
DDR_A_SCS1#: length 64.4
  IN1 w0.102: v1(86.67,46.78) 86.91,46.53 86.91,46.01 85.26,44.35 83.53,44.35 81.99,42.82 81.5,42.82
  IN1 w0.211: 81.5,42.82 80.42,42.82 80.21,42.61 80.21,42.02 80,41.81 79.57,41.81 79.36,42.02 79.36,42.43 79.15,42.64 75.09,42.64 74.25,43.48 64.46,43.48 63.15,44.8 39.73,44.8 38.55,45.98 34.23,45.98 v1(33.23,46.98)
  BOTTOM w0.102: UC1.AR37 86.77,46.88 v1(86.67,46.78) ; JDIMM1.157 36.19,48.29 36.09,48.18 34.02,48.18 33.23,47.39 v1(33.23,46.98)
DDR_A_SDM0: length 76.7
  IN2 w0.127: v1(31.67,87.35) 32.17,86.85 36.13,86.85 37.9,88.63 40.8,88.63 53.26,76.17 57.03,76.17 57.16,76.04 57.16,75.72 57.28,75.6 57.54,75.6 57.66,75.72 57.66,76.04 57.79,76.17 58.04,76.17 58.17,76.04 58.17,75.72 58.3,75.6 58.55,75.6 58.68,75.72 58.68,76.04 58.81,76.17 59.06,76.17 59.19,76.04 59.19,75.72 59.31,75.6 59.57,75.6 59.7,75.72 59.7,76.04 59.82,76.17 60.08,76.17 60.2,76.04 60.2,75.72 60.33,75.6 60.72,75.6 60.84,75.72 60.84,76.04 60.97,76.17 61.23,76.17 61.35,76.04 61.35,75.72 61.48,75.6 61.73,75.6 61.86,75.72 61.86,76.04 61.99,76.17 62.24,76.17 62.37,76.04 62.37,75.72 62.5,75.6 82.06,75.6 85.28,72.38 85.28,70.68 86.9,69.06 v1(87.21,69.06)
  BOTTOM w0.102: UC1.B35 87.47,66.01 87.09,66.39 87.09,68.94 v1(87.21,69.06) ; JDIMM1.12 29.78,86.54 29.92,86.68 31,86.68 v1(31.67,87.35)
DDR_A_SDM1: length 68.8
  IN2 w0.127: v1(83.06,65.83) 82.81,65.83 79.13,69.5 52.95,69.5 50.79,71.67 50.61,71.67 50.36,71.42 50.18,71.42 50,71.6 50,71.78 50.25,72.03 50.25,72.21 50.07,72.39 49.89,72.39 49.64,72.14 49.46,72.14 49.28,72.32 49.28,72.5 49.53,72.74 49.53,72.92 49.35,73.1 49.17,73.1 48.92,72.86 48.74,72.86 48.56,73.04 48.56,73.21 48.81,73.46 48.81,73.64 48.63,73.82 48.45,73.82 48.2,73.57 48.02,73.57 47.84,73.75 47.84,73.93 48.09,74.18 48.09,74.36 47.91,74.54 47.73,74.54 47.48,74.29 47.3,74.29 47.12,74.47 47.12,74.65 47.37,74.9 47.37,75.08 47.19,75.26 47.01,75.26 46.77,75.01 46.59,75.01 46.41,75.19 46.41,75.37 46.65,75.62 46.65,75.8 46.47,75.98 46.29,75.98 46.05,75.73 45.87,75.73 45.69,75.91 45.69,76.09 45.94,76.34 45.94,76.52 45.76,76.7 45.58,76.7 45.33,76.45 45.15,76.45 41.43,80.17 41.43,81.63 40.53,82.53 38.28,82.53 37.64,81.9 34.85,81.9 v1(34.72,81.77)
  BOTTOM w0.102: v1(83.06,65.83) 82.96,65.72 82.96,65.05 83.26,64.74 84.01,64.74 84.11,64.82 84.35,64.82 84.44,64.73 84.7,64.73 UC1.D40 ; v1(34.72,81.77) 34.72,81.47 34.9,81.29 JDIMM1.33
DDR_A_SDM2: length 64.6
  IN2 w0.127: v1(31.33,76.43) 31.33,76.35 31.74,75.93 38.18,75.93 50.77,63.34 54.64,63.34 54.76,63.21 59.4,63.21 59.57,63.04 63.43,63.04 64.05,63.66 73.67,63.66 74.03,63.3 76.25,63.3 77.25,64.3 v1(77.25,64.65)
  BOTTOM w0.102: UC1.K40 84.7,61.43 84.44,61.43 84.35,61.52 84.08,61.52 84,61.44 83.68,61.44 83.61,61.52 82.24,61.52 81.11,62.64 79.26,62.64 v1(77.25,64.65) ; JDIMM1.54 29.61,76.04 29.71,75.93 30.82,75.93 v1(31.33,76.43)
DDR_A_SDM3: length 65
  IN2 w0.127: v1(34.21,71.1) 34.72,71.61 35.81,71.61 36.15,71.27 36.15,70.99 41.28,65.86 44.54,62.61 44.72,62.61 44.99,62.88 45.16,62.88 45.34,62.7 45.34,62.52 45.08,62.25 45.08,62.07 45.26,61.89 45.43,61.89 45.7,62.16 45.88,62.16 46.06,61.98 46.06,61.8 45.79,61.53 45.79,61.35 45.97,61.17 46.15,61.17 46.42,61.44 46.6,61.44 46.78,61.26 46.78,61.08 46.51,60.81 46.51,60.63 46.69,60.45 46.87,60.45 47.14,60.72 47.32,60.72 47.5,60.54 47.5,60.36 47.23,60.09 47.23,59.91 47.41,59.73 47.59,59.73 47.86,60 48.04,60 48.22,59.82 48.22,59.64 47.95,59.37 47.95,59.19 48.13,59.01 75.19,59.01 75.63,59.45 80.76,59.45 81.35,58.86 v1(81.35,58.46)
  BOTTOM w0.102: UC1.T41 84.18,57.95 83.39,57.95 83.31,57.88 81.61,57.88 81.35,58.14 v1(81.35,58.46) ; JDIMM1.75 36.19,70.78 35.87,70.47 34.84,70.47 v1(34.21,71.1)
DDR_A_SDM4: length 61.8
  IN2 w0.127: v1(76.84,51.74) 76.2,52.37 47.14,52.37 39.38,44.61 37.36,44.61 35.64,42.89 31.57,42.89 31.21,42.54 31.03,42.54 30.84,42.74 30.84,42.92 31.35,43.43 v1(31.45,43.43)
  BOTTOM w0.102: v1(31.45,43.43) 30.94,42.91 29.97,42.91 29.84,43.03 JDIMM1.178 ; UC1.AE41 83.71,52.8 77.98,52.8 77.18,52.01 77.11,52.01 v1(76.84,51.74)
DDR_A_SDM5: length 62.6
  IN2 w0.127: v1(35.01,38.35) 36.62,38.35 37.83,39.56 41.3,39.56 45.05,43.31 45.23,43.31 45.45,43.1 45.63,43.1 45.81,43.28 45.81,43.46 45.59,43.67 45.59,43.85 45.78,44.04 45.96,44.04 46.18,43.82 46.36,43.82 46.54,44 46.54,44.18 46.32,44.4 46.32,44.58 46.53,44.78 46.71,44.78 46.92,44.57 47.1,44.57 47.28,44.75 47.28,44.93 47.07,45.14 47.07,45.32 47.24,45.5 47.42,45.5 47.64,45.29 47.82,45.29 48,45.46 48,45.64 47.78,45.86 47.78,46.04 48.01,46.27 48.19,46.27 48.41,46.05 48.59,46.05 48.77,46.23 48.77,46.41 48.55,46.63 48.55,46.81 48.78,47.04 48.96,47.04 49.18,46.82 49.35,46.82 49.54,47 49.54,47.18 49.32,47.4 49.32,47.57 49.5,47.76 49.68,47.76 49.89,47.54 50.07,47.54 50.25,47.72 50.25,47.9 50.04,48.11 50.04,48.29 50.26,48.52 81.37,48.52 v1(82.22,49.38)
  BOTTOM w0.102: v1(82.22,49.38) 82.22,49.38 82.24,49.38 82.24,49.38 82.56,49.05 83.3,49.05 83.54,49.29 83.95,49.29 84,49.34 84,49.34 84.1,49.44 84.35,49.44 UC1.AL40 ; JDIMM1.199 35.57,37.79 v1(35.01,38.35)
DDR_A_SDM6: length 62.9
  IN2 w0.127: v1(31.45,32.63) 32.02,33.2 35.43,33.2 35.77,32.85 42.39,32.85 51.98,42.45 58.32,42.45 58.45,42.58 58.45,42.92 58.58,43.05 58.83,43.05 58.96,42.92 58.96,42.58 59.09,42.45 78.89,42.45 81.5,45.06 81.66,45.06 v1(82.54,45.93)
  BOTTOM w0.102: UC1.AU40 84.35,46.14 84.09,46.14 84,46.04 82.65,46.04 v1(82.54,45.93) ; JDIMM1.220 29.96,32.54 30.35,32.15 30.97,32.15 v1(31.45,32.63)
DDR_A_SDM7: length 74.2
  IN2 w0.127: v1(35.01,27.3) 35.08,27.23 36.76,27.23 37.32,26.67 42.57,26.67 52.54,36.64 64.24,36.64 64.37,36.52 64.37,36 64.49,35.87 64.75,35.87 64.88,36 64.88,36.52 65,36.64 65.3,36.64 65.43,36.52 65.43,36 65.56,35.87 65.81,35.87 65.94,36 65.94,36.52 66.07,36.64 66.32,36.64 66.45,36.52 66.45,36 66.57,35.87 67.5,35.87 67.63,36 67.63,36.52 67.76,36.64 68.01,36.64 68.14,36.52 68.14,36 68.27,35.87 69.52,35.87 69.65,36 69.65,36.52 69.78,36.64 70.03,36.64 70.16,36.52 70.16,36 70.28,35.87 70.54,35.87 70.66,36 70.66,36.52 70.79,36.64 71.05,36.64 71.17,36.52 71.17,36 71.3,35.87 71.55,35.87 71.68,36 71.68,36.52 71.81,36.64 72.06,36.64 72.19,36.52 72.19,36 72.32,35.87 72.57,35.87 72.7,36 72.7,36.52 72.82,36.64 73.08,36.64 73.2,36.52 73.2,36 73.33,35.87 73.59,35.87 73.71,36 73.71,36.52 73.84,36.64 74.09,36.64 74.22,36.52 74.22,36 74.35,35.87 74.6,35.87 74.73,36 74.73,36.52 74.86,36.64 75.11,36.64 75.24,36.52 75.24,36 75.36,35.87 76.27,35.87 76.95,36.56 79.94,36.56 83.03,39.64 v1(83.03,40.21)
  BOTTOM w0.102: v1(83.03,40.21) 83.05,40.24 84.25,40.24 86.37,42.35 UC1.BA37 ; v1(35.01,27.3) 35.02,27.29 JDIMM1.241
DDR_A_SDQ0: length 77
  IN2 w0.127: v1(87.89,68.3) 88.45,68.86 88.45,70.73 87.9,71.27 87.9,73.33 83.58,77.66 75.69,77.66 75.12,78.23 61.42,78.23 60.22,79.43 52.91,79.43 40.91,91.43 32.48,91.43 31.8,90.75 v1(31.8,88.88)
  BOTTOM w0.102: v1(87.89,68.3) 87.89,68.07 88.05,67.91 88.05,66.84 88.02,66.81 UC1.A34 ; JDIMM1.8 30.4,87.54 30.71,87.84 30.75,87.84 v1(31.8,88.88)
DDR_A_SDQ1: length 77.3
  IN2 w0.127: v1(87.5,67.84) 87.5,68.13 87.49,68.14 87.49,68.47 88.06,69.04 88.06,70.54 87.51,71.1 87.51,73.09 83.32,77.27 75.22,77.27 75.09,77.4 75.09,77.72 74.96,77.85 74.71,77.85 74.58,77.72 74.58,77.4 74.45,77.27 74.13,77.27 74.01,77.4 74.01,77.72 73.88,77.85 73.63,77.85 73.5,77.72 73.5,77.4 73.37,77.27 73.12,77.27 72.99,77.4 72.99,77.72 72.86,77.85 72.61,77.85 72.48,77.72 72.48,77.4 72.36,77.27 72.1,77.27 71.97,77.4 71.97,77.72 71.85,77.85 61.26,77.85 60.06,79.05 52.76,79.05 41.49,90.31 34.75,90.31 v1(33.32,88.88)
  BOTTOM w0.102: v1(33.32,88.88) 33.8,88.4 35.47,88.4 36.08,87.78 JDIMM1.7 ; v1(87.5,67.84) 87.85,67.49 87.85,66.99 87.79,66.93 87.79,66.33 87.78,66.33 87.78,66.32 87.7,66.24 87.7,65.98 88.02,65.66 UC1.B34
DDR_A_SDQ2: length 76.7
  IN2 w0.127: v1(32.68,85.58) 33.2,86.09 36.13,86.09 36.44,86.09 38.14,87.79 40.56,87.79 54.29,74.06 57.53,74.06 57.65,74.18 57.65,74.71 57.78,74.83 58.03,74.83 58.16,74.71 58.16,74.18 58.29,74.06 58.56,74.06 58.68,74.18 58.68,74.71 58.81,74.83 59.07,74.83 59.19,74.71 59.19,74.18 59.32,74.06 59.59,74.06 59.72,74.18 59.72,74.71 59.84,74.83 60.1,74.83 60.23,74.71 60.23,74.18 60.35,74.06 60.61,74.06 60.73,74.18 60.73,74.71 60.86,74.83 61.11,74.83 61.24,74.71 61.24,74.18 61.37,74.06 61.62,74.06 61.75,74.18 61.75,74.71 61.88,74.83 81.18,74.83 84.72,71.29 84.72,70.84 85.69,69.87 85.69,69.18 85.38,68.87 85.16,68.87 85.16,68.87 v1(85.03,68.87)
  BOTTOM w0.102: JDIMM1.20 29.86,84.54 30.12,84.79 31.9,84.79 v1(32.68,85.58) ; v1(85.03,68.87) 85.47,68.87 85.83,68.52 85.83,66.88 85.82,66.87 85.82,66.81 85.82,66.81 UC1.A38
DDR_A_SDQ3: length 77.8
  IN2 w0.127: v1(34.21,85.58) 34.7,85.08 36.51,85.08 37.67,86.24 41.03,86.24 53.98,73.29 73.77,73.29 73.89,73.42 73.89,73.94 74.02,74.07 74.28,74.07 74.4,73.94 74.4,73.42 74.53,73.29 74.78,73.29 74.91,73.42 74.91,73.94 75.04,74.07 75.29,74.07 75.42,73.94 75.42,73.23 75.55,73.1 75.8,73.1 75.93,73.23 75.93,73.94 76.05,74.07 76.31,74.07 76.43,73.94 76.43,73.23 76.56,73.1 76.82,73.1 76.94,73.23 76.94,73.94 77.07,74.07 77.32,74.07 77.45,73.94 77.45,73.23 77.58,73.1 77.83,73.1 77.96,73.23 77.96,73.94 78.09,74.07 78.34,74.07 78.47,73.94 78.47,73.23 78.59,73.1 78.85,73.1 78.97,73.23 78.97,73.94 79.1,74.07 79.36,74.07 79.48,73.94 79.48,73.23 79.61,73.1 79.86,73.1 79.99,73.23 79.99,73.94 80.12,74.07 80.37,74.07 80.5,73.94 80.5,73.23 80.63,73.1 81.69,73.1 83.77,71.02 83.77,70.44 84.29,69.92 84.29,68.34 v1(85.03,67.6)
  BOTTOM w0.102: v1(34.21,85.58) 34.21,84.83 34.76,84.29 JDIMM1.21 ; v1(85.03,67.6) 85.09,67.6 85.59,67.11 85.59,66.32 85.51,66.23 85.51,65.98 85.6,65.89 85.6,65.63 UC1.B38
DDR_A_SDQ4: length 76.3
  IN2 w0.127: v1(30.27,88.88) 30.27,89.76 32.32,91.81 41.07,91.81 53.07,79.81 60.38,79.81 61.58,78.61 75.28,78.61 75.85,78.04 83.74,78.04 88.3,73.47 88.3,71.4 88.83,70.87 88.83,69.27 v1(88.84,69.25)
  BOTTOM w0.102: v1(30.27,88.88) 29.93,88.54 JDIMM1.4 ; UC1.A33 88.46,66.57 88.46,66.67 88.47,66.69 88.47,68.89 v1(88.84,69.25)
DDR_A_SDQ5: length 77.7
  IN2 w0.127: v1(34.84,88.88) 34.84,89.52 35.25,89.93 41.33,89.93 52.78,78.48 60.09,78.48 61.1,77.46 63.21,77.46 63.34,77.34 63.34,77.02 63.47,76.89 63.72,76.89 63.85,77.02 63.85,77.34 63.97,77.46 64.23,77.46 64.35,77.34 64.35,77.02 64.48,76.89 64.74,76.89 64.86,77.02 64.86,77.34 64.99,77.46 65.24,77.46 65.37,77.34 65.37,77.02 65.5,76.89 65.75,76.89 65.88,77.02 65.88,77.34 66.01,77.46 66.26,77.46 66.39,77.34 66.39,77.02 66.51,76.89 66.77,76.89 66.89,77.02 66.89,77.34 67.02,77.46 67.28,77.46 67.4,77.34 67.4,77.02 67.53,76.89 67.78,76.89 67.91,77.02 67.91,77.34 68.04,77.46 68.29,77.46 68.42,77.34 68.42,77.02 68.55,76.89 68.8,76.89 68.93,77.02 68.93,77.34 69.05,77.46 69.31,77.46 69.43,77.34 69.43,77.02 69.56,76.89 69.82,76.89 69.94,77.02 69.94,77.34 70.07,77.46 70.32,77.46 70.45,77.34 70.45,77.02 70.58,76.89 70.83,76.89 70.96,77.02 70.96,77.34 71.09,77.46 71.34,77.46 71.47,77.34 71.47,77.02 71.59,76.89 83.07,76.89 87.11,72.85 87.11,70.92 87.63,70.4 v1(87.63,70.08)
  BOTTOM w0.102: v1(87.63,70.08) 87.95,70.08 88.27,69.76 88.27,66.77 88.26,66.76 88.26,66.33 88.35,66.24 88.35,65.98 UC1.B33 ; v1(34.84,88.88) 35.33,89.36 35.81,89.36 36.09,89.08 36.09,89.08 36.21,88.95 36.21,88.95 36.38,88.78 JDIMM1.3
DDR_A_SDQ6: length 76.6
  IN2 w0.127: v1(31.16,85.58) 31.22,85.58 31.72,86.07 32.23,86.07 32.63,86.47 36.28,86.47 38.06,88.25 40.64,88.25 53.1,75.79 54.32,75.79 54.61,75.5 54.61,74.56 54.73,74.44 54.99,74.44 55.11,74.56 55.11,75.66 55.24,75.79 55.49,75.79 55.62,75.66 55.62,74.56 55.75,74.44 56,74.44 56.13,74.56 56.13,75.66 56.26,75.79 56.51,75.79 56.64,75.66 56.64,74.56 56.76,74.44 57.02,74.44 57.15,74.56 57.15,75.09 57.27,75.21 81.59,75.21 v1(84.88,71.92)
  BOTTOM w0.102: UC1.A37 86.32,66.51 86.32,68.95 86.28,68.99 86.28,69.38 85.05,70.61 85.05,71.75 v1(84.88,71.92) ; JDIMM1.16 29.74,85.54 30.2,86 30.74,86 v1(31.16,85.58)
DDR_A_SDQ7: length 77.7
  IN2 w0.127: v1(84.91,70.09) 84.23,70.78 84.23,71.13 80.91,74.45 73.51,74.45 73.39,74.33 73.39,73.8 73.26,73.67 73.01,73.67 72.88,73.8 72.88,74.26 72.75,74.39 72.5,74.39 72.37,74.26 72.37,73.8 72.24,73.67 71.99,73.67 71.86,73.8 71.86,74.26 71.74,74.39 71.48,74.39 71.35,74.26 71.35,73.8 71.23,73.67 70.97,73.67 70.85,73.8 70.85,74.26 70.72,74.39 70.47,74.39 70.34,74.26 70.34,73.8 70.21,73.67 69.96,73.67 69.83,73.8 69.83,74.26 69.7,74.39 69.45,74.39 69.32,74.26 69.32,73.8 69.2,73.67 68.94,73.67 68.81,73.8 68.81,74.33 68.69,74.45 68.43,74.45 68.31,74.33 68.31,73.8 68.18,73.67 67.93,73.67 67.8,73.8 67.8,74.33 67.67,74.45 67.42,74.45 67.29,74.33 67.29,73.8 67.16,73.67 66.91,73.67 66.78,73.8 66.78,74.33 66.66,74.45 66.4,74.45 66.27,74.33 66.27,73.8 66.15,73.67 65.89,73.67 65.77,73.8 65.77,74.33 65.64,74.45 65.39,74.45 65.26,74.33 65.26,73.8 65.13,73.67 64.8,73.67 64.67,73.8 64.67,74.33 64.54,74.45 64.29,74.45 64.16,74.33 64.16,73.8 64.04,73.67 63.78,73.67 63.65,73.8 63.65,74.33 63.53,74.45 63.27,74.45 63.15,74.33 63.15,73.8 63.02,73.67 62.77,73.67 62.64,73.8 62.64,74.33 62.51,74.45 62.26,74.45 62.13,74.33 62.13,73.8 62,73.67 54.13,73.67 41.08,86.73 37.62,86.73 36.47,85.58 v1(35.73,85.58)
  BOTTOM w0.102: UC1.B37 86.15,65.98 86.15,66.24 86.05,66.33 86.05,69.24 85.21,70.09 v1(84.91,70.09) ; v1(35.73,85.58) 35.73,85.45 35.9,85.29 JDIMM1.17
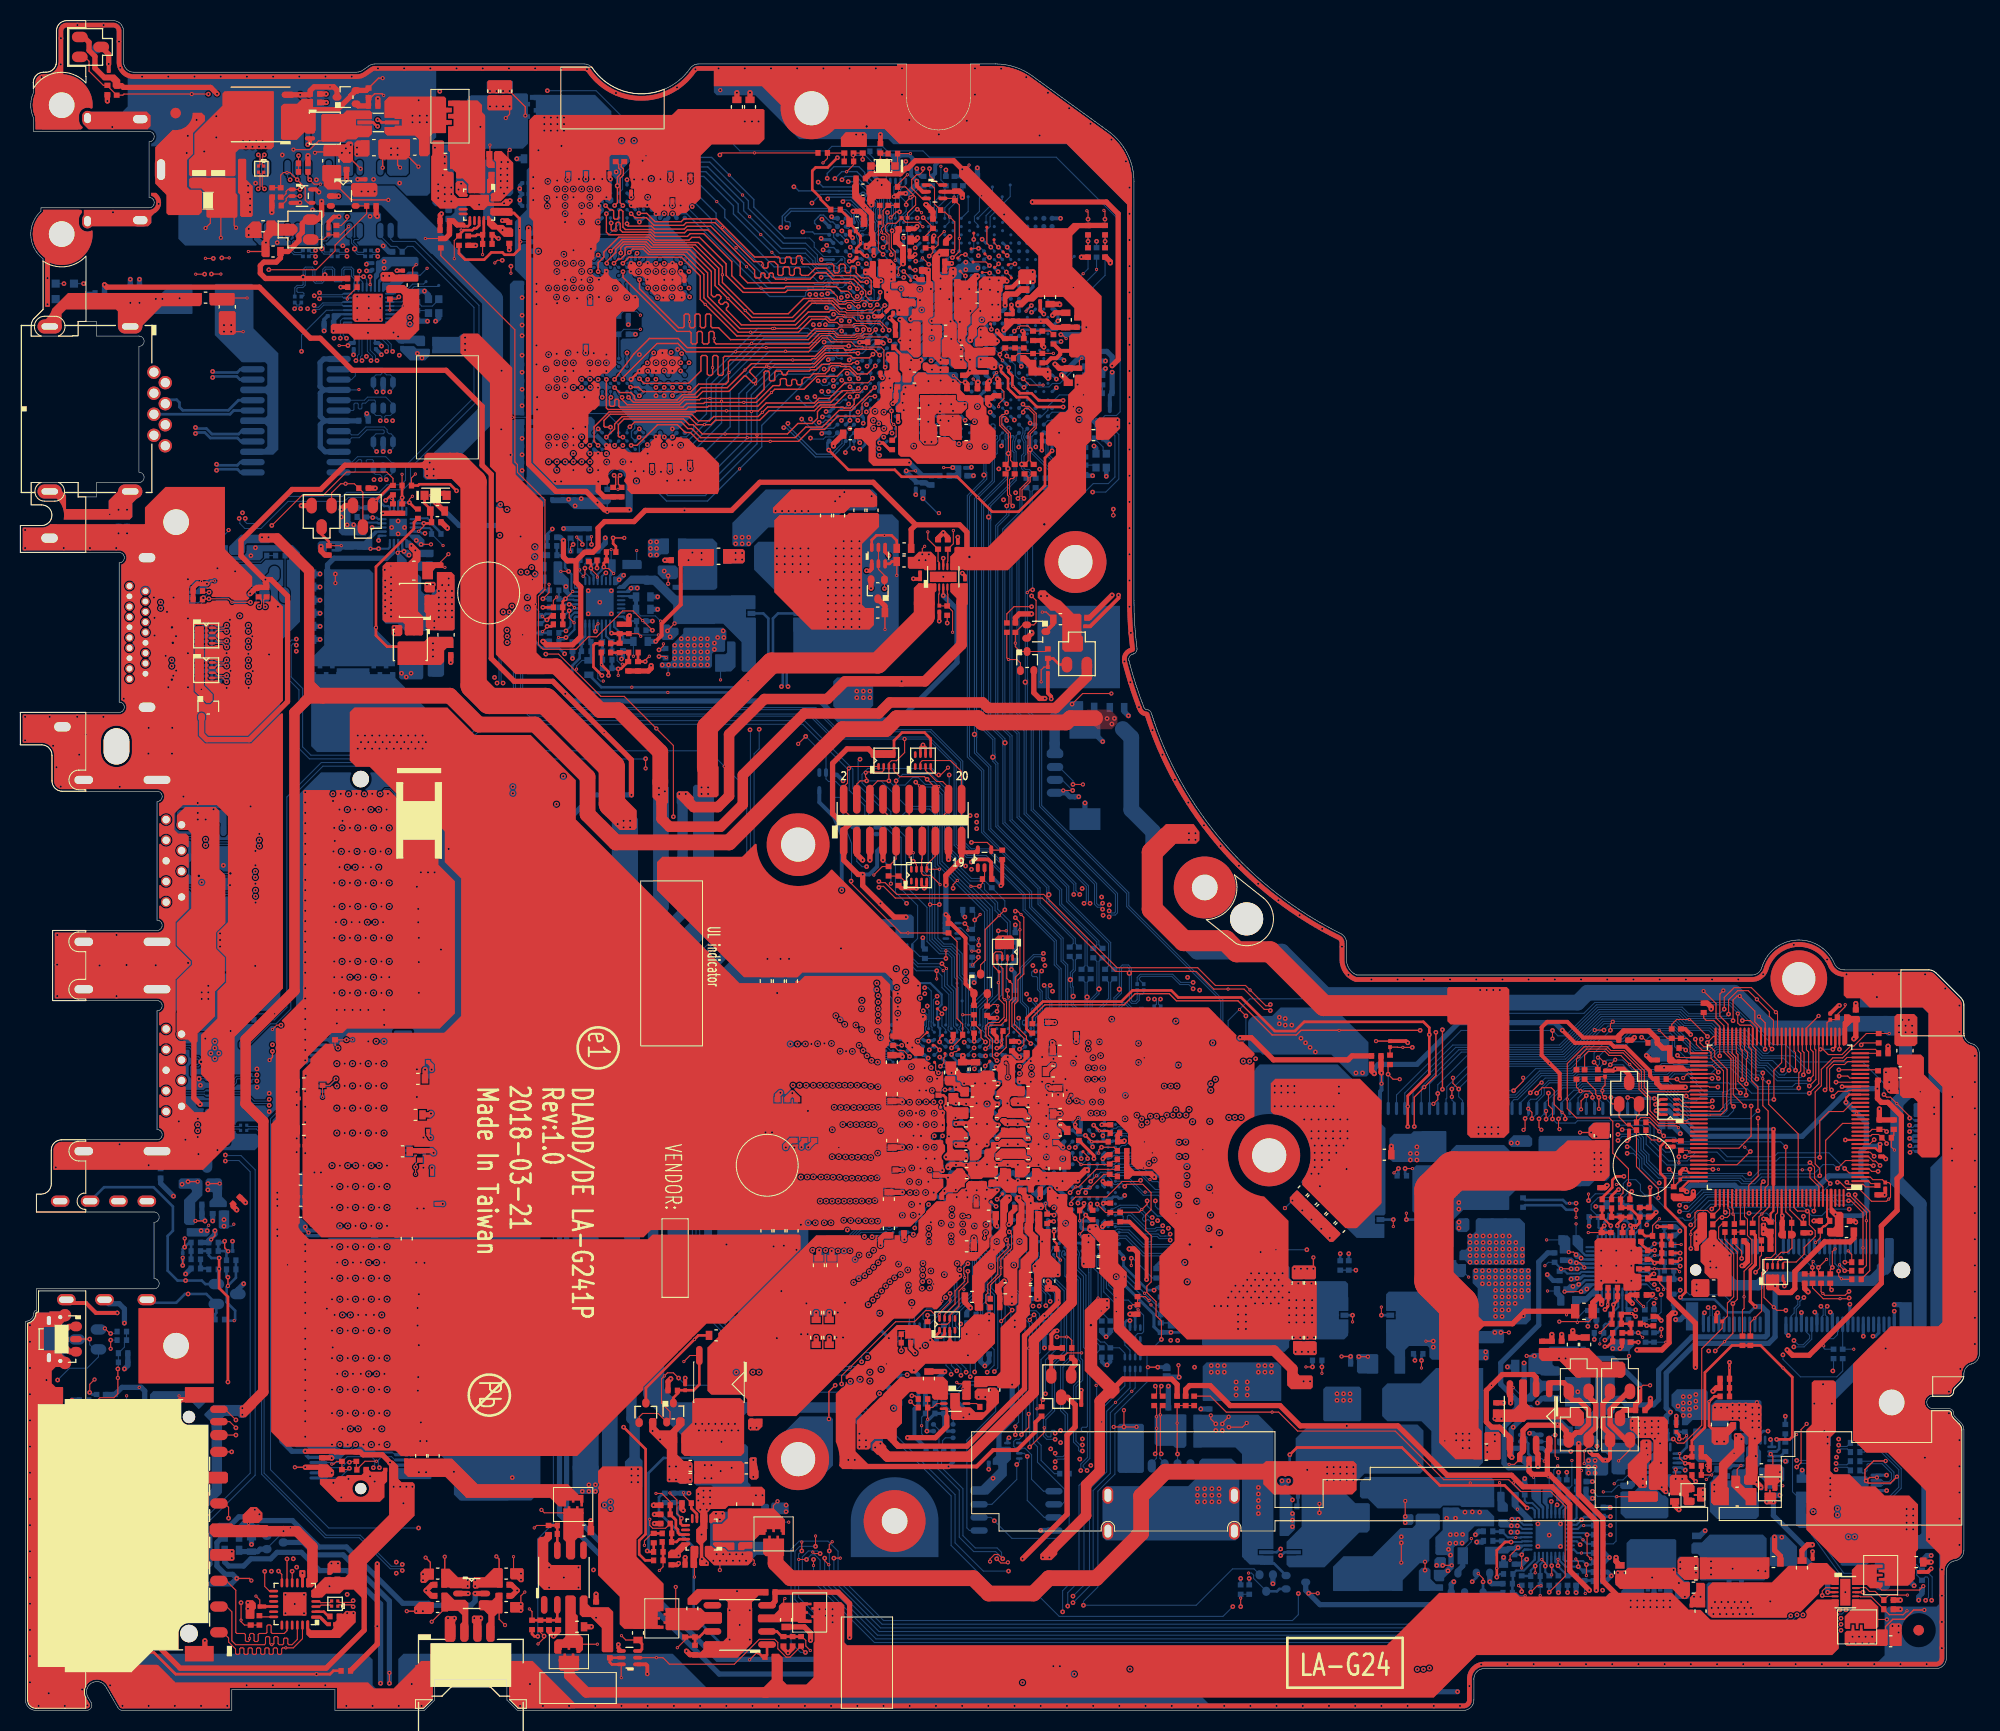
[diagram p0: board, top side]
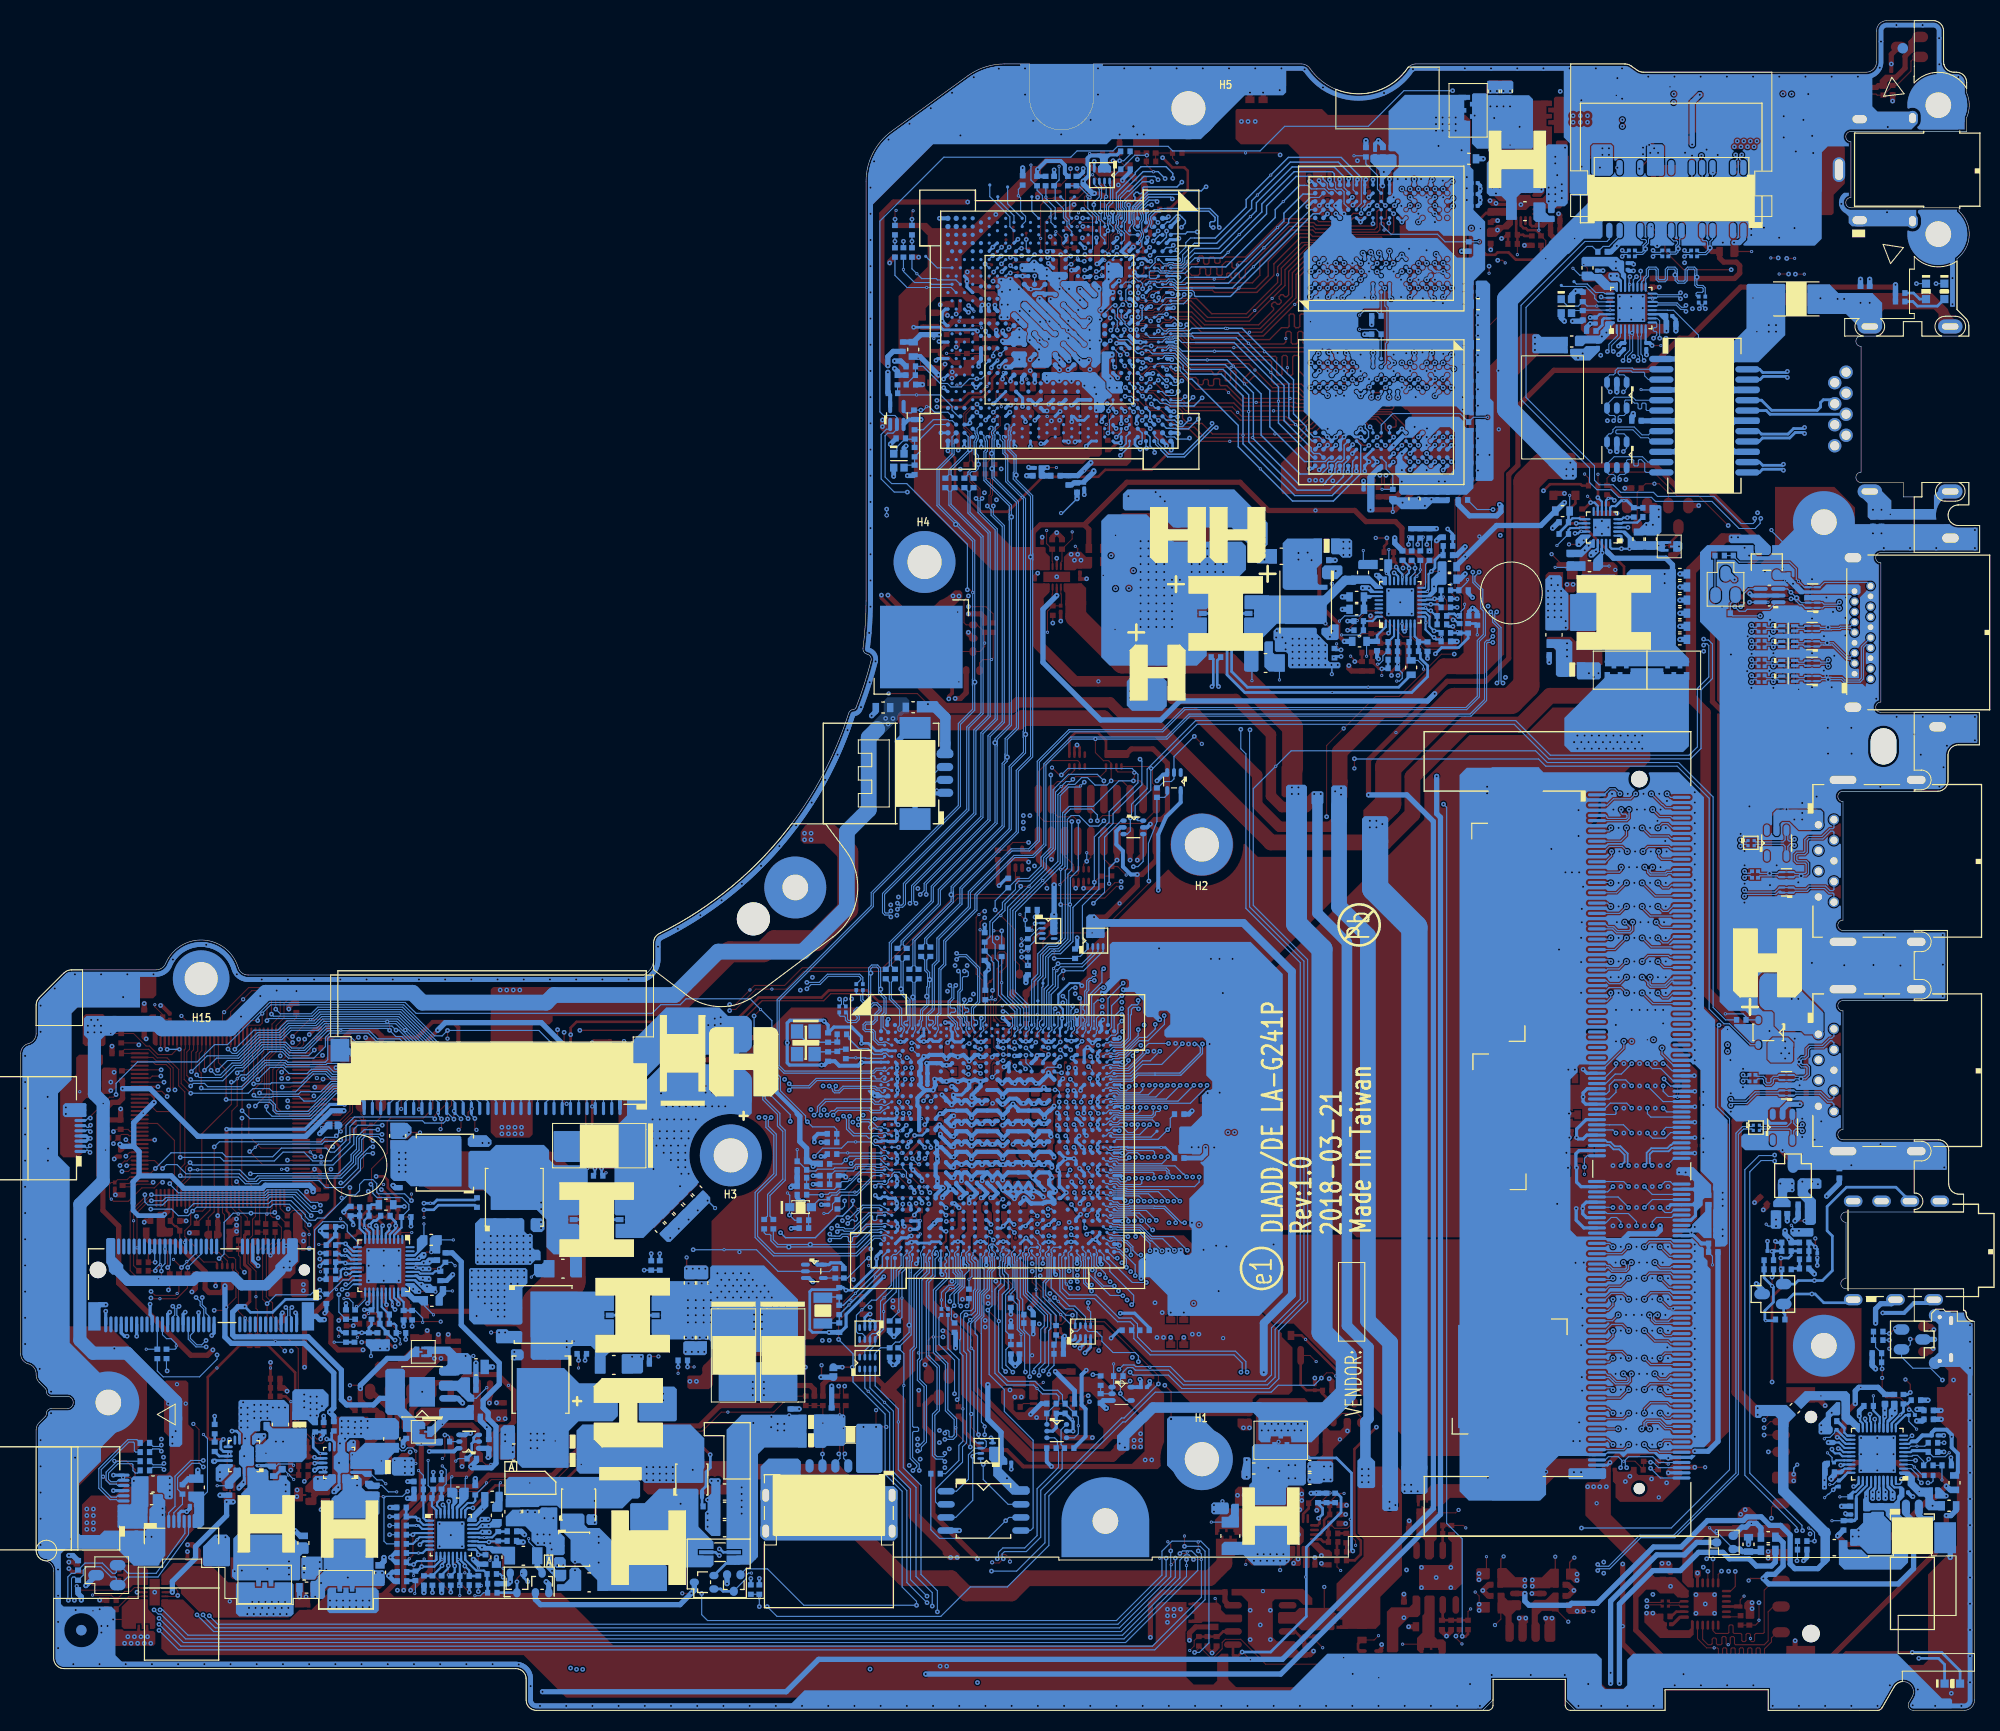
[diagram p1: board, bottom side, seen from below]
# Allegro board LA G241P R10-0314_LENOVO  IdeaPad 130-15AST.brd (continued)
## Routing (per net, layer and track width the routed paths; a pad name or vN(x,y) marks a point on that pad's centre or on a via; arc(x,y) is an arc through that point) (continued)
DDR_A_SDQ8: length 67.8
  IN2 w0.127: v1(31.08,83.29) 32.34,84.55 36.73,84.55 37.89,85.71 40.81,85.71 54.06,72.46 81.62,72.46 83.39,70.69 83.39,70.17 83.67,69.89 83.67,68.59 v1(83.12,68.05)
  BOTTOM w0.102: JDIMM1.28 30.79,82.54 31.08,82.83 v1(31.08,83.29) ; v1(83.12,68.05) 83.87,67.3 UC1.B41
DDR_A_SDQ9: length 68.9
  IN2 w0.127: v1(35.66,83.29) 37.09,83.29 37.65,83.85 41.05,83.85 54.1,70.8 66.26,70.8 66.39,70.92 66.39,71.19 66.51,71.31 66.77,71.31 66.89,71.19 66.89,70.92 67.02,70.8 67.27,70.8 67.4,70.92 67.4,71.19 67.53,71.31 67.78,71.31 67.91,71.19 67.91,70.92 68.04,70.8 68.29,70.8 68.42,70.92 68.42,71.19 68.54,71.31 68.8,71.31 68.93,71.19 68.93,70.92 69.05,70.8 69.45,70.8 69.57,70.92 69.57,71.19 69.7,71.31 69.95,71.31 70.08,71.19 70.08,70.92 70.21,70.8 70.46,70.8 70.59,70.92 70.59,71.19 70.72,71.31 70.97,71.31 71.1,71.19 71.1,70.92 71.22,70.8 71.48,70.8 71.61,70.92 71.61,71.19 71.73,71.31 71.99,71.31 72.11,71.19 72.11,70.92 72.24,70.8 72.49,70.8 72.62,70.92 72.62,71.19 72.75,71.31 73,71.31 73.13,71.19 73.13,70.92 73.26,70.8 73.51,70.8 73.64,70.92 73.64,71.19 73.76,71.31 74.02,71.31 74.15,71.19 74.15,70.92 74.27,70.8 74.58,70.8 74.71,70.92 74.71,71.19 74.84,71.31 75.09,71.31 75.22,71.19 75.22,70.92 75.35,70.8 75.6,70.8 75.73,70.92 75.73,71.19 75.85,71.31 76.11,71.31 76.24,71.19 76.24,70.92 76.36,70.8 76.62,70.8 76.74,70.92 76.74,71.19 76.87,71.31 77.12,71.31 77.25,71.19 77.25,70.92 77.38,70.8 77.63,70.8 77.76,70.92 77.76,71.15 77.89,71.28 78.14,71.28 78.27,71.15 78.27,70.92 78.39,70.8 80.45,70.8 82.43,68.83 82.43,67.54 v1(83.12,66.84)
  BOTTOM w0.102: v1(83.12,66.84) 83.51,66.45 83.51,65.71 83.75,65.47 84.16,65.47 UC1.C40 ; v1(35.66,83.29) 35.66,82.88 36.25,82.29 JDIMM1.29
DDR_A_SDQ10: length 69
  IN2 w0.127: v1(34.21,80.24) 34.7,79.75 37.14,79.75 37.68,80.29 38.94,80.29 51.85,67.37 69.65,67.37 69.77,67.5 69.77,67.78 69.9,67.91 70.16,67.91 70.28,67.78 70.28,67.5 70.41,67.37 70.66,67.37 70.79,67.5 70.79,67.78 70.92,67.91 71.17,67.91 71.3,67.78 71.3,67.5 71.43,67.37 71.68,67.37 71.81,67.5 71.81,67.78 71.93,67.91 72.19,67.91 72.31,67.78 72.31,67.5 72.44,67.37 72.7,67.37 72.82,67.5 72.82,67.85 72.95,67.98 73.2,67.98 73.33,67.85 73.33,67.5 73.46,67.37 73.8,67.37 73.93,67.5 73.93,67.85 74.05,67.98 74.31,67.98 74.44,67.85 74.44,67.5 74.56,67.37 74.82,67.37 74.94,67.5 74.94,67.85 75.07,67.98 75.32,67.98 75.45,67.85 75.45,67.5 75.58,67.37 75.83,67.37 75.96,67.5 75.96,67.85 76.09,67.98 76.34,67.98 76.47,67.85 76.47,67.5 76.59,67.37 76.85,67.37 76.98,67.5 76.98,67.85 77.1,67.98 77.36,67.98 77.48,67.85 77.48,67.5 77.61,67.37 77.86,67.37 77.99,67.5 77.99,67.85 78.12,67.98 78.37,67.98 78.5,67.85 78.5,67.5 78.63,67.37 v1(79.02,67.37)
  BOTTOM w0.102: JDIMM1.41 35.17,79.29 v1(34.21,80.24) ; v1(79.02,67.37) 79,67.35 79,66.52 80.58,64.94 81.46,64.94 82.81,63.58 83.4,63.58 83.57,63.41 UC1.F41
DDR_A_SDQ11: length 67.6
  IN2 w0.127: v1(81.66,63.98) 81.68,64 81.68,64.66 80.46,65.88 80.46,67.1 78.82,68.74 57.72,68.74 57.59,68.61 57.59,68.26 57.47,68.14 57.21,68.14 57.08,68.26 57.08,68.61 56.96,68.74 51.78,68.74 40.67,79.85 40.67,81.32 40.21,81.77 38.59,81.77 37.95,81.13 36.76,81.13 36.39,80.76 33.2,80.76 v1(32.68,80.24)
  BOTTOM w0.102: UC1.G40 84.35,63.08 84.1,63.08 84,63.18 84,63.18 83.97,63.21 83.49,63.21 83.48,63.21 83.37,63.21 83.3,63.28 82.81,63.28 82.11,63.98 v1(81.66,63.98) ; v1(32.68,80.24) 31.42,78.98 29.78,78.98 29.72,79.04 JDIMM1.42
DDR_A_SDQ12: length 67.5
  IN2 w0.127: v1(32.61,83.29) 33.48,84.17 36.89,84.17 38.05,85.33 40.65,85.33 53.9,72.07 56.52,72.07 56.64,71.95 56.64,71.69 56.77,71.56 57.02,71.56 57.15,71.69 57.15,71.95 57.28,72.07 57.53,72.07 57.66,71.95 57.66,71.69 57.79,71.56 58.04,71.56 58.17,71.69 58.17,71.95 58.29,72.07 81.44,72.07 v1(82.99,70.52)
  BOTTOM w0.102: v1(82.99,70.52) 84.47,69.05 UC1.A40 ; JDIMM1.24 29.88,83.54 30.12,83.77 32.13,83.77 v1(32.61,83.29)
DDR_A_SDQ13: length 68.8
  IN2 w0.127: v1(34.13,83.29) 34.63,83.79 37.05,83.79 37.5,84.23 41.2,84.23 54.26,71.18 58.65,71.18 58.78,71.31 58.78,71.57 58.9,71.69 59.16,71.69 59.28,71.57 59.28,71.31 59.41,71.18 59.67,71.18 59.79,71.31 59.79,71.57 59.92,71.69 60.17,71.69 60.3,71.57 60.3,71.31 60.43,71.18 60.68,71.18 60.81,71.31 60.81,71.57 60.94,71.69 61.19,71.69 61.32,71.57 61.32,71.31 61.44,71.18 61.7,71.18 61.82,71.31 61.82,71.57 61.95,71.69 62.21,71.69 62.33,71.57 62.33,71.31 62.46,71.18 62.71,71.18 62.84,71.31 62.84,71.57 62.97,71.69 63.22,71.69 63.35,71.57 63.35,71.31 63.48,71.18 63.73,71.18 63.86,71.31 63.86,71.57 63.98,71.69 64.24,71.69 64.36,71.57 64.36,71.31 64.49,71.18 64.75,71.18 64.87,71.31 64.87,71.57 65,71.69 65.25,71.69 65.38,71.57 65.38,71.31 65.51,71.18 65.76,71.18 65.89,71.31 65.89,71.57 66.02,71.69 80.5,71.69 82.87,69.32 v1(83.12,69.32)
  BOTTOM w0.102: UC1.B40 84.11,66.22 84.11,68.33 v1(83.12,69.32) ; v1(34.13,83.29) 34.62,83.78 35.84,83.78 35.84,83.77 35.86,83.77 36.34,83.29 JDIMM1.25
DDR_A_SDQ14: length 67.6
  IN2 w0.127: v1(31.16,80.24) 31.05,80.36 31.05,80.96 31.22,81.14 36.23,81.14 36.61,81.52 37.8,81.52 38.43,82.15 40.37,82.15 41.05,81.47 41.05,80.01 50.27,70.79 50.45,70.79 50.7,71.04 50.88,71.04 51.06,70.86 51.06,70.68 50.81,70.43 50.81,70.25 50.99,70.07 51.17,70.07 51.42,70.32 51.6,70.32 51.78,70.14 51.78,69.96 51.53,69.71 51.53,69.53 51.94,69.12 78.97,69.12 81.54,66.56 v1(81.54,66.02)
  BOTTOM w0.102: JDIMM1.38 29.86,80.04 30.14,79.76 30.68,79.76 v1(31.16,80.24) ; v1(81.54,66.02) 81.54,65.43 82.98,63.99 83.72,63.99 83.74,63.96 UC1.E41
DDR_A_SDQ15: length 69.2
  IN2 w0.127: v1(35.73,80.24) 36.87,80.24 37.3,80.68 39.09,80.68 52.01,67.75 57.97,67.75 58.1,67.88 58.1,68.23 58.22,68.36 58.48,68.36 58.6,68.23 58.6,67.88 58.73,67.75 58.98,67.75 59.11,67.88 59.11,68.23 59.24,68.36 59.49,68.36 59.62,68.23 59.62,67.88 59.75,67.75 60,67.75 60.13,67.88 60.13,68.23 60.25,68.36 60.51,68.36 60.64,68.23 60.64,67.88 60.76,67.75 61.02,67.75 61.14,67.88 61.14,68.23 61.27,68.36 61.52,68.36 61.65,68.23 61.65,67.88 61.78,67.75 62.03,67.75 62.16,67.88 62.16,68.23 62.29,68.36 62.54,68.36 62.67,68.23 62.67,67.88 62.79,67.75 63.05,67.75 63.18,67.88 63.18,68.23 63.3,68.36 63.56,68.36 63.68,68.23 63.68,67.88 63.81,67.75 64.06,67.75 64.19,67.88 64.19,68.23 64.32,68.36 64.57,68.36 64.7,68.23 64.7,67.88 64.83,67.75 65.08,67.75 65.21,67.88 65.21,68.23 65.33,68.36 65.59,68.36 65.72,68.23 65.72,67.88 65.84,67.75 66.1,67.75 66.22,67.88 66.22,68.23 66.35,68.36 66.6,68.36 66.73,68.23 66.73,67.88 66.86,67.75 67.11,67.75 67.24,67.88 67.24,68.23 67.37,68.36 67.62,68.36 67.75,68.23 67.75,67.88 67.87,67.75 68.13,67.75 68.26,67.88 68.26,68.23 68.38,68.36 68.64,68.36 68.76,68.23 68.76,67.88 68.89,67.75 69.14,67.75 69.27,67.88 69.27,68.23 69.4,68.36 78.65,68.36 79.89,67.12 v1(79.89,66.52)
  BOTTOM w0.102: UC1.F40 84.7,63.63 84.44,63.63 84.35,63.72 84.08,63.72 84,63.64 83.68,63.64 83.61,63.72 83.55,63.72 83.48,63.78 82.9,63.78 81.43,65.25 80.71,65.25 79.89,66.08 v1(79.89,66.52) ; JDIMM1.37 35.77,80.29 v1(35.73,80.24)
DDR_A_SDQ16: length 63.7
  IN2 w0.127: v1(80.62,63.9) 78.06,66.46 51.47,66.46 38.95,78.98 37.78,78.98 37.63,78.83 33.56,78.83 v1(32.68,77.96)
  BOTTOM w0.102: v1(32.68,77.96) 32.68,77.82 31.9,77.04 JDIMM1.50 ; UC1.J40 84.3,61.76 84,62.06 83.62,62.06 83.6,62.04 82.48,62.04 v1(80.62,63.9)
DDR_A_SDQ17: length 64.8
  IN2 w0.127: v1(79.44,63.92) 79.44,64.39 77.75,66.08 65.07,66.08 64.94,65.95 64.94,65.46 64.81,65.34 64.44,65.34 64.31,65.46 64.31,65.95 64.18,66.08 63.93,66.08 63.8,65.95 63.8,65.46 63.68,65.34 63.42,65.34 63.3,65.46 63.3,65.95 63.17,66.08 62.91,66.08 62.79,65.95 62.79,65.46 62.66,65.34 62.33,65.34 62.21,65.46 62.21,65.95 62.08,66.08 61.82,66.08 61.7,65.95 61.7,65.46 61.57,65.34 60.58,65.34 60.1,65.82 51.58,65.82 38.79,78.6 37.93,78.6 37.79,78.45 34.7,78.45 v1(34.21,77.96)
  BOTTOM w0.102: UC1.J41 82.35,61.76 81.12,62.99 80.37,62.99 v1(79.44,63.92) ; JDIMM1.49 34.88,77.29 v1(34.21,77.96)
DDR_A_SDQ18: length 65.2
  IN2 w0.127: v1(34.21,74.91) 34.21,74.54 34.34,74.41 37.27,74.41 38.32,73.37 38.93,73.37 50.4,61.9 50.89,61.9 51.01,61.77 51.01,61.58 51.14,61.45 51.39,61.45 51.52,61.58 51.52,61.77 51.65,61.9 51.9,61.9 52.03,61.77 52.03,61.58 52.16,61.45 52.41,61.45 52.54,61.58 52.54,61.77 52.66,61.9 52.92,61.9 53.05,61.77 53.05,61.58 53.17,61.45 53.43,61.45 53.55,61.58 53.55,61.77 53.68,61.9 53.93,61.9 54.06,61.77 54.06,61.58 54.19,61.45 54.44,61.45 54.57,61.58 54.57,61.77 54.7,61.9 54.95,61.9 55.08,61.77 55.08,61.58 55.2,61.45 55.46,61.45 55.59,61.58 55.59,61.77 55.71,61.9 55.97,61.9 56.09,61.77 56.09,61.58 56.22,61.45 56.47,61.45 56.6,61.58 56.6,61.77 56.73,61.9 56.98,61.9 57.11,61.77 57.11,61.58 57.24,61.45 57.49,61.45 57.62,61.58 57.62,61.77 57.74,61.9 73.71,61.9 73.96,62.16 78.75,62.16 79.89,61.02 v1(79.89,60.62)
  BOTTOM w0.102: UC1.N40 84.35,59.78 84.09,59.78 84,59.87 83.62,59.87 83.43,59.69 80.56,59.69 79.89,60.36 v1(79.89,60.62) ; v1(34.21,74.91) 35.33,73.78 JDIMM1.63
DDR_A_SDQ19: length 64.3
  IN2 w0.127: v1(78.7,60.61) 77.54,61.77 73.96,61.77 73.71,61.52 61.49,61.52 61.36,61.39 61.36,61.2 61.24,61.07 60.98,61.07 60.86,61.2 60.86,61.39 60.73,61.52 60.48,61.52 60.35,61.39 60.35,61.2 60.22,61.07 59.9,61.07 59.77,61.2 59.77,61.39 59.64,61.52 59.32,61.52 59.2,61.39 59.2,61.2 59.07,61.07 58.75,61.07 58.62,61.2 58.62,61.39 58.49,61.52 58.24,61.52 58.11,61.39 58.11,61.2 57.98,61.07 50.69,61.07 38.78,72.98 38.16,72.98 37.12,74.03 33.56,74.03 v1(32.68,74.91)
  BOTTOM w0.102: UC1.N41 83.79,59.48 79.83,59.48 v1(78.7,60.61) ; v1(32.68,74.91) 31.81,74.04 JDIMM1.62
DDR_A_SDQ20: length 64.5
  IN2 w0.127: v1(31.16,77.96) 32.42,79.21 37.47,79.21 37.62,79.36 39.11,79.36 51.63,66.84 78.24,66.84 81.09,63.99 81.09,63.81 81.87,63.03 v1(82.49,63.03)
  BOTTOM w0.102: v1(82.49,63.03) 82.49,62.84 82.87,62.46 83.32,62.46 83.4,62.54 84.01,62.54 84.09,62.62 84.35,62.62 84.44,62.53 84.7,62.53 UC1.H40 ; JDIMM1.46 29.64,78.04 30.2,77.47 30.68,77.47 v1(31.16,77.96)
DDR_A_SDQ21: length 65.1
  IN2 w0.127: v1(35.73,77.96) 37.83,77.96 37.95,78.07 38.09,78.22 38.64,78.22 51.54,65.31 60.07,65.31 60.42,64.96 65.27,64.96 65.45,65.13 65.45,65.57 65.57,65.7 65.83,65.7 65.96,65.57 65.96,65.08 66.08,64.96 66.34,64.96 66.46,65.08 66.46,65.57 66.59,65.7 66.84,65.7 66.97,65.57 66.97,65.08 67.1,64.96 67.35,64.96 67.48,65.08 67.48,65.57 67.61,65.7 67.86,65.7 67.99,65.57 67.99,65.24 68.11,65.12 68.37,65.12 68.5,65.24 68.5,65.57 68.62,65.7 68.88,65.7 69,65.57 69,65.18 69.13,65.05 69.38,65.05 69.51,65.18 69.51,65.57 69.64,65.7 69.89,65.7 70.02,65.57 70.02,65.18 70.15,65.05 70.58,65.05 70.71,65.18 70.71,65.57 70.84,65.7 71.09,65.7 71.22,65.57 71.22,65.18 71.35,65.05 71.6,65.05 71.73,65.18 71.73,65.57 71.85,65.7 72.11,65.7 72.24,65.57 72.24,65.12 72.36,64.99 72.62,64.99 72.74,65.12 72.74,65.57 72.87,65.7 77.57,65.7 v1(78.6,64.67)
  BOTTOM w0.102: UC1.H41 83.52,62.31 83.46,62.25 82.56,62.25 81.09,63.72 81.09,64.11 80.53,64.67 v1(78.6,64.67) ; JDIMM1.45 36.06,78.29 v1(35.73,77.96)
DDR_A_SDQ22: length 64.1
  IN2 w0.127: v1(31.16,74.91) 31.8,75.55 37.22,75.55 38.64,74.13 39.25,74.13 50.72,62.66 63.59,62.66 64.2,63.28 73.24,63.28 73.6,62.92 80.05,62.92 82.42,60.55 v1(82.42,60.5)
  BOTTOM w0.102: v1(31.16,74.91) 30.68,74.43 30.2,74.43 29.92,74.71 29.92,74.71 29.59,75.04 JDIMM1.58 ; v1(82.42,60.5) 82.42,60.35 82.67,60.09 83.26,60.09 83.51,60.34 84.01,60.34 84.09,60.42 84.35,60.42 84.44,60.33 84.7,60.33 UC1.M40
DDR_A_SDQ23: length 65
  IN2 w0.127: v1(35.73,74.91) 37.32,74.91 38.48,73.75 39.09,73.75 50.56,62.28 64.11,62.28 64.24,62.41 64.24,62.77 64.36,62.9 64.62,62.9 64.74,62.77 64.74,62.41 64.87,62.28 65.12,62.28 65.25,62.41 65.25,62.77 65.38,62.9 65.63,62.9 65.76,62.77 65.76,62.41 65.89,62.28 66.14,62.28 66.27,62.41 66.27,62.77 66.39,62.9 66.65,62.9 66.78,62.77 66.78,62.41 66.9,62.28 67.23,62.28 67.36,62.41 67.36,62.77 67.48,62.9 67.74,62.9 67.87,62.77 67.87,62.41 67.99,62.28 68.25,62.28 68.37,62.41 68.37,62.77 68.5,62.9 68.75,62.9 68.88,62.77 68.88,62.41 69.01,62.28 69.26,62.28 69.39,62.41 69.39,62.77 69.52,62.9 69.77,62.9 69.9,62.77 69.9,62.41 70.02,62.28 70.28,62.28 70.41,62.41 70.41,62.77 70.53,62.9 70.79,62.9 70.91,62.77 70.91,62.41 71.04,62.28 71.29,62.28 71.42,62.41 71.42,62.77 71.55,62.9 71.8,62.9 71.93,62.77 71.93,62.41 72.06,62.28 72.31,62.28 72.44,62.41 72.44,62.77 72.56,62.9 72.82,62.9 72.95,62.77 72.95,62.41 73.07,62.28 73.58,62.28 73.84,62.54 79.17,62.54 v1(81.09,60.62)
  BOTTOM w0.102: JDIMM1.59 35.86,74.78 v1(35.73,74.91) ; UC1.M41 83.57,60.11 83.35,59.89 81.38,59.89 81.09,60.17 v1(81.09,60.62)
DDR_A_SDQ24: length 65.3
  IN2 w0.127: v1(35.73,72.62) 36.69,72.62 39.4,69.91 39.4,69.13 39.6,68.93 39.78,68.93 39.99,69.14 40.17,69.14 40.33,68.99 40.33,68.81 40.01,68.49 40.01,68.31 40.19,68.13 40.37,68.13 40.69,68.45 40.87,68.45 41.05,68.27 41.05,68.09 40.73,67.77 40.73,67.59 40.91,67.41 41.09,67.41 41.41,67.73 41.59,67.73 41.77,67.55 41.77,67.37 41.45,67.05 41.45,66.87 41.63,66.69 41.81,66.69 42.13,67.01 42.31,67.01 42.49,66.83 42.49,66.65 42.17,66.33 42.17,66.15 42.35,65.97 42.53,65.97 42.84,66.29 43.02,66.29 43.2,66.11 43.2,65.93 42.89,65.61 42.89,65.43 43.07,65.26 43.25,65.26 43.56,65.57 43.74,65.57 43.92,65.39 43.92,65.21 43.61,64.9 43.61,64.72 43.79,64.54 43.97,64.54 44.28,64.85 44.46,64.85 44.64,64.67 44.64,64.49 44.33,64.18 44.33,64 44.5,63.82 44.68,63.82 45,64.13 45.18,64.13 49.54,59.77 72.96,59.77 73.48,60.29 74.54,60.29 v1(74.87,60.62)
  BOTTOM w0.102: JDIMM1.67 35.89,72.78 v1(35.73,72.62) ; v1(74.87,60.62) 74.87,60.49 76.49,58.87 83.55,58.87 83.57,58.85 83.95,58.85 84.09,58.7 84.47,58.7 84.57,58.6 UC1.R40
DDR_A_SDQ25: length 63.7
  IN2 w0.127: v1(82.54,58.49) 82.54,59 81.82,59.72 75.35,59.72 75.03,59.39 49.19,59.39 45.32,63.26 44.43,63.26 39.02,68.66 39.02,69.75 36.66,72.12 31.66,72.12 v1(31.16,72.62)
  BOTTOM w0.102: v1(82.54,58.49) 82.95,58.08 83.23,58.08 83.31,58.16 84.03,58.16 84.09,58.21 84.35,58.21 84.65,57.91 UC1.T40 ; v1(31.16,72.62) 30.57,72.04 JDIMM1.70
DDR_A_SDQ26: length 64.8
  IN2 w0.127: v1(81.59,56.81) 81.59,57.63 81.46,57.76 80.7,57.76 80.14,57.2 78.29,57.2 77.98,57.51 75.28,57.51 75.14,57.65 47.66,57.65 47.27,58.04 47.09,58.04 46.75,57.71 46.57,57.71 46.39,57.89 46.39,58.07 46.73,58.4 46.73,58.58 46.55,58.76 46.37,58.76 46.03,58.43 45.85,58.43 45.67,58.61 45.67,58.79 46.01,59.12 46.01,59.3 45.83,59.48 45.65,59.48 45.32,59.14 45.14,59.14 44.96,59.32 44.96,59.5 45.29,59.84 45.29,60.02 45.11,60.2 44.93,60.2 44.6,59.86 44.42,59.86 44.24,60.04 44.24,60.22 44.57,60.56 44.57,60.74 44.39,60.92 44.21,60.92 43.88,60.58 43.7,60.58 43.52,60.76 43.52,60.94 43.85,61.28 43.85,61.46 43.66,61.65 43.48,61.65 43.15,61.31 42.97,61.31 42.79,61.49 42.79,61.67 43.12,62.01 43.12,62.19 v1(35.73,69.57)
  BOTTOM w0.102: UC1.W40 84.32,56.26 83.98,56.59 83.41,56.59 83.41,56.6 83.09,56.6 82.53,56.04 82.03,56.04 81.59,56.48 v1(81.59,56.81) ; v1(35.73,69.57) 35.73,69.15 36.1,68.78 JDIMM1.83
DDR_A_SDQ27: length 64.5
  IN2 w0.127: v1(32.68,69.57) 33.48,68.77 35.45,68.77 38.83,65.4 38.83,64.38 46.47,56.74 65.56,56.74 65.88,56.42 71.44,56.42 71.87,56.85 73.32,56.85 73.62,56.55 77.56,56.55 78.2,55.91 80.25,55.91 80.42,56.07 v1(80.42,56.81)
  BOTTOM w0.102: v1(32.68,69.57) 31.64,68.54 JDIMM1.84 ; UC1.Y40 84.67,55.71 84.36,56.01 84.08,56.01 83.9,55.83 81.4,55.83 v1(80.42,56.81)
DDR_A_SDQ28: length 64.5
  IN2 w0.127: v1(32.68,72.62) 32.68,73.07 33.11,73.5 36.89,73.5 49.86,60.54 61.83,60.54 61.96,60.66 61.96,60.86 62.09,60.99 62.34,60.99 62.47,60.86 62.47,60.66 62.59,60.54 62.85,60.54 62.97,60.66 62.97,60.86 63.1,60.99 74,60.99 74.39,61.37 76.72,61.37 v1(77.47,60.62)
  BOTTOM w0.102: UC1.P40 84.7,59.23 84.44,59.23 84.35,59.32 84.08,59.32 84.04,59.28 84.02,59.28 84,59.26 83.74,59.26 83.72,59.28 78.81,59.28 v1(77.47,60.62) ; v1(32.68,72.62) 32.11,73.2 30.16,73.2 29.99,73.04 JDIMM1.66
DDR_A_SDQ29: length 65.5
  IN2 w0.127: v1(76.14,60.62) 75.64,61.12 74.64,61.12 74.13,60.6 73.25,60.6 72.8,60.15 72.5,60.15 72.38,60.28 72.38,60.48 72.25,60.6 72,60.6 71.87,60.48 71.87,60.28 71.74,60.15 71.49,60.15 71.36,60.28 71.36,60.48 71.23,60.6 70.98,60.6 70.85,60.48 70.85,60.28 70.73,60.15 70.42,60.15 70.3,60.28 70.3,60.48 70.17,60.6 69.92,60.6 69.79,60.48 69.79,60.28 69.66,60.15 69.41,60.15 69.28,60.28 69.28,60.48 69.15,60.6 68.9,60.6 68.77,60.48 68.77,60.28 68.65,60.15 68.23,60.15 68.11,60.28 68.11,60.48 67.98,60.6 67.73,60.6 67.6,60.48 67.6,60.28 67.47,60.15 67.14,60.15 67.01,60.28 67.01,60.48 66.89,60.6 66.63,60.6 66.51,60.48 66.51,60.28 66.38,60.15 66.13,60.15 66,60.28 66,60.48 65.87,60.6 65.62,60.6 65.49,60.48 65.49,60.28 65.36,60.15 65.11,60.15 64.98,60.28 64.98,60.48 64.86,60.6 64.6,60.6 64.47,60.48 64.47,60.28 64.35,60.15 64.09,60.15 63.97,60.28 63.97,60.48 63.84,60.6 63.59,60.6 63.46,60.48 63.46,60.28 63.33,60.15 49.7,60.15 36.74,73.12 34.7,73.12 v1(34.21,72.62)
  BOTTOM w0.102: UC1.P41 84.1,59.01 84.06,59.05 83.66,59.05 83.63,59.08 77.68,59.08 v1(76.14,60.62) ; JDIMM1.71 36.14,71.78 36.03,71.9 34.93,71.9 v1(34.21,72.62)
DDR_A_SDQ30: length 65.2
  IN2 w0.127: v1(34.21,69.57) 34.63,69.16 35.61,69.16 39.6,65.17 39.6,64.99 39.26,64.66 39.26,64.48 39.44,64.3 39.62,64.3 39.96,64.63 40.14,64.63 40.32,64.45 40.32,64.27 39.98,63.94 39.98,63.76 40.16,63.58 40.34,63.58 40.68,63.91 40.86,63.91 41.03,63.73 41.03,63.55 40.7,63.22 40.7,63.04 40.88,62.86 41.06,62.86 41.39,63.19 41.57,63.19 41.75,63.01 41.75,62.83 41.42,62.5 41.42,62.32 41.6,62.14 41.78,62.14 42.11,62.47 42.29,62.47 42.47,62.29 42.47,62.11 42.14,61.78 42.14,61.6 46.47,57.27 74.73,57.27 74.87,57.13 77.82,57.13 78.13,56.81 v1(79.7,56.81)
  BOTTOM w0.102: v1(79.7,56.81) 80.15,57.27 83.3,57.27 83.57,57 83.97,57 84.12,57.16 84.31,57.16 84.65,56.81 UC1.V40 ; JDIMM1.79 36.2,69.78 35.93,70.06 35.9,70.06 35.87,70.09 34.72,70.09 v1(34.21,69.57)
DDR_A_SDQ31: length 64.5
  IN2 w0.127: v1(31.16,69.57) 32.34,68.39 34.16,68.39 35.05,67.5 36.18,67.5 37.58,66.11 37.58,65.93 37.41,65.76 37.41,65.58 37.59,65.4 37.77,65.4 37.94,65.57 38.12,65.57 38.3,65.39 38.3,65.21 37.92,64.83 37.92,64.65 46.28,56.29 65.47,56.29 65.72,56.04 71.6,56.04 72.03,56.47 72.97,56.47 73.34,56.11 77.39,56.11 78.22,55.28 81.21,55.28 v1(82.74,56.81)
  BOTTOM w0.102: v1(31.16,69.57) 30.68,69.09 30.2,69.09 29.76,69.54 JDIMM1.80 ; UC1.V41 84.21,56.8 83.48,56.8 83.31,56.97 82.84,56.97 82.74,56.87 v1(82.74,56.81)
DDR_A_SDQ32: length 61.6
  IN2 w0.127: v1(30.95,44.95) 32.2,46.21 35.51,46.21 36.49,47.19 38.51,47.19 39.78,48.46 39.78,49.11 46.43,55.76 65.24,55.76 65.62,55.38 77.45,55.38 78,54.83 81.18,54.83 82.4,53.61 v1(82.4,53.61)
  BOTTOM w0.102: UC1.AD41 84.05,53.51 84.05,53.51 83.57,53.51 83.44,53.38 82.63,53.38 v1(82.4,53.61) ; v1(30.95,44.95) 30.03,44.03 JDIMM1.174
DDR_A_SDQ33: length 62.7
  IN2 w0.127: v1(78.66,53.7) 78,53.7 77.56,54.13 74.07,54.13 73.69,54.51 73.24,54.51 73.11,54.39 73.11,54.18 72.98,54.05 72.73,54.05 72.6,54.18 72.6,54.49 72.48,54.62 72.22,54.62 72.09,54.49 72.09,54.18 71.97,54.05 71.71,54.05 71.59,54.18 71.59,54.49 71.46,54.62 71.21,54.62 71.08,54.49 71.08,54.18 70.95,54.05 70.7,54.05 70.57,54.18 70.57,54.49 70.44,54.62 70.19,54.62 70.06,54.49 70.06,54.18 69.94,54.05 69.68,54.05 69.55,54.18 69.55,54.49 69.43,54.62 60.25,54.62 60.04,54.83 52.03,54.83 51.49,54.28 46.68,54.28 38.83,46.43 36.8,46.43 35.82,45.45 34.49,45.45 v1(33.99,44.95)
  BOTTOM w0.102: v1(78.66,53.7) 78.66,53.59 79.24,53.01 83.42,53.01 83.68,53.27 84,53.27 84.08,53.19 84.35,53.19 84.44,53.29 84.7,53.29 UC1.AD40 ; v1(33.99,44.95) 34.66,44.29 JDIMM1.173
DDR_A_SDQ34: length 62.3
  IN2 w0.127: v1(33.99,41.9) 33.99,41.54 34.12,41.41 35.99,41.41 37.13,42.55 38.94,42.55 40.8,44.41 40.98,44.41 41.25,44.13 41.43,44.13 41.61,44.31 41.61,44.49 41.34,44.77 41.34,44.95 41.52,45.13 41.75,45.13 42,44.88 42.18,44.88 42.36,45.06 42.36,45.24 42.09,45.52 42.09,45.7 42.24,45.85 42.47,45.85 42.72,45.6 42.9,45.6 43.08,45.78 43.08,45.96 42.83,46.21 42.83,46.39 43.01,46.57 43.19,46.57 43.44,46.32 43.62,46.32 48.52,51.23 74.94,51.23 75.15,51.02 80.61,51.02 v1(81.19,51.6)
  BOTTOM w0.102: JDIMM1.187 36.22,40.79 35.87,41.13 34.76,41.13 v1(33.99,41.9) ; UC1.AH41 84.04,51.31 84.03,51.31 83.57,51.31 83.25,50.99 81.32,50.99 81.19,51.12 v1(81.19,51.6)
DDR_A_SDQ35: length 61.6
  IN2 w0.127: v1(75.63,51.72) 75.36,51.99 47.3,51.99 39.54,44.23 37.52,44.23 35.8,42.51 31.72,42.51 31.11,41.9 v1(30.95,41.9)
  BOTTOM w0.102: JDIMM1.186 30.08,41.03 v1(30.95,41.9) ; v1(75.63,51.72) 75.63,51.22 76.06,50.79 83.4,50.79 83.68,51.07 84,51.07 84.07,51.01 84.36,51.01 84.44,51.09 84.7,51.09 UC1.AH40
DDR_A_SDQ36: length 62.6
  IN2 w0.127: v1(79.96,53.67) 79.9,53.67 79.25,54.32 77.91,54.32 77.24,55 65.46,55 65.15,55.31 46.53,55.31 40.16,48.95 40.16,48.3 38.67,46.81 36.64,46.81 35.66,45.83 33.35,45.83 v1(32.47,44.95)
  BOTTOM w0.102: JDIMM1.170 29.56,45.03 29.97,45.44 31.98,45.44 v1(32.47,44.95) ; v1(79.96,53.67) 79.95,53.68 79.95,54.14 80.09,54.28 82.63,54.28 82.76,54.42 83.24,54.42 83.29,54.36 84,54.36 84.06,54.31 84.35,54.31 84.65,54.61 UC1.AB40
DDR_A_SDQ37: length 62.2
  IN2 w0.127: v1(35.52,44.95) 35.87,44.95 36.96,46.05 38.98,46.05 46.84,53.9 51.65,53.9 52.19,54.45 59.88,54.45 60.09,54.24 61.81,54.24 61.93,54.11 61.93,53.79 62.06,53.67 62.32,53.67 62.44,53.79 62.44,54.11 62.57,54.24 62.82,54.24 62.95,54.11 62.95,53.79 63.08,53.67 63.33,53.67 63.46,53.79 63.46,54.11 63.59,54.24 63.84,54.24 63.97,54.11 63.97,53.79 64.09,53.67 64.35,53.67 64.47,53.79 64.47,54.11 64.6,54.24 64.86,54.24 64.98,54.11 64.98,53.79 65.11,53.67 65.36,53.67 65.49,53.79 65.49,54.11 65.62,54.24 65.87,54.24 66,54.11 66,53.79 66.13,53.67 66.38,53.67 66.51,53.79 66.51,54.11 66.63,54.24 66.89,54.24 67.01,54.11 67.01,53.79 67.14,53.67 67.4,53.67 67.52,53.79 67.52,54.11 67.65,54.24 67.9,54.24 68.03,54.11 68.03,53.79 68.16,53.67 68.41,53.67 68.54,53.79 68.54,54.11 68.67,54.24 68.92,54.24 69.05,54.11 69.05,53.79 69.17,53.67 77.65,53.67 78.15,53.16 80.94,53.16 81.16,53.38 v1(81.16,53.63)
  BOTTOM w0.102: v1(35.52,44.95) 35.85,45.29 JDIMM1.169 ; UC1.AC40 84.3,54.06 83.95,53.71 83.48,53.71 83.43,53.66 83.24,53.66 82.92,53.66 82.5,54.08 81.6,54.08 v1(81.16,53.63)
DDR_A_SDQ38: length 62.6
  IN2 w0.127: v1(35.52,41.9) 35.73,41.9 36.96,43.13 37.14,43.13 37.33,42.93 37.51,42.93 37.69,43.11 37.69,43.29 37.49,43.49 37.49,43.67 37.68,43.85 39.7,43.85 43.08,47.22 43.26,47.22 43.53,46.95 43.71,46.95 43.89,47.13 43.89,47.31 43.62,47.58 43.62,47.76 43.79,47.94 43.97,47.94 44.25,47.67 44.43,47.67 44.61,47.85 44.61,48.03 44.33,48.3 44.33,48.48 44.58,48.73 44.76,48.73 45.04,48.46 45.22,48.46 45.4,48.64 45.4,48.82 45.12,49.09 45.12,49.27 45.3,49.45 45.48,49.45 45.76,49.18 45.94,49.18 46.12,49.36 46.12,49.54 45.84,49.81 45.84,49.99 46.02,50.17 46.2,50.17 46.47,49.9 46.65,49.9 46.83,50.08 46.83,50.25 46.56,50.53 46.56,50.71 46.74,50.89 46.92,50.89 47.19,50.61 47.37,50.61 47.55,50.79 47.55,50.97 47.28,51.25 47.28,51.43 47.46,51.61 75.19,51.61 75.49,51.3 79.71,51.3 80.01,51.6 80,51.6 v1(80,51.6)
  BOTTOM w0.102: UC1.AF40 84.7,52.19 84.44,52.19 84.35,52.09 84.09,52.09 84.01,52.17 84,52.17 84,52.18 80.11,52.18 80.01,52.08 80.01,51.6 v1(80,51.6) ; JDIMM1.183 35.64,41.79 v1(35.52,41.9)
DDR_A_SDQ39: length 61.3
  IN2 w0.127: v1(32.47,41.9) 33.35,41.03 36.14,41.03 37.29,42.17 40.01,42.17 48.48,50.64 81.72,50.64 82.44,51.36 v1(82.44,51.6)
  BOTTOM w0.102: UC1.AG40 84.35,51.64 84.1,51.64 84,51.54 83.52,51.54 83.48,51.51 83.48,51.51 83.23,51.26 82.77,51.26 v1(82.44,51.6) ; JDIMM1.182 29.6,42.03 29.97,42.4 31.97,42.4 v1(32.47,41.9)
DDR_A_SDQ40: length 63.1
  IN2 w0.127: v1(79.82,49.38) 79.43,49.77 74.02,49.77 73.91,49.66 48.79,49.66 48.61,49.48 48.61,49.3 48.83,49.08 48.83,48.9 48.65,48.72 48.48,48.72 48.25,48.94 48.07,48.94 47.89,48.76 47.89,48.58 48.21,48.27 48.21,48.09 48.03,47.91 47.85,47.91 47.53,48.22 47.35,48.22 47.18,48.04 47.18,47.86 47.49,47.55 47.49,47.37 47.31,47.19 47.13,47.19 46.82,47.51 46.64,47.51 46.46,47.33 46.46,47.15 46.77,46.83 46.77,46.65 46.59,46.47 46.41,46.47 46.1,46.79 45.92,46.79 45.74,46.61 45.74,46.43 46.05,46.11 46.05,45.93 45.88,45.75 45.7,45.75 45.38,46.07 45.2,46.07 45.02,45.89 45.02,45.71 45.33,45.39 45.33,45.21 45.16,45.03 44.98,45.03 44.66,45.35 44.48,45.35 44.3,45.17 44.3,44.99 44.62,44.67 44.62,44.49 44.44,44.31 44.26,44.31 43.94,44.63 43.76,44.63 40.39,41.26 37.67,41.26 36.28,39.87 v1(35.52,39.87)
  BOTTOM w0.102: UC1.AK41 84.19,50.18 82.82,50.18 82.74,50.1 80.54,50.1 v1(79.82,49.38) ; JDIMM1.195 36,38.79 35.52,39.26 v1(35.52,39.87)
DDR_A_SDQ41: length 61.9
  IN2 w0.127: v1(30.95,39.87) 30.95,40.35 31.47,40.87 32.74,40.87 33.12,40.49 36.37,40.49 37.51,41.64 40.23,41.64 48.66,50.07 80.27,50.07 v1(80.96,49.38)
  BOTTOM w0.102: UC1.AK40 84.7,49.99 84.44,49.99 84.35,49.89 84.08,49.89 84,49.98 82.9,49.98 82.82,49.89 81.48,49.89 80.97,49.38 v1(80.96,49.38) ; JDIMM1.194 30.11,39.03 v1(30.95,39.87)
DDR_A_SDQ42: length 62.8
  IN2 w0.127: v1(35.52,36.82) 37.01,36.82 38.02,37.84 42.84,37.84 52.23,47.22 66.22,47.22 66.35,47.09 66.35,46.78 66.48,46.65 66.73,46.65 66.86,46.78 66.86,47.09 66.99,47.22 67.35,47.22 67.48,47.09 67.48,46.78 67.61,46.65 67.86,46.65 67.99,46.78 67.99,47.09 68.11,47.22 68.37,47.22 68.49,47.09 68.49,46.78 68.62,46.65 68.88,46.65 69,46.78 69,47.09 69.13,47.22 69.4,47.22 69.53,47.09 69.53,46.78 69.65,46.65 69.91,46.65 70.03,46.78 70.03,47.09 70.16,47.22 70.42,47.22 70.54,47.09 70.54,46.78 70.67,46.65 70.92,46.65 71.05,46.78 71.05,47.09 71.18,47.22 71.43,47.22 71.56,47.09 71.56,46.78 71.69,46.65 71.94,46.65 72.07,46.78 72.07,47.09 72.19,47.22 72.45,47.22 72.57,47.09 72.57,46.78 72.7,46.65 72.96,46.65 73.08,46.78 73.08,47.09 73.21,47.22 74.95,47.22 75.47,46.7 78.54,46.7 79.12,47.28 79.12,47.66 79.57,48.11 80.58,48.11 v1(81.22,47.47)
  BOTTOM w0.102: JDIMM1.207 36.01,35.79 35.52,36.28 v1(35.52,36.82) ; v1(81.22,47.47) 81.77,48.03 84.2,48.03 UC1.AP41
DDR_A_SDQ43: length 62.2
  IN2 w0.127: v1(32.47,36.82) 33.35,35.95 42.03,35.95 51.97,45.89 78.87,45.89 80,47.02 82.07,47.02 v1(82.49,47.44)
  BOTTOM w0.102: v1(32.47,36.82) 31.47,35.82 30.19,35.82 29.9,35.54 JDIMM1.208 ; UC1.AP40 84.65,48.01 84.35,47.71 84.07,47.71 84,47.78 83.96,47.78 83.91,47.83 82.66,47.83 82.49,47.66 v1(82.49,47.44)
DDR_A_SDQ44: length 63.4
  IN2 w0.127: v1(33.99,39.87) 33.89,39.77 33.89,39.52 34.03,39.38 36.33,39.38 37.73,40.78 40.45,40.78 40.71,41.04 40.89,41.04 41.21,40.73 41.39,40.73 41.57,40.91 41.57,41.09 41.25,41.4 41.25,41.58 41.43,41.76 41.61,41.76 41.93,41.45 42.11,41.45 42.29,41.63 42.29,41.81 41.97,42.12 41.97,42.3 42.15,42.48 42.33,42.48 42.65,42.17 42.83,42.17 43.07,42.41 43.07,42.59 42.75,42.9 42.75,43.08 42.95,43.28 43.14,43.28 43.45,42.96 43.63,42.96 43.81,43.14 43.81,43.32 43.49,43.64 43.49,43.82 43.67,44 43.85,44 44.17,43.68 44.35,43.68 49.94,49.28 77.4,49.28 v1(77.5,49.38)
  BOTTOM w0.102: UC1.AJ41 83.7,50.59 82.65,50.59 82.57,50.5 78.65,50.5 77.79,49.65 77.77,49.65 v1(77.5,49.38) ; v1(33.99,39.87) 34.56,40.43 35.68,40.43 36.33,39.79 JDIMM1.191
DDR_A_SDQ45: length 61.8
  IN2 w0.127: v1(78.67,49.38) 78.19,48.9 50.1,48.9 41.55,40.35 39.18,40.35 38.78,39.94 37.43,39.94 36.48,39 32.69,39 32.47,39.22 v1(32.47,39.87)
  BOTTOM w0.102: v1(32.47,39.87) 31.84,40.5 30.09,40.5 29.63,40.03 JDIMM1.190 ; v1(78.67,49.38) 79.59,50.3 82.65,50.3 82.74,50.38 83.94,50.38 84.09,50.54 84.35,50.54 UC1.AJ40
DDR_A_SDQ46: length 62.9
  IN2 w0.127: v1(33.99,36.82) 34.49,36.33 41.88,36.33 52.39,46.84 61.65,46.84 61.78,46.71 61.78,46.39 61.91,46.27 62.16,46.27 62.29,46.39 62.29,46.71 62.41,46.84 62.67,46.84 62.8,46.71 62.8,46.39 62.92,46.27 63.18,46.27 63.3,46.39 63.3,46.71 63.43,46.84 63.68,46.84 63.81,46.71 63.81,46.39 63.94,46.27 64.19,46.27 64.32,46.39 64.32,46.71 64.45,46.84 64.7,46.84 64.83,46.71 64.83,46.39 64.95,46.27 65.21,46.27 65.34,46.39 65.34,46.71 65.46,46.84 65.72,46.84 65.84,46.71 65.84,46.39 65.97,46.27 78.53,46.27 v1(79.79,47.52)
  BOTTOM w0.102: v1(33.99,36.82) 34.6,37.43 35.64,37.43 36.28,36.79 JDIMM1.203 ; v1(79.79,47.52) 79.79,47.51 79.79,47.51 80.76,48.48 82.21,48.48 82.25,48.44 83.58,48.44 83.63,48.49 83.8,48.49 UC1.AN41
DDR_A_SDQ47: length 62.6
  IN2 w0.127: v1(30.95,36.82) 32.2,35.57 37.2,35.57 37.77,35 38.89,35 39.46,35.57 42.19,35.57 52.13,45.51 79.06,45.51 v1(80.14,46.59)
  BOTTOM w0.102: UC1.AN40 84.35,48.34 84.09,48.34 83.99,48.23 81.44,48.23 80.84,47.63 80.84,47.28 v1(80.14,46.59) ; v1(30.95,36.82) 30.46,36.34 29.87,36.34 29.67,36.54 JDIMM1.204
DDR_A_SDQ48: length 63.3
  IN2 w0.127: v1(32.47,34.16) 33.35,35.03 36.72,35.03 37.28,34.47 39.65,34.47 39.78,34.59 39.78,34.88 39.91,35 40.16,35 40.29,34.88 40.29,34.59 40.42,34.47 41.84,34.47 51.95,44.57 74.05,44.57 74.55,45.07 78.71,45.07 v1(79.23,44.55)
  BOTTOM w0.102: v1(79.23,44.55) 80.21,45.53 80.36,45.53 81.43,46.6 83.61,46.6 83.68,46.67 84,46.67 84.08,46.59 84.35,46.59 84.44,46.69 84.7,46.69 UC1.AT40 ; v1(32.47,34.16) 31.85,33.54 JDIMM1.216
DDR_A_SDQ49: length 63.1
  IN2 w0.127: v1(30.95,34.16) 31.53,33.58 35.79,33.58 36.13,33.23 42.23,33.23 52.42,43.43 59.32,43.43 59.47,43.27 59.47,42.96 59.59,42.83 59.85,42.83 59.98,42.96 59.98,43.3 60.1,43.43 60.36,43.43 60.48,43.3 60.48,42.96 60.61,42.83 78.65,42.83 v1(80.4,44.57)
  BOTTOM w0.102: JDIMM1.212 29.72,34.54 29.82,34.64 30.46,34.64 v1(30.95,34.16) ; v1(80.4,44.57) 80.4,45.28 81.48,46.36 UC1.AU41
DDR_A_SDQ50: length 63.4
  IN2 w0.127: v1(30.95,31.11) 32.2,29.85 35.94,29.85 35.95,29.84 37.35,29.84 37.83,29.37 42.35,29.37 52.52,39.53 74.64,39.53 75.15,40.04 80.55,40.04 83.57,43.06 v1(83.57,43.85)
  BOTTOM w0.102: UC1.AY40 83.86,43.85 v1(83.57,43.85) ; v1(30.95,31.11) 30.37,30.54 JDIMM1.228
DDR_A_SDQ51: length 64.5
  IN2 w0.127: v1(33.99,31.11) 34.49,30.61 36.26,30.61 36.27,30.6 37.67,30.6 38.14,30.13 42.04,30.13 52.68,40.77 56.65,40.77 56.77,40.64 56.77,40.42 56.9,40.29 57.15,40.29 57.28,40.42 57.28,40.64 57.41,40.77 57.66,40.77 57.79,40.64 57.79,40.42 57.92,40.29 58.17,40.29 58.3,40.42 58.3,40.64 58.42,40.77 58.68,40.77 58.81,40.64 58.81,40.42 58.93,40.29 59.19,40.29 59.31,40.42 59.31,40.64 59.44,40.77 59.74,40.77 59.86,40.64 59.86,40.42 59.99,40.29 60.24,40.29 60.37,40.42 60.37,40.64 60.5,40.77 60.75,40.77 60.88,40.64 60.88,40.42 61.01,40.29 61.26,40.29 61.39,40.42 61.39,40.64 61.51,40.77 61.77,40.77 61.89,40.64 61.89,40.42 62.02,40.29 62.28,40.29 62.4,40.42 62.4,40.64 62.53,40.77 62.78,40.77 62.91,40.64 62.91,40.42 63.04,40.29 74.32,40.29 74.83,40.8 80.13,40.8 80.75,41.42 v1(80.75,41.49)
  BOTTOM w0.102: v1(80.75,41.49) 82.1,41.49 UC1.BA40 ; v1(33.99,31.11) 34.82,30.29 JDIMM1.229
DDR_A_SDQ52: length 64.5
  IN2 w0.127: v1(76.77,44.62) 76.35,44.19 74.35,44.19 74.22,44.06 74.22,43.72 74.09,43.59 73.84,43.59 73.71,43.72 73.71,44.06 73.59,44.19 73.33,44.19 73.21,44.06 73.21,43.72 73.08,43.59 72.82,43.59 72.7,43.72 72.7,44.06 72.57,44.19 72.32,44.19 72.19,44.06 72.19,43.72 72.06,43.59 71.81,43.59 71.68,43.72 71.68,44.06 71.55,44.19 71.3,44.19 71.17,44.06 71.17,43.72 71.05,43.59 70.79,43.59 70.67,43.72 70.67,44.06 70.54,44.19 70.28,44.19 70.16,44.06 70.16,43.72 70.03,43.59 69.78,43.59 69.65,43.72 69.65,44.06 69.52,44.19 52.11,44.19 41.91,34 36.45,34 35.79,34.65 34.49,34.65 v1(33.99,34.16)
  BOTTOM w0.102: v1(33.99,34.16) 34.63,34.79 36,34.79 36.01,34.79 JDIMM1.211 ; UC1.AR40 84.35,47.24 84.1,47.24 84,47.14 84,47.14 83.97,47.11 83.37,47.11 83.32,47.06 81.31,47.06 80.19,45.94 78.1,45.94 v1(76.77,44.62)
DDR_A_SDQ53: length 64.6
  IN2 w0.127: v1(35.52,34.16) 35.75,34.16 36.29,33.61 42.07,33.61 52.27,43.81 60.86,43.81 60.99,43.68 60.99,43.34 61.12,43.21 61.37,43.21 61.5,43.34 61.5,43.68 61.63,43.81 61.88,43.81 62.01,43.68 62.01,43.34 62.13,43.21 62.39,43.21 62.52,43.34 62.52,43.68 62.64,43.81 62.9,43.81 63.02,43.68 63.02,43.34 63.15,43.21 63.4,43.21 63.53,43.34 63.53,43.68 63.66,43.81 63.91,43.81 64.04,43.68 64.04,43.34 64.17,43.21 64.45,43.21 64.57,43.34 64.57,43.68 64.7,43.81 64.96,43.81 65.08,43.68 65.08,43.34 65.21,43.21 65.46,43.21 65.59,43.34 65.59,43.68 65.72,43.81 65.97,43.81 66.1,43.68 66.1,43.34 66.23,43.21 66.48,43.21 66.61,43.34 66.61,43.68 66.73,43.81 66.99,43.81 67.11,43.68 67.11,43.34 67.24,43.21 67.5,43.21 67.62,43.34 67.62,43.68 67.75,43.81 68,43.81 68.13,43.68 68.13,43.34 68.26,43.21 68.51,43.21 68.64,43.34 68.64,43.68 68.77,43.81 69.02,43.81 69.15,43.68 69.15,43.34 69.27,43.21 74.65,43.21 74.78,43.34 74.78,43.59 74.9,43.72 75.16,43.72 75.28,43.59 75.28,43.4 75.41,43.27 76.7,43.27 v1(78.03,44.6)
  BOTTOM w0.102: v1(78.03,44.6) 79.17,45.74 80.28,45.74 81.38,46.84 83.5,46.84 83.54,46.88 84.19,46.88 UC1.AT41 ; v1(35.52,34.16) 35.89,33.79 JDIMM1.215
DDR_A_SDQ54: length 63.8
  IN2 w0.127: v1(81.83,42.15) 81.83,41.85 80.46,40.48 75.02,40.48 74.45,39.91 52.36,39.91 42.2,29.75 37.99,29.75 37.51,30.22 36.11,30.22 36.1,30.23 33.35,30.23 v1(32.47,31.11)
  BOTTOM w0.102: v1(32.47,31.11) 31.91,31.67 30.09,31.67 29.96,31.54 JDIMM1.224 ; v1(81.83,42.15) 81.83,43.19 83.34,44.71 83.51,44.71 83.65,44.85 84.16,44.85 UC1.AW40
DDR_A_SDQ55: length 63.8
  IN2 w0.127: v1(35.52,31.11) 35.63,30.99 36.42,30.99 36.43,30.99 37.83,30.99 38.23,30.59 41.96,30.59 52.52,41.15 63.3,41.15 63.43,41.02 63.43,40.8 63.55,40.67 63.81,40.67 63.94,40.8 63.94,41.02 64.06,41.15 64.32,41.15 64.44,41.02 64.44,40.8 64.57,40.67 64.82,40.67 64.95,40.8 64.95,41.02 65.08,41.15 65.37,41.15 65.49,41.02 65.49,40.8 65.62,40.67 65.88,40.67 66,40.8 66,41.02 66.13,41.15 66.38,41.15 66.51,41.02 66.51,40.8 66.64,40.67 66.89,40.67 67.02,40.8 67.02,41.02 67.15,41.15 67.4,41.15 67.53,41.02 67.53,40.8 67.65,40.67 67.91,40.67 68.03,40.8 68.03,41.02 68.16,41.15 68.42,41.15 68.54,41.02 68.54,40.8 68.67,40.67 68.92,40.67 69.05,40.8 69.05,41.02 69.18,41.15 69.43,41.15 69.56,41.02 69.56,40.8 69.69,40.67 69.94,40.67 70.07,40.8 70.07,41.02 70.19,41.15 70.56,41.15 70.69,41.02 70.69,40.8 70.81,40.67 71.07,40.67 71.2,40.8 71.2,41.02 71.32,41.15 71.58,41.15 71.7,41.02 71.7,40.8 71.83,40.67 72.08,40.67 72.21,40.8 72.21,41.02 72.34,41.15 72.59,41.15 72.72,41.02 72.72,40.8 72.85,40.67 73.1,40.67 73.23,40.8 73.23,41.02 73.35,41.15 73.61,41.15 73.74,41.02 73.74,40.8 73.86,40.67 74.12,40.67 74.24,40.8 74.24,41.02 74.37,41.15 79.54,41.15 80.79,42.41 81.51,42.41 82.18,43.08 82.57,43.08 v1(82.68,42.97)
  BOTTOM w0.102: v1(35.52,31.11) 35.69,31.29 JDIMM1.225 ; UC1.AY41 83.38,44.46 82.68,43.76 v1(82.68,42.97)
DDR_A_SDQ56: length 74.1
  IN2 w0.127: v1(83.85,41.16) 83.38,41.16 79.63,37.41 62.64,37.41 62.51,37.53 62.51,38.11 62.39,38.23 62.13,38.23 62,38.11 62,37.53 61.88,37.41 61.62,37.41 61.5,37.53 61.5,38.11 61.37,38.23 61.12,38.23 60.99,38.11 60.99,37.53 60.86,37.41 60.61,37.41 60.48,37.53 60.48,38.11 60.35,38.23 60.1,38.23 59.97,38.11 59.97,37.53 59.85,37.41 59.59,37.41 59.46,37.53 59.46,38.11 59.34,38.23 59.03,38.23 58.91,38.11 58.91,37.53 58.78,37.41 58.53,37.41 58.4,37.53 58.4,38.11 58.27,38.23 58.02,38.23 57.89,38.11 57.89,37.53 57.76,37.41 57.51,37.41 57.38,37.53 57.38,38.11 57.26,38.23 57,38.23 56.88,38.11 56.88,37.53 56.75,37.41 56.49,37.41 56.37,37.53 56.37,38.11 56.24,38.23 53.05,38.23 42.25,27.43 40.32,27.43 40.19,27.56 40.19,27.94 40.06,28.07 39.81,28.07 39.68,27.94 39.68,27.56 39.56,27.43 37.83,27.43 36.95,28.31 34.51,28.31 v1(33.99,28.82)
  BOTTOM w0.102: UC1.BA38 85.82,43.08 85.61,42.87 85.61,42.55 85.73,42.43 85.73,42 84.89,41.16 v1(83.85,41.16) ; JDIMM1.237 34.53,28.29 v1(33.99,28.82)
DDR_A_SDQ57: length 72.7
  IN2 w0.127: v1(30.95,28.82) 31.44,29.32 35.72,29.32 35.73,29.31 37.13,29.31 37.61,28.83 42.58,28.83 52.74,38.99 73.53,38.99 73.66,38.87 73.66,38.38 73.79,38.26 74.04,38.26 74.17,38.38 74.17,38.87 74.3,38.99 74.57,38.99 74.7,38.87 74.7,38.38 74.82,38.26 75.08,38.26 75.21,38.38 75.21,39.25 75.33,39.38 75.59,39.38 75.71,39.25 75.71,38.38 75.84,38.26 76.1,38.26 76.22,38.38 76.22,38.87 76.35,38.99 76.77,38.99 76.89,39.12 76.89,39.53 77.02,39.65 77.27,39.65 77.4,39.53 77.4,39.12 77.53,38.99 77.78,38.99 77.91,39.12 77.91,39.46 78.04,39.59 78.29,39.59 78.42,39.46 78.42,39.12 78.54,38.99 78.8,38.99 78.93,39.12 78.93,39.46 79.05,39.59 79.31,39.59 79.43,39.46 79.43,39.12 79.56,38.99 80.13,38.99 83.85,42.71 v1(85.99,42.71)
  BOTTOM w0.102: JDIMM1.236 29.79,28.54 29.98,28.34 30.38,28.34 30.67,28.62 30.67,28.62 30.86,28.82 v1(30.95,28.82) ; UC1.AY37 86.15,44.34 86.15,44.08 86.05,43.99 86.05,42.77 v1(85.99,42.71)
DDR_A_SDQ58: length 73.4
  IN2 w0.127: v1(87.44,41.59) 86.96,41.1 86.96,40.67 85.96,39.68 85.96,38.3 84.18,36.51 83.99,36.51 83.57,36.1 81.88,36.1 79.97,34.19 56.96,34.19 56.83,34.32 56.83,34.84 56.7,34.97 56.45,34.97 56.32,34.84 56.32,34.32 56.2,34.19 55.94,34.19 55.82,34.32 55.82,34.84 55.69,34.97 55.43,34.97 55.31,34.84 55.31,34.32 55.18,34.19 54.93,34.19 54.8,34.32 54.8,34.84 54.67,34.97 54.42,34.97 54.29,34.84 54.29,34.32 54.16,34.19 53.87,34.19 53.75,34.32 53.75,34.84 53.62,34.97 53.37,34.97 53.24,34.84 53.24,34.32 53.11,34.19 52.46,34.19 42.57,24.29 36.96,24.29 36.17,25.08 34.68,25.08 v1(33.99,25.77)
  BOTTOM w0.102: v1(87.44,41.59) 87.85,42 87.85,44.04 UC1.BA34 ; JDIMM1.249 34.48,25.28 v1(33.99,25.77)
DDR_A_SDQ59: length 72.9
  IN2 w0.127: v1(32.47,25.77) 32.47,24.93 32.86,24.54 33.11,24.54 33.24,24.67 33.24,25.05 33.37,25.18 33.62,25.18 33.75,25.05 33.75,24.67 33.87,24.54 36.08,24.54 36.71,23.91 42.72,23.91 52.6,33.78 80.15,33.78 81.94,35.57 84.28,35.57 84.72,36.02 84.72,36.33 86.45,38.05 86.45,38.98 88.1,40.63 v1(88.1,40.96)
  BOTTOM w0.102: UC1.BA33 88.62,43.81 88.62,41.46 v2(88.51,41.35) 88.12,40.96 v1(88.1,40.96) ; v1(32.47,25.77) 31.94,25.24 31.21,25.24 31,25.04 JDIMM1.250
DDR_A_SDQ60: length 73.6
  IN2 w0.127: v1(32.47,28.82) 32.05,28.4 31.6,28.4 31.47,28.28 31.47,27.94 31.58,27.83 32.97,27.83 33.1,27.96 33.1,28.22 33.25,28.37 33.51,28.37 33.66,28.22 33.66,27.94 33.81,27.79 36.83,27.79 37.57,27.05 42.41,27.05 52.39,37.03 53.32,37.03 53.45,37.15 53.45,37.72 53.57,37.85 53.83,37.85 53.95,37.72 53.95,37.15 54.08,37.03 54.34,37.03 54.46,37.15 54.46,37.72 54.59,37.85 54.84,37.85 54.97,37.72 54.97,37.15 55.1,37.03 55.35,37.03 55.48,37.15 55.48,37.72 55.61,37.85 55.86,37.85 55.99,37.72 55.99,37.15 56.11,37.03 79.86,37.03 v1(82.17,39.34)
  BOTTOM w0.102: v1(82.17,39.34) 81.98,39.54 81.98,40.26 84.29,42.56 84.29,43.15 84.86,43.71 84.86,44.14 UC1.AY39 ; JDIMM1.232 29.96,29.54 30.25,29.83 31.87,29.83 32.47,29.23 v1(32.47,28.82)
DDR_A_SDQ61: length 73.8
  IN2 w0.127: v1(35.52,28.82) 37.08,28.82 37.45,28.45 37.66,28.45 37.81,28.3 37.81,28.03 37.97,27.87 38.19,27.87 38.34,28.03 38.34,28.3 38.5,28.45 42.73,28.45 52.89,38.61 62.89,38.61 63.02,38.49 63.02,38 63.15,37.88 63.4,37.88 63.53,38 63.53,38.49 63.66,38.61 63.91,38.61 64.04,38.49 64.04,38 64.16,37.88 64.42,37.88 64.54,38 64.54,38.49 64.67,38.61 64.93,38.61 65.05,38.49 65.05,38 65.18,37.88 65.43,37.88 65.56,38 65.56,38.49 65.69,38.61 65.94,38.61 66.07,38.49 66.07,38 66.2,37.88 66.45,37.88 66.58,38 66.58,38.49 66.7,38.61 66.96,38.61 67.08,38.49 67.08,38 67.21,37.88 67.47,37.88 67.59,38 67.59,38.49 67.72,38.61 67.97,38.61 68.1,38.49 68.1,38 68.23,37.88 68.48,37.88 68.61,38 68.61,38.49 68.74,38.61 68.99,38.61 69.12,38.49 69.12,38 69.24,37.88 69.5,37.88 69.62,38 69.62,38.49 69.75,38.61 70.01,38.61 70.13,38.49 70.13,38 70.26,37.88 70.51,37.88 70.64,38 70.64,38.49 70.77,38.61 71.02,38.61 71.15,38.49 71.15,38 71.28,37.88 71.53,37.88 71.66,38 71.66,38.49 71.78,38.61 72.04,38.61 72.16,38.49 72.16,38 72.29,37.88 72.55,37.88 72.67,38 72.67,38.49 72.8,38.61 73.05,38.61 73.18,38.49 73.18,38 73.31,37.88 79.56,37.88 83.86,42.18 84.48,42.18 v1(84.71,41.95)
  BOTTOM w0.102: v1(35.52,28.82) 35.98,29.29 JDIMM1.233 ; UC1.AY38 85.6,44.69 85.6,44.43 85.51,44.34 85.51,44.1 85.59,44 85.59,43.22 84.71,42.34 v1(84.71,41.95)
DDR_A_SDQ62: length 73.6
  IN2 w0.127: v1(87.45,42.76) 87.43,42.76 86.55,41.88 86.55,40.6 85.63,39.67 85.63,38.55 83.99,36.91 83.82,36.91 83.39,36.48 81.7,36.48 79.79,34.57 63.45,34.57 63.32,34.7 63.32,35.21 63.19,35.34 62.94,35.34 62.81,35.21 62.81,34.7 62.68,34.57 62.43,34.57 62.3,34.7 62.3,35.21 62.18,35.34 61.92,35.34 61.8,35.21 61.8,34.7 61.67,34.57 61.41,34.57 61.29,34.7 61.29,35.22 61.16,35.35 60.91,35.35 60.78,35.22 60.78,34.7 60.65,34.57 60.4,34.57 60.27,34.7 60.27,35.22 60.14,35.35 59.89,35.35 59.76,35.22 59.76,34.7 59.64,34.57 59.38,34.57 59.26,34.7 59.26,35.22 59.13,35.35 58.87,35.35 58.75,35.22 58.75,34.7 58.62,34.57 58.37,34.57 58.24,34.7 58.24,35.21 58.1,35.35 57.85,35.35 57.72,35.22 57.72,34.7 57.59,34.57 57.34,34.57 57.21,34.7 57.21,35.22 57.09,35.35 53.08,35.35 42.41,24.67 37.22,24.67 36.12,25.77 v1(35.52,25.77)
  BOTTOM w0.102: v1(35.52,25.77) 36.03,26.29 JDIMM1.245 ; UC1.AY35 87.47,44.3 87.34,44.18 87.34,44.18 87.15,43.99 87.15,43.59 87.07,43.51 87.07,43.13 v1(87.45,42.76)
DDR_A_SDQ63: length 73.3
  IN2 w0.127: v1(30.95,25.77) 32.62,24.1 35.02,24.1 35.58,23.53 42.88,23.53 52.76,33.4 80.32,33.4 82.07,35.15 84.42,35.15 85.18,35.91 85.18,36.13 86.93,37.89 86.93,38.8 88.52,40.39 88.52,42.33 v1(88.24,42.61)
  BOTTOM w0.102: JDIMM1.246 29.73,26.03 29.89,26.19 30.53,26.19 v1(30.95,25.77) ; UC1.AY34 88.02,44.66 88.32,44.35 88.32,44.05 88.26,43.98 88.26,42.64 v1(88.24,42.61)
DDR_A_SDQS0: length 77.9
  IN2 w0.127: v1(33.95,87.35) 34.13,87.53 34.13,88 34.39,88.26 36.3,88.26 37.44,89.4 41.11,89.4 53.58,76.93 54.13,76.93 54.26,77.06 54.26,77.68 54.52,77.94 55.09,77.94 55.36,77.68 55.36,77.06 55.48,76.93 55.86,76.93 55.99,77.06 55.99,77.68 56.25,77.94 56.83,77.94 57.09,77.68 57.09,77.06 57.21,76.93 57.68,76.93 57.8,77.06 57.8,77.68 58.07,77.94 58.64,77.94 58.9,77.68 58.9,77.06 59.03,76.93 62.56,76.93 63.13,76.36 82.69,76.36 86.58,72.47 86.58,71.1 86.25,70.78 v1(85.79,70.78)
  BOTTOM w0.102: v1(85.79,70.78) 86.21,70.78 86.33,70.65 86.33,69.83 86.52,69.64 86.52,66.74 86.68,66.59 86.68,66.31 86.62,66.24 86.62,65.95 UC1.B36
  BOTTOM w0.114: JDIMM1.13 34.19,86.29 33.95,86.52 v1(33.95,87.35)
DDR_A_SDQS0#: length 77.9
  IN2 w0.127: v1(85.79,71.59) 85.79,71.34 86.08,71.04 86.19,71.04 86.35,71.2 86.35,72.38 82.59,76.13 63.03,76.13 62.46,76.7 58.93,76.7 58.67,76.96 58.67,77.59 58.54,77.71 58.16,77.71 58.04,77.59 58.04,76.96 57.77,76.7 57.12,76.7 56.86,76.96 56.86,77.59 56.73,77.71 56.35,77.71 56.22,77.59 56.22,76.96 55.96,76.7 55.39,76.7 55.12,76.96 55.12,77.59 55,77.71 54.62,77.71 54.49,77.59 54.49,76.96 54.23,76.7 53.48,76.7 41.02,89.16 37.54,89.16 36.4,88.03 34.49,88.03 34.36,87.9 34.36,87.71 v1(34.72,87.35)
  BOTTOM w0.102: v1(85.79,71.59) 85.79,71.59 85.65,71.45 85.65,71.27 85.76,71.16 85.95,71.16 86.13,70.98 86.29,70.98 86.53,70.74 86.53,69.92 86.73,69.72 86.73,68.4 86.89,68.24 86.89,67.99 86.73,67.83 86.73,67.59 86.89,67.44 86.89,67.18 86.73,67.02 86.73,66.83 86.88,66.67 86.88,66.15 UC1.A36
  BOTTOM w0.114: JDIMM1.11 36.21,86.78 36.13,86.7 36.13,86.6 36.02,86.49 34.28,86.49 34.16,86.61 34.16,86.8 34.28,86.92 34.6,86.92 34.72,87.03 v1(34.72,87.35)
DDR_A_SDQS1: length 68.1
  IN2 w0.127: v1(32.43,81.77) 32.16,82.03 32.16,82.33 32.35,82.52 37.43,82.52 38,83.09 40.73,83.09 44.26,79.56 44.26,79.38 44.06,79.18 44.06,78.81 44.46,78.41 44.83,78.41 45.03,78.61 45.21,78.61 53.78,70.03 79.21,70.03 80.87,68.38 81.15,68.38 v1(81.51,68.03)
  BOTTOM w0.102: UC1.E40 84.34,63.96 84,64.3 83.09,64.3 82.29,65.1 82.29,67.4 82.28,67.41
  BOTTOM w0.114: v1(81.51,68.03) 81.65,68.17 82.01,68.17 82.2,67.98 82.2,67.49 82.28,67.41 ; JDIMM1.34 29.74,81.04 29.85,81.15 30.21,81.15 30.35,81.01 31.91,81.01 32.14,81.25 32.14,81.48 v1(32.43,81.77)
DDR_A_SDQS1#: length 68
  IN2 w0.127: v1(81.55,68.85) 81.31,68.61 80.96,68.61 79.31,70.26 53.88,70.26 45.31,78.84 44.94,78.84 44.74,78.64 44.56,78.64 44.29,78.91 44.29,79.09 44.49,79.29 44.49,79.66 40.82,83.32 37.91,83.32 37.33,82.75 32.25,82.75 31.93,82.43 31.93,82.03 v1(31.67,81.77)
  BOTTOM w0.102: UC1.D41 84.22,64.51 83.18,64.51 82.5,65.19 82.5,67.48 82.49,67.48
  BOTTOM w0.114: v1(31.67,81.77) 31.93,81.5 31.93,81.33 31.82,81.22 30.43,81.22 30.29,81.36 29.89,81.36 29.71,81.54 JDIMM1.32 ; 82.49,67.48 82.49,68.09 82.17,68.42 81.64,68.42 81.5,68.56 81.5,68.8 v1(81.55,68.85)
DDR_A_SDQS2: length 65.8
  IN2 w0.127: v1(33.61,76.43) 33.81,76.63 33.81,77.04 34.07,77.3 38.58,77.3 51.46,64.42 59.92,64.42 60.19,64.16 60.19,63.93 60.31,63.81 60.7,63.81 60.82,63.93 60.82,64.16 61.08,64.42 61.66,64.42 61.92,64.16 61.92,63.93 62.05,63.81 62.43,63.81 62.55,63.93 62.55,64.16 62.82,64.42 74.04,64.42 74.45,64.02 75.2,64.02 75.31,64.13 v1(75.31,64.62)
  BOTTOM w0.102: 79.87,61.59 79.89,61.59 79.9,61.6 79.92,61.6 79.95,61.6 81.55,61.59 82.14,61.01 83.98,61.01 84.1,60.88 84.35,60.88 UC1.L40
  BOTTOM w0.114: v1(75.31,64.62) 75.31,63.7 77.41,61.59 79.87,61.59 ; JDIMM1.55 35.54,75.78 35.16,75.41 33.85,75.41 33.61,75.65 v1(33.61,76.43)
DDR_A_SDQS2#: length 65.8
  IN2 w0.127: v1(76.07,64.62) 75.89,64.62 75.54,64.28 75.54,64.03 75.29,63.78 74.35,63.78 73.94,64.19 62.91,64.19 62.79,64.06 62.79,63.84 62.52,63.58 61.95,63.58 61.69,63.84 61.69,64.06 61.56,64.19 61.18,64.19 61.05,64.06 61.05,63.84 60.79,63.58 60.22,63.58 59.96,63.84 59.96,64.06 59.83,64.19 51.37,64.19 38.49,77.07 34.17,77.07 34.04,76.94 34.04,76.77 v1(34.37,76.43)
  BOTTOM w0.102: 79.87,61.8 79.95,61.8 81.63,61.8 82.22,61.21 UC1.K41
  BOTTOM w0.114: 79.87,61.8 77.5,61.8 75.52,63.78 75.52,64.28 75.86,64.62 v1(76.07,64.62) ; JDIMM1.53 36.29,76.29 36,75.99 35.45,75.99 35.07,75.62 33.94,75.62 33.82,75.73 33.82,75.95 34.3,76.43 v1(34.37,76.43)
DDR_A_SDQS3: length 64
  IN2 w0.127: v1(32.68,71.1) 32.42,70.83 32.42,70.65 32.62,70.45 35.94,70.45 47.91,58.48 75.46,58.48 75.75,58.77 77.66,58.77 78.47,57.96 79.7,57.96 79.78,58.05 79.78,58.17 v1(79.5,58.46)
  BOTTOM w0.102: v1(79.5,58.46) 79.38,58.34 79.38,58.2 79.49,58.08 79.77,58.08 79.88,57.98 79.88,57.76 80.17,57.47 83.51,57.47 83.59,57.55 83.77,57.55 83.87,57.44 UC1.U41
  BOTTOM w0.114: v1(32.68,71.1) 32.61,71.1 32.13,70.62 32.13,70.37 31.89,70.13 30.38,70.13 29.8,70.71 29.69,70.71 29.52,70.54 JDIMM1.76
DDR_A_SDQS3#: length 64.1
  IN2 w0.127: v1(31.92,71.1) 32.19,70.83 32.19,70.56 32.52,70.22 35.84,70.22 47.81,58.25 75.55,58.25 75.85,58.54 77.56,58.54 78.37,57.73 78.41,57.73 79.79,57.73 80.01,57.96 80.01,58.39 v1(80.08,58.46)
  BOTTOM w0.102: v1(80.08,58.46) 80.08,57.84 80.25,57.67 83.43,57.67 83.5,57.75 83.91,57.75 84.3,57.36 UC1.U40
  BOTTOM w0.114: v1(31.92,71.1) 31.92,70.46 31.81,70.34 30.46,70.34 29.89,70.91 29.71,70.91 29.59,71.04 JDIMM1.74
DDR_A_SDQS4: length 63.1
  IN2 w0.127: v1(78.76,51.7) 78.56,51.89 78.56,52.16 77.59,53.13 61.28,53.13 61.16,53.26 61.16,53.44 60.89,53.71 60.32,53.71 60.06,53.44 60.06,53.26 59.93,53.13 59.55,53.13 59.42,53.26 59.42,53.65 59.16,53.92 58.59,53.92 58.33,53.65 58.33,53.26 58.2,53.13 57.63,53.13 57.51,53.26 57.51,53.65 57.24,53.92 56.67,53.92 56.41,53.65 56.41,53.26 56.28,53.13 46.83,53.13 39.1,45.41 37.08,45.41 36,44.33 34.23,44.33 33.9,44 33.9,43.59 v1(33.74,43.43)
  BOTTOM w0.102: UC1.AF41 84.2,52.39 78.88,52.39 78.75,52.27 78.75,51.89 v1(78.76,51.7)
  BOTTOM w0.114: v1(33.74,43.43) 33.75,43.43 34.01,43.16 34.01,42.83 34.25,42.59 35.62,42.59 35.96,42.93 36.11,42.93 36.25,42.79 JDIMM1.179
DDR_A_SDQS4#: length 63.1
  IN2 w0.127: v1(34.5,43.43) 34.39,43.43 34.13,43.69 34.13,43.9 34.33,44.1 36.1,44.1 37.18,45.18 39.2,45.18 46.92,52.9 56.38,52.9 56.64,53.17 56.64,53.56 56.77,53.69 57.15,53.69 57.28,53.56 57.28,53.17 57.54,52.9 58.3,52.9 58.56,53.17 58.56,53.56 58.68,53.69 59.07,53.69 59.19,53.56 59.19,53.17 59.46,52.9 60.03,52.9 60.29,53.17 60.29,53.35 60.42,53.47 60.8,53.47 60.93,53.35 60.93,53.17 61.19,52.9 77.5,52.9 78.33,52.07 78.33,51.88 v1(78.17,51.72)
  BOTTOM w0.102: UC1.AE40 84.37,52.76 84.12,52.76 83.95,52.59 78.79,52.59 78.55,52.35 78.55,52.1 v1(78.17,51.72)
  BOTTOM w0.114: v1(34.5,43.43) 34.22,43.15 34.22,42.92 34.34,42.8 35.53,42.8 35.87,43.14 36.1,43.14 36.25,43.29 JDIMM1.177
DDR_A_SDQS5: length 62.8
  IN2 w0.127: v1(31.96,38.35) 31.96,37.91 32.29,37.59 36.69,37.59 37.7,38.6 42.53,38.6 51.91,47.99 77.18,47.99 77.57,47.59 77.57,47.54 77.83,47.28 v1(77.9,47.28)
  BOTTOM w0.102: UC1.AM40 84.7,48.89 84.44,48.89 84.35,48.79 84.08,48.79 84,48.87 83.69,48.87 83.46,48.64 82.35,48.64 82.29,48.71 80.05,48.71 80.01,48.67 79.99,48.67
  BOTTOM w0.114: v1(31.96,38.35) 31.78,38.16 31.78,37.87 31.44,37.54 JDIMM1.200 ; 79.99,48.67 79.04,48.67 77.9,47.54 v1(77.9,47.28)
DDR_A_SDQS5#: length 62.8
  IN2 w0.127: v1(77.04,47.28) 77.22,47.46 77.22,47.62 77.08,47.75 52.01,47.75 42.62,38.37 37.79,38.37 36.78,37.36 32.19,37.36 v1(31.2,38.35)
  BOTTOM w0.102: 79.93,48.88 79.96,48.91 82.37,48.91 82.43,48.85 83.38,48.85 83.61,49.07 84.18,49.07 UC1.AM41
  BOTTOM w0.114: JDIMM1.198 29.84,38.03 30.13,37.74 31.36,37.74 31.57,37.96 31.57,38.22 31.44,38.35 v1(31.2,38.35) ; v1(77.04,47.28) 77.35,47.28 78.95,48.88 79.93,48.88
DDR_A_SDQS6: length 64.3
  IN2 w0.127: v1(82.25,44.16) 82.12,44.03 82.12,43.63 81.3,42.81 80.26,42.81 79.13,41.68 52.3,41.68 42.7,32.09 41.19,32.09 41,31.9 41,31.38 40.74,31.12 40.16,31.12 39.9,31.38 39.9,31.96 39.77,32.09 39.23,32.09 38.69,31.55 34.35,31.55 33.89,32.01 33.89,32.48 v1(33.74,32.63)
  BOTTOM w0.102: UC1.AV40 84.44,45.59 84.35,45.49 84.11,45.49 83.97,45.61 83.14,45.61 82.89,45.36 82.72,45.36 82.25,44.89 v1(82.25,44.16)
  BOTTOM w0.114: JDIMM1.221 35.9,32.29 35.55,31.94 35.54,31.94 35.28,31.67 34.08,31.67 33.84,31.91 33.84,32.53 v1(33.74,32.63)
DDR_A_SDQS6#: length 64.3
  IN2 w0.127: v1(81.28,44.16) 81.39,44.26 81.61,44.26 81.89,43.99 81.89,43.73 81.21,43.05 80.17,43.05 79.04,41.92 52.21,41.92 42.61,32.32 41.09,32.32 40.77,31.99 40.77,31.48 40.64,31.35 40.26,31.35 40.13,31.48 40.13,32.06 39.87,32.32 39.13,32.32 38.59,31.78 34.44,31.78 34.12,32.1 34.12,32.46 34.3,32.63 v1(34.5,32.63)
  BOTTOM w0.102: UC1.AV41 84.04,45.81 83.05,45.81 82.8,45.56 82.63,45.56 82.63,45.56 82.63,45.55 82.05,44.97 82.05,44.62 81.59,44.16 v1(81.28,44.16)
  BOTTOM w0.114: JDIMM1.219 36.29,32.79 36,32.49 35.82,32.49 35.47,32.14 35.46,32.14 35.19,31.88 34.16,31.88 34.05,31.99 34.05,32.25 34.23,32.43 34.23,32.43 34.43,32.63 v1(34.5,32.63)
DDR_A_SDQS7: length 72.6
  IN2 w0.127: v1(86.06,40.67) 85.81,40.91 85.31,40.91 84.51,40.11 84.51,38.63 83.02,37.14 81.59,37.14 79.56,35.11 64.18,35.11 63.4,35.88 52.86,35.88 42.19,25.21 40.92,25.21 40.65,25.47 40.65,25.78 40.53,25.9 40.15,25.9 40.02,25.78 40.02,25.47 39.76,25.21 37.65,25.21 36.43,26.43 32.55,26.43 32.28,26.7 32.28,27.05 32.03,27.3 v1(31.96,27.3)
  BOTTOM w0.102: UC1.BA36 86.88,44.17 86.88,43.63 86.84,43.59 86.84,41.44 86.12,40.72
  BOTTOM w0.114: v1(31.96,27.3) 32.3,27.63 32.3,27.8 32.17,27.92 31.05,27.92 30.45,27.33 29.94,27.33 29.65,27.03 JDIMM1.242 ; 86.12,40.72 v1(86.06,40.67)
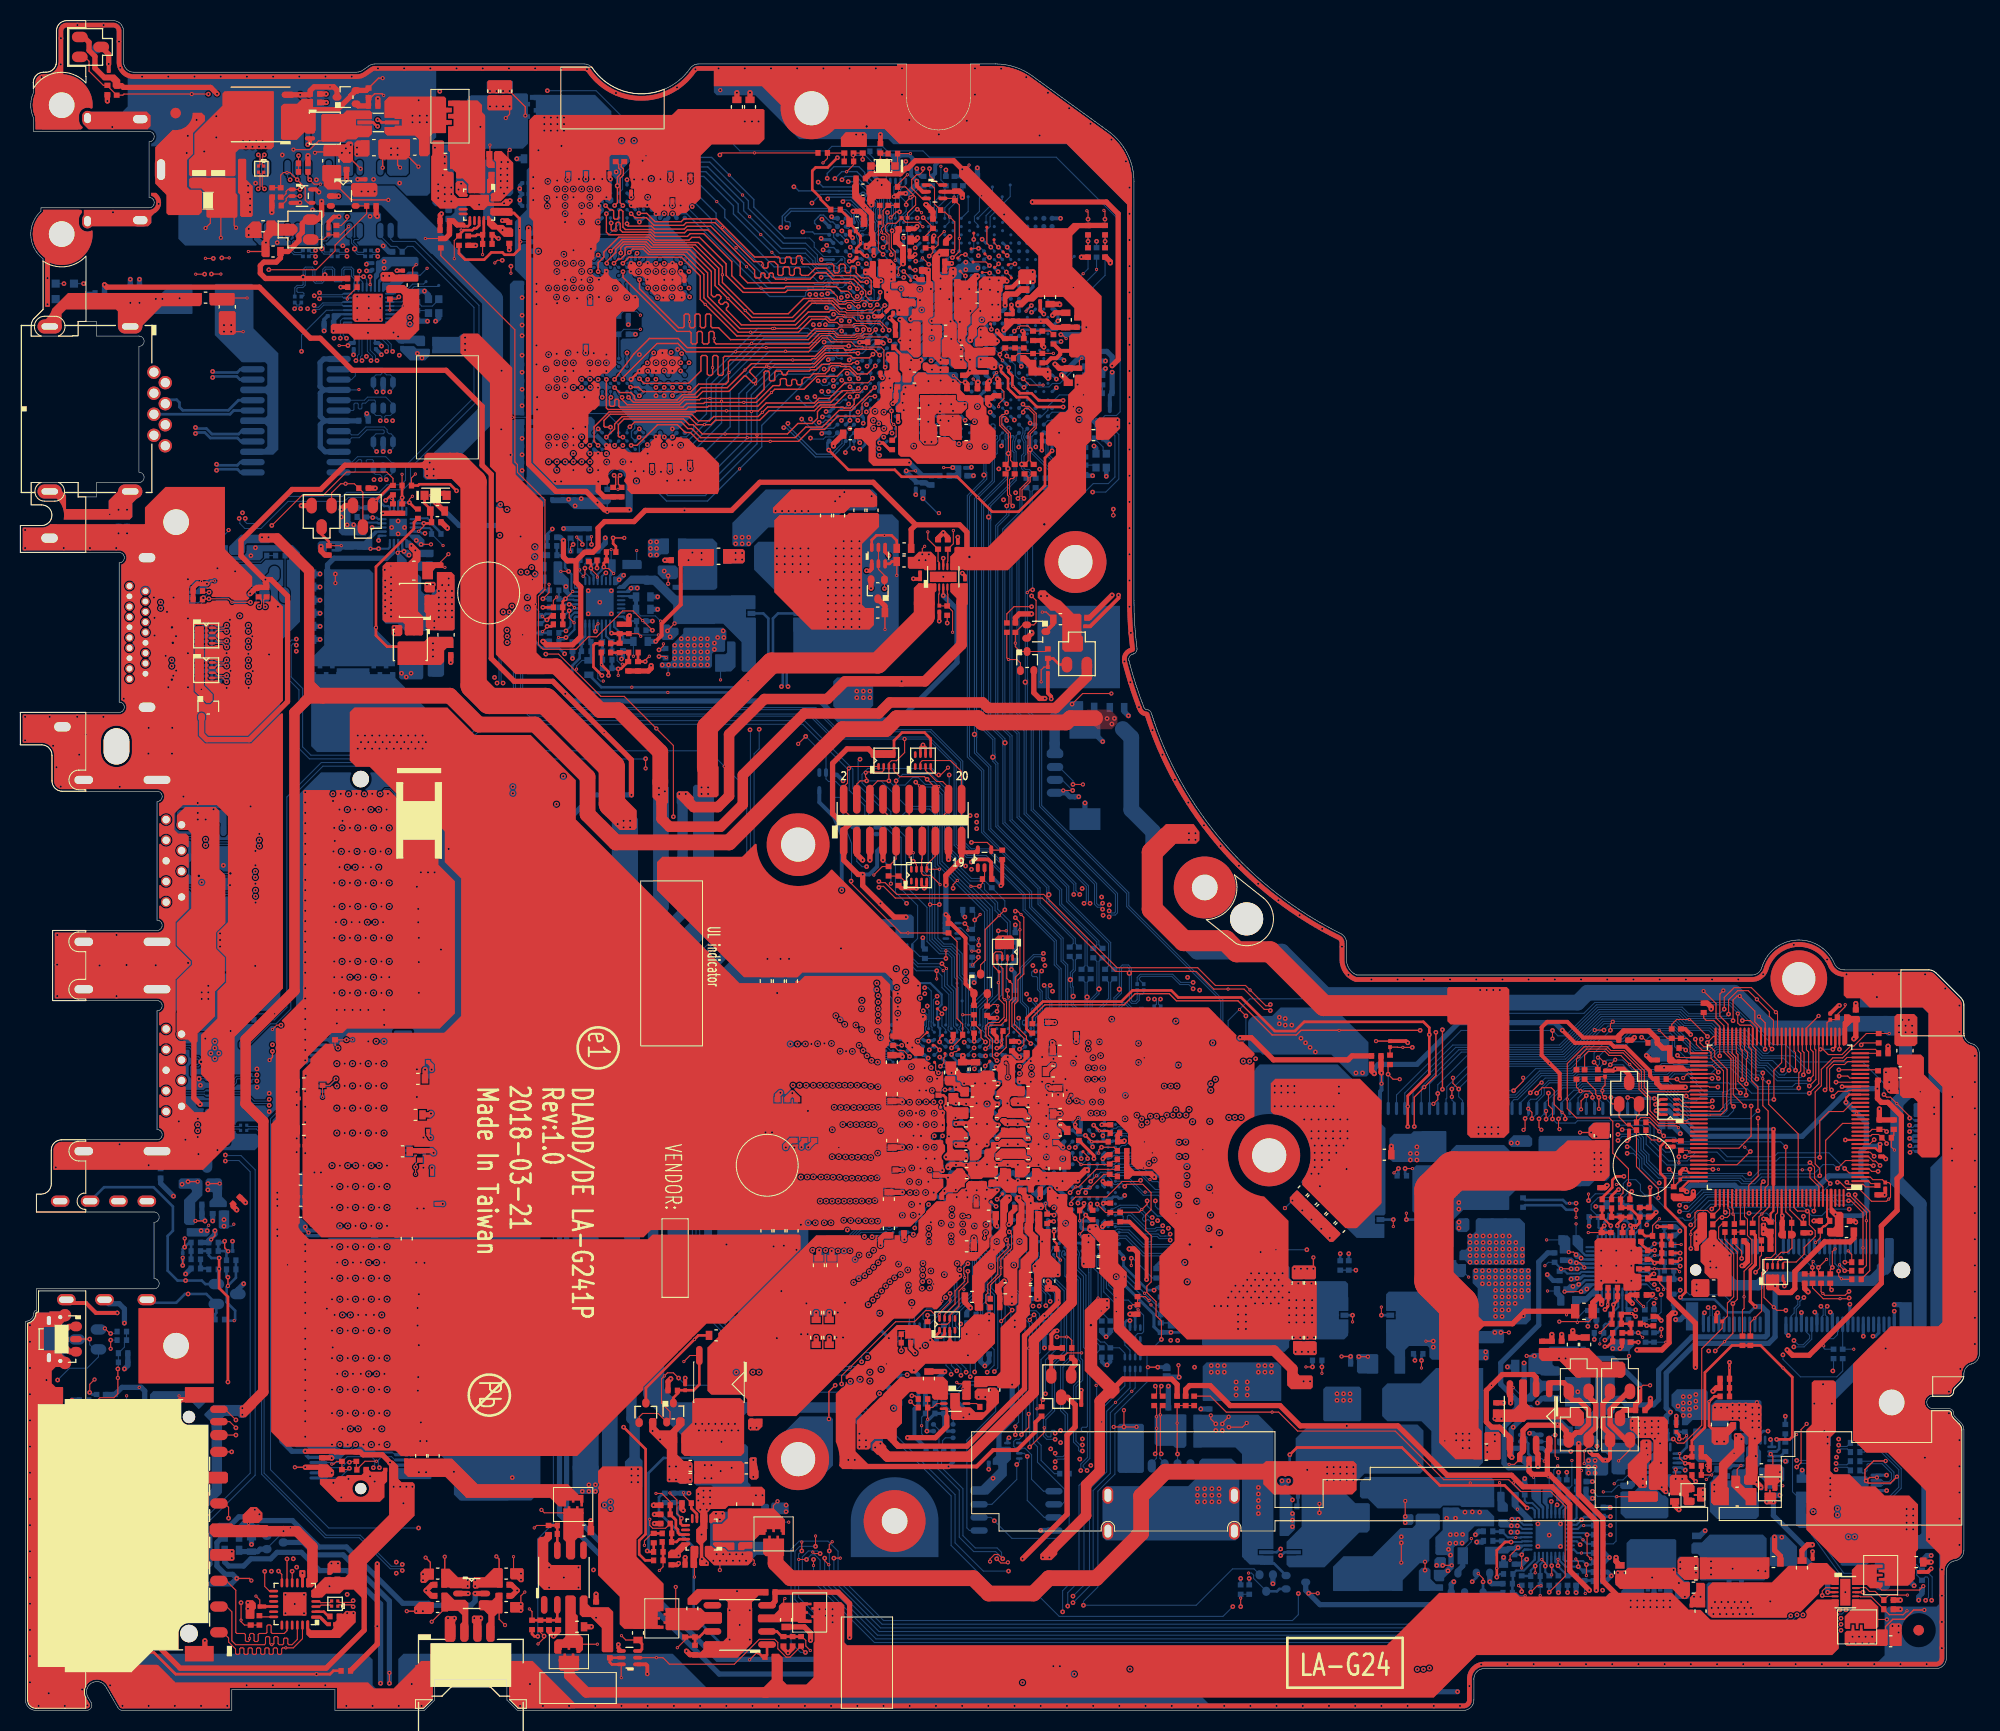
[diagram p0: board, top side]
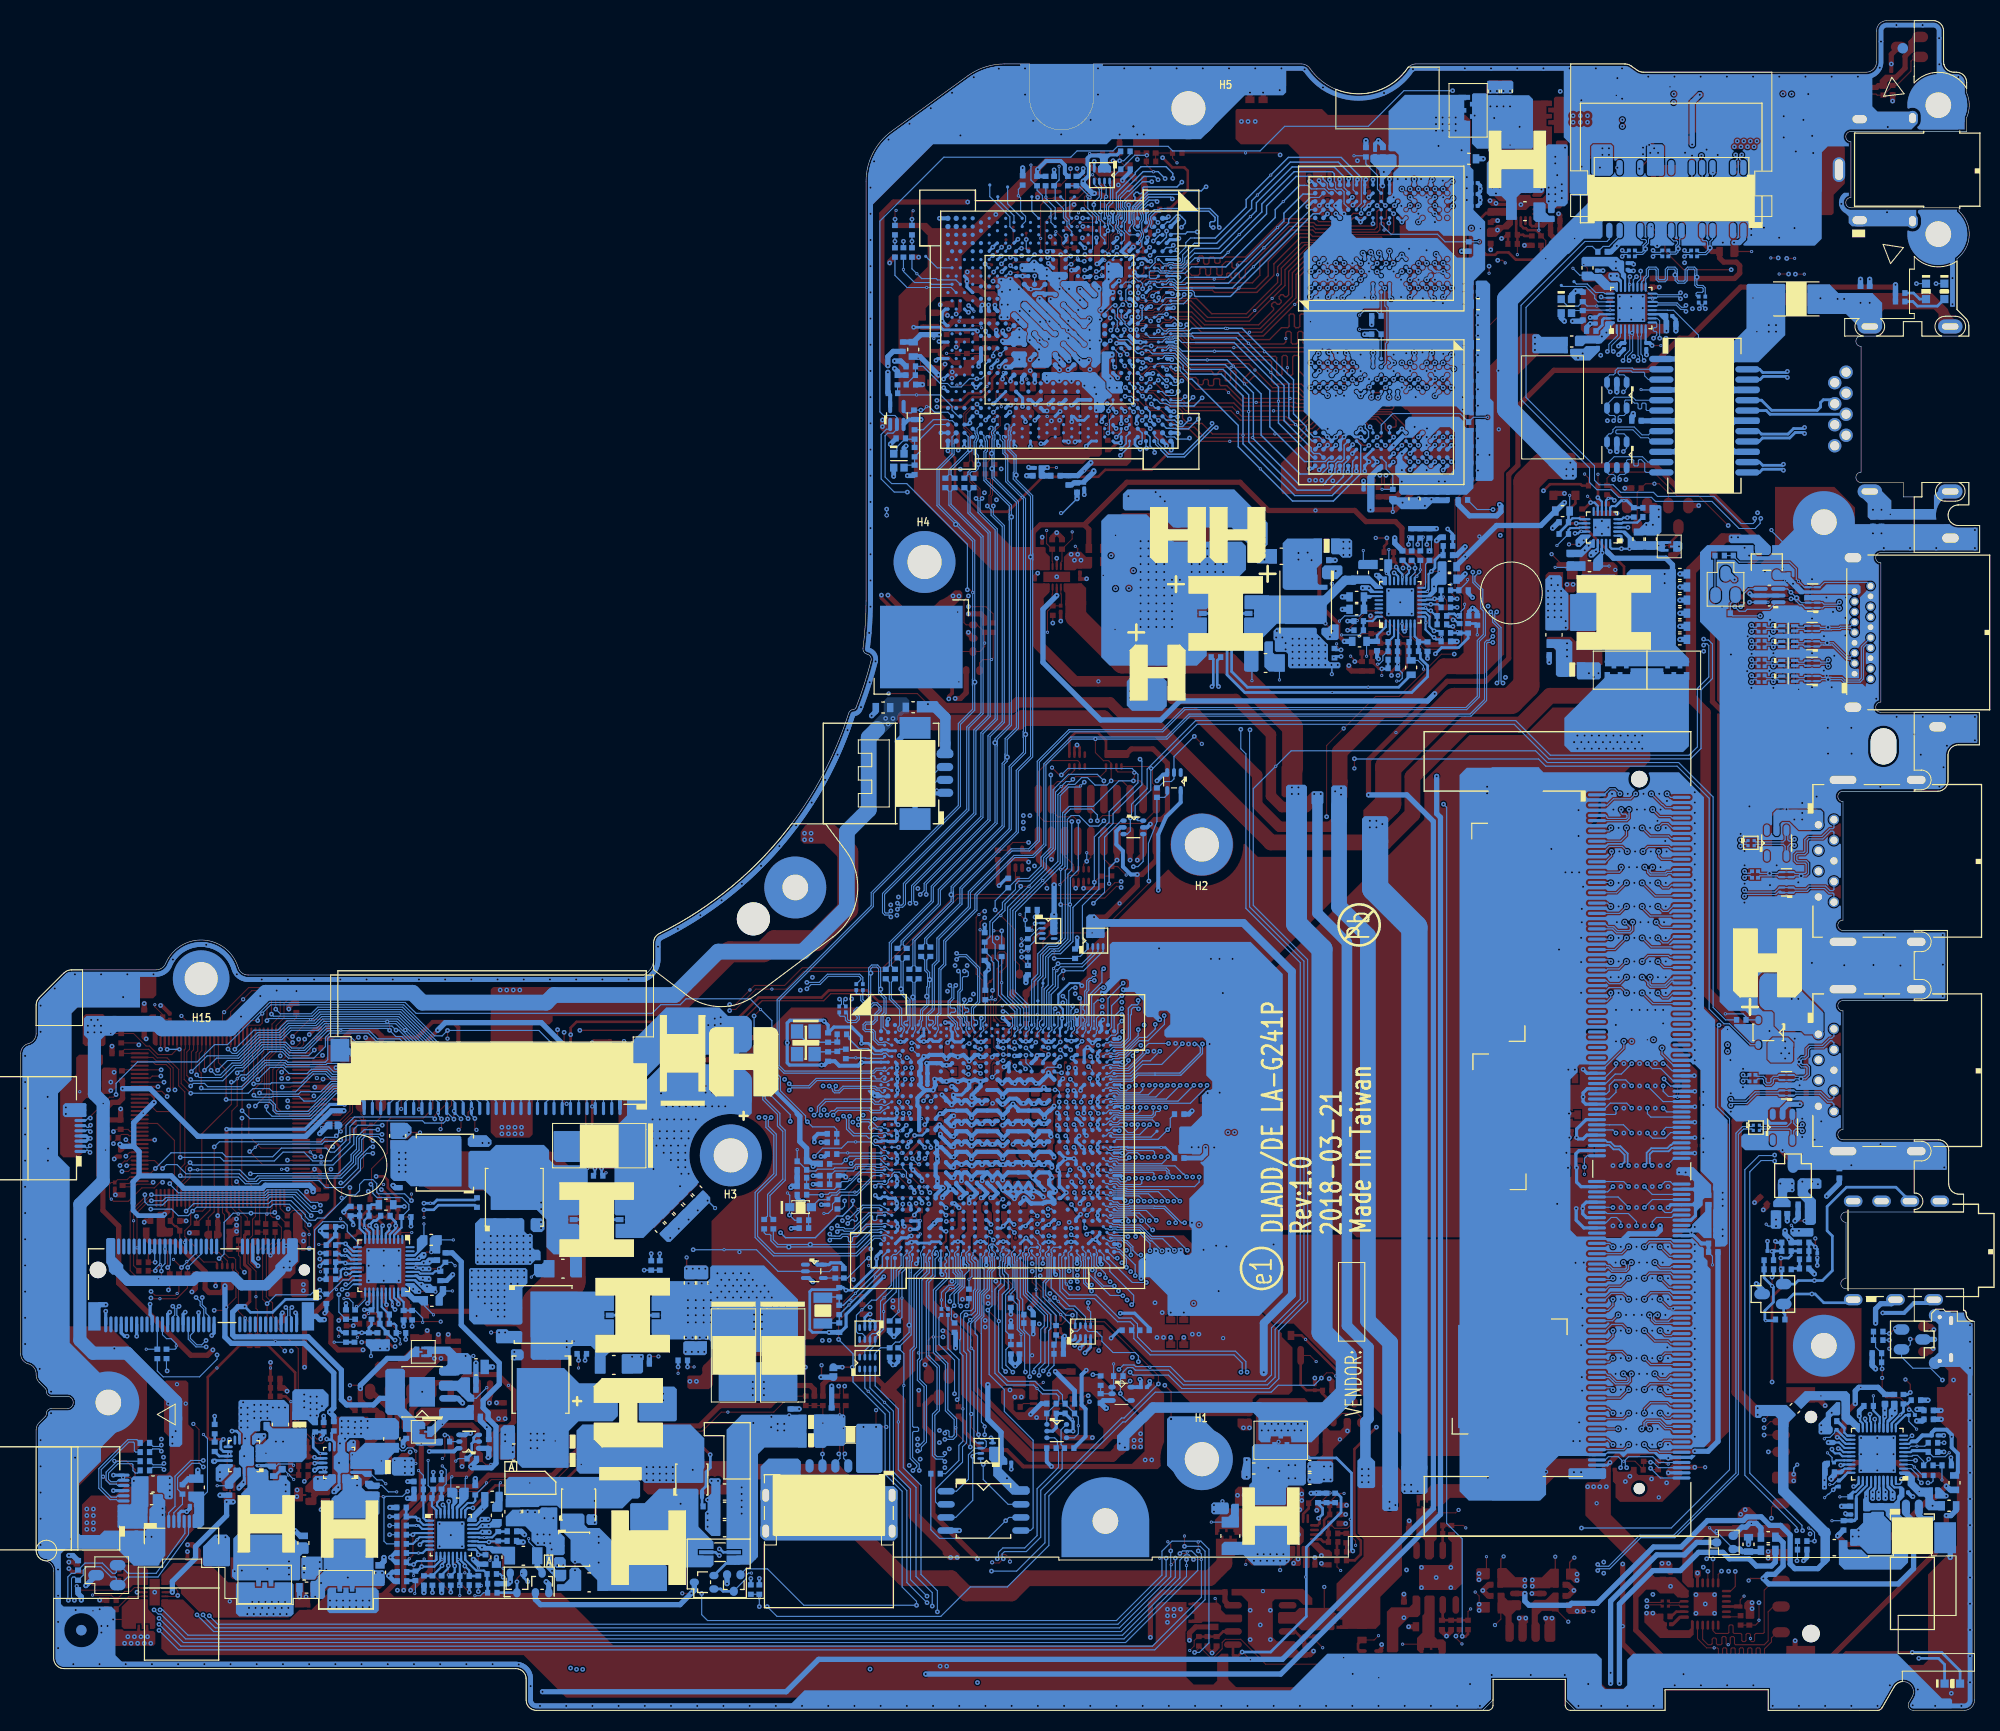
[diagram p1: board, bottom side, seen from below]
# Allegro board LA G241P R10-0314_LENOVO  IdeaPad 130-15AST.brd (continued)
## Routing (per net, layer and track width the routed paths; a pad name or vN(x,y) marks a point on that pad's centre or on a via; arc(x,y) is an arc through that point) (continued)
DDR_A_SDQS7#: length 72.6
  IN2 w0.127: v1(32.72,27.3) 32.51,27.09 32.51,26.8 32.65,26.66 36.52,26.66 37.75,25.44 39.66,25.44 39.79,25.56 39.79,25.87 40.05,26.13 40.62,26.13 40.88,25.87 40.88,25.56 41.01,25.44 42.09,25.44 52.76,36.11 63.5,36.11 64.27,35.34 79.47,35.34 81.5,37.37 82.92,37.37 84.28,38.72 84.28,40.2 85.22,41.14 85.95,41.14 v1(86.06,41.25)
  BOTTOM w0.102: UC1.AY36 86.92,44.68 86.62,44.38 86.62,44.08 86.68,44.02 86.68,43.72 86.64,43.68 86.64,41.52 86.37,41.25 v1(86.06,41.25)
  BOTTOM w0.114: v1(32.72,27.3) 32.5,27.52 32.5,27.88 32.25,28.13 30.96,28.13 30.36,27.54 JDIMM1.240
DDR_A_SMA0: length 62.9
  IN1 w0.102: 81.82,50.79 83.2,50.79 84.9,52.49 84.97,52.49 85.28,52.81 85.77,52.81 85.98,52.6 v1(86.38,52.6)
  IN1 w0.211: v1(30.18,52.83) 31.08,51.93 40.21,51.93 41.16,50.97 55.05,50.97 55.54,51.47 71.12,51.47 71.33,51.26 71.33,51 71.54,50.79 71.96,50.79 72.17,51 72.17,51.26 72.38,51.47 72.8,51.47 73.01,51.26 73.01,51 73.23,50.79 73.65,50.79 73.86,51 73.86,51.26 74.07,51.47 74.6,51.47 74.77,51.3 74.77,50.96 74.94,50.79 81.82,50.79
  BOTTOM w0.102: v1(30.18,52.83) 30.18,52.95 29.59,53.54 JDIMM1.144 ; UC1.AG38 86.38,52.27 v1(86.38,52.6)
DDR_A_SMA1: length 63.5
  IN1 w0.102: v1(87.77,56.81) 87.57,56.81 86.99,56.24 86.42,56.24 85.93,55.74 84.91,55.74
  IN1 w0.211: 84.91,55.74 84.21,55.74 83.74,55.28 82.39,55.28 82.18,55.07 60.81,55.07 60.6,55.28 60.6,55.8 60.39,56.01 59.97,56.01 59.76,55.8 59.76,55.28 59.54,55.07 59.12,55.07 58.91,55.28 58.91,55.8 58.7,56.01 58.28,56.01 58.07,55.8 58.07,55.28 57.86,55.07 57.44,55.07 57.23,55.28 57.23,55.8 57.01,56.01 56.59,56.01 56.38,55.8 56.38,55.28 56.17,55.07 55.75,55.07 55.54,55.28 55.54,55.8 55.33,56.01 54.91,56.01 54.7,55.8 54.7,55.28 54.48,55.07 54.06,55.07 53.85,55.28 53.85,55.8 53.64,56.01 53.22,56.01 53.01,55.8 53.01,55.28 52.8,55.07 52.44,55.07 52.22,55.29 52.22,55.85 52.06,56.01 35.25,56.01 v1(35.22,55.99)
  BOTTOM w0.102: v1(35.22,55.99) 35.52,56.29 JDIMM1.133 ; UC1.W35 87.57,56.61 v1(87.77,56.81)
DDR_A_SMA2: length 63.2
  IN1 w0.102: 82.17,57.38 83.38,57.38 83.82,56.94 84.97,56.94 85.22,57.19 85.79,57.19 v1(86.17,56.81)
  IN1 w0.211: 82.17,57.38 79.12,57.38 78.61,56.86 73.43,56.86 72.98,57.32 47.03,57.32 46.82,57.53 46.82,57.8 46.6,58.01 46.18,58.01 45.97,57.8 45.97,57.53 45.76,57.32 45.18,57.32 44.97,57.53 44.97,57.8 44.76,58.01 44.34,58.01 44.13,57.8 44.13,57.53 43.92,57.32 43.5,57.32 43.29,57.53 43.29,57.8 43.07,58.01 42.65,58.01 42.44,57.8 42.44,57.53 42.23,57.32 41.81,57.32 41.6,57.53 41.6,57.8 41.39,58.01 40.97,58.01 40.76,57.8 40.76,57.53 40.54,57.32 31.99,57.32 v1(30.65,55.99)
  BOTTOM w0.102: v1(30.65,55.99) 30.65,56.26 30.38,56.54 JDIMM1.132 ; UC1.W38 86.17,56.46 v1(86.17,56.81)
DDR_A_SMA3: length 63.8
  IN1 w0.102: v1(88.57,56.81) 88.19,57.19 86.68,57.19 86.55,57.06 86.55,56.65 86.33,56.43 83.76,56.43 83.57,56.62 83.16,56.62 82.07,55.53 81.63,55.53
  IN1 w0.211: 81.63,55.53 64.97,55.53 64.76,55.74 64.76,56.26 64.55,56.47 64.13,56.47 63.92,56.26 63.92,55.74 63.71,55.53 63.29,55.53 63.07,55.74 63.07,56.26 62.86,56.47 62.44,56.47 62.23,56.26 62.23,55.74 62.02,55.53 61.52,55.53 60.58,56.47 34.19,56.47 v1(33.7,55.99)
  BOTTOM w0.102: UC1.W34 88.37,56.61 v1(88.57,56.81) ; JDIMM1.131 35.84,56.79 34.5,56.79 v1(33.7,55.99)
DDR_A_SMA4: length 63.5
  IN1 w0.102: 82.17,59.35 83.76,59.35 84.78,58.33 85.75,58.33 v1(86.17,57.91)
  IN1 w0.211: 82.17,59.35 82.04,59.48 76.25,59.48 75.54,58.77 72.61,58.77 71.98,59.4 44.17,59.4 43.96,59.61 43.96,59.91 43.75,60.12 43.33,60.12 43.12,59.91 43.12,59.61 42.91,59.4 42.49,59.4 42.28,59.61 42.28,59.91 42.07,60.12 41.64,60.12 41.43,59.91 41.43,59.61 41.22,59.4 40.8,59.4 40.59,59.61 40.59,59.91 40.38,60.12 39.96,60.12 39.75,59.91 39.75,59.61 39.54,59.4 39.15,59.4 38.6,59.95 38.22,59.95 37.74,59.47 33.24,59.47 v1(32.18,58.4)
  BOTTOM w0.102: v1(86.17,57.91) 86.17,57.56 UC1.U38 ; v1(32.18,58.4) 32.18,57.87 31.85,57.54 JDIMM1.128
DDR_A_SMA5: length 63.2
  IN1 w0.102: v1(87.38,57.91) 86.7,58.59 85.03,58.59 83.89,59.73 82.43,59.73
  IN1 w0.211: v1(30.65,58.4) 30.98,58.73 30.98,58.73 32.19,59.93 37.55,59.93 38.21,60.59 44.42,60.59 44.64,60.38 44.64,60.08 44.85,59.87 45.27,59.87 45.48,60.08 45.48,60.38 45.69,60.59 46.11,60.59 46.32,60.38 46.32,60.08 46.53,59.87 72.27,59.87 72.86,59.28 75.28,59.28 75.98,59.98 82.17,59.98 82.43,59.73
  BOTTOM w0.102: JDIMM1.126 30.29,58.04 v1(30.65,58.4) ; UC1.U37 86.83,57.36 v1(87.38,57.91)
DDR_A_SMA6: length 63.8
  IN1 w0.102: v1(88.56,57.91) 88.56,57.86 88.09,57.39 86.6,57.39 86.58,57.38 85.89,57.38 85.87,57.39 84.13,57.39 83.57,57.95 82.04,57.95
  IN1 w0.211: 82.04,57.95 78.87,57.95 78.42,57.5 73.62,57.5 73.34,57.78 59.57,57.78 59.36,57.99 59.36,58.26 59.15,58.47 58.73,58.47 58.52,58.26 58.52,57.99 58.31,57.78 57.89,57.78 57.68,57.99 57.68,58.26 57.47,58.47 57.04,58.47 56.83,58.26 56.83,57.99 56.62,57.78 56.2,57.78 55.99,57.99 55.99,58.26 55.78,58.47 55.27,58.47 55.06,58.26 55.06,57.99 54.85,57.78 54.42,57.78 54.21,57.99 54.21,58.26 54,58.47 53.58,58.47 53.37,58.26 53.37,57.99 53.16,57.78 52.74,57.78 52.53,57.99 52.53,58.26 52.32,58.47 51.89,58.47 51.68,58.26 51.68,57.99 51.47,57.78 51.05,57.78 50.84,57.99 50.84,58.26 50.63,58.47 50.21,58.47 50,58.26 50,57.99 49.79,57.78 49.36,57.78 49.15,57.99 49.15,58.26 48.94,58.47 48.52,58.47 48.31,58.26 48.31,57.99 48.1,57.78 47.68,57.78 47.47,57.99 47.47,58.26 47.26,58.47 35.3,58.47 v1(35.22,58.4)
  BOTTOM w0.102: v1(35.22,58.4) 35.22,57.87 35.3,57.79 JDIMM1.127 ; v1(88.56,57.91) 88.37,57.72 UC1.U34
DDR_A_SMA7: length 63.5
  IN1 w0.102: 79.66,62.01 81.67,62.01 81.98,61.7 83.51,61.7 84.97,60.24 85.92,60.24 86.79,59.37 87.41,59.37 v1(87.77,59.01)
  IN1 w0.211: v1(32.18,60.56) 32.5,60.88 32.5,60.88 32.72,61.09 32.72,61.09 33.12,61.5 37.09,61.5 38.22,62.62 40.22,62.62 40.83,62.01 68.76,62.01 68.97,61.8 68.97,61.47 69.18,61.26 69.61,61.26 69.82,61.47 69.82,61.8 70.03,62.01 79.66,62.01
  BOTTOM w0.102: UC1.R35 87.57,58.81 v1(87.77,59.01) ; v1(32.18,60.56) 30.65,59.04 JDIMM1.122
DDR_A_SMA8: length 63.9
  IN1 w0.102: v1(85.4,57.89) 84.71,57.89 83.65,58.95 81.93,58.95
  IN1 w0.211: 81.93,58.95 76.49,58.95 75.78,58.25 72.06,58.25 71.85,58.46 71.85,58.75 71.66,58.94 71.21,58.94 71,58.73 71,58.46 70.79,58.25 70.37,58.25 70.16,58.46 70.16,58.73 69.95,58.94 69.53,58.94 69.31,58.73 69.31,58.46 69.1,58.25 68.68,58.25 68.47,58.46 68.47,58.73 68.26,58.94 67.84,58.94 67.63,58.73 67.63,58.46 67.42,58.25 67,58.25 66.78,58.46 66.78,58.73 66.57,58.94 66.15,58.94 65.94,58.73 65.94,58.46 65.73,58.25 65.31,58.25 65.1,58.46 65.1,58.73 64.89,58.94 64.47,58.94 64.25,58.73 64.25,58.46 64.04,58.25 63.62,58.25 63.41,58.46 63.41,58.73 63.2,58.94 62.78,58.94 62.57,58.73 62.57,58.46 62.36,58.25 61.94,58.25 61.72,58.46 61.72,58.73 61.51,58.94 61.09,58.94 60.88,58.73 60.88,58.46 60.67,58.25 60.25,58.25 60.04,58.46 60.04,58.73 59.83,58.94 34.24,58.94 v1(33.7,58.4)
  BOTTOM w0.102: v1(33.7,58.4) 34.18,58.88 35.78,58.88 36.38,58.29 JDIMM1.125 ; v1(85.4,57.89) UC1.R38
DDR_A_SMA9: length 64.3
  IN1 w0.102: v1(86.17,58.97) 85.6,59.54 84.71,59.54 83.17,61.08 79.06,61.08
  IN1 w0.211: v1(35.22,60.56) 37.52,60.56 38.04,61.08 46.79,61.08 47,60.87 47,60.54 47.21,60.33 47.63,60.33 47.84,60.54 47.84,60.87 48.05,61.08 48.47,61.08 48.68,60.87 48.68,60.54 48.89,60.33 49.32,60.33 49.53,60.54 49.53,60.87 49.74,61.08 50.16,61.08 50.37,60.87 50.37,60.54 50.58,60.33 51,60.33 51.21,60.54 51.21,60.87 51.42,61.08 51.85,61.08 52.06,60.87 52.06,60.54 52.27,60.33 52.96,60.33 53.17,60.54 53.17,60.87 53.38,61.08 53.81,61.08 54.02,60.87 54.02,60.54 54.23,60.33 54.65,60.33 54.86,60.54 54.86,60.87 55.07,61.08 55.49,61.08 55.7,60.87 55.7,60.54 55.91,60.33 56.33,60.33 56.55,60.54 56.55,60.87 56.76,61.08 57.18,61.08 57.39,60.87 57.39,60.54 57.6,60.33 58.02,60.33 58.23,60.54 58.23,60.87 58.44,61.08 58.86,61.08 59.08,60.87 59.08,60.54 59.29,60.33 59.71,60.33 59.92,60.54 59.92,60.87 60.13,61.08 60.55,61.08 60.76,60.87 60.76,60.54 60.97,60.33 72.54,60.33 73,60.79 74.06,60.79 74.35,61.08 79.06,61.08
  BOTTOM w0.102: UC1.N38 85.97,59.17 v1(86.17,58.97) ; JDIMM1.121 35.88,59.29 35.22,59.94 v1(35.22,60.56)
DDR_A_SMA10: length 64.3
  IN1 w0.102: 82.12,50.32 83.24,50.32 84.74,51.82 85.51,51.82 85.85,52.17 87.91,52.17 v1(88.14,52.4)
  IN1 w0.211: 82.12,50.32 82.1,50.31 70.86,50.31 70.63,50.53 70.63,50.79 70.42,51 70,51 69.79,50.79 69.79,50.53 69.58,50.32 69.15,50.32 68.94,50.53 68.94,50.79 68.73,51 68.31,51 68.1,50.79 68.1,50.53 67.89,50.32 67.47,50.32 67.26,50.53 67.26,50.79 67.05,51 55.73,51 55.05,50.32 41.68,50.32 41.5,50.51 40.97,50.51 40.06,51.42 31.43,51.42 30.95,50.94 v1(30.95,50.79)
  BOTTOM w0.102: v1(88.14,52.4) 88.37,52.17 UC1.AG34 ; JDIMM1.146 29.71,51.03 29.95,51.28 30.46,51.28 v1(30.95,50.79)
DDR_A_SMA11: length 63.7
  IN1 w0.102: 81.71,62.47 82.11,62.07 83.57,62.07 85.09,60.56 86.11,60.56 87,59.67 87.87,59.67 v1(88.53,59)
  IN1 w0.211: 81.71,62.47 41.03,62.47 40.41,63.09 38.03,63.09 36.9,61.96 32.06,61.96 v1(30.65,60.56)
  BOTTOM w0.102: v1(30.65,60.56) 30.65,60.04 30.14,59.54 JDIMM1.120 ; v1(88.53,59) 88.37,58.84 UC1.R34
DDR_A_SMA12: length 64.9
  IN1 w0.102: 81.18,61.54 81.63,61.54 81.79,61.38 83.36,61.38 84.89,59.86 85.85,59.86 86.73,58.98 v1(87.06,58.98)
  IN1 w0.211: v1(33.7,60.56) 34.17,61.02 37.33,61.02 37.85,61.54 61.23,61.54 61.44,61.33 61.44,61.01 61.65,60.8 62.07,60.8 62.28,61.01 62.28,61.33 62.49,61.54 62.91,61.54 63.12,61.33 63.12,61.01 63.34,60.8 63.76,60.8 63.97,61.01 63.97,61.33 64.18,61.54 64.6,61.54 64.81,61.33 64.81,61.01 65.02,60.8 65.44,60.8 65.65,61.01 65.65,61.33 65.86,61.54 66.29,61.54 66.5,61.33 66.5,61.01 66.71,60.8 67.13,60.8 67.34,61.01 67.34,61.33 67.55,61.54 67.97,61.54 68.18,61.33 68.18,61.01 68.39,60.8 69.94,60.8 70.4,61.25 73.87,61.25 74.16,61.54 81.18,61.54
  BOTTOM w0.102: v1(87.06,58.98) 87.06,59.27 UC1.N37 ; v1(33.7,60.56) 34.28,61.14 35.36,61.14 35.87,60.63 35.87,60.06 36.14,59.78 JDIMM1.119
DDR_A_SMA13: length 67.6
  IN1 w0.102: 84.37,44.04 85.23,44.04 87.5,46.31 87.5,48.55 v1(88.01,49.06)
  IN1 w0.211: v1(31.71,46.98) 33.2,45.49 37.74,45.49 39.25,43.97 63.08,43.97 64.04,43.02 74.05,43.02 75.64,41.43 79.02,41.43 79.42,41.03 81.36,41.03 84.37,44.04
  BOTTOM w0.102: JDIMM1.158 29.59,48.03 29.83,47.8 31.3,47.8 31.71,47.39 v1(31.71,46.98) ; v1(88.01,49.06) 88.01,49 UC1.AN35
DDR_A_SRAS#: length 63.4
  IN1 w0.102: 82.26,45.5 82.64,45.5 83.27,46.13 84.93,46.13 85.98,47.19 85.98,48.11 86.81,48.93 v1(86.81,50.2)
  IN1 w0.211: v1(32.47,48.76) 33.16,48.07 37.16,48.07 37.67,47.57 39.74,47.57 40.86,46.45 74.26,46.45 75.21,45.5 82.26,45.5
  BOTTOM w0.102: UC1.AJ37 86.77,50.43 86.81,50.39 v1(86.81,50.2) ; JDIMM1.152 31.7,49.54 v1(32.47,48.76)
DDR_A_SWE#: length 65.3
  IN1 w0.211: v1(86.2,50.21) 83.85,47.85 83.85,47.59 83.26,47 81.13,47 81.12,47.02 79.21,47.02 78.82,46.63 75.44,46.63 74.59,47.49 62.31,47.49 62.1,47.7 62.1,48.24 61.89,48.45 61.46,48.45 61.25,48.24 61.25,47.72 61.04,47.51 60.62,47.51 60.41,47.72 60.41,48.24 60.2,48.45 59.78,48.45 59.57,48.24 59.57,47.78 59.29,47.51 58.93,47.51 58.72,47.72 58.72,48.24 58.51,48.45 58.09,48.45 57.88,48.24 57.88,47.72 57.67,47.51 57.25,47.51 57.04,47.72 57.04,48.24 56.83,48.45 56.4,48.45 56.19,48.24 56.19,47.72 55.98,47.51 55.56,47.51 55.35,47.72 55.35,48.24 55.14,48.45 41.94,48.45 41.69,48.19 40.43,48.19 39.32,49.3 34.53,49.3 v1(33.99,48.76)
  BOTTOM w0.102: UC1.AL38 86.2,49.89 v1(86.2,50.21) ; JDIMM1.151 35.02,49.79 v1(33.99,48.76)
DEVSLP0: length 10.3
  TOP w0.102: v1(91.82,43.32) 91.42,42.92 91.42,42.36 91.51,42.26 v2(91.51,41.97) 91.51,41.6 90.58,40.67 90.58,39.41 89.57,38.4 RPC13.7
  IN2 w0.127: v1(90.2,46.02) 90.38,46.02 91.82,44.58 v1(91.82,43.32)
  BOTTOM w0.102: UC1.AV31 90.15,45.96 v1(90.2,46.02)
DEVSLP1: length 10.8
  TOP w0.102: RPC13.8 89.07,38.56 90.1,39.59 v2(90.1,39.79) v1(90.1,40.43)
  IN1 w0.127: v1(90.1,40.43) 89.05,41.47 89.05,47.05 v1(89.24,47.24)
  BOTTOM w0.102: UC1.AU31 89.67,46.81 v1(89.24,47.24)
DGPU_PWR_EN: length 283.3
  TOP w0.102: RV1644.1 95.6,106.33 96.29,107.03 v1(98,107.03) ; PR902.2 40.73,141.06 47.91,133.89 47.91,121.06 48.16,120.81 48.16,120.05 50.83,117.38 50.83,108.68 50.19,108.04 50.19,103.34 50.64,102.9 53.83,102.9 55.03,104.11 55.84,104.11 58.35,106.62 59.37,106.62 v2(60.3,105.68) v1(61.24,104.74) ; v1(163.96,61.28) 163.92,61.32 U11.71 ; RV1642.2 v1(89.82,105.44)
  TOP w0.127: v1(137.82,60.23) v1(137.82,66.01)
  IN1 w0.127: v1(137.82,60.23) 137.67,60.38 137.1,60.38 136.69,59.97 133.6,59.97 129.95,56.32 129.95,54.77 126.52,51.34 126.52,49.69 124.42,47.59 120.17,47.59 117.06,50.7 117.06,52.72 113.35,56.43 110.09,56.43 109.5,55.85 105.69,55.85 105.25,56.29 103.88,56.29 103.83,56.33 100.53,56.33 100.13,55.94 100.13,52.57 99.72,52.16 98.66,52.16 98.19,51.7 98.19,49.59 98.41,49.37 98.41,48.46 97.87,47.92 94.99,47.92 94.15,47.08 94.15,46.35 93.71,45.91 93.12,45.91 90.78,43.58 v1(90.78,43.34) ; v1(61.24,104.74) 60.12,103.62 60.12,100.96 61.68,99.41 71.59,99.41 73.05,100.87 78.58,100.87 82.58,104.87 89.25,104.87 v1(89.82,105.44) 96.23,105.44 97.82,107.03 v1(98,107.03)
  IN2 w0.127: v1(98,107.03) 97.82,107.03 97.31,106.52 97.31,101.45 100.35,98.42 100.35,97.58 110.52,87.41 110.52,76.55 118.33,68.74 118.33,67.12 119.76,65.69 124.74,65.69 125,65.44 135.79,65.44 136.55,66.2 137.63,66.2 v1(137.82,66.01) 138.01,66.2 147.16,66.2 147.67,66.71 154.67,66.71 155.23,66.14 155.23,65.36 156.07,64.52 160.2,64.52 163.43,61.28 v1(163.96,61.28)
  BOTTOM w0.102: v1(90.78,43.34) 90.78,43.85 UC1.BA29
  BOTTOM w0.203: PR1015.2 v1(61.24,104.74)
DGPU_PWR_EN#: length 28.8
  TOP w0.102: QV21.5 QV21.2 83.15,110.65 83.74,110.06 QV11.2 v1(83.74,108.78) ; v1(98,108.07) 98.43,107.64 98.43,105.48 98.21,105.26 QV17.2 97.15,105.26 RV44.2 v2(96.42,103.5) 96.42,103.15 96.89,102.68 QV18.1 99.33,102.68 RV43.1
  IN1 w0.127: v1(83.74,108.78) 96.95,108.78 97.66,108.07 v1(98,108.07)
DGPU_PWR_EN_R: length 7.2
  TOP w0.102: RV1642.1 89.88,107.17 89.88,108.23 89.84,108.28 U1895V.5 ; RV1642.1 90.34,106.58 v2(90.34,104.55) ; RV1642.1 89.08,107.1 CV1380.1 88.99,107.19 88.99,108.23 89.04,108.28 U1895V.3
DGPU_PWRGD: length 176
  TOP w0.102: v2(57.48,110.24) 56.99,110.74 56.67,110.74 v1(56.53,110.88)
  TOP w0.254: PR1002.2 PR1098.1 56.53,111.26 v1(56.53,110.88)
  IN1 w0.127: v1(83.41,33.06) 84.79,31.68 86.87,31.68 90.05,34.85 93.41,34.85 95.58,37.03 95.58,38.16 95.72,38.3 ; v1(71.59,95.14) 71.61,95.15 72.54,95.15 75.02,97.63 75.02,99.41 74.64,99.79 73.62,99.79 72.29,98.46 55.97,98.46 53.94,100.49 53.94,104.3 52.35,105.88 52.35,109.57 52.54,109.76 55.76,109.76 56.3,110.3 56.3,110.65 v1(56.53,110.88) ; 95.72,38.3 97.22,38.3 v1(98.14,39.21) ; 95.72,38.3 95.53,38.49 95.53,40.32 97.7,42.49 97.7,43.1 98.18,43.58 100.89,43.58 102.43,42.04 105.1,42.04 105.65,42.6 108.17,42.6 109.13,43.56 109.13,48.54 v1(110,49.41)
  BOTTOM w0.102: v1(71.59,95.14) 71.59,93.25 71.1,92.76 71.1,77.78 65.83,72.51 65.83,39.89 68.62,37.09 68.62,32.53 69.23,31.92 77,31.92 78.43,33.34 81.79,33.34 81.94,33.49 82.98,33.49 v1(83.41,33.06) ; v1(110,49.41) 110,48.87 110.25,48.62 RC66.1 ; v1(98.14,39.21) 97.94,39.4 RC164.2
  BOTTOM w0.203: v1(56.53,110.88) 56.32,110.67 56.32,110.56 55.94,110.18 PU1001.20
DGPU_PWRGD_R: length 7.5
  BOTTOM w0.102: UC1.AH1 107.47,51.31 108.82,49.95 110.28,49.95 RC66.2 110.75,49.54 111.18,49.1 111.18,48.6 111.58,48.19 v2(112,48.19)
DGPU_PWROK: length 10.5
  TOP w0.102: v1(53.11,110.46) v2(52.36,110.46)
  TOP w0.254: v1(55.87,110.77) PR1098.2
  IN1 w0.254: v1(53.11,110.46) 53.33,110.24 55.6,110.24 55.87,110.51 v1(55.87,110.77)
  BOTTOM w0.203: v1(53.11,110.46) 53.39,110.18 53.39,108.7 53.64,108.45 PU1001.15
  BOTTOM w0.254: v1(53.11,110.46) 52.77,110.8 52.77,111.55 52.3,112.02 PC11227.2 51.97,112.03 PR1099.2
DISPOFF#: length 8.3
  TOP w0.102: R205.2 R204.2 25.21,148.87 25.47,149.13 v2(25.82,149.13) 26.11,149.13 v1(26.81,148.43) 27.59,147.65 27.59,146.46 27.86,146.19 U203.4
  BOTTOM w0.102: v1(26.81,148.43) 26.87,148.49 JEDP1.10
DMIC_CLK: length 180.8
  IN2 w0.127: v1(17.72,17.43) 17.68,17.39 17.68,15.81 16,14.13 7.63,14.13 5.74,16.01 5.74,20.08 5.04,20.77 5.04,22 v1(4.98,22.06) ; v1(21.77,115.59) 21.73,115.55 21.73,114.74 20.22,113.23 20.22,110.31 19.78,109.87 19.78,108 17.9,106.12 17.9,97.67 19.97,95.6 19.97,83.85 18.57,82.45 18.57,72.93 19.33,72.17 19.33,68.08 17.43,66.17 17.43,63.62 18.39,62.65 18.39,54.25 18.82,53.81 19.81,53.81 v1(19.84,53.85)
  BOTTOM w0.102: JEDP1.25 34.87,142.99 35.9,141.97 36.46,141.97 C216.2 37.51,141.97 38.03,141.97 43.94,136.05 43.94,127.32 37.31,120.69 37.31,119.29 36.87,118.85 35.5,118.85 34.76,118.12 31.59,118.12 31.2,117.72 25.72,117.72 23.09,115.09 21.94,115.09 21.73,115.3 21.73,115.55 v1(21.77,115.59) ; v1(19.84,53.85) 19.9,53.8 21.36,53.8 22.74,52.43 22.74,22.8 17.68,17.75 17.68,17.47 v1(17.72,17.43) ; v1(4.98,22.06) 4.92,22.06 4.91,22.06 4.67,22.06 4.49,22.24 LA9.1
DMIC_CLK_R: length 2.5
  BOTTOM w0.102: LA9.2 5.48,22.78 v2(6.3,23.6) 6.55,23.84 7.35,23.84
DMIC_DAT: length 181.5
  IN2 w0.127: v1(17.13,17.43) 17.17,17.39 17.17,16.02 15.79,14.64 7.84,14.64 6.25,16.22 6.25,20.33 5.55,21.03 5.55,22 v1(5.62,22.06) ; v1(21.19,115.59) 21.22,115.55 21.22,114.95 19.71,113.44 19.71,110.52 19.27,110.08 19.27,108.21 17.39,106.33 17.39,97.46 19.46,95.39 19.46,84.06 18.06,82.66 18.06,72.72 18.82,71.96 18.82,68.29 16.92,66.38 16.92,63.41 17.88,62.44 17.88,54.04 18.61,53.31 19.81,53.31 v1(19.84,53.27)
  BOTTOM w0.102: v1(21.19,115.59) 21.25,115.52 21.25,115.1 21.74,114.61 23.29,114.61 25.92,117.24 31.4,117.24 31.79,117.63 34.96,117.63 35.7,118.37 37.07,118.37 37.79,119.09 37.79,120.49 44.43,127.12 44.43,136.25 38.23,142.45 36.1,142.45 35.87,142.67 JEDP1.27 ; UA1.2 6.61,23.44 5.93,22.76 5.93,22.38 v1(5.62,22.06) ; v1(19.84,53.27) 19.9,53.32 21.16,53.32 22.25,52.23 22.25,23 17.2,17.95 17.2,17.49 v1(17.13,17.43)
DP_AUX_ZVSS: length 2.6
  TOP w0.203: v1(94.63,64.22) 94.83,64.22 95.1,64.5 v2(95.1,64.72) 95.1,65.75 RC16.1
  BOTTOM w0.203: v1(94.63,64.22) 94.99,64.22 95.13,64.36 UC1.D21
DP_VSSR: length 10.4
  TOP w0.102: v2(97.46,135.68) 97.46,135.71 v1(97.98,136.23)
  BOTTOM w0.254: UV1.AM24 100.02,127.89 v1(100.4,128.26) ; UV1.AG23 97.58,128.61 v1(97.26,128.29) 97.18,128.29 UV1.AF23 ; UV1.AG14 97.64,135.89 v1(97.98,136.23) ; UV1.AH14 98.07,135.58 v1(97.99,135.58) ; v1(100.4,129.1) 100.01,129.49 UV1.AM22
  BOTTOM w0.305: v1(101.14,130.91) 100.96,131.09 UV1.AM20 ; v1(100.85,132.74) 100.79,132.69 UV1.AM18 ; UV1.AM14 100.22,135.89 100.55,135.57 v1(100.55,134.74) 100.1,134.29 UV1.AM16
  BOTTOM w0.381: UV1.AF19 UV1.AF20 97,130.67 v1(97,130.33)
DP_ZVSS: length 4.7
  BOTTOM w0.102: v2(95.4,68.92) RC17.1 96.36,66.89 96.59,66.66 96.59,66.33 96.52,66.26 96.52,65.96 96.82,65.66 UC1.B18
DRAM_RST: length 53.9
  TOP w0.102: RV36.1 v2(71.14,151.03) 67.98,151.03 v1(67.78,150.84)
  IN1 w0.102: v1(57.64,137.92) 57.26,137.54 50.98,137.54 50.68,137.84 50.68,139.78 51.55,140.65 51.55,147.74 51.78,147.97 57.71,147.97 58.36,148.61 58.36,150.01 59.19,150.84 v1(67.78,150.84)
  BOTTOM w0.102: UV8.J2 57.98,138.26 v1(57.64,137.92) 57.64,136.21 57.43,136 57.43,132.68 57.58,132.54 57.58,130.69 UV7.J2
DRAM_RST_G: length 18.2
  TOP w0.102: v1(81.63,150.4) CV97.1 RV38.1 80.75,151.01 RV37.1 80.75,149.89 v2(80.06,149.2)
  IN2 w0.142: v1(85.6,138.96) 86.01,139.36 86.01,141.47 84.86,142.61 84.86,143.39 85.09,143.62 85.09,144.15 84.43,144.82 84.43,145.82 83.93,146.32 83.93,148.66 82.2,150.4 v1(81.63,150.4)
  BOTTOM w0.102: v1(85.6,138.96) 85.11,138.96 UV1.L10
EC_CLEAR_CMOS#: length 107.1
  TOP w0.102: v1(175.41,51.08) 174.97,51.53 174.97,55.28 176.61,56.92 U11.15 ; v1(100.46,36.21) v2(101.4,36.21) 101.58,36.21 101.89,35.9 RC111.1
  IN1 w0.127: v1(100.46,36.21) 109.78,26.89 113.88,26.89 114.33,26.45 120.17,26.45 121.38,27.65 143.86,27.65 144.17,27.97 146.85,27.97 147.86,28.99 148.36,28.99 149.95,30.57 149.95,31.46 152.36,33.88 152.94,33.88 153.57,34.51 157.25,34.51 159.91,37.17 159.91,48.09 v1(160.81,48.99)
  BOTTOM w0.102: v1(160.81,48.99) 161.09,49.27 161.75,49.27 162.96,50.47 165.98,50.47 166.27,50.18 174.56,50.18 175.41,51.03 v1(175.41,51.08)
EC_FAN_PWM1: length 91.9
  TOP w0.102: v1(101.98,89.21) v3(101.07,89.21) ; v1(176.28,61.51) 177.12,61.51 177.31,61.32 U11.26
  IN1 w0.127: v1(176.28,61.51) 176.27,61.51 173.55,64.22 170.76,64.22 166.05,68.93 140.11,68.93 139.78,69.26 127.65,69.26 122.59,74.33 117.84,74.33 115.53,76.63 113.47,76.63 111.21,78.89 111.21,80.55 102.55,89.21 v1(101.98,89.21)
  BOTTOM w0.102: JFAN1.2 100.96,90.23 v1(101.98,89.21)
EC_FAN_SPEED1: length 94.1
  TOP w0.102: v1(102.01,89.79) v3(102.97,89.79) ; v1(176.25,62.12) U11.28 179.95,62.12 R214.1
  IN1 w0.127: v1(176.25,62.12) 173.89,64.48 170.86,64.48 166.16,69.18 140.3,69.18 139.97,69.51 127.76,69.51 122.69,74.58 117.94,74.58 115.64,76.89 113.58,76.89 111.47,79 111.47,80.65 102.33,89.79 v1(102.01,89.79)
  BOTTOM w0.102: JFAN1.3 100.67,91.48 102.01,90.14 v1(102.01,89.79)
EC_MUTE#: length 195.6
  TOP w0.102: v2(160.75,53.09) v1(160.75,53.69) 160.75,54.12 R198.1 161.58,54.31 161.78,54.12 U11.89
  IN2 w0.127: v1(17.68,14.51) 17.68,13.02 22.16,8.54 39.72,8.54 40.67,9.49 45.81,9.49 46.15,9.15 48.62,9.15 49.15,9.68 55.78,9.68 57.75,7.71 90.07,7.71 93.44,11.08 93.44,18.99 98.43,23.98 98.43,27.18 99.02,27.77 103.58,27.77 110.04,34.23 111.97,34.23 114.24,36.49 114.24,40.92 114.45,41.14 114.45,47.06 114.92,47.53 115.66,47.53 116.46,48.33 116.46,54.55 119.73,57.82 129.55,57.82 130.82,59.09 135.98,59.09 137.57,60.67 139.85,60.67 140.43,61.24 149.97,61.24 151.17,60.04 151.17,59.56 151.76,58.97 154.26,58.97 154.52,58.7 155.51,58.7 157.76,56.46 159.35,56.46 160.37,55.44 160.37,55.12 160.75,54.74 v1(160.75,53.69)
  BOTTOM w0.102: RA46.2 RA43.2 17.63,14.56 v1(17.68,14.51)
EC_ON: length 14.8
  TOP w0.102: PR410.1 167.67,37.61 v2(168.09,38.04) 168.76,38.7 168.76,42.45 169.03,42.72 169.03,43.72 169.22,43.91 169.69,43.91 170.11,44.33 170.11,48.06 170.3,48.26 U11.112
EC_PCIE_WAKE#: length 232.9
  TOP w0.102: R931.1 167.9,47.78 168.7,48.59 U11.108 168.7,51.04 v1(168.94,51.27) ; v1(33.87,139.03) v2(33.87,138.26)
  IN1 w0.127: v1(46.44,113.95) 46.27,113.78 46.27,103.5 47.82,101.96 47.82,97.49 52.54,92.77 95.73,92.77 109.31,79.19 109.31,78.11 112.57,74.85 114.66,74.85 117.24,72.27 122.13,72.27 126.93,67.47 138.68,67.47 139,67.15 162.4,67.15 165.46,64.09 165.46,59.98 165.17,59.69 165.17,58.06 168.94,54.29 v1(168.94,51.27) 168.94,50.96 172.57,47.33 172.57,42.89 176.1,39.36 176.1,38.56 172.01,34.47 v1(170.83,34.47)
  IN2 w0.127: v1(46.44,113.95) 43.75,116.63 43.75,129.34 38.95,134.14 38.95,135.77 37.19,137.53 34.5,137.53 33.87,138.16 v1(33.87,139.03)
  BOTTOM w0.102: R249.1 176.62,32.92 176.05,32.34 172.53,32.34 170.83,34.04 v1(170.83,34.47) ; UL2.21 33.95,138.96 v1(33.87,139.03)
EC_RSMRST#: length 73.4
  TOP w0.102: U11.100 165.5,48.69 165.66,48.53 165.66,48.04 165.42,47.8 v1(164.92,47.8) 164.7,47.8 C835.1
  IN2 w0.127: v1(115.34,48.04) 116.13,48.82 116.13,54.6 119.6,58.07 129.45,58.07 130.72,59.34 135.85,59.34 137.44,60.93 139.73,60.93 140.3,61.5 150.64,61.5 152.25,59.89 154.69,59.89 157.79,56.79 159.37,56.79 160.62,55.54 160.62,55.22 164.49,51.35 164.49,48.15 164.85,47.8 v1(164.92,47.8)
  BOTTOM w0.102: RC59.1 114.84,47.53 v1(115.34,48.04) 115.34,48.77 DC3.1 115.31,49.95 v2(115.53,50.17)
EC_RSMRST#_R: length 10.2
  BOTTOM w0.102: RC60.2 RC59.2 113.49,48.52 DC3.2 112.49,49.52 111.67,49.52 CC8.2 111.23,49.97 110.75,49.97 110.45,50.26 v2(109.01,50.26) 108.81,50.26 107.21,51.86 UC1.AG1
EC_RST#: length 4.1
  TOP w0.102: U11.37 175.1,66.67 C187.2 175.87,66.98 R192.1 176.1,67.48 176.86,68.24 v2(176.86,68.43)
EC_RX: length 30.4
  TOP w0.102: v1(174.91,60.16) 175.08,60.34 175.08,62.3 175.77,62.98 176.71,62.98 177.04,63.32 U11.31 ; v1(177.23,40.63) 176.86,40.25 174.88,40.25 v2(174.7,40.43) 174.53,40.6 R244.2
  IN2 w0.127: v1(174.91,60.16) 174.91,51.66 174.72,51.47 174.72,50.07 176.43,48.35 176.43,46.19 177.27,45.36 177.27,40.66 v1(177.23,40.63)
EC_SCI#: length 101
  TOP w0.102: v1(174.4,53.62) 174.4,57.18 175.29,58.07 176.68,58.07 177.53,58.92 U11.20 ; v1(148.1,59.86) 148.1,58.68 148.49,58.29 v1(148.49,57.35)
  IN1 w0.127: v1(101.64,54.58) 102.1,54.12 106.02,54.12 106.29,54.39 108.04,54.39 108.74,55.08 109.88,55.08 110.45,55.66 112.98,55.66 116.3,52.34 116.3,50.32 119.85,46.77 125.5,46.77 127.28,48.54 127.28,50.92 130.71,54.35 130.71,56 133.73,59.02 147.26,59.02 v1(148.1,59.86)
  BOTTOM w0.102: UC1.AA8 101.64,54.83 v1(101.64,54.58) ; v1(148.49,57.35) 148.88,56.95 150.69,56.95 150.92,57.18 157.38,57.18 157.95,56.61 157.95,55.1 159.77,53.28 161.55,53.28 162.4,54.13 164.43,54.13 165.28,53.28 170.18,53.28 170.53,53.62 v1(174.4,53.62)
EC_SMB_CK1: length 130.7
  TOP w0.102: v1(163.98,59.11) 163.79,58.92 U11.77 161.64,58.92 161.63,58.92 161.17,58.92 160.82,59.26 RP3.4 ; v1(109.99,31.44) 110.11,31.32 110.11,30.7 PR202.2
  IN2 w0.127: v1(109.99,31.44) 110.19,31.24 110.19,29.44 110.87,28.76 112.16,28.76 113.09,29.68 125,29.68 125.76,28.92 151.7,28.92 153.23,27.39 153.23,21.79 153,21.56 153,17.59 153.3,17.29 153.85,17.29 v1(154.1,17.04) 154.36,17.29 154.7,17.29 155.02,17.61 155.02,30.18 157,32.16 158.52,32.16 160.34,33.98 162.95,33.98 164.02,32.91 172.02,32.91 176.95,37.85 176.95,39.17 176.77,39.35 176.77,41.05 175.1,42.73 175.1,48.54 172.05,51.59 172.05,52.54 166.52,58.07 165.7,58.07 164.77,59 164.09,59 v1(163.98,59.11)
  BOTTOM w0.102: PR770.1 v1(154.1,17.04)
EC_SMB_CK2: length 315.5
  TOP w0.102: RP3.2 160.81,58.26 160.95,58.12 U11.79 163.78,58.12 163.8,58.1 164.65,58.1 165.03,58.47 165.03,59.91 165.06,59.94 165.06,62.01 163.86,63.22 163.86,63.79 163.65,64 163.01,64 162.44,64.58 162.44,64.99 v1(162.33,65.09) ; QV1.6 89.03,147.92 88.1,148.85 v1(88.1,149.51) ; v1(121.14,67.86) 121.03,67.98 120.56,67.98 118.59,69.94 v2(117.05,69.94) 115.67,69.94 113.95,71.66 106.14,71.66 99.02,78.77 84.79,78.77 83.64,79.91 83.31,79.91 v1(83.19,79.8)
  IN2 w0.127: v1(162.33,65.09) 162.44,65.19 162.44,66.26 161.29,67.4 146.62,67.4 146.05,66.83 126.74,66.83 125.6,67.98 121.26,67.98 v1(121.14,67.86) ; v1(82.3,86.54) 82.2,86.44 82.2,85.65 84.55,83.31 84.55,80.55 83.9,79.9 83.29,79.9 v1(83.19,79.8) ; v1(88.1,149.51) 87.98,149.64 87.98,150.08 86.07,151.99 71.59,151.99 68.62,154.96 56.13,154.96 53.2,157.89 44.81,157.89 36.59,149.67 21.35,149.67 19.98,148.31 19.98,142.66 21.5,141.14 24.75,141.14 25.17,140.72 25.17,135.38 30.25,130.31 30.25,119.28 26.63,115.67 26.63,112.58 25.81,111.76 25.81,103.82 26.22,103.41 26.62,103.41 v1(26.73,103.3)
  BOTTOM w0.102: v1(26.73,103.3) 26.6,103.43 26.4,103.43 26.23,103.26 26.23,100.21 27.33,99.1 27.33,93.43 28.14,92.63 41.59,92.63 44.94,95.98 75.97,95.98 80.67,91.28 80.67,89.37 82.19,87.86 82.19,86.65 v1(82.3,86.54) 82.3,85.27 82.59,84.98 QC2.3
EC_SMB_DA1: length 128.6
  TOP w0.102: PR201.2 110.47,30.71 110.47,31.34 v1(110.58,31.44) ; v1(163.98,58.51) 163.98,58.52 U11.78 161.53,58.52 161.49,58.56 161.02,58.56 160.82,58.76 RP3.3
  IN2 w0.127: v1(110.58,31.44) 110.58,29.6 111.03,29.14 112,29.14 112.93,30.07 125.15,30.07 125.92,29.3 151.86,29.3 153.61,27.55 153.61,21.63 153.38,21.4 153.38,17.75 153.46,17.67 153.85,17.67 v1(154.1,17.92) 154.36,17.67 154.54,17.67 154.64,17.77 154.64,30.34 156.84,32.54 158.37,32.54 160.18,34.36 163.11,34.36 164.18,33.29 171.86,33.29 176.57,38 176.57,39.01 176.39,39.19 176.39,40.89 174.72,42.57 174.72,48.39 171.67,51.43 171.67,52.39 166.37,57.69 165.54,57.69 164.61,58.62 164.09,58.62 v1(163.98,58.51)
  BOTTOM w0.102: PR769.1 v1(154.1,17.92)
EC_SMB_DA2: length 315.5
  TOP w0.102: v1(83.19,80.38) 83.31,80.27 83.79,80.27 84.94,79.13 99.17,79.13 106.28,72.01 114.1,72.01 115.81,70.3 118.73,70.3 v2(119.17,69.86) 120.7,68.33 121.03,68.33 v1(121.14,68.45) ; v1(162.92,65.09) 162.79,64.96 162.79,64.72 163.16,64.35 163.8,64.35 164.21,63.94 164.21,63.37 165.42,62.16 165.42,59.8 165.38,59.76 165.38,58.32 164.8,57.74 163.8,57.74 163.78,57.72 U11.80 161.35,57.72 161.3,57.76 160.8,57.76 160.8,57.76 RP3.1 ; v1(87.47,149.51) 87.47,149.26 87.14,148.93 86.86,148.93 86.38,148.44 86.38,147.63 87.38,146.62 QV1.3
  IN2 w0.127: v1(162.92,65.09) 162.82,65.19 162.82,66.42 161.45,67.78 146.46,67.78 145.89,67.21 126.9,67.21 125.76,68.36 121.23,68.36 v1(121.14,68.45) ; v1(87.47,149.51) 87.59,149.64 87.59,149.92 85.91,151.6 71.43,151.6 68.46,154.58 55.97,154.58 53.04,157.51 44.97,157.51 36.75,149.29 21.5,149.29 20.36,148.15 20.36,142.82 21.66,141.52 24.91,141.52 25.55,140.87 25.55,135.54 30.63,130.47 30.63,119.12 27.02,115.51 27.02,112.43 26.19,111.6 26.19,103.98 26.38,103.79 26.63,103.79 v1(26.73,103.88) ; v1(81.72,86.54) 81.82,86.44 81.82,85.5 84.17,83.15 84.17,80.71 83.74,80.28 83.29,80.28 v1(83.19,80.38)
  BOTTOM w0.102: QC2.6 81.57,86.28 81.72,86.43 v1(81.72,86.54) 81.83,86.65 81.83,87.71 80.32,89.23 80.32,91.13 75.83,95.62 45.09,95.62 41.73,92.27 27.99,92.27 26.98,93.29 26.98,98.96 25.87,100.06 25.87,103.41 26.25,103.79 26.63,103.79 v1(26.73,103.88)
EC_SMCA: length 6.2
  TOP w0.102: PR202.1 110.12,29.32 v2(110.12,27.36) 110.12,25.01 v1(109.98,24.87)
  BOTTOM w0.102: JBAT1.3 109.64,23.99 110.09,24.43 110.09,24.76 v1(109.98,24.87)
EC_SMDA: length 6.2
  TOP w0.102: PR201.1 110.47,29.32 v2(110.47,28.66) 110.47,24.96 v1(110.56,24.87)
  BOTTOM w0.102: JBAT1.4 110.89,23.97 110.45,24.42 110.45,24.76 v1(110.56,24.87)
EC_TX: length 31.5
  TOP w0.102: v1(177.24,39.99) 177.17,39.92 v2(176.37,39.92) 174.74,39.92 173.7,40.96 R243.2 ; U11.30 177.09,62.92 176.8,62.63 175.77,62.63 175.35,62.21 175.35,60.36 v1(175.54,60.16)
  IN2 w0.127: v1(175.54,60.16) 175.22,59.85 175.22,51.59 174.97,51.34 174.97,50.21 176.81,48.37 176.81,46.26 177.65,45.42 177.65,40.4 v1(177.24,39.99)
ECAGND: length 278.3
  TOP w0.203: 161.36,62.12 161.36,62.12 U11.69
  TOP w0.254: v1(134.46,56.61) v3(134.46,58.56) 134.46,59.6 136.55,61.69 v1(136.55,65.52) 136.55,66.2 135.98,66.77 124.42,66.77 123.54,65.88 121.57,65.88 118.32,69.13 112.22,69.13 111.53,69.82 107.78,69.82 106.7,68.74 99.09,68.74 97.5,67.15 97.5,66.07 97.89,65.68 PH201.2
  IN1 w0.254: v1(159.31,62.32) 159.31,63.26 158.54,64.03 156.7,64.03 155.54,65.18 140.37,65.18 140.31,65.24 136.83,65.24 v1(136.55,65.52) 136.46,65.44 135.28,65.44 134.93,65.79 126.72,65.79 121.57,70.94 116.69,70.94 114.1,73.52 112.01,73.52 107.96,77.57 107.96,78.65 95.4,91.22 88.33,91.22 88.12,91 69.5,91 69.04,91.46 53.04,91.46 47.25,97.25 47.25,101.72 45.7,103.26 45.7,114.86 46.51,115.66 v1(46.51,116.93)
  IN2 w0.254: v1(134.46,56.61) 133.19,56.61 128.3,51.72 128.3,44.73 v1(128.74,44.29) 128.17,43.72 117.99,43.72 115.61,41.34 115.61,40.56 115.19,40.14 115.19,36.19 111.36,32.36 110.12,32.36 108.87,31.11 108.87,23.09 119.09,12.87 v1(119.09,12.79)
  BOTTOM w0.254: R366.2 v1(119.09,12.79) ; R369.2 v1(128.74,44.29)
  BOTTOM w0.508: R367.2 50.52,116.95 49.42,115.84 46.78,115.84 46.38,116.24 46.38,116.81 v1(46.51,116.93)
EDP_AUXN: length 151
  IN2 w0.127: v1(28.58,140.99) 28.69,140.99 29.01,141.31 29.5,141.31 30.73,140.09 32.11,140.09 32.69,140.67 33.75,140.67 34.46,139.97 34.46,138.63 34.95,138.13 41.09,138.13 44.29,134.93 44.29,116.86 46.94,114.2 46.94,107.31 46.82,107.18 46.66,107.18 46.54,107.06 46.54,106.77 v1(46.78,106.52) ; v1(98,61.68) 97.9,61.78 97.52,61.78 97.22,62.07 97.22,65.03 101.29,69.1 101.29,89.98 96.31,94.95 86.56,94.95 85.14,93.54 78.16,93.54 77.35,92.73 54.76,92.73 52.33,95.17 48.73,95.17 46.18,97.71 v1(46.18,99.62)
  BOTTOM w0.102: C206.1 28.12,141.18 28.4,141.18 v1(28.58,140.99) ; v1(46.18,99.62) 46.37,99.81 46.37,105.01 46.97,105.61 46.97,106.33 v1(46.78,106.52) ; UC1.H15 98.47,61.86 98.3,61.68 v1(98,61.68)
EDP_AUXN_C: length 3.5
  BOTTOM w0.102: JEDP1.7 25.87,142.68 26.11,142.43 v4(26.11,141.83) 26.11,141.55 26.49,141.17 27.19,141.17 C206.2
EDP_AUXP: length 151
  IN2 w0.127: v1(46.76,99.62) 46.93,99.46 46.93,99.15 46.44,98.67 46.44,97.82 48.84,95.43 52.44,95.43 54.87,92.99 77.24,92.99 78.05,93.8 85.03,93.8 86.45,95.22 96.42,95.22 101.55,90.09 101.55,68.99 97.49,64.92 97.49,62.18 97.63,62.04 97.83,62.04 97.98,62.19 v1(97.98,62.35) ; v1(28.58,141.58) 29.61,141.58 30.84,140.35 32,140.35 32.59,140.94 33.86,140.94 34.72,140.08 34.72,138.74 35.06,138.39 41.2,138.39 44.55,135.04 44.55,116.96 47.21,114.31 47.21,106.68 v1(47.37,106.52)
  BOTTOM w0.102: v1(97.98,62.35) 98.06,62.35 UC1.G15 ; C207.1 28.13,141.38 28.39,141.38 v1(28.58,141.58) ; v1(46.76,99.62) 46.57,99.81 46.57,104.92 47.18,105.53 47.18,106.33 v1(47.37,106.52)
EDP_AUXP_C: length 3.5
  BOTTOM w0.102: C207.2 27.16,141.37 26.57,141.37 26.34,141.61 26.34,142.4 26.47,142.52 26.78,142.52 26.87,142.61 JEDP1.9
EDP_HPD: length 174.8
  TOP w0.102: R207.1 R209.1 v1(26.94,150.77) ; v1(96.42,77.5) 96.65,77.5 v2(96.97,77.18) 97.25,76.9 97.25,71.4 96.67,70.83 96.67,68.8 96.34,68.47 96.34,66.53 97.5,65.37 97.5,65.08 v1(97.92,64.66)
  IN2 w0.127: v1(96.42,77.5) 96.42,84.87 93.44,87.85 90.58,87.85 90.32,87.6 72.48,87.6 70,85.12 54.08,85.12 48.62,90.58 46.46,90.58 41.48,95.56 24.32,95.56 21.3,98.58 21.3,105.5 21.81,106.01 21.81,108.51 26.25,112.96 26.25,116.62 29.81,120.17 29.81,130.21 24.79,135.22 24.79,140.34 24.39,140.75 21.33,140.75 19.57,142.5 19.57,148.47 21.2,150.09 26.27,150.09 v1(26.94,150.77)
  BOTTOM w0.102: v1(97.92,64.66) 98.17,64.66 UC1.D15
EDP_HPD_R: length 3.3
  TOP w0.102: v2(29.05,148) 28.45,148 28.03,148.42 v1(28.03,148.43) 27.85,148.61 R207.2
  BOTTOM w0.102: v1(28.03,148.43) 28.01,148.43 27.87,148.57 JEDP1.12
EDP_TXN0: length 135.3
  IN2 w0.127: v1(31.63,141.58) 32.06,141.58 33.23,142.75 39.09,142.75 46.15,135.7 46.15,118.5 49.1,115.55 v1(49.1,110.38)
  BOTTOM w0.102: UC1.B9 102.07,66.3 102.07,67.47 101.5,68.04 101.5,72.29 101.06,72.74 101.06,74.88 98.01,77.93 98.01,79.39 93.85,83.55 92.15,83.55 91.32,84.38 91.32,92.04 88.26,95.1 79.23,95.1 77.09,97.25 49.78,97.25 48.67,98.36 48.67,103.75 48.08,104.33 48.08,106.61 48.34,106.87 48.34,108.61 49.1,109.37 v1(49.1,110.38) ; v1(31.63,141.58) 31.45,141.39 30.91,141.39 C209.1
EDP_TXN0_C: length 3.3
  BOTTOM w0.102: JEDP1.15 29.87,142.73 29.65,142.5 29.35,142.5 29.26,142.41 29.26,142.24 29.43,142.07 29.43,141.48 29.49,141.42 30,141.42 C209.2
EDP_TXN1: length 132
  IN2 w0.127: v1(47.16,103.57) 47.32,103.73 48.45,103.73 48.85,104.13 48.85,105.2 48.4,105.66 48.4,108.22 48.06,108.57 48.06,114.59 45.35,117.3 45.35,135.37 39.3,141.42 34.78,141.42 v1(34.62,141.58)
  BOTTOM w0.102: v1(34.62,141.58) 34.43,141.39 34.16,141.39 C211.1 ; v1(47.16,103.57) 47.67,103.57 47.77,103.46 47.77,97.93 49.28,96.41 76.52,96.41 78.75,94.19 87.99,94.19 90.49,91.69 90.49,83.91 91.69,82.71 93.5,82.71 97.17,79.04 97.17,77.58 100.19,74.56 100.19,72.3 100.66,71.83 100.66,67.57 100.98,67.26 100.98,66.42 100.91,66.19 100.91,66.04 UC1.B10
EDP_TXN1_C: length 3.5
  BOTTOM w0.102: C211.2 33.21,141.39 32.72,141.39 32.6,141.51 32.6,142.05 32.28,142.38 32.28,142.53 32.38,142.63 32.74,142.63 32.87,142.77 JEDP1.21
EDP_TXP0: length 135.2
  IN2 w0.127: v1(31.63,140.99) 31.85,140.99 31.96,141.1 31.96,141.23 32.04,141.31 32.17,141.31 33.34,142.49 38.98,142.49 45.88,135.59 45.88,118.39 48.84,115.44 48.84,110.73 v1(48.49,110.38)
  BOTTOM w0.102: C208.1 30.93,141.19 31.44,141.19 v1(31.63,140.99) ; UC1.A9 101.61,66.46 101.4,66.67 101.4,66.82 101.5,66.92 101.77,66.92 101.87,67.02 101.87,67.38 101.3,67.95 101.3,72.21 100.85,72.65 100.85,74.8 97.81,77.84 97.81,79.3 93.77,83.34 92.07,83.34 91.12,84.29 91.12,91.95 88.18,94.9 79.15,94.9 77,97.05 49.7,97.05 48.47,98.28 48.47,103.66 47.88,104.25 47.88,106.7 48.14,106.95 48.14,108.69 48.9,109.45 48.9,109.97 v1(48.49,110.38)
EDP_TXP0_C: length 3.3
  BOTTOM w0.102: C208.2 29.94,141.22 29.41,141.22 29.2,141.42 v4(29.2,141.75) 29.2,142.01 29.05,142.15 29.05,142.71 28.87,142.89 JEDP1.13
EDP_TXP1: length 132
  IN2 w0.127: v1(34.62,140.99) 34.78,141.15 39.19,141.15 45.08,135.26 45.08,117.19 47.79,114.48 47.79,108.46 48.14,108.11 48.14,105.55 48.59,105.09 48.59,104.24 48.34,103.99 48.16,103.99 48.03,104.12 48.03,104.46 47.93,104.55 47.77,104.55 47.64,104.42 47.64,104.12 47.51,103.99 47.32,103.99 v1(47.16,104.15)
  BOTTOM w0.102: v1(34.62,140.99) 34.43,141.19 34.16,141.19 C210.1 ; UC1.A10 101.38,66.11 101.46,66.19 101.46,66.31 101.18,66.59 101.18,67.34 100.87,67.66 100.87,71.91 100.4,72.38 100.4,74.64 97.37,77.66 97.37,79.13 93.59,82.91 91.77,82.91 90.69,83.99 90.69,91.78 88.07,94.39 78.83,94.39 76.61,96.61 49.37,96.61 47.97,98.01 47.97,103.55 47.75,103.77 47.54,103.77 v1(47.16,104.15)
EDP_TXP1_C: length 3.5
  BOTTOM w0.102: JEDP1.19 31.87,142.88 32.07,142.67 32.07,142.29 32.37,141.99 v4(32.37,141.72) 32.37,141.46 32.64,141.19 33.21,141.19 C210.2
EN_0.675VSP: length 3.8
  TOP w0.203: PC519.1 PR510.2 35.92,117.87 v1(35.38,117.34)
  BOTTOM w0.203: v1(35.38,117.34) 35.58,117.53 v2(35.97,117.53) 36.19,117.31 PU501.7
EN_1.35V: length 6.4
  TOP w0.102: PR902.1 v2(39.23,142.73)
  TOP w0.254: PU901.11 43.55,144.1 43.37,143.92 43.01,143.92 42.88,144.05
  TOP w0.508: 42.88,144.05 42.32,144.05 41.94,144.43 PC902.1 PR903.1 41.57,143.12 41.18,142.73 PR902.1
EN_1V: length 7.5
  TOP w0.102: v2(62.93,21.09) 63.62,20.4 63.62,19.08 64.05,18.65 v1(64.05,18.63)
  TOP w0.254: PU601.11 64.14,17.95 63.96,18.13 63.96,18.54 v1(64.05,18.63)
  BOTTOM w0.254: PR603.2 PR601.1 PC601.1 64.1,20.03 63.67,19.6 63.67,19.01 v1(64.05,18.63)
EN_DDR: length 4.4
  TOP w0.102: v2(36.97,119.87) PR508.2
  TOP w0.254: PR508.2 36.97,117.62 v1(36.98,117.61) PC518.1
  BOTTOM w0.203: v1(36.98,117.61) 36.59,117.21 PU501.8
EN_RT3661: length 4.6
  BOTTOM w0.102: v2(150.9,37.63) 150.9,38.05 151.63,38.78 PR851.2
  BOTTOM w0.203: PU801.29 153.27,40.12 152.75,39.59 PC811.2 PR851.2
EN_VGA: length 4.9
  BOTTOM w0.102: PR1015.1 59.71,104.7 60.12,104.28 v2(61.83,104.28)
  BOTTOM w0.203: PR1015.1 PC1010.1 58.83,105.63 58.41,106.05 PU1001.32
ENBKL: length 235.7
  TOP w0.102: v1(27.08,146.84) U203.2 25.97,146.84 25.75,146.61 25.75,146.41 R210.2 ; v1(95.4,77.63) v2(94.85,77.07) 93.5,75.72 93.5,72.74 93.06,72.29 QC1.1 ; v1(163.93,48.62) 164.3,48.99 U11.97
  IN1 w0.127: v1(27.08,146.84) 28.16,147.92 35.52,147.92 43.27,140.17 43.27,134.33 42.57,133.63 42.57,130.97 44.22,129.32 44.22,121.32 45.21,120.32 45.21,98.84 53.02,91.03 68.7,91.03 70.16,89.57 88.68,89.57 89.82,90.71 v1(90.01,90.71) 95.46,90.71 107.65,78.52 107.65,77.44 111.88,73.2 113.97,73.2 116.55,70.62 121.44,70.62 126.65,65.41 134.8,65.41 135.31,64.9 140.02,64.9 140.12,64.8 155.33,64.8 157.3,62.83 157.69,62.83 160.57,59.95 160.57,58.39 164.75,54.21 164.75,49.41 163.96,48.62 v1(163.93,48.62)
  BOTTOM w0.102: v1(95.4,77.63) 95.4,78.5 RC18.1 93.23,80.68 92.17,80.68 90.96,81.88 90.96,82.74 90.01,83.69 v1(90.01,90.71)
ENBKL_R: length 5.6
  TOP w0.102: QC1.3 93.71,68.32 RC22.1 94.06,68.31 94.21,68.46 94.59,68.46 v2(94.72,68.33) 94.72,67.86 v1(94.64,67.78)
  BOTTOM w0.102: v1(94.64,67.78) 94.39,67.78 93.72,67.12 93.72,66.34 94.07,65.99 UC1.B23
ENLDO_3V5V: length 17.1
  TOP w0.102: v1(160.79,26.32) 161.17,26.32 v2(161.49,26.64)
  TOP w0.254: PC429.1 160.79,26.71 v1(160.79,26.32)
  IN1 w0.254: v1(169.62,26.27) 169.48,26.41 167.6,26.41 166.91,27.11 165.55,27.11 165.32,27.34 161.03,27.34 160.68,26.99 160.68,26.42 v1(160.79,26.32)
  BOTTOM w0.254: v1(169.62,26.27) 169.75,26.14 PU402.11 ; v1(160.79,26.32) 160.72,26.38 160.72,26.47 160.49,26.7 PC429.1 PR402.2 161.51,26.81 161.51,25.52 160.88,24.9 PU401.11
ENVDD_R: length 8.5
  BOTTOM w0.102: UC1.B24 93.52,65.66 93.21,65.98 93.21,66.25 93.29,66.33 93.29,67.98 94.77,69.47 v2(94.77,70.57) RC20.1
EXT_MIC_RING2: length 29.8
  IN1 w1.016: 19.2,48.23 18.95,48.48 17.36,48.48 16.47,47.59 16.47,45.62 16.98,45.12 16.98,41.18 17.48,40.68 17.48,39.34 18.63,38.18 18.63,34.64 16.32,32.33 10.76,32.33 8.75,30.32
  BOTTOM w0.102: v1(19.71,46.96) 20.47,46.96 v2(20.67,47.15)
  vias: v1(8.18,29.06) v1(8.49,28.55) v1(19.71,47.59)
EXT_MIC_SLEEVE: length 24.5
  IN1 w1.016: 10.25,29.68 11.55,30.98 17.07,30.98 19.95,33.86 19.95,38.8 19.04,39.72 19.04,41.01 18.32,41.74 18.32,45.69
  BOTTOM w0.102: v1(18.09,46.51) 18.09,46.9 v2(18.23,47.04)
  vias: v1(9.17,29.08) v1(9.17,28.49) v1(17.49,46.51)
FB_1.35V: length 4.8
  TOP w0.102: PC907.2 v2(44.78,141.17)
  TOP w0.254: PR905.2 44.23,143.1 44.12,142.98 PR907.1 ; PR905.2 PC907.2 ; PR905.2 44.9,143.21 PU901.14
FB_1V: length 6.2
  TOP w0.102: v2(60.99,18.53) 60.99,17.94 61.27,17.66 62.51,17.66 PR610.1
  TOP w0.254: PU601.14 63.85,16.6 63.58,16.34 PR608.2 63.1,17.15 PR612.2 63.11,17.98 PR610.1
FB_APU: length 5
  TOP w0.254: PR809.2 PC812.2 ; PC812.2 155.16,47.53 154.78,47.15 v1(154.78,47) ; PC812.2 155.15,47.85 PR807.1 PC813.1
  BOTTOM w0.203: v1(154.78,47) 154.87,46.9 PU801.6
FB_DDR: length 4.1
  BOTTOM w0.203: PU501.6 35.79,116.63 35.64,116.78 35.25,116.78
  BOTTOM w0.254: 35.25,116.78 34.73,117.3 v2(34.46,117.3) 34.17,117.3 PR506.1 32.63,116.63 PR509.1
FB_NB: length 6.5
  TOP w0.102: v2(153.1,36.63) 153.96,37.5 PC810.1
  TOP w0.254: PC810.1 PR811.1 154.4,38.52 v1(154.4,39.34) 154.79,39.73 PC809.2 PR810.2
  BOTTOM w0.203: v1(154.4,39.34) 154.47,39.41 PU801.26
FB_VDDCI: length 2.4
  BOTTOM w0.102: T222.1 91.85,145.36 UV1.W1
FB_VGA: length 6.2
  BOTTOM w0.102: PR1017.2 55.95,100.6 55.95,100.08 56.21,99.81 v2(56.48,99.81)
  BOTTOM w0.203: PU1001.4 56.34,103.66 PC1024.1
  BOTTOM w0.254: PR1017.2 PC1026.1 PR1028.1 PC1024.1
FSET_CHG: length 3.1
  TOP w0.102: v1(148.41,14.03) v2(148.41,13.14)
  BOTTOM w0.203: PR755.1 149.06,13.14 148.44,13.76 148.44,14 v1(148.41,14.03) 148.37,14.07 PU703.12
GATEA20: length 193.9
  TOP w0.102: v1(177.03,51.21) 177.22,51.02 178.59,51.02 178.84,50.77 179.85,50.77 C836.1 179.81,51.08 179.35,51.08 179.12,51.32 U11.1
  IN1 w0.127: v1(88.04,46.76) 88.47,46.33 88.47,43.05 88.67,42.84 88.67,41.01 v1(89.66,40.03) ; v1(177.03,51.21) 176.62,50.81 176.62,46.75 177.8,45.57 177.8,38.87 173.45,34.51 173.45,25.94 174.56,24.82 174.56,13.51 167.37,6.32 139.9,6.32 136,2.42 99.62,2.42 97.88,4.16 97.88,15.67 95.02,18.53 95.02,24.51 94.38,25.15 90.94,25.15 88.31,27.78 84.12,27.78 82.99,28.91 82.34,28.91 80,31.25 80,33.08 81.16,34.23 v1(82.1,34.23)
  IN2 w0.127: v1(82.1,34.23) 84.01,34.23 87.4,37.62 87.4,38.38 89.05,40.03 v1(89.66,40.03)
  BOTTOM w0.102: RPC12.8 87.65,37.8 87.48,37.97 87.48,38.57 87.84,38.93 88.56,38.93 v2(89.3,39.67) v1(89.66,40.03) ; v1(88.04,46.76) UC1.AU35
GPIO19_CTF: length 5.3
  BOTTOM w0.102: UV1.M2 85.6,144.3 85.6,144.82 86.42,145.64 v2(86.42,146.81) 86.42,146.95 87.32,147.85 RV151.2 RV152.1
GPIO28: length 7.5
  BOTTOM w0.102: UV1.R5 87.98,143.43 88.44,143.89 88.44,144.39 88.79,144.74 88.79,145.63 89.58,146.43 89.58,147.51 RV21.2 89.69,147.92 89.21,148.4 v2(89.21,149.73)
GPU_GPIO5: length 19.1
  TOP w0.102: RV195.2 84.04,151.02 RV3152.2 v1(83.34,150.27) 82.83,149.76 DV1.2 ; v1(88.03,140.24) 88.03,140.24 v2(87.43,140.85)
  IN2 w0.142: v1(88.03,140.24) 87.87,140.08 86.49,140.08 86.26,140.3 86.26,141.56 85.11,142.71 85.11,143.29 85.33,143.52 85.33,144.25 84.67,144.92 84.67,145.92 84.2,146.39 84.2,148.97 83.34,149.83 v1(83.34,150.27)
  BOTTOM w0.102: UV1.T9 88.25,140.22 88.05,140.22 v1(88.03,140.24) ; RV3151.1 82.32,150.88 82.93,150.27 v1(83.34,150.27)
GPU_GPIO5_VGA#: length 247.1
  TOP w0.102: v1(167.74,58.6) 167.74,55.69 166.57,54.52 U11.88 ; v2(86.25,150.97) RV195.1 85,150.01 DV1.1 84.25,150.27 v1(83.97,150.27)
  IN1 w0.127: v1(83.97,150.27) 82.82,151.43 76.34,151.43 72.29,155.48 49.81,155.48 49.37,155.03 49.37,149.7 48.8,149.13 48.8,145.45 48.16,144.81 48.16,141.38 47.11,140.33 47.11,139.58 47.72,138.97 47.72,118.9 48.24,118.38 48.24,113.78 47.65,113.2 47.65,109.29 48.7,108.24 48.7,105.39 48.83,105.26 48.83,97.91 52.71,94.04 80.13,94.04 80.52,94.43 95.6,94.43 110.45,79.58 110.45,78.57 110.49,78.53 113.15,75.87 115.22,75.87 117.52,73.57 122.27,73.57 127.34,68.5 139.12,68.5 139.45,68.17 162.97,68.17 167.74,63.39 v1(167.74,58.6)
GPU_PROCHOT#: length 103
  TOP w0.102: v1(52.86,104.04) v2(52.14,104.04) ; v1(87.49,144.75) 88.44,143.8 RV91.1 87.72,142.99 RV90.2
  IN1 w0.102: 82.29,147.26 82.88,146.66 84.55,146.66
  IN1 w0.127: 82.29,147.26 79.91,149.64 79.34,149.64 77.88,151.1 76.29,151.1 72.23,155.16 50.19,155.16 49.75,154.72 49.75,149.51 49.18,148.94 49.18,145.25 48.54,144.62 48.54,143.6 49.29,142.85 49.29,111.68 51.82,109.15 51.82,104.51 52.29,104.04 v1(52.86,104.04) ; v1(87.49,144.75) 87.49,145.61 86.44,146.66 84.55,146.66
  BOTTOM w0.203: PU1001.9 53.77,106.05 53.69,105.97 53.69,104.81 52.92,104.04 v1(52.86,104.04) 52.67,103.85 52.36,103.85 PR1016.1
GPU_SVC: length 112.7
  TOP w0.102: RV89.2 v1(103.47,142.46) RV84.1 ; v1(53.56,113.06) 53.3,112.81 v2(53.3,112.36)
  IN2 w0.127: v1(53.56,113.06) 51.67,111.17 51.67,101.61 52.57,100.7 53.22,100.7 56.37,97.55 74.18,97.55 75.05,98.42 79.61,98.42 80.65,99.46 93.42,99.46 95.53,101.57 95.53,108.93 103.34,116.74 103.34,123.86 104.74,125.25 104.74,141.32 105.63,142.21 105.63,142.65 105.18,143.1 104.1,143.1 v1(103.47,142.46)
  BOTTOM w0.102: v1(53.56,113.06) 53.56,113.43 PC1014.2 53.11,113.49 53.11,112.63 PR1022.1 ; RV84.1 v1(103.47,142.46) RV89.2
GPU_SVC_R: length 25
  TOP w0.102: v2(103.36,145.42) 103.47,145.31 v1(103.47,144.61)
  IN2 w0.102: 88.52,145.1 87.99,144.57 87.99,142.26 87.17,141.44 87.17,140.94 v1(86.77,140.53)
  IN2 w0.127: v1(103.47,144.61) 100.22,147.86 97.18,147.86 96.66,147.34 90.58,147.34 88.52,145.28 88.52,145.1
  BOTTOM w0.102: v1(103.47,144.61) RV94.2 ; v1(86.77,140.53) 87.23,140.53 UV1.P8
GPU_SVC_RT3662: length 3.2
  BOTTOM w0.102: PR1022.2 53.69,111.14 53.69,108.93 53.76,108.85 PU1001.16
GPU_SVD: length 109.5
  TOP w0.102: RV88.2 v1(105.12,142.46) RV87.1 ; v2(53.9,113.77) 54.45,113.23 v1(54.45,113.06)
  IN2 w0.127: v1(54.45,113.06) 53.98,112.59 53.53,112.59 51.98,111.04 51.98,101.74 52.7,101.02 53.35,101.02 56.5,97.87 74.12,97.87 74.98,98.73 79.47,98.73 80.52,99.78 93.36,99.78 95.28,101.69 95.28,109.13 103.02,116.88 103.02,123.99 104.42,125.38 104.42,141.76 v1(105.12,142.46)
  BOTTOM w0.102: v1(54.45,113.06) 54.45,113.43 PC1013.2 54,113.49 54,112.63 PR1018.1 ; RV87.1 v1(105.12,142.46) RV88.2
GPU_SVD_R: length 23.1
  TOP w0.102: v1(105.11,144.61) 105.11,145.36 v2(105.01,145.46)
  IN2 w0.102: v1(86.92,144.71) 87.3,145.1
  IN2 w0.127: 87.3,145.1 87.64,145.43 88.32,145.43 90.48,147.59 96.56,147.59 97.08,148.11 100.72,148.11 103.64,145.19 104.52,145.19 v1(105.11,144.61)
  BOTTOM w0.102: UV1.N1 86.41,144.71 v1(86.92,144.71) ; RV93.2 105.11,144.01 v1(105.11,144.61)
GPU_SVD_RT3662: length 2.2
  BOTTOM w0.102: PR1018.2 v2(54.19,110.6) 54.19,110.39 54.74,109.85 PU1001.17
GPU_SVT: length 106.7
  TOP w0.102: v1(55.34,113.06) v2(55.34,113.81)
  IN2 w0.127: v1(104.29,142.46) 104.1,142.27 104.1,125.52 102.71,124.12 102.71,117.01 95.02,109.32 95.02,101.82 93.3,100.09 80.38,100.09 79.34,99.05 74.92,99.05 74.06,98.19 56.63,98.19 53.48,101.34 52.83,101.34 52.3,101.87 52.3,110.98 53.61,112.29 54.56,112.29 v1(55.34,113.06)
  BOTTOM w0.102: RV156.2 v1(104.29,142.46) ; v1(55.34,113.06) 55.34,113.43 PC1032.2 54.89,113.49 54.89,112.58 PR1025.1
GPU_SVT_RT3662: length 3.2
  TOP w0.102: v2(54.52,109.97) 54.7,110.15 v1(54.7,110.76)
  BOTTOM w0.102: PU1001.18 55.14,109.9 54.7,110.34 v1(54.7,110.76) 54.7,111.19 PR1025.2
H_PROCHOT#: length 151.4
  TOP w0.102: R923.2 166.88,46.39 R929.2 166.12,45.53 C191.1 166.14,45.21 166.83,44.53 v1(166.83,43.82) ; v1(89.69,72.92) v2(89.69,73.67)
  IN1 w0.127: v1(81.37,92.24) 81.49,92.36 95.6,92.36 108.93,79.03 108.93,77.95 112.41,74.47 114.5,74.47 117.08,71.89 121.97,71.89 126.77,67.09 138.52,67.09 138.84,66.77 159.27,66.77 162.65,63.38 162.65,57.86 165.76,54.75 165.76,50.26 166.54,49.48 166.54,44.11 v1(166.83,43.82)
  IN2 w0.102: v1(89.69,72.92) 90.22,72.38 90.22,68.68 v1(89.59,68.05)
  BOTTOM w0.102: v1(89.69,72.92) CC113.2 87.45,73.12 87.15,73.12 86.44,73.83 RPC1.1 86.44,74.34 86.95,74.85 86.95,78.05 85.35,79.64 85.35,84.63 83.97,86.01 83.97,86.96 81.18,89.76 81.18,92.05 v1(81.37,92.24) ; v1(89.59,68.05) 89.6,68.05 89.71,67.94 89.71,66.5 UC1.A31
HDA_BITCLK: length 13
  BOTTOM w0.102: RPC6.5 107.04,34.64 106.52,35.16 RC49.2 105.07,35.72 104.68,35.72 103.75,36.65 v4(103.75,37.36) 103.75,43.57 103.67,43.65 103.67,43.99 103.76,44.08 103.76,44.34 103.67,44.43 103.67,44.44 103.42,44.68 UC1.AY6
HDA_BITCLK_AUDIO: length 143.8
  IN2 w0.127: v1(4.92,24.37) 4.3,24.37 4.06,24.13 4.06,24.09 3.65,23.67 3.65,20.54 3.61,20.5 3.61,19.42 3.67,19.35 3.67,16.97 3.9,16.74 3.9,15.23 8.94,10.19 18.59,10.19 21.7,7.08 48.54,7.08 49.75,8.29 52.67,8.29 55.21,5.75 62,5.75 62.77,4.98 93.18,4.98 98.31,10.11 v1(101.5,10.11)
  BOTTOM w0.102: v1(101.5,10.11) 101.5,11.41 103.08,12.99 103.08,21.62 104.79,23.33 v2(104.79,27.97) 104.79,29.23 107.04,31.48 RPC6.4 ; v1(4.92,24.37) 4.92,24.25 RA50.1 5.4,24.14 6,24.73 6.44,24.73 6.53,24.64 UA1.5
HDA_RST#: length 11.7
  BOTTOM w0.102: RPC9.6 108.04,36.3 108.28,36.54 108.68,36.54 108.85,36.72 108.85,38.31 v2(108.32,38.84) 107.39,39.78 106.92,39.78 105.48,41.23 105.48,44.01 105.27,44.22 104.98,44.22 104.52,44.68 UC1.AY4
HDA_SDIN0: length 154.4
  IN2 w0.127: v1(101.01,9.56) 98.52,9.56 93.37,4.41 62.51,4.41 61.75,5.17 55.02,5.17 52.48,7.71 50,7.71 48.86,6.57 21.49,6.57 18.44,9.62 8.79,9.62 3.39,15.02 3.39,16.41 2.34,17.47 2.34,24.87 v1(3.42,25.95)
  BOTTOM w0.102: v1(101.01,9.56) 101.01,11.6 102.59,13.19 102.59,21.82 104.31,23.54 104.31,31.46 v2(104.25,31.51) 104.25,34.61 RC54.1 103.54,36.42 103.54,42.47 103.53,42.48 103.53,43.46 103.42,43.58 UC1.BA6 ; v1(3.42,25.95) RA52.2
HDA_SDIN0_AUDIO: length 2.6
  BOTTOM w0.102: RA52.1 5.29,25.62 v2(6.05,25.62) 6.63,25.62 6.81,25.44 UA1.7
HDA_SDIN1: length 7.5
  BOTTOM w0.102: UC1.AY5 103.97,44.33 104.31,43.98 104.31,42.97 104.75,42.54 v2(104.75,38.73) 104.75,38.64 RC52.1
HDA_SDIN2: length 6.4
  BOTTOM w0.102: UC1.BA5 103.97,42.93 104.44,42.46 v2(104.44,39.98) 104.44,38.12 RC53.1
HDA_SDOUT: length 11.2
  BOTTOM w0.102: RPC6.6 107.54,34.93 107.04,35.43 RPC9.8 107.04,36.15 106.21,36.98 v2(106.21,38.68) 106.21,39.36 104.99,40.57 104.99,42.67 104.52,43.14 UC1.BA4
HDA_SDOUT_AUDIO: length 139.4
  IN2 w0.127: v1(102.01,11.08) 97.75,11.08 92.8,6.13 78.01,6.13 76.8,7.33 55.02,7.33 53.11,9.24 49.24,9.24 48.03,8.03 22.01,8.03 18.2,11.84 8.6,11.84 5.19,15.26 5.19,19.89 4.54,20.54 4.54,23.08 4.66,23.21 5.15,23.21 v1(6.19,24.24)
  BOTTOM w0.102: v1(102.01,11.08) 103.61,12.68 103.61,21.46 105.27,23.13 105.27,29.01 v2(106.13,29.87) 107.54,31.28 RPC6.3 ; v1(6.19,24.24) UA1.4
HDA_SYNC: length 11
  BOTTOM w0.102: RPC6.7 108.04,34.88 107.54,35.38 RPC9.7 107.54,36.31 107.3,36.54 106.96,36.54 106.52,36.99 106.52,39.67 v2(106.17,40.01) 105.25,40.94 105.25,42.92 105.12,43.05 UC1.BA3
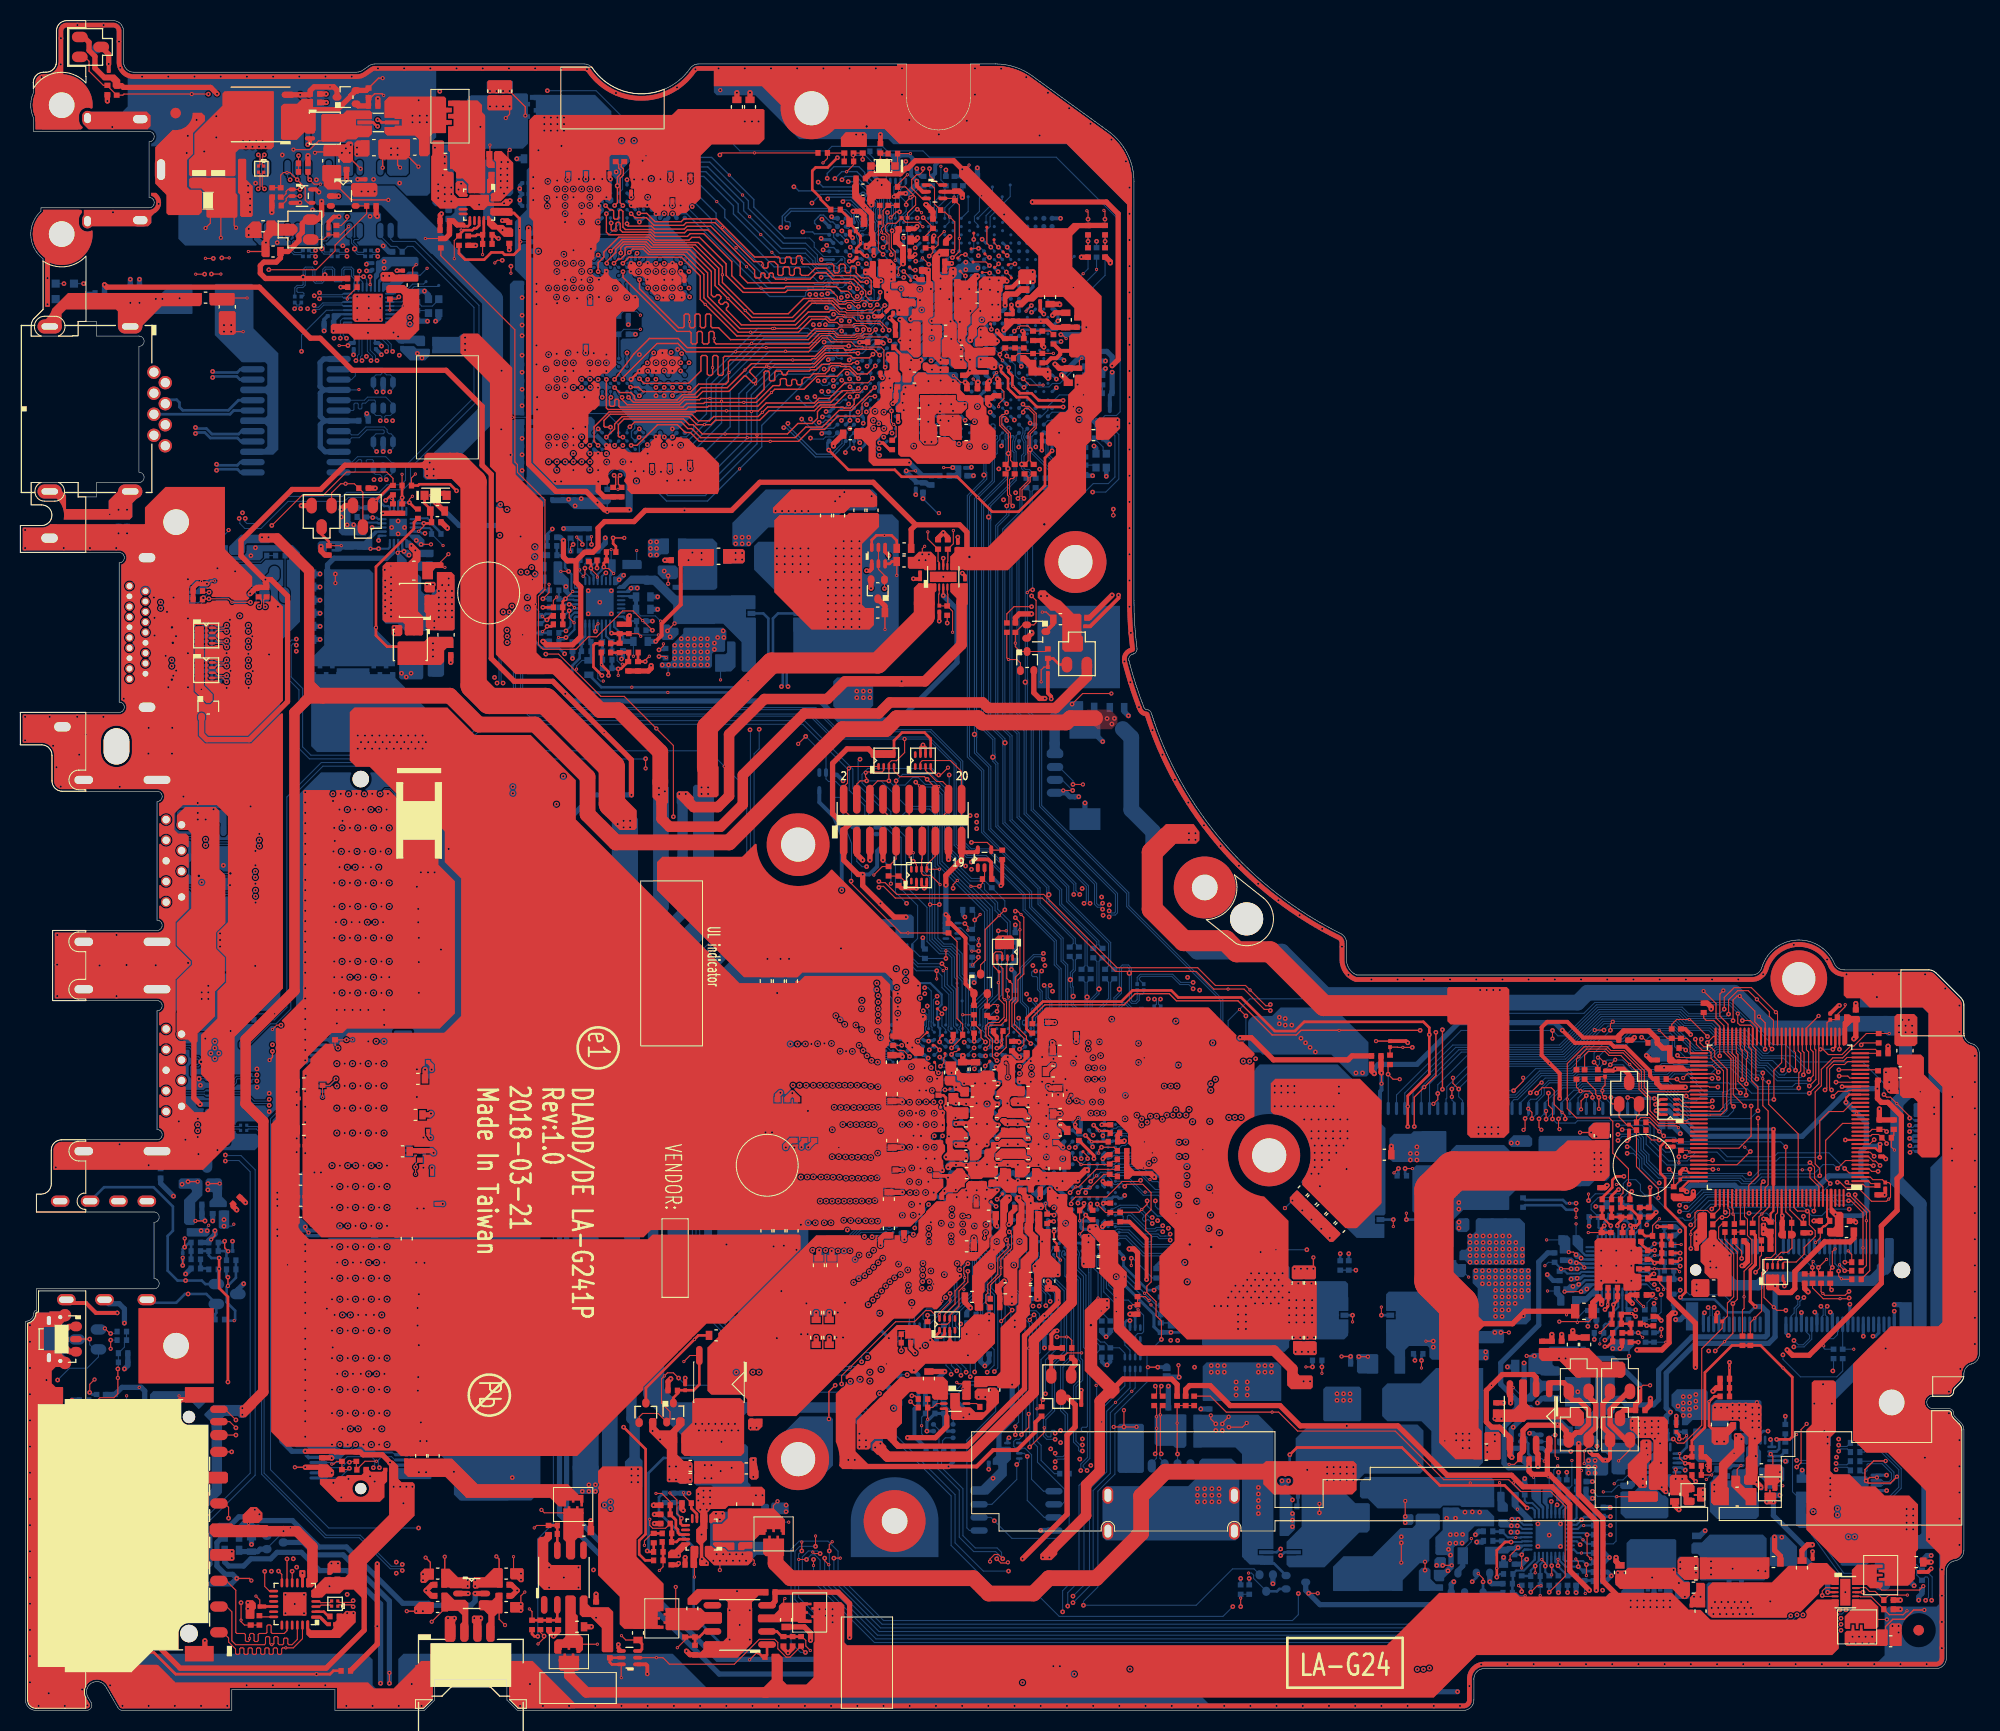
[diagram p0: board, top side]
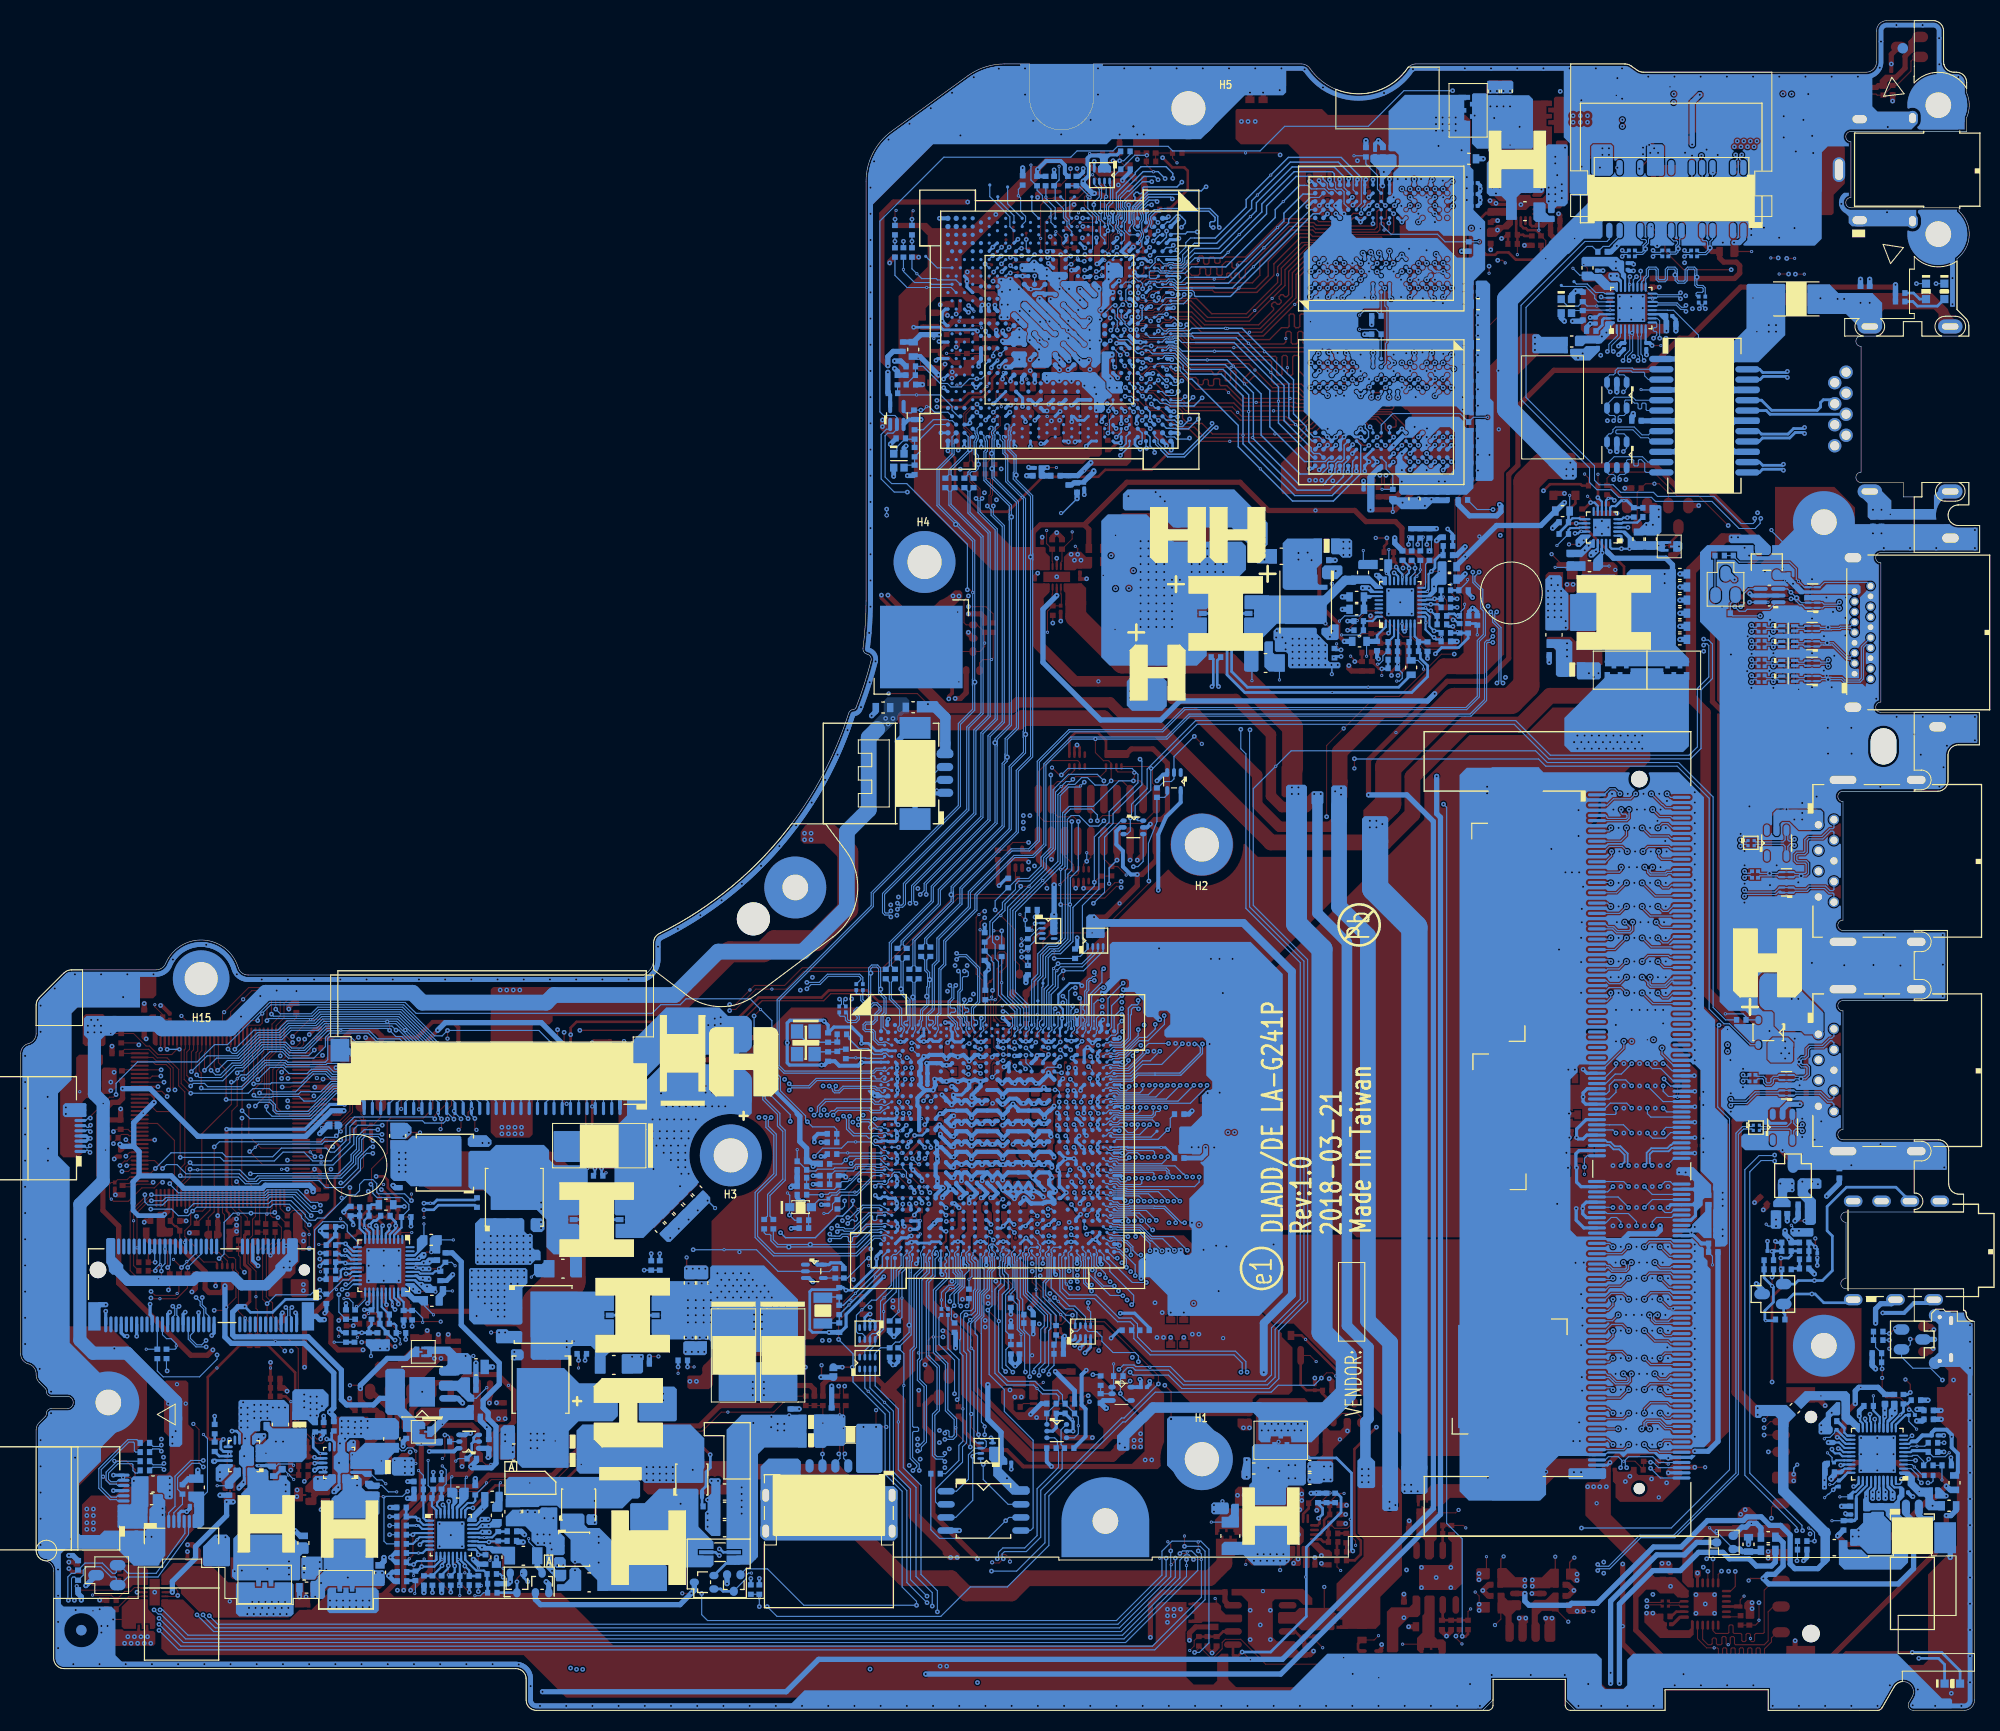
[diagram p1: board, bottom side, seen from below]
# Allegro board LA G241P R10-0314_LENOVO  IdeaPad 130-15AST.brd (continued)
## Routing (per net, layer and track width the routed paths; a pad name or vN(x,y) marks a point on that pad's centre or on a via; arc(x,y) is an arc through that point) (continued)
HDA_SYNC_AUDIO: length 143.7
  IN2 w0.127: v1(6.53,26.64) 5.49,25.6 5.49,24.16 5.04,23.72 4.41,23.72 4.16,23.46 4.16,20.33 4.12,20.29 4.12,19.63 4.18,19.56 4.18,17.18 4.41,16.95 4.41,15.44 9.15,10.7 18.8,10.7 21.91,7.59 48.29,7.59 49.49,8.79 52.92,8.79 54.83,6.89 64.42,6.89 65.18,6.13 77.05,6.13 77.62,5.55 92.99,5.55 98.07,10.63 101.82,10.63 v1(102.01,10.44)
  BOTTOM w0.102: UA1.9 6.97,26.24 6.58,26.64 v1(6.53,26.64) ; RPC6.2 108.04,31.27 v2(107.71,30.94) 105.63,28.86 105.63,22.98 103.96,21.32 103.96,12.4 v1(102.01,10.44)
HDD_ODD_DETECT: length 132.3
  TOP w0.102: v1(183.11,57.43) 183.11,57.6 181.87,58.84 v2(181.87,58.85) 181.25,59.47 180.88,59.47 v1(180.62,59.72)
  IN1 w0.127: v1(99.8,39.66) 101.64,39.66 103.27,38.04 106.5,38.04 109.03,35.51 111.1,35.51 v1(111.48,35.89)
  IN2 w0.127: v1(113.6,57.08) 114.3,56.38 114.3,51.38 113.15,50.22 113.15,47.61 113.69,47.07 113.69,41.5 113.44,41.25 113.44,36.84 112.92,36.31 111.91,36.31 v1(111.48,35.89)
  BOTTOM w0.102: v1(99.8,39.66) 99.8,40.23 98.81,41.22 98.81,42.42 98.99,42.61 98.99,44.18 UC1.BA14 ; v1(180.62,59.72) 180.62,60.8 178.54,62.88 172.75,62.88 171.07,64.56 169.81,64.56 165.72,68.65 152.59,68.65 151.54,67.59 128.65,67.59 127.82,68.43 125.94,68.43 125.36,69 119.17,69 117.05,66.89 117.05,62.24 116.22,61.41 116.22,60.09 113.78,57.65 113.78,57.26 v1(113.6,57.08) 113.11,56.58 111.01,56.58 110.76,56.33 RC159.2 RC158.2 ; v1(183.11,57.43) 183.33,57.43 183.56,57.2 JODD2.7
HDMI_CLKN: length 3.5
  TOP w0.102: v1(19.97,105.22) 19.69,104.95 18.9,104.95 18.86,104.98 RPH1.8
  BOTTOM w0.102: CH14.2 20.6,105.03 20.16,105.03 v1(19.97,105.22) 19.78,105.03 19.54,105.03 19.39,105.18 LH1.1
HDMI_CLKP: length 3.5
  TOP w0.102: v1(19.97,104.64) 19.87,104.74 19.07,104.74 18.81,104.48 RPH1.7
  BOTTOM w0.102: LH1.4 19.4,104.68 19.55,104.83 19.78,104.83 v1(19.97,104.64) 20.16,104.83 20.6,104.83 CH13.2
HDMI_CTRL_CLK: length 19.1
  TOP w0.102: v1(22.28,107.46) v2(20.49,107.46) 20.16,107.79 v1(18.25,107.79) 17.69,107.79 RH28.2
  IN2 w0.127: JHDMI1.15 11.18,107.66 11.18,109.01 11.57,109.4 13.3,109.4 14.28,108.43 14.35,108.35 14.35,107.31 14.08,107.03 13.73,107.03 v1(13.57,106.87)
  BOTTOM w0.102: v1(18.25,107.79) 17.97,107.79 17.39,107.21 17.17,107.21 16.87,106.92 DH1.9 DH1.1 15.19,106.92 15.04,107.07 13.76,107.07 v1(13.57,106.87) ; QH15.6 v1(22.28,107.46)
HDMI_CTRL_DAT: length 13.6
  TOP w0.102: RH27.2 17.76,108.42 v1(18.27,108.42)
  IN2 w0.127: JHDMI1.16 11.9,107.53 11.44,107.99 11.44,108.9 11.68,109.14 13.19,109.14 14.09,108.24 14.09,107.42 13.97,107.3 13.73,107.3 v1(13.57,107.46)
  BOTTOM w0.102: QH15.3 18.6,108.76 v1(18.27,108.42) v4(17.72,107.88) 17.26,107.42 DH1.8 DH1.2 15.21,107.42 15.06,107.27 13.76,107.27 v1(13.57,107.46)
HDMI_HPD: length 16.4
  BOTTOM w0.102: RH133.2 RH138.2 23.85,111.93 23.27,111.35 18.38,111.35 17.74,110.71 17.74,109.69 v2(17.53,109.49) 16.97,108.92 DH1.6 DH1.5 15.47,108.92 15.01,109.38 10.9,109.38 JHDMI1.19
HDMI_HPD_R: length 3.9
  BOTTOM w0.102: RH133.1 25.63,108.21 QH5.2
HDMI_L_CLKN: length 6.2
  BOTTOM w0.102: LH1.2 17.7,105.18 17.56,105.04 17,105.04 16.86,105.17 DH2.6 DH2.5 15.54,105.17 15.4,105.02 v4(14.67,105.02) 13.58,105.02 13.47,105.13 12.5,105.13 JHDMI1.12
HDMI_L_CLKP: length 6.2
  BOTTOM w0.102: JHDMI1.10 12.5,104.93 13.39,104.93 13.5,104.82 14.3,104.82 14.33,104.79 15.01,104.79 15.04,104.82 15.39,104.82 15.54,104.67 DH2.4 DH2.7 16.88,104.67 17.05,104.83 17.57,104.83 17.72,104.68 LH1.3
HDMI_L_TX_N0: length 11.1
  BOTTOM w0.102: LH2.2 17.63,100.3 17.48,100.14 17.02,100.14 16.86,100.31 DH3.8 DH3.2 15.4,100.31 15.25,100.16 15,100.16 14.98,100.19 14.38,100.19 14.35,100.16 13.29,100.16 13.05,99.92 11.64,99.92 11.44,100.11 11.44,103.14 JHDMI1.9
HDMI_L_TX_N1: length 6.7
  BOTTOM w0.102: JHDMI1.6 12.5,102.13 12.78,102.13 14.17,103.52 v4(14.75,103.52) 15.37,103.52 15.52,103.67 DH2.2 DH2.8 16.9,103.67 17.05,103.52 17.5,103.52 17.64,103.66 LH3.2
HDMI_L_TX_N2: length 9.4
  IN2 w0.127: v1(14.65,101.85) 14.5,101.69 13.74,101.69 13.24,101.19 13.24,100.55 12.47,99.79 12,99.79 11.17,100.62 10.96,100.62 JHDMI1.3
  BOTTOM w0.102: LH4.2 17.66,101.81 17.49,101.64 17.02,101.64 16.86,101.8 DH3.6 DH3.5 15.51,101.8 15.36,101.66 14.84,101.66 v1(14.65,101.85)
HDMI_L_TX_P0: length 11.1
  BOTTOM w0.102: JHDMI1.7 10.55,103.16 10.72,103.33 10.96,103.33 11.24,103.06 11.24,100.03 11.55,99.71 13.13,99.71 13.37,99.96 v4(14.66,99.96) 15.29,99.96 15.44,99.8 DH3.1 DH3.9 16.88,99.8 17.02,99.94 17.48,99.94 17.62,99.8 LH2.3
HDMI_L_TX_P1: length 6.8
  BOTTOM w0.102: LH3.3 17.67,103.16 17.52,103.32 17.1,103.32 16.95,103.17 DH2.9 DH2.1 15.49,103.17 15.34,103.32 15.09,103.32 15.06,103.29 14.46,103.29 14.43,103.32 14.26,103.32 12.87,101.93 12.5,101.93 JHDMI1.4
HDMI_L_TX_P2: length 9.3
  IN2 w0.127: JHDMI1.1 10.88,100.36 11.06,100.36 11.89,99.52 12.58,99.52 13.5,100.44 13.5,101.08 13.85,101.43 14.48,101.43 v1(14.65,101.26)
  BOTTOM w0.102: v1(14.65,101.26) 14.84,101.45 15.36,101.45 15.5,101.31 DH3.4 DH3.7 16.88,101.31 16.88,101.3 17.02,101.44 17.49,101.44 17.62,101.31 LH4.3
HDMI_TX_N0: length 3.5
  TOP w0.102: v1(19.97,100.34) 19.12,100.34 18.83,100.62 RPH2.6
  BOTTOM w0.102: LH2.1 19.36,100.3 19.51,100.14 19.78,100.14 v1(19.97,100.34) 20.16,100.14 20.6,100.14 CH16.2
HDMI_TX_N1: length 3.5
  TOP w0.102: v1(19.97,103.7) 19.95,103.69 19.15,103.69 18.86,103.98 RPH1.6
  BOTTOM w0.102: CH18.2 20.6,103.51 20.16,103.51 v1(19.97,103.7) 19.78,103.51 19.54,103.51 19.38,103.66 LH3.1
HDMI_TX_N2: length 3.5
  TOP w0.102: RPH2.8 18.87,101.62 18.93,101.57 19.67,101.57 v1(19.97,101.86)
  BOTTOM w0.102: LH4.1 19.39,101.81 19.55,101.66 19.76,101.66 v1(19.97,101.86) 20.16,101.67 20.6,101.67 CH20.2
HDMI_TX_P0: length 3.5
  TOP w0.102: RPH2.5 19.6,100.12 v1(19.97,99.75)
  BOTTOM w0.102: LH2.4 19.38,99.8 19.52,99.94 19.78,99.94 v1(19.97,99.75) 20.16,99.94 20.6,99.94 CH15.2
HDMI_TX_P1: length 3.5
  TOP w0.102: v1(19.97,103.12) 19.6,103.48 RPH1.5
  BOTTOM w0.102: LH3.4 19.4,103.16 19.55,103.31 19.78,103.31 v1(19.97,103.12) 20.16,103.31 20.6,103.31 CH17.2
HDMI_TX_P2: length 3.5
  TOP w0.102: v1(19.97,101.27) 19.88,101.36 19.05,101.36 18.81,101.12 RPH2.7
  BOTTOM w0.102: LH4.4 19.41,101.31 19.55,101.45 19.79,101.45 v1(19.97,101.27) 20.16,101.47 20.6,101.47 CH19.2
HDT_P11: length 3.8
  TOP w0.102: JHDT1.11 86.13,82.73 v1(86.53,82.34) 86.84,82.03 RPC5.7
  BOTTOM w0.102: v2(86.53,83.16) v1(86.53,82.34)
HDT_P13: length 5.4
  TOP w0.102: JHDT1.13 87.4,82.58 87.34,82.51 RPC5.6 87.34,81.15 87.51,80.98 88.23,80.98 v2(89.13,80.08)
HDT_P15: length 4.3
  TOP w0.102: v2(89.07,81.57) RPC5.5 87.84,82.02 88.67,82.86 JHDT1.15
HGNDA: length 30.3
  TOP w0.127: v1(18.15,51.08) v3(19.29,51.08)
  TOP w0.381: JHP1.3 4.76,39.5 6.34,39.5 7.3,38.54 v1(9.36,38.54)
  IN1 w1.016: 17.36,50.83 15.14,48.61 15.14,46.89 14.63,46.39 14.63,42.77 15.12,42.28 15.12,40.45 13.2,38.54 v1(9.36,38.54)
  BOTTOM w0.381: JHP1.3 4.76,39.5 6.34,39.5 7.3,38.54 v1(9.36,38.54)
  vias: v1(18.15,50.47)
HGNDB: length 11.3
  TOP w0.127: v1(16.22,51.27) v3(17.16,51.27)
  IN1 w1.016: 15.1,50.83 4.79,50.83
  vias: v1(15.65,51.02)
HP_OUTL: length 36.1
  TOP w0.127: v1(19.78,45.5) 19.78,44.86 v3(20.12,44.52)
  IN2 w0.254: v1(13.68,25.4) 13.33,25.4 12.79,25.94 12.79,29.18 15.01,31.4 16.54,31.4 18.76,33.62 18.76,36.89 17.81,37.85 17.81,42.95 16.51,44.25 15.75,44.25 15.33,44.67 15.33,45.18 15.65,45.5 16.86,45.5 17.17,45.18 19.46,45.18 v1(19.78,45.5)
  BOTTOM w0.203: v1(13.68,25.4) 13.53,25.4 13.18,25.04 UA1.25
  BOTTOM w0.254: RA45.1 CA46.1 RA36.2 RA57.2 19.65,45.37 v1(19.78,45.5)
HP_OUTR: length 31.5
  TOP w0.127: v1(15.9,44.92) v3(15.9,45.76)
  IN2 w0.254: v1(15.9,44.92) 16.6,44.92 18.32,43.21 18.32,38.06 19.27,37.1 19.27,33.37 16.79,30.89 15.27,30.89 13.3,28.92 13.3,26.19 13.55,25.94 13.93,25.94 14.29,25.58 v1(14.29,25.33)
  BOTTOM w0.203: v1(14.29,25.33) 14.29,25.21 14,24.92 13.55,24.92 13.27,24.64 UA1.26
  BOTTOM w0.254: RA56.1 RA49.2 RA44.2 16.35,45.37 v1(15.9,44.92) 15.71,44.73 CA54.1
HPOUT_L: length 7.6
  BOTTOM w0.254: RA63.1 19.88,37.79 v2(20.7,37.79) 20.79,37.88 20.79,38.76 19.97,39.58 19.97,41.05 20.87,41.95 CA56.2 RA45.2
HPOUT_L1: length 9.2
  BOTTOM w0.254: JHP1.1 12.53,39.53 15.08,39.53 15.93,40.38 v1(16.23,40.38) 18,40.38 DA8.2 18.97,38.55 18.85,38.42 RA63.2
HPOUT_R: length 1.7
  BOTTOM w0.254: RA64.1 18.15,42.85 CA59.2 RA56.2
HPOUT_R1: length 22.6
  BOTTOM w0.254: JHP1.2 8.09,50.73 12.88,50.73 14.76,48.86 14.76,46.51 14.25,46 14.25,42.64 15.21,41.68 v1(15.99,41.68) 17.56,41.68 17.9,41.34 DA8.3 19.15,41.52 RA64.2
I2C0_SCL: length 23
  BOTTOM w0.102: QC17.1 90.4,27.75 RC146.2 90.4,28.81 89.49,29.72 C2150.1 89.23,30 89.23,30.44 89.48,30.69 90.82,30.69 v2(91.35,31.22) 91.68,31.55 94.28,31.55 95.43,32.7 95.43,40.84 94.87,41.39 94.87,42.05 94.96,42.14 94.96,43.57 94.86,43.67 94.86,43.99 94.92,44.06 94.92,44.35 94.76,44.52 94.76,44.77 UC1.AY22
I2C0_SCL_TP: length 136
  TOP w0.102: v3(95.7,14.36) 95.63,14.29 95.02,14.29 v1(94.62,14.7)
  IN2 w0.127: v1(94.62,14.7) 94.72,14.6 94.72,13.04 95.67,12.1 101.98,12.1 103.88,10.19 107.28,10.19 112.44,5.03 135.4,5.03 136.32,5.95 175.79,5.95 177.42,7.59 177.89,7.59 181.57,11.27 184.53,11.27 184.77,11.03 184.77,10.79 v1(184.66,10.67)
  BOTTOM w0.102: JTP1.5 173.52,17.76 173.59,17.69 173.59,17.06 176.56,12.93 179.47,12.93 180.25,12.15 D281.2 180.6,12.27 180.6,12.83 180.7,12.93 181.1,12.93 182.1,13.93 183.48,13.93 183.8,13.61 183.8,13.12 C281.1 184.62,12.93 184.8,12.93 184.94,12.79 184.94,10.95 v1(184.66,10.67) ; v1(94.62,14.7) 94.73,14.81 94.73,15.17 94.51,15.4 92.39,15.4 90.99,16.8 90.99,21.35 88.91,23.42 88.91,25.21 RC144.2 89.02,25.76 89.02,27.2 QC17.6
I2C0_SDA: length 24.5
  BOTTOM w0.102: QC17.4 87.74,26.43 87.34,26.83 v2(87.34,27.6) 87.34,28.43 RC147.2 87.71,28.81 88.62,29.72 C2151.1 88.88,30 88.88,30.59 89.33,31.04 90.67,31.04 91.54,31.91 94.13,31.91 95.07,32.85 95.07,40.69 94.52,41.25 94.52,42.19 94.69,42.37 94.69,43.49 94.62,43.56 UC1.BA22
I2C0_SDA_TP: length 135.2
  TOP w0.102: v3(93.97,14.43) 93.97,14.69 94.4,15.12 94.78,15.12 v1(95.2,14.7)
  IN2 w0.127: v1(185.24,10.67) 185.16,10.76 185.16,11.19 184.69,11.65 181.42,11.65 177.73,7.97 177.26,7.97 175.63,6.33 136.16,6.33 135.25,5.42 112.6,5.42 107.44,10.57 104.04,10.57 102.14,12.48 95.82,12.48 95.1,13.2 95.1,14.6 v1(95.2,14.7)
  BOTTOM w0.102: v1(185.24,10.67) 185.3,10.72 185.3,12.94 184.95,13.29 184.62,13.29 C282.1 183.63,14.29 181.95,14.29 180.95,13.29 180.7,13.29 180.6,13.39 180.6,13.95 D281.3 180.25,14.08 179.47,13.29 176.74,13.29 173.95,17.17 173.95,17.7 174.02,17.77 JTP1.4 ; QC17.3 89.64,26.43 89.37,26.16 89.37,25.54 RC145.2 89.26,25.21 89.26,23.57 91.34,21.49 91.34,16.95 92.53,15.75 94.66,15.75 95.09,15.32 95.09,14.81 v1(95.2,14.7)
I2C1_SCL: length 8
  TOP w0.102: v1(95.83,46.4) 95.84,46.4 96.05,46.18 96.05,44.81 95.02,43.78 v2(95.02,42.94) 95.02,42.26 94.01,41.24 94.01,39.92 RC160.2
  BOTTOM w0.102: v1(95.83,46.4) 95.91,46.4 UC1.AU19
I2C1_SDA: length 8.5
  TOP w0.102: RC161.2 93.56,39.51 93.56,40.29 93.75,40.48 93.75,41.31 94.72,42.27 94.72,43.86 95.72,44.86 v2(95.72,45.12) 95.72,45.48 v1(95.58,45.62)
  BOTTOM w0.102: v1(95.58,45.62) 95.61,45.62 95.95,45.96 UC1.AV19
ILMT_1.35V: length 5.3
  TOP w0.102: PR906.1 42.03,142.52 v2(42.03,140.77)
  TOP w0.254: PR906.1 42.49,143.08 42.95,143.54 43.78,143.54 43.97,143.73 44.19,143.73 44.45,143.98 PU901.13
ILMT_1V: length 5.8
  TOP w0.102: v2(61.58,21.04) 62.16,21.04 62.97,20.22 PR609.1
  TOP w0.254: PU601.13 63.88,17.05 63.72,17.21 63.72,17.52 63.52,17.73 63.52,18.46 63.33,18.65 63.32,18.65 PR607.2 PR609.1
IMON_APU: length 2.4
  BOTTOM w0.203: PR843.1 158.96,44.29 158.78,44.11 v2(158.41,44.11) 158.24,44.11 157.85,43.72 PU801.14
IMON_NB: length 2.9
  BOTTOM w0.203: PR842.1 159.06,41.81 158.84,42.03 158.84,42.64 158.65,42.83 v2(158.37,42.83) 157.89,42.83 157.8,42.92 PU801.16
IMON_VGA: length 2.7
  TOP w0.102: v1(53.17,107.25) 53.36,107.25 v2(53.69,106.93)
  BOTTOM w0.203: PR1009.2 52.46,107.25 v1(53.17,107.25) PU1001.12
INVT_PWM_R: length 18.7
  TOP w0.102: UC21.2 93.44,80.82 RC24.1 93.23,80.22 v1(92.93,79.91) v2(92.12,79.91)
  BOTTOM w0.102: v1(92.93,79.91) 92.93,79.72 94.45,78.2 94.45,77.56 95.66,76.36 95.66,74.52 95.4,74.26 95.4,72.93 95.09,72.61 95.09,69.37 93.5,67.78 93.5,66.13 UC1.A24
ISEN1N_APU: length 37.7
  TOP w0.102: v1(133.06,47.59) v2(133.06,46.92)
  IN1 w0.254: v1(157.63,47.08) 157.63,47.4 155.54,49.5 155.54,50.68 155.12,51.1 154.65,51.1 153.94,50.39 152.49,50.39 151.35,51.53 135.28,51.53 133.44,49.69 133.44,47.97 v1(133.06,47.59)
  BOTTOM w0.203: PC805.2 157.01,46.74 156.47,46.2 PU801.10
  BOTTOM w0.254: v1(157.63,47.08) 157.63,47.34 157.89,47.59 PC807.1 157.88,47.97 PC805.2 PR852.2 ; PL803.3 v1(133.06,47.59)
ISEN1N_VGA: length 35.4
  BOTTOM w0.203: PU1001.8 54.74,104.14 54.37,103.78 PC1036.2
  BOTTOM w0.254: PL1001.3 73.41,106.37 72.93,105.88 72.93,100.42 71.21,98.71 v2(62.74,98.71) 55.02,98.71 53.48,100.25 53.48,101.32 54.19,102.02 54.19,102.53 PR1020.2 PC1036.2 53.51,103.6 PC1020.1
ISEN1P_APU: length 4.6
  BOTTOM w0.203: PU801.9 156.07,46.35 v2(156.56,46.83) 156.56,47.52 PC805.1
  BOTTOM w0.254: PR805.2 155.86,49.04 PR852.1 PC805.1
ISEN1P_APU_R: length 26.6
  TOP w0.102: v1(134.33,47.59) v2(134.33,48.21)
  IN1 w0.254: v1(152.68,48.86) 152.68,49.62 151.22,51.08 135.47,51.08 133.95,49.56 133.95,47.97 v1(134.33,47.59)
  BOTTOM w0.254: PL803.2 v1(134.33,47.59) ; PR805.1 153.57,48.86 v1(152.68,48.86)
ISEN1P_VGA: length 5.4
  BOTTOM w0.102: PR1030.2 54.42,101.82 53.89,101.29 v2(53.89,100.97)
  BOTTOM w0.203: PU1001.7 55.14,103.75 PC1036.1
  BOTTOM w0.254: PC1036.1 PR1020.1 55.29,102.02 PR1030.2
ISENN_NB: length 38.8
  TOP w0.102: v1(129.11,38.32) v2(129.11,37.67)
  IN1 w0.254: v1(153.57,35.91) 153.44,35.91 152.3,34.76 149,34.76 148.3,34.07 148.3,32.92 147.09,31.72 131.79,31.72 130.2,33.3 130.2,37.23 v1(129.11,38.32)
  BOTTOM w0.203: PC826.2 155.27,38.61 PU801.24
  BOTTOM w0.254: PC826.2 PR853.2 155.04,37.38 154.4,36.73 PC828.1 154.38,36.62 153.67,35.91 v1(153.57,35.91) ; PL804.3 v1(129.11,38.32)
ISENP_NB: length 6.1
  BOTTOM w0.102: PR845.2 153.46,36.43 153.08,36.05 v2(153.08,35.54)
  BOTTOM w0.203: PU801.25 154.87,39.13 PC826.1 PR853.1 153.63,37.5 153.46,37.32 PR845.2
ISENP_NB_R: length 32.3
  TOP w0.102: v1(131.9,38.32) v2(131.9,39.11)
  IN1 w0.254: v1(131.9,38.32) 130.71,37.13 130.71,33.49 132.11,32.1 146.84,32.1 147.86,33.11 147.86,34.26 148.81,35.21 150.71,35.21 151.48,35.97 v1(152.54,35.97)
  BOTTOM w0.254: PL804.2 v1(131.9,38.32) ; PR845.1 v1(152.54,35.97)
ISOLATE#: length 4.2
  TOP w0.102: v2(31.66,136.86) 31.66,137.06 RL10.1 RL8.2 32.79,139.03 v1(33.24,139.03)
  BOTTOM w0.102: UL2.20 33.55,138.72 v1(33.24,139.03)
JTAG_TCK: length 5.8
  TOP w0.102: v3(84.33,144.77) 84.87,145.31 v1(85.19,145.31)
  BOTTOM w0.102: UV1.L3 84.78,144.23 85.13,144.58 85.13,145.25 v1(85.19,145.31) 85.19,146.54 85.09,146.64 85.09,147.76 85.3,147.97 RPV34.6
JTAG_TDI_GPU: length 8.7
  TOP w0.102: v2(84.78,140.62) 84.78,141.46 84.41,141.83 84.41,143.43 v1(84.47,143.49)
  BOTTOM w0.102: RPV34.8 84.3,147.92 84.23,147.85 84.23,146.36 84.61,145.98 84.61,144.95 84.45,144.79 84.45,144.54 84.49,144.5 84.49,144.05 84.42,143.98 84.42,143.54 v1(84.47,143.49) 84.47,143.4 UV1.L5
JTAG_TDO_GPU: length 9.7
  BOTTOM w0.102: v3(80.7,150.8) 81.87,150.8 RV369.1 83.91,148.76 83.91,147.78 84,147.69 84,146.21 84.41,145.8 84.41,145.03 84.25,144.87 84.25,144.76 84.25,144.45 84.29,144.41 84.29,144.14 83.98,143.83 UV1.K4
JTAG_TMS_GPU: length 3.8
  BOTTOM w0.102: RPV34.7 84.8,147.89 84.65,147.73 v3(84.65,146.79) 84.81,146.63 84.81,144.72 UV1.L1
JTAG_TRSTB: length 7.8
  TOP w0.102: v1(85.84,146) 85.84,146.3 v3(86.25,146.71)
  BOTTOM w0.102: UV1.L6 84.78,142.61 85.21,143.04 85.21,144.37 85.36,144.52 85.36,144.91 85.84,145.38 v1(85.84,146) 85.84,146.23 85.31,146.77 85.31,147.5 85.8,148 RPV34.5
KBRST#: length 190.1
  TOP w0.102: v1(176.11,51.21) 176.37,51.21 176.91,50.67 178.12,50.67 179.42,49.37 180.88,49.37 v2(181.09,49.58) 181.26,49.75 181.26,51.02 181.09,51.19 C2154.1 180.47,51.47 179.54,51.47 179.29,51.72 U11.2 ; v1(87.91,38.32) RC90.2
  IN1 w0.127: v1(176.11,51.21) 176.11,51.19 175.5,50.58 175.5,47.33 177.42,45.41 177.42,41.79 176.75,41.11 176.75,38.38 173.07,34.7 173.07,25.75 174.18,24.63 174.18,13.66 167.22,6.7 139.74,6.7 135.85,2.8 99.88,2.8 98.26,4.41 98.26,15.83 95.4,18.69 95.4,24.67 94.54,25.53 91.1,25.53 88.47,28.16 84.28,28.16 83.15,29.29 82.53,29.29 80.84,30.98 80.84,32.22 82.76,34.14 83.73,34.14 v1(87.91,38.32)
  BOTTOM w0.102: v1(87.91,38.32) 88.55,38.32 90.5,40.28 90.5,41.45 90.18,41.77 90.18,44.17 UC1.BA30
KSI0: length 39.9
  TOP w0.102: v1(168.3,61.22) 168.2,61.32 168.2,64.08 167.9,64.37 U11.55 167.9,66.25 167.71,66.45 166.65,66.45 166.45,66.65 v3(166.45,67.57)
  BOTTOM w0.102: JKB1.15 142.97,59.15 143.25,59.43 143.82,59.43 144.08,59.68 144.91,59.68 147.23,62.01 150.33,62.01 150.74,62.41 152.77,62.41 153.04,62.68 153.04,63.48 154.1,64.55 155.64,64.55 155.93,64.84 157.41,64.84 157.89,65.32 159.95,65.32 160.1,65.17 160.1,63.1 160.35,62.86 163.98,62.86 164.16,63.04 166.24,63.04 168.05,61.22 v1(168.3,61.22)
KSI1: length 28.4
  TOP w0.102: v3(151.26,58.29) 151.26,59.1 v1(151.77,59.61) ; U11.56 167.5,64.33 167.79,64.04 167.79,61.05 168.4,60.44 v1(168.4,58.15)
  BOTTOM w0.102: v1(168.4,58.15) 167.64,57.38 161.73,57.38 159.27,59.85 152.01,59.85 v1(151.77,59.61) JKB1.26
KSI2: length 30.9
  TOP w0.102: v1(167.29,60.75) 167.29,63.18 167.4,63.29 167.4,63.8 167.1,64.09 U11.57 ; v3(145.68,56.29) 145.84,56.44 v1(145.84,57.4)
  BOTTOM w0.102: v1(145.84,57.4) 146.17,57.73 JKB1.19 146.17,59.05 146.38,59.26 146.94,59.26 147.42,59.75 147.42,60.4 148.12,61.09 150.73,61.09 151.09,61.45 159.72,61.45 160.22,61.94 161.58,61.94 162.67,60.85 165.56,60.85 165.66,60.75 v1(167.29,60.75)
KSI3: length 30
  TOP w0.102: v1(166.88,61.17) 166.88,63.99 166.7,64.17 U11.58 ; v3(147.44,60.88) 147.34,60.88 v1(146.35,59.88)
  BOTTOM w0.102: JKB1.18 145.37,58.91 v1(146.35,59.88) 147.79,61.32 150.62,61.32 150.97,61.68 159.63,61.68 160.13,62.17 161.68,62.17 162.08,61.77 163.86,61.77 164.44,62.35 165.69,62.35 166.87,61.17 v1(166.88,61.17)
KSI4: length 29.5
  TOP w0.102: U11.59 166.3,63.75 166.47,63.58 166.47,60.99 167.26,60.2 v1(167.26,59.66) ; v3(147.87,58.12) v1(147.87,57.33)
  BOTTOM w0.102: v1(147.87,57.33) 147.88,57.33 148.57,58.03 JKB1.22 148.57,59.43 149.51,60.37 150.98,60.37 151.37,60.76 159.67,60.76 161.35,59.09 162.41,59.09 162.85,59.53 165.47,59.53 165.53,59.47 167.07,59.47 v1(167.26,59.66)
KSI5: length 29.1
  TOP w0.102: v3(147.41,56.3) 147.18,56.53 v1(147.18,57.36) ; U11.60 165.9,63.71 166.24,63.37 166.24,60.34 v1(166.71,59.87)
  BOTTOM w0.102: v1(147.18,57.36) 147.77,57.95 JKB1.21 147.77,58.95 149.46,60.63 150.92,60.63 151.28,60.99 159.78,60.99 160.77,60 162.71,60 162.95,59.76 166.6,59.76 v1(166.71,59.87)
KSI6: length 32.5
  TOP w0.102: v1(167.12,58.6) 166.02,59.71 166.02,63.27 165.5,63.78 U11.61 165.5,66.54 164.71,67.34 164.71,69.47 v3(165.05,69.8)
  BOTTOM w0.102: v1(167.12,58.6) 166.75,58.97 165.72,58.97 165.41,58.66 165.41,58.16 165.1,57.85 161.93,57.85 159.48,60.3 151.56,60.3 151.17,59.91 150.94,59.91 150.17,59.14 JKB1.24
KSI7: length 30.4
  TOP w0.102: v1(166.04,58.57) 165.79,58.82 165.79,63.18 165.1,63.86 U11.62 165.1,66.39 164.34,67.15 164.34,68.55 v3(163.13,69.75)
  BOTTOM w0.102: JKB1.25 150.97,59.39 151.66,60.08 159.38,60.08 161.85,57.61 165.5,57.61 166.04,58.16 v1(166.04,58.57)
KSO0: length 37.7
  TOP w0.102: U11.39 174.3,60.77 v1(173.38,59.85) ; v3(146.14,58.35) 146.5,57.99 v1(146.5,57.38)
  BOTTOM w0.102: v1(146.5,57.38) 146.97,57.86 JKB1.20 146.97,58.97 147.69,59.7 147.69,60.34 148.21,60.86 150.83,60.86 151.18,61.22 159.82,61.22 160.07,61.47 160.31,61.71 161.49,61.71 163.21,59.99 165.44,59.99 165.75,60.29 167.35,60.29 167.79,59.85 v1(173.38,59.85)
KSO1: length 39.8
  TOP w0.102: v1(173.38,60.55) 174.02,61.18 174.02,64.04 173.9,64.15 U11.40 ; v3(152.89,63.3) 153.03,63.3 v1(153.53,62.81)
  BOTTOM w0.102: v1(173.38,60.55) 173.13,60.8 172.05,60.8 171.73,60.48 168.47,60.48 166.14,62.81 164.25,62.81 164.07,62.63 160.25,62.63 160.15,62.73 159.08,62.73 158.5,62.15 156.21,62.15 155.3,63.06 153.78,63.06 v1(153.53,62.81) 152.9,62.18 150.83,62.18 150.43,61.78 147.33,61.78 145.01,59.45 144.17,59.45 143.77,59.05 JKB1.16
KSO2: length 43.4
  TOP w0.102: v1(173.38,61.18) 173.76,61.56 173.76,63.84 173.5,64.1 U11.41 ; v3(145.65,61.35) 145.65,61.02 v1(144.72,60.09)
  BOTTOM w0.102: JKB1.14 142.17,59.18 142.71,59.72 143.69,59.72 144.06,60.09 v1(144.72,60.09) 146.87,62.24 150.24,62.24 153.12,65.12 155.28,65.12 156.07,65.91 160.11,65.91 162.24,63.77 163.79,63.77 164.35,64.33 166.35,64.33 168.36,62.32 169.01,62.32 170.27,61.05 173.26,61.05 v1(173.38,61.18)
KSO3: length 48
  TOP w0.102: v1(173.32,61.94) 173.32,63.85 173.1,64.06 U11.42 173.1,66.16 v3(174.28,67.34)
  BOTTOM w0.102: JKB1.9 138.17,59.29 138.24,59.36 138.24,60.46 141.16,63.38 149.64,63.38 153.31,67.05 160.59,67.05 161.23,66.4 163.84,66.4 164.74,65.5 166.82,65.5 168.84,63.48 171.78,63.48 v1(173.32,61.94)
KSO4: length 42.8
  TOP w0.102: v1(154.1,65.96) 154.1,66.55 v3(154.33,66.78) ; v1(172.81,61.63) 172.87,61.69 172.87,63.78 172.7,63.96 U11.43
  BOTTOM w0.102: JKB1.13 141.37,59.84 144,62.46 150.02,62.46 152.9,65.35 153.49,65.35 v1(154.1,65.96) 154.28,66.13 160.21,66.13 162.34,64 163.69,64 164.25,64.56 166.44,64.56 168.45,62.55 169.22,62.55 170.4,61.37 172.56,61.37 v1(172.81,61.63)
KSO5: length 37.4
  TOP w0.102: v1(172.37,60.36) 172.37,61.82 172.56,62.01 172.56,63.72 172.3,63.97 U11.44 ; v1(154.09,62.6) 154.09,62.62 v3(154.57,63.1)
  BOTTOM w0.102: JKB1.17 144.57,59.04 144.76,59.23 145.1,59.23 147.42,61.55 150.52,61.55 150.9,61.93 153.42,61.93 v1(154.09,62.6) 155.32,62.6 156.01,61.92 159.51,61.92 160,62.4 164.17,62.4 164.35,62.58 166.05,62.58 168.4,60.23 172.24,60.23 v1(172.37,60.36)
KSO6: length 44.1
  TOP w0.102: v1(138.74,60.25) v3(138.74,59.49) ; U11.45 171.9,63.93 172.05,63.78 v1(172.05,62.07)
  BOTTOM w0.102: JKB1.10 138.97,58.95 138.74,59.19 v1(138.74,60.25) 141.63,63.15 149.74,63.15 153.41,66.82 160.49,66.82 161.14,66.17 163.74,66.17 164.64,65.27 166.73,65.27 168.75,63.25 170.87,63.25 v1(172.05,62.07)
KSO7: length 41.6
  TOP w0.102: U11.46 171.5,62.16 v1(171.41,62.07) ; v1(153.48,65.97) v3(152.58,65.97)
  BOTTOM w0.102: v1(171.41,62.07) 170.97,61.63 170.53,61.63 169.38,62.78 168.55,62.78 166.54,64.79 164.16,64.79 163.6,64.23 162.43,64.23 160.3,66.36 153.88,66.36 v1(153.48,65.97) 153.2,65.97 149.93,62.69 143.9,62.69 140.57,59.36 JKB1.12
KSO8: length 42.7
  TOP w0.102: U11.47 171.1,62.39 v1(170.78,62.07) ; v3(138.84,61.35) 138.84,60.81 v1(139.4,60.25)
  BOTTOM w0.102: v1(170.78,62.07) 169.83,63.02 168.63,63.02 166.61,65.04 164.55,65.04 163.64,65.95 161.04,65.95 160.4,66.59 153.5,66.59 149.83,62.92 142.03,62.92 139.4,60.29 v1(139.4,60.25) 139.4,59.5 139.77,59.13 JKB1.11
KSO9: length 32.2
  TOP w0.102: U11.48 170.7,62.82 169.95,62.07 v1(169.95,59.24) ; v3(149.17,56.37) 149.08,56.46 v1(149.08,57.36)
  BOTTOM w0.102: v1(169.95,59.24) 169.92,59.2 165.63,59.2 165.18,58.75 165.18,58.26 165,58.08 162.03,58.08 159.57,60.53 151.47,60.53 151.07,60.14 150.56,60.14 149.37,58.95 JKB1.23 149.37,57.65 v1(149.08,57.36)
KSO10: length 46.3
  TOP w0.102: v1(165.14,68) 165.14,69.13 166.1,70.09 167.76,70.09 v3(170.14,67.71) 170.3,67.55 U11.49
  BOTTOM w0.102: JKB1.4 134.17,59.86 138.83,64.52 149.17,64.52 152.84,68.19 161.06,68.19 161.69,67.56 164.7,67.56 v1(165.14,68)
KSO11: length 45.1
  TOP w0.102: v1(165.56,67.52) 165.56,68.92 166.44,69.79 167.46,69.79 v3(168.3,68.95) 169.51,67.75 169.51,67.31 169.9,66.92 U11.50
  BOTTOM w0.102: v1(165.56,67.52) 165.36,67.32 161.61,67.32 160.96,67.96 152.93,67.96 149.26,64.29 139.11,64.29 134.97,60.16 JKB1.5
KSO12: length 41.6
  TOP w0.102: v3(136.95,58.82) 137.37,59.24 v1(137.37,59.82) ; v1(169.77,64.13) 169.5,64.4 U11.51
  BOTTOM w0.102: v1(169.77,64.13) 169.35,63.71 168.94,63.71 166.92,65.73 164.84,65.73 163.94,66.63 161.33,66.63 160.68,67.28 153.22,67.28 149.55,63.61 140.31,63.61 137.37,60.66 v1(137.37,59.82) JKB1.8
KSO13: length 42.5
  TOP w0.102: v3(168.51,67.28) 169.1,66.68 U11.52 v1(169.1,64.11)
  BOTTOM w0.102: JKB1.7 136.57,60.75 139.65,63.84 149.45,63.84 153.12,67.51 160.78,67.51 161.42,66.86 164.04,66.86 164.95,65.96 167.26,65.96 v1(169.1,64.11)
KSO14: length 43.2
  TOP w0.102: U11.53 168.7,66.16 168.1,66.77 168.1,67.81 v3(166.64,69.27) 166.37,69.27 165.99,68.89 v1(165.99,66.88)
  BOTTOM w0.102: JKB1.6 135.77,60.42 139.41,64.06 149.36,64.06 153.03,67.73 160.87,67.73 161.52,67.09 165.79,67.09 v1(165.99,66.88)
KSO15: length 43
  TOP w0.102: v1(148.49,65.93) v3(148.49,65.14) ; U11.54 168.3,66.24 167.65,66.89 v1(166.89,66.89)
  BOTTOM w0.102: JKB1.3 133.37,59.67 139.63,65.93 v1(148.49,65.93) 149.01,65.41 149.73,65.41 152.74,68.42 165.63,68.42 166.87,67.18 166.87,66.92 v1(166.89,66.89)
KSO16: length 18
  TOP w0.102: U11.81 161.65,57.32 161.51,57.18 158.9,57.18 157.95,58.13 157.95,59.47 157.11,60.32 157.11,61.98 155.33,63.76 154.05,63.76 153.68,64.13 151.79,64.13 v2(151.05,63.38) 150.82,63.15 R275.1
KSO16_R: length 4.1
  TOP w0.102: R275.2 150.82,60.44 v3(151.21,60.05) 152.07,60.05 152.36,59.76 v1(152.36,59.44)
  BOTTOM w0.102: JKB1.27 152.57,59.01 152.36,59.21 v1(152.36,59.44)
KSO17: length 17.2
  TOP w0.102: R276.1 151.6,63.53 151.97,63.9 153.58,63.9 153.98,63.51 155.12,63.51 v2(155.98,62.65) 156.88,61.75 156.88,60.22 157.7,59.4 157.7,58.01 158.79,56.92 U11.82
KSO17_R: length 4.7
  TOP w0.102: R276.2 152.68,60.13 152.68,59.75 v1(152.99,59.44) v3(152.99,58.32)
  BOTTOM w0.102: JKB1.28 153.37,58.91 152.99,59.29 v1(152.99,59.44)
LAN_CLKREQ#: length 201.4
  IN2 w0.127: v1(81.52,33.81) 79.87,32.16 78.83,32.16 78.13,31.46 71.72,31.46 71.02,30.76 57.37,30.76 47.21,20.6 31.08,20.6 28.92,22.76 28.92,47.72 27.73,48.91 27.73,51.77 26.2,53.29 26.2,91.81 19.23,98.78 19.23,105.47 21.17,107.41 21.17,108.78 25.55,113.16 25.55,116.93 29.17,120.55 29.17,129.85 v1(27.23,131.79)
  BOTTOM w0.102: UC1.AY32 89.77,44.91 89.99,44.69 89.99,44.42 89.91,44.34 89.91,44.07 89.97,44 89.97,40.97 88.22,39.21 87.68,39.21 86.65,38.17 RPC12.6 86.65,36.99 86.39,36.73 85.56,36.73 85.05,36.23 85.05,35.78 83.97,34.7 81.84,34.7 81.52,34.38 v1(81.52,33.81) ; UL2.12 30.22,135.78 30.21,135.77 29.64,135.77 27.23,133.36 v1(27.23,131.79)
LAN_MDIN0: length 25.5
  IN2 w0.089: v1(35.47,131.78) 35.65,131.61 35.65,131.28 35.85,131.08 36.1,131.08 38.06,129.12 38.06,123.54 35.03,120.51 35.03,119.52 v1(34.87,119.35)
  BOTTOM w0.089: v1(35.47,131.78) 35.64,131.94 35.64,132.36 34.81,133.19 34.81,133.53 34.75,133.59 UL2.2 ; TL1.12 32.31,120.05 32.44,120.18 32.44,120.96 32.77,121.29 32.97,121.29 33.06,121.2 33.06,120.77 33.15,120.68 33.41,120.68 33.5,120.77 33.5,121.2 33.59,121.29 34.11,121.29 34.19,121.2 DL2.6 34.19,120.04 34.38,119.85 34.83,119.85 35.02,119.66 35.02,119.5 v1(34.87,119.35)
LAN_MDIN1: length 23.3
  IN2 w0.089: v1(34.51,122.08) 35.02,122.59 35.02,123.32 37.18,125.47 37.18,128.81 35.76,130.23 34.34,130.23 34.13,130.44 34.13,130.73 v1(33.96,130.89)
  BOTTOM w0.089: UL2.5 33.55,133.31 33.61,133.25 33.61,131.78 34.11,131.27 34.11,131.04 v1(33.96,130.89) ; TL1.9 31.73,123.05 32.09,123.41 32.81,123.41 33.57,124.17 35.14,124.17 35.24,124.07 35.24,123.89 35.14,123.79 34.45,123.79 34.19,123.54 DL2.1 34.19,122.39 v1(34.51,122.08)
LAN_MDIN2: length 20.2
  IN2 w0.089: v1(34.87,125.06) 35.03,125.23 35.03,125.58 36.29,126.83 36.29,128.43 35.35,129.37 33.41,129.37 32.67,130.11 32.67,130.72 v1(32.5,130.89)
  BOTTOM w0.089: v1(32.5,130.89) 32.65,131.04 32.65,131.37 32.81,131.52 32.81,133.25 32.75,133.31 UL2.7 ; v1(34.87,125.06) 35.02,125.22 35.02,125.44 34.89,125.57 34.45,125.57 34.19,125.82 DL1.6 34.38,126.48 34.38,126.97 34.28,127.07 33.74,127.07 33.44,126.77 33.17,126.77 33.08,126.68 33.08,126.29 32.99,126.2 32.82,126.2 32.73,126.29 32.73,126.68 32.64,126.77 32.4,126.77 32.31,126.67 32.31,126.14 32.22,126.05 TL1.6
LAN_MDIN3: length 18.2
  IN2 w0.089: v1(30.99,133.06) 31.07,132.99 31.07,131.27 31.6,130.74 31.6,129.98 33.04,128.53 35,128.53 35.09,128.44 35.09,128.37 34.58,127.86 v1(34.51,127.86)
  BOTTOM w0.089: UL2.10 31.22,134.98 30.99,134.75 v1(30.99,133.06) ; v1(34.51,127.86) 34.19,128.17 DL1.1 34.19,129.26 34.45,129.51 34.89,129.51 35.02,129.63 35.02,129.8 34.93,129.89 33.76,129.89 33.64,129.77 32.53,129.77 32.44,129.68 32.44,129.41 32.08,129.05 TL1.3
LAN_MDIP0: length 25.5
  IN2 w0.089: v1(36.06,131.78) 35.89,131.61 35.89,131.39 35.95,131.33 36.21,131.33 38.31,129.22 38.31,123.44 35.28,120.41 35.28,119.52 v1(35.45,119.35)
  BOTTOM w0.089: UL2.1 35.15,133.57 35.09,133.51 35.09,133.31 35.92,132.48 35.92,131.92 v1(36.06,131.78) ; TL1.11 32.13,121.05 32.65,121.57 35.4,121.57 36.09,120.87 DL2.4 36.09,120.04 35.91,119.85 35.46,119.85 35.3,119.69 35.3,119.5 v1(35.45,119.35)
LAN_MDIP1: length 23.3
  IN2 w0.089: v1(35.78,122.08) 35.27,122.59 35.27,123.22 37.42,125.37 37.42,128.91 35.86,130.47 34.44,130.47 34.37,130.54 34.37,130.72 v1(34.55,130.89)
  BOTTOM w0.089: v1(34.55,130.89) 34.39,131.04 34.39,131.39 33.89,131.9 33.89,133.25 33.95,133.31 UL2.4 ; TL1.8 31.71,124.05 32.07,123.69 32.69,123.69 33.46,124.45 35.26,124.45 35.52,124.19 35.52,123.98 35.72,123.79 35.91,123.79 36.09,123.6 DL2.3 36.09,122.39 v1(35.78,122.08)
LAN_MDIP2: length 20.2
  IN2 w0.089: v1(35.45,125.06) 35.28,125.23 35.28,125.48 36.53,126.73 36.53,128.54 35.45,129.62 33.51,129.62 32.92,130.21 32.92,130.72 v1(33.09,130.89)
  BOTTOM w0.089: UL2.6 33.15,133.31 33.09,133.25 33.09,131.4 32.94,131.25 32.94,131.04 v1(33.09,130.89) ; TL1.5 33.32,127.05 33.62,127.35 35.4,127.35 36.09,126.65 DL1.4 36.09,125.82 35.84,125.57 35.4,125.57 35.3,125.47 35.3,125.22 v1(35.45,125.06)
LAN_MDIP3: length 18.2
  IN2 w0.089: v1(35.78,127.86) 35.33,128.3 35.33,128.54 35.1,128.78 33.14,128.78 31.84,130.08 31.84,130.84 31.31,131.37 31.31,132.79 v1(31.59,133.06)
  BOTTOM w0.089: v1(35.78,127.86) 36.09,128.17 DL1.3 36.09,129.26 35.84,129.51 35.46,129.51 35.3,129.67 35.3,129.92 35.04,130.17 33.65,130.17 33.53,130.05 TL1.2 ; v1(31.59,133.06) 31.27,133.38 31.27,133.64 31.36,133.73 31.52,133.73 31.61,133.82 31.61,134 31.52,134.08 31.36,134.08 31.27,134.17 31.27,134.5 31.36,134.58 UL2.9
LANGAN:
  vias: v1(10.63,136.49) v1(11.52,136.49) v1(13.11,136.87) v1(13.74,136.87) v3(15.41,136.94)
LANGAN1:
  vias: v1(9.49,116.43) v1(10.31,116.43) v2(8.64,115.98)
LDO1: length 2.2
  BOTTOM w0.203: UA1.21 12.8,26.64 13.09,26.93 13.09,27.38
  BOTTOM w0.305: CA61.2 13.76,28.05 13.09,27.38
LDO2: length 3.2
  BOTTOM w0.102: v2(13.53,20.71) CA64.2
  BOTTOM w0.203: 12.22,21.18 12,21.18 11.3,21.88 UA1.32
  BOTTOM w0.305: CA64.2 12.51,20.89 12.22,21.18
LDO3: length 4.9
  BOTTOM w0.102: v2(2.92,24.98) 3.31,24.59 4.48,24.59 4.95,25.06 CA51.2
  BOTTOM w0.203: 6.5,25.19 6.65,25.04 UA1.6
  BOTTOM w0.305: 6.5,25.19 5.08,25.19 CA51.2
LDO_3V: length 1.2
  TOP w0.102: PC613.1 v2(65.32,12.93)
LDO_3V_1.35V: length 11.7
  TOP w0.254: PC912.1 47.82,145.2 48.36,144.66 v2(48.36,143.69) 48.36,141.71 47.81,141.15 46.93,141.15 46.7,141.38 45.63,141.38 44.94,140.68 43.08,140.68 42.49,141.27 PR906.2
LED1_GPIO: length 2.9
  TOP w0.102: v1(36.67,137.06) 36.46,136.86 RL17.1 v2(35.79,135.79)
  BOTTOM w0.102: UL2.26 36.59,136.98 v1(36.67,137.06)
LG1_APU: length 11.4
  TOP w0.102: v1(150.29,42.82) v3(149.32,42.82)
  IN1 w1.016: 149.02,42.87 144.81,47.08 140.3,47.08
  vias: v1(139.42,47.35) v1(139.42,46.77) v1(150.88,42.82)
LG1_VGA: length 6.5
  TOP w0.102: v1(62.7,104.68) 62.7,104.72 v3(63.39,105.4)
  IN2 w1.016: 60.63,109.09 62.08,109.09 62.97,108.2 62.97,105.45
  vias: v1(59.17,108.83) v1(59.77,108.83) v1(62.96,104.11)
LG_CHG: length 6.5
  TOP w0.102: v1(137.85,14.06) v3(138.72,14.06)
  IN2 w0.762: 143.44,16.63 141.1,14.29 138.76,14.29
  vias: v1(137.26,14.06) v1(144.47,17.29) v1(145.1,17.29)
LG_DDR: length 3.6
  TOP w0.102: v1(38.81,113.07) v3(39.78,113.07)
  IN2 w1.016: 39.72,109.82 39.72,112.49
  vias: v1(38.36,113.45) v1(39.39,109.19) v1(39.97,109.19)
LG_NB: length 7.4
  TOP w0.102: v1(143.49,36.64) v3(144.26,36.64)
  IN2 w1.016: 144.2,37.08 148.9,41.78
  vias: v1(142.9,36.64) v1(150.29,41.83) v1(150.88,41.9)
LID_SW#: length 263.5
  TOP w0.102: U11.115 171.5,48.53 C838.2 v1(172.81,47.91) ; U282.3 6.21,160.34 6.63,159.92 6.63,158.97 8.02,157.59 C2153.1 8.41,157.54 R273.1 9.91,156.63 10.01,156.74 v3(16.59,156.74) v1(18.2,156.74)
  IN1 w0.127: v1(18.2,156.74) 18.2,157.18 18.62,157.6 48.26,157.6 48.99,156.88 48.99,149.89 47.96,148.86 47.96,145.31 47.73,145.08 47.73,143.05 46.27,141.58 46.27,139.31 47.08,138.49 47.08,118.46 47.6,117.94 47.6,114.14 46.76,113.3 46.76,109.14 48.07,107.84 48.07,105.13 48.2,105 48.2,97.65 48.21,97.64 52.7,93.15 95.89,93.15 109.69,79.35 109.69,78.27 112.73,75.23 114.82,75.23 117.4,72.65 122.28,72.65 127.09,67.85 138.84,67.85 139.15,67.53 162.6,67.53 165.84,64.29 165.84,59.76 165.57,59.49 165.57,58.19 171.31,52.45 171.31,49.41 v1(172.81,47.91)
LINE1-L: length 32.4
  IN2 w0.254: v1(11.08,28.28) 11.13,28.33 11.13,29.8 13.24,31.91 16.22,31.91 18.25,33.94 18.25,36.68 17.3,37.64 17.3,42.7 16.28,43.72 15.33,43.72 14.76,44.29 14.76,45.62 15.2,46.07 17.05,46.07 17.43,45.69 19.13,45.69 19.45,46 20.03,46 v1(20.54,45.5)
  BOTTOM w0.203: UA1.18 10.9,27.88 11.08,28.06 v1(11.08,28.28)
  BOTTOM w0.254: CA46.2 v1(20.54,45.5)
LINE1-R: length 23
  TOP w0.127: v1(15.71,43.15) v3(15.71,43.9)
  IN2 w0.254: v1(10.6,28.72) 10.6,30.16 12.85,32.42 15.9,32.42 17.74,34.26 17.74,36.43 16.79,37.38 16.79,42.46 16.11,43.15 v1(15.71,43.15)
  BOTTOM w0.203: v1(10.6,28.72) 10.6,28.04 10.5,27.94 UA1.17
  BOTTOM w0.254: v1(15.71,43.15) CA54.2
LPC_AD0: length 200.1
  TOP w0.102: U11.10 179.25,54.92 v1(179.67,55.34) ; v1(76.86,14.64) v2(76.86,14.04)
  IN2 w0.127: v1(76.86,14.64) 76.86,15.15 76.61,15.4 76.61,18.01 85.74,27.14 86.73,27.14 90.2,30.61 90.2,31.47 91.15,32.41 v1(91.15,32.49) ; v1(176.94,9.75) 177.19,9.75 177.68,10.23 177.68,13.18 181.26,16.76 181.26,20.17 181.73,20.64 181.73,24.24 177.65,28.32 177.65,31.52 185.07,38.93 185.07,48.46 181.26,52.27 181.26,53.61 180.74,54.12 180.19,54.12 179.67,54.64 v1(179.67,55.34)
  BOTTOM w0.102: UC1.BA26 92.46,44.17 92.46,40.48 90.32,38.35 90.32,37.21 90.58,36.96 90.58,33.7 91.15,33.13 v1(91.15,32.49) ; v1(76.86,14.64) 76.86,12.99 82.91,6.93 173.87,6.93 176.28,9.34 176.53,9.34 v1(176.94,9.75)
LPC_AD1: length 200.6
  TOP w0.102: v1(179.67,53.74) 179.29,54.12 U11.8 ; v1(76.18,14.64) v2(75.43,14.64)
  IN2 w0.127: v1(76.18,14.64) 76.18,18.12 85.58,27.53 86.58,27.53 89.18,30.13 89.18,31.62 89.58,32.02 90.22,32.02 90.73,32.53 90.73,32.91 v1(90.74,32.92) ; v1(176.35,9.75) 175.96,10.14 175.96,12.01 180.88,16.92 180.88,20.33 181.35,20.8 181.35,24.08 177.27,28.16 177.27,31.71 184.66,39.1 184.66,48.29 180.88,52.07 180.88,52.79 179.93,53.74 v1(179.67,53.74)
  BOTTOM w0.102: v1(76.18,14.64) 76.62,15.08 76.99,15.08 77.5,14.57 77.5,12.85 83.06,7.29 173.64,7.29 176.1,9.75 v1(176.35,9.75) ; v1(90.74,32.92) 90.22,33.44 90.22,36.82 90.01,37.04 90.01,38.38 92.26,40.64 92.26,43.93 92.07,44.11 92.07,44.31 92.17,44.41 92.17,44.71 91.97,44.91 UC1.AY28
LPC_AD2: length 193.4
  TOP w0.102: U11.7 179.11,53.72 179.56,53.27 179.81,53.27 v1(180.24,52.84) ; v1(77.94,14.76) 77.94,14.52 v2(78.34,14.13)
  IN2 w0.127: v1(77.94,14.76) 77.94,17.73 85.48,25.26 87.16,25.26 88.65,26.75 88.65,27.44 91.35,30.14 91.35,30.99 92.47,32.12 v1(92.47,32.81) ; v1(172.77,9.26) 174.22,10.71 175.08,10.71 175.58,11.21 175.58,12.16 180.46,17.04 180.46,24.43 176.89,28 176.89,31.87 184.28,39.26 184.28,48.13 180.49,51.92 180.49,52.58 v1(180.24,52.84)
  BOTTOM w0.102: v1(77.94,14.76) 77.94,12.91 83.21,7.64 171.15,7.64 v1(172.77,9.26) ; v1(92.47,32.81) 92.55,32.89 92.55,36.54 93.06,37.04 93.06,39.72 93.28,39.95 93.28,43.62 93.29,43.62 93.29,43.99 92.97,44.31 UC1.AY25
LPC_AD3: length 189.8
  TOP w0.102: U11.5 179.28,52.92 179.39,52.82 v1(179.59,52.82) ; v1(78.83,14.76) v2(79.45,14.76)
  IN2 w0.127: v1(94.39,32.86) 94.39,32.8 93.48,31.89 93.42,31.89 92.11,30.59 92.11,29.82 89.41,27.13 89.41,26.43 87.48,24.5 85.79,24.5 78.83,17.54 v1(78.83,14.76) ; v1(171.58,9.17) 171.58,9.33 179.69,17.44 179.69,24.12 176.12,27.69 176.12,32.18 183.52,39.58 183.52,47.75 179.59,51.68 v1(179.59,52.82)
  BOTTOM w0.102: UC1.AY23 94.07,44.33 94.39,44.01 94.39,43.99 94.42,43.96 94.42,43.36 94.48,43.3 94.48,42.57 94.13,42.22 94.13,40.92 94.72,40.34 94.72,33.19 v1(94.39,32.86) ; v1(171.58,9.17) 170.76,8.36 83.5,8.36 78.83,13.03 v1(78.83,14.76)
LPC_CLK0_EC: length 203.1
  TOP w0.102: v1(180.88,54.96) 180.88,55.07 R921.1 180.1,55.85 179.48,55.85 179.35,55.72 U11.12 ; v2(76.79,15.35) 76.93,15.21 v1(77.5,15.21)
  IN2 w0.127: v1(77.5,15.21) 77.5,17.82 85.32,25.64 87,25.64 88.27,26.91 88.27,27.6 90.97,30.3 90.97,31.15 92.05,32.24 v1(92.05,32.36) ; v1(176.46,8.93) 176.63,9.11 177.14,9.11 178.11,10.08 178.11,13.07 181.64,16.61 181.64,20.01 182.11,20.48 182.11,24.4 178.03,28.48 178.03,31.36 185.45,38.78 185.45,48.65 181.64,52.46 181.64,53.77 180.88,54.53 v1(180.88,54.96)
  BOTTOM w0.102: v1(77.5,15.21) 77.24,15.46 76.35,15.46 75.77,14.88 75.77,13.57 82.76,6.58 174.1,6.58 v1(176.46,8.93) ; UC1.BA25 92.97,40.08 92.74,39.84 92.74,38.5 RC78.1 RC77.2 92.62,36.9 92.05,36.33 v1(92.05,32.36)
LPC_CLK1: length 9.4
  BOTTOM w0.102: RC80.1 92.89,35.64 v2(92.89,36.45) 92.89,36.56 93.26,36.92 93.26,39.36 RC79.2 93.88,40.42 93.49,40.81 93.49,43.48 93.52,43.51 UC1.BA24
LPC_CLKRUN#: length 219.3
  TOP w0.102: v1(77.05,15.91) v2(77.05,16.91) ; R428.1 178.6,64.72 v1(178.41,64.53)
  IN2 w0.127: v1(178.41,64.53) 179.58,64.53 184.2,59.91 184.2,51.61 186.21,49.6 186.21,38.46 178.79,31.04 178.79,28.79 182.87,24.71 182.87,20.17 182.4,19.7 182.4,16.29 179.81,13.7 179.81,10.65 177.51,8.35 177.09,8.35 176.51,7.76 v1(176.46,7.76) ; v1(91.65,32.8) 91.63,32.78 91.63,32.36 90.58,31.31 90.58,30.46 86.15,26.03 85.16,26.03 77.05,17.92 v1(77.05,15.91)
  BOTTOM w0.102: UC1.AY26 92.56,44.77 92.56,44.51 92.73,44.34 92.73,44.07 92.67,44 92.67,40.33 90.64,38.31 90.64,37.29 90.99,36.95 90.99,33.79 91.65,33.13 v1(91.65,32.8) ; v1(77.05,15.91) 75.53,15.91 75.06,15.44 75.06,10.74 79.93,5.87 174.56,5.87 v1(176.46,7.76)
LPC_FRAME#: length 192.1
  TOP w0.102: U11.4 179.18,52.52 179.43,52.27 v1(180.05,52.27) ; v1(78.39,15.46) 78.39,16.07 v2(78.67,16.35)
  IN2 w0.127: v1(172.19,9.26) 172.19,9.4 180.08,17.29 180.08,24.27 176.51,27.84 176.51,32.03 183.9,39.42 183.9,47.91 180.05,51.76 v1(180.05,52.27) ; v1(78.39,15.46) 78.39,17.63 85.64,24.88 87.32,24.88 89.03,26.59 89.03,27.28 91.73,29.98 91.73,30.83 v1(93.69,32.8)
  BOTTOM w0.102: UC1.AY24 93.52,44.68 93.83,44.37 93.83,44.07 93.74,43.97 93.74,43.26 93.69,43.22 93.69,40.99 94.39,40.29 94.39,36.78 RC75.2 RC76.1 94.36,34.99 94.36,33.47 v1(93.69,32.8) ; v1(78.39,15.46) 78.39,12.97 83.35,8 171,8 172.19,9.19 v1(172.19,9.26)
LPC_PD#: length 4.3
  BOTTOM w0.102: UC1.AC1 v2(109.71,54.06) 110.64,54.06 RC112.2
LPC_RST#: length 198.5
  TOP w0.102: v1(180.88,56.13) 180.66,56.34 C833.1 179.47,56.34 179.24,56.12 U11.13 ; v1(75.72,15.46) v2(75.72,16.32)
  IN2 w0.127: v1(180.88,56.13) 180.88,55.62 181.32,55.17 181.32,54.62 182.02,53.92 182.02,52.7 185.83,48.89 185.83,38.62 178.41,31.2 178.41,28.63 182.49,24.56 182.49,20.33 182.02,19.86 182.02,16.45 179.38,13.81 179.38,10.79 177.32,8.73 176.91,8.73 176.53,8.35 v1(176.46,8.35) ; v1(90.2,32.59) 90.05,32.44 89.46,32.44 88.8,31.78 88.8,30.29 86.42,27.91 85.43,27.91 84.24,26.73 82.83,26.73 82.36,26.26 82.36,24.96 75.72,18.32 v1(75.72,15.46)
  BOTTOM w0.102: v1(75.72,15.46) 75.42,15.16 75.42,10.97 80.16,6.22 174.33,6.22 v1(176.46,8.35) ; v1(90.2,32.59) 90.2,32.96 89.7,33.46 RC94.2 CC13.1 89.5,35.67 RC93.1
LPC_RST#_R: length 8.2
  BOTTOM w0.102: RC93.2 89.5,38.31 91.44,40.25 v2(91.44,40.82) 91.44,43.87 91.87,44.31 UC1.AY27
LX1_APU: length 12.2
  TOP w0.102: v3(151.58,42.94) 151.12,43.4 v1(150.8,43.4)
  IN2 w1.016: 149.42,44.06 144.55,48.93 140.17,48.93
  vias: v1(139.41,49.24) v1(139.41,48.61) v1(150.22,43.53)
LX1_VGA: length 7.5
  BOTTOM w0.102: PR1034.1 v2(70.51,99.85)
  BOTTOM w0.889: 60.71,109.59 61.47,109.59 64.39,106.68 PQ1001.7
LX1_VGA_1: length 25.5
  BOTTOM w0.254: PL1001.2 71.99,106.37 72.48,105.88 72.48,100.74 70.96,99.22 v2(59.25,99.22) 56.29,99.22 PR1030.1
LX_1.35V: length 1.3
  TOP w0.102: v1(47.24,150.14) 47.24,151.15 v3(47.41,151.33)
  vias: v1(42.45,147.48) v1(42.7,148.05) v1(46.6,150.14) v1(46.54,149.51) v1(46.54,148.9) v1(46.54,148.3) v1(46.54,147.67) v1(46.86,147.1) v1(47.18,149.51) v1(47.18,148.9) v1(47.18,148.3) v1(47.18,147.67)
LX_1V: length 2.1
  TOP w0.102: v2(71.11,14.15) 71.11,14.55 70.64,15.02 PC603.2 ; v1(67.78,14.51) v3(67.78,13.61)
  vias: v1(67.15,14.51) v1(67.4,19.08) v1(67.46,15.14) v1(67.78,18.51) v1(68.04,19.08) v1(68.1,15.14) v1(68.42,14.51) v1(68.73,15.14) v1(69.05,14.51) v1(69.37,15.14) v1(69.69,14.51) v1(69.97,15.14) v1(70.32,14.51)
LX_3V:
  vias: v1(157.25,22.45) v1(157.25,21.81) v1(157.61,26) v1(157.61,25.42) v2(157.72,24.78)
LX_5V:
  vias: v1(164.18,21.87) v1(164.18,21.24) v1(166.3,26.62) v1(166.8,26.31) v2(166.09,24.94)
LX_CHG: length 11.3
  TOP w0.102: v1(133.84,16.25) v3(133.84,14.33)
  IN2 w0.762: 143.31,17.92 142.88,17.92 142.78,17.82 135.79,17.82 134.52,16.55
  vias: v1(133.84,16.83) v1(144.5,17.9) v1(145.09,17.9)
LX_DDR:
  vias: v1(35.33,109.57) v1(35.33,108.93) v1(35.33,108.3) v1(35.33,107.66) v1(35.33,107.03) v1(35.33,106.39) v1(35.91,109.89) v1(35.91,109.25) v1(35.91,108.62) v1(35.91,107.98) v1(35.91,107.35) v1(35.91,106.71) v1(35.91,106.08) v1(37.87,112.93) v1(38.25,112.49) v3(35.3,110.6)
LX_NB: length 14.6
  TOP w0.102: v1(136.93,35.81) v2(136.22,35.81)
  IN1 w1.016: 149.56,40.73 144.49,35.65 137.82,35.65
  vias: v1(136.93,35.22) v1(150.47,41.11) v1(151.03,41.31)
M0_MA0: length 30.5
  TOP w0.13: v1(57.58,128.27) 58.06,127.79 59.15,127.79 59.48,127.46 59.48,127.21 59.61,127.08 63.64,127.08 64.16,127.6 65.31,127.6 65.96,128.26 68.5,128.26 v2(70.22,129.98) 70.84,130.6 76.95,130.6 78.02,131.67 81.1,131.67 v1(81.17,131.6)
  BOTTOM w0.102: UV7.H4 57.18,128.67 v1(57.58,128.27)
  BOTTOM w0.127: UV1.K17 83.8,133.29 83.43,132.92 82.55,132.92 81.95,132.32 81.95,131.94 81.61,131.6 v1(81.17,131.6)
M0_MA1: length 33.6
  TOP w0.13: v1(82.85,130.37) 82.07,129.6 81.09,129.6 80.37,130.32 79.5,130.32 79.42,130.41 78.61,130.41 78.38,130.18 78.38,130.01 77.99,129.62 76.85,129.62 76.48,129.25 75.97,129.25 75.74,129.02 75.74,128.68 75.61,128.55 75.35,128.55 75.22,128.68 75.22,128.93 75.09,129.06 74.84,129.06 74.74,128.96 74.74,128.57 74.64,128.47 74.33,128.47 74.23,128.57 74.23,129.04 74.13,129.15 73.74,129.15 73.64,129.04 73.64,128.57 73.54,128.47 72.95,128.47 71.32,126.84 v2(70.11,126.84) 66.32,126.84 66.22,126.74 64.57,126.74 64.22,126.38 58.09,126.38 57.99,126.49 57.99,127.03 57.89,127.13 57.69,127.13 57.59,127.03 57.59,126.56 57.48,126.46 57.21,126.46 57.08,126.59 57.08,127.19 v1(57.22,127.33)
  BOTTOM w0.102: v1(82.85,130.37) 83.18,130.71 UV1.J20 ; UV7.H5 57.18,127.37 v1(57.22,127.33)
M0_MA2: length 29.2
  TOP w0.102: 79.91,127.6 80.07,127.76 80.73,127.76 80.79,127.82 81.36,127.82 81.79,128.25 81.91,128.25 v1(81.92,128.26)
  TOP w0.13: v1(56.78,123.47) 57.58,124.27 57.58,124.73 58.31,125.46 64.78,125.46 65.56,124.68 v2(66.28,124.68) 66.91,124.68 67.34,125.11 71.64,125.11 72.57,126.04 76.95,126.04 77.51,126.6 78.91,126.6 79.91,127.6
  BOTTOM w0.102: v1(81.92,128.26) 81.95,128.26 UV1.H23 ; v1(56.78,123.47) 57.16,123.09 UV7.H11
M0_MA3: length 28.9
  TOP w0.102: v1(81.2,128.2) 81.02,128.02 80.71,128.02 80.66,127.97 80.16,127.97
  TOP w0.13: v1(57.18,124.44) 56.64,124.44 56.54,124.54 56.54,125.09 57.14,125.69 65.06,125.69 65.7,125.05 66.78,125.05 67.19,125.47 71.49,125.47 v2(71.9,125.87) 72.42,126.39 76.87,126.39 77.33,126.85 78.54,126.85 79.66,127.97 80.16,127.97
  BOTTOM w0.102: v1(81.2,128.2) 81.2,128.31 UV1.G23 ; v1(57.18,124.44) 57.18,124.44 UV7.H10
M0_MA4: length 29
  TOP w0.13: v1(58.38,123.47) 58.04,123.47 57.94,123.57 57.94,124.68 58.49,125.23 64.25,125.23 64.8,124.68 65.18,124.68 66.08,123.78 v2(68.29,123.78) 74.33,123.78 75.34,124.79 76.74,124.79 77.24,125.29 77.24,125.95 77.65,126.36 79.76,126.36 79.82,126.29 80.43,126.29 80.8,126.66 80.8,127.13 v1(81.11,127.44)
  BOTTOM w0.102: v1(81.11,127.44) 81.56,127.89 UV1.G24 ; v1(58.38,123.47) 58.76,123.09 UV7.K11
M0_MA5: length 27.8
  TOP w0.13: v1(59.06,124.47) 59.53,124.93 64.04,124.93 64.67,124.3 65.05,124.3 65.93,123.42 v2(70.44,123.42) 75.08,123.42 76.1,124.45 77.71,124.45 79.32,126.06 80.54,126.06 82.77,128.29 v1(82.78,128.29)
  BOTTOM w0.102: v1(59.06,124.47) 58.78,124.19 UV7.K10 ; UV1.H24 v1(82.78,128.29)
M0_MA6: length 29.5
  TOP w0.13: v1(58.92,127.33) 59.41,126.85 63.79,126.85 64.29,127.35 65.56,127.35 66.11,127.9 68.65,127.9 70.14,129.39 70.32,129.39 70.96,128.75 71.15,128.75 71.33,128.93 71.33,129.11 70.69,129.76 70.69,129.94 70.99,130.24 v2(72.53,130.24) 76.91,130.24 78.05,131.38 80.46,131.38 80.67,131.16 82.27,131.16 v1(82.62,131.51)
  BOTTOM w0.102: UV7.K5 58.78,127.47 v1(58.92,127.33)
  BOTTOM w0.127: UV1.J19 83.18,132.07 v1(82.62,131.51)
M0_MA7: length 29
  TOP w0.13: v1(83.27,131.43) 82.71,131.98 81.6,131.98 81.59,131.99 80.62,131.99 80.55,131.92 79.92,131.92 79.76,132.08 78.11,132.08 77.1,131.08 76.74,131.08 76.61,130.95 v2(74.84,130.95) 68.78,130.95 68.61,130.78 68.61,128.87 68.35,128.62 65.72,128.62 64.96,127.86 63.38,127.86 63.35,127.89 60.32,127.89 59.89,128.32 v1(59.12,128.32)
  BOTTOM w0.102: UV1.K19 83.93,132.09 v1(83.27,131.43) ; v1(59.12,128.32) 58.78,128.66 UV7.K4
M0_MA8: length 29.3
  TOP w0.13: v1(58.3,127.33) 58.3,127.12 58.8,126.62 63.88,126.62 64.36,127.09 65.81,127.09 65.94,127.22 v2(66.82,127.22) 71.19,127.22 72.06,128.09 72.06,129.75 72.19,129.88 72.45,129.88 72.58,129.75 72.58,129.02 72.67,128.94 73.02,128.94 73.1,129.02 73.1,129.75 73.23,129.88 73.66,129.88 73.79,129.75 73.79,129.63 73.92,129.5 74.18,129.5 74.31,129.63 74.31,129.75 74.44,129.88 76.47,129.88 76.6,130.01 77.13,130.01 77.65,130.52 78.38,130.52 78.5,130.64 79.51,130.64 79.6,130.55 80.54,130.55 80.68,130.7 v1(81.08,130.7)
  BOTTOM w0.102: UV1.G20 81.28,130.89 v1(81.08,130.7) ; v1(58.3,127.33) 57.98,127.65 UV7.J5
M1_MA0: length 32
  TOP w0.102: 78.82,133.98 79.18,133.98 79.34,134.14 80.76,134.14 80.9,134.28 81.85,134.28 v1(82.26,133.87)
  TOP w0.13: 78.82,133.98 76.96,133.98 76.26,133.29 69.42,133.29 v2(66.36,136.34) 65.88,136.82 65.88,139.1 64.06,140.91 58.96,140.91 v1(58.38,140.33)
  BOTTOM w0.102: v1(82.26,133.87) 82.82,134.42 82.82,134.66 83.18,135.02 UV1.J14 ; v1(58.38,140.33) 58.78,139.93 UV8.H4
M1_MA1: length 33.4
  TOP w0.102: v1(83.57,133.84) 83.57,134.15 83.24,134.49 80.79,134.49 80.65,134.34 79.39,134.34 79.15,134.59
  TOP w0.13: 79.15,134.59 78.39,134.59 78.07,134.9 76.67,134.9 75.41,133.64 v2(70.75,133.64) 69.56,133.64 66.24,136.97 66.24,139.25 64.29,141.19 60.87,141.19 60.35,141.71 59.32,141.71 v1(59,141.38)
  BOTTOM w0.102: UV8.H5 58.78,141.17 v1(59,141.38) ; v1(83.57,133.84) 83.57,134.75 83.79,134.97 83.79,135.5 UV1.K14
M1_MA2: length 32.3
  TOP w0.13: v1(82.02,138.51) 81.45,138.51 80.82,139.14 78.8,139.14 78.09,139.84 77.04,139.84 76.35,139.15 75.73,139.15 75.57,139.31 75.57,139.76 75.44,139.89 75.13,139.89 75,139.76 75,139.28 74.87,139.15 74.66,139.15 74.53,139.28 74.53,139.84 74.4,139.97 74.04,139.97 73.91,139.84 73.91,139.28 73.78,139.15 73.5,139.15 73.4,139.25 73.4,140.15 73.05,140.49 72.58,140.49 72.45,140.36 72.45,139.99 72.32,139.86 72.06,139.86 71.93,139.99 v2(71.93,140.16) 71.93,140.36 71.8,140.49 71.09,140.49 67.3,144.27 64.53,144.27 64.26,144.01 61.4,144.01 60.66,144.75 59.57,144.75 v1(59.18,145.13)
  BOTTOM w0.102: UV8.H11 58.78,145.53 v1(59.18,145.13) ; UV1.J11 82.76,138.51 v1(82.02,138.51)
M1_MA3: length 32.5
  TOP w0.102: 81.54,137.99 81.92,137.61 81.92,137.14 82.35,136.71 83.12,136.71 83.32,136.91 v1(83.32,137.52)
  TOP w0.13: 81.54,137.99 80.75,138.78 78.7,138.78 78.07,139.41 77.15,139.41 76.53,138.79 v2(74.17,138.79) 73.18,138.79 72.97,139.01 72.97,139.28 72.86,139.38 72.66,139.38 72.56,139.28 72.56,139.01 72.46,138.91 72.25,138.91 72.15,139.01 72.15,139.28 72.05,139.38 71.85,139.38 71.75,139.28 71.75,139.01 71.64,138.91 71.28,138.91 71.15,139.04 71.15,139.67 66.9,143.92 64.6,143.92 64.34,143.65 61.43,143.65 61.15,143.94 58.88,143.94 58.78,144.04 v1(58.78,144.17)
  BOTTOM w0.102: v1(58.78,144.17) 58.78,144.17 UV8.H10 ; v1(83.32,137.52) 83.18,137.39 UV1.J13
M1_MA4: length 34.5
  TOP w0.102: v1(82.36,136.25) 81.92,136.7 81.5,136.7 81.31,136.51 80.83,136.51 80.63,136.72 80.03,136.72 79.94,136.62 79.39,136.62 79.17,136.85 79.17,137.11 78.83,137.44
  TOP w0.13: 78.83,137.44 78.5,137.78 76.37,137.78 76.31,137.72 74.34,137.72 74.13,137.51 70.04,137.51 68.38,139.16 68.38,140.27 65.81,142.84 65.05,142.84 64.79,142.58 61.52,142.58 61,143.1 57.03,143.1 56.78,143.35 v1(56.78,145.13)
  BOTTOM w0.102: v1(82.36,136.25) 82.74,136.63 82.74,137.73 UV1.H11 ; UV8.K11 v1(56.78,145.13)
M1_MA5: length 32.2
  TOP w0.102: v1(81.53,137.46) 81.53,137.02 81.25,136.74 80.93,136.74 80.53,137.14 80.53,137.3 80.21,137.62 80.04,137.62
  TOP w0.13: v1(57.24,144.23) 57.24,143.58 57.34,143.48 57.64,143.48 v2(57.71,143.55) 57.71,144.19 57.81,144.3 58.01,144.3 58.12,144.19 58.12,143.58 58.34,143.35 61.08,143.35 61.49,142.93 64.64,142.93 64.9,143.2 66.22,143.2 68.94,140.48 68.94,139.11 70.16,137.89 74.01,137.89 74.2,138.08 79.07,138.08 79.53,137.62 80.04,137.62
  BOTTOM w0.102: UV1.G11 81.58,137.51 v1(81.53,137.46) ; v1(57.24,144.23) 57.18,144.29 UV8.K10
M1_MA6: length 34.6
  TOP w0.102: v1(83.03,136.32) 82.54,135.82 81.98,135.82 81.91,135.75 80.12,135.75 79.91,135.96
  TOP w0.13: v1(57.18,141.51) 58.31,142.63 60.81,142.63 61.33,142.11 65.4,142.11 67.67,139.84 67.67,138.32 v2(70.24,135.75) 70.91,135.08 74.81,135.08 76.42,136.68 78.7,136.68 79.42,135.96 79.91,135.96
  BOTTOM w0.102: UV1.J16 83.18,134.73 83.54,135.09 83.54,135.9 83.13,136.32 v1(83.03,136.32) ; UV8.K5 v1(57.18,141.51)
M1_MA7: length 35.7
  TOP w0.102: 78.9,136.12 79.4,135.62 79.96,135.62 80.07,135.51 82.58,135.51 82.86,135.79 83.3,135.79 v1(83.76,136.25)
  TOP w0.13: v1(56.82,140.33) 56.82,140.51 57.69,141.38 57.69,141.69 58.4,142.4 60.63,142.4 61.15,141.88 65.12,141.88 67.31,139.7 67.31,138.17 v2(68.56,136.92) 70.76,134.72 74.96,134.72 76.69,136.45 78.56,136.45 78.9,136.12
  BOTTOM w0.102: v1(56.82,140.33) 57.18,139.97 UV8.K4 ; v1(83.76,136.25) 84.02,136.25 84.78,135.49 UV1.L15
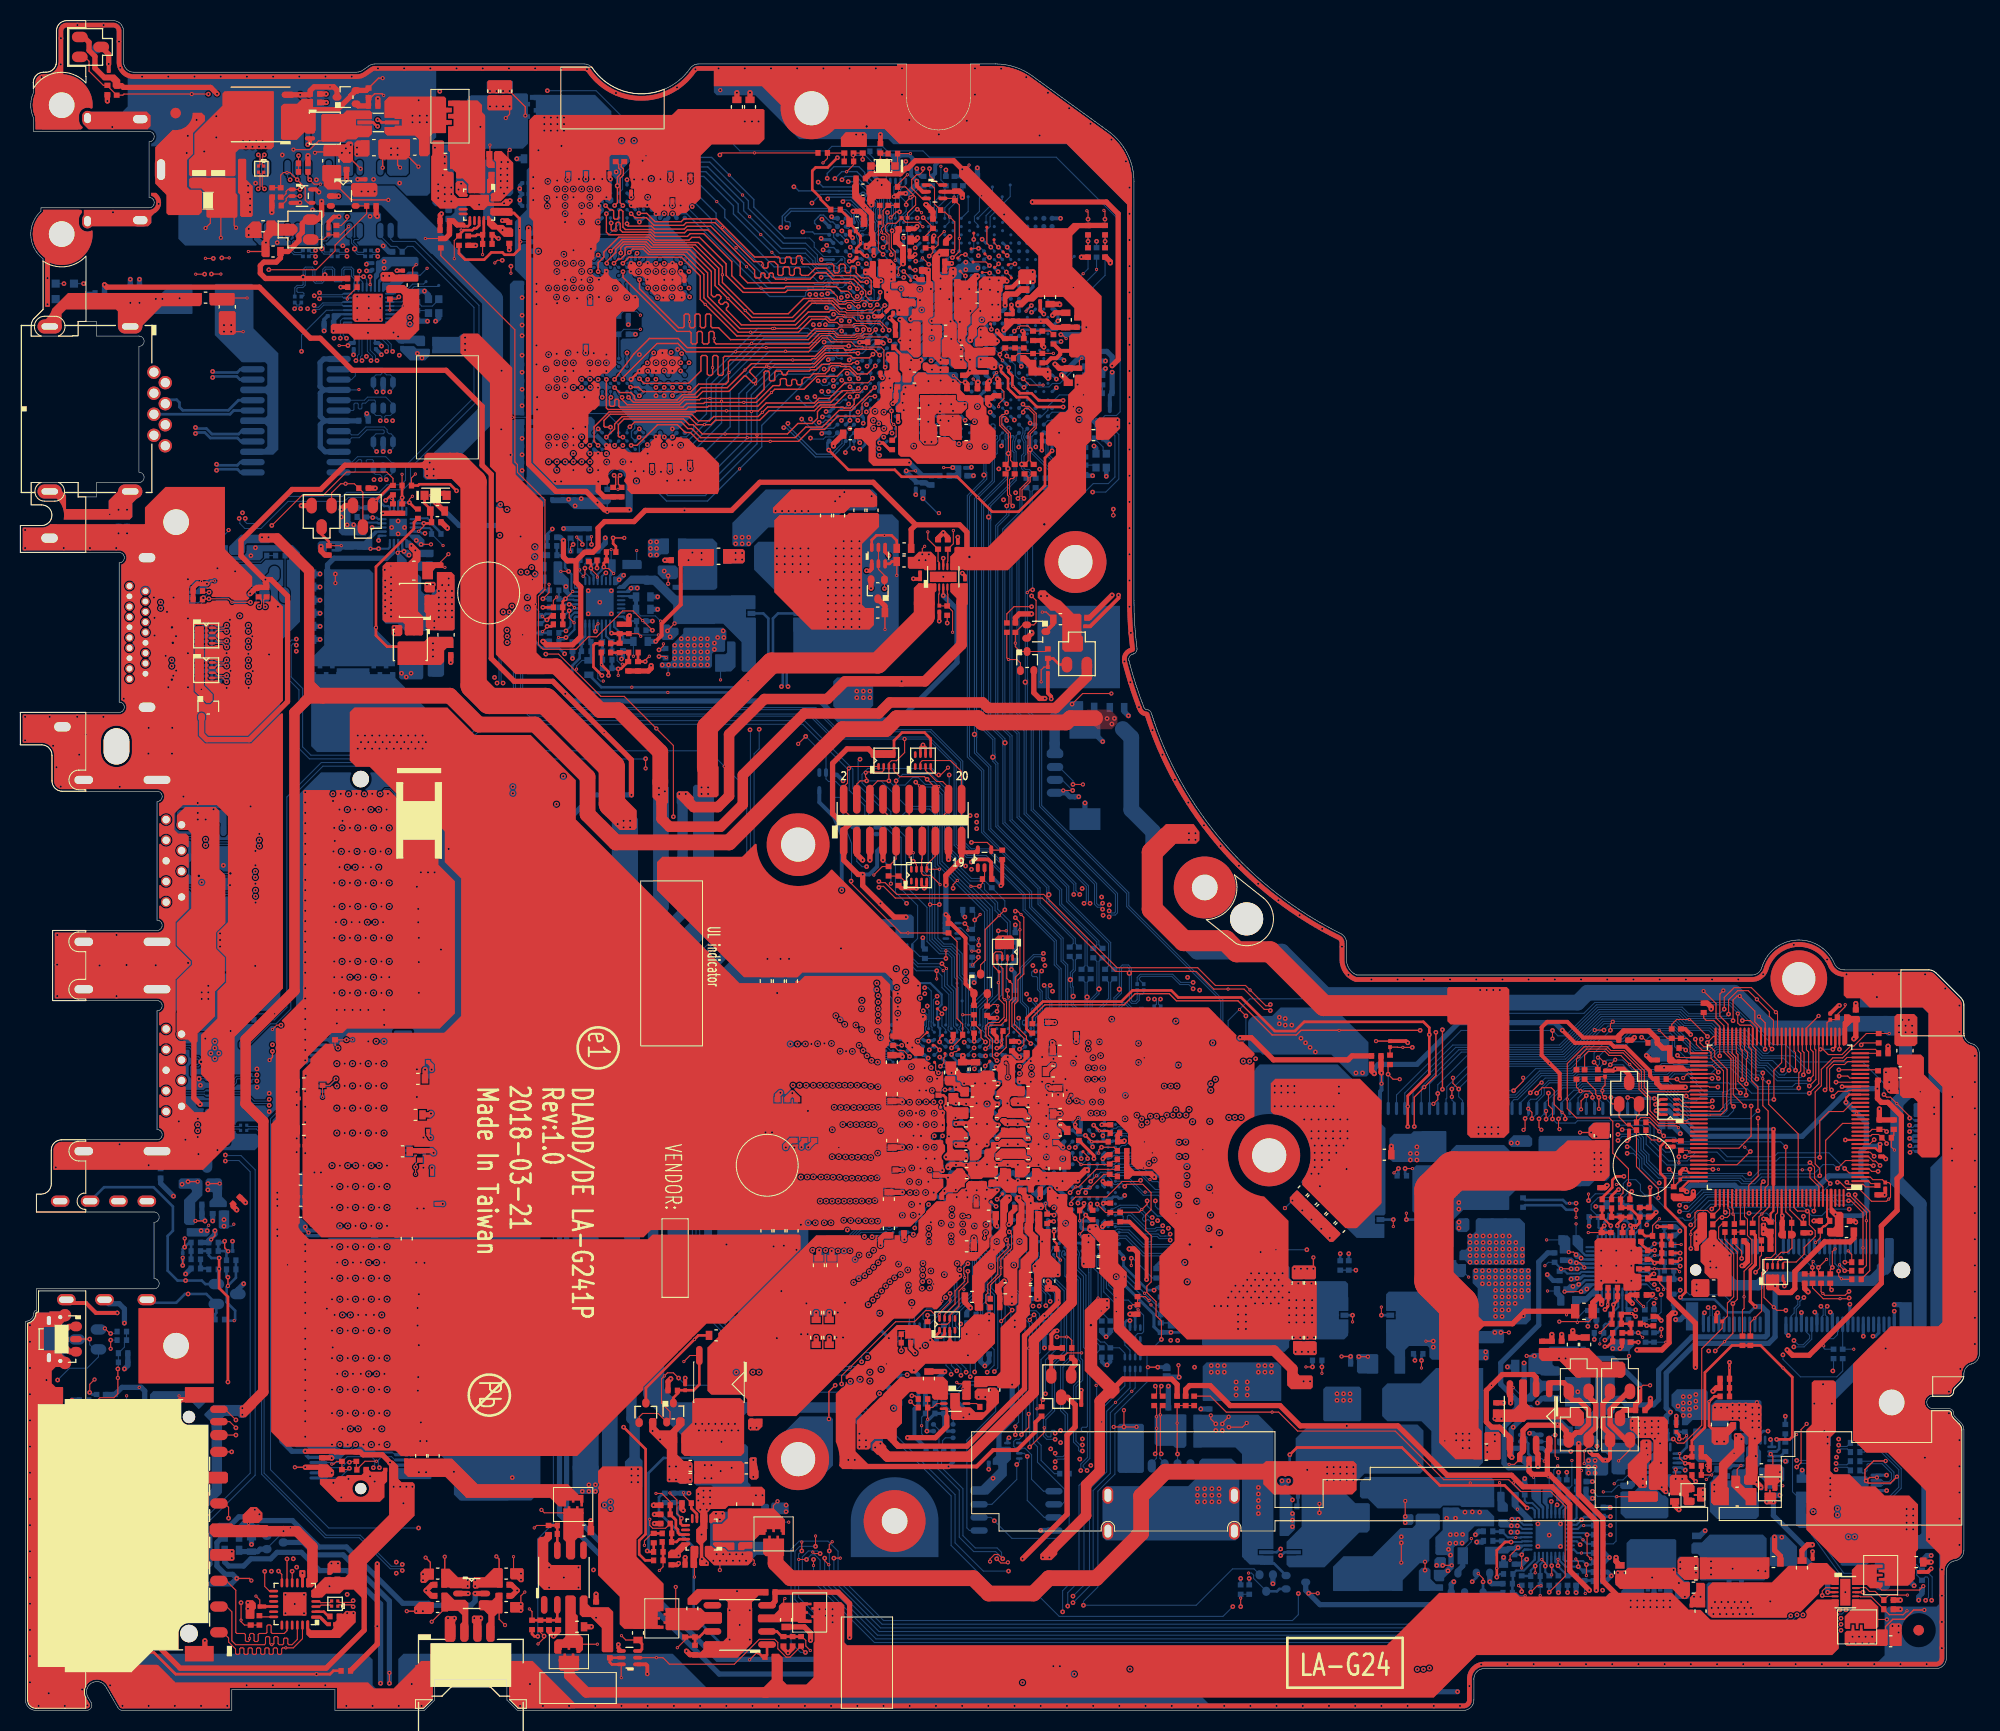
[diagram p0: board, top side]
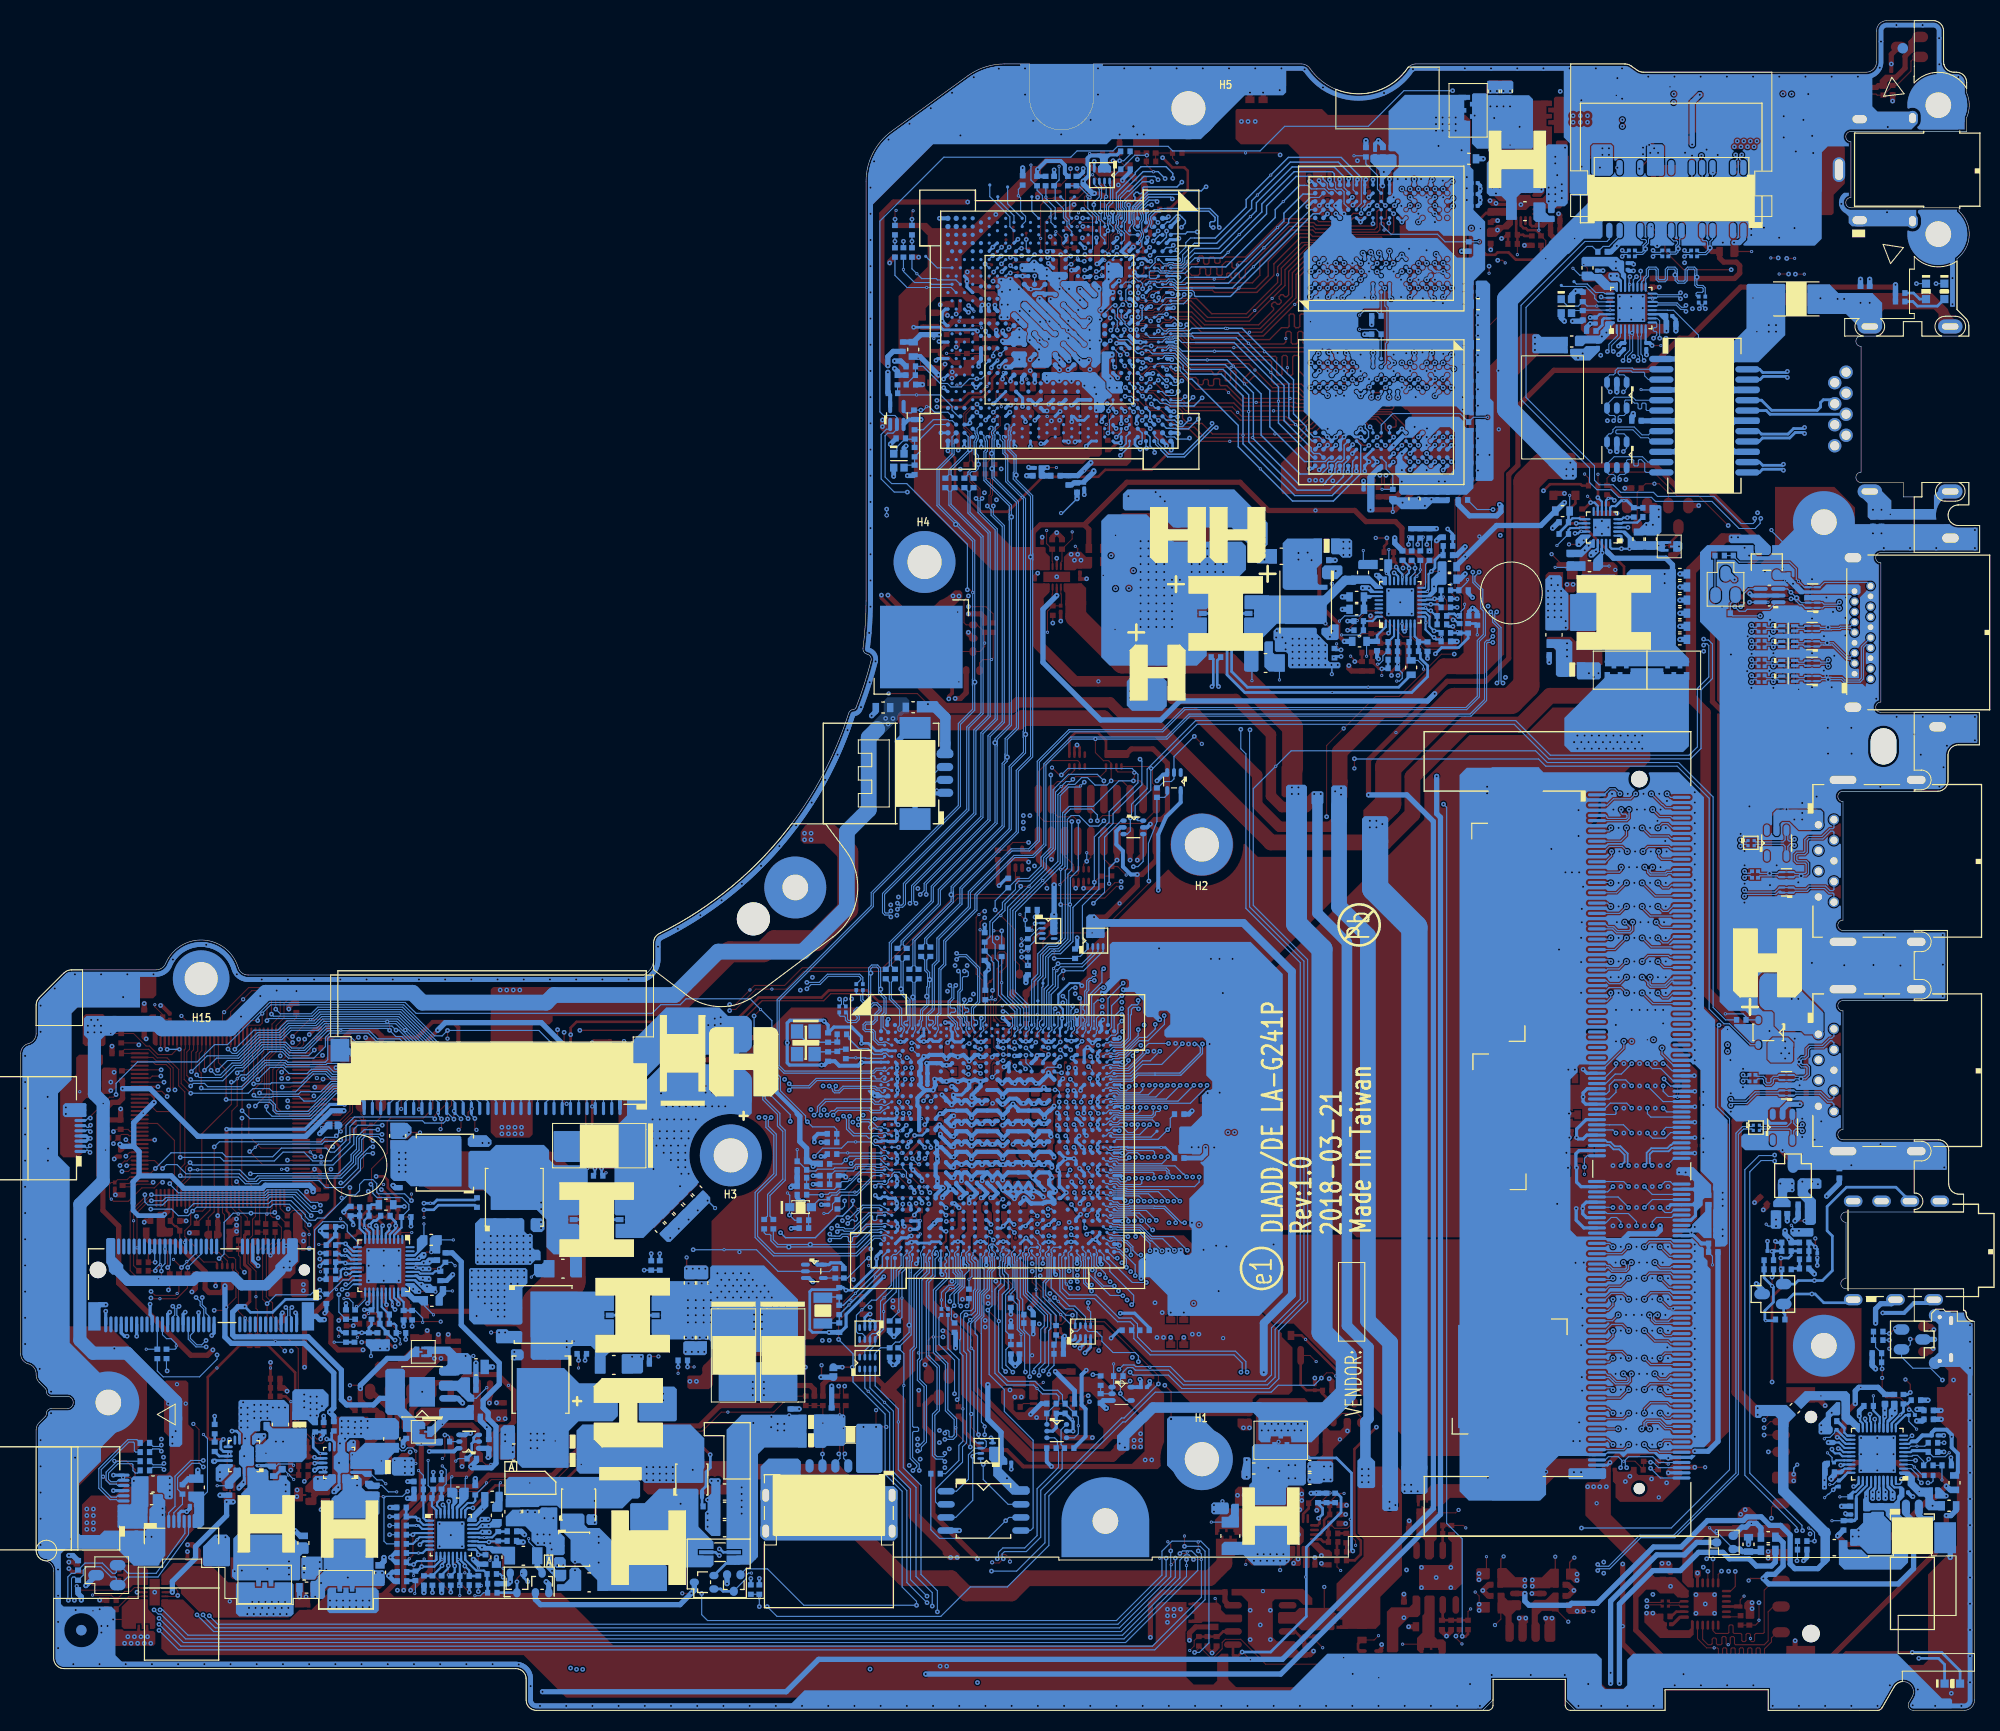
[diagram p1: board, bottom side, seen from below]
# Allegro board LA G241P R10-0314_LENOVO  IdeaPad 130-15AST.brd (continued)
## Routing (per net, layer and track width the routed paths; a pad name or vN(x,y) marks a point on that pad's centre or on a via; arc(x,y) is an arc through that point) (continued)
M1_MA8: length 32.3
  TOP w0.102: v1(81.55,135.11) 81.35,135.31 79.85,135.31 79.8,135.35 79.37,135.35 78.96,135.77 78.64,135.77
  TOP w0.13: 78.64,135.77 78.52,135.77 78.36,135.6 76.35,135.6 75.11,134.36 69.86,134.36 68.42,135.8 68.42,135.99 68.61,136.18 68.61,136.36 68.43,136.55 68.24,136.55 68.05,136.35 67.87,136.35 67.68,136.54 67.68,136.72 67.88,136.91 67.88,137.1 67.69,137.28 67.51,137.28 67.32,137.09 67.13,137.09 66.95,137.27 66.95,139.54 64.85,141.65 61.06,141.65 60.54,142.17 58.5,142.17 58.17,141.85 v1(58.17,141.33)
  BOTTOM w0.102: UV1.G14 81.55,135.66 v1(81.55,135.11) ; v1(58.17,141.33) 57.98,141.13 UV8.J5
M_ADBI0: length 31
  TOP w0.102: v1(84.24,132.82) 83.88,133.19 81.82,133.19 81.7,133.08 81.17,133.08 81.02,132.92 78.91,132.92 78.51,133.32 77.62,133.32 77.41,133.1
  TOP w0.13: v1(57.58,129.07) 59.46,131.55 60.95,133.04 63.72,133.04 64.61,132.15 v2(72.27,132.15) 76.45,132.15 77.41,133.1
  BOTTOM w0.102: UV7.J4 57.96,128.69 v1(57.58,129.07) ; v1(84.24,132.82) 84.58,132.49 UV1.L18
M_ADBI1: length 35
  TOP w0.102: 79.21,135.15 79.72,135.15 79.76,135.11 80.65,135.11 81.03,134.73 83.3,134.73 v1(84.19,133.84)
  TOP w0.13: v1(57.51,140.33) 57.93,140.75 58.18,140.75 58.59,141.16 58.59,141.81 58.72,141.94 60.44,141.94 60.96,141.42 64.57,141.42 66.59,139.4 66.59,137.12 69.71,134 v2(72.9,134) 75.26,134 76.42,135.16 78.14,135.16 78.48,134.82 78.87,134.82 79.21,135.15
  BOTTOM w0.102: UV1.K16 83.98,134.05 v1(84.19,133.84) ; v1(57.51,140.33) 57.92,139.93 UV8.J4
M_CAS#0: length 31.8
  TOP w0.13: v1(59.99,129.13) 60.44,128.68 61.41,128.68 61.42,128.69 63.82,128.69 63.83,128.7 64.75,128.7 65.94,129.89 65.94,131.26 66.07,131.39 66.43,131.39 66.56,131.26 66.56,129.59 66.69,129.46 66.95,129.46 67.08,129.59 v2(67.08,130.21) 67.08,131.26 67.21,131.39 67.47,131.39 67.6,131.26 67.6,129.59 67.73,129.46 67.98,129.46 68.11,129.59 68.11,131.18 68.24,131.31 77.01,131.31 78.01,132.31 v1(80.27,132.31)
  BOTTOM w0.102: v1(59.99,129.13) 59.62,129.49 UV7.L3 ; UV1.G19 81.19,132.09 80.97,132.31 v1(80.27,132.31)
M_CAS#1: length 34.8
  TOP w0.102: 79.78,136.36 79.97,136.36 80.12,136.51 80.52,136.51 80.9,136.13 v1(81.21,136.13)
  TOP w0.13: 79.78,136.36 79.34,136.36 78.79,136.91 75.89,136.91 74.41,135.43 71.06,135.43 68.03,138.47 v2(68.03,139.21) 68.03,139.99 65.68,142.34 61.43,142.34 60.91,142.86 57.98,142.86 56.54,141.43 56.54,140.94 55.98,140.37 v1(55.98,139.53)
  BOTTOM w0.102: UV8.L3 v1(55.98,139.53)
  BOTTOM w0.127: UV1.G16 81.16,134.91 81.16,136.08 v1(81.21,136.13)
M_CKE0: length 31.2
  TOP w0.102: 77.41,132.77 77.71,133.08 78.2,133.08 78.57,132.71 80.51,132.71 80.93,132.29 81.6,132.29 81.69,132.2 83.4,132.2 83.68,131.92 83.68,130.38 v1(83.8,130.25)
  TOP w0.13: 77.41,132.77 76.38,131.75 v2(69.31,131.75) 64.51,131.75 63.7,132.55 61.69,132.55 58.38,129.25 v1(58.38,129.07)
  BOTTOM w0.102: v1(58.38,129.07) 57.98,129.47 UV7.J3
  BOTTOM w0.127: v1(83.8,130.25) 83.98,130.43 UV1.K20
M_CKE1: length 34.7
  TOP w0.102: 77.3,133.37 77.45,133.52 78.8,133.52 79.16,133.15 80.94,133.15 81.07,133.28 81.57,133.28 81.77,133.47 82.46,133.47 v1(82.89,133.9)
  TOP w0.13: v1(58.39,139.52) 58.39,138.96 63.63,133.72 64.86,133.72 64.99,133.59 64.99,132.64 65.12,132.51 65.44,132.51 65.57,132.64 65.57,133.59 65.7,133.72 65.96,133.72 66.09,133.59 66.09,132.64 66.22,132.51 66.58,132.51 66.71,132.64 66.71,133.59 66.84,133.72 67.1,133.72 67.23,133.59 v2(67.23,133.04) 67.23,132.7 67.42,132.51 76.43,132.51 77.3,133.37
  BOTTOM w0.102: UV8.J3 58,139.13 v1(58.39,139.52)
  BOTTOM w0.127: UV1.J17 82.89,133.58 v1(82.89,133.9)
M_CLK0: length 32.9
  TOP w0.13: v1(58.11,119.77) 57.94,119.6 57.94,118.92 RV79.2
  IN1 w0.102: v1(58.38,122.67) 58.12,122.42 58.12,121.5 58,121.37 58,119.98
  IN1 w0.168: v1(58.11,119.77) 58,119.88 58,119.98
  IN2 w0.168: v1(58.38,122.67) 57.93,123.12 57.93,123.91 58.4,124.38 58.4,124.72 58.89,125.21 73.4,125.21 73.86,125.67 76.79,125.67 77.5,126.38 79.1,126.38 79.59,125.9 80.57,125.9 81.03,126.36 81.55,126.36 v1(81.98,125.92)
  BOTTOM w0.102: v1(81.98,125.92) 82.35,126.29 UV1.H26 ; UV7.J12 58,122.29 v1(58.38,122.67)
M_CLK1: length 36.4
  TOP w0.13: v1(57.58,145.93) 57.85,146.2 v4(57.85,147.85) 57.85,148.68 58.17,149 58.17,149.37 57.97,149.57 57.97,149.92 RV86.2
  IN2 w0.168: v1(81.18,140.29) 81.23,140.34 81.23,143.65 79.62,145.26 77.55,145.26 76.85,144.56 73.5,144.56 72.29,143.34 58.49,143.34 57.81,144.02 57.81,145.7 v1(57.58,145.93)
  BOTTOM w0.102: UV8.J12 v1(57.58,145.93) ; v1(81.18,140.29) UV1.G9
M_CLK#0: length 33.2
  TOP w0.13: RV80.2 57.68,118.85 57.68,119.62 v1(57.53,119.77)
  IN1 w0.102: 57.71,119.98 57.71,121.49 57.83,121.62 57.83,122.42 v1(57.58,122.67)
  IN1 w0.168: v1(57.53,119.77) 57.71,119.95 57.71,119.98
  IN2 w0.168: v1(57.58,122.67) 57.58,124.06 58.04,124.52 58.04,124.86 58.74,125.56 73.25,125.56 73.71,126.03 76.64,126.03 77.35,126.74 79.25,126.74 79.73,126.26 80.42,126.26 80.88,126.71 81.69,126.71 81.79,126.61 81.98,126.61 81.98,126.62 v1(82,126.62)
  BOTTOM w0.102: v1(82,126.62) 82,126.64 82.38,127.02 UV1.H25 ; UV7.J11 57.98,123.07 v1(57.58,122.67)
M_CLK#1: length 36.5
  TOP w0.13: v1(58.38,145.93) 58.11,146.2 58.11,148.57 58.43,148.89 58.43,149.48 58.22,149.68 58.22,149.91 RV85.2
  IN2 w0.168: v1(58.38,145.93) 58.17,145.72 58.17,144.17 58.64,143.7 72.14,143.7 73.35,144.91 76.7,144.91 77.4,145.62 79.76,145.62 81.59,143.79 81.59,140.68 v1(81.98,140.29)
  BOTTOM w0.102: UV8.J11 v1(58.38,145.93) ; v1(81.98,140.29) UV1.H9
M_CS0B#0: length 32.1
  TOP w0.102: v1(82.58,129.18) 82.13,128.74 79.9,128.74
  TOP w0.13: v1(55.98,122.67) 55.58,123.07 55.58,124.46 57.05,125.92 65.4,125.92 65.5,126.02 v2(68.42,126.02) 71.51,126.02 72.27,126.78 76.92,126.78 77.38,127.23 78.4,127.23 79.9,128.74
  BOTTOM w0.102: v1(55.98,122.67) 56.36,122.29 UV7.G12 ; UV1.H22 82.38,129.38 v1(82.58,129.18)
M_CS1B#0: length 34.2
  TOP w0.13: v1(82.3,137.46) 82.45,137.61 82.45,138.65 82.18,138.92 81.49,138.92 80.99,139.42 80.99,139.92 80.85,140.06 80.58,140.06 80.45,139.93 80.45,139.54 80.32,139.41 80.06,139.41 79.93,139.54 79.93,140.12 79.8,140.25 79.48,140.25 79.35,140.12 79.35,139.54 79.22,139.41 78.96,139.41 78.83,139.54 78.83,140.12 78.7,140.25 75.85,140.25 75.72,140.38 v2(75.72,140.62) 75.72,140.91 75.59,141.04 75.33,141.04 75.2,140.91 75.2,140.38 75.07,140.25 74.81,140.25 74.68,140.38 74.68,140.81 74.55,140.94 74.25,140.94 74.12,140.81 74.12,140.45 73.99,140.32 73.73,140.32 73.61,140.45 73.61,140.81 73.48,140.94 71.15,140.94 67.45,144.63 64.3,144.63 64.04,144.37 61.5,144.37 60.69,145.17 v1(59.93,145.17)
  BOTTOM w0.102: v1(59.93,145.17) 59.93,145.66 59.58,146.01 UV8.G12 ; UV1.G13 82.15,137.46 v1(82.3,137.46)
M_DA0: length 57.7
  IN2 w0.168: v1(84.47,123.86) 84.48,123.86 84.71,123.62 84.71,120.22 79.41,114.91 53.01,114.91 49.11,118.82 49.11,128.27 v1(50.93,130.09)
  BOTTOM w0.102: UV7.A2 51.13,130.29 v1(50.93,130.09) ; 84.33,124 84.33,125.14 UV1.K27
  BOTTOM w0.127: 84.33,124 v1(84.47,123.86)
M_DA1: length 55.7
  IN2 w0.168: v1(51.98,130.67) 51.98,130.47 49.62,128.11 49.62,118.98 53.21,115.39 79.21,115.39 84.24,120.42 84.24,122.89 v1(83.66,123.47)
  BOTTOM w0.102: v1(51.98,130.67) 52.36,130.29 UV7.B2
  BOTTOM w0.127: UV1.J29 83.18,123.95 83.66,123.47 v1(83.66,123.47)
M_DA2: length 51.3
  IN2 w0.168: v1(51.18,128.27) 51.18,125.86 50.13,124.81 50.13,119.14 53.41,115.86 59.09,115.86 59.46,116.24 72.42,116.24 72.8,115.86 79.02,115.86 83.77,120.61 83.77,121.81 83.36,122.22 83.35,122.22 v1(83.21,122.36)
  BOTTOM w0.102: UV7.A4 51.58,128.67 v1(51.18,128.27)
  BOTTOM w0.127: UV1.H30 82.38,123.86 82.71,123.53 82.71,122.83 83.18,122.36 v1(83.21,122.36)
M_DA3: length 48.7
  IN2 w0.168: v1(51.98,128.27) 51.98,125.99 50.64,124.65 50.64,119.3 53.57,116.37 58.34,116.37 58.99,117.02 60.77,117.02 61.06,116.74 79.21,116.74 83.26,120.79 v1(83.26,121.71)
  BOTTOM w0.102: v1(51.98,128.27) 52.38,128.67 UV7.B4
  BOTTOM w0.127: v1(83.26,121.71) 82.38,122.59 UV1.H32
M_DA4: length 45.8
  IN2 w0.102: v1(55.98,130.67) 55.6,130.29 55.6,128.43 55.6,128.43 55.6,122.48 55.82,122.25 56.14,122.25 56.36,122.03 56.36,121.71 56.58,121.49 57.03,121.49
  IN2 w0.168: v1(81.34,122.93) 81.34,123.67 81.13,123.88 80.71,123.88 80.56,123.73 80.56,123.34 80.41,123.18 80.1,123.18 79.95,123.34 79.95,123.73 79.8,123.88 79.49,123.88 79.34,123.73 79.34,123.34 79.19,123.18 78.88,123.18 78.73,123.34 78.73,123.67 78.58,123.82 78.26,123.82 78.04,123.6 78.04,122.64 77.63,122.23 77.21,122.23 77.06,122.38 77.06,122.8 76.91,122.95 76.6,122.95 76.45,122.8 76.45,122.38 76.3,122.23 76,122.23 75.84,122.38 75.84,123.11 75.69,123.26 75.39,123.26 75.23,123.11 75.23,122.38 75.08,122.23 74.78,122.23 74.62,122.38 74.62,123.11 74.47,123.26 74.17,123.26 74.01,123.11 74.01,122.28 73.69,121.95 72.8,121.95 72.31,121.46 59.38,121.46 59.35,121.49 57.03,121.49
  BOTTOM w0.102: UV7.F2 55.6,130.29 v1(55.98,130.67)
  BOTTOM w0.127: v1(81.34,122.93) 81.15,123.12 81.15,123.86 UV1.G29
M_DA5: length 43.3
  IN2 w0.102: 57.34,122.25 56.66,122.25 56.4,122.51 56.4,126.79 56.54,126.93 56.73,126.93 56.84,127.04 56.84,128.28 56.36,128.76 56.3,128.76 v1(55.98,129.07)
  IN2 w0.168: v1(80.37,124.29) 80.36,124.31 74.96,124.31 74.58,123.92 73.69,123.92 71.9,122.14 71.26,122.14 71.09,122.3 71.09,123.37 70.93,123.54 70.42,123.54 70.26,123.37 70.26,122.3 70.09,122.14 69.54,122.14 69.37,122.3 69.37,123.37 69.2,123.54 68.7,123.54 68.53,123.37 68.53,122.3 68.36,122.14 67.86,122.14 67.69,122.3 67.69,123.37 67.53,123.54 67.02,123.54 66.86,123.37 66.86,122.3 66.69,122.14 66.19,122.14 66.02,122.3 66.02,123.37 65.85,123.54 65.35,123.54 65.18,123.37 65.18,122.3 65.01,122.14 61.95,122.14 61.75,122.33 59.55,122.33 59.21,121.99 57.6,121.99 57.34,122.25
  BOTTOM w0.102: UV7.F4 55.6,128.69 v1(55.98,129.07)
  BOTTOM w0.127: UV1.F28 80.77,124.69 v1(80.37,124.29)
M_DA6: length 46.8
  IN2 w0.102: 54,120.88 54,123.63 54.05,123.68 54.05,128.08 54,128.13 54,128.69 v1(54.38,129.07)
  IN2 w0.168: v1(80.73,122.4) 80.73,121.74 80.02,121.04 78.38,121.04 78.23,120.89 78.23,119.34 78.08,119.19 77.77,119.19 77.62,119.34 77.62,120.87 77.45,121.04 77.04,121.04 76.82,120.82 76.82,119.34 76.67,119.19 76.36,119.19 76.21,119.34 76.21,120.89 76.06,121.04 75.7,121.04 75.53,120.87 75.53,119.36 75.36,119.19 65.66,119.19 65.12,119.73 63.58,119.73 63.54,119.69 61.05,119.69 61.01,119.73 59.27,119.73 58.88,119.33 56.44,119.33 56.11,119.66 55.12,119.66 54.59,120.19 54.59,120.28 54,120.88
  BOTTOM w0.102: v1(54.38,129.07) 54.76,128.69 UV7.E4
  BOTTOM w0.127: UV1.F32 80.78,122.43 80.74,122.39 80.74,122.4 v1(80.73,122.4)
M_DA7: length 45.8
  IN2 w0.102: 55.64,121.34 55.52,121.47 55.05,121.47 54.8,121.71 54.8,123.57 55.16,123.93 55.16,127.75 54.8,128.12 54.8,130.19 54.81,130.2 54.81,130.3 v1(55.18,130.67)
  IN2 w0.168: 55.64,121.34 56.47,120.52 59.23,120.52 59.55,120.84 65.09,120.84 66.27,119.66 71.37,119.66 71.54,119.83 71.54,120.82 71.7,120.99 72.21,120.99 72.37,120.82 72.37,119.83 72.54,119.66 72.99,119.66 73.18,119.86 73.18,121.32 73.31,121.44 73.93,121.44 74.05,121.32 74.05,119.83 74.22,119.66 74.72,119.66 74.89,119.83 74.89,121.38 75.06,121.55 79.52,121.55 v1(79.95,121.98)
  BOTTOM w0.102: v1(55.18,130.67) 54.8,130.29 UV7.E2
  BOTTOM w0.127: v1(79.95,121.98) 79.95,122.17 80.39,122.61 80.39,123.5 UV1.F30
M_DA8: length 28.3
  IN1 w0.168: v1(55.18,122.68) 55.27,122.77 55.27,123.41 55.46,123.6 56.16,123.6 56.54,123.98 58.7,123.98 59.97,122.71 59.97,122.08 60.61,121.44 63.32,121.44 64.48,122.6 71.8,122.6 72.19,122.2 75.06,122.2 76.23,123.38 v1(76.56,123.38)
  BOTTOM w0.102: v1(55.18,122.68) 55.58,123.07 UV7.F11 ; UV1.C30 78.78,123.49 78.02,123.49 77.82,123.28 76.66,123.28 v1(76.56,123.38)
M_DA9: length 38.8
  IN1 w0.168: v1(51.98,121.08) 52.08,121.08 53.43,119.73 53.43,117.79 55.11,116.11 58.26,116.11 58.38,115.99 63.74,115.99 65.96,118.2 76.76,118.2 80.36,121.81 80.36,122.18 80.31,122.22 80.31,123.43 81.15,124.27 v1(81.15,125.09)
  BOTTOM w0.102: UV7.B13 52.38,121.41 52.05,121.08 v1(51.98,121.08)
  BOTTOM w0.127: UV1.F27 81.15,125.12 v1(81.15,125.09)
M_DA10: length 28.8
  IN1 w0.168: v1(76.56,125.23) 76.56,124.37 74.86,122.68 72.39,122.68 70.18,124.88 55.86,124.88 55.01,124.04 55.01,123.46 54.38,122.84 v1(54.38,122.68)
  BOTTOM w0.102: UV7.E11 54.78,123.07 v1(54.38,122.68)
  BOTTOM w0.127: UV1.A28 77.88,124.69 77.69,124.51 77.24,124.51 76.56,125.19 v1(76.56,125.23)
M_DA11: length 32.1
  IN1 w0.168: v1(51.98,123.49) 51.91,123.56 51.91,124.36 52.92,125.38 70.35,125.38 72.58,123.15 74.67,123.15 75.71,124.19 v1(75.71,125.22)
  BOTTOM w0.102: UV7.B11 v1(51.98,123.49)
  BOTTOM w0.127: 76.12,124.81 76.66,124.28 77.84,124.28 77.88,124.32 78.53,124.32 78.54,124.33 78.8,124.33 79.16,124.69 UV1.C28
  BOTTOM w0.13: 76.12,124.81 v1(75.71,125.22)
M_DA12: length 35.4
  IN1 w0.102: v1(54.39,121.08) 54.39,120.9 54.18,120.68 54.18,119.98
  IN1 w0.168: v1(79.56,125.09) 79.56,122.14 78.98,121.55 78.98,121.09 76.85,118.97 65.96,118.97 64.31,117.31 62.04,117.31 61.59,116.87 55.6,116.87 54.18,118.29 54.18,119.98
  BOTTOM w0.102: UV1.E27 79.58,125.09 v1(79.56,125.09) ; v1(54.39,121.08) 54.39,121.1 UV7.E13
M_DA13: length 42.4
  IN1 w0.168: v1(81.16,125.9) 81.17,125.9 82.09,124.99 82.09,122.46 77.11,117.48 65.9,117.48 63.94,115.51 58.18,115.51 58.06,115.64 54.3,115.64 51.17,118.76 v1(51.17,121.08)
  BOTTOM w0.102: UV7.A13 51.58,121.49 51.18,121.09 51.18,121.08 v1(51.17,121.08)
  BOTTOM w0.13: v1(81.16,125.9) 81.2,125.9 UV1.G26
M_DA14: length 36.1
  IN1 w0.102: 54.65,119.98 54.65,120.5 55.19,121.04 v1(55.19,121.08)
  IN1 w0.168: v1(80.27,126.69) 80.27,126.38 79.11,125.22 79.11,124.98 79.21,124.88 79.21,122.44 76.74,119.97 66.3,119.97 64.5,118.18 62.24,118.18 61.46,117.4 55.76,117.4 54.65,118.51 54.65,119.98
  BOTTOM w0.102: UV7.F13 55.58,121.47 v1(55.19,121.08)
  BOTTOM w0.127: v1(80.27,126.69) 80.27,126.68 79.87,126.29 UV1.D26
M_DA15: length 35.4
  IN1 w0.168: v1(80.39,127.38) 80.06,127.05 79.42,127.05 79.36,126.99 76.51,126.99 75.09,125.58 75.09,124.24 74.47,123.62 72.78,123.62 70.52,125.88 52.22,125.88 51.18,124.84 v1(51.18,123.47)
  BOTTOM w0.102: v1(80.39,127.38) 80.49,127.38 UV1.F25 ; UV7.A11 51.56,123.09 v1(51.18,123.47)
M_DA16: length 22
  IN2 w0.168: v1(76.99,127.41) 76.99,126.87 76.82,126.7 73.43,126.7 72.97,126.24 61.14,126.24 60.48,126.9 60.48,128.77 v1(60.78,129.07)
  BOTTOM w0.102: v1(76.99,127.41) 77.37,127.03 78.32,127.03 UV1.A25 ; v1(60.78,129.07) 60.4,128.69 UV7.M4
M_DA17: length 17.3
  IN2 w0.152: v1(63.99,128.3) 63.99,127.49
  IN2 w0.168: v1(76.22,127.34) 76.18,127.34 75.76,127.75 73.14,127.75 72.74,127.35 64.13,127.35 63.99,127.49
  BOTTOM w0.102: v1(63.99,128.3) 63.97,128.3 UV7.T4 ; 77.89,126.78 78.51,126.78 78.81,127.09 UV1.C25
  BOTTOM w0.127: v1(76.22,127.34) 76.78,126.78 77.89,126.78
M_DA18: length 22.7
  IN2 w0.168: v1(61.58,129.09) 61.58,129.08 60.92,128.43 60.92,127.22 61.43,126.71 72.77,126.71 73.34,127.28 v1(75.34,127.28)
  BOTTOM w0.102: 78.42,126.49 78.45,126.52 78.87,126.75 79.39,126.75 79.74,127.09 UV1.E25 ; UV7.N4 v1(61.58,129.09)
  BOTTOM w0.127: 78.42,126.49 76.13,126.49 76.08,126.54
  BOTTOM w0.13: 76.08,126.54 v1(75.34,127.28)
M_DA19: length 16.2
  IN2 w0.168: v1(64.8,128.25) 65.13,127.92 72.64,127.92 72.95,128.22 75.96,128.22 76.27,127.91 v1(77.66,127.91)
  BOTTOM w0.102: UV1.D24 79.21,127.89 78.83,127.51 77.97,127.51 77.66,127.82 v1(77.66,127.91) ; v1(64.8,128.25) 64.38,128.67 UV7.U4
M_DA20: length 18
  IN2 w0.168: v1(79.59,128.99) 79.13,129.46 78.73,129.46 78.36,129.83 78.36,130.18 77.32,131.22 64.73,131.22 64.2,130.69 v1(63.99,130.69)
  BOTTOM w0.102: v1(63.99,130.69) 63.6,130.29 UV7.T2 ; UV1.E23 79.68,128.99 v1(79.59,128.99)
M_DA21: length 23.3
  IN2 w0.168: v1(80.35,129.12) 80.61,129.37 80.61,129.76 80.31,130.06 80.19,130.06 78.45,131.79 77.62,131.79 77,132.42 62.4,132.42 61.78,131.8 61.78,131.19 61.59,131 v1(61.59,130.69)
  BOTTOM w0.102: UV7.N2 61.2,130.29 v1(61.59,130.69) ; UV1.F23 v1(80.35,129.12)
M_DA22: length 16.3
  IN2 w0.168: v1(78.77,128.98) 78.74,129.01 78.62,129.01 78.19,129.44 77.5,129.44 76.19,130.75 64.86,130.75 v1(64.79,130.68)
  BOTTOM w0.102: v1(64.79,130.68) 64.4,130.29 UV7.U2
  BOTTOM w0.127: v1(78.77,128.98) 78.8,129.01 78.99,129.01 79.47,129.49 UV1.D22
M_DA23: length 24.6
  IN2 w0.168: v1(81.26,130.13) 80.74,130.13 80.47,130.4 80.23,130.4 78.35,132.27 77.52,132.27 76.91,132.89 61.39,132.89 60.74,132.24 v1(60.74,130.67)
  BOTTOM w0.102: v1(60.74,130.67) 60.38,130.31 UV7.M2
  BOTTOM w0.127: v1(81.26,130.13) 80.94,130.13 UV1.F21
M_DA24: length 31.5
  BOTTOM w0.102: UV1.E21 79.68,130.59 77.85,130.59 77.47,130.22 77.47,129.9 76.67,129.1
  BOTTOM w0.13: UV7.M11 59.97,122.68 59.97,119.91 62.61,117.28 66.58,117.28 v2(69.7,120.39) 71.84,122.54 71.84,124.61 76.33,129.1 76.67,129.1
M_DA25: length 30.2
  BOTTOM w0.102: 76.53,129.58 76.67,129.58 77.18,130.08 77.18,130.42 78.14,131.38 78.59,131.38 78.62,131.41 78.91,131.41 79.1,131.22 79.1,131.2 79.21,131.09 UV1.D20
  BOTTOM w0.13: 76.53,129.58 73.49,129.58 71.38,127.47 v2(71.38,123.65) 71.38,122.82 66.36,117.8 62.73,117.8 60.8,119.74 60.8,120.46 60.75,120.51 60.75,121.12 UV7.M13
M_DA26: length 30
  BOTTOM w0.102: 76.43,130.04 77.98,131.58 78.51,131.58 78.53,131.61 79,131.61 79.05,131.55 80.17,131.55 80.51,131.89 UV1.F19
  BOTTOM w0.13: UV7.N13 61.18,121.26 61.59,120.85 61.59,120.31 61.64,120.25 61.64,119.64 62.95,118.33 66.14,118.33 70.83,123.02 v2(70.83,125.95) 70.83,127.57 73.3,130.04 76.43,130.04
M_DA27: length 28.3
  BOTTOM w0.102: 76.36,130.5 76.55,130.5 77.94,131.89 UV1.A19
  BOTTOM w0.13: 76.36,130.5 73.11,130.5 v2(71.25,128.63) 70.37,127.76 70.37,123.31 65.92,118.86 63.58,118.86 63.32,119.12 63.32,119.2 62.47,120.05 62.47,120.43 62.39,120.51 62.39,120.89 62.18,121.09 61.8,121.09 61.57,121.32 61.57,122.7 UV7.N11
M_DA28: length 22.2
  BOTTOM w0.102: 76.02,132.64 77.3,132.64 77.72,133.07 78.04,133.07 78.13,132.98 78.59,132.98 78.61,132.99 78.91,132.99 79.21,132.69 UV1.D18
  BOTTOM w0.13: 76.02,132.64 72.23,132.64 67.94,128.36 v2(67.94,126.95) 67.94,124.84 64.59,121.49 UV7.U13
M_DA29: length 24.5
  BOTTOM w0.102: UV1.F17 80.41,133.12 79.07,133.12 78.99,133.2 78.52,133.2 78.51,133.18 78.21,133.18 78.12,133.27 76.29,133.27
  BOTTOM w0.127: 64.77,122.13 64.52,121.88 63.97,121.88 UV7.T13
  BOTTOM w0.13: 76.29,133.27 76.12,133.1 72.04,133.1 v2(68.68,129.74) 67.4,128.47 67.4,125.06 64.77,122.43 64.77,122.13
M_DA30: length 20.3
  BOTTOM w0.102: UV1.A17 76.37,133.49
  BOTTOM w0.127: 76.37,133.49 76.29,133.56 ; 64.67,123.09 UV7.U11
  BOTTOM w0.13: 76.29,133.56 71.84,133.56 v2(70.85,132.57) 66.94,128.66 66.94,125.36 64.67,123.09
M_DA31: length 22.5
  BOTTOM w0.102: UV1.C17 78.82,133.49 78.52,133.79 76.58,133.79 76.35,134.02 76.32,134.02
  BOTTOM w0.127: 65.04,124 64.53,123.49 63.99,123.49 UV7.T11 ; 65.88,125.13 66.48,125.73 66.48,129.04
  BOTTOM w0.13: 65.88,125.13 65.24,124.49 65.24,124.2 65.04,124 ; 76.32,134.02 v2(73.07,134.02) 71.47,134.02 66.48,129.04
M_DA32: length 26.2
  IN1 w0.102: 60.31,136.82 60.31,138.29 60.37,138.35 60.37,139.05 v1(59.9,139.52)
  IN1 w0.168: 60.31,136.82 60.31,136.48 64.12,132.66 70.78,132.66 71.4,132.05 77.87,132.05 v1(79.58,133.76)
  BOTTOM w0.102: UV1.E17 79.85,133.49 v1(79.58,133.76) ; UV8.F4 59.97,139.52 v1(59.9,139.52)
M_DA33: length 22.9
  IN1 w0.102: 62.68,136.82 62.68,137.18 62.36,137.5 62.24,137.5 61.96,137.78 61.96,139.15 v1(61.58,139.53)
  IN1 w0.168: 62.68,136.82 62.68,136.51 64.95,134.23 71.22,134.23 71.67,133.78 76.18,133.78 76.77,134.38 v1(76.84,134.38)
  BOTTOM w0.102: UV8.E4 61.18,139.93 v1(61.58,139.53) ; UV1.D16 79.56,134.29 79.04,133.77 78.83,133.77 78.6,134 77.13,134 76.96,134.17 76.96,134.26 v1(76.84,134.38)
M_DA34: length 24.5
  IN1 w0.168: v1(80.33,134.72) 79.81,134.21 78.79,134.21 77.27,132.68 71.43,132.68 70.89,133.22 64.24,133.22 60.78,136.68 v1(60.78,137.93)
  BOTTOM w0.102: UV1.F15 80.7,135.09 v1(80.33,134.72) ; UV8.F2 v1(60.78,137.93)
M_DA35: length 21.1
  IN1 w0.168: v1(61.58,137.92) 61.31,137.65 61.31,136.82 64.4,133.73 71.05,133.73 71.47,133.31 76.37,133.31 77.43,134.37 v1(77.43,134.38)
  BOTTOM w0.102: v1(61.58,137.92) 61.56,137.93 61.56,137.95 UV8.E2 ; UV1.A15 78.09,135.09 77.43,134.43 v1(77.43,134.38)
M_DA36: length 19.3
  IN1 w0.102: v1(63.17,139.52) 63.57,139.92 64.42,139.92 64.86,140.37 65.09,140.37
  IN1 w0.168: 65.09,140.37 73.39,140.37 76.44,137.31 v1(76.5,137.31)
  BOTTOM w0.102: v1(76.5,137.31) 76.54,137.27 76.54,137 77.14,136.4 78.28,136.4 78.36,136.32 79.16,136.32 UV1.D14 ; UV8.B4 63.18,139.52 v1(63.17,139.52)
M_DA37: length 19.1
  IN1 w0.168: v1(64.78,137.93) 65.25,138.4 72.86,138.4 75.25,136.01 77.23,136.01 77.77,136.55 80.52,136.55 v1(81.09,137.12)
  BOTTOM w0.102: UV8.A2 v1(64.78,137.93) ; UV1.F13 80.78,136.77 81.09,137.08 v1(81.09,137.12)
M_DA38: length 15.9
  IN1 w0.168: v1(77.08,137.31) 76.61,136.83 76.25,136.83 73.42,139.67 64.92,139.67 v1(64.78,139.53)
  BOTTOM w0.102: UV8.A4 v1(64.78,139.53) ; UV1.A13 77.74,136.69 77.53,136.89 77.4,136.89 77.08,137.21 v1(77.08,137.31)
M_DA39: length 17.7
  IN1 w0.168: v1(63.98,137.93) 64.92,138.87 73.06,138.87 75.45,136.48 76.84,136.48 v1(77.67,137.31)
  BOTTOM w0.102: v1(77.67,137.31) 77.98,136.99 78.88,136.99 UV1.C13 ; UV8.B2 v1(63.98,137.93)
M_DA40: length 20.6
  BOTTOM w0.102: 76.01,137.13 76.09,137.21 76.09,137.5 76.29,137.7 76.74,137.7 76.74,137.69 77.86,137.69 78.15,137.98 78.23,137.98 79.68,137.98 UV1.E11
  BOTTOM w0.13: 76.01,137.13 76,137.11 72.59,137.11 v2(71.77,137.93) 64.57,145.13 63.98,145.13 UV8.B11
M_DA41: length 17.3
  BOTTOM w0.102: 66.5,143.86 64.82,145.53 UV8.A11
  BOTTOM w0.127: 77.79,137.93 78.1,138.24 78.33,138.24 UV1.A11
  BOTTOM w0.13: 66.5,143.86 v2(70.37,139.99) 72.42,137.94 76.32,137.94 76.33,137.95 76.8,137.95 76.82,137.93 77.79,137.93
M_DA42: length 19.7
  BOTTOM w0.102: 64.85,146.71 64,146.71 UV8.B13 ; 76.86,138.4 76.98,138.28 77.83,138.28 78.01,138.46 78.12,138.46 78.26,138.59 78.51,138.59 78.81,138.29 UV1.C11
  BOTTOM w0.13: 64.85,146.71 66.95,144.61 66.95,144.23 v2(69.35,141.83) 72.79,138.4 76.86,138.4
M_DA43: length 20.9
  BOTTOM w0.102: UV8.A13 64.49,147.03 65.09,147.04 ; UV1.F11 80.48,138.59 79.86,138.59 79.76,138.49 79.46,138.49 79.36,138.59 78.8,138.59 78.59,138.8 78.07,138.8 77.75,138.48 77.35,138.48 76.86,138.97 76.08,138.97
  BOTTOM w0.13: 65.09,147.04 65.09,147.03 65.56,147.04 67.41,145.19 67.41,144.42 v2(68.03,143.8) 72.87,138.97 76.08,138.97
M_DA44: length 24.7
  BOTTOM w0.102: UV1.A9 77.28,139.89 76.8,140.37 76.8,140.58 76.08,141.3 ; 62.52,148.49 62.52,148.28 62.4,148.17 62.4,147.63 62.3,147.52 61.84,147.52 61.58,147.27 61.58,146.1 61.18,145.7 UV8.E11
  BOTTOM w0.13: 76.08,141.3 76.08,141.3 73.56,141.3 v2(71.75,143.11) 69.56,145.31 69.56,146.07 66.41,149.22 62.73,149.22 62.52,149 62.52,148.49
M_DA45: length 24.6
  BOTTOM w0.102: UV8.E13 61.18,147.27 61.58,147.66 61.58,148.49 ; 76.08,141.76 77.03,140.81 77.03,140.43 77.37,140.09 78.15,140.09 78.26,140.19 78.51,140.19 78.63,140.08 78.99,140.08 79.18,139.89 UV1.C9
  BOTTOM w0.13: 61.58,148.49 61.58,148.71 62.54,149.67 66.61,149.67 70.08,146.2 70.08,145.43 v2(70.67,144.85) 73.75,141.76 76.08,141.76
M_DA46: length 30.4
  BOTTOM w0.102: 76.08,142.78 76.48,142.78 76.93,142.33 76.93,141.89 77.82,140.99 79.71,140.99 79.89,140.82 79.89,140.81 79.9,140.8 79.9,140.4 80.41,139.89 UV1.F9 ; UV8.F11 60.38,145.66 59.91,146.13 59.91,148.31 59.88,148.34 59.88,148.49
  BOTTOM w0.13: 76.08,142.78 74.07,142.78 71.07,145.78 71.07,146.51 v2(68.7,148.89) 66.99,150.59 61.86,150.59 59.88,148.61 59.88,148.49
M_DA47: length 26.3
  BOTTOM w0.102: 60.7,148.49 60.7,147.45 UV8.F13 ; UV1.D8 79.49,140.69 79.08,140.28 78.71,140.28 78.59,140.4 78.17,140.4 78.07,140.29 77.45,140.29 77.23,140.52 77.23,141.14 76.1,142.27 76.08,142.27
  BOTTOM w0.13: 60.7,148.49 60.7,148.7 62.14,150.13 66.8,150.13 v2(69.98,146.95) 70.54,146.39 70.54,145.65 73.93,142.27 76.08,142.27
M_DA48: length 37.4
  IN2 w0.168: v1(51.17,137.92) 51.17,135.07 51.34,134.9 74.84,134.9 76.18,136.24 77.05,136.24 77.25,136.43 78.33,136.43 79.9,138.01 79.9,140.73 80.26,141.09 v1(80.39,141.09)
  BOTTOM w0.13: v1(80.39,141.09) 80.38,141.09 UV1.E7 ; v1(51.17,137.92) 51.58,138.33 UV8.U2
M_DA49: length 27.6
  IN2 w0.168: v1(55.22,137.93) 55.29,137.85 55.74,137.85 55.8,137.79 56.94,137.79 58.41,136.32 74.09,136.32 77.18,139.41 77.18,141 77.79,141.61 v1(77.79,141.63)
  BOTTOM w0.13: UV1.A7 77.92,141.49 v1(77.79,141.63) ; v1(55.22,137.93) 55.58,138.29 UV8.M2
M_DA50: length 32.6
  IN2 w0.168: v1(78.14,142.07) 78.55,141.66 78.55,138.3 78.29,138.04 76.64,138.04 74.45,135.85 55.2,135.85 54.44,136.61 54.44,137.88 v1(54.39,137.94)
  BOTTOM w0.13: v1(78.14,142.07) 78.35,141.86 78.81,141.86 UV1.C7 ; UV8.N2 v1(54.39,137.94)
M_DA51: length 35.5
  IN2 w0.168: v1(51.99,137.93) 52.43,137.49 52.43,136.74 53.61,135.57 54.76,135.57 54.95,135.38 74.65,135.38 75.93,136.66 76.74,136.66 76.97,136.89 78.41,136.89 79.34,137.83 79.34,140.81 80.42,141.89 v1(80.43,141.89)
  BOTTOM w0.13: v1(80.43,141.89) 80.45,141.89 80.78,141.56 UV1.F7 ; UV8.T2 52.38,138.27 52.04,137.93 v1(51.99,137.93)
M_DA52: length 27.6
  IN2 w0.168: v1(52.79,140.32) 52.8,140.33 52.8,140.38 52.94,140.53 52.94,140.65 53.45,141.16 55.35,141.16 56.19,141.99 74.18,141.99 75.56,143.37 v1(75.82,143.37)
  BOTTOM w0.13: UV1.A5 78.28,143.19 76.96,143.19 76.78,143.37 v1(75.82,143.37) ; v1(52.79,140.32) 52.4,139.93 UV8.T4
M_DA53: length 27.4
  IN2 w0.102: v1(55.24,139.56) 55.59,139.91 64.14,139.91
  IN2 w0.168: v1(79.6,143.47) 79.19,143.89 78.61,143.89 78.08,143.36 77.34,143.36 76.22,142.24 75.82,142.24 73.6,140.02 64.25,140.02 64.14,139.91
  BOTTOM w0.13: UV8.M4 55.58,139.9 v1(55.24,139.56) ; UV1.E5 v1(79.6,143.47)
M_DA54: length 29.1
  IN2 w0.168: v1(77.34,143.82) 77.34,143.74 76.46,142.86 75.77,142.86 74.03,141.13 60.17,141.13 59.88,140.84 56.5,140.84 55.99,140.33 55.1,140.33 54.72,139.95 54.72,139.87 v1(54.38,139.53)
  BOTTOM w0.13: v1(77.34,143.82) 76.96,144.2 76.96,144.46 77.27,144.77 77.27,144.77 77.5,145 77.83,145 78.06,144.77 78.06,144.76 78.49,144.34 78.73,144.34 UV1.C3 ; UV8.N4 v1(54.38,139.53)
M_DA55: length 31.3
  IN2 w0.102: 75.95,143.86 76.84,143.86 77.21,144.23 77.99,144.23 78.05,144.29 v1(79.63,144.29)
  IN2 w0.168: 75.95,143.86 75.16,143.86 73.76,142.46 52.66,142.46 51.99,141.79 51.99,140.34 v1(51.98,140.34)
  BOTTOM w0.13: UV8.U4 v1(51.98,140.34) ; v1(79.63,144.29) 79.63,144.33 UV1.E1
M_DA56: length 32.5
  IN2 w0.102: v1(55.17,145.94) 55.17,145.91 55.61,145.47 56.56,145.47 56.62,145.54 57.01,145.54 57.2,145.73 57.2,146.18 57.32,146.31 59.47,146.31 60.23,145.55 63.6,145.55 63.7,145.44 65.6,145.44 65.85,145.7
  IN2 w0.168: v1(80.24,145.99) 80.14,145.89 77.07,145.89 76.88,145.7 65.85,145.7
  BOTTOM w0.102: UV1.G7 81.58,141.55 81.18,141.95 81.18,142.59 81.02,142.87 81.02,143.2 81.2,143.54 81.2,144.28 81.03,144.53 81.03,145 81.18,145.34 81.18,145.44 80.63,145.99 v1(80.24,145.99) ; UV8.M11 v1(55.17,145.94)
M_DA57: length 33.9
  IN2 w0.102: 65.47,146.17 65.4,146.24 64.21,146.24 64.13,146.32 62.13,146.32 61.34,147.11 58.59,147.11 58.16,146.68 57.41,146.68 57.06,146.33 54.82,146.33 54.41,145.93 v1(54.38,145.93)
  IN2 w0.168: v1(76.71,146.17) 65.47,146.17
  BOTTOM w0.102: UV8.N11 v1(54.38,145.93) ; 81.86,145.37 81.87,145.36 81.87,145.33 81.94,145.26 81.94,144.59 81.87,144.44 81.87,144.12 82,143.93 82,143.76 81.73,143.48 81.4,143.48 81.23,143.18 81.23,142.95 81.41,142.64 UV1.G6
  BOTTOM w0.127: 81.86,145.37 81.86,145.72 80.96,146.62 80.96,146.63 80.58,147.01 77.55,147.01 v1(76.71,146.17)
M_DA58: length 31.7
  IN2 w0.102: v1(55.18,147.53) 55.59,147.13 57.07,147.13 57.31,146.88 58.08,146.88 58.51,147.32 61.42,147.32 62.11,146.63 64.86,146.63 64.91,146.68
  IN2 w0.168: v1(78.23,146.57) 78.24,146.56 78.88,146.56 79,146.68 79,147.18 78.83,147.35 78.26,147.35 77.59,146.68 64.91,146.68
  BOTTOM w0.102: UV1.G1 81.63,144.74 81.63,145.3 ; UV8.N13 v1(55.18,147.53)
  BOTTOM w0.127: 81.63,145.3 81.63,145.63 80.52,146.74 78.4,146.74 v1(78.23,146.57)
M_DA59: length 31.6
  IN2 w0.102: 64.59,147.19 62.01,147.19 61.67,147.53 v1(55.98,147.53)
  IN2 w0.152: 64.59,147.19 71.91,147.19
  IN2 w0.168: v1(79.71,146.31) 80.06,146.66 80.64,146.66 80.81,146.83 80.81,147.19 80.64,147.36 79.4,147.36 79.02,147.74 78.08,147.74 77.53,147.19 71.91,147.19
  BOTTOM w0.102: UV1.G3 81.58,143.96 81.4,144.15 81.4,144.35 81.23,144.58 81.23,144.94 81.4,145.32 81.4,145.53 ; UV8.M13 v1(55.98,147.53)
  BOTTOM w0.127: v1(79.71,146.31) 79.85,146.45 80.49,146.45 81.4,145.53
M_DA60: length 43.4
  IN2 w0.102: 51.5,148.49 51.5,148.32 51.91,147.91 52.14,147.91 52.52,147.53 v1(52.78,147.53)
  IN2 w0.168: 51.5,148.49 51.5,149.11 53.7,151.3 65.67,151.3 67.04,149.93 77.54,149.93 v1(78.93,148.54)
  BOTTOM w0.102: UV1.J6 82.88,142.59 82.88,143.21 82.88,143.22 82.88,143.23 83.11,143.46 83.19,143.46 83.52,143.79 83.52,143.99 83.45,144.06 83.45,144.52 83.49,144.56 83.49,144.82 83.3,145 83.3,145.42 83.46,145.58 83.46,146.82 83.12,147.16 ; UV8.T13 v1(52.78,147.53)
  BOTTOM w0.13: v1(78.93,148.54) 79.61,149.22 81.06,149.22 83.12,147.16
M_DA61: length 41.4
  IN2 w0.168: v1(51.98,147.53) 51.22,147.53 50.64,148.11 50.64,149.1 53.32,151.78 65.87,151.78 66.37,151.28 68.05,151.28 68.92,150.41 77.78,150.41 79.62,148.57 v1(79.62,148.43)
  BOTTOM w0.102: 82.6,147.33 83.25,146.67 83.25,145.66 83.1,145.51 83.1,144.77 UV1.J1 ; UV8.U13 v1(51.98,147.53)
  BOTTOM w0.13: 82.6,147.33 82.41,147.33 80.99,148.75 79.93,148.75 v1(79.62,148.43)
M_DA62: length 44.2
  IN2 w0.168: v1(80.22,148.24) 80.22,148.63 77.98,150.88 69.27,150.88 67.49,152.66 53.53,152.66 50.16,149.29 50.16,146.78 v1(51.06,145.88)
  BOTTOM w0.102: 81.12,148.24 83.05,146.31 83.05,145.74 82.88,145.57 82.88,144.56 83.01,144.43 83.01,144.39 83.11,144.29 83.11,143.96 UV1.J3 ; UV8.U11 51.41,145.53 v1(51.06,145.88)
  BOTTOM w0.13: 81.12,148.24 v1(80.22,148.24)
M_DA63: length 43.3
  IN2 w0.102: 52.62,148.49 52.62,148.32 53.16,147.77 53.16,146.27 52.82,145.93 v1(52.78,145.93)
  IN2 w0.168: v1(78.19,148.56) 77.51,149.24 77.29,149.46 66.75,149.46 65.38,150.83 54.18,150.83 52.62,149.27 52.62,148.49
  BOTTOM w0.102: UV8.T11 v1(52.78,145.93) ; 83.66,147.15 83.66,145.49 83.51,145.34 83.51,145.08 83.69,144.9 83.69,144.48 83.65,144.44 83.65,144.15 83.72,144.08 83.72,143.69 83.18,143.15 UV1.J5
  BOTTOM w0.13: 83.66,147.15 81.82,149 81.82,149.14 81.26,149.7 78.84,149.7 78.19,149.05 v1(78.19,148.56)
M_DBI0#: length 45.5
  IN2 w0.102: 54.02,120.13 54.02,120.37 53.74,120.65 53.47,120.65 53.17,120.96 53.17,123.64 53.16,123.65 53.16,128.41 53.2,128.45 53.2,130.29 v1(53.58,130.67)
  IN2 w0.152: 54.75,119.36 54.75,119.36 ; 54.02,120.13 54.02,120.09
  IN2 w0.168: v1(82.66,125.09) 82.66,125.01 81.88,124.23 81.88,122.23 78.37,118.72 61.69,118.72 61.62,118.78 57.56,118.78 57.5,118.72 55.39,118.72 54.75,119.36 ; 54.02,120.09 54.75,119.36
  BOTTOM w0.102: UV7.D2 53.96,130.29 v1(53.58,130.67)
  BOTTOM w0.127: v1(82.66,125.09) 82.64,125.09 82.64,125.23 UV1.H27
M_DBI1#: length 33.5
  IN1 w0.102: 76.08,122.36 76.99,123.27 76.99,125.13 77.3,125.44 v1(77.72,125.44) ; v1(53.58,121.08) 52.99,121.68 52.99,122.08 53.18,122.27 55.49,122.27 55.59,122.17 55.59,121.72 56.54,120.77 56.54,119.98
  IN1 w0.168: 56.54,119.98 56.54,119.75 57.14,119.16 58.64,119.16 59.02,119.54 59.02,120.24 59.65,120.87 63.59,120.87 64.45,121.73 75.25,121.73 75.88,122.36 76.08,122.36
  BOTTOM w0.102: UV7.D13 53.98,121.49 v1(53.58,121.08)
  BOTTOM w0.127: UV1.A27 77.77,125.49 v1(77.72,125.44)
M_DBI2#: length 18.8
  IN2 w0.102: 65.31,128.86 64.67,129.51 62.89,129.51 62.77,129.63 62.77,130.29 v1(62.37,130.68)
  IN2 w0.168: 65.31,128.86 76.3,128.86 76.77,128.4 v1(78.8,128.4)
  BOTTOM w0.102: UV7.P2 v1(62.37,130.68)
  BOTTOM w0.127: v1(78.8,128.4) 79.09,128.69 UV1.C23
M_DBI3#: length 25.7
  BOTTOM w0.102: 76.76,131.02 76.78,131.02 77.85,132.09 78.15,132.09 78.26,132.19 78.51,132.19 78.81,131.89 UV1.C19
  BOTTOM w0.13: 76.76,131.02 76.7,130.96 72.92,130.96 v2(72.32,130.36) 69.62,127.66 69.62,123.66 65.85,119.89 63.78,119.89 63.18,120.5 63.18,120.97 63.05,121.1 62.56,121.1 62.17,121.49 UV7.P13
M_DBI4#: length 20.7
  IN1 w0.102: 63.51,136.82 63.51,137.45 63.4,137.55 62.76,137.55 v1(62.38,137.93)
  IN1 w0.168: v1(79.56,134.77) 78.38,134.77 78.36,134.79 76.62,134.79 76.08,134.25 72.27,134.25 71.37,135.16 64.7,135.16 63.51,136.35 63.51,136.82
  BOTTOM w0.102: UV1.C15 79.24,135.09 v1(79.56,134.77) ; UV8.D2 v1(62.38,137.93)
M_DBI5#: length 23.4
  BOTTOM w0.102: 63.42,148.3 63.21,148.09 63.21,147.65 63.06,147.51 62.6,147.51 62.22,147.13 UV8.D13 ; 76.04,140.84 77.33,139.56 78.53,139.56 78.57,139.6 78.99,139.6 79.01,139.58 79.33,139.58 79.63,139.89 UV1.E9
  BOTTOM w0.13: 76.04,140.84 73.37,140.84 v2(72.82,141.39) 69.1,145.12 69.1,145.88 66.22,148.76 63.74,148.76 63.61,148.63 63.61,148.49 63.42,148.3
M_DBI6#: length 30.8
  IN2 w0.102: v1(53.59,137.94) 53.98,138.33 63.51,138.33
  IN2 w0.168: 63.51,138.33 63.53,138.34 64.98,138.34 65.12,138.21 74.75,138.21 76.6,140.05 76.6,141.12 77.97,142.49 v1(80.08,142.49)
  BOTTOM w0.102: UV8.P2 v1(53.59,137.94)
  BOTTOM w0.13: UV1.C5 79.46,143.09 79.61,142.94 79.61,142.94 79.83,142.72 79.83,142.72 80.07,142.48 80.07,142.49 v1(80.08,142.49)
M_DBI7#: length 31.9
  IN2 w0.102: v1(54.38,147.53) 54.76,147.91 63.22,147.91
  IN2 w0.152: 71.66,147.66 63.47,147.66
  IN2 w0.168: 71.66,147.66 74.87,147.66 v1(74.96,147.75) ; 63.47,147.66 63.22,147.91
  BOTTOM w0.102: 82.09,145.42 82.12,145.39 82.12,145.38 82.15,145.35 82.15,144.52 82.07,144.37 82.07,144.19 82.38,143.79 UV1.H4 ; UV8.P13 v1(54.38,147.53)
  BOTTOM w0.127: 79.33,147.35 80.56,147.35 82.09,145.82 82.09,145.42
  BOTTOM w0.13: 79.33,147.35 75.42,147.35 75.03,147.75 v1(74.96,147.75)
M_EDC_0: length 50.4
  IN2 w0.102: v1(52.78,130.67) 52.39,130.29 52.39,120.47
  IN2 w0.168: v1(82.69,124.31) 82.49,124.11 82.49,121.4 78.92,117.84 61.42,117.84 61.36,117.9 57.96,117.9 57.9,117.84 57.36,117.84 57.2,117.67 57.2,117.41 57.03,117.25 56.69,117.25 56.53,117.41 56.53,117.67 56.36,117.84 56.02,117.84 55.85,117.67 55.85,117.43 55.68,117.27 55.35,117.27 55.18,117.43 55.18,117.69 54.6,118.27 54.36,118.27 53.84,117.74 53.6,117.74 53.36,117.98 53.36,118.22 53.89,118.74 53.89,118.98 52.39,120.47
  BOTTOM w0.102: v1(52.78,130.67) 53.16,130.29 UV7.C2
  BOTTOM w0.127: v1(82.69,124.31) 82.38,124.62 UV1.H28
M_EDC_1: length 35.4
  IN1 w0.102: 55.53,119.98 55.59,120.04 55.59,120.74 55.65,120.81 55.65,121.19 55.38,121.47 55.06,121.47 54.64,121.89 v1(53.58,121.89) ; 65.09,120.01 65.06,119.98
  IN1 w0.168: 55.53,119.98 55.53,119 56.25,118.28 61.09,118.28 62.54,119.73 63.59,119.73 63.59,119.73 64.81,119.73 65.06,119.98 ; v1(77.41,124.9) 78.29,124.9 78.64,124.54 78.64,123.16 76.34,120.85 65.93,120.85 65.09,120.01
  BOTTOM w0.102: UV7.C13 v1(53.58,121.89)
  BOTTOM w0.127: v1(77.41,124.9) 77.79,124.9 78.01,125.12 78.81,125.12 UV1.C27
M_EDC_2: length 16.8
  IN2 w0.102: v1(63.18,130.69) 63.58,130.29 64.52,130.29 64.8,130.01
  IN2 w0.168: 64.8,130.01 64.99,129.82 76.41,129.82 v1(77.31,128.93)
  BOTTOM w0.102: v1(77.31,128.93) 77.75,128.49 78.18,128.49 UV1.A23 ; UV7.R2 v1(63.18,130.69)
M_EDC_3: length 24.3
  BOTTOM w0.102: UV1.E19 79.68,132.19 78.8,132.19 78.59,132.4 78.17,132.4 78.07,132.29 77.75,132.29 77.26,131.8
  BOTTOM w0.13: 77.26,131.8 v2(74.15,131.8) 72.57,131.8 68.78,128.01 68.78,124.48 65.41,121.1 63.41,121.1 63.03,121.49 UV7.R13
M_EDC_4: length 19.9
  IN1 w0.102: 64.46,136.82 64.46,137.3 64.22,137.55 63.97,137.55 63.97,137.55 63.82,137.55 63.44,137.93 v1(63.18,137.93)
  IN1 w0.168: v1(78.8,135.39) 76.45,135.39 76.19,135.13 73.89,135.13 72.91,136.11 66.75,136.11 66.58,136.28 66.58,136.57 66.41,136.74 65.91,136.74 65.74,136.57 65.74,136.28 65.57,136.11 65.17,136.11 64.46,136.82
  BOTTOM w0.102: UV8.C2 v1(63.18,137.93) ; v1(78.8,135.39) 78.81,135.39 79.54,135.39 79.84,135.09 UV1.E15
M_EDC_5: length 23.6
  BOTTOM w0.102: UV8.C13 63.05,147.13 63.47,147.55 64.22,147.55 64.23,147.54 64.77,147.54 65.11,147.88 65.41,147.88 ; UV1.D10 79.8,138.87 80.36,138.87 80.46,138.97 80.46,139.48 80.36,139.58 79.61,139.58 79.41,139.38 78.92,139.38 78.91,139.39 78.66,139.39 78.62,139.36 77.01,139.36 76.38,139.98 76,139.98
  BOTTOM w0.13: 76,139.98 73.04,139.98 68.26,144.77 68.26,145.53 v2(67.48,146.31) 65.91,147.88 65.41,147.88 65.41,147.88
M_EDC_6: length 31.3
  IN2 w0.102: 76.08,141.17 77.01,142.1 77.01,142.7 77.44,143.12 78.48,143.12 78.79,143.44 v1(78.79,143.45) ; 65.09,139.14 65.08,139.12 53.28,139.12 53.18,139.02 53.18,138.33 v1(52.77,137.92)
  IN2 w0.168: 65.09,139.14 74.05,139.14 76.08,141.17
  BOTTOM w0.102: v1(52.77,137.92) UV8.R2
  BOTTOM w0.13: UV1.D6 79.38,142.29 78.8,142.87 78.8,143.45 v1(78.79,143.45)
M_EDC_7: length 38.1
  IN2 w0.102: 53.59,148.49 53.58,148.48 v1(53.58,147.53)
  IN2 w0.168: v1(77.31,148.2) 76.46,148.2 76.1,148.56 66.26,148.56 65,149.82 54.71,149.82 53.59,148.7 53.59,148.49
  BOTTOM w0.102: UV8.R13 v1(53.58,147.53) ; UV1.G5 82.41,143.09 82.88,143.55 82.88,144.23 82.8,144.3 82.8,144.35 82.67,144.48 82.67,145.66 82.85,145.83 82.85,146.16 82.8,146.21
  BOTTOM w0.127: 82.8,146.21 82.58,146.43
  BOTTOM w0.13: 82.58,146.43 82.29,146.43 82.23,146.36 82.04,146.36 81.85,146.55 81.85,146.74 81.98,146.87 81.98,147 81.76,147.22 81.57,147.22 81.44,147.08 81.26,147.08 81.07,147.27 81.07,147.45 81.11,147.48 81.11,147.62 80.99,147.73 77.78,147.73 v1(77.31,148.2)
M_RAS#0: length 30.5
  TOP w0.13: v1(81.22,129.14) 80.32,130.04 79.81,130.04 79.14,129.37 77.19,129.37 75.93,128.11 73.09,128.11 v2(72.78,127.8) 71.47,126.48 66.69,126.48 66.58,126.38 64.72,126.38 64.49,126.15 56.93,126.15 56.78,126.31 v1(56.78,129.07)
  BOTTOM w0.102: UV7.G3 56.38,129.47 v1(56.78,129.07)
  BOTTOM w0.127: v1(81.22,129.14) 81.22,129.33 UV1.G22
M_RAS#1: length 33.7
  TOP w0.102: v1(81.69,133.9) 81.69,133.73 81.44,133.48 80.98,133.48 80.86,133.36 79.25,133.36 78.88,133.72 77.14,133.72 77.03,133.61
  TOP w0.13: v1(59.99,138.74) 59.99,137.87 63.78,134.08 64.19,134.08 64.32,134.21 64.32,135.28 64.45,135.41 64.71,135.41 64.84,135.28 v2(64.84,134.66) 64.84,134.21 64.97,134.08 65.23,134.08 65.36,134.21 65.36,135.28 65.49,135.41 65.75,135.41 65.87,135.28 65.87,134.21 66,134.08 66.26,134.08 66.39,134.21 66.39,135.28 66.52,135.41 66.78,135.41 66.91,135.28 66.91,134.21 67.04,134.08 67.66,134.08 68.81,132.93 76.35,132.93 77.03,133.61
  BOTTOM w0.102: UV8.G3 59.6,139.13 v1(59.99,138.74) ; UV1.G17 81.68,133.39 81.68,133.9 v1(81.69,133.9)
M_WCKA0_0: length 36.9
  IN1 w0.168: v1(73.97,124.39) 73.97,124.49 73.96,124.56 71.97,126.56 71.15,126.56 70.77,126.94 70.77,127.81 70.6,127.98 70.1,127.98 69.93,127.81 69.93,126.93 69.55,126.56 68.77,126.56 68.38,126.94 68.38,127.82 68.21,127.99 67.71,127.99 67.54,127.82 67.54,126.93 67.17,126.56 66.22,126.56 65.84,126.93 65.84,127.31 65.67,127.48 65.17,127.48 65,127.31 65,126.93 64.63,126.56 54.22,126.56 53.8,126.97 53.8,128.05 53.58,128.27 v1(53.58,128.29)
  BOTTOM w0.102: v1(53.58,128.29) UV7.D4 ; UV1.E32 79.95,123.09 79.85,122.99 79.85,122.76 79.35,122.26 79.35,122.21 79.3,122.17
  BOTTOM w0.13: v1(73.97,124.39) 74.21,124.39 77.05,121.56 78.69,121.56 79.3,122.17
M_WCKA0_0#: length 36.9
  IN1 w0.168: v1(54.38,128.29) 54.16,128.07 54.16,127.12 54.36,126.91 64.48,126.91 64.65,127.08 64.65,127.46 65.02,127.84 65.82,127.84 66.2,127.46 66.2,127.08 66.36,126.91 67.02,126.91 67.19,127.08 67.19,127.97 67.56,128.35 68.36,128.35 68.74,127.97 68.74,127.09 68.91,126.91 69.41,126.91 69.57,127.08 69.57,127.96 69.95,128.34 70.75,128.34 71.12,127.96 71.12,127.09 71.3,126.91 72.12,126.91 74.23,124.8 v1(74.38,124.8)
  BOTTOM w0.102: 79.12,122.35 79.12,122.36 79.62,122.86 79.62,123.24 79.98,123.61 UV1.E30 ; v1(54.38,128.29) UV7.D5
  BOTTOM w0.13: 79.12,122.35 78.58,121.82 77.15,121.82 74.38,124.59 v1(74.38,124.8)
M_WCKA0_1: length 18.3
  IN1 w0.168: v1(77.88,130.07) 77.82,130.01 65.62,130.01 64.86,129.25 62.41,129.25 62.03,128.88 62.03,128.74 v1(61.58,128.29)
  BOTTOM w0.102: v1(61.58,128.29) UV7.P4
  BOTTOM w0.112: v1(77.88,130.07) 78.17,130.07 UV1.A21
M_WCKA0_1#: length 18.4
  IN1 w0.168: v1(78.78,130.01) 78.76,130 78.53,130 78.19,129.66 65.77,129.66 65.01,128.9 62.55,128.9 62.38,128.73 v1(62.38,128.29)
  BOTTOM w0.102: v1(62.38,128.29) UV7.P5
  BOTTOM w0.112: v1(78.78,130.01) 78.78,130.01 79.06,130.29 UV1.C21
M_WCKA1_0: length 24.4
  IN1 w0.168: v1(62.39,140.33) 62.15,140.33 61.93,140.55 61.93,141.25 62.07,141.38 74.19,141.38 75.7,139.87 78.74,139.87 79.61,138.99 79.61,137.84 79.47,137.7 79.13,137.7 78.96,137.53 78.96,137.17 79.13,137 v1(79.55,137)
  BOTTOM w0.102: UV8.D4 61.99,139.93 v1(62.39,140.33)
  BOTTOM w0.112: UV1.E13 79.85,136.55 79.69,136.55 79.48,136.76 79.48,136.94 v1(79.55,137)
M_WCKA1_0#: length 24
  IN1 w0.168: v1(80.15,137.14) 79.97,137.32 79.97,139.14 78.88,140.23 75.85,140.23 74.34,141.74 61.92,141.74 61.57,141.39 v1(61.57,140.32)
  BOTTOM w0.102: v1(61.57,140.32) UV8.D5
  BOTTOM w0.112: v1(80.15,137.14) 79.8,137.49 UV1.D12
M_WCKA1_1: length 33.2
  IN1 w0.168: v1(74.27,143.8) 74.15,143.68 74.15,143.24 73.74,142.84 55.28,142.84 54.45,142.01 54.45,141.18 54.13,140.86 54.13,140.55 54.36,140.32 v1(54.37,140.32)
  BOTTOM w0.102: UV1.E3 79.98,143.84 80.1,143.72 80.24,143.72 80.34,143.82 80.34,143.96 80.24,144.19 80.24,144.42 80.33,144.59 80.33,144.85 79.89,145.3 79.41,145.3 79.32,145.39 79.05,145.39 79.03,145.38 79.02,145.38 ; UV8.P4 v1(54.37,140.32)
  BOTTOM w0.13: v1(74.27,143.8) 74.47,143.8 74.6,143.92 74.6,144.25 74.48,144.37 74.2,144.37 74.09,144.48 74.09,144.78 74.68,145.38 79.02,145.38
M_WCKA1_1#: length 33.3
  IN1 w0.168: v1(53.58,140.33) 53.77,140.52 53.77,141.01 54.09,141.33 54.09,142.16 55.13,143.2 73.6,143.2 73.79,143.39 73.79,143.69 v1(73.68,143.8)
  BOTTOM w0.102: UV8.P5 v1(53.58,140.33) ; UV1.F4 80.6,143.85 80.43,144.22 80.43,144.37 80.54,144.55 80.54,144.98 79.99,145.53 79.51,145.53 79.4,145.64 79.02,145.64
  BOTTOM w0.13: 79.02,145.64 74.58,145.64 73.83,144.89 73.83,143.95 v1(73.68,143.8)
M_WE#0: length 29.4
  TOP w0.102: v1(82.81,127.43) 82.26,127.43 81.56,126.73 81.56,125.76 81.31,125.51 80.8,125.51
  TOP w0.13: 80.8,125.51 79.21,125.51 77.92,124.21 76.55,124.21 75.4,123.06 v2(72.66,123.06) 65.78,123.06 64.92,123.92 64.42,123.92 63.67,124.67 61.74,124.67 59.74,122.67 v1(59.18,122.67)
  BOTTOM w0.102: v1(59.18,122.67) 59.56,122.29 UV7.L12 ; v1(82.81,127.43) 82.21,127.43 81.87,127.09 UV1.G25
M_WE#1: length 33.8
  TOP w0.13: v1(81.1,137.85) 80.52,138.44 v2(80.42,138.44) 80.28,138.44 80.27,138.44 70.47,138.44 69.75,139.16 69.75,140.43 66.62,143.56 64.63,143.56 64.36,143.29 61.46,143.29 61.15,143.6 58.62,143.6 58.39,143.83 58.39,145.35 58.23,145.5 58.08,145.5 57.98,145.4 57.98,144.74 57.85,144.61 57.58,144.61 57.48,144.72 57.48,145.4 57.38,145.5 57.12,145.5 v1(56.7,145.92)
  BOTTOM w0.102: v1(81.1,137.85) 81.1,138.36 81.35,138.6 81.54,138.6 82.03,139.09 UV1.H10 ; v1(56.7,145.92) 56.38,146.24 UV8.L12
MCT: length 1.2
  TOP w0.102: v1(20.41,133.7) v2(21.57,133.7)
  vias: v1(19.71,134.33) v1(19.71,133.7) v1(20.41,134.33)
MEM_MA_ZVDDIO: length 6.8
  BOTTOM w0.15: 84.11,54.61 83.51,54.61 83.47,54.65 82.6,54.65
  BOTTOM w0.152: UC1.AB41 84.11,54.61
  BOTTOM w0.203: RC3.1 78.02,53.7 78.9,54.59 v2(79.31,54.59) 82.53,54.59 82.6,54.65
MODEL_ID#: length 19.6
  TOP w0.102: v2(109.39,39.76) 109.02,40.12 RC156.2 RC157.2 107.77,39.34 v1(107.53,39.1)
  IN1 w0.127: v1(107.53,39.1) 106.73,38.3 103.53,38.3 101.74,40.09 99.61,40.09 v1(98.73,39.21)
  BOTTOM w0.102: UC1.AY16 97.92,44.66 98.25,44.33 98.25,44.09 98.17,44 98.17,43.46 97.94,43.24 97.94,42.65 98.4,42.19 98.4,41.05 98.99,40.46 98.99,39.46 v1(98.73,39.21)
NOVO#: length 270.2
  TOP w0.102: U11.68 163.98,62.52 164.57,61.93 v1(164.57,61.89) ; v1(171.11,38.79) 170.24,38.79 v3(169.94,39.1) 169,40.04 169,42.37 169.33,42.7 RP4.8 ; SW1.2 v1(6.7,36.01)
  IN1 w0.127: v1(164.57,61.89) 165.2,61.26 165.2,60.08 164.91,59.79 164.91,57.96 168.3,54.57 168.3,51.15 172.28,47.17 172.28,41.09 171.11,39.92 v1(171.11,38.79) 170.33,38.02 170.33,31.53 172.43,29.43 172.43,25.56 173.38,24.6 173.38,20.82 172.81,20.25 172.81,13.19 166.95,7.33 139.19,7.33 135.98,4.12 v1(135.98,3.98)
  IN2 w0.127: v1(135.98,3.98) 135.57,4.4 109.01,4.4 108.36,5.05 95.72,5.05 94.01,3.33 61.88,3.33 61.11,4.09 54.45,4.09 52.67,5.87 15.36,5.87 12.37,8.86 8.41,8.86 5.17,12.1 3.84,12.1 1.7,14.23 1.7,28.88 3.58,30.76 v1(3.58,32.03)
  BOTTOM w0.102: v1(3.58,32.03) 4.73,33.18 6.44,33.18 7.55,34.28 D1.3 7.15,35.01 6.7,35.46 v1(6.7,36.01)
NUM_LED#: length 34.9
  TOP w0.102: v1(169.45,60.93) 169.45,58.77 172.3,55.91 U11.117 ; v1(152.52,62.86) 152.89,62.49 R277.1
  BOTTOM w0.102: v1(169.45,60.93) 169.19,60.93 v2(168.87,61.24) 168.49,61.63 167.97,61.63 165.72,63.87 164.54,63.87 163.91,63.24 161.46,63.24 160.33,64.37 160.33,65.26 159.91,65.68 156.19,65.68 155.4,64.89 153.66,64.89 152.52,63.75 v1(152.52,62.86)
NUM_LED#_R: length 4.3
  TOP w0.102: v1(153.57,59.44) 153.33,59.68 v3(153.33,60.09) 153.33,60.38 153.58,60.63 C275.1 153.11,61.45 R277.2
  BOTTOM w0.102: v1(153.57,59.44) 153.57,59.4 154.17,58.8 JKB1.29
ON/OFF#: length 28.6
  TOP w0.102: v1(171.1,54.64) U11.114 171.1,48.35 171.68,47.77 C837.1 171.68,46.16 J1.2 171.71,44.85 171.27,44.42 170.65,44.42 169.83,43.6 RP4.7 ; R283.1 157.95,57.03 v3(158.84,56.14) v1(159.27,55.71)
  BOTTOM w0.102: v1(171.1,54.64) 170.61,55.14 160.78,55.14 160.35,55.57 159.41,55.57 v1(159.27,55.71) 159.06,55.92 J2.2
OPCN_CHG: length 1.6
  BOTTOM w0.102: PC750.2 148.17,22.55 v2(148.07,22.65)
OPCP_CHG: length 1.5
  BOTTOM w0.102: v2(146.65,22.61) 146.78,22.48 PC750.1
P_ZVDDP: length 2.2
  TOP w0.102: v2(102.53,57.41) 102.22,57.1 v1(102.22,56.8)
  TOP w0.305: RC1.2 102.22,56.53 v1(102.22,56.8)
  BOTTOM w0.2: v1(102.22,56.8) 101.97,57.05 UC1.U8
P_ZVSS: length 3.9
  TOP w0.203: RC2.1 v2(103.82,55.15) v1(103.22,55.75)
  BOTTOM w0.203: v1(103.22,55.75) 102.48,55.75 UC1.W8
PBTN_OUT#: length 91.8
  TOP w0.102: v1(173.45,52.48) 173.45,51.66 174.3,50.8 U11.122
  IN1 w0.127: v1(154.84,55.86) 154.68,55.86 153.98,56.56 153.98,57.54 153.51,58.01 150.8,58.01 150.68,58.13 134.14,58.13 131.6,55.59 131.6,53.94 128.23,50.58 128.23,46.45 127.15,45.37 126.39,45.37 126.01,45.75 119.49,45.75 114.63,50.61 114.63,52.62 113.11,54.15 111.17,54.15 110.39,53.37 v1(109.88,53.37)
  BOTTOM w0.102: RC44.2 110.26,52.99 v1(109.88,53.37) 109.52,53.74 106.35,53.74 106.26,53.82 105.99,53.82 105.67,53.51 UC1.AD2 ; v1(154.84,55.86) 154.85,55.87 156.64,55.87 157.06,55.45 157.06,54.34 157.61,53.79 157.61,53.14 158.92,51.83 166.91,51.83 167.21,51.53 167.73,51.53 168.62,52.42 v2(172.71,52.42) 173.38,52.42 v1(173.45,52.48)
PC_BEEP: length 3.6
  BOTTOM w0.102: CA69.1 6.84,28.02 v2(6.09,27.27)
  BOTTOM w0.203: UA1.11 8.1,27.69 7.16,28.63 CA69.1
PCC_GPIO_6: length 4.5
  TOP w0.102: RV90.1 87.76,141.85 CV90.2 ; v2(89.52,143.4) 88.94,142.82 88.94,142.12 88.67,141.85 CV90.2 ; CV90.2 88.42,141.37 v1(88.07,141.03)
  BOTTOM w0.102: UV1.T8 88.24,141.03 v1(88.07,141.03)
PCIE_ARX_C_DTX_N0: length 14.6
  BOTTOM w0.102: UL2.18 32.75,138.51 32.55,138.7 32.55,138.89 32.29,139.15 32.29,139.74 32.07,139.96 31.35,139.96 31.13,139.74 31.13,138.84 31.03,138.74 30.55,138.74 30.44,138.84 30.44,139.74 30.23,139.96 29.51,139.96 29.29,139.74 29.29,139.53 29.26,139.5 29.26,138.93 29.29,138.9 29.29,138.75 29.14,138.6 28.65,138.6 28.53,138.72 28.53,139.71 28.28,139.96 27.6,139.96 27.38,139.74 v4(27.38,138.98) 27.38,138.28 27.28,138.18 26.8,138.18 26.57,137.95 CL12.1
PCIE_ARX_C_DTX_P0: length 14.6
  BOTTOM w0.102: UL2.17 32.35,138.81 32.08,139.07 32.08,139.65 31.98,139.76 31.44,139.76 31.33,139.65 31.33,138.76 31.11,138.54 30.46,138.54 30.24,138.76 30.24,139.66 30.14,139.76 29.59,139.76 29.49,139.65 v4(29.49,139.21) 29.49,138.66 29.23,138.4 28.56,138.4 28.32,138.64 28.32,139.63 28.2,139.76 27.69,139.76 27.59,139.65 27.59,139.29 27.61,139.26 27.61,138.7 27.59,138.67 27.59,138.2 27.37,137.98 26.88,137.98 26.77,137.87 26.77,137.61 26.88,137.51 27.36,137.51 27.46,137.41 27.46,137.2 27.36,137.1 CL11.1
PCIE_ARX_C_GTX_N0: length 5.2
  BOTTOM w0.102: UV1.AG31 97.63,123.53 97.75,123.53 97.82,123.47 97.82,122.1 99.68,120.24 99.68,119.83 CV2.1
PCIE_ARX_C_GTX_N1: length 6.2
  BOTTOM w0.102: CV4.1 97.84,119.83 97.84,119.98 97.69,120.13 97.31,120.13 97.03,120.41 v4(97.03,120.83) 97.03,121.69 97.24,121.9 97.24,122.96 97.03,123.36 97.03,123.6 97.16,123.88 97.16,124.31 UV1.AF28
PCIE_ARX_C_GTX_N2: length 7.5
  TOP w0.102: v1(97.16,126.67) 97.37,126.46 97.75,126.46 98.44,125.77 98.44,124.35 97.86,123.77 v4(97.86,122.26) 97.86,121.16 CV6.1
  BOTTOM w0.102: UV1.AF26 v1(97.16,126.67)
PCIE_ARX_C_GTX_N3: length 6.5
  TOP w0.102: CV8.1 95.75,121.1 v4(95.75,121.89) 95.75,123.75 94.91,124.59 94.91,125.42 95.16,125.67 95.36,125.67 v1(95.58,125.89)
  BOTTOM w0.102: v1(95.58,125.89) UV1.AD26
PCIE_ARX_C_GTX_P0: length 5.5
  BOTTOM w0.102: UV1.AH30 98.02,123.53 98.02,122.19 99.89,120.32 99.89,119.83 CV1.1
PCIE_ARX_C_GTX_P1: length 5.7
  BOTTOM w0.102: CV3.1 98.05,119.83 98.05,120.07 97.78,120.34 97.39,120.34 97.26,120.47 97.26,121.63 97.44,121.82 97.44,123.01 97.23,123.41 97.23,123.55 97.36,123.83 97.36,124.07 UV1.AG29
PCIE_ARX_C_GTX_P2: length 7.4
  TOP w0.102: v1(97.18,125.89) 97.18,126.08 97.36,126.26 97.67,126.26 98.24,125.69 98.24,124.44 97.65,123.85 97.65,122.65 97.63,122.62 97.63,121.96 97.65,121.94 97.65,121.16 CV5.1
  BOTTOM w0.102: UV1.AF27 v1(97.18,125.89)
PCIE_ARX_C_GTX_P3: length 6.4
  TOP w0.102: v1(95.58,125.09) 95.58,125.34 95.46,125.46 95.24,125.46 95.11,125.34 95.11,124.67 95.95,123.84 95.95,122.22 95.98,122.19 95.98,121.56 95.95,121.53 95.95,121.23 CV7.1
  BOTTOM w0.102: v1(95.58,125.09) UV1.AD27
PCIE_ARX_DTX_N0: length 149
  IN2 w0.127: v1(103.74,57.92) 103.74,57.94 104.03,58.23 104.03,58.33 104.29,58.59 104.95,58.59 105.31,58.95 105.31,59.66 107.16,61.51 108.12,61.51 108.86,62.24 108.86,67.55 108.03,68.37 108.03,71.87 107.07,72.83 107.07,85.32 96.55,95.84 85.92,95.84 84.96,94.88 78.11,94.88 76.82,93.59 55.04,93.59 52.67,95.96 51.23,95.96 43.77,103.43 43.77,113.21 40.72,116.25 40.72,128.08 35.94,132.86 32.46,132.86 30.62,134.7 27.21,134.7 26.56,135.35 v1(26.56,135.92)
  BOTTOM w0.102: CL12.2 26.79,136.3 26.79,136.15 v1(26.56,135.92) ; v1(103.74,57.92) 103.79,57.87 103.79,57.58 UC1.U5
PCIE_ARX_DTX_N2: length 99.6
  IN2 w0.127: v1(104.72,58.99) 104.44,59.27 104.44,59.56 104.16,59.84 103.55,59.84 103.19,59.48 103.19,58.57 103.02,58.41 103.02,57.62 103.47,57.18 106.29,57.18 108.08,58.97 116.39,58.97 117.07,59.65 119.52,59.65 120.86,60.99 135.15,60.99 136.73,62.57 138.95,62.57 139.52,63.14 151.27,63.14 152.92,61.49 156.22,61.49 156.98,60.73 158.15,60.73 162.84,56.04 163.67,56.04 166.72,53 166.72,44.93 168.86,42.78 168.86,36.75 170.01,35.61 171.53,35.61 v1(171.88,35.25)
  BOTTOM w0.102: UC1.R4 104.68,58.77 104.68,58.96 v1(104.72,58.99) ; v1(171.88,35.25) 172.87,35.25 173.62,36 JWLAN1.43
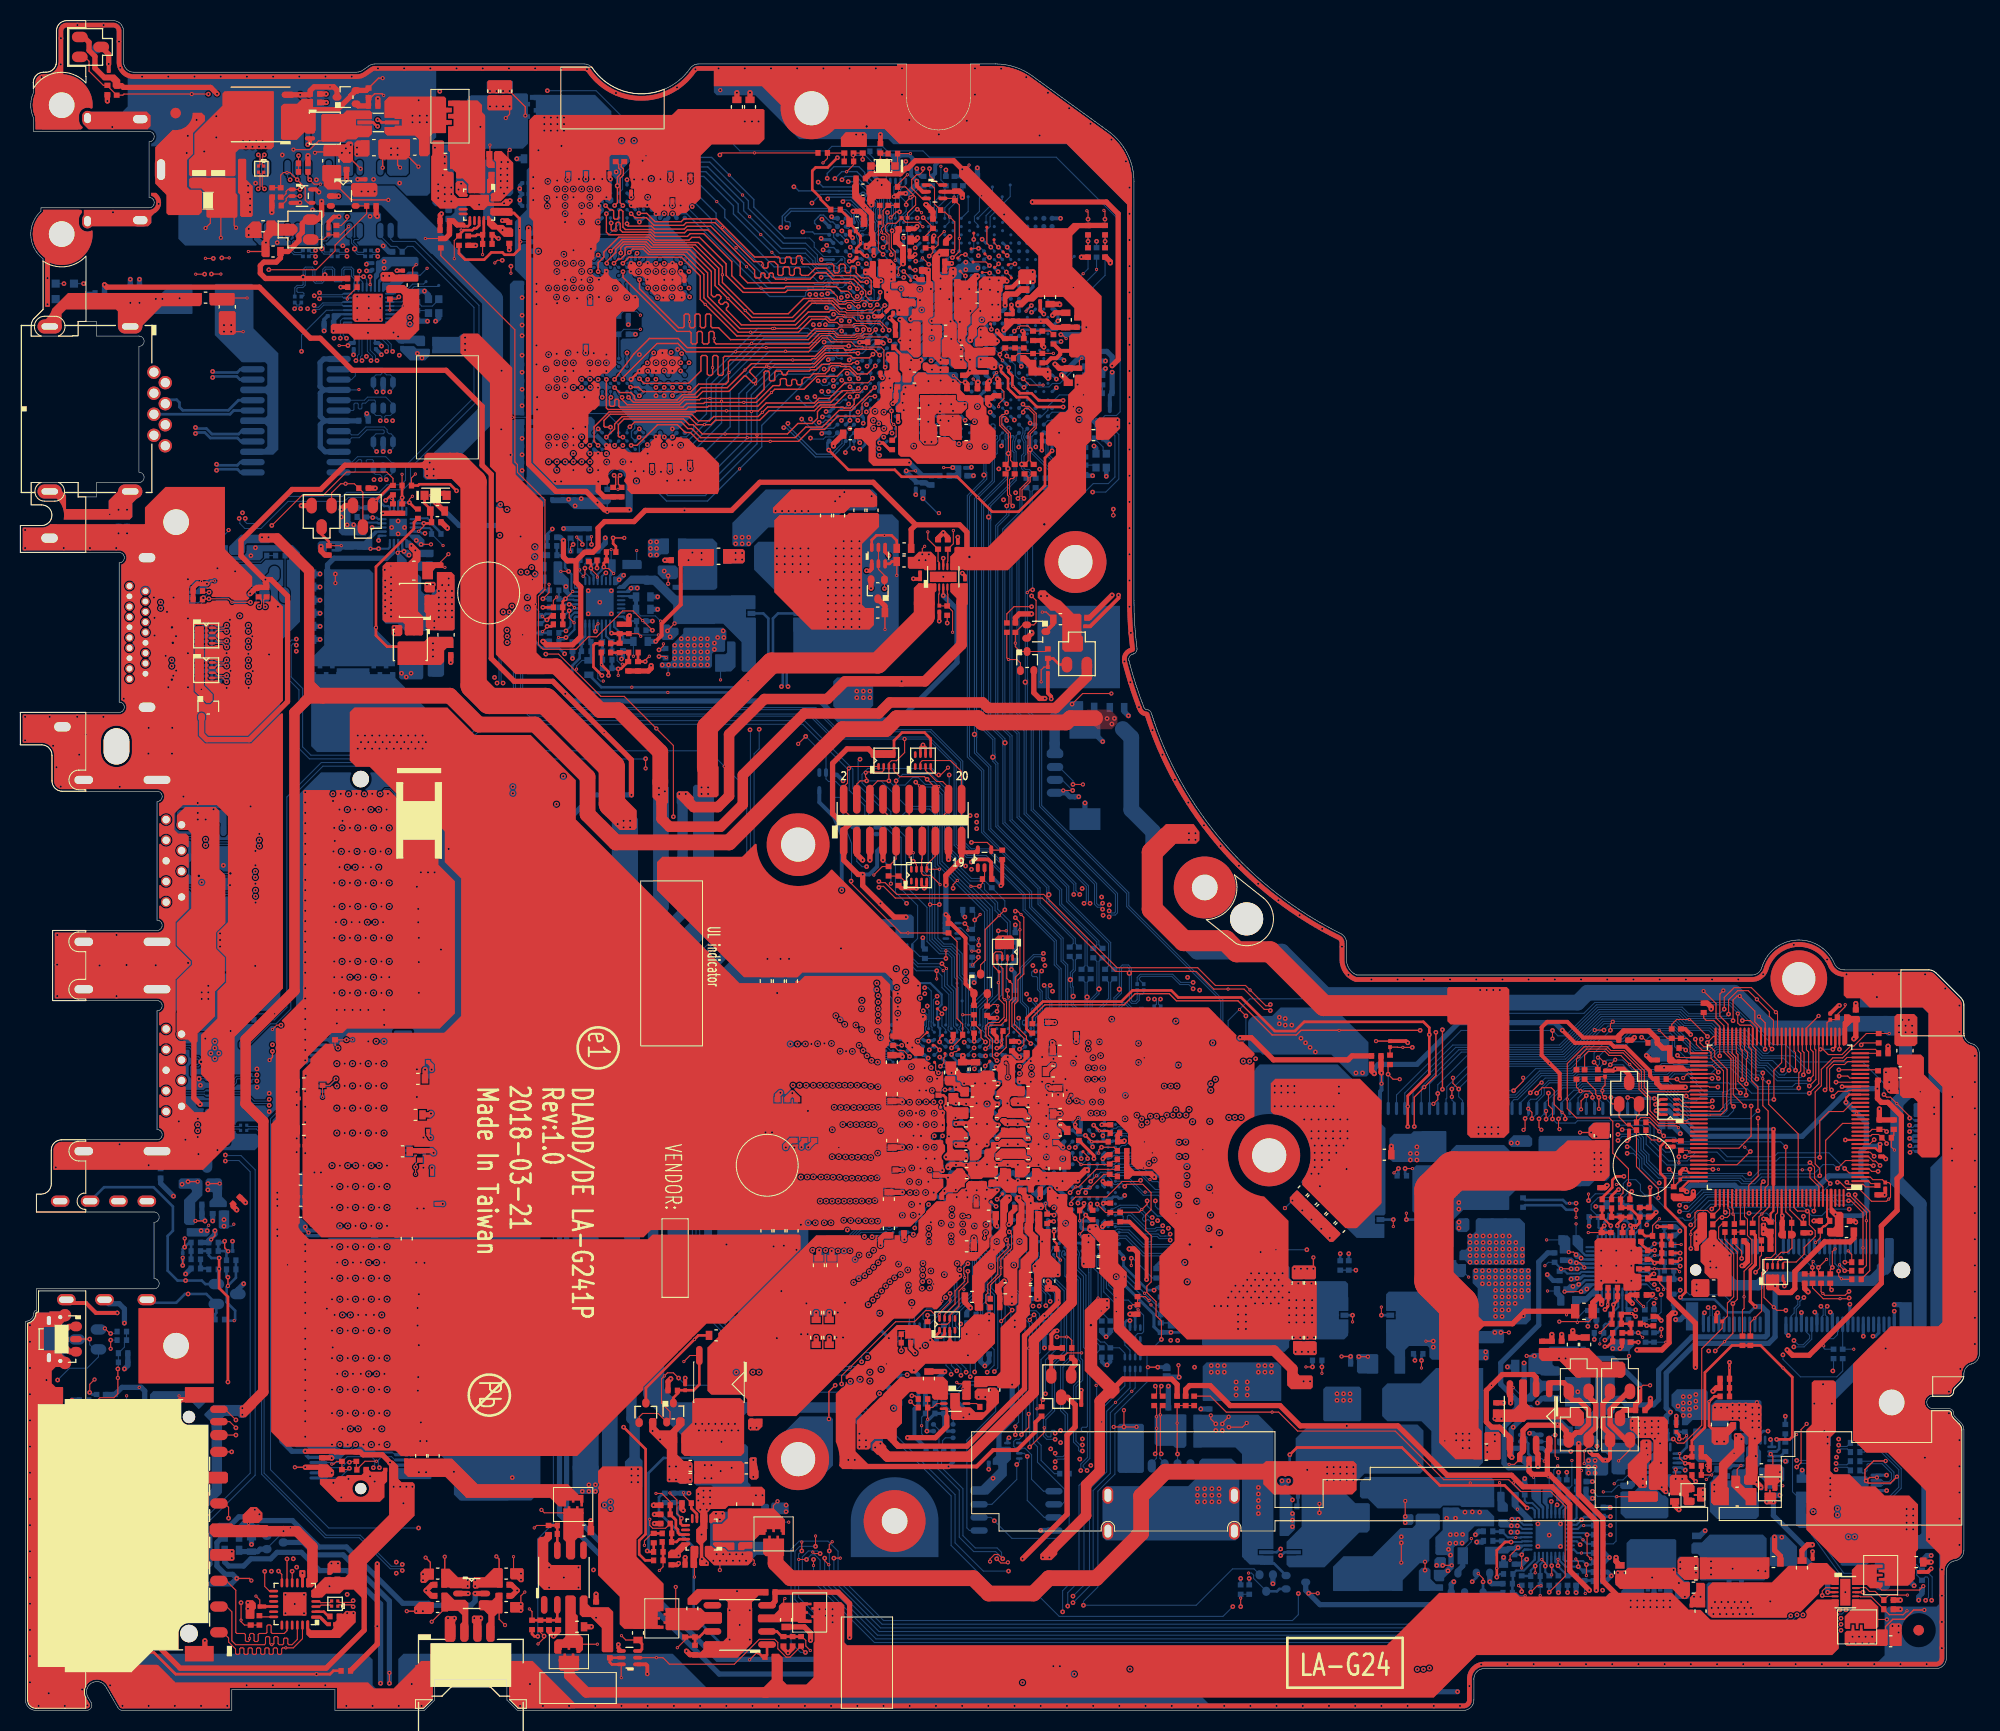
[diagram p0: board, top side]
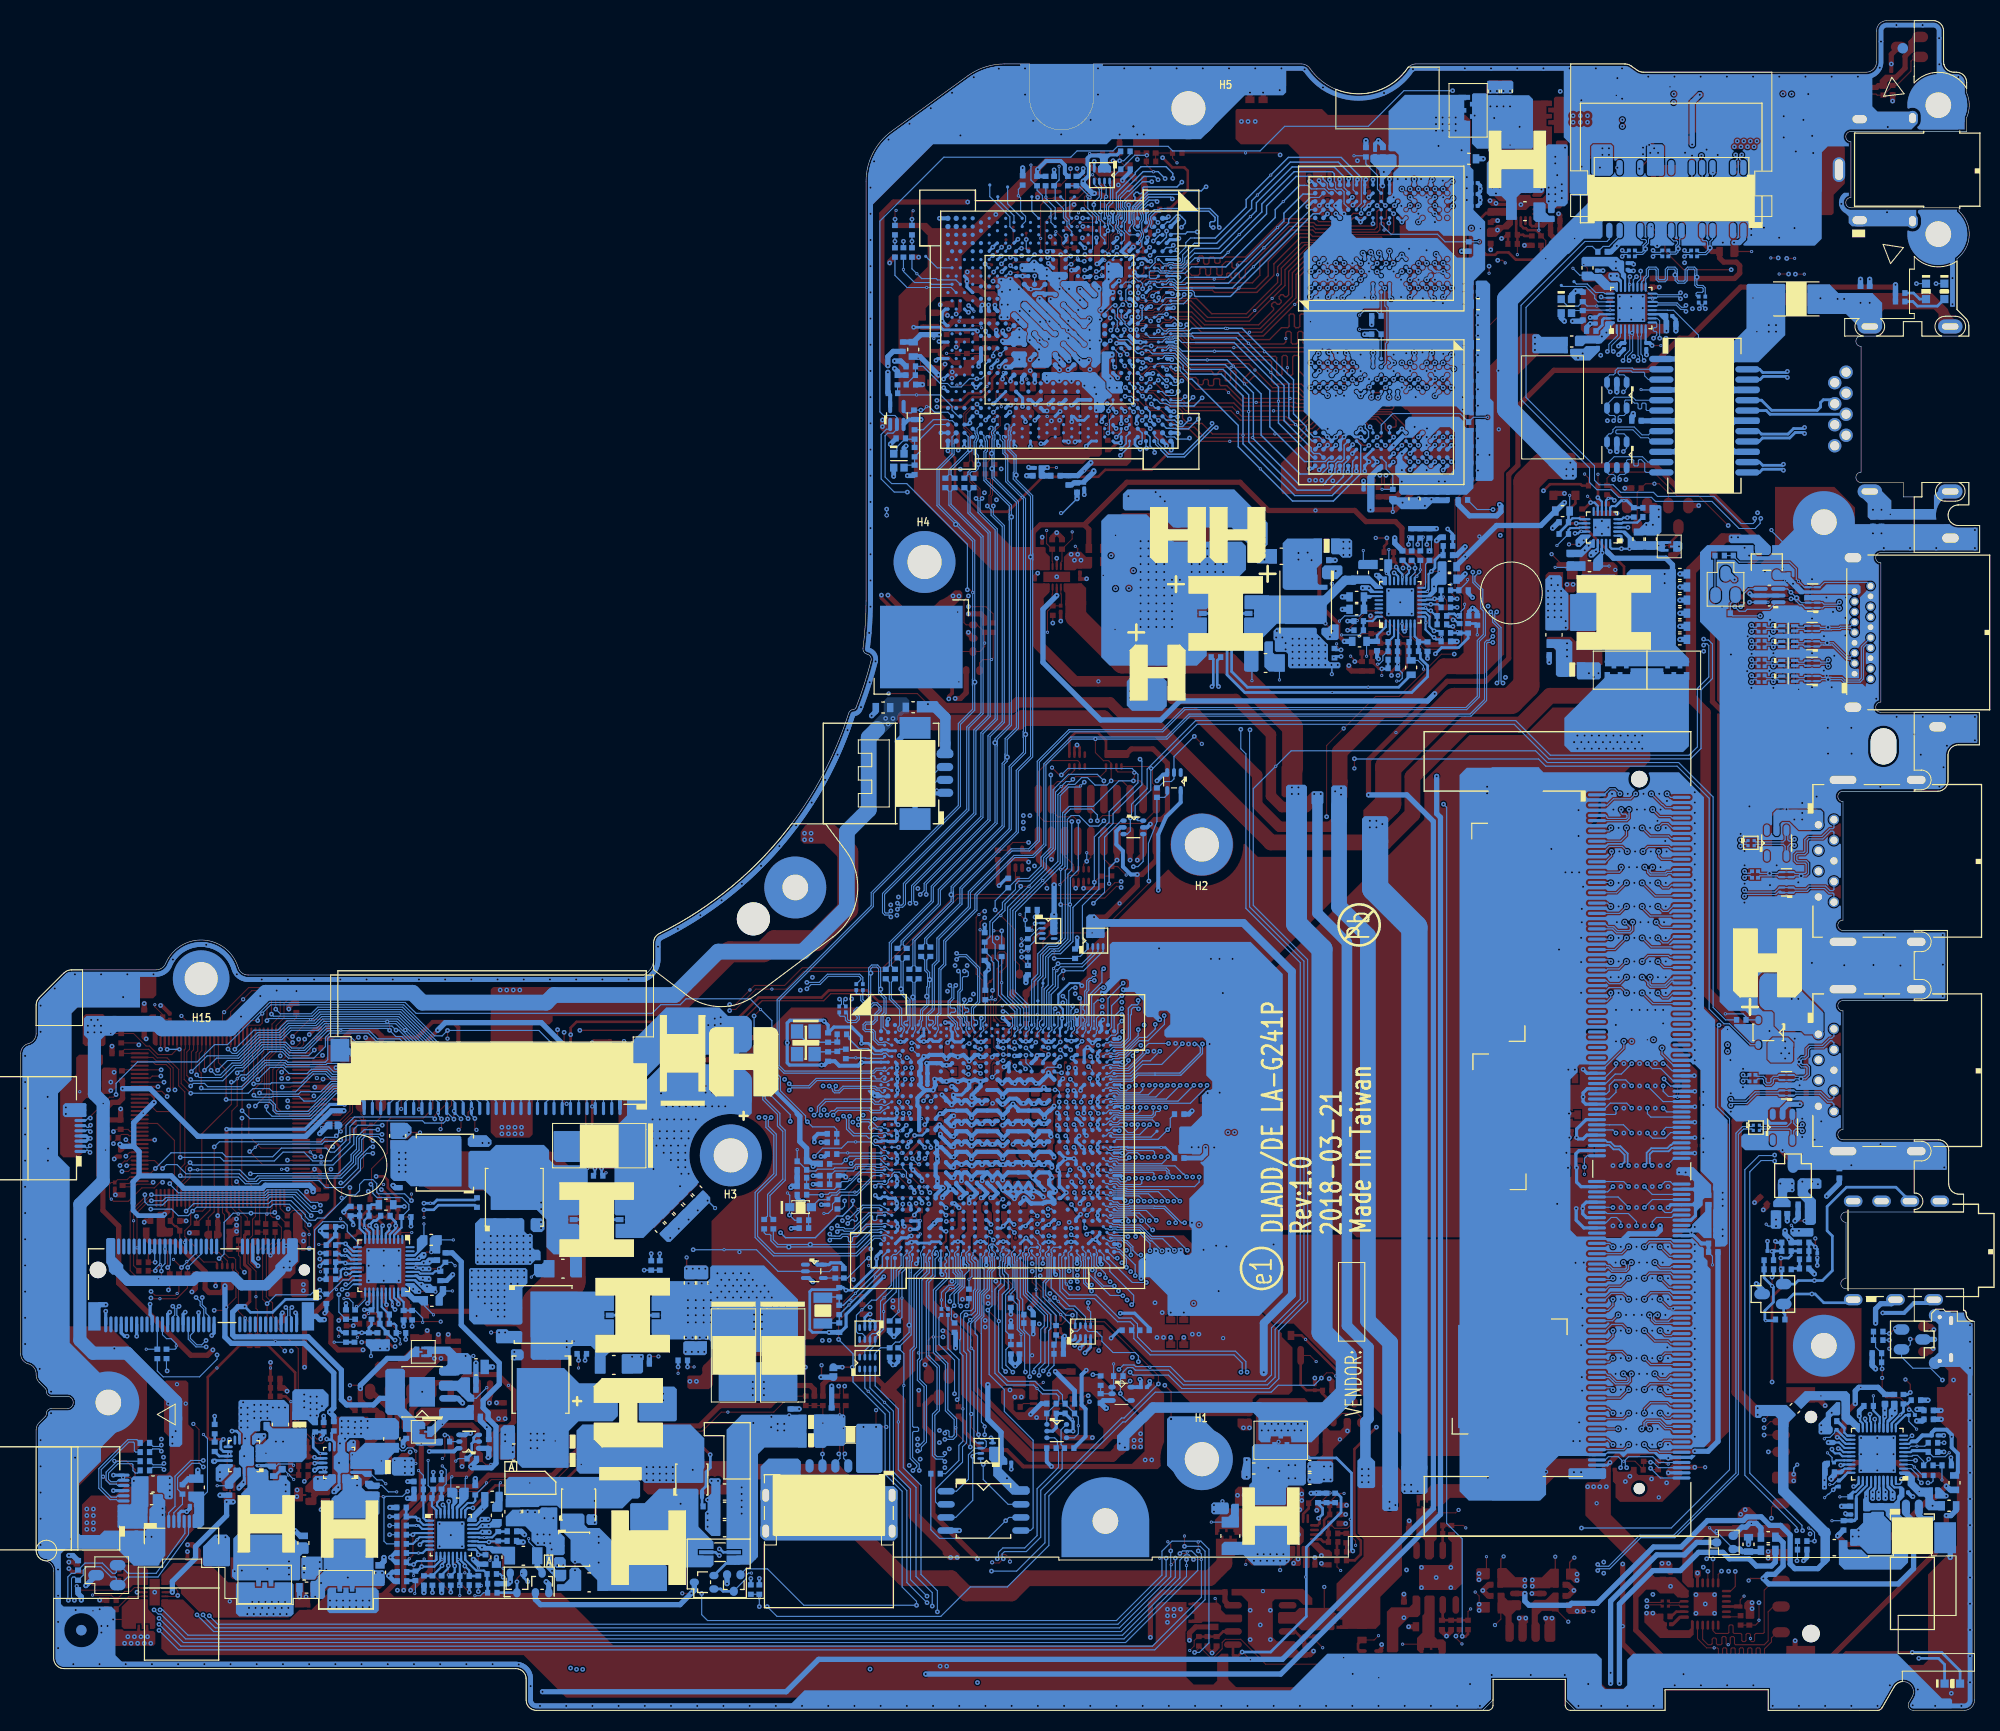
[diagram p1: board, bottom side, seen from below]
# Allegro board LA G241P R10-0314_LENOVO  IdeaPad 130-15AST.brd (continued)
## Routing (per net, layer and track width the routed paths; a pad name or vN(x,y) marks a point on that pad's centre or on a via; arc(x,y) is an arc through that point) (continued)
PCIE_ARX_DTX_P0: length 149
  IN2 w0.127: v1(104.32,57.92) 104.29,57.94 104.29,58.22 104.4,58.32 105.06,58.32 105.58,58.84 105.58,59.55 107.27,61.24 108.23,61.24 109.12,62.13 109.12,67.66 108.3,68.48 108.3,71.98 107.34,72.94 107.34,85.43 96.66,96.11 85.81,96.11 84.85,95.14 78,95.14 76.72,93.86 55.15,93.86 52.78,96.23 51.34,96.23 44.03,103.54 44.03,113.31 40.99,116.36 40.99,128.19 36.05,133.13 32.57,133.13 30.73,134.97 27.32,134.97 26.82,135.46 26.82,135.59 27.14,135.91 v1(27.14,135.92)
  BOTTOM w0.102: v1(104.32,57.92) 104.19,57.79 104.19,57.54 UC1.U4 ; CL11.2 26.99,136.3 26.99,136.07 v1(27.14,135.92)
PCIE_ARX_DTX_P2: length 99.5
  IN2 w0.127: v1(103.9,58.99) 104.18,59.27 104.18,59.45 104.05,59.58 103.66,59.58 103.46,59.37 103.46,58.46 103.29,58.3 103.29,57.73 103.58,57.44 106.18,57.44 106.46,57.73 106.46,57.91 106.26,58.11 106.26,58.29 106.44,58.47 106.62,58.47 106.82,58.27 107,58.27 107.18,58.45 107.18,58.63 107.02,58.79 107.02,58.97 107.2,59.14 107.38,59.14 107.54,58.99 107.72,58.99 107.97,59.24 116.28,59.24 116.96,59.92 119.41,59.92 120.75,61.25 135.04,61.25 136.62,62.83 138.84,62.83 139.41,63.4 151.38,63.4 153.03,61.75 156.33,61.75 157.09,60.99 158.26,60.99 162.95,56.3 163.78,56.3 166.98,53.11 166.98,45.04 169.13,42.89 169.13,36.86 170.12,35.87 v1(171.9,35.87)
  BOTTOM w0.102: UC1.R5 103.9,58.79 103.9,58.99 v1(103.9,58.99) ; v1(171.9,35.87) 172.32,35.45 172.79,35.45 173.42,36.08 173.42,36.37 173.12,36.67 JWLAN1.41
PCIE_ARX_GTX_N0: length 66.1
  IN2 w0.127: v1(105.51,77.53) 105.7,77.34 106.05,77.34 106.39,76.99 106.39,68.61 106.45,68.55 106.45,62.85 105.25,61.64 104.56,61.64 v1(104.13,61.21)
  BOTTOM w0.102: v1(105.51,77.53) 105.71,77.32 106.02,77.32 106.12,77.43 106.12,79.13 97.96,87.3 97.96,95.27 96.57,96.66 96.57,113.85 99.68,116.96 99.68,118.23 CV2.2 ; UC1.L4 v1(104.13,61.21)
PCIE_ARX_GTX_N1: length 63.6
  IN2 w0.127: v1(104.88,77.69) 104.72,77.86 104.52,77.86 104.4,77.74 104.4,76.25 105.31,75.33 105.31,66.2 105.37,66.14 105.37,63.15 104.96,62.73 104.53,62.73 v1(104.1,62.3)
  BOTTOM w0.102: v1(104.88,77.69) 104.69,77.88 104.37,77.88 104.1,78.16 104.1,80.1 97.27,86.93 97.27,94.99 95.89,96.37 95.89,114.24 97.84,116.2 97.84,118.23 CV4.2 ; UC1.J4 v1(104.1,62.3)
PCIE_ARX_GTX_N2: length 62.7
  TOP w0.102: CV6.2 97.86,119.56 97.86,119.14 97.07,118.35 97.07,117.71 v1(97.26,117.52)
  IN2 w0.127: v1(103.66,78.26) 103.52,78.12 103.52,75.8 104.49,74.83 104.49,65.44 104.15,65.1 104.15,64.48 104.38,63.67 v1(104.68,63.49)
  BOTTOM w0.102: v1(103.66,78.26) 103.51,78.42 103.51,79.96 96.79,86.68 96.79,94.79 95.4,96.17 95.4,114.49 97.07,116.15 97.07,117.33 v1(97.26,117.52) ; UC1.G4 v1(104.68,63.49)
PCIE_ARX_GTX_N3: length 61.4
  TOP w0.102: CV8.2 95.66,119.72 95.66,117.87 95.8,117.73 95.8,117.01 v1(95.58,116.79)
  IN2 w0.127: v1(102.09,79.12) 102.19,79.02 102.19,75.36 103.33,74.22 103.33,65.8 102.91,65.38 102.91,64.71 v1(103.49,64.13)
  BOTTOM w0.102: v1(102.09,79.12) 102.09,80.11 95.9,86.29 95.9,94.42 94.52,95.8 94.52,114.9 95.58,115.97 v1(95.58,116.79) ; UC1.E7 v1(103.49,64.13)
PCIE_ARX_GTX_P0: length 66.3
  IN2 w0.127: v1(105.51,76.94) 105.64,77.07 105.94,77.07 106.13,76.88 106.13,68.5 106.19,68.44 106.19,62.96 105.13,61.89 104.45,61.89 104.18,61.62 103.88,61.62 103.47,61.21 v1(103.44,61.21)
  BOTTOM w0.102: CV1.2 99.89,118.23 99.89,116.88 96.78,113.76 96.78,96.74 98.16,95.36 98.16,87.38 106.33,79.21 106.33,77.35 106.1,77.12 105.69,77.12 v1(105.51,76.94) ; UC1.L5 v1(103.44,61.21)
PCIE_ARX_GTX_P1: length 63.9
  IN2 w0.127: v1(103.49,62.33) 103.93,62.76 104.2,62.76 104.43,62.99 104.84,62.99 105.11,63.26 105.11,66.03 105.05,66.09 105.05,75.22 104.13,76.14 104.13,77.85 104.41,78.12 104.72,78.12 v1(104.88,78.28)
  BOTTOM w0.102: CV3.2 98.05,118.23 98.05,116.11 96.09,114.16 96.09,96.46 97.48,95.07 97.48,87.01 104.3,80.19 104.3,78.24 104.46,78.09 104.69,78.09 v1(104.88,78.28) ; UC1.J5 v1(103.49,62.33)
PCIE_ARX_GTX_P2: length 62.8
  TOP w0.102: v1(96.67,117.52) 96.87,117.71 96.87,118.43 97.65,119.22 97.65,119.56 CV5.2
  IN2 w0.127: v1(103.95,63.29) 104.12,63.6 103.89,64.45 103.89,65.21 104.22,65.55 104.22,74.72 103.25,75.69 103.25,78.09 v1(103.08,78.26)
  BOTTOM w0.102: v1(103.95,63.29) 103.78,63.29 103.57,63.09 UC1.G5 ; v1(96.67,117.52) 96.87,117.33 96.87,116.24 95.2,114.57 95.2,96.09 96.59,94.7 96.59,86.6 103.3,79.88 103.3,78.49 v1(103.08,78.26)
PCIE_ARX_GTX_P3: length 61.3
  TOP w0.102: CV7.2 96.36,119.62 96.19,119.45 95.97,119.45 95.86,119.34 95.86,117.95 96,117.81 96,116.96 v1(96.17,116.79)
  IN2 w0.127: v1(103.49,64.73) 103.47,64.7 103.29,64.7 103.18,64.82 103.18,65.27 103.6,65.69 103.6,74.33 102.45,75.47 102.45,78.9 v1(102.67,79.12)
  BOTTOM w0.102: v1(103.49,64.73) 103.24,64.73 UC1.D7 ; v1(96.17,116.79) 95.8,116.43 95.8,115.9 94.72,114.82 94.72,95.89 96.1,94.5 96.1,86.38 102.29,80.19 102.29,79.5 v1(102.67,79.12)
PCIE_ATX_C_DRX_N0: length 137.9
  IN2 w0.127: v1(28.44,136.25) 30.57,136.25 32.49,134.33 36.75,134.33 41.81,129.27 41.81,116.68 44.92,113.57 44.92,103.85 51.74,97.03 53.19,97.03 55.55,94.66 75.03,94.66 76.35,95.98 84.36,95.98 85.31,96.93 97.21,96.93 108.14,86 108.14,73.27 109.32,72.08 109.32,70.95 110.38,69.89 110.38,69.08 v1(110.49,68.97)
  BOTTOM w0.102: UL2.14 31.23,136.58 31.14,136.49 29.3,136.49 28.87,136.06 28.63,136.06 v1(28.44,136.25) ; v1(110.49,68.97) 110.3,68.78 110.3,68.48 CC2.2
PCIE_ATX_C_DRX_N2: length 91.9
  IN2 w0.127: v1(113.65,69.97) 113.45,69.97 113.39,70.03 113.39,70.24 113.3,70.33 113.21,70.33 113.08,70.2 113.08,69.43 113.58,68.93 115.71,68.93 121.29,63.35 134.72,63.35 135.85,64.48 138.08,64.48 138.84,65.24 153.95,65.24 155.59,63.6 156.76,63.6 157.41,62.96 158.09,62.96 158.18,63.05 160.72,63.05 162.59,61.17 162.59,59.28 163.91,57.96 164.48,57.96 165.53,56.9 166.36,56.9 170.98,52.28 170.98,49.08 172.54,47.52 172.54,40.36 v1(172.86,40.04)
  BOTTOM w0.102: JWLAN1.37 172.12,38.92 172.47,39.27 172.47,39.64 v1(172.86,40.04) ; CC4.2 108.44,70.86 108.44,71 108.62,71.18 111.59,71.18 112.38,70.39 113.24,70.39 v1(113.65,69.97)
PCIE_ATX_C_DRX_P0: length 137.9
  IN2 w0.127: v1(28.44,135.67) 28.6,135.51 28.83,135.51 28.99,135.66 28.99,135.87 29.11,135.99 30.46,135.99 32.38,134.07 36.64,134.07 41.55,129.16 41.55,116.57 44.66,113.46 44.66,103.74 51.63,96.76 53.08,96.76 55.44,94.39 75.14,94.39 76.46,95.71 84.47,95.71 85.42,96.67 97.1,96.67 107.87,85.89 107.87,73.16 109.06,71.97 109.06,70.85 110.12,69.78 110.12,69.18 v1(109.91,68.97)
  BOTTOM w0.102: CC1.2 110.1,68.48 110.1,68.78 v1(109.91,68.97) ; UL2.13 31.26,136.18 31.16,136.28 29.38,136.28 28.96,135.86 28.63,135.86 v1(28.44,135.67)
PCIE_ATX_C_DRX_P2: length 91.9
  IN2 w0.127: v1(113.65,70.59) 113.1,70.59 112.81,70.31 112.81,69.32 113.47,68.66 115.61,68.66 121.18,63.09 134.83,63.09 135.96,64.22 138.19,64.22 138.95,64.98 153.84,64.98 155.48,63.34 156.65,63.34 157.3,62.69 158.2,62.69 158.29,62.78 160.61,62.78 162.32,61.06 162.32,59.17 163.8,57.69 164.37,57.69 165.42,56.64 166.25,56.64 170.72,52.17 170.72,48.97 172.27,47.42 v1(172.27,40.04)
  BOTTOM w0.102: v1(113.65,70.59) 112.46,70.59 111.67,71.38 108.53,71.38 108.23,71.08 CC3.2 ; v1(172.27,40.04) 172.27,39.35 171.92,39 171.92,38.53 171.62,38.23 JWLAN1.35
PCIE_ATX_C_GRX_N0: length 58.2
  BOTTOM w0.102: UV1.AE31 95.98,123.55 96.05,123.62 96.21,123.62 96.29,123.54 96.29,123.41 96.16,123.08 96.16,122.11 96.29,121.98 96.29,119.36 93.83,116.89 v4(93.83,115.73) 93.83,95.52 95.19,94.16 95.19,93.55 95.21,93.52 95.21,86.01 101.4,79.82 101.4,78.43 105.46,74.36 105.46,72.2 CC105.2
PCIE_ATX_C_GRX_N1: length 56.8
  BOTTOM w0.102: UV1.AD28 95.4,124.47 95.4,124.1 95.55,123.95 95.55,123.81 95.43,123.69 95.43,123.28 95.51,123.2 95.51,120.73 95.48,120.7 95.48,120.13 95.51,120.11 95.51,119.58 93.14,117.22 93.14,95.23 94.24,94.14 v4(94.24,92.44) 94.24,92.03 94.53,91.74 94.53,85.7 100.71,79.52 100.71,78.13 104.32,74.52 104.32,74.24 CC107.2
PCIE_ATX_C_GRX_N2: length 57.6
  BOTTOM w0.102: CC109.2 103.18,72.2 103.18,74.65 99.47,78.36 99.47,78.79 99.44,78.82 99.44,79.38 99.47,79.41 99.47,79.79 93.84,85.42 93.84,91.46 92.46,92.84 v4(92.46,94.65) 92.46,117.52 94.19,119.25 94.19,121.71 94.46,121.98 94.46,123.12 94.7,123.36 94.7,123.56 94.64,123.62 94.51,123.62 UV1.AC31
PCIE_ATX_C_GRX_N3: length 56.2
  BOTTOM w0.102: CC111.2 102.03,74.36 102.03,74.77 98.62,78.19 98.62,79.67 93.16,85.14 93.16,91.07 91.77,92.45 91.77,111.55 91.74,111.57 91.74,112.14 91.77,112.16 91.77,117.8 93.37,119.41 v4(93.37,119.79) 93.37,121.71 93.98,122.32 93.98,123.09 93.87,123.19 93.87,123.7 93.93,123.76 93.93,124 93.86,124.08 93.86,124.41 UV1.AB28
PCIE_ATX_C_GRX_P0: length 58.2
  BOTTOM w0.102: UV1.AF30 96.49,123.6 96.49,123.37 96.36,123.04 96.36,122.2 96.5,122.06 96.5,119.27 94.03,116.81 94.03,116.04 94.06,116.01 94.06,115.44 94.03,115.42 94.03,95.6 95.42,94.22 v4(95.42,93.83) 95.42,86.09 101.6,79.91 101.6,78.51 105.67,74.45 105.67,72.2 CC104.2
PCIE_ATX_C_GRX_P1: length 57
  BOTTOM w0.102: CC106.2 104.52,74.24 104.52,74.6 100.92,78.21 100.92,79.6 94.73,85.79 94.73,91.83 94.47,92.09 94.47,92.72 94.44,92.74 94.44,94.23 93.35,95.32 93.35,117.14 95.71,119.5 v4(95.71,120.42) 95.71,123.28 95.63,123.36 95.63,123.61 95.75,123.73 95.75,124.04 95.61,124.18 95.61,124.42 95.7,124.52 95.88,124.52 95.98,124.42 UV1.AE29
PCIE_ATX_C_GRX_P2: length 57.7
  BOTTOM w0.102: UV1.AD30 94.92,123.63 94.92,123.26 94.66,123 94.66,121.9 94.39,121.62 94.39,119.16 92.66,117.43 92.66,94.95 92.69,94.93 92.69,94.36 92.66,94.34 92.66,92.93 94.05,91.54 94.05,85.5 99.67,79.88 v4(99.67,79.1) 99.67,78.44 103.38,74.73 103.38,72.2 CC108.2
PCIE_ATX_C_GRX_P3: length 57
  BOTTOM w0.102: UV1.AC29 94.46,124.36 94.46,124.62 94.33,124.75 94.16,124.75 94.05,124.64 94.05,124.15 94.14,124.07 94.14,123.68 94.08,123.61 94.08,123.28 94.19,123.17 94.19,122.23 93.58,121.62 93.58,120.1 93.65,120.02 93.65,119.4 91.98,117.72 91.98,111.86 v4(91.97,111.85) 91.98,111.85 91.98,92.54 93.36,91.15 93.36,85.22 98.82,79.76 98.82,78.28 102.24,74.86 102.24,74.36 CC110.2
PCIE_ATX_DRX_N0: length 12.9
  BOTTOM w0.102: CC2.1 110.52,67.41 110.42,67.31 110.03,67.31 109.92,67.2 109.92,66.92 109.7,66.7 108.87,66.7 108.57,67 108.57,67.31 108.9,67.65 108.9,67.79 108.71,67.98 108.57,67.98 108.24,67.65 107.93,67.65 107.15,68.42 106.91,68.42 106.66,68.17 106.66,67.93 107.05,67.54 107.05,66.99 107.29,66.75 107.97,66.75 108.21,66.51 108.21,66.04 107.99,65.82 107.33,65.82 107.22,65.71 107.22,65.03 106.74,64.55 106.16,64.55 UC1.D1
PCIE_ATX_DRX_N2: length 12.9
  BOTTOM w0.102: CC4.1 108.87,69.55 108.78,69.46 108.55,69.46 108.44,69.34 108.44,68.84 108.15,68.56 107.69,68.56 107.47,68.78 v4(107.47,71.49) 107.47,71.9 107.3,72.08 106.88,72.08 106.71,71.91 106.71,69.55 106.18,69.02 106.18,67.69 106.47,67.4 UC1.B1
PCIE_ATX_DRX_P0: length 12.9
  BOTTOM w0.102: CC1.1 109.72,67.52 109.72,67.01 109.62,66.9 108.96,66.9 108.77,67.09 108.77,67.23 109.1,67.56 109.1,67.87 108.8,68.18 108.49,68.18 108.15,67.85 108.01,67.85 107.24,68.62 106.83,68.62 106.46,68.25 106.46,67.85 106.85,67.46 106.85,66.9 107.2,66.55 107.89,66.55 108.01,66.43 108.01,66.13 107.91,66.02 107.25,66.02 107.02,65.8 107.02,65.12 106.66,64.75 106.33,64.75 106.2,64.81 105.99,64.81 UC1.D2
PCIE_ATX_DRX_P2: length 12.9
  BOTTOM w0.102: UC1.B2 106.27,66.26 106.27,67.32 105.98,67.61 105.98,69.1 106.5,69.63 v4(106.5,69.93) 106.5,71.99 106.79,72.28 107.38,72.28 107.67,71.99 107.67,68.86 107.77,68.76 108.07,68.76 108.23,68.93 CC3.1
PCIE_ATX_GRX_N0: length 6.3
  BOTTOM w0.102: UC1.B4 104.22,65.98 104.22,66.24 104.47,66.5 104.47,68.05 105.46,69.05 105.46,70.6 CC105.1
PCIE_ATX_GRX_N1: length 7.7
  BOTTOM w0.102: UC1.B5 103.66,66.37 103.66,68.9 104.33,69.57 104.33,72.63 CC107.1
PCIE_ATX_GRX_N2: length 5.8
  BOTTOM w0.102: UC1.B6 103.12,66.01 103.12,66.23 103.17,66.4 103.17,68.93 103.18,68.93 103.18,70.6 CC109.1
PCIE_ATX_GRX_N3: length 8
  BOTTOM w0.102: CC111.1 102.03,72.76 102.03,71.84 101.75,71.56 v4(101.75,70.86) 101.75,70.15 101.83,70.07 101.83,68.41 102.44,67.8 102.44,66.92 102.57,66.8 102.57,66.32 UC1.B7
PCIE_ATX_GRX_P0: length 6.2
  BOTTOM w0.102: CC104.1 105.67,70.6 105.67,68.97 104.67,67.97 104.67,66.4 104.83,66.24 104.83,65.98 104.7,65.85 104.61,65.85 104.52,65.94 UC1.A4
PCIE_ATX_GRX_P1: length 7.4
  BOTTOM w0.102: UC1.A5 104.13,66.46 104.24,66.57 104.24,66.72 104.14,66.82 103.96,66.82 103.87,66.92 103.87,68.82 104.53,69.48 v4(104.53,69.96) 104.53,72.65 CC106.1
PCIE_ATX_GRX_P2: length 5
  BOTTOM w0.102: CC108.1 103.38,70.6 v4(103.38,69.17) 103.38,68.85 103.38,68.85 103.38,66.15 UC1.A6
PCIE_ATX_GRX_P3: length 7.3
  BOTTOM w0.102: UC1.A7 102.77,66.56 102.77,66.88 102.64,67.01 102.64,67.88 102.03,68.49 v4(102.03,69.25) 102.03,70.16 101.96,70.23 101.96,71.47 102.24,71.75 102.24,72.76 CC110.1
PDB: length 17.5
  IN2 w0.127: v1(15.98,16.41) 15.71,16.15 9.06,16.15 7.55,17.66 v1(7.55,22.45)
  BOTTOM w0.102: RA46.1 v1(15.98,16.41) 15.98,17.25 16.3,17.57 16.44,17.57 v2(16.55,17.68)
  BOTTOM w0.127: v1(7.55,22.45) 7.55,22.1 7.71,21.94 7.99,21.94 8.1,22.04 UA1.40
PGOOD: length 24.6
  TOP w0.102: v1(71.47,5.66) 71.41,5.66 v2(70.67,4.91)
  TOP w0.254: v1(71.47,5.66) 71.95,5.17 PR2009.2 72.35,5.38 PU2001.1
  BOTTOM w0.254: v1(71.47,5.66) 68.7,5.66 65.24,9.11 65.24,15.83 61.88,19.19 61.88,20.67 62.27,21.06 PR603.1
PLL_ANALOG_IN: length 3.6
  BOTTOM w0.102: UV1.AA1 94.2,146.11 T221.1
PLL_ANALOG_OUT: length 4.6
  BOTTOM w0.102: UV1.AA3 92.78,144.07 92.45,144.39 92.45,144.88 92.94,145.36 92.94,146.65 v2(93.15,146.87) 93.15,147.49 RV83.1
PLT_RST_VGA#: length 73
  IN1 w0.127: v1(102.61,126.09) 102.09,125.57 102.09,123.4 100.74,122.05 100.74,118.87 93.92,112.06 90.78,112.06 89.74,111.02 86.42,111.02 86.26,111.17 86.26,114.51 84.92,115.85 67.03,115.85 65.66,114.48 56.71,114.48 56.29,114.06 52.03,114.06 v1(51.54,114.56)
  BOTTOM w0.102: UV1.AL27 99.98,125.89 101.27,125.89 101.81,126.42 v2(102.05,126.42) 102.38,126.09 v1(102.61,126.09) RV4.1 103.55,125.82 104.1,125.82 104.28,126 UV2.4
  BOTTOM w0.254: v1(51.54,114.56) 51.06,114.08 PR1006.1 PR1099.1
PLUG_IN: length 33.1
  TOP w0.102: v3(7.17,32.09) 6.7,31.62 v1(6.7,30.83)
  IN2 w0.254: JHP1.6 10.46,50.35 13.46,50.35 14.82,48.99 14.82,46.77 14.25,46.19 14.25,44.04 14.95,43.34 14.95,39.34 11.43,35.82 11.43,31.88 9.93,30.38 7.14,30.38 v1(6.7,30.83)
  BOTTOM w0.254: RA23.2 6.95,30.63 6.76,30.83 v1(6.7,30.83)
PLUG_IN_R: length 3.7
  BOTTOM w0.203: v2(7.67,28.66) 8.5,27.83 UA1.12
  BOTTOM w0.254: RA51.1 6.97,29.72 RA23.1 7.36,28.97 v2(7.67,28.66)
PM_CLKRUN#: length 8.7
  TOP w0.102: U11.38 174.7,64.11 175.22,63.59 176.56,63.59 177.38,64.42 177.7,64.42 178.92,65.64 R428.2 v2(181.13,65.64)
PM_SLP_S3#: length 92.8
  TOP w0.102: v1(176.11,52.54) 176.89,53.32 U11.6
  IN1 w0.127: v1(154.84,55.26) 153.63,56.47 153.63,57.43 153.32,57.75 150.4,57.75 150.29,57.85 134.24,57.85 131.85,55.47 131.85,53.81 128.49,50.45 128.49,46.32 127.22,45.05 126.33,45.05 125.88,45.5 119.34,45.5 114.33,50.51 114.33,52.54 113.16,53.71 v1(112.93,53.71)
  BOTTOM w0.102: v1(112.93,53.71) 112.13,54.51 110.3,54.51 109.69,55.12 v2(108.93,55.12) 107.43,55.12 107.08,54.78 106.74,54.78 106.26,54.29 106,54.29 UC1.AC2 ; v1(154.84,55.26) 155.22,55.64 156.5,55.64 156.81,55.34 156.81,54.23 157.38,53.66 157.38,52.99 158.77,51.61 166.73,51.61 167.03,51.3 167.95,51.3 168.68,52.04 173.83,52.04 174.72,52.93 175.73,52.93 v1(176.11,52.54)
PM_SLP_S5#: length 216.5
  TOP w0.102: v1(107.03,50.82) 107.23,51.02 108.77,51.02 109.58,50.21 109.58,48.56 109.06,48.04 109.06,46.56 109.59,46.03 109.59,41.56 109.17,41.14 109.17,40.53 110.06,39.64 110.06,38.28 110.58,37.76 v1(110.58,35.97) ; U11.123 174.7,50.78 173.89,51.59 173.89,52.67 v1(173.45,53.12) ; v2(50.15,6.44) 50.74,7.03 v1(50.74,7.21) 50.38,7.56 PR2003.1
  IN1 w0.127: v1(154.82,56.74) 154.82,57.46 153.76,58.51 151.06,58.51 150.93,58.64 133.89,58.64 131.09,55.85 131.09,54.2 127.73,50.83 127.73,47.72 126.27,46.26 119.79,46.26 115.92,50.13 115.92,52.1 113.36,54.65 110.91,54.65 110.33,54.07 109.31,54.07 107.39,52.15 107.39,51.19 v1(107.03,50.82)
  IN2 w0.127: v1(50.74,7.21) 51.25,6.7 52.92,6.7 54.83,4.79 61.5,4.79 62.26,4.03 93.56,4.03 98.39,8.86 101.69,8.86 v1(103.02,10.19)
  BOTTOM w0.102: v1(154.82,56.74) 157.18,56.74 157.57,56.35 157.57,54.9 159.58,52.89 173.22,52.89 v1(173.45,53.12) ; UC1.AG4 104.37,51.86 104.7,52.19 105.19,52.19 105.41,51.97 105.41,51.77 105.72,51.46 105.72,51.44 105.77,51.39 105.77,51.21 105.98,51 106.26,51 106.32,51.06 106.78,51.06 v1(107.03,50.82) ; PQ711.2 120.09,13.19 119.56,13.72 117.48,13.72 113.95,10.19 v1(103.02,10.19) 103.02,10.57 104.42,11.97 104.42,21.25 106.07,22.9 106.07,28.73 109.18,31.84 109.18,34.57 v1(110.58,35.97)
PROCHOT#: length 59.3
  TOP w0.102: v1(164.26,34.85) v2(165.17,35.76) 165.98,36.57 v1(165.98,39.44) 166.41,39.87 166.41,44.44 165.2,45.65 R929.1
  IN1 w0.127: v1(164.26,34.85) 163.58,34.17 161.48,34.17 158.52,31.21 157.57,31.21 157.06,30.7 155.73,30.7 153.29,28.26 153.29,22.17 v1(152.36,21.24)
  BOTTOM w0.102: PU801.11 157.22,45.46 158.21,46.45 158.21,47.04 158.55,47.39 160.57,47.39 161.38,46.58 161.38,40.7 161.78,40.3 165.12,40.3 v1(165.98,39.44) ; v1(152.36,21.24) 152.85,20.76 154.46,20.76 154.65,20.57 154.65,16.41 154.38,16.15 PR777.1
PROG_CHG: length 4.6
  TOP w0.102: v2(151.78,13.07) v1(151.78,14.14)
  BOTTOM w0.203: PR753.1 152.24,14.14 v1(151.78,14.14) 151.44,14.48 149.71,14.48 149.57,14.62 PU703.9
PS_0: length 4.1
  TOP w0.102: RV8.2 RV9.1 CV29.1 94.92,131.6 v1(94.92,131.49) 94.92,131.19 v2(95.19,130.93)
  BOTTOM w0.102: v1(94.92,131.49) 94.38,132.03 UV1.AC19
PS_1: length 5.7
  TOP w0.102: v2(100.11,131.59) RV11.2 98.15,131.59 RV12.1 96.7,131.58 CV28.1 95.8,131.13 v1(95.59,131.33)
  BOTTOM w0.102: v1(95.59,131.33) 95.59,131.68 UV1.AD19
PS_2: length 5
  TOP w0.102: RV28.2 99.78,133.75 RV13.1 CV11.1 97.63,134.26 96.9,134.26 v2(96.72,134.08) 96.65,134.08 v1(96.32,133.75)
  BOTTOM w0.102: UV1.AE17 96.32,133.63 v1(96.32,133.75)
PS_3: length 13.9
  TOP w0.102: v2(99.11,128.52) 97.79,128.52 v1(97.18,129.13)
  BOTTOM w0.102: RV15.2 104.03,128.59 RV16.1 103.13,129.49 CV15.1 102.39,130.33 100.73,128.68 100.02,128.68 99.68,128.34 98.69,128.34 97.91,129.13 v1(97.18,129.13) 96.74,129.13 96.41,129.45 96.41,130.46 UV1.AE20
PWR_CAPS_LED: length 6.2
  TOP w0.102: v1(131.92,61.82) v3(131.92,60.77)
  TOP w0.508: R271.1 R278.1 131.87,61.87 v1(131.92,61.82)
  BOTTOM w0.381: JKB1.1 131.77,60.02 131.92,60.16 v1(131.92,61.82)
PWR_LED#: length 240.7
  TOP w0.102: U11.92 166.39,52.92 v1(167.67,54.2) ; R272.1 157.55,55.87 158.1,55.31 v1(158.84,55.31)
  IN1 w0.127: v1(135.39,3.98) 139,7.59 166.85,7.59 172.56,13.3 172.56,20.45 173.12,21.01 173.12,24.49 172.18,25.43 172.18,29.3 169.94,31.54 169.94,38.32 170.53,38.91 170.53,41.38 171.1,41.95 171.1,47.02 169.41,48.71 169.41,49.47 168.05,50.83 168.05,53.81 v1(167.67,54.2)
  IN2 w0.127: v1(135.39,3.98) 108.75,3.98 106.2,1.43 54.51,1.43 51.59,4.35 38.32,4.35 36.03,2.06 33.87,2.06 32.25,3.68 12.38,3.68 11.01,5.05 v1(5.87,5.05)
  BOTTOM w0.102: v1(167.67,54.2) 167.54,54.2 v2(167.13,54.61) 166.83,54.91 160.66,54.91 160.39,55.17 158.98,55.17 v1(158.84,55.31)
  BOTTOM w0.254: v1(5.87,5.05) 3.96,5.05 3.37,4.45 LED2.1
PX_EN: length 1.2
  TOP w0.102: v1(94.1,133.93) 94.1,134.36 T218.1
  BOTTOM w0.102: UV1.AB16 93.94,133.93 v1(94.1,133.93)
PXS_RST#: length 125.5
  TOP w0.102: v1(118.77,67.34) v2(118.15,67.96)
  IN1 w0.127: v1(112.16,35.87) 111.38,35.1 108.91,35.1 106.34,37.66 103.06,37.66 101.48,39.24 v1(99.38,39.24)
  IN2 w0.127: v1(115.27,57.12) 114.7,56.55 114.7,51.12 113.53,49.95 113.53,47.77 114.07,47.22 114.07,41.34 113.82,41.09 113.82,36.66 113.03,35.87 v1(112.16,35.87) ; v1(118.77,67.34) 118.77,68.99 110.9,76.87 110.9,87.6 105.86,92.64 105.86,93.57 104.12,95.31 104.12,101.25 105.37,102.51 105.37,113.95 103.91,115.41 v1(103.91,118.14)
  BOTTOM w0.102: RV3153.1 99.65,37.88 99.65,38.97 v1(99.38,39.24) 99.38,40.36 98.61,41.13 98.61,42.54 98.78,42.71 98.78,43.99 98.67,44.1 98.67,44.36 UC1.AY15 ; v1(118.77,67.34) 118.77,65.08 117.91,64.22 117.91,61.88 117.08,61.06 117.08,59.59 115.27,57.78 v1(115.27,57.12) ; UV2.1 105.58,124.35 105.69,124.24 105.95,124.24 106.45,123.73 106.45,119.41 105.18,118.14 v1(103.91,118.14)
RGND_RT3661: length 27.4
  TOP w0.102: v2(151.96,46.33) PC987.1
  TOP w0.254: v1(154.9,50.5) 154.82,50.5 154.22,49.9 PR827.2 ; PR823.2 PC987.1 153.25,46.74 v1(153.51,47) ; PR820.1 157.62,37.29 v1(157.62,37.3) 157.43,37.5 PC814.2
  IN1 w0.254: v1(157.62,37.3) 157.62,38.84 157.13,39.33 157.13,42.22 157.7,42.79 157.7,44.16 157.13,44.73 157.13,47.37 155.07,49.43 155.07,50.33 v1(154.9,50.5) 154.59,50.5 154.4,50.31 154.4,48.24 153.51,47.35 v1(153.51,47)
  BOTTOM w0.203: v1(153.51,47) 153.51,46.73 154.07,46.16 PU801.4
  BOTTOM w0.254: PC818.2 154.05,47.88 153.51,47.34 v1(153.51,47)
RGND_VGA: length 5.7
  TOP w0.102: v2(60.11,104.16) 59.86,104.41 PR1019.1
  TOP w0.254: PC1006.1 57.33,104.41 v1(57.28,104.46) ; PC1006.1 PC1011.1 57.2,103.48 PR1014.2 ; PC1006.1 PR1019.1
  BOTTOM w0.203: v1(57.28,104.46) 57.14,104.6 PU1001.2
RJ45_RX1+: length 12.7
  IN2 w0.178: v1(16.95,124.4) 16.81,124.26 16.43,124.26 16.27,124.43 16.27,126.66 15.84,127.09 15.08,127.09 14.44,127.73 14.44,127.73 JLAN1.3
  BOTTOM w0.267: TL1.17 21.42,124.05 21.14,123.77 18.54,123.77 18.01,124.3 17.05,124.3 v1(16.95,124.4)
RJ45_RX1-: length 12.8
  IN2 w0.178: v1(16.95,123.82) 16.81,123.96 16.31,123.96 15.97,124.3 15.97,126.54 15.71,126.79 15.32,126.79 14.02,125.49 JLAN1.6
  BOTTOM w0.267: v1(16.95,123.82) 17.05,123.92 17.85,123.92 18.39,123.39 21.02,123.39 21.36,123.05 TL1.16
RJ45_TX0+: length 17.7
  IN2 w0.178: v1(18.99,120.84) 18.85,120.7 18.49,120.7 18.3,120.88 18.3,127.17 15.08,130.4 14.12,130.4 13.5,129.77 JLAN1.1
  BOTTOM w0.267: TL1.14 21.31,121.05 21,120.74 19.09,120.74 v1(18.99,120.84)
RJ45_TX0-: length 17.8
  IN2 w0.178: JLAN1.2 13.78,128.99 13.78,129.62 14.25,130.09 14.95,130.09 18,127.04 18,120.76 18.36,120.4 18.85,120.4 v1(18.99,120.26)
  BOTTOM w0.267: v1(18.99,120.26) 19.09,120.36 21.01,120.36 21.32,120.05 TL1.13
RJ45_TX2+: length 9.7
  BOTTOM w0.267: TL1.20 21.12,127.05 20.14,126.07 15.71,126.07 15.39,126.39 15.39,126.83 15.13,127.09 14.4,127.09 JLAN1.4
RJ45_TX2-: length 9.7
  BOTTOM w0.267: TL1.19 20.65,126.05 20.3,125.69 JLAN1.5
RJ45_TX3+: length 15.9
  IN1 w0.178: JLAN1.7 14.39,123.65 14.77,123.27 17.17,123.27 17.5,123.6 17.5,129.19 18.02,129.7 18.47,129.7 v1(18.61,129.84)
  BOTTOM w0.267: TL1.23 21.31,130.05 21,129.74 18.71,129.74 v1(18.61,129.84)
RJ45_TX3-: length 15.9
  IN1 w0.178: JLAN1.8 14.02,122.37 14.51,121.89 15.04,121.89 15.27,122.12 15.27,122.78 15.46,122.97 17.3,122.97 17.81,123.47 17.81,129.06 18.14,129.4 18.47,129.4 v1(18.61,129.26)
  BOTTOM w0.267: v1(18.61,129.26) 18.71,129.36 20.95,129.36 21.26,129.05 TL1.22
RNC1N__NB: length 47.1
  TOP w0.102: v1(126.14,33.3) v2(126.14,32.68)
  IN2 w0.254: v1(160.87,41.81) 160.39,41.33 160.39,39.29 161,38.68 161,36.25 157.99,33.24 156.75,33.24 155.29,31.78 148.24,31.78 146.97,30.51 134.71,30.51 133,32.22 127.22,32.22 v1(126.14,33.3)
  BOTTOM w0.254: PH804.1 v1(126.14,33.3) ; v1(160.87,41.81) PR842.2 PR847.1
RNC1N_APU: length 44.2
  TOP w0.102: v2(133.12,52.13) 133.54,52.54 v1(133.56,52.54)
  TOP w0.254: PR846.1 v1(160.86,44.35)
  IN2 w0.254: v1(133.56,52.54) 133.7,52.68 133.7,55.15 134.33,55.78 136.3,55.78 138.83,58.31 149.99,58.31 151.14,57.17 153.46,57.17 154.27,56.35 154.27,54.46 155.3,53.43 156.49,53.43 157.19,52.74 157.19,50.64 157.76,50.07 158.71,50.07 160.23,48.56 160.23,45 160.86,44.37 v1(160.86,44.35)
  BOTTOM w0.254: v1(133.56,52.54) 133.56,51.97 PH803.1 ; v1(160.86,44.35) 160.31,44.35 PR843.2
RNC1P__NB: length 47.9
  TOP w0.102: v1(125.22,33.3) v2(124.59,33.3)
  IN2 w0.254: v1(160.87,43.08) 159.91,42.12 159.91,35.8 157.74,33.62 156.56,33.62 155.09,32.16 148.05,32.16 146.78,30.89 134.9,30.89 133.19,32.61 127.6,32.61 126.33,33.88 125.8,33.88 v1(125.22,33.3)
  BOTTOM w0.254: v1(160.87,43.08) 160.49,43.46 PR849.2 ; PH804.2 v1(125.22,33.3)
RNC1P_APU: length 43.4
  TOP w0.102: v1(134.2,52.54) v2(134.91,52.54)
  TOP w0.254: v1(160.87,43.77) 160.63,43.53 PR848.1
  IN2 w0.254: v1(134.2,52.54) 134.08,52.67 134.08,54.96 134.52,55.4 136.49,55.4 139,57.92 149.85,57.92 150.98,56.79 153.27,56.79 153.88,56.17 153.88,54.28 155.11,53.05 156.3,53.05 156.81,52.54 156.81,50.45 157.63,49.62 158.59,49.62 159.84,48.37 159.84,44.62 160.75,43.72 160.82,43.72 v1(160.87,43.77)
  BOTTOM w0.254: PH803.2 134.2,51.99 v1(134.2,52.54)
RREF: length 1.6
  TOP w0.254: UR1.2 29.39,9.57 29.85,9.11 RR1.1
RTC_CLK: length 111.6
  TOP w0.102: v1(109.2,49.41) 109.2,49.09 v2(108.68,48.58) 108.41,48.3 RC83.2 105.65,48.3 RC84.1 105.18,48.28 v1(104.36,49.1)
  TOP w0.127: R245.2 175.41,40.9 v1(175.54,40.77)
  IN2 w0.127: v1(116.21,46.32) 117.19,47.3 117.19,54.34 119.71,56.86 129.5,56.86 131.09,58.45 136.81,58.45 138.19,59.83 139.97,59.83 140.68,60.55 149.65,60.55 150.52,59.67 150.52,59.31 151.54,58.29 153.99,58.29 154.21,58.07 155.23,58.07 160.29,53.01 161.93,53.01 163.03,51.91 163.03,47.08 164.37,45.75 164.37,41.58 162.54,39.76 162.54,37.53 166.07,34 171.67,34 175.86,38.19 175.86,38.8 175.76,38.91 175.76,40.56 v1(175.54,40.77)
  BOTTOM w0.102: UC1.AN4 104.37,48.99 104.36,49 v1(104.36,49.1)
  BOTTOM w0.127: v1(109.2,49.41) 109.2,48.94 110.2,47.93 110.73,47.93 112.83,45.84 115.72,45.84 v1(116.21,46.32)
S5_MUX_CTRL: length 121.1
  TOP w0.102: v2(148.99,24.43) 148.74,24.67 v1(148.74,26.7)
  IN1 w0.254: v1(82.32,31.94) 82.32,30.95 83.04,30.24 84.69,30.24 85.75,29.18 88.93,29.18 90.45,27.65 102.33,27.65 106.2,23.78 120.3,23.78 122.01,25.49 134.84,25.49 137.29,23.04 144.93,23.04 148.58,26.7 v1(148.74,26.7)
  IN2 w0.254: v1(102.23,54.59) 102.23,54.8 101.89,55.15 100.7,55.15 100.36,54.8 100.36,54.12 100.08,53.84 100.08,52.47 99.78,52.17 93.33,52.17 92.18,51.03 91.45,51.03 91.16,50.74 91.16,50.19 91.26,50.09 91.26,49.46 90.93,49.14 90.04,49.14 89.76,48.86 89.76,47.3 89.74,47.28 89.74,46.45 89.64,46.35 89.64,43.53 90.4,42.77 90.4,41.99 92.59,39.81 92.59,38.12 91.44,36.97 88.33,36.97 83.68,32.32 82.71,32.32 v1(82.32,31.94)
  BOTTOM w0.102: v1(148.74,26.7) 148.45,26.7 148.29,26.54 RC152.1 QC22.5
  BOTTOM w0.254: UC1.AA7 102.23,54.62 v1(102.23,54.59)
SA0_DIM1: length 7
  TOP w0.102: v1(31.87,24.06) 31.96,24.15 RD202.2 32.54,23.39 RD205.1 32.84,23.59 32.84,23.63 33.38,24.16 v2(34.48,24.16)
  BOTTOM w0.102: v1(31.87,24.06) 31.87,24.05 31.62,24.05 31.1,23.54 JDIMM1.256
SA1_DIM1: length 6.1
  TOP w0.102: v2(30.17,23.88) 30.36,23.88 30.62,24.15 RD203.2 RD206.1 31.74,23.35 v1(31.87,23.48)
  BOTTOM w0.102: v1(31.87,23.48) 30.93,22.54 JDIMM1.260
SA2_DIM1: length 5.2
  BOTTOM w0.102: v2(25.87,43.2) 25.87,44.04 26.25,44.42 RD204.2
  BOTTOM w0.305: 26.96,45.3 27.69,46.03 JDIMM1.166
  BOTTOM w0.381: RD204.2 RD207.1 26.93,45.27 26.96,45.3
SATA_ACT#: length 10.8
  BOTTOM w0.102: RPC12.7 87.15,37.06 87.43,36.77 87.84,36.77 88.12,37.05 88.12,37.46 v2(89.05,38.39) 90.76,40.1 90.76,41.51 90.38,41.88 90.38,43.92 90.53,44.07 90.53,44.34 90.22,44.66 UC1.AY30
SATA_ARX_C_DTX_N0: length 10
  BOTTOM w0.102: JHDD1.6 180.45,20.81 180.59,20.68 181.1,20.68 182.06,21.64 182.06,23.34 179.38,26.02 178.95,26.02 178.84,25.91 178.84,25.16 178.73,25.05 C235.2
SATA_ARX_C_DTX_P0: length 10.1
  BOTTOM w0.102: C236.2 178.6,26.25 179.48,26.25 182.3,23.44 182.3,21.54 181.19,20.44 180.57,20.44 180.44,20.31 JHDD1.5
SATA_ARX_DTX_N0: length 130.3
  IN2 w0.127: v1(176.23,25.14) 176.23,25.15 176.44,25.36 176.56,25.36 176.77,25.15 176.77,24.97 176.57,24.77 176.57,24.61 176.75,24.43 176.95,24.43 177.13,24.61 177.31,24.61 177.58,24.34 177.58,18.4 175.29,16.11 175.29,14.92 168.03,7.66 135.61,7.66 134.7,6.74 113.15,6.74 107.8,12.1 104.7,12.1 100.41,16.39 100.41,22.46 99.37,23.49 99.37,26.44 99.5,26.57 99.72,26.57 99.84,26.45 99.84,25.86 99.93,25.77 100.24,25.77 100.35,25.87 100.35,26.22 v1(100.28,26.28)
  BOTTOM w0.102: v1(176.23,25.14) 176.45,25.35 177.07,25.35 C235.1 ; v1(100.28,26.28) 100.28,26.28 99.47,26.28 99.14,26.61 99.14,28.3 99.99,29.15 99.99,33.64 101.15,34.8 101.15,40.68 99.87,41.96 99.87,44 99.81,44.16 99.81,44.36 UC1.AY12
SATA_ARX_DTX_N1: length 155.6
  IN2 w0.127: v1(183.11,56.12) 182.95,56.28 182.56,56.28 181.39,57.45 179.77,57.45 177.76,55.45 177.76,51.17 178.65,50.28 178.65,38.21 173.19,32.74 173.19,25.44 173.54,25.08 173.54,21.21 172.37,20.04 172.37,15.14 169.32,12.1 162.39,12.1 161.89,11.59 155.34,11.59 153.98,10.23 135.04,10.23 133.77,8.97 114.16,8.97 108.8,14.32 105.63,14.32 102.76,17.18 v1(102.76,23.26)
  BOTTOM w0.102: UC1.BA8 102.32,42.8 103.02,42.1 103.02,35.21 103.41,34.83 103.41,27.55 103.3,27.45 102.92,27.45 102.82,27.35 102.82,27.15 102.92,27.05 103.3,27.05 103.41,26.95 103.41,24.53 102.76,23.89 v1(102.76,23.26) ; v1(183.11,56.12) 183.28,56.29 183.45,56.29 183.54,56.2 JODD2.5
SATA_ARX_DTX_P0: length 130.3
  IN2 w0.127: v1(100.28,26.88) 99.37,26.88 99.06,26.57 99.06,23.36 100.09,22.33 100.09,16.26 104.57,11.78 107.67,11.78 113.02,6.43 134.83,6.43 135.74,7.35 168.16,7.35 175.61,14.79 175.61,15.98 177.89,18.27 177.89,24.47 176.99,25.37 176.69,25.67 176.28,25.67 v1(176.23,25.72)
  BOTTOM w0.102: C236.1 177.03,25.59 176.36,25.59 v1(176.23,25.72) ; v1(100.28,26.88) 100.28,27.07 100.19,27.16 99.98,27.16 99.88,27.06 99.88,26.57 99.82,26.52 99.57,26.52 99.38,26.71 99.38,28.2 100.23,29.05 100.23,33.54 101.39,34.7 101.39,40.78 100.11,42.06 100.11,42.37 100.26,42.51 100.26,42.66 100.11,42.81 100.11,42.94 100.28,43.11 100.28,43.27 100.11,43.44 100.11,43.61 100.27,43.77 100.27,43.95 100.12,44.1 UC1.BA12
SATA_ARX_DTX_P1: length 155.7
  IN2 w0.127: v1(103.37,23.26) 103.49,23.26 103.58,23.17 103.58,22.9 103.48,22.8 103.16,22.8 103.08,22.71 103.08,17.31 105.76,14.63 108.93,14.63 114.28,9.28 133.64,9.28 134.91,10.55 153.85,10.55 155.21,11.9 161.76,11.9 162.27,12.41 169.19,12.41 172.05,15.27 172.05,20.17 173.23,21.34 173.23,24.95 172.87,25.31 172.87,32.87 178.34,38.33 178.34,50.15 177.45,51.04 177.45,55.58 179.64,57.77 181.52,57.77 182.69,56.6 182.95,56.6 v1(183.1,56.75)
  BOTTOM w0.102: JODD2.6 183.59,56.7 183.41,56.53 183.31,56.53 v1(183.1,56.75) ; UC1.AY8 102.64,44.34 102.64,44.17 102.56,43.9 102.56,42.9 103.26,42.2 103.26,35.31 103.64,34.93 103.64,24.43 103,23.79 103,23.63 v1(103.37,23.26)
SATA_ATX_C_DRX_N0: length 6.4
  BOTTOM w0.102: JHDD1.8 180.46,21.81 180.59,21.94 181.22,21.94 181.59,22.31 181.59,23.1 180.53,24.16 C234.2
SATA_ATX_C_DRX_P0: length 6.5
  BOTTOM w0.102: C233.2 178.54,23.02 178.75,23.02 178.98,23.25 178.98,23.82 179.09,23.92 180.43,23.92 181.35,23 181.35,22.41 181.12,22.18 180.56,22.18 180.43,22.31 JHDD1.9
SATA_ATX_DRX_N0: length 123.6
  IN2 w0.127: v1(100.28,24.12) 100.77,24.12 100.94,23.95 100.94,16.61 104.92,12.63 108.02,12.63 113.37,7.28 134.48,7.28 135.41,8.21 167.83,8.21 174.7,15.09 174.7,16.3 176.88,18.47 176.88,23.6 176.54,23.94 v1(175.98,23.94)
  BOTTOM w0.102: UC1.AY10 101.48,44.46 101.53,44.32 101.53,44.12 101.47,43.97 101.47,42.22 102.07,41.61 102.07,34.3 101.04,33.27 101.04,29.17 101.49,28.72 101.49,24.72 101.14,24.37 100.53,24.37 v1(100.28,24.12) ; C234.1 177.03,23.82 176.11,23.82 v1(175.98,23.94)
SATA_ATX_DRX_N1: length 158.9
  IN2 w0.127: v1(102.92,25.15) 102.92,24.92 102.82,24.82 102.59,24.82 102.5,24.91 102.5,25.33 102.41,25.43 102.19,25.43 102.1,25.33 102.1,17.09 105.4,13.79 108.58,13.79 113.93,8.44 134,8.44 134.93,9.37 161.9,9.37 164.04,11.52 169.5,11.52 172.94,14.96 172.94,19.78 174.08,20.92 174.08,25.63 173.76,25.94 173.76,32.55 179.22,38.01 179.22,50.47 178.3,51.39 178.3,55.22 179.99,56.92 181.17,56.92 181.88,56.21 181.88,55.96 182.27,55.57 182.27,55.06 182.33,55 182.6,55 182.7,54.89 182.7,54.63 182.83,54.5 183,54.5 183.14,54.64 v1(183.14,54.76)
  BOTTOM w0.102: JODD2.2 183.66,54.7 183.51,54.56 183.33,54.56 v1(183.14,54.76) ; v1(102.92,25.15) 102.87,25.1 102.67,25.1 102.56,25.21 102.56,25.52 102.06,26.02 102.06,31.47 102.71,32.12 102.71,33.86 102.51,34.06 102.51,41.73 101.79,42.44 101.79,43.49 101.87,43.57 101.87,43.76 UC1.BA9
SATA_ATX_DRX_P0: length 123.6
  IN2 w0.127: v1(175.98,23.35) 176.26,23.63 176.41,23.63 176.56,23.48 176.56,22.93 176.44,22.8 176.25,22.8 176.12,22.68 176.12,22.42 176.25,22.3 176.44,22.3 176.56,22.17 176.56,18.6 174.39,16.43 174.39,15.22 167.7,8.52 135.28,8.52 134.35,7.59 113.5,7.59 108.15,12.94 105.05,12.94 101.25,16.74 101.25,24.08 100.9,24.43 100.56,24.43 100.28,24.71 v1(100.28,24.94)
  BOTTOM w0.102: UC1.BA10 101.25,44.24 101.25,44.39 101.16,44.55 101.03,44.55 101,44.52 100.91,44.37 100.91,44.08 101.23,43.77 101.23,42.12 101.84,41.51 101.84,34.4 100.8,33.37 100.8,29.07 101.25,28.62 101.25,24.82 101.04,24.6 100.38,24.6 100.28,24.71 v1(100.28,24.94) ; v1(175.98,23.35) 176.21,23.58 177.07,23.58 C233.1
SATA_ATX_DRX_P1: length 158.9
  IN2 w0.127: v1(183.15,54.11) 183.07,54.19 182.7,54.19 181.96,54.93 181.96,55.44 181.57,55.83 181.57,56.08 181.04,56.61 180.12,56.61 178.61,55.1 178.61,51.52 179.54,50.6 179.54,37.88 174.08,32.42 174.08,26.07 174.39,25.76 174.39,20.79 173.25,19.65 173.25,14.83 169.63,11.21 164.17,11.21 162.02,9.06 135.06,9.06 134.12,8.12 113.8,8.12 108.45,13.47 105.28,13.47 101.79,16.96 101.79,25.46 102.06,25.74 v1(102.92,25.74)
  BOTTOM w0.102: UC1.AY9 102.1,43.96 102.1,43.47 102.03,43.39 102.03,42.54 102.75,41.83 102.75,34.16 102.95,33.95 102.95,32.02 102.3,31.37 102.3,26.12 102.68,25.74 v1(102.92,25.74) ; v1(183.15,54.11) 183.36,54.32 183.49,54.32 183.61,54.2 JODD2.1
SATA_ZVDDP: length 2.4
  TOP w0.102: RC89.1 99.51,48.47 99.37,48.61 v2(99.37,49.17)
  TOP w0.203: v1(100.18,48.03) 100.08,48.12 RC89.1
  BOTTOM w0.203: v1(100.18,48.03) 100.51,48.36 UC1.AP11
SATA_ZVSS: length 3.7
  TOP w0.102: RC88.1 100.43,44.04 v2(100.8,43.67)
  TOP w0.203: RC88.1 100.43,45.26 100.17,45.53 v1(100.17,46.45)
  BOTTOM w0.203: UC1.AU11 100.67,46.75 100.37,46.45 v1(100.17,46.45)
SD_CD_N: length 23.1
  TOP w0.102: JSD1.10 20.27,28 v1(20.87,27.4) ; v1(26.32,13.49) 26.32,13.49 UR1.10
  IN2 w0.127: v1(26.32,13.49) 26.32,12.98 26,12.67 23.65,12.67 23.01,13.3 23.01,16.54 19.84,19.72 19.84,26.37 v1(20.87,27.4)
SD_CLK: length 14.6
  TOP w0.102: v1(20.16,18.64) 20.16,19.69 19.78,20.07 JSD1.5 ; RR5.2 CR3.1 21.69,8.27 21.36,8.6 v2(21.36,8.74) v1(21.36,10.44)
  IN2 w0.127: v1(21.36,10.44) 21.36,17.43 v1(20.16,18.64)
SD_CLK_R: length 1.4
  TOP w0.102: RR5.1 23.26,9.07 UR1.18
SD_CMD: length 15.9
  TOP w0.102: JSD1.2 19.94,12.57 20.86,11.65 20.86,7.56 20.96,7.46 21.68,7.46 21.79,7.36 21.79,6.77 21.89,6.67 22.09,6.67 22.19,6.77 v2(22.19,6.98) 22.19,7.36 22.29,7.46 22.52,7.46 22.62,7.36 22.62,6.77 22.72,6.67 22.93,6.67 23.03,6.77 23.03,7.36 23.13,7.46 23.77,7.46 23.87,7.56 23.87,8.18 23.98,8.29 24.18,8.29 24.28,8.18 24.28,7.56 24.38,7.46 25.55,7.46 25.82,7.73 UR1.20
SD_D0: length 16.7
  TOP w0.102: JSD1.7 v1(20.45,25.07) ; UR1.13 24.11,11.57 23.66,12.02 v1(23.66,13.48)
  IN2 w0.127: v1(23.66,13.48) 23.51,13.63 23.51,16.74 20.45,19.8 v1(20.45,25.07)
SD_D1: length 17.8
  TOP w0.102: JSD1.8 v1(20.87,26.7) ; UR1.12 25.32,13.18 v1(25,13.51)
  IN2 w0.127: v1(20.87,26.7) 20.98,26.59 20.98,19.84 24.07,16.76 24.07,14.43 v1(25,13.51)
SD_D2: length 16.8
  TOP w0.102: JSD1.9 19.6,7.57 20.16,7.02 20.16,6.63 20.83,5.96 20.83,5.53 20.93,5.43 21.14,5.43 21.24,5.53 21.24,5.96 21.34,6.06 21.54,6.06 21.64,5.96 21.64,5.53 21.74,5.43 21.95,5.43 22.05,5.53 22.05,5.96 22.15,6.06 22.35,6.06 22.46,5.96 22.46,5.53 22.56,5.43 22.76,5.43 22.86,5.53 22.86,5.96 22.96,6.06 23.17,6.06 23.27,5.96 23.27,5.53 23.37,5.43 23.57,5.43 23.68,5.53 23.68,5.96 23.78,6.06 23.98,6.06 24.08,5.96 24.08,5.53 24.18,5.43 24.39,5.43 24.49,5.53 24.49,5.96 24.59,6.06 24.79,6.06 24.89,5.96 24.89,5.53 25,5.43 25.2,5.43 25.3,5.53 25.3,5.96 25.4,6.06 v2(25.71,6.06) 26.43,6.06 27.32,6.95 UR1.23
SD_D3: length 16.1
  TOP w0.102: UR1.22 26.82,6.88 26.31,6.37 26,6.37 25.9,6.47 25.9,6.91 25.8,7.02 25.59,7.02 25.49,6.91 25.49,6.47 25.39,6.37 25.06,6.37 24.96,6.47 24.96,7.05 24.85,7.16 24.65,7.16 24.55,7.05 24.55,6.47 24.45,6.37 v2(24.35,6.37) 24.24,6.37 24.14,6.47 24.14,7.05 24.04,7.16 23.84,7.16 23.74,7.05 23.74,6.47 23.64,6.37 20.86,6.37 20.47,6.75 20.47,9.56 19.96,10.07 JSD1.1
SD_WP: length 19.9
  TOP w0.102: v1(20.87,28.16) 19.83,29.2 JSD1.11 ; UR1.11 v1(25.82,14.69)
  IN2 w0.127: v1(25.82,14.69) 24.65,15.85 24.65,16.8 21.36,20.08 21.36,27.67 v1(20.87,28.16)
SDREG: length 1.2
  TOP w0.102: v2(22.81,11.08) 23.18,10.71 CR4.2
SERIRQ: length 119.8
  TOP w0.102: v1(149.72,57.36) 149.72,57.69 v2(149.42,57.99) 148.66,58.76 148.66,60.1 148.38,60.38 147.48,60.38 v1(146.95,59.86) ; U11.3 177.24,52.12 v1(176.81,52.54)
  IN1 w0.127: v1(91.04,42.74) 91.4,43.1 91.4,43.66 93.27,45.53 94,45.53 95.04,46.57 95.04,47.12 95.45,47.54 98.84,47.54 99.33,48.03 99.33,50.89 100.51,52.06 100.51,54.93 100.79,55.21 105.18,55.21 105.63,54.77 107.85,54.77 108.55,55.47 109.69,55.47 110.28,56.05 113.16,56.05 116.68,52.53 116.68,50.51 120.04,47.15 125.31,47.15 126.9,48.73 126.9,51.08 130.33,54.51 130.33,56.16 133.57,59.4 146.5,59.4 v1(146.95,59.86)
  BOTTOM w0.102: v1(176.81,52.54) 175.29,54.07 170.33,54.07 169.95,53.69 165.43,53.69 164.59,54.53 160.25,54.53 159.86,54.13 159.44,54.13 158.33,55.24 158.33,56.74 157.52,57.54 149.91,57.54 v1(149.72,57.36) ; UC1.AV27 91.71,45.96 91.26,45.51 91.26,45.28 91,45.02 91,44.76 91.07,44.69 91.07,44.43 91,44.36 91,44.06 91.16,43.9 91.16,42.87 v1(91.04,42.74)
SET1_RT3661: length 3.2
  TOP w0.254: PR839.2 157.06,45.26 PR836.2 158.38,44.61 v1(158.4,44.62)
  BOTTOM w0.203: PU801.13 157.73,44.12 158.23,44.62 v1(158.4,44.62)
SET_VGA: length 4
  TOP w0.102: v2(53.65,105.47) 53.18,105.94 v1(53.18,106.63)
  BOTTOM w0.203: PR1004.1 PR1013.2 52.68,106.14 v1(53.18,106.63) 53.39,106.63 53.61,106.85 PU1001.11
SNB_APU: length 0.7
  BOTTOM w0.102: v2(140.36,42.02) 140.08,42.3 139.8,42.3
SNB_APU_NB: length 0.9
  TOP w0.102: v1(129.72,34.3) v3(130.6,34.3)
SNB_VGA1: length 1.6
  BOTTOM w0.102: PR1034.2 v2(67.85,99.93)
SNUB_1.35V: length 1.8
  BOTTOM w0.102: PR904.2 v2(42.7,143.54)
SNUB_1V: length 1.8
  BOTTOM w0.102: PR605.2 v2(74.45,18.25)
SPK_L1-: length 45.9
  TOP w0.127: LA7.1 39.72,14.36 v3(39.26,14.81)
  IN1 w1.016: 39.91,12.48 40.22,12.16 40.22,9.05 39.21,8.03 37.68,8.03 36.41,6.76 19.9,6.76 17.05,9.62 12.28,9.62 9.22,12.68 9.22,18.88
  vias: v1(9.76,21.15) v1(9.76,20.57) v1(39,13.21) v1(39,12.62)
SPK_L1-_CONN: length 3.4
  TOP w0.127: LA7.2 v3(41.11,14.9)
  IN1 w1.016: 42.38,11.78 42.38,10.06
  vias: v1(41.43,8.95) v1(42.04,8.95) v1(43.33,12.64) v1(43.33,12.04)
SPK_L2+: length 35.5
  TOP w0.127: v1(38.36,9.62) v3(37.43,9.62)
  IN1 w1.016: 10.75,18.7 10.75,13.7 13.17,11.27 17.62,11.27 20.6,8.29 35.78,8.29 37.1,9.61 37.52,9.61
  vias: v1(10.34,21.15) v1(10.34,20.57) v1(38.99,9.62)
SPK_L2+_CONN: length 1.9
  TOP w0.102: LA8.2 41.11,9.86 v3(39.85,8.6)
SPK_R1-: length 56.5
  TOP w0.102: LA5.1 v2(47.78,14.9)
  IN1 w1.016: 7.7,19.07 7.7,11.88 14.34,5.24 37.05,5.24 38.07,6.25 44.73,6.25 46.7,8.22 46.7,11.84 47.46,12.6
  vias: v1(9.1,21.18) v1(9.1,20.59) v1(48.5,13.26) v1(48.5,12.67)
SPK_R1-_CONN: length 4
  TOP w0.127: 46.38,13.26 46.38,14.66 v3(46.12,14.93)
  IN1 w1.016: 45.18,11.78 45.18,9.81 44.99,9.62
  vias: v1(43.97,8.95) v1(44.06,12.64) v1(44.06,12.04) v1(44.6,8.95)
SPK_R2+: length 58.7
  TOP w0.102: v2(48.87,11.47) 48.49,11.09 v1(48.49,10.29)
  IN1 w1.016: 48.22,8.41 48.22,7.33 45.62,4.73 38.7,4.73 37.68,3.71 13.6,3.71 6.17,11.14 6.17,19.22 7.31,20.35
  vias: v1(8.41,21.15) v1(8.41,20.54) v1(48.49,9.7)
SPK_R2+_CONN: length 2
  TOP w0.102: v3(46.95,8.27) 46.38,8.84 46.38,10.03
SUSCLK_R: length 4.8
  TOP w0.102: R245.1 175.41,42.75 v1(175.62,42.95) 175.62,44.48 v2(175.88,44.75)
  BOTTOM w0.102: JWLAN1.50 175.37,43.2 v1(175.62,42.95)
SUSP: length 8.3
  TOP w0.102: Q412.1 33.17,118.13 R934.2 32.35,118.95 v3(31.5,118.95) 31.04,118.95 30.14,118.05 Q411.2
SUSP#: length 352
  TOP w0.102: RP4.5 170.83,43.36 170.94,43.48 172.11,43.48 172.89,44.25 172.89,44.89 173.95,45.95 173.95,46.53 173.38,47.1 173.38,48.23 v1(173.19,48.42) 172.24,48.42 171.9,48.75 U11.116 ; R941.1 86.69,30.51 v1(86.39,30.51) ; v1(25.24,66.45) 24.83,66.45 v2(24.41,66.03) ; PR510.1 36.1,119.47 35.49,120.08 31.59,120.08 29.33,117.82 27.27,117.82 v1(24.35,114.9) ; U381.5 175.87,11.05 174.73,11.05 v1(174.64,11.14) 174.64,11.58 174.96,11.89 175.5,11.89 175.54,11.86 U381.3
  TOP w0.254: Q412.2 34.14,117.04 35.89,118.79 PR510.1
  IN1 w0.127: v1(86.39,30.51) 91.98,30.51 92.99,29.49 102.2,29.49 105.69,26 113.44,26 113.88,25.56 120.54,25.56 121.43,26.45 135.23,26.45 137.68,24 143.12,24 145.58,26.46 146.72,26.46 148.36,28.1 148.81,28.1 154.33,33.62 157.69,33.62 161.7,37.63 161.7,39.22 161.32,39.6 161.32,46.51 v1(161.89,47.08) ; v1(177.26,48.61) 177,48.35 177,46.9 178.18,45.72 178.18,38.68 173.89,34.38 173.89,26.07 174.95,25.01 174.95,13.35 174.59,12.99 174.59,11.19 v1(174.64,11.14)
  IN2 w0.127: v1(25.24,66.45) 25.44,66.65 25.44,91.2 18.4,98.24 18.4,105.91 20.35,107.86 20.35,109.12 21.68,110.46 21.68,112.93 23.65,114.9 v1(24.35,114.9) ; v1(86.39,30.51) 86.2,30.51 85.41,29.73 84.45,29.73 83.27,28.54 73.37,28.54 71.27,26.45 57.3,26.45 48.54,17.68 v1(38.57,17.68)
  BOTTOM w0.102: v1(161.89,47.08) 161.95,47.08 162.65,47.78 162.65,47.91 163.81,49.08 165.4,49.08 165.69,48.79 172.82,48.79 v1(173.19,48.42) 173.64,47.97 174.59,47.97 175.22,48.61 v1(177.26,48.61) ; v1(38.57,17.68) 29.87,17.68 24.22,23.33 24.22,57.37 25.36,58.51 25.36,66.32 v1(25.24,66.45)
SVC_RT3661: length 110.7
  TOP w0.102: v2(93,77.18) 93,77.16 92.5,76.65 v1(92.48,76.65)
  IN1 w0.127: v1(158.36,41.3) 159.15,42.09 159.15,48.57 158.73,48.99 157.7,48.99 156.94,49.75 156.94,56.86 155.09,58.71 155.09,60.04 154.78,60.36 152.09,60.36 150.94,61.5 138.75,61.5 138.65,61.6 136.66,61.6 136.26,61.2 129.12,61.2 128.34,61.98 124.01,61.98 119.33,66.65 118.51,66.65 117.59,67.57 113.82,67.57 111.24,70.15 110.59,70.15 105.62,75.12 103.21,75.12 98.99,79.34 98.99,82.13 95.62,85.5 v1(92.67,85.5)
  IN2 w0.127: v1(92.48,76.65) 94.33,78.49 94.33,83.85 v1(92.67,85.5)
  BOTTOM w0.102: PR833.1 92.48,75.99 v1(92.48,76.65) 92.48,77.39 PC837.1 ; v1(158.36,41.3) 158.1,41.3 157.68,41.72 PU801.19
SVD_RT3661: length 116.8
  TOP w0.102: v1(92.84,73.04) 92.84,72.86 v2(92.26,72.28)
  IN1 w0.127: v1(92.67,86.14) 95.34,86.14 99.24,82.24 99.24,79.47 103.34,75.37 105.73,75.37 110.69,70.41 111.34,70.41 113.93,67.83 117.69,67.83 118.61,66.91 119.44,66.91 124.11,62.24 133.05,62.24 133.72,61.56 136.26,61.56 136.55,61.85 138.76,61.85 138.86,61.75 151.05,61.75 152.19,60.61 154.88,60.61 155.35,60.14 155.35,58.81 157.19,56.97 157.19,49.88 157.83,49.24 158.84,49.24 159.4,48.68 159.4,41.52 v1(158.7,40.82)
  IN2 w0.127: v1(92.84,73.04) 91.95,73.93 91.95,77.69 94.07,79.81 94.07,83.66 92.8,84.93 92.48,84.93 92.23,85.18 92.23,85.69 v1(92.67,86.14)
  BOTTOM w0.102: v1(92.84,73.04) PR829.1 PC836.1 ; PU801.20 157.65,41.32 158.14,40.82 v1(158.7,40.82)
SVT_RT3661: length 4
  BOTTOM w0.102: PU801.21 156.47,39.8 157.44,38.84 PR824.1 157.66,39.05 157.66,39.54 158.05,39.93 v2(158.53,39.93)
SYS_PWRGD_EC: length 96.6
  TOP w0.102: U11.32 180.1,63.72 C834.1 180.1,63.8 179.8,64.1 177.45,64.1 176.62,63.28 175.67,63.28 174.55,62.16 174.55,60.57 173.95,59.97 173.95,52.99 174.4,52.54 v1(174.4,51.85)
  IN1 w0.127: v1(124.68,44.67) 124.9,44.44 127.37,44.44 129,46.07 129,50.17 132.36,53.54 132.36,55.21 134.39,57.24 143.81,57.24 144.41,56.65 152.71,56.65 154.08,55.28 154.08,54.96 155.02,54.02 v1(155.73,54.02)
  BOTTOM w0.102: v1(174.4,51.85) 174.27,51.72 168.75,51.72 168.1,51.07 166.83,51.07 166.52,51.38 160.96,51.38 160.29,50.7 158.59,50.7 156.92,52.37 156.92,53.43 156.34,54.02 v1(155.73,54.02) ; v1(124.68,44.67) v2(121.68,44.67) 118.54,44.67 116.45,42.58 UC24.2 113.77,42.55 111.47,42.55 111.18,42.84 RC64.1
SYS_RST#: length 9.4
  BOTTOM w0.102: RC86.1 CC162.2 113.36,50.51 111.01,50.51 RC85.2 110.25,51.27 109.69,51.27 109.49,51.47 v2(109.46,51.47) 109.32,51.47 108.3,52.49 107.17,52.49 107.04,52.37 106.16,52.37 UC1.AF1
SYSON: length 255.3
  TOP w0.102: U11.95 161.44,51.72 161.44,51.71 161.09,51.71 C193.1 160.87,51.41 R948.2 160.24,52.04 v1(159.79,52.48) ; PR508.1 37.89,119.51 v2(38.27,119.89)
  TOP w0.254: PR2223.1 49.57,7.41 49.8,7.18 v1(50.13,7.18) ; v1(42.26,118.27) 41.62,118.9 38.65,118.9 38.52,118.78 PR508.1
  IN1 w0.127: v1(159.79,52.48) 158.33,53.94 158.33,57.56 157.83,58.07 157.83,59.34 155.41,61.75 152.83,61.75 151.69,62.9 139.33,62.9 139.23,63 136.08,63 135.78,62.7 134.2,62.7 133.53,63.38 124.59,63.38 118.99,68.97 115.87,68.97 113.29,71.55 111.17,71.55 106.2,76.51 103.84,76.51 100.42,79.93 100.42,82.77 94.83,88.36 89.94,88.36 89.44,87.85 51.97,87.85 v1(51.95,87.88) 42.89,96.93 42.89,117.63 v1(42.26,118.27)
  BOTTOM w0.102: v1(50.13,7.18) 50.13,16.63 51.64,18.14 51.64,87.57 v1(51.95,87.88)
TESTEN: length 6.2
  TOP w0.102: RV154.2 RV17.2 83.61,145.45 83.61,143.91 83.45,143.76 v2(83.45,143.35) 83.45,143.29 83.57,143.17 83.77,143.17 83.97,142.97 83.97,142.26 v1(83.6,141.89)
  BOTTOM w0.102: UV1.K7 83.6,141.87 v1(83.6,141.89)
TON_DDR: length 3.2
  TOP w0.102: v1(37.68,117.12) 37.68,117.44 v2(37.98,117.73)
  TOP w0.254: PR507.2 38.31,116.5 v1(37.68,117.12)
  BOTTOM w0.203: PU501.9 36.99,116.81 37.3,117.12 v1(37.68,117.12)
TP_DISABLE#: length 52.5
  TOP w0.102: v1(164.57,61.28) 164.13,61.72 U11.70 161.55,61.72 v3(161.15,61.32)
  IN1 w0.127: v1(172.16,24.24) 172.16,24.68 171.67,25.18 171.67,28.99 169.34,31.31 169.34,41.38 169.74,41.78 169.74,47.62 168.9,48.46 168.9,49.22 167.16,50.96 167.16,55.35 164.66,57.85 164.66,59.9 164.95,60.19 164.95,60.9 v1(164.57,61.28)
  BOTTOM w0.102: v1(172.16,24.24) 173.37,24.24 174.91,22.7 174.91,19.78 175.52,19.17 JTP1.1
TP_INT#: length 143.2
  TOP w0.102: v1(101.83,49.12) 101.83,49.37 102.25,49.79 105.27,49.79 106.77,51.29 108.45,51.29 v1(108.56,51.4) ; v1(172.16,23.6) 172.58,24.02 172.58,27.23 v3(173.13,27.78)
  IN1 w0.127: v1(167.6,52.04) 167.6,50.89 169.15,49.34 169.15,48.58 169.99,47.74 169.99,41.67 169.6,41.28 169.6,31.5 171.92,29.18 171.92,25.3 172.6,24.63 172.6,24.03 v1(172.16,23.6) ; v1(155.25,56.31) 154.65,56.31 154.28,56.69 154.28,57.61 153.63,58.26 150.94,58.26 150.82,58.39 134.01,58.39 131.35,55.72 131.35,54.07 127.98,50.7 127.98,47.59 126.39,46 119.66,46 115.66,50 115.66,51.97 113.24,54.4 111.04,54.4 110.45,53.81 109.48,53.81 108.79,53.13 108.79,51.63 v1(108.56,51.4)
  IN2 w0.127: v1(101.83,49.12) 100.74,50.21 100.26,50.21 100.15,50.11 99.55,50.11 99.32,50.34 95.63,50.34 95.28,49.98 95.28,48.71 94.49,47.92 92.08,47.92 v1(91.32,47.16)
  BOTTOM w0.102: v1(155.25,56.31) 156.56,56.31 157.32,55.55 157.32,54.41 157.84,53.89 157.84,53.29 159.07,52.06 167.58,52.06 v1(167.6,52.04) ; JTP1.2 175.02,19.16 174.18,19.99 R280.2 174.65,21.44 174.65,22.57 173.27,23.96 172.52,23.96 v1(172.16,23.6) ; v1(91.32,47.16) 91.31,47.16 91.17,47.16 UC1.AR29
TSEN_APU: length 21.3
  IN2 w0.254: v1(158.37,45.24) 158.44,45.24 159.22,46.03 159.22,48.35 158.4,49.18 157.51,49.18 156.87,49.81 154.84,49.81 154.33,50.32 151.6,50.32 150.78,49.5 v1(150.78,49.18)
  BOTTOM w0.203: PR830.1 159.16,45.29 158.42,45.29 v1(158.37,45.24) 157.65,44.52 PU801.12
  BOTTOM w0.254: v1(150.78,49.18) v2(150.15,49.18) 149.82,49.18 149.51,49.5 145.84,49.5 PH802.1
TSEN_APU_R: length 20.7
  TOP w0.102: v1(150.78,48.54) v2(150.78,47.8)
  TOP w0.254: PR832.2 v1(158.66,46.91)
  IN2 w0.254: v1(158.66,46.91) 158.66,47.45 156.68,49.43 154.59,49.43 154.08,49.94 151.79,49.94 151.35,49.5 151.35,48.86 151.03,48.54 v1(150.78,48.54)
  BOTTOM w0.254: PR830.2 160.25,45.15 PC835.1 PR834.1 159.32,46.91 v1(158.66,46.91) ; PH802.2 145.84,48.99 149.38,48.99 149.82,48.54 v1(150.78,48.54)
TSEN_NB: length 30.2
  TOP w0.102: v1(135.79,33.94) v2(135.79,33.2)
  IN2 w0.254: v1(156.56,38.84) 156.38,38.84 155.67,38.13 155.67,35.02 154.21,33.56 146.8,33.56 146.04,32.8 135.92,32.8 135.66,33.05 135.66,33.81 v1(135.79,33.94)
  BOTTOM w0.203: PU801.23 155.67,39.03 PR821.1
  BOTTOM w0.254: v1(156.56,38.84) PR821.1 ; v1(135.79,33.94) 135.79,34.43 PH801.1
TSEN_NB_R: length 30.2
  TOP w0.102: v2(157.23,36.17) 156.8,36.61 v1(156.8,36.62)
  IN2 w0.254: v1(156.8,36.62) 156.11,35.93 156.11,34.83 154.46,33.18 146.96,33.18 146.19,32.42 135.73,32.42 135.28,32.86 135.28,33.81 v1(135.16,33.94)
  BOTTOM w0.254: PH801.2 135.16,34.43 v1(135.16,33.94) ; PR828.1 156.11,37.11 155.86,37.37 PR821.2 ; PR828.1 v1(156.8,36.62) PR825.1 ; PR828.1 PC834.1
TSEN_VGA: length 14.5
  TOP w0.102: v2(62.31,103.42) 62.31,103.24 61.9,102.84 v1(61.88,102.84)
  IN2 w0.254: v1(52.86,104.68) 53.11,104.68 54.51,103.28 60.61,103.28 61.05,102.84 v1(61.88,102.84)
  BOTTOM w0.203: PU1001.10 53.68,106.45 53.3,106.08 53.3,105.12 v1(52.86,104.68) 52.36,104.68 PR1003.2
  BOTTOM w0.254: v1(61.88,102.84) 62.37,102.84 PH1002.1
TSEN_VGA_R: length 16.8
  TOP w0.102: v2(62.58,102.09) 62.46,102.2 v1(61.88,102.2)
  IN2 w0.254: v1(52.73,102.46) 52.86,102.58 60.67,102.58 61.05,102.2 v1(61.88,102.2)
  BOTTOM w0.254: PR1003.1 50.4,104.49 PR1021.1 PR1026.2 49.56,103.98 50.47,103.07 52.12,103.07 v1(52.73,102.46) ; v1(61.88,102.2) 62.37,102.2 PH1002.2
UG1_APU: length 12.2
  TOP w0.102: v3(150.07,44.44) 150.52,44.44 v1(150.78,44.19)
  IN2 w1.016: 150.24,45.02 144.81,50.45 144.81,54.2
  vias: v1(144.49,55.02) v1(145.1,55.02) v1(151.26,43.86)
UG1_VGA: length 2.9
  TOP w0.102: v1(62.77,110.03) v3(62.77,109.25)
  IN2 w1.016: 59.36,110.43 61.47,110.43
  vias: v1(58.02,109.64) v1(58.45,110.08) v1(62.38,110.48)
UG_CHG: length 10.9
  TOP w0.102: v1(134.22,18.79) v3(134.22,20.31)
  IN2 w0.102: 144.75,18.52 144.93,18.52
  IN2 w0.762: 135.18,18.53 136.65,20.01 141.75,20.01 142.94,18.81 143.31,18.81
  vias: v1(134.22,18.2) v1(144.55,18.52) v1(145.15,18.52)
UG_DDR: length 7.1
  TOP w0.102: v3(36.55,112.25) 36.68,112.39 v1(37.16,112.39)
  IN2 w1.016: 37.37,105.06 38.25,105.95 38.25,111.16
  vias: v1(36.22,105.02) v1(36.22,104.42) v1(37.65,112.03)
UG_NB: length 11.8
  TOP w0.102: v1(151.26,40.61) v3(149.66,40.61)
  IN1 w1.016: 150.61,40.12 144.97,34.49 142.73,34.49
  vias: v1(142.01,34.76) v1(142.01,34.18) v1(151.82,40.86)
USB3_ARX_DTX_N1: length 160.1
  IN2 w0.127: v1(24.09,58.67) 24.23,58.81 24.51,58.81 24.73,58.58 24.73,52.67 26.26,51.15 26.26,23.46 30.44,19.28 47.84,19.28 57.93,29.37 71.72,29.37 72.49,30.13 82.08,30.13 83.25,31.31 84.1,31.31 86.27,33.48 86.93,33.48 89.2,35.76 99.41,35.76 99.83,35.33 100.61,35.33 101.47,36.19 101.47,40.71 102.45,41.69 102.45,46.06 103.96,47.57 104.39,47.57 106.52,49.69 106.52,52.36 107.98,53.82 107.98,56.74 108.14,56.9 108.54,56.9 v1(108.67,56.77)
  BOTTOM w0.102: UC1.W1 106.56,56.35 106.92,56.35 107.05,56.47 107.21,56.47 107.39,56.3 107.53,56.3 107.67,56.44 107.67,56.59 107.5,56.76 107.5,56.93 107.65,57.08 108.36,57.08 v1(108.67,56.77) ; JUSB1.5 14.1,58.78 14.3,58.98 14.71,58.98 15.48,59.75 17.8,59.75 17.93,59.62 D301.1 D301.9 19.37,59.62 19.5,59.75 21.63,59.75 22.54,58.85 23.92,58.85 v1(24.09,58.67)
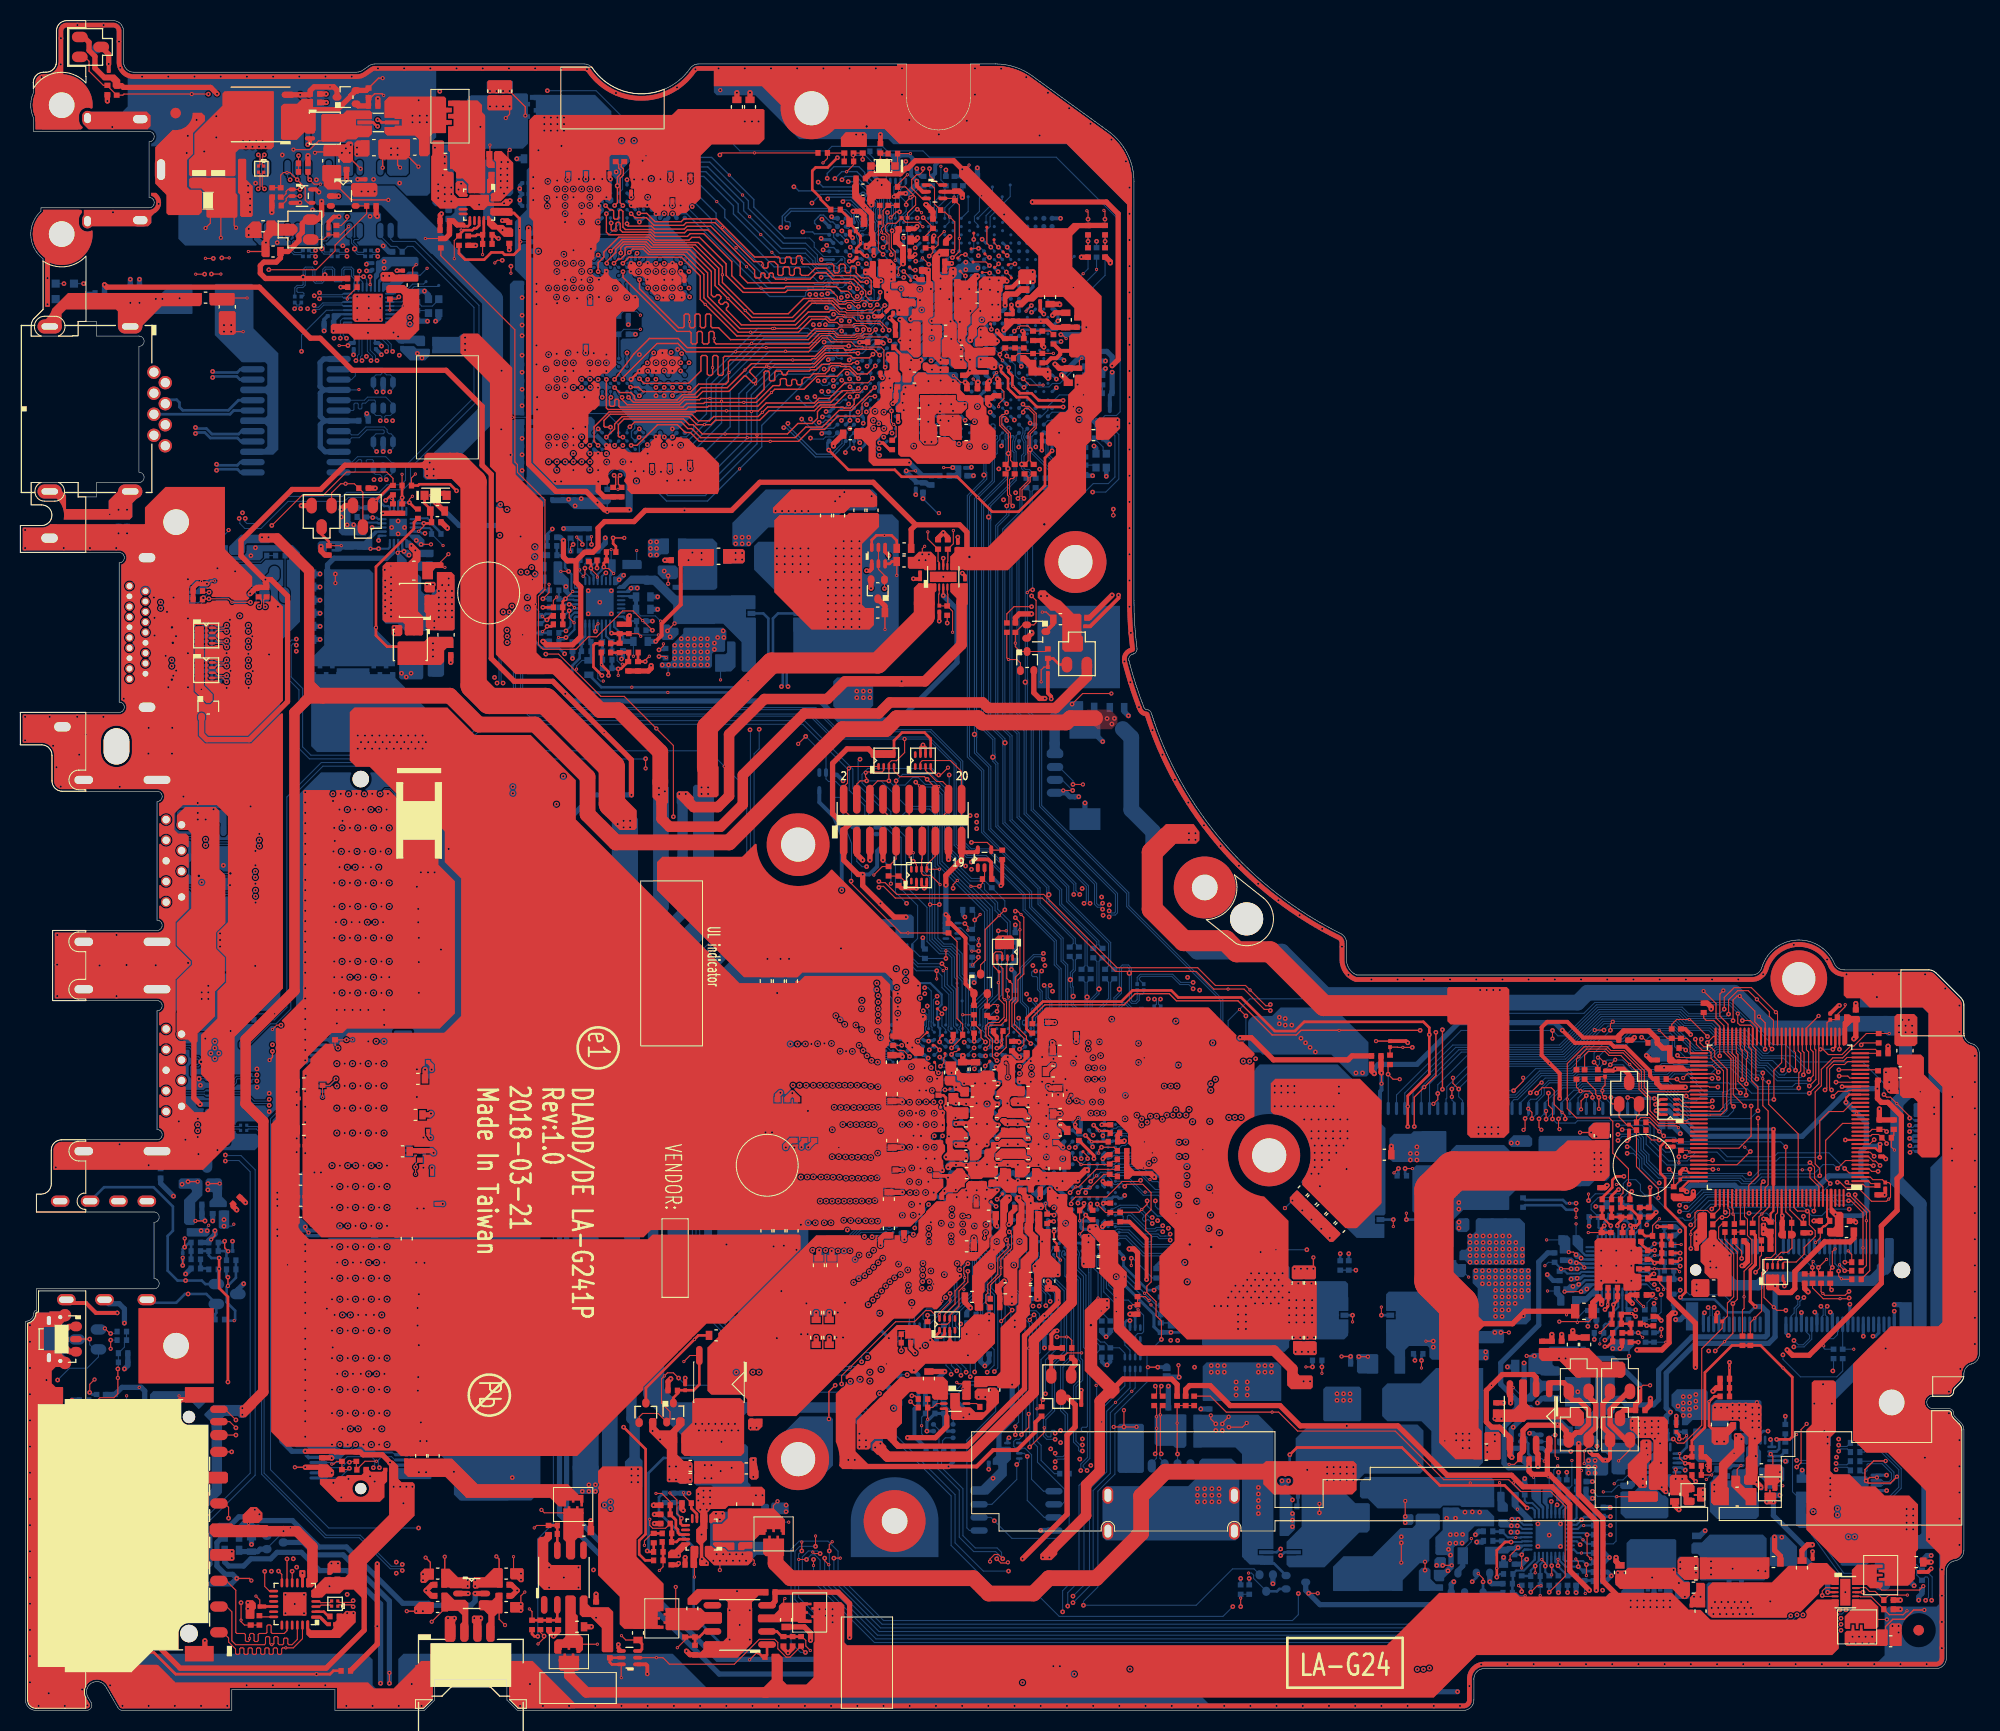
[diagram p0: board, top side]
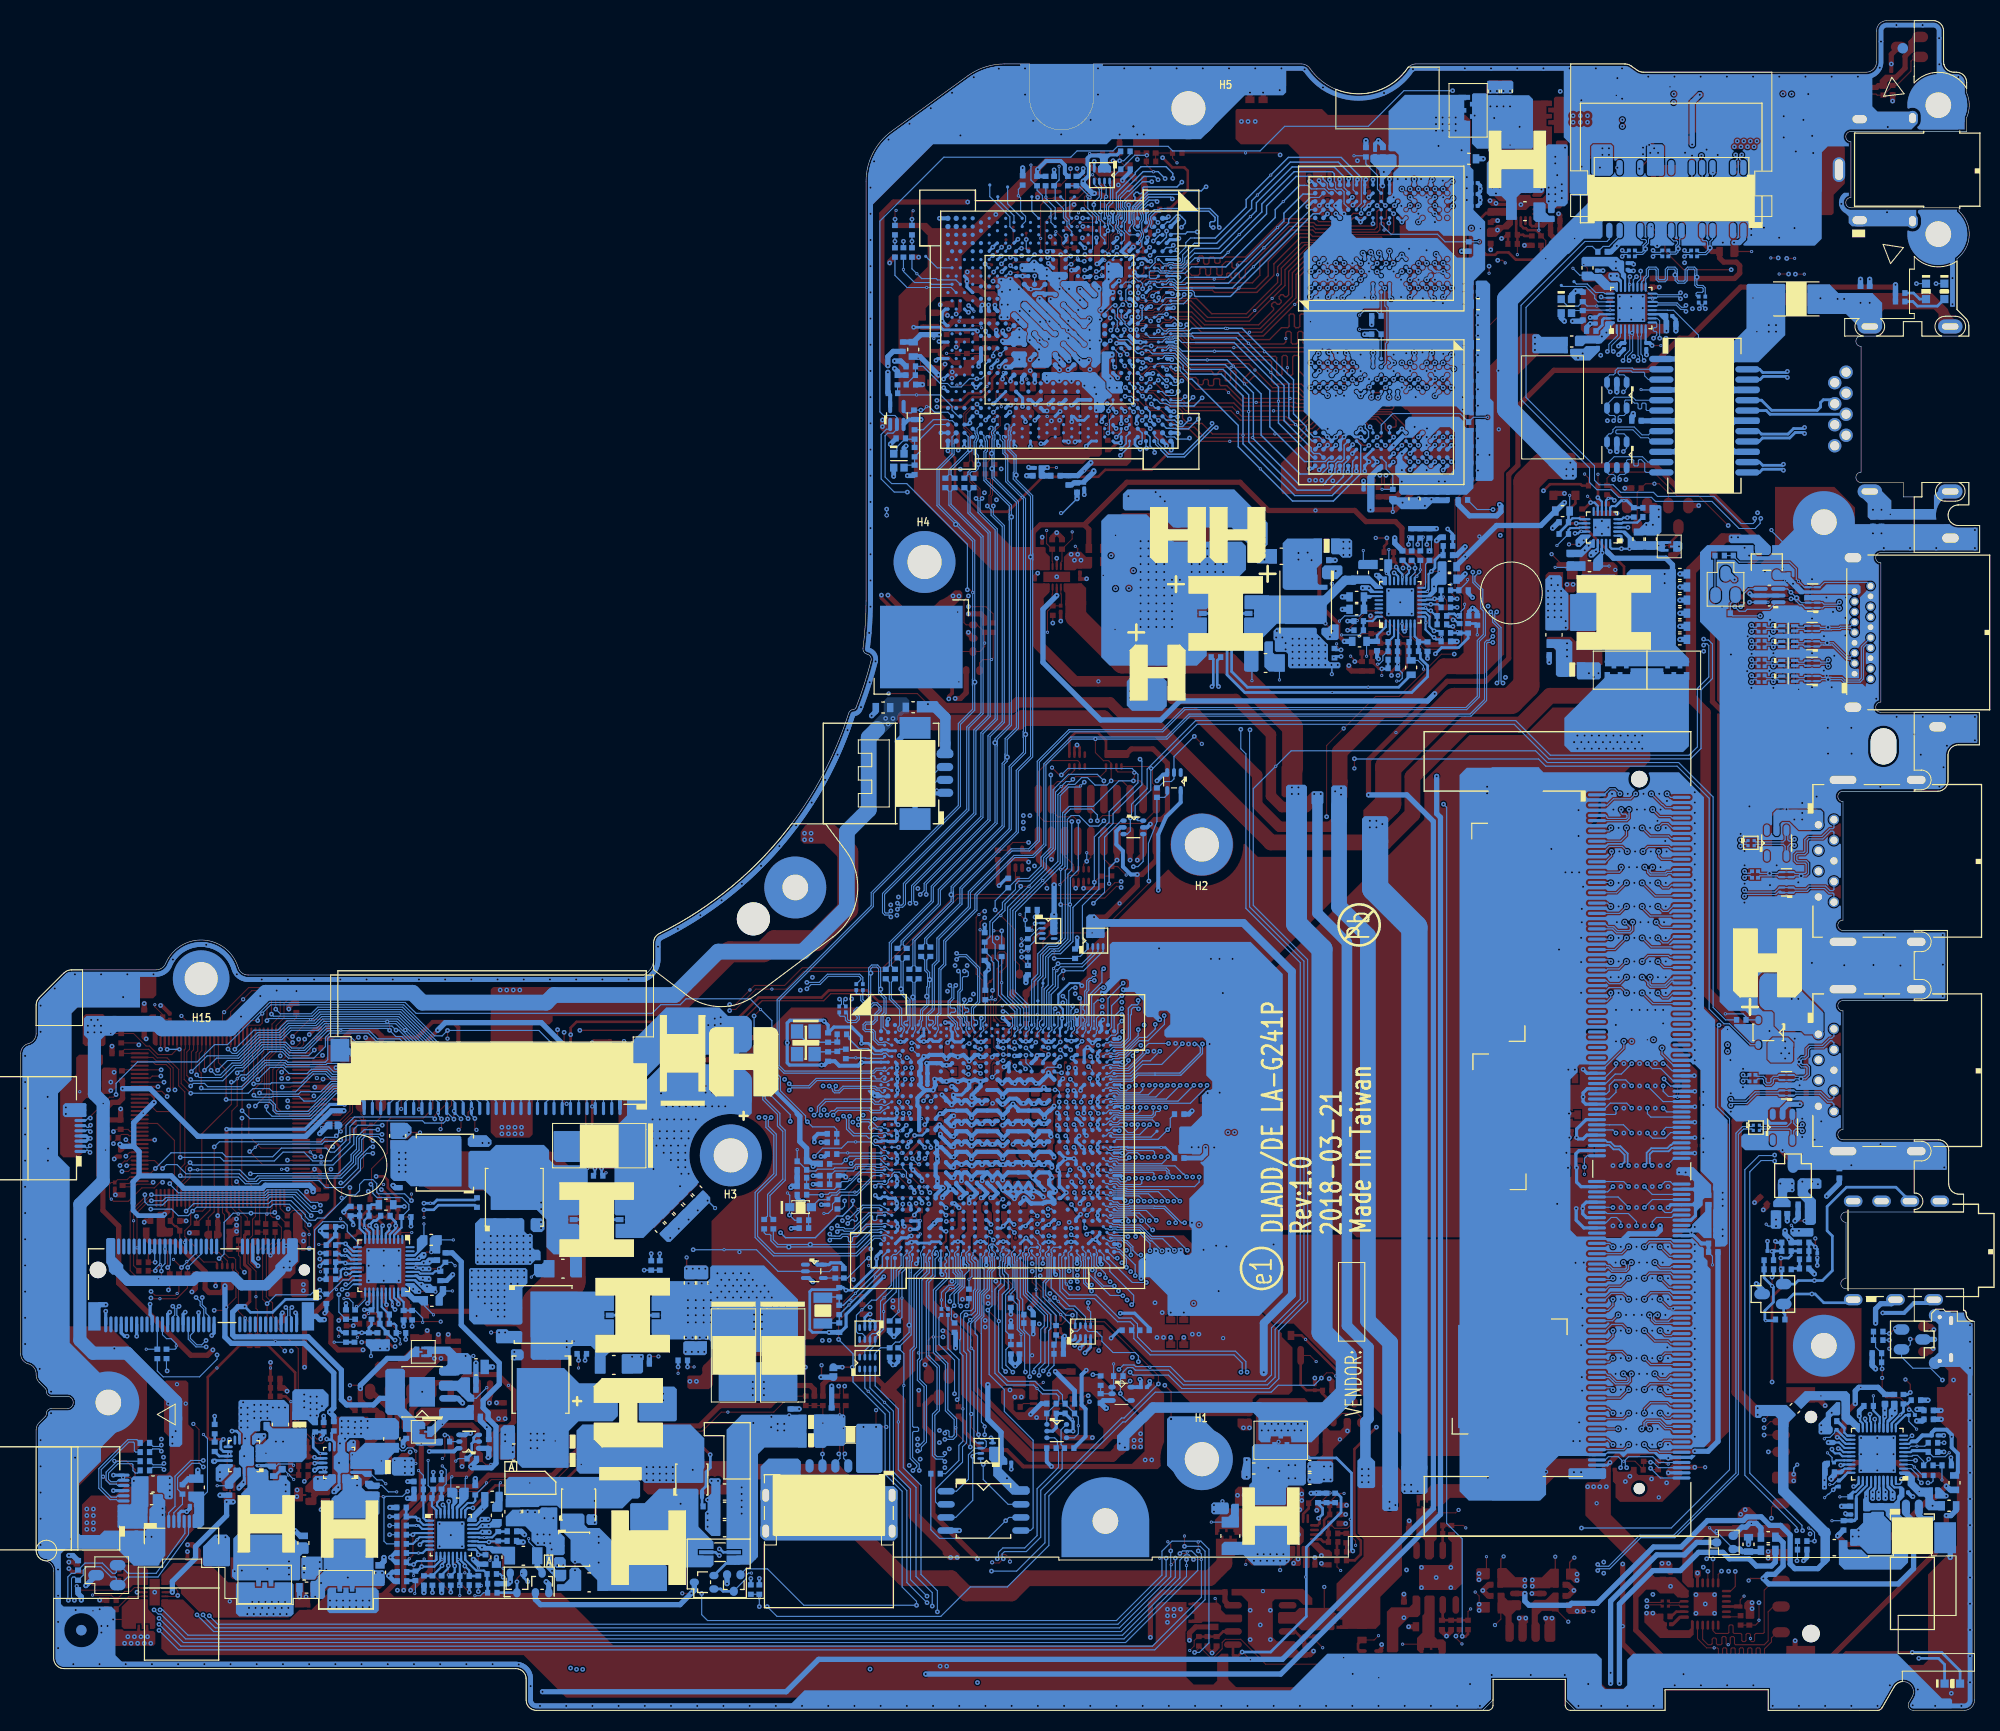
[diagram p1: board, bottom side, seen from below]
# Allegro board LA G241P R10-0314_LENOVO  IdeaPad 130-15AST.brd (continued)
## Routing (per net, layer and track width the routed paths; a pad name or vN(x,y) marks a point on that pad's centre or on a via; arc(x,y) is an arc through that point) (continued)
USB3_ARX_DTX_N2: length 185.6
  IN2 w0.127: v1(110.11,57.62) 110.11,56.83 109.45,56.17 109.45,53.79 108.59,52.93 108.59,52.04 107.77,51.22 107.77,49.6 105.65,47.48 105.65,46.41 103.85,44.61 103.85,41.75 102.42,40.32 102.42,35.8 101,34.38 98.65,34.38 98.24,34.79 89.57,34.79 85.14,30.36 84.19,30.36 83.01,29.18 72.93,29.18 72.16,28.41 58.31,28.41 48.22,18.32 30,18.32 25.31,23.01 25.31,50.63 23.78,52.17 23.78,57.35 23.21,57.91 23.21,60.06 23.51,60.36 23.51,75.81 23.97,76.27 23.97,78.77 23.79,78.95 v1(22.77,78.95)
  BOTTOM w0.102: v1(22.77,78.95) 22.6,79.12 19.72,79.12 19.41,79.43 19.27,79.43 D304.9 D304.1 17.98,79.29 17.85,79.43 16.69,79.43 16.42,79.7 15.01,79.7 14.57,79.26 14.2,79.26 14.1,79.16 JUSB2.5 ; v1(110.11,57.62) 109.82,57.33 109.82,56.37 109.16,55.71 107.89,55.71 107.65,55.48 107.44,55.48 107.21,55.71 106.79,55.71 106.62,55.54 106.29,55.54 UC1.Y1
USB3_ARX_DTX_P1: length 160.1
  IN2 w0.127: v1(24.09,59.26) 24.23,59.12 24.64,59.12 25.05,58.71 25.05,52.8 26.57,51.27 26.57,23.59 30.57,19.59 47.71,19.59 57.8,29.68 71.59,29.68 72.36,30.45 81.95,30.45 83.12,31.62 83.97,31.62 86.14,33.8 86.8,33.8 89.07,36.07 99.53,36.07 99.96,35.64 100.48,35.64 101.16,36.32 101.16,40.84 102.14,41.82 102.14,46.19 103.83,47.88 104.26,47.88 106.21,49.82 106.21,52.49 107.67,53.95 107.67,56.87 108.01,57.21 108.53,57.21 v1(108.67,57.35)
  BOTTOM w0.102: v1(108.67,57.35) 108.67,57.35 108.64,57.32 107.55,57.32 106.83,56.59 106.35,56.59 106.21,56.45 105.96,56.45 UC1.W2 ; v1(24.09,59.26) 23.92,59.09 22.63,59.09 21.73,59.99 19.5,59.99 19.37,60.12 D301.8 D301.2 17.93,60.12 17.8,59.99 15.38,59.99 14.62,59.22 14.3,59.22 14.1,59.42 JUSB1.6
USB3_ARX_DTX_P2: length 185.6
  IN2 w0.127: v1(22.77,79.53) 22.96,79.72 23.4,79.72 23.54,79.59 23.54,79.39 23.67,79.26 23.92,79.26 24.28,78.9 24.28,76.14 23.82,75.68 23.82,60.23 23.52,59.93 23.52,58.04 24.09,57.48 24.09,52.3 25.62,50.76 25.62,23.14 30.13,18.64 48.09,18.64 58.18,28.73 72.03,28.73 72.8,29.49 82.88,29.49 84.06,30.67 85.01,30.67 89.44,35.1 98.37,35.1 98.78,34.69 100.87,34.69 102.11,35.93 102.11,40.44 103.54,41.88 103.54,44.74 105.34,46.54 105.34,47.61 107.46,49.73 107.46,51.35 108.28,52.17 108.28,53.06 109.14,53.92 109.14,56.3 109.8,56.96 109.8,57.34 v1(109.51,57.62)
  BOTTOM w0.102: UC1.Y2 105.6,55.89 105.85,55.89 105.98,56.02 106.26,56.02 106.33,55.95 109.06,55.95 109.58,56.47 109.58,57.56 v1(109.51,57.62) ; JUSB2.6 14.1,79.6 14.2,79.5 14.48,79.5 14.91,79.94 16.52,79.94 16.79,79.66 17.88,79.66 18.01,79.79 D304.2 D304.8 19.39,79.79 19.82,79.36 22.6,79.36 v1(22.77,79.53)
USB3_ATX_C_DRX_N1: length 13.5
  BOTTOM w0.102: JUSB1.8 14.1,64.74 14.3,64.94 14.43,64.94 15.11,64.25 16.38,64.25 16.55,64.07 16.55,63.45 16.86,63.15 17.15,63.15 17.25,63.05 17.25,62.74 17.15,62.64 16.72,62.64 16.47,62.4 16.47,61.61 16.84,61.25 v4(17.29,61.25) 17.85,61.25 17.98,61.12 D301.4 D301.7 19.39,61.12 19.52,61.25 19.87,61.25 19.97,61.15 19.97,60.86 20.21,60.62 20.68,60.62 20.92,60.86 20.92,61.15 21.02,61.25 21.46,61.25 C301.2
USB3_ATX_C_DRX_N2: length 13.9
  BOTTOM w0.102: JUSB2.8 14.1,85.16 14.2,85.26 14.41,85.26 15.16,84.51 16.5,84.51 16.68,84.32 16.68,83.22 16.92,82.98 17.59,82.98 17.7,82.88 17.7,82.49 17.59,82.39 16.79,82.39 16.55,82.15 16.55,81.17 16.79,80.93 v4(17.27,80.93) 17.88,80.93 18.01,80.79 D304.4 D304.7 19.45,80.79 19.58,80.93 21.27,80.93 C839.2
USB3_ATX_C_DRX_P1: length 13.5
  BOTTOM w0.102: C302.2 21.56,61.49 20.92,61.49 20.68,61.25 20.68,60.96 20.58,60.86 20.31,60.86 20.21,60.96 20.21,61.25 19.96,61.49 19.54,61.49 19.41,61.62 D301.6 D301.5 17.96,61.62 17.83,61.49 16.94,61.49 16.71,61.71 16.71,62.3 16.82,62.4 17.25,62.4 17.49,62.64 v4(17.49,62.9) 17.49,63.15 17.25,63.39 16.96,63.39 16.79,63.55 16.79,64.17 16.47,64.49 15.21,64.49 14.53,65.17 14.31,65.17 14.1,65.39 JUSB1.9
USB3_ATX_C_DRX_P2: length 13.9
  BOTTOM w0.102: JUSB2.9 14.1,85.6 14.2,85.5 14.51,85.5 15.26,84.75 16.6,84.75 16.92,84.42 16.92,83.32 17.02,83.22 17.69,83.22 17.93,82.97 17.93,82.39 17.69,82.15 16.89,82.15 16.79,82.05 16.79,81.27 16.89,81.16 17.85,81.16 17.98,81.29 D304.5 D304.6 19.41,81.29 19.54,81.16 v4(20.34,81.16) 21.24,81.16 C840.2
USB3_ATX_DRX_N1: length 163.9
  IN2 w0.127: v1(111.1,57.72) 111.35,57.48 111.35,57.16 110.39,56.2 110.39,51.59 109.88,51.08 109.37,51.08 108.42,50.13 108.42,49.36 106.3,47.24 106.3,46.11 104.49,44.29 104.49,41.48 103.05,40.05 103.05,35.53 101.27,33.75 98.26,33.75 97.87,34.14 89.82,34.14 87.54,31.86 87.54,30.36 86.02,28.85 84.82,28.85 83.64,27.67 73.45,27.67 71.27,25.49 57.3,25.49 48.85,17.04 30.38,17.04 24.46,22.96 24.46,50.58 23.12,51.93 23.12,56.74 22.09,57.76 22.09,58.2 22.22,58.32 22.45,58.32 22.58,58.45 22.58,58.71 22.45,58.83 22.22,58.83 22.09,58.96 22.09,59.21 22.22,59.34 22.45,59.34 22.58,59.47 22.58,59.72 22.45,59.85 22.22,59.85 22.09,59.98 22.09,61.03 22.34,61.27 22.66,61.27 v1(22.9,61.03)
  BOTTOM w0.102: C301.1 22.5,61.2 22.73,61.2 v1(22.9,61.03) ; v1(111.1,57.72) 110.64,58.18 107.65,58.18 107.41,57.95 106.51,57.95 106.29,58.17 UC1.R2
USB3_ATX_DRX_N2: length 192.3
  IN2 w0.127: v1(112.31,57.72) 112.49,57.55 112.49,56.95 111.34,55.81 111.34,50.16 109.98,48.8 109.21,48.8 107.27,46.86 107.27,45.67 105.46,43.86 105.46,41.11 104.03,39.69 104.03,34.76 102.07,32.8 98.58,32.8 96.48,30.7 94.77,30.7 87.21,23.14 85.41,23.14 80.11,17.83 80.11,15.28 78.67,13.84 60.33,13.84 58.07,16.1 29.99,16.1 23.52,22.57 23.52,50.19 22.13,51.58 22.13,56.23 21.14,57.21 21.14,62.31 22.18,63.34 22.18,76.15 22.3,76.28 22.57,76.28 22.7,76.4 22.7,76.66 22.57,76.78 22.3,76.78 22.18,76.91 22.18,77.17 22.3,77.29 22.57,77.29 22.7,77.42 22.7,77.67 22.57,77.8 22.3,77.8 22.18,77.93 22.18,80.89 22.3,81.01 22.52,81.01 v1(22.76,80.77)
  BOTTOM w0.102: v1(22.76,80.77) 22.58,80.94 22.24,80.94 C839.1 ; v1(112.31,57.72) 112.4,57.81 112.4,58.45 111.81,59.04 107.35,59.04 107.09,58.77 106.39,58.77 106.21,58.67 106.03,58.67 UC1.P2
USB3_ATX_DRX_P1: length 163.9
  IN2 w0.127: v1(111.7,57.72) 111.66,57.68 111.66,57.03 110.7,56.07 110.7,51.46 110.01,50.77 109.5,50.77 108.73,50 108.73,49.23 106.61,47.11 106.61,45.98 104.8,44.16 104.8,41.36 103.37,39.92 103.37,35.4 101.4,33.43 98.13,33.43 97.74,33.83 89.95,33.83 87.85,31.73 87.85,30.24 86.15,28.54 84.95,28.54 83.77,27.36 73.58,27.36 71.4,25.18 57.43,25.18 48.98,16.73 30.25,16.73 24.15,22.83 24.15,50.45 22.8,51.8 22.8,56.61 21.78,57.63 21.78,61.16 22.21,61.59 22.87,61.59 v1(22.9,61.62)
  BOTTOM w0.102: C302.1 22.48,61.44 22.73,61.44 v1(22.9,61.62) ; UC1.R1 106.47,58.33 106.61,58.19 107.31,58.19 107.55,58.42 110.74,58.42 111,58.16 111.26,58.16 v1(111.7,57.72)
USB3_ATX_DRX_P2: length 192.3
  IN2 w0.127: v1(22.76,81.36) 22.73,81.33 22.17,81.33 21.86,81.02 21.86,63.47 20.83,62.44 20.83,57.08 21.81,56.1 21.81,51.45 23.2,50.06 23.2,22.44 29.86,15.78 57.94,15.78 60.2,13.52 78.8,13.52 80.42,15.15 80.42,17.71 85.54,22.83 87.34,22.83 94.9,30.38 96.61,30.38 98.71,32.48 102.2,32.48 104.34,34.63 104.34,39.56 105.77,40.98 105.77,43.73 107.58,45.54 107.58,46.73 109.34,48.49 110.11,48.49 111.66,50.03 111.66,55.68 112.8,56.82 112.8,57.56 v1(112.96,57.72)
  BOTTOM w0.102: v1(22.76,81.36) 22.58,81.18 22.23,81.18 C840.1 ; v1(112.96,57.72) 112.64,58.05 112.64,58.55 111.91,59.28 107.26,59.28 106.99,59.01 106.7,59.01 106.46,59.26 106.22,59.26 106.12,59.15 UC1.P1
USB20_CR_N3: length 1.6
  TOP w0.102: L308.2 30.04,10.21 29.11,10.21 28.98,10.07 UR1.3
USB20_CR_P3: length 1.6
  TOP w0.102: L308.3 29.98,10.44 29.07,10.44 28.95,10.57 UR1.4
USB20_N1: length 99.2
  IN2 w0.127: v1(164.16,39.07) 164.16,39.83 165.32,40.99 165.32,46.45 166.01,47.14 166.01,52.8 163.41,55.4 162.52,55.4 160.19,57.73 158.34,57.73 157.41,58.67 157.41,59.33 155.9,60.83 152.68,60.83 151.06,62.45 139.85,62.45 139.34,61.93 137.05,61.93 135.47,60.35 130.26,60.35 129.31,59.4 120.48,59.4 120.1,59.02 117.88,59.02 117.12,58.26 v1(117.12,57.5)
  BOTTOM w0.102: v1(117.12,57.5) 117.39,57.23 117.39,56.64 116.62,55.88 116.62,51.94 118.43,50.13 118.43,45.96 116.79,44.32 108.91,44.32 107.21,46.01 106.56,46.01 106.19,46.11 105.99,46.11 UC1.AV2 ; JWLAN1.5 164.12,38.13 163.99,38.26 163.99,38.9 v1(164.16,39.07)
USB20_N2: length 13
  BOTTOM w0.102: R951.1 116.91,45.64 116.44,45.18 v4(113.32,45.18) 108.87,45.18 107.45,46.6 106.78,46.6 106.54,46.66 106.34,46.66 UC1.AU2
USB20_N2_L: length 2.7
  TOP w0.102: L307.4 23.2,149.9 23.2,150.69 v1(23.04,150.84)
  BOTTOM w0.102: v1(23.04,150.84) 23.24,150.64 23.24,150.44 22.87,150.06 JEDP1.2
USB20_N2_R: length 182.3
  TOP w0.102: v1(23.03,147.54) 23.21,147.72 23.21,149.01 L307.3
  IN2 w0.127: v1(23.03,147.54) 23.17,147.4 23.17,145.16 24.9,143.42 39.33,143.42 46.78,135.96 46.78,118.82 49.74,115.86 49.74,114.22 50.41,113.55 50.41,109.08 49.83,108.49 49.83,106.52 49.52,106.22 49.52,101.51 51.59,99.45 53.06,99.45 55.98,96.53 74.62,96.53 75.54,97.45 83.47,97.45 84.5,98.48 97.89,98.48 109.57,86.8 109.57,76.06 111.86,73.77 111.86,68.63 112.84,67.65 115.28,67.65 117.48,65.44 117.48,64.73 118.69,63.53 118.69,63.12 v1(118.52,62.96)
  BOTTOM w0.102: R951.2 117.23,47.93 117.23,49.93 115.75,51.4 115.75,56.25 116.27,56.77 116.27,57.9 117.69,59.32 117.69,60.8 118.52,61.63 118.52,62.11 118.76,62.35 118.76,62.72 v1(118.52,62.96)
USB20_N3: length 113.2
  TOP w0.102: L308.1 30.87,10.23 32.06,10.23 v1(32.23,10.06)
  IN2 w0.127: v1(111.43,46.19) 111.57,46.05 111.93,46.05 112.29,45.69 112.29,43.53 111.02,42.26 110.69,42.26 109.4,40.97 109.4,34.49 103.32,28.41 98.76,28.41 97.62,27.27 95.85,27.27 92.67,24.1 92.67,18 85,10.32 50.63,10.32 50.14,10.81 46.43,10.81 45.81,10.19 32.37,10.19 v1(32.23,10.06)
  BOTTOM w0.102: v1(111.43,46.19) 111.25,46 110.94,46 110.93,45.99 110.47,45.99 110.26,46.19 108.87,46.19 107.91,47.15 106.43,47.15 106.19,47.21 105.99,47.21 UC1.AT2
USB20_N5: length 157.4
  IN2 w0.127: v1(110.71,47) 110.57,46.87 110.2,46.87 109.89,46.56 109.89,43.64 108.14,41.9 108.14,35.2 105.66,32.72 105.11,32.72 102.05,29.67 98.13,29.67 97.04,28.57 95.32,28.57 91.41,24.66 91.41,18.52 84.47,11.58 59.53,11.58 58.32,12.79 53.56,12.79 53.11,12.35 52.03,12.35 50.35,14.03 37.11,14.03 v1(36.99,14.15)
  BOTTOM w0.102: L301.1 22.04,56.62 22.95,56.62 23.6,55.97 23.6,23 29.62,16.98 32.92,16.98 35.93,13.98 36.82,13.98 v1(36.99,14.15) ; UC1.AP2 105.98,48.31 106.26,48.31 106.33,48.25 107.66,48.25 109.2,46.7 109.95,46.7 110.07,46.83 110.54,46.83 v1(110.71,47)
USB20_N5_R: length 14.1
  IN2 w0.127: v1(17.16,56.79) 17.03,56.65 16.82,56.65 16.64,56.83 16.64,57.73 16.95,58.05 16.95,61.71 16.43,62.24 15.73,62.24 15.6,62.36 JUSB1.2
  BOTTOM w0.102: v1(17.16,56.79) 17.34,56.62 17.68,56.62 18,56.93 18,57.67 D302.4 18.25,57.68 18.25,57 18.64,56.61 21.19,56.61 L301.2
USB20_N6: length 186.2
  IN2 w0.127: v1(109.69,47.8) 109.58,47.8 108.87,47.09 108.87,43.96 106.71,41.8 106.71,35.98 102.57,31.84 98.97,31.84 96.78,29.66 95.07,29.66 90.39,24.98 90.39,18.84 84.09,12.53 60.04,12.53 57.43,15.14 29.6,15.14 22.53,22.21 22.53,49.83 21.18,51.19 21.18,55.46 20.2,56.44 20.2,63.09 21.16,64.05 21.16,81.55 22.13,82.52 23.34,82.52 24.09,83.28 24.09,83.98 23.71,84.37 23.18,84.37 v1(23.15,84.4)
  BOTTOM w0.102: v1(23.15,84.4) 22.97,84.22 22.87,84.22 22.56,84.22 L305.1 ; v1(109.69,47.8) 109.45,47.8 108.25,48.99 106.56,48.99 UC1.AN2
USB20_N6_R: length 10.4
  IN2 w0.127: JUSB2.2 15.6,82.66 15.73,82.54 16.49,82.54 16.73,82.78 16.73,83.91 17.1,84.29 17.75,84.29 v1(17.93,84.47)
  BOTTOM w0.102: L305.2 21.7,84.22 19.02,84.22 18.83,84.42 18.83,85.23 D305.4 18.57,85.23 18.57,84.42 18.44,84.29 18.1,84.29 v1(17.93,84.47)
USB20_P1: length 99.2
  IN2 w0.127: v1(117.7,57.5) 117.8,57.59 117.8,57.76 117.7,57.85 117.49,57.85 117.43,57.91 117.43,58.13 118,58.7 120.23,58.7 120.61,59.09 129.44,59.09 130.39,60.04 135.6,60.04 137.18,61.62 139.47,61.62 139.98,62.14 150.93,62.14 152.55,60.52 155.77,60.52 157.09,59.2 157.09,58.54 158.21,57.42 160.06,57.42 162.39,55.09 163.28,55.09 165.7,52.67 165.7,47.27 165.01,46.58 165.01,41.12 163.85,39.96 163.85,39.65 163.74,39.54 163.41,39.54 163.27,39.4 163.27,39.15 163.35,39.07 v1(163.58,39.07)
  BOTTOM w0.102: v1(163.58,39.07) 163.75,38.9 163.75,38.27 163.62,38.14 JWLAN1.3 ; v1(117.7,57.5) 117.63,57.43 117.63,56.55 116.86,55.78 116.86,52.04 118.67,50.23 118.67,45.86 116.89,44.08 108.81,44.08 107.11,45.77 106.53,45.77 106.26,45.5 106.13,45.5 106.06,45.58 106.06,45.75 UC1.AV1
USB20_P2: length 13.2
  BOTTOM w0.102: UC1.AU1 107.35,46.36 108.77,44.94 v4(115.41,44.94) 116.54,44.94 117.14,45.54 117.14,46.06 117.25,46.16 117.63,46.16 117.8,46.32 R950.1
USB20_P2_L: length 2.7
  TOP w0.102: v1(23.62,150.84) 23.43,150.65 23.43,149.88 L307.1
  BOTTOM w0.102: JEDP1.4 23.87,150.05 23.48,150.44 23.48,150.7 v1(23.62,150.84)
USB20_P2_R: length 182.2
  TOP w0.102: L307.2 23.42,149.02 23.42,147.76 v1(23.64,147.54)
  IN2 w0.127: v1(23.64,147.54) 23.48,147.39 23.48,145.29 25.03,143.73 39.46,143.73 47.09,136.09 47.09,118.95 50.05,115.99 50.05,114.35 50.73,113.68 50.73,108.95 50.14,108.36 50.14,106.39 49.84,106.09 49.84,101.64 51.72,99.76 53.19,99.76 56.11,96.84 74.49,96.84 75.41,97.76 83.34,97.76 84.37,98.79 98.02,98.79 109.88,86.93 109.88,76.19 112.18,73.9 112.18,68.76 112.97,67.96 115.41,67.96 117.8,65.57 117.8,64.86 119,63.66 119,63.09 v1(119.13,62.96)
  BOTTOM w0.102: R950.2 117.47,47.93 117.47,50.03 115.99,51.5 115.99,56.15 116.51,56.67 116.51,57.8 117.93,59.22 117.93,60.7 118.76,61.53 118.76,62.01 119,62.25 119,62.83 v1(119.13,62.96)
USB20_P3: length 113.2
  TOP w0.102: L308.4 30.88,10.47 32.06,10.47 v1(32.23,10.64)
  IN2 w0.127: v1(32.23,10.64) 32.37,10.51 45.68,10.51 46.3,11.13 50.27,11.13 50.76,10.63 84.87,10.63 92.36,18.13 92.36,24.23 95.72,27.58 97.5,27.58 98.63,28.72 103.19,28.72 109.09,34.62 109.09,41.1 110.56,42.57 110.89,42.57 111.98,43.65 111.98,44.33 111.85,44.46 111.43,44.46 111.31,44.59 111.31,44.84 111.43,44.97 111.85,44.97 111.98,45.1 111.98,45.56 111.8,45.74 111.57,45.74 v1(111.43,45.6)
  BOTTOM w0.102: v1(111.43,45.6) 111.27,45.76 111.04,45.76 111.03,45.75 110.37,45.75 110.16,45.96 109.74,45.96 109.63,45.85 109.63,45.53 109.53,45.43 109.33,45.43 109.23,45.53 109.23,45.85 109.13,45.96 108.77,45.96 107.81,46.91 UC1.AT1
USB20_P5: length 157.4
  IN2 w0.127: v1(110.71,46.42) 110.57,46.55 110.33,46.55 110.2,46.43 110.2,43.51 108.46,41.77 108.46,35.07 105.79,32.41 105.24,32.41 102.18,29.35 98.26,29.35 97.17,28.26 95.45,28.26 91.73,24.53 91.73,18.39 84.6,11.27 59.4,11.27 58.19,12.48 53.69,12.48 53.24,12.04 51.9,12.04 50.22,13.72 37.15,13.72 v1(36.99,13.56)
  BOTTOM w0.102: UC1.AP1 106.77,48.01 106.88,47.91 106.88,47.6 106.98,47.5 107.18,47.5 107.28,47.6 107.28,47.91 107.38,48.01 107.56,48.01 109.11,46.46 110.05,46.46 110.17,46.59 110.54,46.59 v1(110.71,46.42) ; v1(36.99,13.56) 36.82,13.74 35.83,13.74 32.82,16.75 29.52,16.75 23.36,22.91 23.36,55.87 22.85,56.38 22.06,56.38 L301.4
USB20_P5_R: length 14.1
  IN2 w0.127: v1(17.16,56.21) 17.03,56.34 16.69,56.34 16.33,56.7 16.33,57.86 16.64,58.18 16.64,61.58 16.3,61.92 15.73,61.92 15.6,61.8 JUSB1.3
  BOTTOM w0.102: L301.3 21.19,56.37 18.39,56.37 18.25,56.24 18.25,55.43 D302.3 18,55.43 18,56.17 17.79,56.38 17.34,56.38 v1(17.16,56.21)
USB20_P6: length 186.1
  IN2 w0.127: v1(23.15,83.81) 23.39,84.05 23.58,84.05 23.78,83.85 23.78,83.41 23.21,82.83 22,82.83 20.85,81.68 20.85,64.18 19.88,63.22 19.88,56.31 20.87,55.33 20.87,51.06 22.22,49.7 22.22,22.08 29.47,14.83 57.3,14.83 59.91,12.22 84.22,12.22 90.71,18.71 90.71,24.85 95.2,29.35 96.91,29.35 99.1,31.53 102.7,31.53 107.02,35.85 107.02,41.67 109.18,43.84 109.18,46.96 109.44,47.21 v1(109.69,47.21)
  BOTTOM w0.102: v1(109.69,47.21) 109.32,47.58 109.18,47.58 109.04,47.44 108.89,47.44 108.75,47.58 108.75,47.73 108.89,47.87 108.89,48.01 108.15,48.75 106.66,48.75 UC1.AN1 ; v1(23.15,83.81) 22.97,83.98 22.56,83.98 L305.4
USB20_P6_R: length 10.5
  IN2 w0.127: v1(17.93,83.88) 17.83,83.98 17.23,83.98 17.04,83.78 17.04,82.65 16.62,82.22 15.73,82.22 15.6,82.1 JUSB2.3
  BOTTOM w0.102: L305.3 21.7,83.99 19.02,83.99 18.83,83.79 18.83,82.98 D305.3 18.57,82.98 18.57,83.79 18.3,84.06 18.1,84.06 v1(17.93,83.88)
USB_EN#: length 182.9
  TOP w0.102: v1(60.58,92.28) v3(60.58,91.34) ; R194.1 v1(160.56,61.22) 160.86,60.92 U11.72
  IN1 w0.127: v1(60.58,92.28) 60.58,92.19 60.68,92.09 69.42,92.09 69.85,91.66 87.73,91.66 88.05,91.98 95.44,91.98 108.55,78.87 108.55,77.79 112.25,74.09 114.34,74.09 116.92,71.51 121.81,71.51 126.61,66.71 138.36,66.71 138.68,66.39 158.46,66.39 161.09,63.76 161.09,61.75 v1(160.56,61.22)
  BOTTOM w0.102: U301.4 22.19,64.55 24.22,66.58 24.75,66.58 26.19,68.01 26.19,88.45 29.3,91.56 42.03,91.56 42.73,92.26 60.58,92.26 v1(60.58,92.28)
USB_OC0#: length 3
  TOP w0.102: v2(104.51,54.04) 104.51,54.35 v1(104.77,54.61) 105.96,54.61 RC45.2
  BOTTOM w0.102: UC1.AB2 v1(104.77,54.61)
USB_OC1#: length 201.6
  IN1 w0.127: v1(112.23,49.94) 111.81,49.94 111.42,50.34 109.41,50.34 108.75,49.68 108.75,43.72 108.02,42.98 105.5,42.98 104.98,42.46 102.55,42.46 101.05,43.96 98.02,43.96 97.3,43.24 97.3,42.63 95.15,40.48 95.15,37.34 93.14,35.34 89.88,35.34 86.64,32.1 85.44,32.1 84.01,33.52 83.05,33.52 v1(82.32,32.8)
  BOTTOM w0.102: v1(82.32,32.8) 82.04,32.51 78.61,32.51 77.31,31.21 68.86,31.21 67.91,32.16 67.91,36.8 65.12,39.59 65.12,72.8 70.39,78.07 70.39,89.37 v2(68.2,91.56) 66.71,93.05 43.02,93.05 41.88,91.91 29.15,91.91 25.81,88.57 25.81,68.17 24.6,66.96 R301.2 ; RC46.2 112.3,50 v1(112.23,49.94) 112.13,50.04 111.6,50.04 111.45,50.2 110.81,50.2 110.49,50.51 109.99,50.51 108.34,52.16 106.34,52.16 106.33,52.15 106.32,52.15 106.15,51.98 105.89,51.98 UC1.AG2
USB_OC1#_U301: length 3.6
  BOTTOM w0.102: v2(24.63,67.54) 22.9,67.54 22.62,67.26 R301.1 21.43,66.96 U301.3
USB_ZVSS: length 3.7
  TOP w0.102: v1(103.24,48.03) 103.24,47.92 103,47.68 103,46.54 v2(102.66,46.19)
  TOP w0.254: RC108.1 103.69,47.58 v1(103.24,48.03)
  BOTTOM w0.203: UC1.AN7 103.24,48.09 v1(103.24,48.03)
USBSS_ZVDD: length 11.7
  TOP w0.102: v2(102.66,47.48) RC101.1
  TOP w0.254: RC101.1 103.08,48.9 v1(103.08,49.17)
  IN2 w0.203: v1(103.96,55.77) 104.52,55.21 105.17,55.21 105.37,55.01 105.37,53.24 104.04,51.91 103.53,51.91 103.22,51.59 103.22,51.08 103.7,50.6 103.7,49.79 v1(103.08,49.17)
  BOTTOM w0.2: UC1.W5 103.57,56.17 v1(103.96,55.77)
USBSS_ZVSS: length 2.6
  TOP w0.203: RC100.1 105.39,56.2 v2(104.56,56.2) v1(104.02,56.75)
  BOTTOM w0.2: UC1.W4 104.37,56.39 v1(104.02,56.75)
VCIN0_PH1: length 90.9
  TOP w0.102: U11.109 169.1,50.68 169.4,50.97 169.4,58.12 168.88,58.64 v1(168.88,61.82) ; v1(161.41,64.03) 161.21,64.23 PR206.2
  TOP w0.127: PH201.1 98.07,67.21 99.28,68.42 106.96,68.42 108.04,69.5 111.34,69.5 112.03,68.81 118,68.81 121.31,65.5 123.66,65.5 124.11,65.94 v2(127.8,65.94) v1(135.66,65.94)
  IN2 w0.127: v1(161.41,64.03) 160.67,64.78 156.26,64.78 155.55,65.49 155.55,66.18 154.78,66.96 147.47,66.96 146.97,66.45 136.17,66.45 v1(135.66,65.94)
  BOTTOM w0.102: v1(161.41,64.03) 161.95,63.49 163.83,63.49 164.44,64.1 166.25,64.1 168.36,61.99 168.7,61.99 v1(168.88,61.82)
VCIN1_AC_IN: length 63.4
  TOP w0.102: U11.110 169.5,48.86 v2(168.78,48.14) 168.51,47.86 168.51,45.81 C190.1 R930.1 168.75,44.12 168.58,43.96 168.58,42.9 v1(168.18,42.49)
  IN1 w0.127: v1(151.31,18.48) 152.75,19.92 152.75,20.29 153.67,21.21 153.67,28.01 155.92,30.26 157.25,30.26 157.83,30.83 158.71,30.83 160.57,32.69 165.34,32.69 167.29,34.64 167.29,41.6 v1(168.18,42.49)
  IN1 w0.254: v1(151.31,18.48) 150.12,17.29 150.12,13.78 149.63,13.3 144.8,13.3 144.24,13.86 141.57,13.86 140.71,13 v1(140.71,12.48)
  BOTTOM w0.203: v1(151.31,18.48) 150.82,17.99 PU703.2
  BOTTOM w0.254: v1(140.71,12.48) 141.11,12.88 PQ741.2 ; PR731.1 PR741.2 152.45,18.75 151.58,18.75 v1(151.31,18.48)
VCIN1_BATT_DROP: length 38.2
  TOP w0.102: v1(163.5,64.76) 164.09,65.35 U11.64
  TOP w0.254: PR451.2 PR452.1 PC451.1 v2(165.65,33.2) v1(165.65,33.75)
  IN1 w0.127: v1(165.65,33.75) 167.03,35.13 167.03,41.71 167.54,42.21 167.54,44.54 167.12,44.96 167.12,49.47 166.14,50.45 166.14,54.91 163.03,58.02 163.03,62.58 163.5,63.05 v1(163.5,64.76)
VCIN1_BATT_TEMP: length 125.6
  TOP w0.102: C189.1 163.15,67.15 163.39,66.91 164.12,66.91 164.7,66.33 U11.63 v1(164.7,63.47) ; v1(148.17,11.46) 149.72,13.01 149.72,19.8 148.3,21.23 145.39,21.23 144.25,22.37 137.96,22.37 133.25,27.08 123.79,27.08 121.95,28.92 v2(121.31,28.92) 116.87,28.92 115.32,30.47 PR205.2
  IN1 w0.127: v1(164.7,63.47) 163.54,62.3 163.54,58.25 166.65,55.14 166.65,50.67 168.26,49.06 168.26,45.7 169.23,44.74 169.23,41.99 168.84,41.59 168.84,34.54 165.98,31.67 160.99,31.67 158.5,29.18 156.37,29.18 154.74,27.56 154.74,16.87 153.03,15.15 153.03,14.01 151.28,12.26 151.28,11.27 150.77,10.76 148.87,10.76 v1(148.17,11.46)
  BOTTOM w0.254: PR778.2 v1(148.17,11.46)
VCOUT0_MAIN_PWR_ON: length 14.1
  TOP w0.102: PR411.1 166.91,38.83 167.06,38.98 v2(167.06,40.11) 167.06,42.59 167.82,43.35 167.82,45.61 167.39,46.05 167.39,47.62 167.1,47.9 U11.104
VCOUT1_PROCHOT#: length 2.5
  TOP w0.102: R923.1 166.7,47.48 U11.103
VGA_B+: length 9.6
  TOP w0.381: v1(61.56,103.66) 62.13,104.23 62.13,105.38 63.99,107.23 PC1021.1
  BOTTOM w0.508: PR1032.1 v1(61.56,103.66)
  vias: v1(64.73,111.54) v1(66,112.23) v1(66,111.6) v3(65.12,112.27)
VGA_CLKREQ#: length 308.2
  TOP w0.102: v2(87.33,145.23) 87,145.56 v1(86.92,145.56) ; RC133.2 RC134.2 v1(85.36,34.89)
  IN2 w0.127: v1(88.04,46.12) 88.95,45.2 88.95,42 89.89,41.06 90.19,41.06 90.58,40.67 90.58,40.11 v1(85.36,34.89) 84.32,33.85 82.43,33.85 81.88,33.3 81.88,31.84 81.12,31.08 71.97,31.08 71.27,30.38 57.56,30.38 47.4,20.22 30.89,20.22 28.54,22.57 28.54,47.53 27.35,48.72 27.35,51.58 25.82,53.1 25.82,91.58 18.82,98.58 18.82,105.69 20.73,107.6 20.73,108.93 25.11,113.31 25.11,117.06 28.79,120.74 28.79,129.63 26.76,131.67 26.76,132.43 24.16,135.03 24.16,137.55 19.32,142.39 19.32,148.68 21.01,150.37 25.67,150.37 26.56,151.27 29.02,151.27 30.19,150.09 36.45,150.09 44.76,158.4 53.42,158.4 56.42,155.4 71.35,155.4 74.39,152.37 86.71,152.37 88.67,150.4 88.67,147.73 86.92,145.98 v1(86.92,145.56)
  BOTTOM w0.102: UC1.AV35 87.88,45.96 v1(88.04,46.12) ; 85.97,144.78 85.97,141.71 UV1.N7
  BOTTOM w0.117: v1(86.92,145.56) 86.75,145.56 85.97,144.78
VGA_SMB_CK3: length 8.8
  TOP w0.102: QV1.1 88.28,147.92 88.59,147.62 88.59,146.08 RV6.2 89.38,145.28 89.61,145.28 v2(90.08,144.81) 90.55,144.34 90.55,141.66 v1(90.36,141.47)
  BOTTOM w0.102: UV1.U7 89.94,141.65 90.26,141.65 90.36,141.55 v1(90.36,141.47)
VGA_SMB_DA3: length 8
  TOP w0.102: QV1.4 90.35,146.62 RV5.2 90.99,145.98 v2(90.99,142.74) 90.99,141.49 90.39,140.88 v1(90.32,140.88)
  BOTTOM w0.102: v1(90.32,140.88) 90.24,140.96 90.06,140.96 UV1.U8
VGATE: length 41.2
  TOP w0.102: U11.74 161.82,60.12 161.69,59.99 157.83,59.99 157.39,60.42 157.39,62.02 155.43,63.99 154.14,63.99 153.77,64.36 151.55,64.36 149.93,62.73 v2(149.93,59.28) 149.93,58.35 150.83,57.45 154,57.45 154.33,57.12 154.33,54.04 155.86,52.52 155.86,51.08 v1(155.92,51.02)
  BOTTOM w0.102: PR813.2 152.24,48.56 152.24,49.05 152.91,49.73 155.32,49.73 155.73,50.13 155.73,50.83 v1(155.92,51.02)
  BOTTOM w0.203: PU801.3 153.67,46.09 152.95,46.82 PR813.2
VMB2: length 3.8
  TOP w0.102: v1(106.95,27.49) v3(106.95,29.11) ; v1(106.95,27.49) v3(105.96,27.49) ; v1(106.95,27.49) v3(108.17,27.49)
VR_ON: length 49.5
  TOP w0.102: v1(151.98,49.43) v2(151.98,50.07) ; U11.121 173.9,48.49 v1(173.83,48.42)
  IN2 w0.127: v1(151.92,37.24) 152.49,37.81 153.95,37.81 157.7,41.56 157.7,46.11 158.05,46.46 158.05,47.43 156.56,48.93 154.46,48.93 153.95,49.43 v1(151.98,49.43)
  BOTTOM w0.102: PR851.1 v1(151.92,37.24) ; v1(173.83,48.42) 173.1,49.14 165.84,49.14 165.55,49.43 163.66,49.43 162.26,48.04 162.26,47.9 161.89,47.53 161.32,47.53 161.1,47.74 160.4,47.74 158.17,49.98 157.43,49.98 157.02,50.4 157.02,51.01 156.56,51.47 155.73,51.47 155.35,51.08 155.35,50.26 155.18,50.09 152.64,50.09 v1(151.98,49.43)
VREF_0.775VALW: length 2
  BOTTOM w0.102: PR1458.2 145.71,30.27 v2(144.68,31.3)
VREF_PINSET_RT3661: length 15.8
  TOP w0.102: v1(159.03,36.99) v2(159.03,36.28)
  TOP w0.254: PR838.1 159.08,45.98 PR831.1 PR846.2 PR848.2 159.02,43.46 158.48,43.46 v1(158.39,43.37) 158.3,43.46 158.29,43.46 158.02,43.73 PR850.1
  IN2 w0.254: v1(159.03,36.99) 159.53,37.48 159.53,42.3 158.45,43.37 v1(158.39,43.37)
  BOTTOM w0.203: PU801.15 158.37,43.32 158.39,43.34 v1(158.39,43.37)
  BOTTOM w0.254: PR847.2 PR849.1 158.48,43.46 v1(158.39,43.37) ; PR826.2 158.66,36.62 v1(159.03,36.99)
VREF_VGA: length 6.4
  TOP w0.102: v2(53.52,108.5) v1(52.81,107.79)
  TOP w0.254: PR1010.2 PR1012.2 PR1008.1 52.56,107.54 v1(52.81,107.79)
  BOTTOM w0.203: PR1001.2 PR1011.1 v1(52.81,107.79) 52.89,107.71 53.6,107.71 53.66,107.65 PU1001.13
VSEN_APU: length 10.3
  TOP w0.102: v2(154.69,51) 154.99,51 155.33,50.66 155.33,50.15 155.08,49.9 PR814.2
  TOP w0.254: PR814.2 155.16,49.48 PC812.1 PR809.1 156.9,47.83 PR816.2 156.94,47.27 156.68,47.02 v1(156.05,47.02) 156.17,46.89 PC988.1
  BOTTOM w0.203: v1(156.05,47.02) 156.05,46.96 155.67,46.58 PU801.8
  BOTTOM w0.254: v1(156.05,47.02) 156.05,47.08 155.64,47.49 155.4,47.49 154.97,47.92 PC818.1
VSEN_NB: length 17.4
  TOP w0.254: v1(155.41,47) 155.29,46.87 PC986.2 ; v1(156.56,38.19) 156.52,38.19 156.22,38.5 v2(156.15,38.5) 155.29,38.5 PR811.2 PC810.2 PC814.1 156.1,36.63 PR808.1 PR812.1
  IN1 w0.254: v1(155.41,47) 155.41,46.87 156.75,45.53 156.75,40.65 155.76,39.66 155.76,38.87 156.43,38.19 v1(156.56,38.19)
  BOTTOM w0.203: PU801.7 155.27,46.85 v1(155.41,47)
VSEN_VGA: length 17.2
  TOP w0.102: v1(57.93,101) v2(57.93,100.36)
  TOP w0.254: v1(57.93,101) 58.19,101 PC1003.1 58.94,101.76 PR1027.1 58.08,102.58 PC1011.2 57.2,102.57 PR1024.2
  IN1 w0.254: v1(57.93,101) 57.59,101.34 57.59,102.14 58.07,102.62 58.07,108.6 56.73,109.94 v1(56.73,110.3)
  BOTTOM w0.203: PU1001.21 56.34,109.96 56.68,110.3 v1(56.73,110.3)
  BOTTOM w0.254: PC1026.2 PR1017.1 57.32,101.04 57.35,101 v1(57.93,101)
VTTREF_DDR: length 2.7
  BOTTOM w0.203: PC515.1 33.16,115.18 34.57,115.18 34.64,115.11 PU501.4
WAKE#_R: length 3.5
  BOTTOM w0.102: v2(177.69,35.02) R249.2 176.62,35.03 JWLAN1.55
WAKEB: length 8
  BOTTOM w0.102: UV1.AJ27 98.98,125.49 99.58,126.09 99.58,126.46 100.69,127.56 v2(103.02,127.56) 104.69,127.56 RV162.2 104.87,127.74 RV163.1
WL_OFF#: length 5.9
  BOTTOM w0.102: RC130.1 v2(100.61,39.79) 100.61,40.52 99.9,41.23 99.44,41.23 99.21,41.46 99.21,42.19 99.49,42.47 99.49,43.78 UC1.BA13
WL_RST#: length 4.4
  TOP w0.102: v1(176.23,42.6) 176.23,42.12 v2(176.49,41.85) 176.54,41.81 R250.1
  BOTTOM w0.102: JWLAN1.52 175.87,43.33 176.23,42.97 v1(176.23,42.6)
WLAN_CLKREQ#: length 161.8
  TOP w0.102: v1(79.58,31.65) 79.58,32.45 v2(80.41,33.28) 84.81,37.69 86.64,37.69 87.72,38.77 88.23,38.77 88.61,38.38 88.61,37.75 88.93,37.43 89.82,37.43 90.07,37.68 RPC13.6 90.07,38.29 90.96,39.18 90.96,40.67 91.82,41.53 v1(91.82,42.59)
  IN2 w0.127: v1(91.82,42.59) 92.29,43.06 92.29,44.67 91.32,45.64 v1(91.32,46.39) ; v1(175.67,32.92) 175.67,27.59 179.31,23.94 179.31,17.6 168.42,6.71 136.01,6.71 135.09,5.8 112.76,5.8 107.47,11.08 104.23,11.08 102.45,12.86 96.41,12.86 v1(95.76,13.51)
  BOTTOM w0.102: UC1.AV29 90.89,45.96 v1(91.32,46.39) ; v1(95.76,13.51) 93.32,13.51 90.58,16.25 90.58,20.92 83.15,28.35 82.9,28.35 79.6,31.65 v1(79.58,31.65) ; R246.1 175.73,32.98 v1(175.67,32.92)
WLAN_CLKREQ#_R: length 4.1
  BOTTOM w0.102: R246.2 174.9,35.02 174.78,35.15 v2(174.78,35.35) 174.78,35.54 175.29,36.05 175.73,36.05 176.12,36.44 JWLAN1.53
WLAN_DISABLE_R: length 3.5
  TOP w0.102: v1(176.83,43.46) R248.1 177.5,44.21 v2(177.15,44.56)
  BOTTOM w0.102: JWLAN1.56 176.87,43.5 v1(176.83,43.46)
XTALIN: length 7.2
  BOTTOM w0.102: UV1.AM28 101.28,124.69 102.72,123.25 102.72,122.06 RV20.1 CV17.1 104,120.76 YV2.3
XTALOUT: length 4.6
  BOTTOM w0.102: RV1643.1 102.38,124.19 101.4,125.16 99.96,125.16 99.86,125.06 99.56,125.06 UV1.AK28
XTALOUT_R: length 3.7
  BOTTOM w0.102: YV2.1 104.93,122.17 104.93,122.51 CV18.1 104.02,123.27 RV1643.2 RV20.2
XTLI: length 3.9
  BOTTOM w0.102: YL1.3 39.29,135.74 CL14.2 38.4,135.78 UL2.29
XTLO: length 5.4
  BOTTOM w0.102: UL2.28 v2(37.09,136.18) 38.02,136.18 CL13.2 38.88,136.17 39.91,136.17 40.53,136.8 YL1.1
N14140561: length 5.6
  TOP w0.102: v2(38.59,114.34) 39.08,114.84 v1(39.08,115.11)
  TOP w0.254: v1(39.08,115.11) 39.72,115.11 PC508.2 39.83,116.18 PR505.2 39.72,116.49 39.15,117.05 PD501.1
  BOTTOM w0.203: PU501.12 v1(39.08,115.11)
N14166749: length 0.7
  TOP w0.102: 73.97,10.24 73.97,10.74 v2(74.08,10.85)
N14166761: length 5.3
  TOP w0.102: PR2005.2 75.73,7.16 76.11,6.77 76.11,6.24 v2(76.55,5.81)
  TOP w0.254: PU2001.2 73.31,7.65 73.8,7.16 PC2002.1 PR2006.1 PR2005.2
N14166787: length 5
  TOP w0.102: v2(63.65,6.08) 64.42,6.84 PC2004.2
  TOP w0.254: PR2007.1 PR2001.2 ; PR2001.2 65.79,7.12 66.32,7.65 PU2001.7 ; PR2001.2 PC2004.2
N15305130: length 7.5
  TOP w0.102: PR205.1 PR203.1 PR204.1 v2(112.11,27.86) 112.11,24.9 v1(112.14,24.86)
  BOTTOM w0.102: JBAT1.5 v1(112.14,24.86)
N16741477: length 1.2
  TOP w0.102: T212.1 93.81,140.9 v1(93.92,140.9)
  BOTTOM w0.102: v1(93.92,140.9) 93.59,140.9 UV1.AB8
N16741489: length 1.5
  TOP w0.102: T208.1 94.36,142.31 v1(94.78,141.89)
  BOTTOM w0.102: UV1.AD7 v1(94.78,141.89)
N16741505: length 5.4
  BOTTOM w0.102: T214.1 95.93,146.8 94.38,145.26 94.38,145.24 93.98,144.84 93.98,143.89 UV1.AB4
N16741517: length 1.3
  TOP w0.102: v1(95.55,139.48) 96.03,139 T206.1
  BOTTOM w0.102: UV1.AD9 95.55,139.52 v1(95.55,139.48)
N16741525: length 1.7
  TOP w0.102: v1(91.58,141.17) 91.17,141.17 T216.1
  BOTTOM w0.102: v1(91.58,141.17) 92.06,140.69 UV1.Y8
N16741803: length 3.9
  TOP w0.102: v2(94.8,126.42) 94.8,126.68 95.31,127.19 95.31,127.89 RV29.2
  TOP w0.508: RV29.2 94.8,128.99 v1(94.69,129.1)
  BOTTOM w0.254: UV1.AC22 94.69,129.38 v1(94.69,129.1)
N16741825: length 2.6
  TOP w0.102: v1(93.92,128.9) 94.33,129.31 94.33,129.44 v2(94.61,129.72)
  TOP w0.508: RV59.2 93.74,128.72 v1(93.92,128.9)
  BOTTOM w0.305: UV1.AB22 93.92,129.15 v1(93.92,128.9)
N16751828: length 1.1
  TOP w0.102: v1(94.8,140.27) 94.46,139.94 T209.1
  BOTTOM w0.102: UV1.AC8 v1(94.8,140.27)
N16751830: length 1.1
  TOP w0.102: v1(95.63,141.09) 95.58,141.09 T205.1
  BOTTOM w0.102: v1(95.63,141.09) 95.98,140.74 UV1.AE8
N16751834: length 1.2
  TOP w0.102: T203.1 95.83,140.27 v1(96.38,140.27)
  BOTTOM w0.102: UV1.AE9 96,139.89 v1(96.38,140.27)
N16751836: length 1.3
  TOP w0.102: T201.1 86.48,139.66 v1(86.73,139.66)
  BOTTOM w0.102: UV1.N9 86.41,139.66 v1(86.73,139.66)
N16751838: length 3.1
  BOTTOM w0.102: UV1.AB2 93.58,144.95 95.15,146.52 T215.1
N16751842: length 2.4
  TOP w0.102: v1(93.92,140.11) 93.57,140.46 T211.1
  BOTTOM w0.102: UV1.AB9 93.7,139.89 v1(93.92,140.11)
N16751844: length 1.3
  TOP w0.102: v1(93.93,139.39) 93.88,139.44 T207.1
  BOTTOM w0.102: UV1.AC10 94.08,139.39 v1(93.93,139.39)
N16751848: length 1.9
  TOP w0.102: T202.1 86.27,138.87 v1(85.6,139.54)
  BOTTOM w0.102: UV1.L9 85.33,139.54 v1(85.6,139.54)
N16751852: length 1.4
  TOP w0.102: T213.1 92.19,141.78 v1(92.85,141.78)
  BOTTOM w0.102: v1(92.85,141.78) 93.09,141.78 UV1.AB7
N16751854: length 2.6
  TOP w0.102: T210.1 93.66,142.28 v1(94.05,141.9)
  BOTTOM w0.102: v1(94.05,141.9) 94.38,141.56 UV1.AC7
N16751856: length 1.5
  TOP w0.102: T204.1 91.53,139.1 v1(91.58,139.1)
  BOTTOM w0.102: v1(91.58,139.1) 91.58,139.1 UV1.Y11
N16751858: length 1.8
  TOP w0.102: T217.1 v1(92.39,142.64)
  BOTTOM w0.102: v1(92.39,142.64) 92.39,141.7 UV1.Y7
N16808781: length 6.4
  BOTTOM w0.102: UV1.AJ11 99.21,138.71 100.99,138.71 101.12,138.84 102.52,138.84 v2(102.99,139.32) 103.47,139.79 RV157.1
N16808782: length 8.4
  BOTTOM w0.102: UV1.AK12 99.67,137.98 v2(102.04,137.98) 103.94,137.98 105.12,139.16 RV155.1
N16808783: length 6.6
  BOTTOM w0.102: RV156.1 v2(104.29,139.73) 104.29,139.54 103.22,138.46 101.75,138.46 101.57,138.29 UV1.AL11
N17005206: length 4.3
  BOTTOM w0.508: PR109.1 21.17,17.69 21.62,18.13 v2(22.1,18.13) 22.27,18.13 22.63,17.77 23.03,17.77 PD101.3
N17215242: length 2.4
  BOTTOM w0.203: PU703.3 150.94,17.59 151.27,17.92 v2(151.51,17.92) PR769.2
N17215261: length 2.4
  BOTTOM w0.203: PU703.8 150.56,15.59 150.9,15.26 v2(151.3,15.26) PR727.1
N17215273: length 1.6
  TOP w0.102: v2(144.38,14.56) 144.38,15.02 v1(145.15,15.79)
N17215298: length 2.9
  TOP w0.102: v1(145.51,15.09) v2(145.51,13.81)
  BOTTOM w0.203: PR757.1 v1(145.51,15.09) 145.61,15.2 145.61,15.42 145.78,15.59 PU703.17
N17215363: length 3.8
  TOP w0.127: PR737.1 33.95,156.4 34.32,156.77 35.03,156.77 v2(35.19,156.61)
  TOP w0.508: PR737.1 33.72,156.39 PR738.2 32.72,155.59 PQ707.2
N17215386: length 0.8
  TOP w0.102: v1(136.13,13.59) v3(136.13,14.41)
N17215397: length 3.9
  BOTTOM w0.102: v2(140.62,16.66) 140.62,16.36 139.79,15.52 PR743.2
  BOTTOM w0.508: PD703.1 139.32,13.53 139.79,14 PR743.2
N17215405: length 4.7
  BOTTOM w0.102: v2(119.03,13.31) 119.32,13.31 119.52,13.11 119.52,12.8 120.74,11.57 PQ711.1
  BOTTOM w0.254: PQ711.1 121.79,11.55 122.01,11.78 PQ710.2
N17215464: length 2.2
  BOTTOM w0.102: v2(151.67,11.33) 151.6,11.4 PR754.2
  BOTTOM w0.254: PC752.1 152.38,12.59 PR754.2
N17215501: length 2.9
  TOP w0.102: v2(147.45,14.62) 147.79,14.28 v1(147.79,14)
  BOTTOM w0.203: PR778.1 147.79,13.43 v1(147.79,14) 147.97,14.18 PU703.13
N17215508: length 4
  TOP w0.102: v2(141.29,13.26) 141.76,12.79 v1(141.76,12.46)
  BOTTOM w0.254: PR779.1 PQ741.1 v1(141.76,12.46)
N17225517: length 5.2
  TOP w0.102: PR2223.2 49.57,9.58 v2(49.32,9.83)
  TOP w0.254: PU2002.2 52.02,8.82 PC2001.1 PR2008.1 PR2003.2 PR2223.2
N17225535: length 1.7
  TOP w0.102: 54.17,6.42 v2(55.91,6.42)
N17225564: length 4.7
  TOP w0.102: v2(49.79,17.7) 50.02,17.93 PR2002.1
  TOP w0.254: PR2002.1 51.18,17.94 PR2004.2 PC2005.2 52.02,17.11 PU2002.7
N17268367: length 2.5
  TOP w0.102: PC608.2 61.19,17.16 60.47,16.44 v2(60.47,16.01)
  TOP w0.254: PR612.1 PC608.2
N17268583: length 3
  TOP w0.102: v2(64.26,21.1) 64.26,20.85 PR611.2
  TOP w0.254: PU601.9 65.55,19.04 65.01,19.58 PR611.2
N17847259: length 3
  BOTTOM w0.102: T4935.1 101.02,139.89 UV1.AL9
N17877344: length 2.4
  BOTTOM w0.102: T223.1 88.17,146.33 88.17,144.88 UV1.R1
N17877347: length 3.3
  BOTTOM w0.102: T224.1 88.56,146.29 88.56,144.84 88.24,144.52 88.24,144.15 UV1.R3
N20132221: length 2.2
  TOP w0.102: v2(181.64,54.34) 181.33,54.64 R921.2 181.57,55.77 C831.1
N20280223: length 32.2
  TOP w0.254: R377.1 30.32,3.84 29.99,3.51 v3(28.68,3.51) 15.03,3.51 12.92,5.62 v1(6.5,5.62)
  BOTTOM w0.254: v1(6.5,5.62) 3.65,5.62 1.87,3.84 LED2.2
N20455593: length 4.3
  BOTTOM w0.254: R376.1 6.44,136.62 6,136.17 4.07,136.17 LED3.2
N20455694: length 2.3
  BOTTOM w0.254: LED4.2 5.79,136.85 6.38,137.44 R378.1
N22463592: length 1.3
  TOP w0.102: T26.1 91.38,47.88 v1(91.32,47.94)
  BOTTOM w0.102: v1(91.32,47.94) 91.73,48.36 UC1.AP27
N22797561: length 2
  TOP w0.102: v1(86.98,64.89) 87.69,65.6 87.73,65.6 T60.1
  BOTTOM w0.125: 87.38,64.49 v1(86.98,64.89)
  BOTTOM w0.127: UC1.D35 87.47,64.4 87.38,64.49
N22797567: length 1.3
  TOP w0.102: VSS_SENSE1.1 94.15,49.24 94.18,49.24 v1(94.55,48.87)
  BOTTOM w0.102: UC1.AM23 94.36,48.87 v1(94.55,48.87)
N22799035: length 3.7
  TOP w0.102: U1895V.10 89.84,111.41 89.88,111.45 CV271.1 90.41,113.14 v2(90.41,114.42)
N22799039: length 3.8
  TOP w0.102: U1895V.12 89.04,111.33 88.93,111.43 CV281.1 87.94,113.59 v2(87.94,114.28)
N22800917: length 2.9
  TOP w0.102: v2(99.04,106.51) 99.42,106.51 RV42.2
  TOP w0.381: RV42.2 100.1,105.34 QV17.1
N22801416: length 4.3
  TOP w0.254: QV21.6 82.5,113.49 82.96,113.95 v2(83.73,113.95) 84.42,113.95 84.93,113.44 RV57.1
N22801421: length 2.6
  TOP w0.102: v2(84.93,110.06) RV56.1
  TOP w0.254: QV21.3 84.23,111.18 84.46,111.41 RV56.1
N22801431: length 3.3
  TOP w0.127: v2(83.78,104.82) RV45.1
  TOP w0.508: QV11.1 83.78,107.09 RV45.1
N22840797: length 5.3
  BOTTOM w0.102: UV8.J13 58.35,147.5 58.35,148.86 59.47,149.97 59.47,150.64 RV121.1 59.58,150.75 v2(60.62,150.75)
N22840814: length 4.7
  BOTTOM w0.102: v2(60.07,135.3) 59.69,135.68 58.45,135.68 RV117.1 57.98,135.23 UV8.J1
N22840825: length 10.8
  BOTTOM w0.102: UV8.J10 57.98,144.1 57.02,143.14 52.52,143.14 51.79,142.41 RV119.1 v2(48.48,142.41)
N22841005: length 4.6
  BOTTOM w0.102: UV7.J13 57.5,121.01 57.5,120.37 56.86,119.73 RV120.1 v2(57.9,118.41)
N22841028: length 4.6
  BOTTOM w0.102: UV7.J1 57.98,133.43 RV116.1 58.47,133.93 v2(60.07,133.93)
N22841062: length 12.1
  BOTTOM w0.102: v2(47.67,125.39) 49.05,125.39 RV118.1 50.33,125.76 56.86,125.76 57.98,124.64 UV7.J10
N23123559: length 3.3
  TOP w0.102: R946.2 58.66,6.82 v2(58.24,7.24)
  TOP w0.254: R946.2 60.23,6.44 60.23,5.94 60.05,5.76 Q401.3
N23712513: length 4.6
  TOP w0.102: v2(173.76,43.54) 173.68,43.45 v1(173.68,42.95) 173.7,42.92 R243.1 R251.2
  BOTTOM w0.102: JWLAN1.38 172.37,44.25 v1(173.68,42.95)
N23727534: length 9.7
  TOP w0.254: R935.2 65.7,36.37 v2(65.31,35.98) 60.61,31.27 Q83.1
N23728403: length 3.7
  TOP w0.102: R937.2 v2(87.92,28.24) ; R937.2 R941.2 ; R937.2 88.42,29.37 88.8,29.75 U18.3
N23728440: length 1.4
  TOP w0.102: U18.6 92.66,29.75 C860.1
N24107383: length 2.2
  BOTTOM w0.203: 36.4,134.98 UL2.31
  BOTTOM w0.254: RL9.2 37.12,133.76 36.55,134.33 36.55,134.83 36.4,134.98
N24107515: length 1.9
  TOP w0.102: RL19.2 v2(21.95,136.96)
N24108268: length 4
  BOTTOM w0.102: UL2.25 36.31,137.38 36.43,137.5 37.19,137.5 38.01,138.32 39.06,138.32 TPL1.1
N24108270: length 5.6
  BOTTOM w0.102: TPL2.1 40.43,138.08 38.15,138.08 37.29,137.22 37.29,136.92 36.95,136.58 UL2.27
N24222879: length 4.5
  TOP w0.102: R244.1 174.27,42.58 v1(174.27,42.95) v2(175.06,43.73)
  BOTTOM w0.102: JWLAN1.40 172.87,44.35 v1(174.27,42.95)
N24293759: length 7.7
  TOP w0.102: v2(151.56,23.94) 151.56,25.2 152,25.63 QC18.3
  TOP w0.508: QC18.3 152,26.78 152.68,27.46 152.68,29.75 152,30.43 QC19.3
N24293761: length 9.1
  TOP w0.102: v2(154.9,24.19) 156,25.29 QC20.3
  TOP w0.508: QC20.3 155.59,26.23 154.08,27.74 154.08,29.15 155.86,30.93 QC21.3
N24299188: length 4.6
  BOTTOM w0.102: RC153.1 147.45,24.41 v2(147.69,24.17)
  BOTTOM w0.254: 145.95,26.07 146.14,25.87 146.14,24.87 RC153.1 ; 145.95,26.07 145.95,26.45 145.68,26.72 QC22.3 ; 145.95,26.07 QC22.2
N24380776: length 3
  TOP w0.102: v2(61.92,13.57) 62.27,13.92 PR2222.1
  TOP w0.254: PR608.1 62.27,16.25 PR2221.2 PR2222.1
N24409303: length 6.6
  BOTTOM w0.102: RA53.1 v2(14.29,18.39)
  BOTTOM w0.203: UA1.33 10.9,21.81 11.93,20.78 11.93,20.55
  BOTTOM w0.305: CA60.1 12.13,18.41 11.93,18.61 11.93,20.55
  BOTTOM w0.381: CA60.1 12.91,18.41 RA53.1
N24409452: length 2.3
  BOTTOM w0.102: v2(3.62,22.34) CA52.1 RA50.2
N24409678: length 3.4
  BOTTOM w0.102: v2(10.27,30.5) CA63.1
  BOTTOM w0.203: UA1.15 9.7,27.81 9.65,27.86 9.65,28.45 10.27,29.07 CA63.1
N24409882: length 3.4
  BOTTOM w0.102: v2(15.03,26.34) 14.9,26.47 14.48,26.47 14.02,26.93 14.02,27.12 13.93,27.21 CA68.1
  BOTTOM w0.203: UA1.22 12.87,26.24 CA68.1
N24410711: length 2.5
  BOTTOM w0.102: CA57.2 13.78,22.29 14.18,21.9 v2(14.51,21.9)
  BOTTOM w0.203: UA1.30 12.77,23.04 13.02,22.79
  BOTTOM w0.254: 13.02,22.79 13.52,22.29 CA57.2
N24410726: length 5.5
  IN2 w0.254: v1(13.44,23.78) 13.44,22.46 14.16,21.73 v1(14.16,21.39)
  BOTTOM w0.102: v1(14.16,21.39) 14.58,20.97 14.66,20.97 v2(15,20.63)
  BOTTOM w0.203: 12.45,23.84 13.14,23.84
  BOTTOM w0.254: v1(13.44,23.78) 13.2,23.78 13.14,23.84 ; v1(14.16,21.39) 13.85,21.71 CA57.1
N24468122: length 13.9
  TOP w0.102: v3(158.75,49.7) 158.75,50.6 156.63,52.72 R272.2 156.52,56.27 155.98,56.8 C272.1 155.68,56.8 154.96,57.52 D303.2 154.32,58.81 154.16,58.97 v1(154.16,59.44)
  BOTTOM w0.102: JKB1.30 154.97,59.08 154.61,59.44 v1(154.16,59.44)
N24468142: length 8.9
  TOP w0.102: v1(155.78,59.43) 156.26,59.43 D303.3 156.89,57.83 156.63,57.57 156.63,57.06 ; v2(160.7,56.52) 160.53,56.69 158.69,56.69 157.9,57.49 157.06,57.49 156.63,57.06 ; R283.2 156.63,57.06
  BOTTOM w0.102: v1(155.78,59.43) 155.77,59.42 JKB1.31
N25213376: length 4.7
  TOP w0.102: RV1644.2 95.6,102.06 v2(95.75,101.91) 96.58,101.91 96.91,101.57 QV18.2
N28714558: length 2.5
  BOTTOM w0.203: PU703.5 151.2,16.79 v2(151.45,16.54) 151.84,16.15 PR777.2
N31626633: length 1.8
  TOP w0.102: v2(160.96,45.18) PR831.2
  TOP w0.254: PR832.1 160,45.92 PR831.2
N31626674: length 3.2
  TOP w0.102: PR838.2 158.19,47.01 v2(158.85,47.67)
  TOP w0.254: PR839.1 157.46,46 PR838.2
N31627184: length 2
  BOTTOM w0.102: v2(159.48,35.7) PR826.1
  BOTTOM w0.254: PR826.1 PR825.2
N31646442: length 4.1
  TOP w0.102: PR850.2 160.53,42.82 v2(160.81,42.54)
  TOP w0.254: PC833.1 PR850.2
N33488216: length 4.8
  TOP w0.102: v1(151.84,17.04) 151.84,15.05 v2(152.2,14.7)
  BOTTOM w0.203: PU703.4 151.68,17.19 v1(151.84,17.04) PR770.2
N37640332: length 1.3
  TOP w0.381: RV2.2 86.98,138.75 v1(86.74,139)
  BOTTOM w0.381: v1(86.74,139) 86.27,139 UV1.N10
N37640410: length 2
  TOP w0.102: v1(92.8,128.79) 92.64,128.79 v2(92.33,129.1)
  TOP w0.508: v1(92.8,128.79) 92.75,128.74 RV3.1
  BOTTOM w0.381: UV1.AA22 92.8,129.27 v1(92.8,128.79)
N37828209: length 2.8
  TOP w0.102: v2(90.41,129.43) 90.49,129.43 91.15,128.78 v1(91.56,128.78)
  TOP w0.508: RV1.1 91.74,128.6 v1(91.56,128.78)
  BOTTOM w0.381: UV1.Y22 91.56,129.47 91.56,128.78 v1(91.56,128.78)
N38038746: length 3.6
  TOP w0.102: v2(77.78,150.07) 78.21,150.5 RV36.2 78.22,151.02 CV96.1 79.85,150.22 RV37.2
N38038992: length 4
  TOP w0.102: CV98.2 83.15,144.14 83.15,141.64 v1(83.6,141.19)
  BOTTOM w0.102: UV1.K8 83.98,140.81 v1(83.6,141.19)
N38038994: length 8
  TOP w0.102: v2(87.46,143.87) 87.03,144.3 85.8,144.3 CV99.2 84.86,144.2 84.06,144.2 83.85,143.98 83.85,143.41 84.18,143.08 84.18,141.7 84.39,141.48 v1(84.39,141.17)
  BOTTOM w0.102: UV1.L7 84.72,141.49 v1(84.39,141.17)
N38038995: length 1.1
  TOP w0.102: CV98.1 RV40.2
N38038996: length 6.1
  TOP w0.102: v2(85.96,148.91) 85,147.96 RV41.2 85.77,147.73 86.76,146.74 86.76,145.98 85.97,145.19 CV99.1
N38349725: length 4.4
  TOP w0.102: RV39.2 84.86,123.55 84.86,124.48 v2(84.64,124.71) 84.42,124.92 v1(84.42,126.01)
  BOTTOM w0.102: UV1.K25 83.98,126.72 84.42,126.28 v1(84.42,126.01)
N72585933: length 1.4
  TOP w0.102: PC517.1 40.67,111.32 v3(41.47,112.12)
N99502843: length 1.3
  TOP w0.102: v1(93.54,46.33) 93.44,46.23 T28.1
  BOTTOM w0.102: v1(93.54,46.33) 93.97,46.76 UC1.AU23
N99511855: length 4.9
  BOTTOM w0.102: RC71.2 CC9.1 85.17,30.7 UC23.2 UC23.1 83.92,31.5 RC73.1 v2(83.92,33.6)
N102084029: length 3.3
  TOP w0.102: v2(31.08,112.95) R933.2
  TOP w0.254: Q411.1 29.17,114.04 29.87,113.34 R933.2
N110838109:
  vias: v2(17.52,99.01)
N115820979: length 5.7
  TOP w0.102: v2(182.89,11.18) 181.09,11.18 C847.1 179.77,11.54 179.21,11.54 178.84,11.9 178.3,11.9 178.25,11.86 U381.12
N115820982: length 5.9
  TOP w0.102: U381.10 178.3,11.06 178.35,11.02 179.4,11.02 C848.1 181.14,9.28 182.48,9.28 v2(182.86,9.66)
N119889933: length 2.1
  TOP w0.102: v1(51.03,105.12) 51.03,105.05 v2(50.6,104.61)
  TOP w0.254: v1(51.03,105.12) 51.45,105.12 PR1010.1
  BOTTOM w0.254: v1(51.03,105.12) 51.45,105.12 PR1010.1
N119889936: length 2.2
  TOP w0.102: v1(51.02,105.75) 50.92,105.75 v2(50.56,106.1)
  TOP w0.254: v1(51.02,105.75) 51.41,106.14 PR1012.1
  BOTTOM w0.203: v1(51.02,105.75) 50.87,105.75 50.51,105.39 PR1021.2
N119896729: length 2.7
  BOTTOM w0.102: v2(49.9,107.27) 49.9,106.91 50.24,106.57 50.24,106.29 PR1007.2
  BOTTOM w0.254: PR1013.1 51.45,106.33 50.89,106.33 50.7,106.14 PR1007.2
N119896747: length 1.9
  BOTTOM w0.102: v2(48.67,104.3) PR1023.2
  BOTTOM w0.254: PR1026.1 48.82,105.39 PR1023.2
N119932245: length 4.5
  BOTTOM w0.102: v2(59.4,102.23) PR1032.2
  BOTTOM w0.203: 58.38,104.23 57.54,105.08 PU1001.1
  BOTTOM w0.254: 58.38,104.23 PC1016.1
  BOTTOM w0.508: PC1016.1 58.4,103.66 PR1032.2
N119936487: length 2.2
  BOTTOM w0.102: PC1008.1 49.61,109.47 v2(49.61,109.66)
  BOTTOM w0.254: PR1001.1 PC1008.1
N119936846: length 40.4
  TOP w0.102: v2(51.97,107.97) 51.64,107.64 PR1008.2
  TOP w0.254: v1(50.62,106.96) PR1008.2
  IN1 w0.254: v1(74.39,99.28) 74.26,99.15 74.26,98.71 73.05,97.5 51.27,97.5 49.75,99.03 49.75,104.3 50.07,104.61 50.07,106.41 v1(50.62,106.96)
  BOTTOM w0.254: PH1001.1 74.26,101.94 74.26,99.41 v1(74.39,99.28) ; v1(50.62,106.96) PR1009.1
N119936854: length 39.8
  TOP w0.102: v1(50.62,107.79) 51.22,108.39 v2(51.22,109.2)
  IN1 w0.254: v1(73.75,99.28) 73.83,99.21 73.83,98.85 72.86,97.88 51.46,97.88 50.13,99.22 50.13,104.11 50.45,104.42 50.45,106.06 51.11,106.72 51.11,107.54 50.85,107.79 v1(50.62,107.79)
  BOTTOM w0.254: PH1001.2 73.88,101.81 73.88,99.41 v1(73.75,99.28) ; PR1011.2 v1(50.62,107.79)

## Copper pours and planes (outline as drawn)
3V_SN on TOP (solid shape): 158.71,21.11 158.71,20.35 158.59,20.22 155.86,20.22 155.86,21.24 158.59,21.24
5V_SN on TOP (solid shape): 166.68,22.68 166.68,22.03 167.16,21.56 168.24,21.56 168.24,19.91 167.22,19.91 167.22,20.35 165.83,21.75 165.83,22.76 166.6,22.76
+0.6V_DDR_VREFCA on BOTTOM (solid shape): 26.57,49.24 26.57,48.37 27.84,47.1 27.84,46.88 28,46.73 29.69,46.73 29.76,46.66 29.76,46.41 29.69,46.35 27.24,46.35 26.69,45.8 25.97,45.8 25.97,49.27 26,49.31 26.51,49.31
+0.6VS on TOP (solid shape): 30.38,23.26 30.38,22.83 30.15,22.6 28.98,22.6 28.84,22.74 28.84,23.79 28.92,23.87 29.77,23.87
+0.6VSP on BOTTOM (solid shape): 35.49,114.37 35.49,114.27 35.41,114.19 34.62,114.19 34.09,113.66 34.09,112.73 33.92,112.57 31.22,112.57 31.04,112.39 30.48,112.39 30.48,113.12 30.46,113.15 29.87,113.15 29.87,113.35 29.9,113.38 33.28,113.38 34.32,114.42 35.44,114.42
+0.95VALW on TOP (solid shape): 88.77,109.22 88.77,108.55 88.61,108.39 88.61,107.15 86.64,107.15 86.58,107.22 86.58,108.84 87.02,109.29 88.7,109.29
+0.95VALW on TOP (solid shape): 67.66,88.74 67.46,88.55 65.75,88.55 65.62,88.68 65.62,91.41 65.75,91.53 67.66,91.53
+0.95VALW on TOP (solid shape): 83.91,25.62 83.91,24.8 83.02,24.8 82.58,25.24 82.58,25.81 82.9,26.13 83.4,26.13
+0.95VALW on TOP (solid shape): 70.13,29.9 70.13,24.99 69.81,24.67 64.35,24.67 64.04,24.99 64.04,26.83 65.11,27.9 65.11,29.98 65.4,30.28 69.76,30.28
+0.95VALW on TOP (solid shape): outline of 119 points within 99.48,41.56 102.39,50.78
+0.95VALW on BOTTOM (solid shape): 67.21,89.57 67.21,87.15 65.18,87.15 65.18,89.57 65.37,89.76 67.02,89.76
+0.95VALW on BOTTOM (solid shape): 83.59,26.64 83.59,25.37 83.4,25.18 82.51,25.18 82.39,25.3 82.39,26.38 80.55,28.22 80.55,28.73 80.74,28.92 81.31,28.92
+0.95VALW on BOTTOM (solid shape): 70.51,28.99 69.88,28.35 69.88,26.26 69.62,26 68.73,26 68.73,26.57 66.7,26.57 66.7,26 64.73,26 63.53,27.21 63.53,29.88 70.51,29.88
+0.95VALWP on TOP (solid shape): 70.13,23.91 70.13,22.26 69.88,22 65.31,22 65.31,24.16 69.88,24.16
+0.95VALWP on BOTTOM (solid shape): 70.51,25.56 70.51,22.13 70.77,21.87 70.77,20.22 70.45,19.91 67.34,19.91 67.21,20.03 67.21,21.56 66.96,21.81 65.5,21.81 65.31,22 65.31,24.16 65.05,24.41 64.8,24.41 64.8,24.54 65.05,24.8 65.05,25.81 70.26,25.81
+0.95VGS on TOP (solid shape): 88.74,111.85 88.74,110.62 88.67,110.56 87.66,110.56 87.51,110.71 86.13,110.71 86.01,110.84 86.01,111.85 86.58,111.85 87.09,112.36 88.23,112.36
+0.95VGS on TOP (solid shape): 97.77,137.46 97.03,137.46 96.65,137.08 95.89,137.08 95.66,136.85 95.66,136.14 95.56,136.03 95.3,136.03 95.2,136.14 95.2,137.38 95.43,137.61 96.37,137.61 96.85,138.09 97.77,138.09
+0.95VGS on TOP (solid shape): outline of 385 points within 84.86,120.88 94.52,129.75
+0.95VGS on BOTTOM (solid shape): 86,129.78 86.21,129.7 86.42,129.78 88.1,129.78 88.14,129.74 88.16,129.74 88.26,129.69 88.36,129.68 88.5,129.7 88.62,129.78 88.9,129.78 89.16,129.65 89.43,129.78 90.7,129.78 90.88,129.6 90.88,129.06 90.48,128.65 90.28,128.65 89.92,129.02 89.65,129.02 89.34,128.7 89.07,128.7 88.75,129.02 88.44,129.02 88.06,128.65 87.96,128.65 87.61,129.01 87.26,129.01 86.99,128.74 86.99,128.38 85.82,127.21 85.82,125.95 85.7,125.83 85.06,125.83 84.77,126.12 84.77,126.47 84.88,126.71 84.77,126.96 84.77,126.98 84.53,127.21 84.28,127.21 84.09,127.41 84.09,127.57 84.13,127.6 84.16,127.64 84.19,127.67 84.23,127.7 84.72,128.18 84.72,128.22 84.72,128.23 84.72,128.77 85.73,129.78
+0.95VGS on IN1 (solid shape): outline of 2423 points within 85.1,111.22 103.47,144.3
+0.95VS on TOP (solid shape): outline of 2584 points within 66.58,28.54 94.88,51.33
+0.95VS on IN1 (solid shape): outline of 217 points within 88.93,49.05 95.15,51.47
+0.95VS on VCC: 74.81,35.4 74.39,35.82 74.39,40.23 81.67,40.23 84.78,43.34 85.48,43.34 88.1,45.96 88.1,48.06 89.31,49.26 89.31,50.47 89.99,51.15 94.54,51.15 94.9,50.79 94.9,37.5 88.19,37.5 86.09,35.4
+0.775VALW on BOTTOM (solid shape): 152.24,34.7 152.24,34.26 151.22,34.26 151.22,35.27 151.67,35.27
+0.775VALWP on BOTTOM (solid shape): 151.03,35.02 150.46,35.02 150.46,34.51 151.03,34.51 151.03,34.26 150.27,34.26 149.95,34.57 148.74,34.57 148.49,34.32 148.49,33.56 148.68,33.37 149.06,33.37 149.32,33.11 149.32,32.66 149.14,32.48 147.41,32.48 147.28,32.61 146.19,32.61 146.17,32.63 146.17,34.3 146.52,34.65 147.61,34.65 148.24,35.27 151.03,35.27
+1.2V on TOP (solid shape): outline of 7385 points within 27.33,45.87 89.61,97.25
+1.2V on BOTTOM (solid shape): 33.81,100.49 36.29,100.49 36.29,100.17 40.22,96.23 40.22,93.57 39.59,92.93 28.73,92.93 28.16,93.5 28.16,100.49 30.63,100.49 30.63,101.06 33.81,101.06
+1.2V on BOTTOM (solid shape): 28.87,52.67 29.18,52.67 29.36,52.48 29.36,51.97 29.29,51.9 28.87,51.9 28.72,51.89 28.57,51.85 28.22,51.85 27.65,51.27 27.65,50.77 27.78,50.64 27.78,50.39 27.65,50.26 27.65,49.37 27.84,49.18 27.84,48.93 27.78,48.93 27.65,48.8 27.65,48.42 27.4,48.42 26.82,48.99 26.82,49.5 26.63,49.69 26,49.69 26,50.96 27.71,52.67 28.83,52.67
+1.2V on VCC: 74.24,40.73 72.59,42.38 38.68,42.38 35.76,45.31 27.4,45.31 27.4,65.24 30.87,65.24 36.07,70.45 69.33,70.45 70.03,69.75 82.83,69.75 82.83,67.3 86.92,63.21 87.74,63.21 89.63,61.33 89.63,51.51 88.8,50.68 88.8,49.48 87.59,48.27 87.59,46.17 85.27,43.85 84.57,43.85 81.46,40.73
+1.2V on GND: 30.36,46.89 29.91,47.34 28.07,47.34 28.03,47.38 28.03,53.09 27.33,53.79 27.33,61.65 28.39,62.7 29.66,62.7 31.14,64.19 31.14,64.95 31.31,65.12 34.59,65.12 34.7,65.01 34.7,64.19 36.37,62.51 38.47,62.51 38.64,62.35 38.64,57.14 39.21,56.57 39.21,51.13 38.7,50.62 38.7,48.52 38.02,47.85 36.24,47.85 35.29,46.89
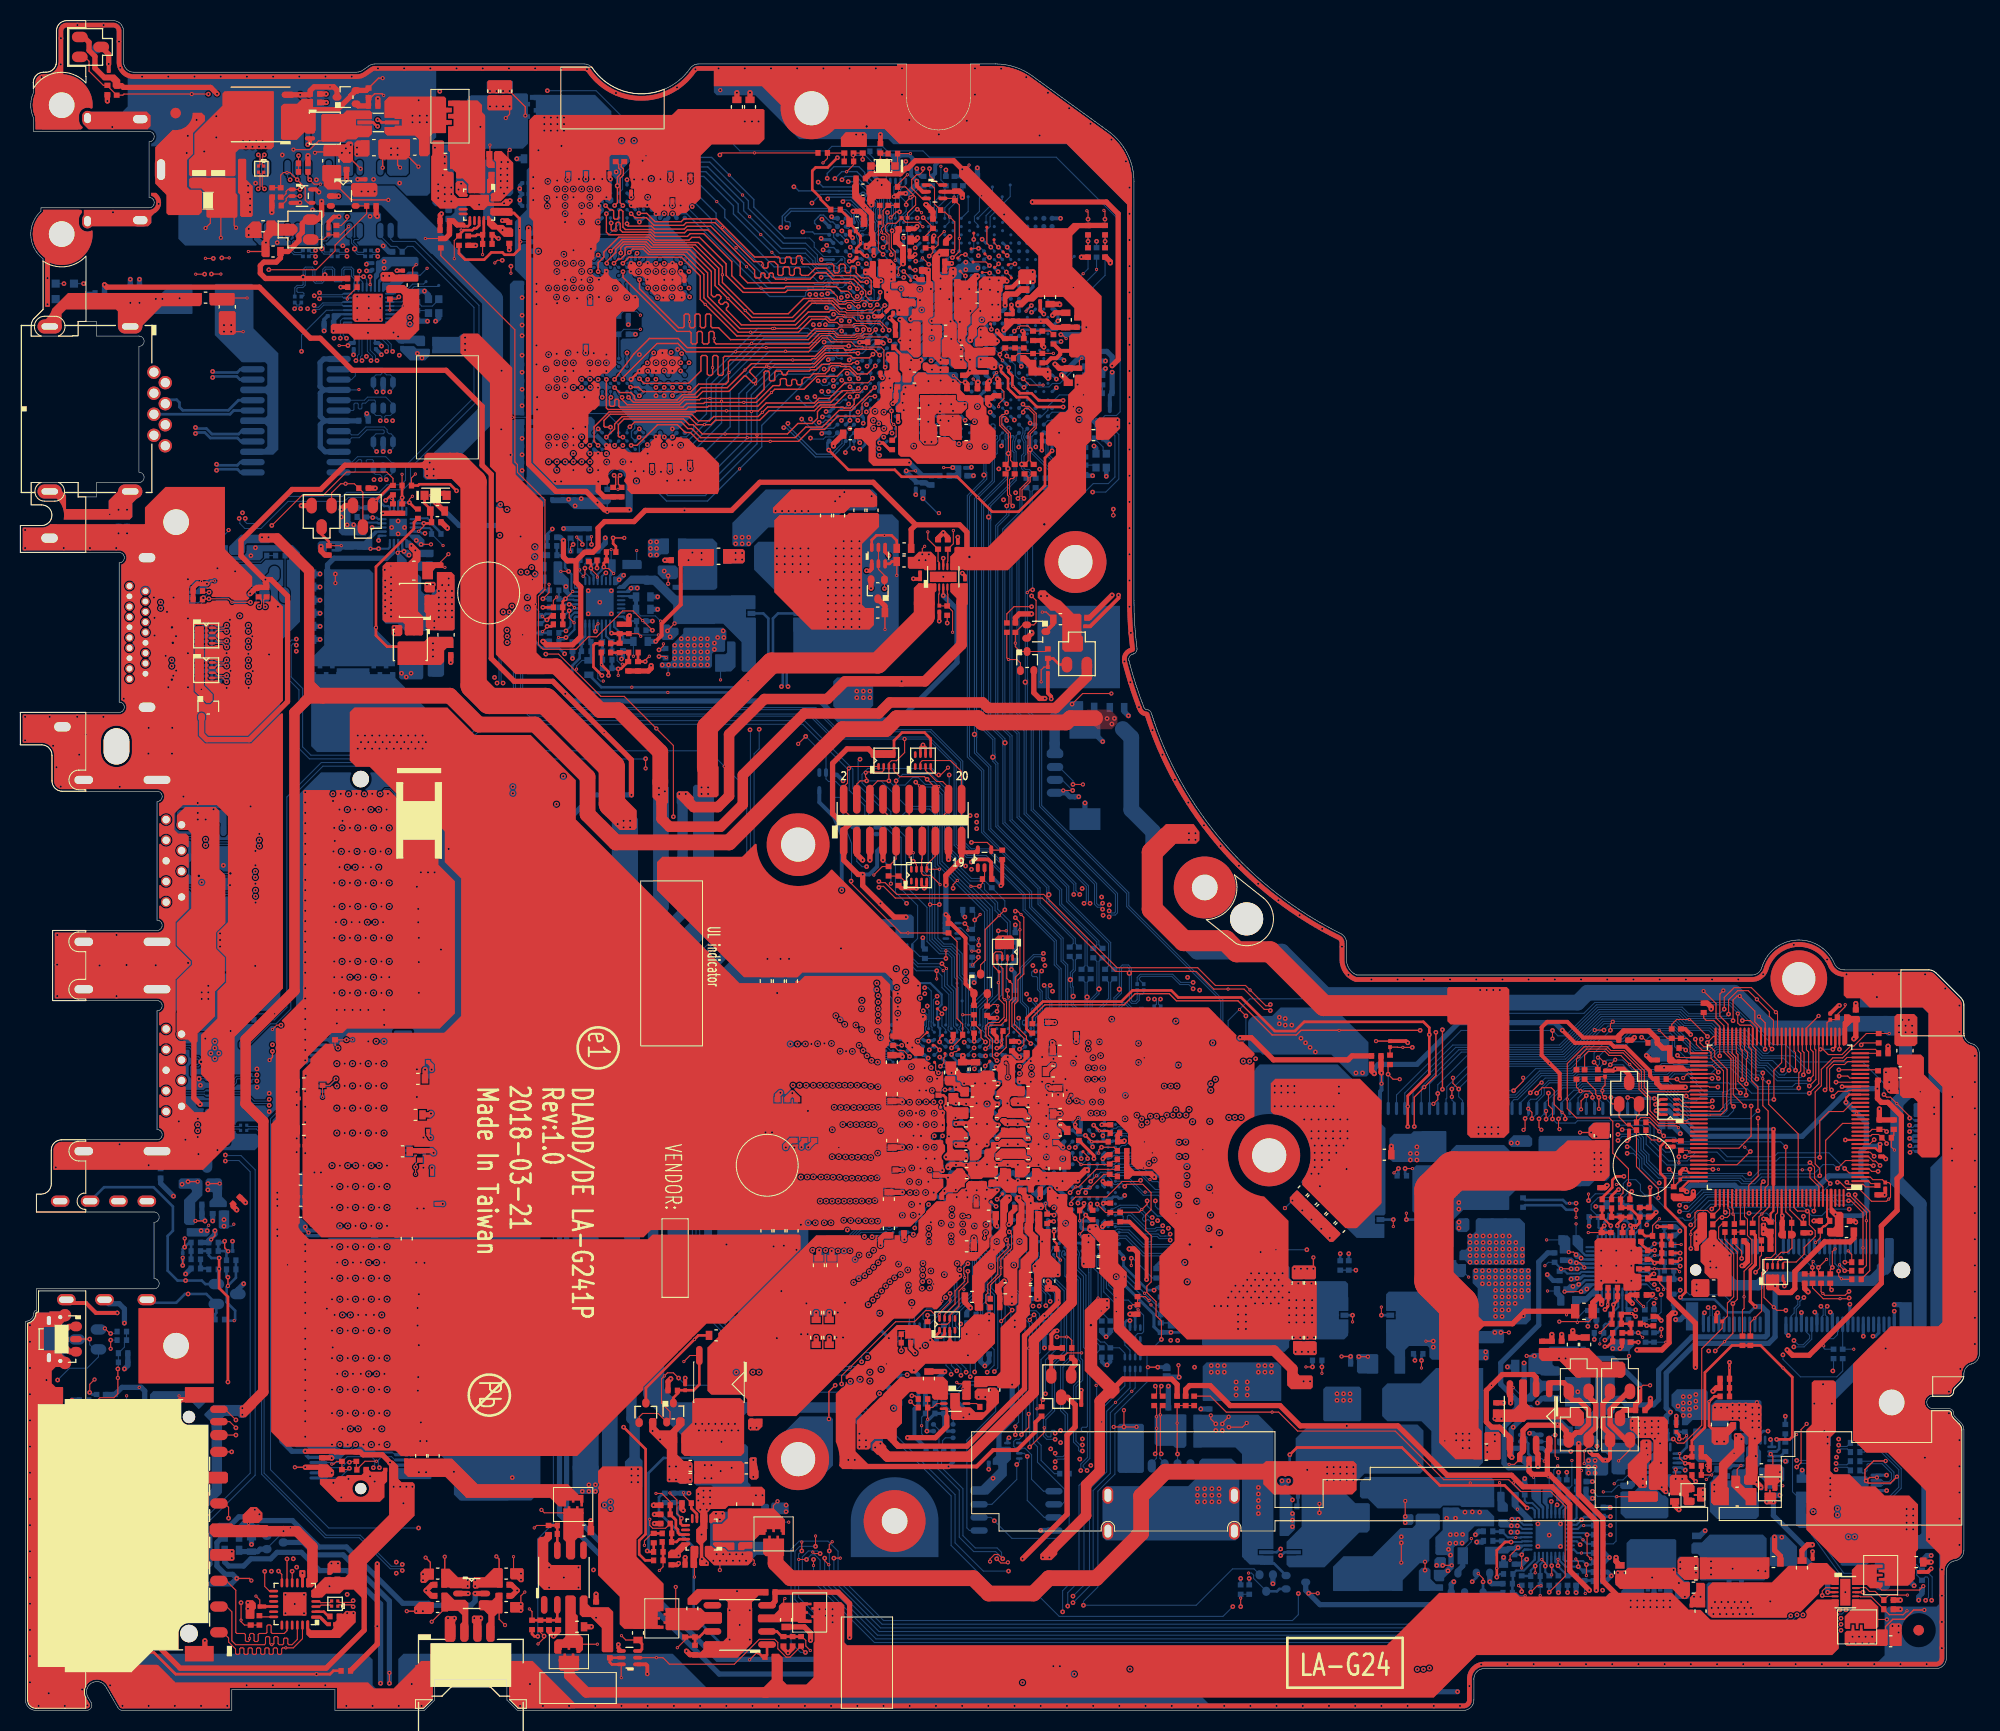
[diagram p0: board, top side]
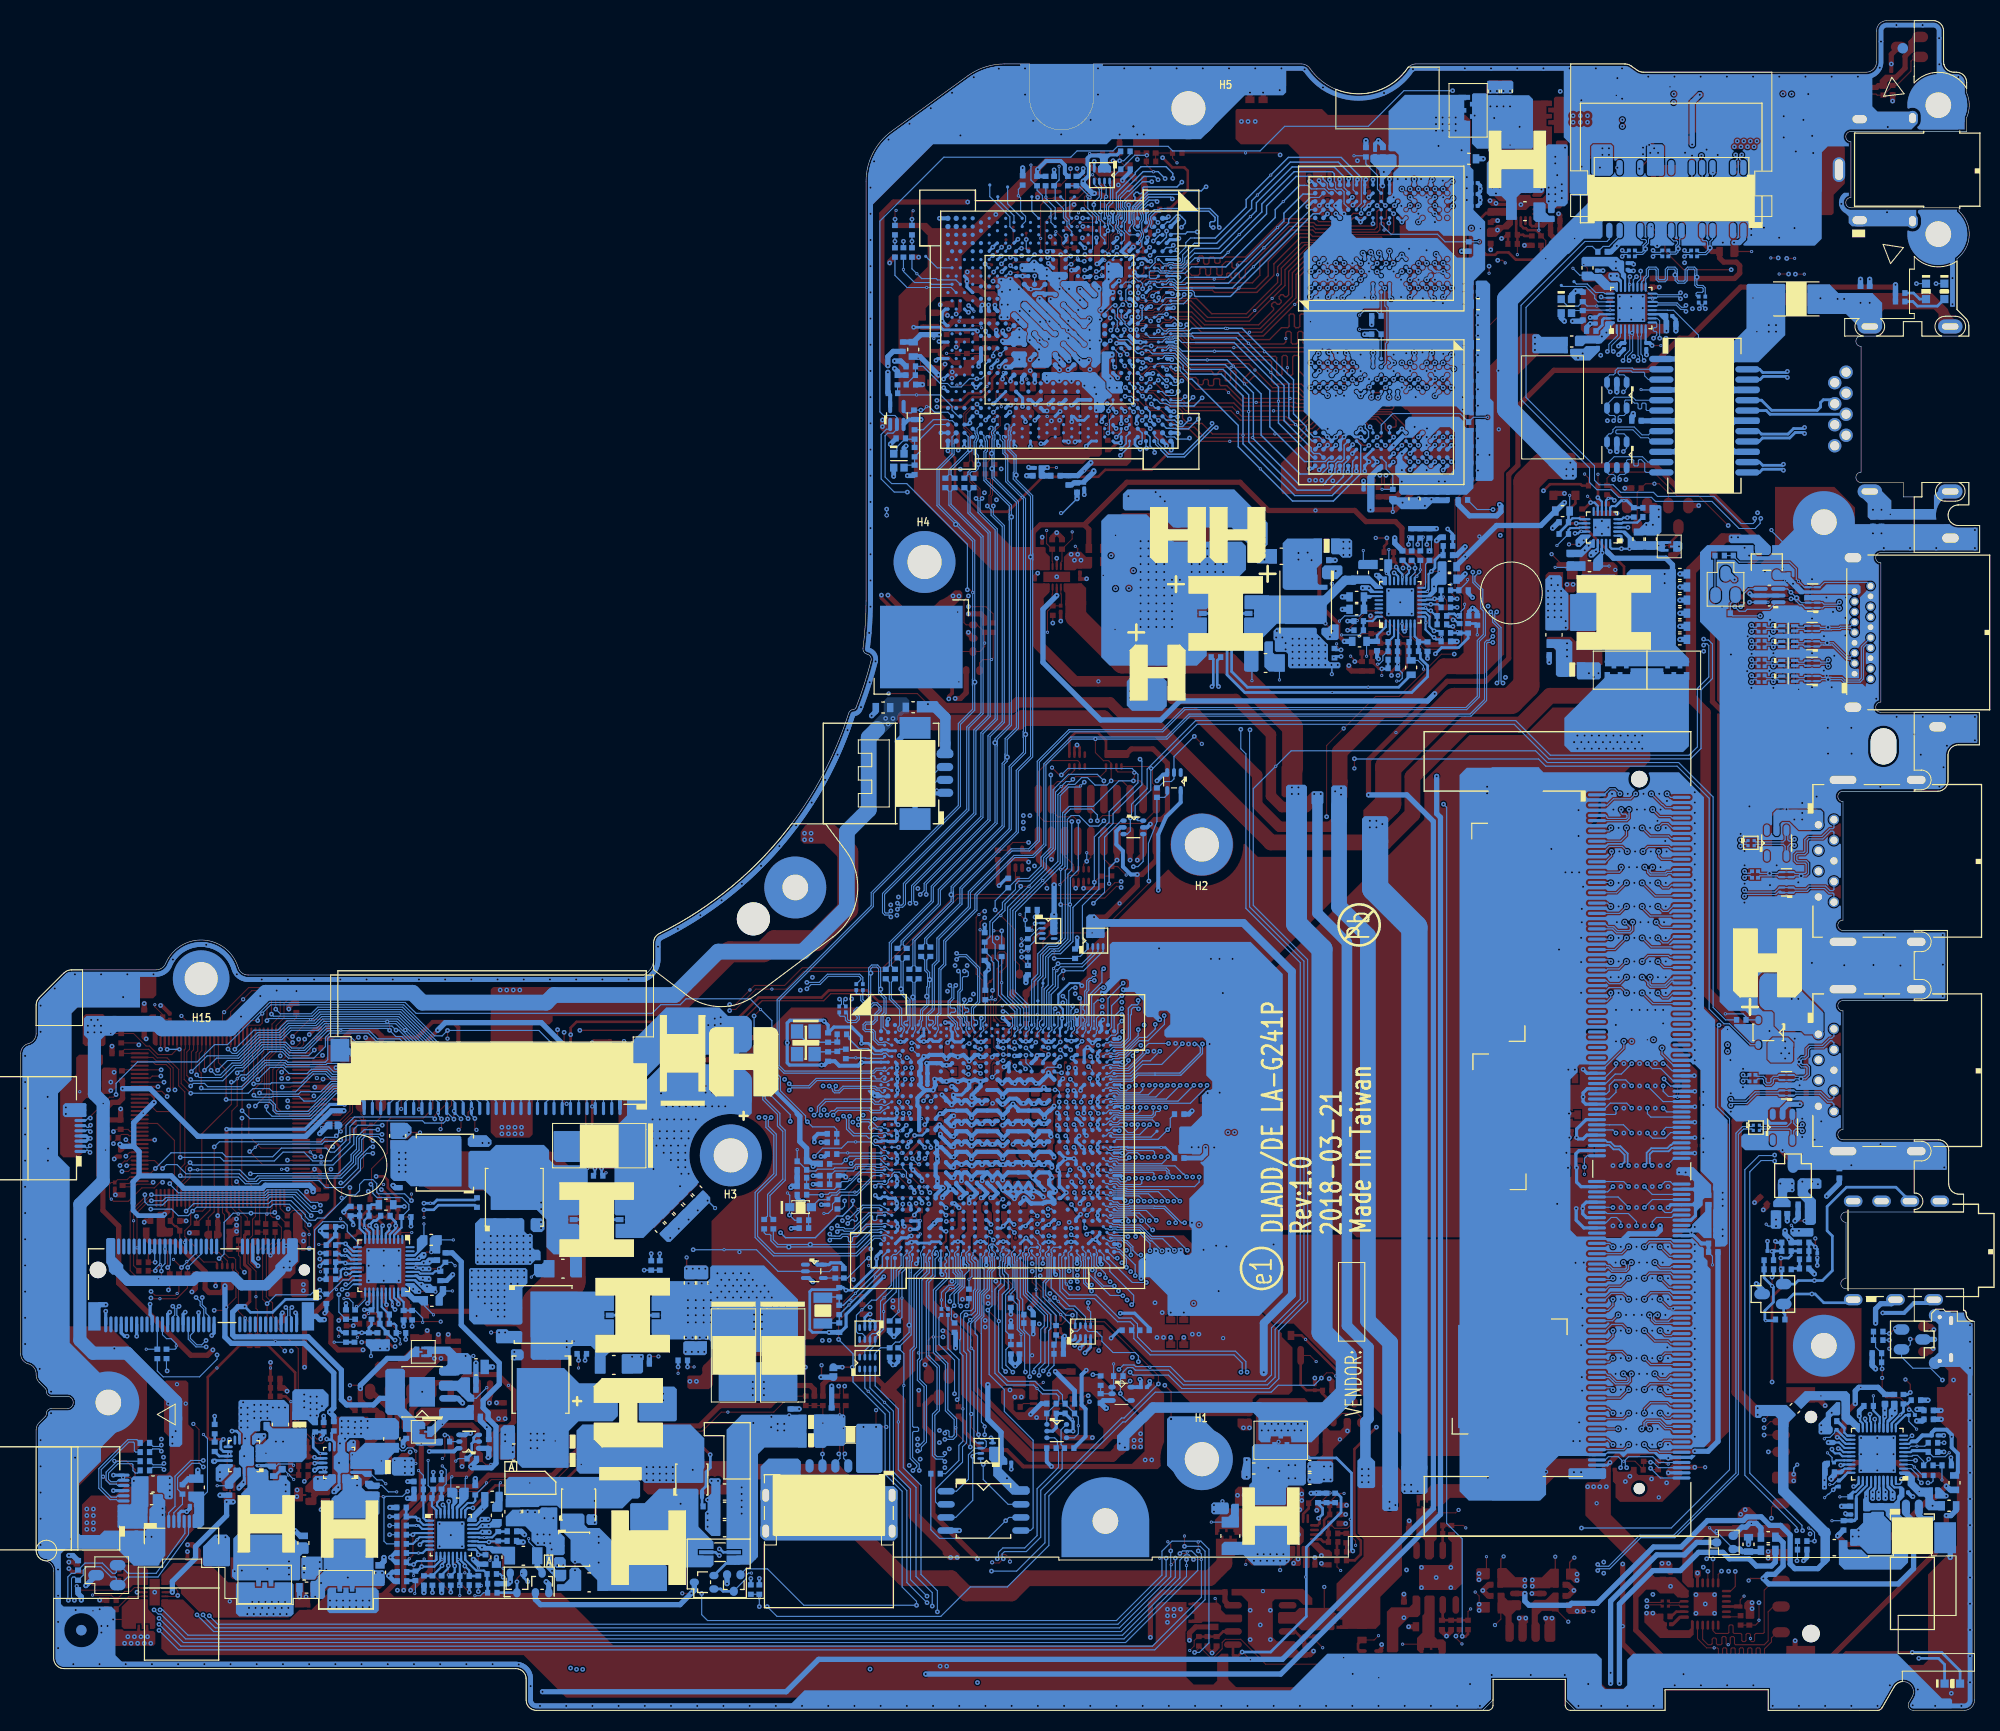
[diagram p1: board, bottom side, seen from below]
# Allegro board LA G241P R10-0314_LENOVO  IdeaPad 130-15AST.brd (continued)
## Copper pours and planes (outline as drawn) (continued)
+1.2V on GND: 86.12,45.94 85.82,46.25 85.82,52.43 86.58,53.19 86.58,55.52 85.94,56.15 85.94,57.04 85.24,57.74 85.24,58.08 85.82,58.65 85.82,63.48 85.93,63.59 86.34,63.59 86.39,63.54 86.39,62.84 86.65,62.58 88.37,62.58 88.55,62.4 88.55,61.7 89.31,60.94 89.31,60.54 88.74,59.96 88.74,58.33 89,58.07 89.45,58.07 89.63,57.89 89.63,54.31 89.25,53.93 89.25,53.44 89.44,53.25 89.44,52.34 89.18,52.09 89.18,49.42 87.78,48.03 87.78,47.39 87.61,47.21 87.16,47.21 86.9,46.95 86.9,46.06 86.78,45.94
+1.2VP on BOTTOM (solid shape): 34.19,110.27 34.19,105.06 36.29,102.96 36.29,101.25 28.16,101.25 28.16,102.01 29.43,103.28 29.43,110.65 33.81,110.65
+1.8VALW on TOP (solid shape): 65.24,88.55 65.24,87.98 64.92,87.66 64.48,87.66 63.59,88.55 63.59,88.93 63.78,89.12 64.67,89.12
+1.8VALW on TOP (solid shape): 91.8,109.25 91.8,107.27 91.75,107.22 91.72,107.22 91.66,107.15 90.82,107.15 90.71,107.27 90.71,107.87 90.12,108.45 90.12,109.24 90.19,109.3 91.75,109.3
+1.8VALW on TOP (solid shape): outline of 96 points within 81.05,25.3 89.88,32.35
+1.8VALW on TOP (solid shape): outline of 130 points within 55.97,7.9 62.32,23.65
+1.8VALW on BOTTOM (solid shape): 60.29,24.21 60.29,21.75 60.1,21.56 58.73,21.56 58.57,21.71 58.57,24.13 59,24.55 59.95,24.55
+1.8VALW on BOTTOM (solid shape): 64.73,88.99 64.73,87.91 64.67,87.85 63.72,87.85 63.59,87.98 63.59,88.99 63.72,89.12 64.61,89.12
+1.8VALW on IN1 (solid shape): outline of 422 points within 58.77,21.62 82.2,30.07
+1.8VALW on IN2 (solid shape): outline of 102 points within 98.45,41.37 99.85,49.94
+1.8VALWP on TOP (solid shape): 66.32,9.54 67.86,9.54 67.98,9.41 67.98,8.53 67.86,8.4 66.35,8.4 65.72,7.78 62.64,7.78 62.51,7.9 62.51,9.94 65.92,9.94
+1.8VGS on TOP (solid shape): outline of 173 points within 90.11,110.56 104.78,149.76
+1.8VS on TOP (solid shape): 84.8,92.42 84.74,92.36 82.51,92.36 82.39,92.49 82.39,93.06 82.45,93.12 84.8,93.12
+1.8VS on TOP (solid shape): 97.5,50.64 97.5,50.13 97.63,50 97.94,50 98.2,49.75 98.2,49.37 98.33,49.24 99.02,49.24 99.11,49.16 99.11,49.14 99.15,49.04 99.21,48.96 99.21,48.73 99.02,48.54 98.26,48.54 98.2,48.48 98.2,47.27 98.14,47.21 98.14,46.46 98.63,45.97 98.63,43.96 97.94,43.27 97.94,39.51 97.79,39.29 97.83,39.02 97.83,38.41 97.48,38.05 97.48,37.19 96.87,36.57 96.87,31.65 96.44,31.23 94.83,31.23 94.6,31.46 93.76,31.46 93.64,31.34 92.69,31.34 92.68,31.34 92.48,31.34 92.43,31.39 92.43,31.93 92.43,32.3 92.56,32.42 94.59,32.42 94.99,32.83 94.99,37.12 96.53,38.66 96.53,39.19 96.74,39.41 96.74,42.64 96.93,42.82 96.93,43.72 97.77,44.56 97.77,45.89 97.31,46.35 97.31,47.21 97.44,47.34 97.44,49.22 97.09,49.56 97.1,49.69 97.09,49.75 97.09,49.9 96.95,50.05 96.93,50.05 96.9,50.08 96.8,50.08 96.67,50.2 96.67,50.64 96.74,50.7 97.44,50.7
+1.8VS on BOTTOM (solid shape): 90.07,77.25 90.07,75.34 89.94,75.21 89.5,75.21 89.37,75.34 89.37,77.25 89.44,77.31 89.44,77.37 89.94,77.37
+1.8VS on BOTTOM (solid shape): 86.58,76.93 86.58,74.96 86.51,74.9 84.93,74.9 84.8,75.02 84.8,76.74 85.31,76.74 85.75,77.18 86.32,77.18
+1.8VS on BOTTOM (solid shape): 95.99,25.48 95.99,24.33 95.6,23.93 95.6,22.76 93.77,20.93 92.24,20.93 92.07,21.1 92.07,21.52 92.28,21.74 93.08,21.74 94.76,23.42 94.76,23.72 94.67,23.82 94.27,23.82 94.24,23.86 94.24,24.39 94.57,24.72 94.57,25.47 94.66,25.56 95.91,25.56
+1.8VS on IN2 (solid shape): 98.33,49.88 98.33,49.31 98.52,49.12 98.96,49.12 99.09,48.99 99.09,47.85 98.2,46.96 98.2,44.04 97.75,43.59 97.75,37.62 97.75,37.62 97.75,37.49 97.11,36.85 96.33,36.85 96.1,37.08 96.1,38.18 96.52,38.59 96.52,42.34 96.67,42.5 96.67,44.54 97.31,45.18 97.31,49.81 97.5,50 98.2,50
+1.8VS_R on TOP (solid shape): 92.1,31.91 92.1,30.19 92.04,30.13 91.34,30.13 91.28,30.19 91.28,31.84 91.4,31.97 92.04,31.97
+1.35VGSP on TOP (solid shape): 47.65,156.49 47.65,155.29 47.53,155.16 45.37,155.16 45.24,155.29 45.24,156.49 45.37,156.62 47.53,156.62
+1.35VGSP on BOTTOM (solid shape): 49.18,156.68 49.18,151.92 48.7,151.45 43.4,151.45 43.27,151.57 43.27,156.24 43.65,156.62 47.65,156.62 47.84,156.81 49.05,156.81
+1.35VS_VRAM on TOP (solid shape): 84.54,140.53 84.54,140.52 84.59,140.44 84.67,140.39 84.68,140.38 84.84,140.23 84.84,139.29 84.83,139.21 84.84,139.13 84.84,138.64 84.75,138.55 84.36,138.55 84.28,138.47 84.28,137.84 84.43,137.69 85.02,137.69 85.3,137.41 85.3,137.07 85.42,136.95 86,136.95 86.05,136.9 86.59,136.9 86.74,136.75 86.74,136.16 86.24,136.16 86.06,135.98 86.06,135.3 86.01,135.25 85,135.25 84.89,135.35 84.89,135.82 84.83,135.88 84.38,135.88 83.91,135.41 83.66,135.67 83.95,135.96 83.97,135.96 84.13,136.11 84.13,136.52 83.7,136.95 83.7,137.69 83.47,137.91 83.47,138.3 83.57,138.3 83.72,138.45 83.72,138.8 83.54,138.98 83.26,138.98 83.14,139.11 83.14,140.63 83.24,140.73 84.33,140.73
+1.35VS_VRAM on TOP (solid shape): outline of 317 points within 58.95,128.82 63.95,131.98
+1.35VS_VRAM on TOP (solid shape): outline of 404 points within 80.78,120.68 86.39,131.72
+1.35VS_VRAM on TOP (solid shape): outline of 555 points within 58.84,136.63 64.46,140.45
+1.35VS_VRAM on TOP (solid shape): outline of 4519 points within 49.3,117.95 72.1,155.29
+1.35VS_VRAM on BOTTOM (solid shape): 84.66,140.33 84.66,138.8 85.02,138.45 85.02,138.06 85.01,138.06 85.01,137.62 85.02,137.62 85.02,136.24 85.09,136.17 85.09,136.13 85.21,136.01 85.27,135.99 85.37,135.88 85.37,135.7 85.24,135.58 85.07,135.58 84.33,136.31 84.33,137.05 84.1,137.28 83.9,137.28 83.77,137.41 83.77,137.63 83.87,137.74 84.18,137.74 84.33,137.89 84.33,138.32 83.72,138.93 83.52,138.93 83.39,138.96 83.26,138.93 83.09,138.93 83.01,139.01 83.01,139.95 83.44,140.38 84.13,140.38 84.25,140.51 84.48,140.51
+1.35VS_VRAM on BOTTOM (solid shape): 85.09,131.65 85.09,130.64 85.09,130.63 85.09,129.33 84.61,128.85 84.61,128.22 84.17,127.78 84.12,127.74 84.08,127.71 83.12,127.71 83.01,127.81 83.01,128.05 83.11,128.29 83.01,128.52 83.01,128.76 83.13,128.88 83.68,128.88 83.88,129.09 83.88,129.17 84.15,129.44 84.2,129.47 84.23,129.52 84.37,129.65 84.37,131.02 84.2,131.19 84.05,131.19 84,131.19 83.93,131.19 83.83,131.29 83.83,131.64 83.97,131.78 84.96,131.78
+1.35VS_VRAM on BOTTOM (solid shape): 62.23,146.39 62.26,146.38 62.29,146.37 62.62,146.04 62.62,145.83 62.22,145.44 62.22,145.42 62.2,145.41 62.11,145.32 62.06,145.2 62.05,145.19 61.91,145.05 61.9,145.04 61.75,144.5 62.3,144.65 62.3,144.67 62.36,144.72 62.37,144.73 62.39,144.74 62.56,144.77 62.71,144.9 62.73,144.9 62.91,144.9 62.97,144.84 62.97,144.72 62.97,144.7 62.95,144.68 62.83,144.53 62.81,144.33 62.82,144.32 62.81,144.29 62.34,143.82 61.2,143.82 60.88,144.14 60.88,144.77 60.88,144.8 60.9,144.83 60.9,144.99 60.91,145 60.93,145.01 60.97,145.01 61.49,145.07 61.74,145.53 61.74,145.57 61.8,145.63 61.8,146.46 61.89,146.54 62.08,146.54
+1.35VS_VRAM on BOTTOM (solid shape): 53.52,139.99 53.63,139.97 53.75,139.7 54.02,139.58 54.15,139.3 54.43,139.17 54.55,138.9 54.76,138.81 54.78,138.8 54.85,138.74 54.84,138.7 54.85,138.67 54.83,138.65 54.81,138.65 54.56,138.57 54.44,138.28 54.33,138.3 54.3,138.36 54.21,138.56 54,138.65 53.94,138.68 53.91,138.75 53.81,138.97 53.59,139.06 53.57,139.06 53.5,139.13 53.5,139.15 53.39,139.37 53.15,139.45 53.13,139.45 53.08,139.5 53.18,139.6 53.2,139.61 53.42,139.71 53.5,139.95
+1.35VS_VRAM on BOTTOM (solid shape): outline of 132 points within 49.05,117.89 57.37,125.44
+1.35VS_VRAM on BOTTOM (solid shape): outline of 5217 points within 47.91,123.6 65.5,156.66
+1.35VS_VRAM on IN1 (solid shape): outline of 3059 points within 50.32,127.6 84.86,154.97
+1.35VS_VRAM on IN2 (solid shape): outline of 1974 points within 80.01,126.95 86.83,140.55
+2.5V on TOP (solid shape): 44.29,21.94 53.05,21.94 54.51,20.48 54.51,19.78 54.26,19.78 54.26,20.35 52.86,20.35 52.86,19.78 52.16,19.78 51.34,20.6 43.21,20.6 41.18,22.64 37.56,22.64 37.18,23.02 37.18,24.41 41.81,24.41
+2.5V on BOTTOM (solid shape): 37.98,23.48 39.71,23.48 39.83,23.36 39.83,22.52 39.73,22.43 36.34,22.43 36.18,22.58 36.18,23.37 36.3,23.48 37.98,23.48
+2.5VP on TOP (solid shape): 54.57,16.79 54.51,16.73 54,16.73 53.75,16.48 53.75,14.83 53.56,14.64 53.11,14.64 52.86,14.89 52.86,16.35 52.61,16.6 52.61,19.59 54.57,19.59
+3V_LAN on TOP (solid shape): outline of 97 points within 30.06,132.94 38.64,138.22
+3V_LAN on BOTTOM (solid shape): 32.16,135.45 32.16,135.32 32.11,135.27 31.09,135.27 30.61,134.79 30.61,133.62 30.53,133.55 30.18,133.55 30.08,133.65 30.08,134.79 30.15,134.87 30.15,135.4 30.25,135.5 32.11,135.5
+3V_LAN on BOTTOM (solid shape): 36.3,134.57 36.3,134.23 36.45,134.07 36.45,134.04 36.73,133.76 36.73,133.44 36.86,133.32 39.08,133.32 39.21,133.19 39.21,132.36 39.14,132.3 38.45,132.3 38.19,132.55 36.65,132.55 35.7,133.51 35.7,134.17 35.38,134.5 35.35,134.5 35.33,134.51 35.33,134.61 35.41,134.69 36.18,134.69
+3VALW on TOP (solid shape): 54.13,3.97 54,3.84 52.35,3.84 52.16,4.03 52.16,5.3 54.13,5.3
+3VALW on TOP (solid shape): 100.48,15.65 100.48,15.14 99.91,14.57 98.96,14.57 98.83,14.7 98.83,15.14 99.79,16.1 100.04,16.1
+3VALW on TOP (solid shape): 9.65,158.11 9.65,157.33 9.57,157.25 9.13,157.25 8.92,157.45 8.92,157.85 8.71,158.06 8.02,158.06 7.86,158.22 7.86,158.43 8.06,158.62 9.14,158.62
+3VALW on TOP (solid shape): 62.77,88.04 62.64,87.91 62.64,87.79 61.62,87.79 61.62,88.17 61.24,88.55 61.24,90.26 62.77,90.26
+3VALW on TOP (solid shape): 64.9,16.21 64.9,16.08 64.84,16.01 64.78,16.01 63.97,15.21 63.97,14.89 63.85,14.76 62.77,14.76 62.77,15.33 63.02,15.59 63.39,15.59 64.09,16.28 64.84,16.28
+3VALW on TOP (solid shape): 107.47,52.8 107.98,52.29 109.69,52.29 110.16,51.82 110.16,51.53 110.07,51.43 109.79,51.43 109.37,51.85 107.79,51.85 107.47,51.53 106.96,51.53 106.96,54.51 107.47,54.51
+3VALW on TOP (solid shape): 105.56,39.84 105.56,39.02 104.36,37.81 104.36,33.43 106.52,31.27 106.52,30.83 105.95,30.26 105.18,30.26 105.18,30.89 103.15,32.92 103.15,38.83 104.29,39.97 105.44,39.97
+3VALW on TOP (solid shape): 45.46,144.87 45.46,144.81 46.22,144.05 46.76,144.05 47.02,143.79 47.56,143.79 47.75,143.6 47.75,142.97 47.67,142.89 46.84,142.89 46.13,143.6 45.65,143.6 45.21,144.05 45.21,144.87 45.27,144.94 45.4,144.94
+3VALW on TOP (solid shape): outline of 140 points within 95.28,39.27 97.59,49.95
+3VALW on TOP (solid shape): outline of 364 points within 71.91,1.24 176.24,11.4
+3VALW on TOP (solid shape): outline of 654 points within 42.64,100.49 50.76,133.51
+3VALW on BOTTOM (solid shape): 62.83,89.5 62.83,86.14 61.31,86.14 61.31,89.5 61.5,89.69 62.64,89.69
+3VALW on BOTTOM (solid shape): 57.88,19.52 57.69,19.33 56.48,19.33 56.35,19.46 56.35,21.87 57.88,21.87
+3VALW on BOTTOM (solid shape): 43.33,133.32 43.33,131.73 43.21,131.6 39.91,131.6 39.91,133.19 42.45,133.19 42.7,133.44 43.21,133.44
+3VALW on BOTTOM (solid shape): 157.38,11.39 158.09,11.39 158.09,11.9 158.58,11.9 158.58,11.39 159.28,11.39 159.28,11.9 159.93,11.9 160.13,11.7 160.13,9.63 159.93,9.43 155.41,9.43 155.16,9.68 155.16,11.59 155.48,11.9 157.38,11.9
+3VALW on BOTTOM (solid shape): 113.95,53.05 113.88,52.99 113.44,52.99 113.25,52.8 113.25,52.67 113.18,52.61 112.87,52.61 112.74,52.74 112.11,52.74 112.11,53.31 113.12,53.31 113.44,53.62 113.44,53.69 113.95,53.69
+3VALW on BOTTOM (solid shape): 154.52,32.92 154.52,28.92 154.27,28.67 153.38,28.67 152.81,28.1 152.81,27.02 152.05,27.02 151.92,26.89 151.92,26.13 151.48,25.68 149.06,25.68 148.94,25.81 148.94,26.32 150.52,26.32 150.65,26.45 150.65,26.76 151.22,26.76 151.22,27.27 150.65,27.27 150.65,27.84 150.84,28.03 151.35,28.03 152.62,29.3 152.62,32.92 152.81,33.11 154.33,33.11
+3VALW on IN1 (solid shape): 46.07,143.35 45.94,143.35 45.56,142.97 45.11,142.97 44.67,143.41 44.67,143.79 46.07,143.79
+3VALW on IN1 (solid shape): 100.93,4.92 100.99,4.86 100.99,4.16 100.87,4.03 99.98,4.03 99.85,4.16 99.85,4.98 99.91,5.05 100.93,5.05
+3VALW on IN1 (solid shape): 100.04,16.29 100.04,14.19 99.85,14 99.02,14 98.83,14.19 98.83,15.39 98.83,15.4 98.83,16.26 98.99,16.43 99.9,16.43
+3VALW on IN1 (solid shape): outline of 230 points within 95.87,38.83 114.65,52.99
+3VALW on VCC: 65.35,8.09 56.23,17.22 56.23,20.25 56.71,20.73 63.23,20.73 64.86,19.1 64.86,14.15 67.49,11.52 77.9,11.52 79.09,10.34 79.09,8.09
+3VALW_3VS on TOP (solid shape): 180.07,10.04 180.07,8.12 179.86,7.9 178.69,7.9 178.69,8.45 178.14,8.45 178.14,7.89 177.9,7.89 177.9,8.45 177.34,8.45 177.34,7.89 176.94,7.89 176.81,8.02 176.81,9.11 177.51,9.81 177.51,10.7 177.57,10.76 179.35,10.76
+3VALW_EC on TOP (solid shape): 177.45,67.34 178.16,67.34 178.31,67.19 178.31,66.81 178.21,66.71 177.51,66.71 177.07,66.26 177.07,64.67 176.88,64.48 176.68,64.48 176.62,64.55 176.62,66.77 176.75,66.9 176.75,67.47 177.32,67.47
+3VALW_EC on TOP (solid shape): 175.63,50.54 175.63,48.78 176.05,48.36 176.49,48.36 176.68,48.17 176.68,46 176.62,45.94 175.29,45.94 175.1,46.13 175.1,46.77 175.67,46.77 175.86,46.96 175.86,47.78 175.35,48.29 175.35,50.55 175.4,50.59 175.58,50.59
+3VALWP on TOP (solid shape): 160.47,13.71 160.47,13.19 161.24,12.43 161.76,12.43 161.81,12.38 161.81,11.14 161.49,10.82 161.06,10.82 160.1,11.78 155.03,11.78 154.59,12.22 154.59,13.37 154.78,13.56 155.53,13.56 155.81,13.83 160.35,13.83
+3VALWP on BOTTOM (solid shape): 160.49,16.48 160.49,13.49 161.1,12.89 161.1,12.77 161.3,12.56 161.68,12.56 161.76,12.48 161.76,10.94 161.63,10.8 160.57,10.8 160.36,11.01 160.36,11.79 160.08,12.06 159.15,12.06 159.15,11.52 158.71,11.52 158.71,12.07 157.95,12.07 157.95,11.52 157.52,11.52 157.52,12.06 154.69,12.06 154.59,12.17 154.59,13.43 154.74,13.58 155.56,13.58 155.67,13.68 155.67,16.22 156.05,16.6 160.37,16.6
+3VDD_CODEC on BOTTOM (solid shape): 7.79,23.12 7.79,22.96 7.66,22.83 7.27,22.83 6.95,22.51 6.95,21.82 5.87,20.73 5.36,20.73 5.23,20.6 5.23,19.7 4.93,19.4 3.33,19.4 3.33,20.29 4.3,20.29 4.5,20.49 4.5,21.58 4.52,21.61 5.68,21.61 5.77,21.69 5.78,21.69 6.25,22.16 6.25,22.64 6.77,23.15 7.76,23.15
+3VGS on TOP (solid shape): 99.34,108.6 100.01,108.03 100.78,107.63 100.79,107.62 102.08,106.34 102.67,106.34 102.82,106.19 102.82,104.25 102.99,104.08 102.99,102.85 102.8,102.66 101.22,102.66 100.98,102.9 100.98,105.91 100.55,106.34 100.55,106.39 100.5,106.39 100.26,106.63 99.85,106.63 98.59,107.89 98.59,108.41 98.8,108.62 99.32,108.62
+3VGS on BOTTOM (solid shape): 85.5,150.65 85.44,150.59 85.37,150.59 85.24,150.46 85.24,149.89 85.44,149.7 85.44,149.19 85.37,149.13 84.23,149.13 84.17,149.19 84.17,149.7 84.48,150.02 84.48,150.46 84.23,150.72 84.23,150.97 85.5,150.97
+3VGS on IN1 (solid shape): 99.8,109.21 99.8,108.01 99.62,107.83 98.73,107.83 98.67,107.89 98.67,109.61 98.97,109.91 99.1,109.91
+3VGS on IN1 (solid shape): 106.42,130.57 106.42,128.62 106.33,128.53 105.34,128.53 105.25,128.62 105.25,129.42 105.53,129.7 105.53,130.55 105.65,130.67 106.32,130.67
+3VL on TOP (solid shape): 163.36,21.49 163.36,20.41 163.2,20.25 162.56,20.25 162.5,20.31 162.5,21.53 162.59,21.62 163.22,21.62
+3VL on TOP (solid shape): 170.46,42.19 170.46,40.92 170.27,40.73 169.34,40.73 169.19,40.88 169.19,42.19 169.26,42.26 170.4,42.26
+3VLP on TOP (solid shape): 161.57,22.74 161.57,22.45 162.27,21.75 162.27,21.24 162.21,21.18 161.76,21.18 161.7,21.11 161.7,20.6 162.21,20.6 162.27,20.54 162.27,20.03 162.14,19.91 161.32,19.91 161.19,20.03 161.19,20.67 161,20.86 159.98,20.86 159.86,20.99 159.86,22.64 160.07,22.85 161.46,22.85
+3VLP on BOTTOM (solid shape): 160.15,22.73 161.29,22.73 161.51,22.51 161.51,21.49 161.29,21.27 160.14,21.27 159.32,22.09 159.32,22.81 159.41,22.9 159.97,22.9
+3VS on TOP (solid shape): 34.57,147.92 34.57,146.97 34.38,146.78 32.29,146.78 32.03,147.03 32.03,147.94 32.2,148.11 34.38,148.11
+3VS on TOP (solid shape): 163.69,41.74 163.69,40.24 163.54,40.08 162.16,40.08 161.94,40.3 161.94,41.65 162.12,41.82 163.61,41.82
+3VS on TOP (solid shape): 58.57,88.68 58.57,88.42 59.72,87.28 59.72,85.56 59.53,85.37 58.07,85.37 56.8,86.64 56.8,88.55 56.99,88.74 58.51,88.74
+3VS on TOP (solid shape): 27.61,13.53 27.61,12.97 27.46,12.82 27.46,11.98 27.41,11.93 27.23,11.93 27.18,11.98 27.18,12.84 27,13.02 27,13.53 27.08,13.61 27.54,13.61
+3VS on TOP (solid shape): 41.75,119.41 39.4,119.41 39.14,119.66 39.14,120.29 38.94,120.49 38.69,120.49 38.69,120.97 38.71,121 38.89,121 39.14,121.25 39.14,121.7 39.4,121.95 41.75,121.95
+3VS on TOP (solid shape): 177.74,7.74 178.3,7.74 178.3,8.3 178.54,8.3 178.54,7.71 179.86,7.71 180,7.85 180.93,7.85 180.98,7.8 180.98,6.36 180.88,6.25 177,6.25 176.81,6.44 176.81,7.52 177,7.71 177.49,7.71 177.49,8.3 177.74,8.3
+3VS on TOP (solid shape): 36.6,23.72 36.6,22.45 36.92,22.13 38,22.13 38.19,21.94 38.19,18.89 33.56,14.25 33.56,10.89 33.11,10.89 32.29,11.71 31.33,11.71 30.95,11.33 29.62,11.33 29.23,10.94 28.27,10.94 28.17,11.04 28.17,11.6 29.49,12.92 31.46,12.92 31.78,13.24 31.78,15.02 35.71,18.95 35.71,23.72 35.52,23.91 35.52,24.22 36.1,24.22
+3VS on TOP (solid shape): outline of 509 points within 79.02,23.4 94.45,38.57
+3VS on BOTTOM (solid shape): 41.75,121.57 41.75,120.74 40.35,119.35 39.27,119.35 39.02,119.6 39.02,120.93 40.22,122.14 41.18,122.14
+3VS on BOTTOM (solid shape): 56.03,21.24 55.78,20.99 53.69,20.99 53.49,21.18 53.49,23.72 56.03,23.72
+3VS on BOTTOM (solid shape): 59.84,86.45 59.84,84.1 57.3,84.1 57.3,86.52 57.5,86.71 59.59,86.71
+3VS on BOTTOM (solid shape): 41.74,142.37 41.74,142.15 40.85,141.25 39.79,141.25 38.32,142.72 36.73,142.72 36.54,142.91 36.54,144.37 34.95,145.95 28.73,145.95 28.54,146.14 28.54,146.87 30.47,146.87 30.47,146.82 30.48,146.76 30.49,146.71 30.52,146.66 30.55,146.62 30.58,146.58 30.62,146.55 30.67,146.52 30.72,146.5 30.77,146.49 30.83,146.49 30.88,146.49 30.93,146.5 30.98,146.52 31.03,146.55 31.07,146.58 31.1,146.62 31.13,146.66 31.16,146.71 31.17,146.76 31.18,146.82 31.18,146.87 31.17,146.92 31.16,146.97 31.13,147.02 31.1,147.07 31.07,147.1 31.03,147.14 30.98,147.16 30.93,147.18 30.88,147.2 30.83,147.2 30.77,147.2 30.72,147.18 30.67,147.16 30.62,147.14 30.58,147.1 30.55,147.07 30.52,147.02 30.49,146.97 30.48,146.92 30.47,146.87 28.54,146.87 28.54,147.41 28.98,147.86 36.25,147.86
+3VS on VCC: 168.75,5.22 168.75,10.42 167.9,11.27 152.47,11.27 152.03,11.71 135.24,11.71 131.62,8.09 79.59,8.09 79.59,10.55 78.11,12.03 67.7,12.03 65.37,14.36 65.37,19.31 63.44,21.24 56.5,21.24 55.87,20.6 35.91,20.6 35.91,23.8 36.2,24.1 43.25,24.1 44.01,24.86 48.96,24.86 51.5,27.4 57.66,27.4 59.51,29.24 77.33,29.24 86.47,20.1 170,20.1 171.22,21.32 171.22,31.31 164.6,37.94 160.41,37.94 160.11,38.24 160.11,38.91 162.14,40.95 162.14,41.9 162.44,42.19 164.51,42.19 174.78,31.93 174.78,17.77 180.18,12.37 180.18,5.22
+3VS_APU on TOP (solid shape): outline of 163 points within 92.23,38.77 96.08,50.01
+3VS_CMOS on TOP (solid shape): 24.94,144.16 26.49,144.16 26.83,143.82 26.83,143.42 26.42,143 24.47,143 24.22,142.75 24.22,142.74 24.13,142.64 24.13,140.97 24.09,140.92 23.5,140.92 23.34,141.08 23.34,142.38 23.53,142.57 23.53,143.33 23.82,143.62 23.82,144.37 23.93,144.49 24.61,144.49
+3VS_WLAN on TOP (solid shape): 164.4,46.43 164.4,45.71 164.42,45.69 164.42,45.68 165.85,44.25 165.85,40.19 165.8,40.14 164.6,40.14 164.49,40.25 164.49,41.65 164.49,41.65 164.49,41.8 164.41,41.89 163.76,41.89 163.22,42.42 163.22,43.11 162.85,43.49 162.85,45.09 163.17,45.41 163.17,45.41 163.64,45.88 163.64,46.45 163.8,46.61 164.22,46.61
+3VS_WLAN on BOTTOM (solid shape): 164.02,45.71 164.02,44.29 165.18,43.13 165.18,42.75 164.99,42.56 163.72,42.56 163.55,42.72 163.55,42.98 162.99,43.54 162.99,45.63 163.14,45.78 163.95,45.78
+3VS_WLAN on BOTTOM (solid shape): 181.57,45.68 181.57,43.4 181.37,43.03 181.32,42.61 181.32,42.58 180.99,42.25 180.14,42.25 179.92,42.47 179.92,43.18 180.7,43.95 180.7,45.69 180.81,45.81 181.45,45.81
+5V_DISPLAY on BOTTOM (solid shape): 20.03,110.33 20.03,109.82 19.84,109.63 18.82,109.63 17.43,108.23 17.05,108.23 16.98,108.3 12.35,108.3 12.22,108.17 11.71,108.17 11.52,108.36 11.52,109 11.71,109.19 14.82,109.19 15.39,108.62 16.98,108.62 17.58,109.21 17.73,109.29 17.81,109.45 18.32,109.95 18.32,110.33 19.2,110.33 19.4,110.52 19.84,110.52
+5V_HDD on BOTTOM (solid shape): 179.14,22.5 179.14,20.08 179.26,19.96 180.38,19.96 180.48,19.87 180.48,17.78 180.32,17.62 177.85,17.62 177.57,17.91 177.57,19.69 177.49,19.77 177.49,22.66 177.54,22.71 178.93,22.71
+5V_ODD on TOP (solid shape): 184.5,63.3 184.5,61.66 186.03,60.13 186.03,53.93 185.73,53.62 184.28,53.62 183.87,54.03 183.87,59.01 183.5,59.38 182.46,59.38 182.17,59.67 182.17,60.28 182.15,60.28 182.15,62.45 181.89,62.7 181.89,63.53 181.95,63.59 184.2,63.59
+5V_ODD on BOTTOM (solid shape): 185.77,58.66 185.77,57.73 185.58,57.54 183.58,57.54 183.49,57.62 183.49,58.78 183.59,58.88 185.55,58.88
+5VALW on TOP (solid shape): 54.96,11.02 54.96,10.32 55.27,10 56.03,10 56.04,10 57.02,10 57.44,9.57 57.44,5.72 57.36,5.64 56.46,5.64 56.33,5.77 56.33,7.99 55.27,9.05 54.45,9.05 54.19,9.3 54.19,10.95 54.38,11.14 54.83,11.14
+5VALW on TOP (solid shape): 175.3,14.09 175.3,14.08 176.24,13.14 176.24,12.22 176.18,12.16 176.01,12.16 175.96,12.21 174.84,12.21 174.34,11.7 174.34,11.33 172.48,9.48 172.44,9.51 172.17,9.62 171.91,9.49 171.85,9.45 171.78,9.47 171.38,9.47 171.23,9.11 171.21,9.02 171.13,8.98 163.92,8.98 163.54,9.36 163.54,11.97 163.98,12.41 169.76,12.41 171.36,14.01 173.18,14.01 173.46,14.29 175.1,14.29
+5VALW on BOTTOM (solid shape): 20.53,64.75 20.53,63.14 20.22,62.83 18.25,62.83 18.06,63.02 18.06,64.76 18.54,65.24 20.03,65.24
+5VALW on BOTTOM (solid shape): 165.23,11.87 165.98,11.87 165.98,12.41 166.43,12.41 166.43,11.87 167.18,11.87 167.18,12.41 168.81,12.41 169,12.22 169,9.43 168.68,9.11 163.67,9.11 163.41,9.36 163.41,12.22 163.6,12.41 165.23,12.41
+5VALW on IN1 (solid shape): 24.79,63.72 24.67,63.59 24.16,63.59 24.03,63.72 24.03,65.5 24.79,65.5
+5VALW on IN1 (solid shape): 153.51,11.78 153.51,9.75 154.4,8.86 162.52,8.86 164.05,10.38 164.05,10.63 164.18,10.76 167.6,10.76 168.11,10.25 168.11,9.3 166.72,7.9 153.44,7.9 152.49,8.86 152.49,11.78 152.62,11.9 153.38,11.9
+5VALW on VCC: 49.37,1.17 49.37,13.28 48.9,13.75 28.26,13.75 27.57,14.44 22.04,14.44 21.49,14.99 21.49,39.19 20.73,39.95 20.73,40.88 21.68,41.84 21.68,49.03 20.16,50.55 20.16,51.91 19.65,52.42 18.76,52.42 18.76,62.05 17.93,62.87 17.93,64.89 18.29,65.24 26.89,65.24 26.89,21.26 28.05,20.1 55.72,20.1 55.72,17.01 65.14,7.59 131.83,7.59 135.45,11.21 151.81,11.21 152.26,10.76 167.69,10.76 168.24,10.21 168.24,5.22 141.87,5.22 140.34,4.58 139.7,3.05 139.7,1.17
+5VALW_5VS on TOP (solid shape): 180.49,13.81 179.92,13.81 179.92,13.24 180.5,13.24 180.5,13 179.92,13 179.92,12.41 180.49,12.41 180.49,12.03 180.3,11.84 179.29,11.84 178.97,12.16 177.57,12.16 177.51,12.22 177.51,13.62 178.02,14.13 180.49,14.13
+5VALWP on TOP (solid shape): 169.51,12.92 169.32,12.73 162.78,12.73 162.78,14.83 169.51,14.83
+5VALWP on BOTTOM (solid shape): 171.42,24.28 171.42,24.06 171.24,23.88 170.99,23.88 170.78,24.1 169.38,24.1 169.32,24.16 169.32,24.3 169.37,24.35 170.87,24.35 170.93,24.41 171.28,24.41
+5VALWP on BOTTOM (solid shape): 169.26,16.67 169.26,13.75 169.38,13.62 169.38,12.98 169,12.6 167.03,12.6 167.03,12.03 166.59,12.03 166.59,12.58 165.82,12.58 165.82,12.03 165.38,12.03 165.38,12.6 162.91,12.6 162.78,12.73 162.78,14.95 162.52,15.21 162.02,15.21 161.95,15.27 161.95,16.1 162.14,16.29 162.97,16.29 163.73,17.05 168.87,17.05
+5VDDA_CODEC on BOTTOM (solid shape): 17.93,29.94 17.93,29.88 17.3,29.24 17.24,29.24 16.41,30.07 13.49,30.07 13.36,29.94 13.36,28.24 12.82,27.7 12.53,27.7 11.78,26.95 11.65,26.95 11.6,27.01 11.6,27.78 11.66,27.84 11.71,27.84 12.54,28.67 12.54,30.64 12.85,30.95 16.92,30.95
+5VLP on TOP (solid shape): 170.78,23.59 170.78,22.45 170.78,22.42 170.31,21.95 170.31,21.36 170.23,21.28 169.81,21.28 169.81,21.83 169.32,21.83 169.32,21.28 169.08,21.28 169.06,21.3 169.06,23.76 169.13,23.82 170.54,23.82
+5VLP on BOTTOM (solid shape): 170.96,23.51 170.96,22.31 170.84,22.19 170.4,22.19 169.7,22.89 169.7,23.28 169.31,23.68 169.31,23.83 169.36,23.88 170.59,23.88
+5VS on TOP (solid shape): 22.82,30.07 22.82,29.43 21.81,28.41 21.36,28.41 21.24,28.54 21.24,29.43 21.36,29.56 21.49,29.56 22.19,30.26 22.63,30.26
+5VS on TOP (solid shape): 25.3,113.89 25.3,113.12 25.24,113.06 24.73,113.06 24.54,113.25 23.27,113.25 23.08,113.44 23.08,114.01 23.21,114.14 25.05,114.14
+5VS on TOP (solid shape): 29.05,99.15 29.49,99.15 29.49,97.69 29.43,97.63 27.14,97.63 27.08,97.69 27.08,98.07 27.52,98.52 27.52,99.79 28.41,99.79
+5VS on TOP (solid shape): 183.86,67.21 183.86,64.67 183.61,64.42 181.83,64.42 181.64,64.61 181.64,67.28 181.89,67.53 183.54,67.53
+5VS on TOP (solid shape): outline of 231 points within 173.1,12.1 183.92,31.99
+5VS on BOTTOM (solid shape): 175.48,25.68 175.35,25.56 174.46,25.56 174.21,25.81 174.21,28.48 175.48,28.48
+5VS on BOTTOM (solid shape): 15.61,17.33 15.61,17.06 15.39,16.85 15.39,14.43 15.09,14.13 14.89,14.13 14.48,14.53 14.48,17.56 14.62,17.7 15.24,17.7
+5VS on BOTTOM (solid shape): 183.73,67.09 183.73,65.5 183.35,65.12 183.35,64.55 183.29,64.48 182.08,64.48 182.08,65.05 181.7,65.44 180.94,65.44 180.56,65.82 180.56,67.34 183.48,67.34
+5VS on BOTTOM (solid shape): 24.28,113.89 24.28,113.38 24.09,113.19 21.94,113.19 21.74,113 21.74,112.3 21.49,112.04 20.41,112.04 20.22,112.23 20.22,112.87 21.36,114.01 24.16,114.01
+5VS on BOTTOM (solid shape): 176.63,22.69 176.63,21.25 176.5,21.11 176.11,21.11 175.92,20.92 175.92,20.62 175.79,20.48 175.24,20.48 175.11,20.6 175.11,22.56 175.32,22.76 176.56,22.76
+5VS on BOTTOM (solid shape): 21.74,29.49 21.74,28.48 21.62,28.35 21.24,28.35 21.05,28.54 19.78,28.54 19.52,28.29 19.52,27.46 18.51,27.46 18.51,27.91 17.81,28.61 17.81,28.73 18.7,29.62 21.62,29.62
+5VS on IN1 (solid shape): outline of 1631 points within 174.21,17.3 185.89,67.4
+5VS on IN2 (solid shape): 183.73,67.09 183.73,65.63 183.54,65.44 181.76,65.44 181.32,65.88 180.75,65.88 180.69,65.94 180.69,66.9 181.13,67.34 183.48,67.34
+5VS on TOP: 103.39,97.05 105.62,97.05 106.31,96.35 106.31,95.7 105.76,95.14 104.37,95.14 104.09,95.42 103.08,95.42 102.94,95.56 102.94,96.59
+5VS on BOTTOM: 103.84,96.66 103.74,96.77 103.74,97.96 104.03,98.25 105.83,98.25 106.2,97.88 106.2,96.89 107.69,95.41 107.69,95.33 106.94,94.58 106.33,94.58 104.24,96.66
+5VS on IN2: 105.43,96.68 106.45,96.68 107.74,95.39 107.74,95.01 107.29,94.57 106.43,94.57 104.97,96.03 104.97,96.22
+5VS_FAN on BOTTOM (solid shape): 102.99,97.85 102.99,96.78 102.99,96.78 101.13,96.78 100.9,97.01 100.9,97.73 101.04,97.87 102.97,97.87
+5VS_FAN on BOTTOM (solid shape): 100.74,93.31 101.06,92.99 101.06,92.55 100.87,92.36 99.66,92.36 99.47,92.55 99.47,92.99 99.72,93.25 99.72,93.95 100.74,93.95
+5VS_PVDD on BOTTOM (solid shape): 7.81,21.53 7.78,21.5 7.78,20.99 7.97,20.79 7.97,20.44 8.31,20.1 10.53,20.1 10.72,20.29 10.72,21.52 10.81,21.52 11.17,21.16 11.17,20.59 11.27,20.49 11.27,19.39 11.18,19.3 10.63,19.3 10.54,19.4 9.22,19.4 9.07,19.25 9.07,18.89 8.46,18.28 8.46,15.16 8.56,15.05 10.9,15.05 11.43,15.59 12.66,15.59 12.8,15.73 12.8,16.48 13.62,16.48 13.62,14.17 13.11,13.66 7.6,13.66 6.91,14.34 6.91,18.2 7.7,18.99 7.7,20.29 7.27,20.72 7.27,21.51 7.48,21.72 7.81,21.72
+8.4V_VMB on BOTTOM (solid shape): 113,28.64 113,25.66 112.81,25.47 111.91,25.47 111.73,25.65 110.11,25.65 109.92,25.84 109.92,28.55 110.07,28.7 112.94,28.7
+12.6V_BATT+ on BOTTOM (solid shape): 121.44,27.21 121.44,15.65 119.92,15.65 119.92,15.02 121.44,15.02 121.44,14.13 119.15,14.13 118.39,14.89 118.39,24.86 117.76,25.49 113.69,25.49 113.69,28.67 119.98,28.67
+12.6V_BATT+ on IN2 (solid shape): 120.99,27.62 120.99,18.79 120.79,18.59 118.78,18.59 118.44,18.94 118.44,24.71 117.4,25.76 115.85,25.76 115.41,26.2 115.41,28.03 115.72,28.35 120.26,28.35
+12.6VB_DDR on TOP (solid shape): 41.94,103.98 41.94,103.03 41.3,103.03 41.05,102.77 41.05,101.69 40.73,101.38 36.54,101.38 36.54,103.54 36.67,103.66 39.14,103.66 39.59,104.11 41.81,104.11
+12.6VB_DDR on BOTTOM (solid shape): 41.94,103.09 41.87,103.03 41.24,103.03 41.05,102.84 41.05,100.42 40.86,100.23 39.59,100.23 39.46,100.36 39.46,103.6 39.72,103.85 41.94,103.85
+17.4V_BATT_CHG on BOTTOM (solid shape): 129.38,20.1 130.65,20.1 130.77,19.97 130.77,17.49 130.52,17.24 129.76,17.24 126.39,13.87 122.96,13.87 122.71,14.13 122.71,15.02 124.23,15.02 124.23,15.65 122.71,15.65 122.71,16.35 124.17,17.81 124.17,21.37 124.3,21.49 127.98,21.49
+19V_APDIN on TOP (solid shape): 20.84,148.55 20.84,147.13 21.01,146.97 21.01,144.86 20.89,144.74 18.15,144.74 18.02,144.87 18.02,147.1 17.52,147.59 16.55,147.59 16.33,147.81 16.33,148.49 16.47,148.62 20.76,148.62
+19V_P1 on TOP (solid shape): 28.34,156.23 28.34,155.47 28.6,155.22 28.6,153.21 28.41,153.02 27.5,153.02 26.78,152.31 25.36,152.31 25.23,152.43 25.23,155.53 25.49,155.79 26.8,155.79 27.28,156.27 28.3,156.27
+19V_P2 on TOP (solid shape): 34.05,154.95 34.05,154.31 32.51,154.31 32.51,153.67 34.05,153.67 34.05,152.87 33.74,152.56 32.72,152.56 32.5,152.34 31.61,152.34 31.38,152.11 29.28,152.11 29.15,152.24 29.15,154.69 29.26,154.81 31.26,154.81 31.59,155.15 33.86,155.15
+19V_VIN on TOP (solid shape): 24.54,156.97 24.54,151.65 24.28,151.38 23.87,151.38 23.86,151.4 23.39,151.4 23.37,151.38 23.29,151.38 23.27,151.4 22.81,151.4 22.79,151.38 21.16,151.38 20.82,151.05 20.82,148.86 20.73,148.77 16.45,148.77 16.31,148.91 16.31,150.36 16.86,150.9 16.86,152.9 19.56,155.61 19.56,156.8 19.78,157.01 24.5,157.01
+19V_VIN on IN1 (solid shape): 24.54,156.97 24.54,151.65 24.28,151.38 23.87,151.38 23.86,151.4 23.39,151.4 23.37,151.38 23.29,151.38 23.27,151.4 22.81,151.4 22.79,151.38 21.16,151.38 20.82,151.05 20.82,148.86 20.73,148.77 16.45,148.77 16.2,149.02 16.2,152.66 19.85,156.3 19.85,156.87 19.99,157.01 24.5,157.01
+19VB_1V on TOP (solid shape): 74.09,18.49 74.09,17.02 73.77,17.02 73.77,17.57 72.21,17.57 72.21,17.02 71.62,17.02 71.08,16.48 67.16,16.48 67.1,16.54 67.1,18.01 67.16,18.08 67.99,18.08 68.54,18.64 68.54,19.46 68.67,19.59 72.99,19.59
+19VB_3V on BOTTOM (solid shape): 157.38,25.06 157.81,25.06 157.91,24.97 157.91,23.48 157.82,23.4 155.67,23.4 155.54,23.27 155.54,22.89 154.4,22.89 154.21,23.08 154.21,24.41 153.63,24.99 153.25,24.99 153.19,25.05 153.19,25.87 153.25,25.94 156.5,25.94
+19VB_5V on TOP (solid shape): 166.25,27.31 165.57,26.64 165.57,26 165.32,25.75 164.18,25.75 163.92,26 163.92,27.46 165.29,27.46 165.76,27.93 166.25,27.93
+19VB_5V on BOTTOM (solid shape): 166.33,27.91 166.33,27.21 166.27,27.14 166.08,27.14 165.85,26.92 165.85,26.37 165.91,26.31 165.92,26.31 166.42,25.8 166.42,25.8 166.99,25.8 167.09,25.7 167.09,24.15 167.01,24.07 162.61,24.07 162.14,24.54 162.14,27.34 165.45,27.34 165.76,27.65 165.76,27.91 165.83,27.97 166.27,27.97
+19VB_APU on TOP (solid shape): 154.02,51.85 153.51,51.34 151.28,51.34 150.9,50.96 148.81,50.96 148.81,54.13 149.95,55.28 154.02,55.28
+19VB_APU on TOP (solid shape): 141.89,37.62 141.89,37.3 141.32,36.73 141.32,27.4 141.63,27.08 141.63,24.35 139.09,24.35 137.51,25.94 137.51,38.45 137.57,38.51 141,38.51
+19VB_APU on BOTTOM (solid shape): 141.76,24.03 141.25,23.53 136.81,23.53 136.74,23.59 136.74,27.08 135.79,28.03 132.49,28.03 131.98,28.54 131.98,31.21 132.49,31.72 135.73,31.72 137.19,33.18 141.76,33.18
+19VB_APU on BOTTOM (solid shape): 152.34,55.28 154.02,55.28 154.02,51.66 153.7,51.34 152.55,51.34 152.05,50.83 147.16,50.83 147.16,55.59 147.28,55.72 151.9,55.72
+19VB_CHG on BOTTOM (solid shape): 142.84,22.32 142.84,19.72 139.68,19.72 139.54,19.86 137.87,19.86 137.6,19.59 131.54,19.59 130.58,20.54 130.01,20.54 129.82,20.73 129.82,22.13 130.33,22.64 142.52,22.64
+VDD_CT on TOP (solid shape): 94.68,130.8 94.68,130.17 94.49,129.98 94.08,129.98 93.9,130.17 92.81,130.17 92.79,130.19 92.79,131.14 92.9,131.25 94.23,131.25
+VDD_CT on BOTTOM (solid shape): 93.84,131.62 93.84,131.35 93.61,131.11 93.61,130.86 93.96,130.51 94.47,130.51 94.6,130.38 94.6,130.14 94.49,130.03 93.75,130.03 93.55,130.23 93.49,130.23 93.48,130.23 92.44,130.23 92.29,130.38 92.29,130.62 92.44,130.77 92.44,131.22 92.31,131.34 92.31,131.61 92.48,131.78 93.68,131.78
+VDD_CT on IN1 (solid shape): outline of 117 points within 92.8,130.01 100.48,132.3
+VDDCR_FCH_ALW on TOP (solid shape): 153.32,33.81 155.29,33.81 155.54,33.56 155.54,32.54 155.29,32.29 150.78,32.29 149.19,33.88 147.47,33.88 147.16,34.19 147.16,35.08 147.22,35.15 151.98,35.15
+VDDCR_FCH_ALW on TOP (solid shape): 123.98,32.48 125.12,32.48 125.25,32.35 125.25,31.34 125.06,31.15 123.15,31.15 122.77,31.53 122.77,32.73 123.73,32.73
+VDDCR_FCH_ALW on TOP (solid shape): 104.54,46.9 104.54,46.86 104.55,46.81 104.57,46.76 104.6,46.72 104.64,46.68 104.68,46.64 104.72,46.61 104.77,46.59 104.82,46.58 104.87,46.58 106.01,46.58 106.39,46.19 106.39,43.34 107.22,42.51 107.22,41.18 106.96,40.92 106.96,40.35 105.95,40.35 105.95,40.99 104.85,42.08 105.87,42.08 105.87,42.03 105.88,41.98 105.89,41.93 105.92,41.88 105.95,41.84 105.98,41.8 106.03,41.77 106.07,41.75 106.12,41.73 106.17,41.72 106.23,41.72 106.28,41.73 106.33,41.75 106.37,41.77 106.42,41.8 106.45,41.84 106.48,41.88 106.51,41.93 106.52,41.98 106.53,42.03 106.53,42.08 106.52,42.13 106.51,42.18 106.48,42.23 106.45,42.27 106.42,42.31 106.37,42.34 106.33,42.36 106.28,42.38 106.23,42.38 106.17,42.38 106.12,42.38 106.07,42.36 106.03,42.34 105.98,42.31 105.95,42.27 105.92,42.23 105.89,42.18 105.88,42.13 105.87,42.08 104.85,42.08 104.55,42.38 104.55,45.37 104.27,45.65 104.27,45.73 103.8,46.2 103.78,46.22 103.75,46.26 103.7,46.3 103.59,46.33 103.41,46.51 103.41,46.96 103.6,47.15 104.29,47.15
+VDDCR_FCH_ALW on IN1 (solid shape): 126.14,32.22 126.14,31.59 125.95,31.4 124.23,31.4 124.04,31.59 124.04,32.29 124.17,32.42 125.95,32.42
+VDDCR_FCH_ALW on IN1 (solid shape): 150.01,34.26 150.01,32.48 149.44,31.91 148.87,31.91 148.87,34.19 149.06,34.38 149.89,34.38
+VDDR3 on TOP (solid shape): 93.75,133.99 93.74,133.97 93.85,133.68 94.16,133.58 94.29,133.58 94.29,133.51 94.49,133.31 94.49,133.25 94.91,132.83 94.91,132.66 94.82,132.57 94.8,132.57 94.58,132.34 93.33,132.34 93.26,132.26 92.58,132.26 92.52,132.33 92.52,132.96 92.8,133.25 92.8,133.98 93.01,134.18 93.56,134.18
+VDDR3 on BOTTOM (solid shape): 93.55,133.77 93.68,133.77 93.85,133.6 93.85,133.32 94.22,132.96 94.53,132.96 94.59,133.02 94.79,133.02 94.92,132.89 94.92,132.67 94.66,132.41 93.9,132.41 93.7,132.21 93.48,132.21 93.32,132.38 92.88,132.38 92.71,132.21 92.47,132.21 92.3,132.38 92.3,132.58 92.39,132.67 92.39,133.32 92.37,133.34 92.35,133.58 92.57,133.75 92.97,134.15 93.17,134.15
GND on TOP (solid shape): 19.8,111.64 14.08,111.64 12.05,113.67 12.05,116.64 14.05,118.64 19.8,118.64
GND on TOP (solid shape): 71.91,27.53 71.53,27.14 70.7,27.14 70.51,27.34 70.51,28.16 70.64,28.29 71.91,28.29
GND on TOP (solid shape): 154.02,55.59 153.86,55.44 152.33,55.44 151.98,55.78 151.98,56.48 152.49,56.99 154.02,56.99
GND on TOP (solid shape): 20.09,22.95 20.09,22.19 19.9,22 17.87,22 17.74,22.13 17.74,23.02 17.87,23.14 19.9,23.14
GND on TOP (solid shape): 20.73,15.52 20.73,14.64 20.6,14.51 18.57,14.51 18.38,14.7 18.38,15.46 18.57,15.65 20.6,15.65
GND on TOP (solid shape): 47.65,157.95 47.65,156.94 47.53,156.81 45.37,156.81 45.24,156.94 45.24,157.95 45.37,158.08 47.53,158.08
GND on TOP (solid shape): 70.2,112.43 70.2,111.41 70,111.22 68.1,111.22 68.1,112.62 70,112.62
GND on TOP (solid shape): 92.97,152.36 84.97,152.36 84.97,159.66 92.97,159.66
GND on TOP (solid shape): 96.29,74.9 96.29,73.88 96.23,73.82 94.52,73.82 94.45,73.89 94.45,74.87 94.73,75.15 96.04,75.15
GND on TOP (solid shape): 104.17,45.69 104.17,43.02 104.04,42.89 103.02,42.89 102.83,43.08 102.83,46 103.02,46.19 103.66,46.19
GND on TOP (solid shape): 106.58,125.19 106.58,124.3 105.5,123.22 104.36,123.22 104.23,123.35 104.23,125.06 104.55,125.38 106.39,125.38
GND on TOP (solid shape): 127.92,46.26 127.92,46.13 127.22,45.43 126.9,45.43 123.03,49.31 123.03,49.75 123.66,50.39 123.79,50.39
GND on TOP (solid shape): 143.47,26.8 143.47,24.4 143.36,24.28 142,24.28 141.9,24.39 141.9,26.9 142,27 143.27,27
GND on TOP (solid shape): 182.02,62.13 182.02,59.78 181.19,59.78 180.56,60.42 180.56,62.2 180.69,62.32 181.83,62.32
GND on TOP (solid shape): 23.33,144.18 23.33,142.78 21.89,142.78 21.78,142.89 21.78,143.7 22.45,144.37 23.14,144.37
GND on TOP (solid shape): 33.81,150.84 33.64,150.68 32.51,150.68 32.36,150.83 32.36,152 32.6,152.24 33.81,152.24
GND on TOP (solid shape): 35.08,134.78 34.95,134.65 32.4,134.65 32.18,134.87 32.18,137.23 32.33,137.38 35.08,137.38
GND on TOP (solid shape): 125.63,35.65 125.63,34.57 125.5,34.45 123.54,34.45 123.34,34.64 123.34,35.78 125.5,35.78
GND on TOP (solid shape): 12.6,154.65 12.6,153.64 12.28,153.32 6.6,153.32 6.06,153.86 6.06,154.78 6.31,155.03 12.22,155.03
GND on TOP (solid shape): 22.79,10.41 22.79,9.87 22.66,9.75 22.66,8.93 22.61,8.88 21.87,8.88 21.81,8.94 21.81,10.57 21.92,10.69 22.51,10.69
GND on TOP (solid shape): 125.57,42.96 125.57,41.94 125.44,41.81 123.34,41.81 123.22,41.94 123.22,42.96 123.41,43.15 125.38,43.15
GND on TOP (solid shape): 162.65,14.77 162.65,12.72 162.59,12.66 161.28,12.66 160.62,13.31 160.62,14.6 160.91,14.89 162.53,14.89
GND on TOP (solid shape): 23.44,19.17 23.44,18.53 23.06,18.16 21.65,18.16 21.52,18.29 21.52,18.95 22.29,19.72 22.89,19.72
GND on TOP (solid shape): 161.32,49.88 161.64,49.88 161.76,49.75 161.76,49.5 161.64,49.37 160.2,49.37 159.97,49.6 159.97,50.11 161.09,50.11
GND on TOP (solid shape): 163.29,12.24 163.29,10 161.87,10 161.81,10.07 161.81,10.93 162.42,11.55 162.42,12.36 163.16,12.36
GND on TOP (solid shape): 31.02,14.38 31.02,13.43 30.95,13.37 30.32,13.37 30.13,13.17 29.75,13.17 29.75,14.19 30.06,14.51 30.89,14.51
GND on TOP (solid shape): 83.02,117.7 83.02,116.93 82.77,116.68 80.42,116.68 79.85,116.11 72.99,116.11 72.93,116.17 72.93,116.62 74.7,118.39 82.32,118.39
GND on TOP (solid shape): 42.06,110.08 42.06,104.87 41.94,104.74 39.59,104.74 39.27,105.06 39.27,106.39 39.14,106.52 39.14,108.04 39.27,108.17 40.16,108.17 40.35,108.36 40.35,110.39 41.75,110.39
GND on TOP (solid shape): 82.03,152.85 82.03,151.69 81.95,151.6 79.59,151.6 79.51,151.69 79.51,152.52 79.52,152.54 79.68,152.71 79.98,153.04 81.84,153.04
GND on TOP (solid shape): 84.36,148.11 84.36,146.59 82.96,146.59 82.77,146.4 82.77,145.89 82.64,145.76 82.39,145.76 82.07,146.08 82.07,146.97 82.01,147.03 82.01,147.92 82.2,147.92 82.83,148.56 83.91,148.56
GND on TOP (solid shape): 182.34,8.27 182.34,7.78 182.34,6.3 182.28,6.24 181.26,6.24 181.15,6.35 181.15,8.24 181.34,8.43 182.18,8.43
GND on TOP (solid shape): 71.34,24.48 71.34,23.97 71.38,23.93 71.43,23.55 71.53,23.18 71.53,22.57 71.34,22.38 70.83,22.38 70.64,22.57 70.64,24.41 70.77,24.54 71.27,24.54
GND on TOP (solid shape): 21.87,150.38 21.87,148.43 22.49,147.81 22.49,144.96 22.35,144.82 21.41,144.82 21.28,144.95 21.28,146.97 21.06,147.19 21.06,150.36 21.17,150.46 21.79,150.46
GND on TOP (solid shape): 98.41,139.59 98.41,138.49 98.23,138.31 96.77,138.31 96.24,137.79 95.43,137.79 95.4,137.81 95.4,138.17 95.43,138.19 96.01,138.19 96.7,138.88 96.7,139.54 96.9,139.74 98.26,139.74
GND on TOP (solid shape): 169.19,47.23 169.19,46.89 169.38,46.7 169.89,46.7 169.89,44.54 169.83,44.48 169.32,44.48 169.32,45.81 169.13,46 168.81,46 168.68,46.13 168.68,47.17 168.81,47.29 169.13,47.29
GND on TOP (solid shape): 90.66,127.53 90.66,127.09 90.88,126.87 91.62,126.87 91.75,126.74 91.75,126.28 91.22,125.75 88.79,125.75 88.61,125.57 88.61,124.81 88.85,124.57 88.85,122.93 88.67,122.75 87.61,122.75 87.18,123.19 87.18,127.53 87.2,127.55 90.63,127.55
GND on TOP (solid shape): 97.88,130.97 98.39,130.97 98.45,130.9 98.45,130.33 98.58,130.21 99.66,130.21 99.91,129.95 99.91,129.13 99.72,128.94 99.53,128.94 99.02,129.44 97.75,129.44 97.69,129.51 97.69,130.21 97.06,130.84 96.93,130.84 96.93,131.41 97.44,131.41
GND on TOP (solid shape): 51.51,17.24 51.51,16.64 51.15,16.28 51.15,14.41 51.46,14.09 54.28,14.09 54.28,11.68 50.74,11.68 50.13,12.29 50.13,16.6 50.35,16.83 50.67,16.83 50.83,16.98 50.83,17.22 50.91,17.31 51.44,17.31
GND on TOP (solid shape): 32.48,9.49 32.48,8.54 30.95,7.02 28.03,7.02 27.69,7.36 27.69,8.64 27.78,8.73 27.9,8.73 27.97,8.67 27.97,7.97 28.16,7.78 30.13,7.78 30.32,7.97 30.32,8.54 30.44,8.54 30.63,8.73 30.63,9.36 31.27,9.36 31.52,9.62 32.35,9.62
GND on TOP (solid shape): 72.48,11.14 71.53,11.14 70.89,10.51 70.89,6.51 69.5,5.11 65.12,5.11 65.12,5.62 65.88,5.62 66.19,5.94 66.19,6.51 66.39,6.7 68.1,6.7 68.54,7.14 68.54,10.51 68.29,10.76 66.07,10.76 65.56,10.25 64.67,10.25 64.67,10.89 65.56,11.78 72.48,11.78
GND on TOP (solid shape): 159.67,28.1 159.67,21.11 159.54,20.99 159.35,20.99 158.94,21.39 157.96,21.39 157.83,21.52 157.83,23.78 158.27,24.22 158.27,26.17 158.03,26.41 156.97,26.41 156.26,27.12 156.12,27.12 155.98,27.26 155.98,28.22 156.24,28.48 159.29,28.48
GND on TOP (solid shape): 82.91,140.45 82.91,139.06 83.11,138.85 83.47,138.85 83.57,138.75 83.57,138.52 83.47,138.42 83.37,138.42 83.24,138.3 83.24,137.97 83.21,137.94 82.76,137.94 82.63,138.07 82.63,138.78 82.25,139.16 81.82,139.16 81.66,139.31 81.66,139.72 81.77,139.82 82.2,139.82 82.32,139.95 82.32,140.56 82.81,140.56
GND on TOP (solid shape): 85.8,131.57 86.04,131.57 86.55,131.06 87.04,131.06 87.17,131.19 87.37,131.19 87.5,131.06 87.5,130.86 87.25,130.6 87.25,130.09 87.12,129.96 87.04,129.96 86.38,129.3 86.38,128.9 86.25,128.77 85.58,128.77 85.47,128.87 85.47,129.74 85.21,130 85.21,131.4 85.39,131.58 85.79,131.58
GND on TOP (solid shape): 94.83,30.95 94.83,29.81 93.18,28.16 90.32,28.16 90.2,28.29 90.2,29.24 90.13,29.3 90.13,30.76 91.02,30.76 91.02,29.56 91.21,29.37 92.1,29.37 92.55,28.92 93.37,28.92 93.63,29.18 93.63,30 93.5,30.13 92.66,30.13 92.48,30.32 92.48,30.95 92.74,31.21 93.72,31.21 93.82,31.3 94.49,31.3
GND on TOP (solid shape): 64.35,28.22 64.35,27.65 63.65,26.95 63.65,24.8 64.29,24.16 64.92,24.16 65.12,23.97 65.12,22.13 64.99,22 63.85,22 63.72,22.13 62.77,22.13 62.64,22.26 62.64,25.3 60.92,27.02 60.92,28.22 61.05,28.35 61.5,28.35 61.62,28.22 61.62,27.46 61.94,27.14 62.96,27.14 63.53,27.72 63.53,28.22 63.72,28.41 64.16,28.41
GND on TOP (solid shape): 97.33,54.49 97.38,54.43 97.44,54.38 97.44,53.88 97.56,53.76 97.75,53.76 97.81,53.7 97.82,53.69 97.85,53.6 97.91,53.52 97.91,53.52 97.91,53.37 97.77,53.23 97.53,53.23 97.28,53.48 95.22,53.48 95.02,53.28 94.6,53.28 94.49,53.39 94.49,53.95 95.03,54.49
GND on TOP (solid shape): 156.54,45.69 156.54,45.08 156.67,44.94 157.01,44.94 157.2,44.76 157.2,43.35 157.14,43.3 156.5,43.3 156.42,43.22 156.42,42.47 156.54,42.35 156.99,42.35 157.12,42.22 157.12,40.95 156.87,40.7 155.46,40.7 155.37,40.79 155.37,41.31 155.28,41.4 153.47,41.4 153.34,41.26 153.34,40.79 153.26,40.71 152.64,40.71 152.57,40.78 152.57,45.5 152.85,45.78 156.45,45.78
GND on TOP (solid shape): 168.75,29.56 168.75,26.13 168.37,25.75 168.37,22.38 168.92,21.82 168.92,21.48 168.81,21.37 168.56,21.37 168.43,21.49 168.43,21.56 168.11,21.87 167.22,21.87 167.22,21.88 167.06,22.04 167.06,22.7 167.22,22.86 167.22,24.48 167.48,24.73 167.48,26.51 166.65,27.34 166.65,27.97 166.52,28.1 164.05,28.1 163.98,28.16 163.98,29.56 164.24,29.81 168.49,29.81
GND on TOP (solid shape): 185.12,30.62 184.57,29.86 185.12,29.1 185.12,26.11 177.62,26.11 177.62,33.61 185.12,33.61
GND on TOP (solid shape): 98.86,48.41 98.92,48.4 99.04,48.29 99.04,46.83 99.19,46.68 99.82,46.68 99.82,44.42 99.84,44.4 99.84,44.16 100.8,43.2 100.8,42.13 100.68,42 99.15,42 98.96,41.81 98.96,39.72 98.89,39.65 98.83,39.65 98.76,39.66 98.68,39.65 98.35,39.65 98.25,39.74 98.25,42.44 98.1,42.59 98.1,43.17 98.81,43.88 98.81,46.02 98.35,46.47 98.35,48.42 98.81,48.42
GND on TOP (solid shape): 41.05,152.11 41.05,150.97 41.35,150.67 41.35,149.34 41.49,149.19 41.81,149.19 41.97,149.03 41.97,147.03 42.35,146.65 43.37,146.65 43.49,146.78 43.49,146.91 43.56,146.97 45.33,146.97 45.4,146.91 45.4,146.33 45.53,146.21 46.6,146.21 46.99,146.59 47.62,146.59 47.68,146.52 47.68,146.27 47.3,145.89 45.27,145.89 44.89,145.51 43.94,145.51 43.56,145.89 42.41,145.89 42.16,145.64 40.64,145.64 39.8,146.47 39.8,150.71 39.91,150.83 39.91,152.16 39.99,152.24 40.92,152.24
GND on TOP (solid shape): 163.47,48.18 163.47,45.89 163.12,45.54 163.11,45.54 162.7,45.12 162.7,44.64 162.62,44.56 162.31,44.56 162.23,44.64 162.24,44.67 162.25,44.87 162.15,45.04 162.15,46.02 162.15,46.03 162.18,46.16 162.15,46.28 162.15,46.29 162.15,46.33 162.54,46.73 162.54,48.11 162.71,48.28 163.37,48.28
GND on TOP (solid shape): 91.38,52.47 91.38,52.42 91.56,52.25 91.56,52.13 91.95,51.73 91.95,51.55 91.49,51.1 91.49,50.74 91.21,50.74 90.71,50.24 89.83,50.24 89.51,49.93 89.51,49.52 89.13,49.52 89.04,49.62 89.04,50.11 89.76,50.84 89.76,51.5 89.61,51.66 88.47,51.66 88.47,52.16 89.03,52.16 89.18,52.01 90.21,52.01 90.63,52.43 90.65,52.43 90.77,52.55 91.3,52.55
GND on TOP (solid shape): 72.16,21.37 72.16,20.1 71.91,19.84 68.61,19.84 68.29,19.52 66.89,19.52 66.58,19.21 66.58,17.6 66.51,17.54 66.51,16.53 66.17,16.2 66.17,14.91 66.7,14.38 66.7,14.06 66.64,14 65.88,14 65.88,14.01 65.76,14.13 65.76,14.65 65.84,14.72 65.84,16.01 65.5,16.35 65.5,17.56 65.88,17.94 65.88,19.08 65.45,19.51 65.45,21.38 65.75,21.68 71.85,21.68
GND on TOP (solid shape): 95.41,56.52 95.67,56.43 95.93,56.52 96.41,56.52 96.66,56.44 96.91,56.52 97.32,56.52 97.43,56.41 97.43,55.85 97.55,55.73 97.74,55.73 97.82,55.65 97.82,55.64 97.87,55.54 97.95,55.46 97.95,55.31 97.84,55.2 97.45,55.2 97.11,55.54 95.06,55.54 94.74,55.22 94.55,55.22 94.43,55.35 94.43,55.5 95.04,56.11 95.04,56.45 95.1,56.52
GND on TOP (solid shape): 89.83,61.48 90.14,61.48 90.24,61.47 90.33,61.48 90.52,61.48 90.59,61.41 90.59,61.03 90.62,61 90.63,61 90.73,60.9 91.01,60.9 91.1,60.81 91.1,60.64 91.28,60.47 91.31,60.47 91.45,60.44 91.58,60.46 91.59,60.47 91.85,60.47 91.93,60.39 91.93,59.59 91.85,59.51 91.16,59.51 91.07,59.6 91.07,59.87 90.87,60.07 90.52,60.07 90.46,60.14 90.46,60.47 90.34,60.59 89.75,60.59 89.58,60.76 89.58,61.46 89.61,61.5 89.81,61.5
GND on TOP (solid shape): 92.99,139.22 92.99,138.94 92.71,138.66 92.71,137.61 92.73,137.6 92.73,136.05 92.1,135.43 92.1,135.4 92.06,135.36 92.06,134.51 91.73,134.17 91.73,133.41 91.58,133.26 91.58,132.94 91.58,132.94 91.58,132.79 91.89,132.48 92.04,132.48 92.38,132.14 93.28,132.14 93.34,132.2 94.36,132.2 94.49,132.07 94.49,131.5 94.36,131.38 92.79,131.38 92.59,131.17 92.59,130.14 92.74,129.99 93.8,129.99 93.83,129.96 93.83,129.58 93.78,129.53 92.1,129.53 91.77,129.2 91.09,129.2 91.09,129.71 91.59,129.71 91.85,129.96 91.85,130.65 91.85,130.68 91.51,131.02 91.51,132.11 91.49,132.12 90.84,132.77 90.84,134.57 90.49,134.93 90.49,138.74 90.55,138.8 90.62,138.8 90.62,138.81 91.06,138.81 91.22,138.65 91.72,138.65 92.45,139.38 92.83,139.38
GND on TOP (solid shape): 13.11,147.16 13.61,146.12 12.96,145.17 12.66,144.87 12.66,144.24 12.35,143.92 6.38,143.92 6.12,144.18 6.12,145.51 12.45,145.51 13.15,146.11 12.65,146.88 12.65,147.16
GND on TOP (solid shape): 103.66,52.54 103.66,52.23 103.53,52.1 103.36,52.1 102.71,51.45 102.71,51.27 102.52,51.08 102.12,51.08 101.42,50.39 100.41,50.39 100.21,50.59 100.21,50.68 99.95,50.93 98.39,50.93 98.2,50.74 98.2,50.26 97.69,50.26 97.69,50.77 97.56,50.89 96.67,50.89 96.55,50.77 96.55,50.26 96.48,50.2 95.56,50.2 94.96,50.8 94.4,50.8 94.36,50.76 93.84,50.76 93.82,50.79 93.82,51.36 93.94,51.49 94.48,51.49 94.91,51.92 94.93,51.94 94.93,51.96 94.93,52.41 95.03,52.53 95.05,52.54 95.07,52.54 95.91,52.54 95.99,52.47 96.01,52.46 96.01,52.44 96.01,51.71 96.01,51.69 96.02,51.68 96.18,51.52 96.2,51.5 96.22,51.5 96.29,51.5 96.36,51.44 96.37,51.43 96.39,51.42 97.39,51.42 97.41,51.43 97.42,51.44 97.66,51.68 97.92,51.68 98.05,51.81 98.05,52.54 98.07,52.57 98.73,52.57 99.09,52.21 102.63,52.21 103.09,52.67 103.53,52.67
GND on TOP (solid shape): outline of 89 points within 29.01,20.22 35.52,23.59
GND on TOP (solid shape): 5.68,145.05 2.6,145.05 1.66,143.45 2.17,141.68 2.27,141.57 2.46,141.38 2.57,141.3 2.81,141.11 2.83,141.09 2.83,141.07 2.83,136.16 2.82,136.13 2.78,136.11 2.42,136.11 2.39,136.13 2.37,136.16 2.37,140.87 2.11,141.08 1.87,141.32 1.85,141.36 1.85,141.35 1.19,143.35 2.11,145.24 2.17,145.3 2.17,145.51 5.68,145.51
GND on TOP (solid shape): 90.02,58.63 90.21,58.63 90.23,58.63 90.25,58.62 90.38,58.48 91.52,58.48 91.65,58.46 91.77,58.48 91.79,58.48 91.89,58.38 91.89,57.49 91.73,57.34 90.46,57.34 90.3,57.18 90.3,56.69 90.5,56.48 91.26,56.48 91.77,55.97 91.77,55.36 91.7,55.29 90.43,55.29 90.32,55.19 90.32,54.55 90.51,54.37 91.39,54.37 91.83,53.93 91.83,53.7 91.85,53.68 91.85,53.66 91.85,53.39 91.85,53.37 91.83,53.35 91.76,53.29 91.44,53.29 91.42,53.29 91.4,53.3 91.38,53.33 89.95,53.33 89.94,53.33 89.66,53.33 89.47,53.53 89.47,53.8 89.81,54.14 89.81,54.84 89.81,54.86 89.8,54.88 89.66,55.02 89.66,55.37 89.66,55.39 89.67,55.41 89.79,55.64 89.76,55.9 89.75,55.92 89.75,56.55 89.82,56.78 89.75,57.01 89.75,58.03 89.75,58.05 89.74,58.07 89.7,58.11 89.63,58.19 89.55,58.25 89.54,58.26 89.49,58.32 89.49,58.54 89.47,58.56 89.47,58.75 89.58,58.85 89.8,58.85
GND on TOP (solid shape): 85.67,156.36 88.97,153.06 92.27,156.36 92.27,159.46 94.52,159.46 96.31,159.17 97.93,158.35 105.33,152.96 107.09,150.91 107.72,148.28 107.72,145.83 107.47,145.83 101.37,151.93 85.17,151.93 83.75,153.35 76.01,153.35 71.85,157.51 67.2,157.51 67.2,159.46 85.67,159.46
GND on TOP (solid shape): 4.44,38.35 4.44,37.91 3.71,37.18 2.31,37.18 2.25,37.11 2.25,34.96 2.31,34.89 3.65,34.89 4.41,34.13 4.41,33.56 4.16,33.3 3.39,33.3 3.01,32.92 3.01,31.72 3.39,31.34 4.09,31.34 4.09,28.29 2.19,26.38 2.19,15.97 4.98,13.17 4.98,4.86 5.43,4.41 13.3,4.41 15.01,2.7 33.68,2.7 34.25,2.13 36.16,2.13 38.83,4.79 49.62,4.79 53.73,0.68 53.73,0.2 48.26,0.2 48.23,0.2 47.35,1.08 47.35,3.2 39.94,3.2 39.94,1.25 39.94,1.08 39.06,0.2 38.53,0.2 30.67,0.2 30.67,2.2 20.27,2.2 20.27,0.2 10.39,0.2 9.87,0.2 9.72,0.24 9.61,0.35 9.44,0.65 8.43,2.4 6.78,2.84 6.34,1.2 6.66,0.65 6.66,0.35 6.4,0.2 5.88,0.2 1.47,0.2 0.91,0.44 0.67,1 0.67,36.93 0.67,37.55 1.25,37.89 1.48,38.52 1.49,38.55 1.5,38.57 4.22,38.57
GND on TOP (solid shape): outline of 151 points within 94.34,57.19 97.83,64
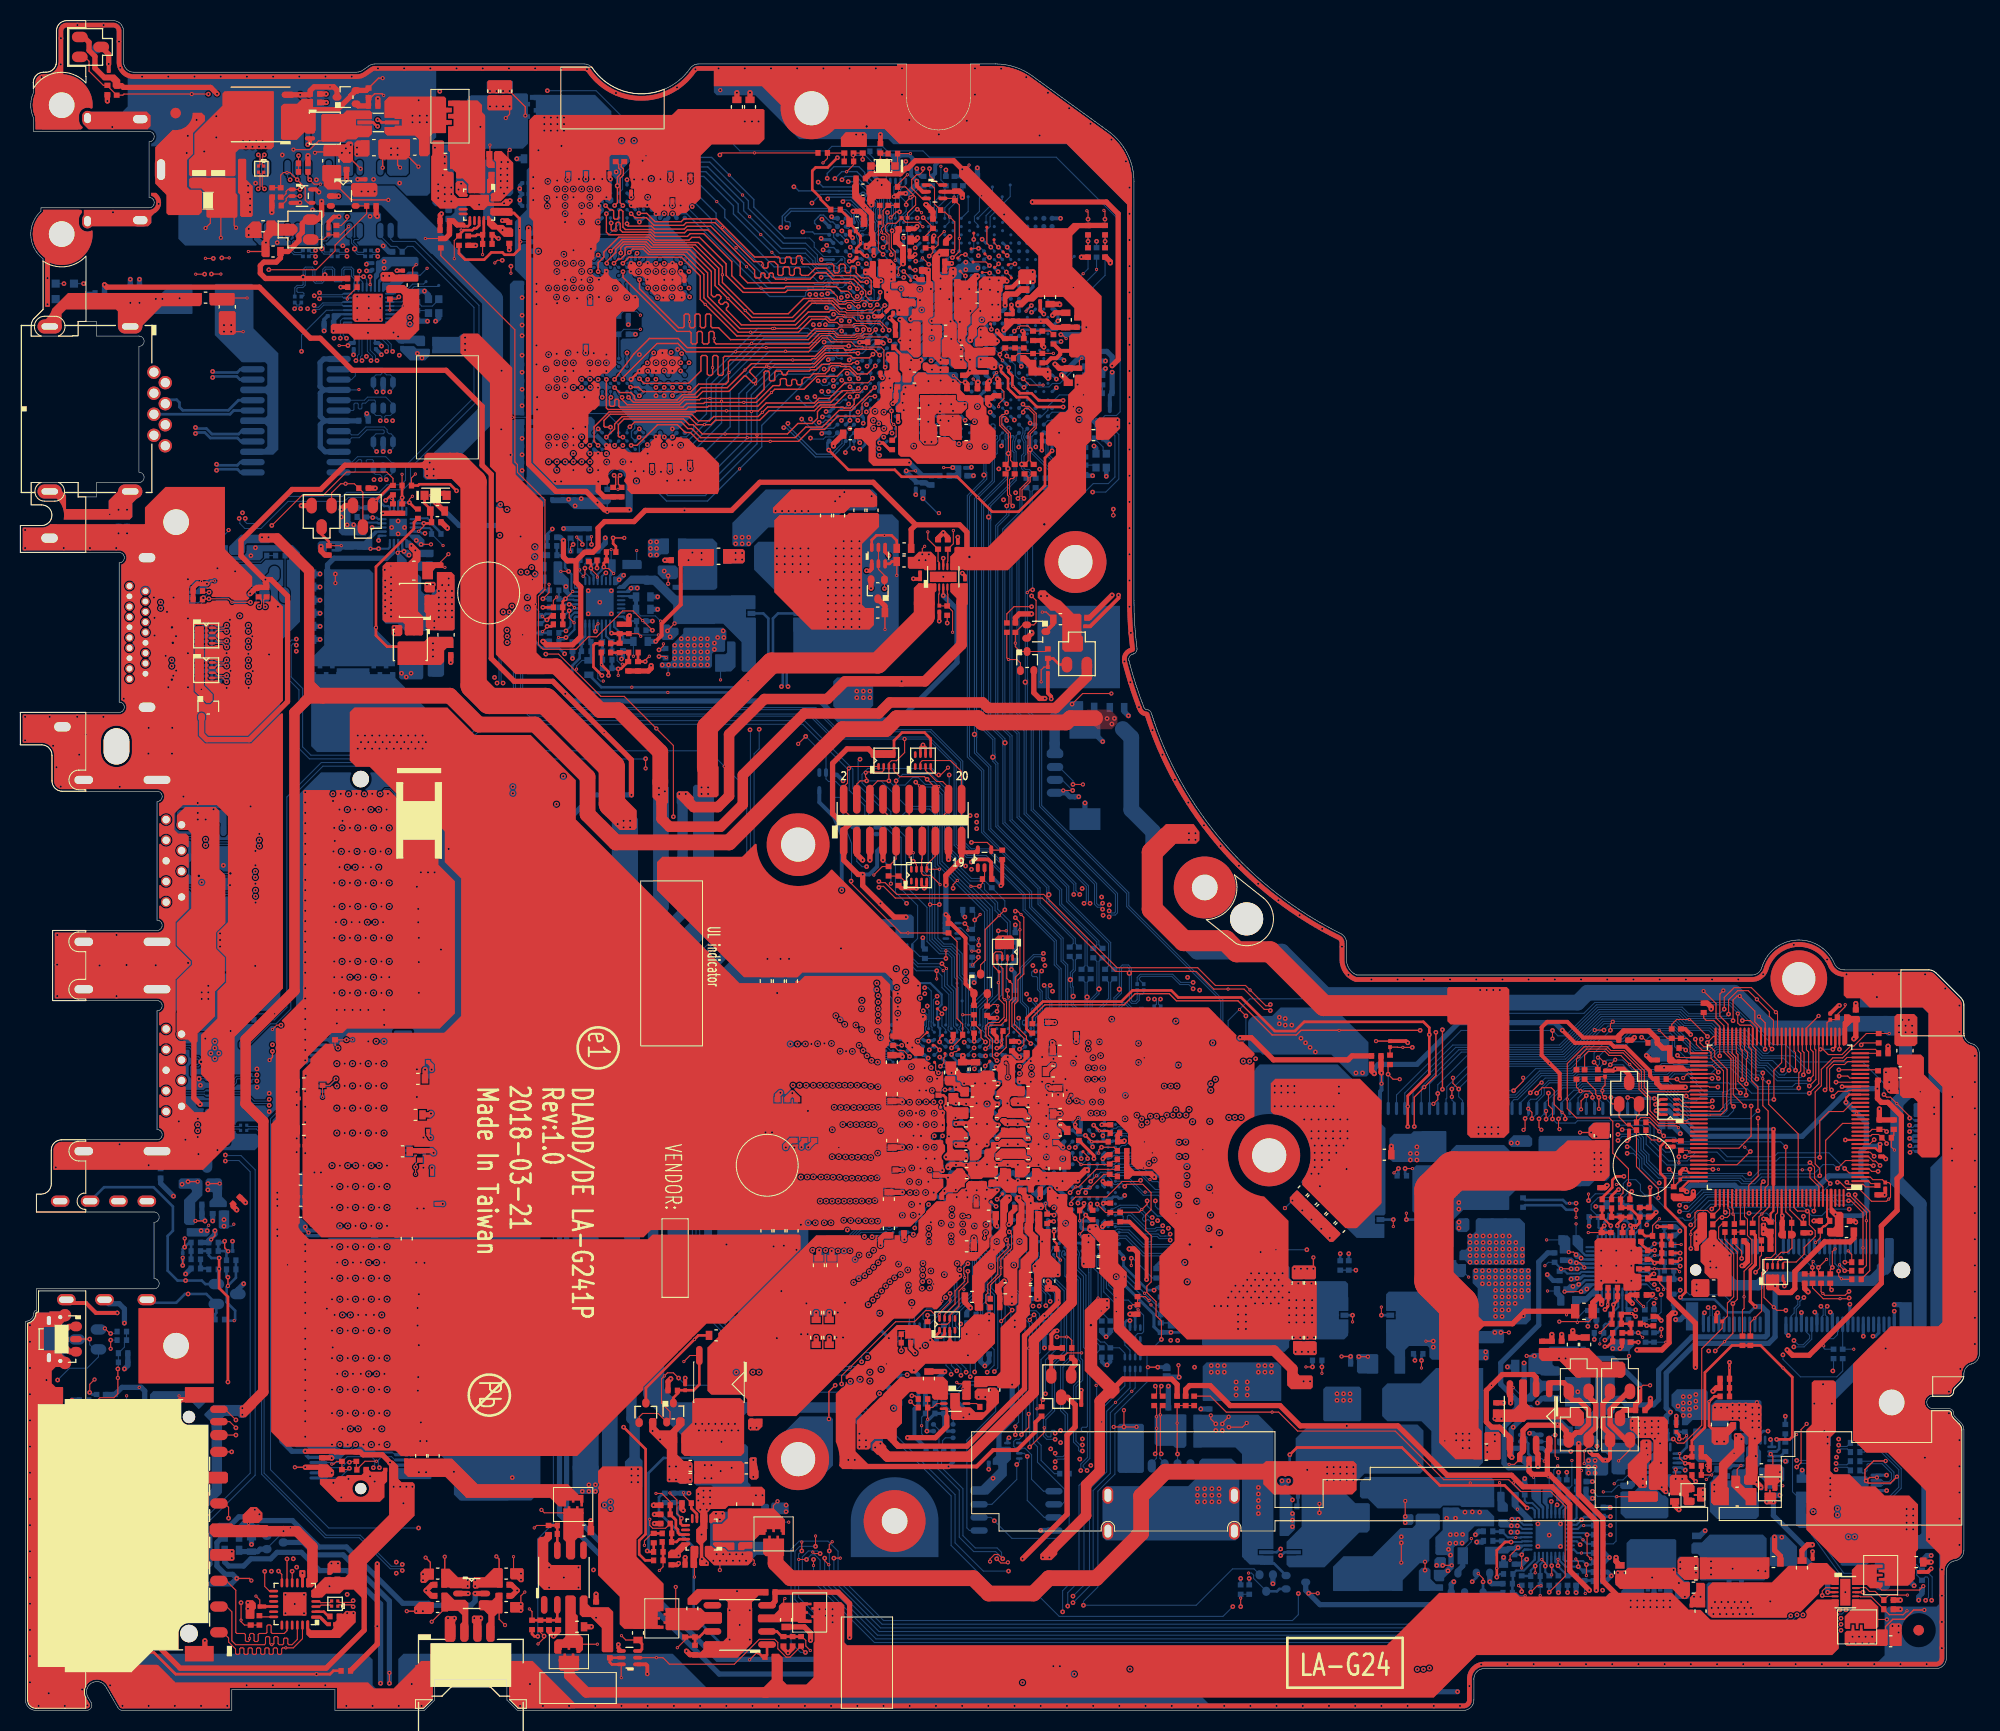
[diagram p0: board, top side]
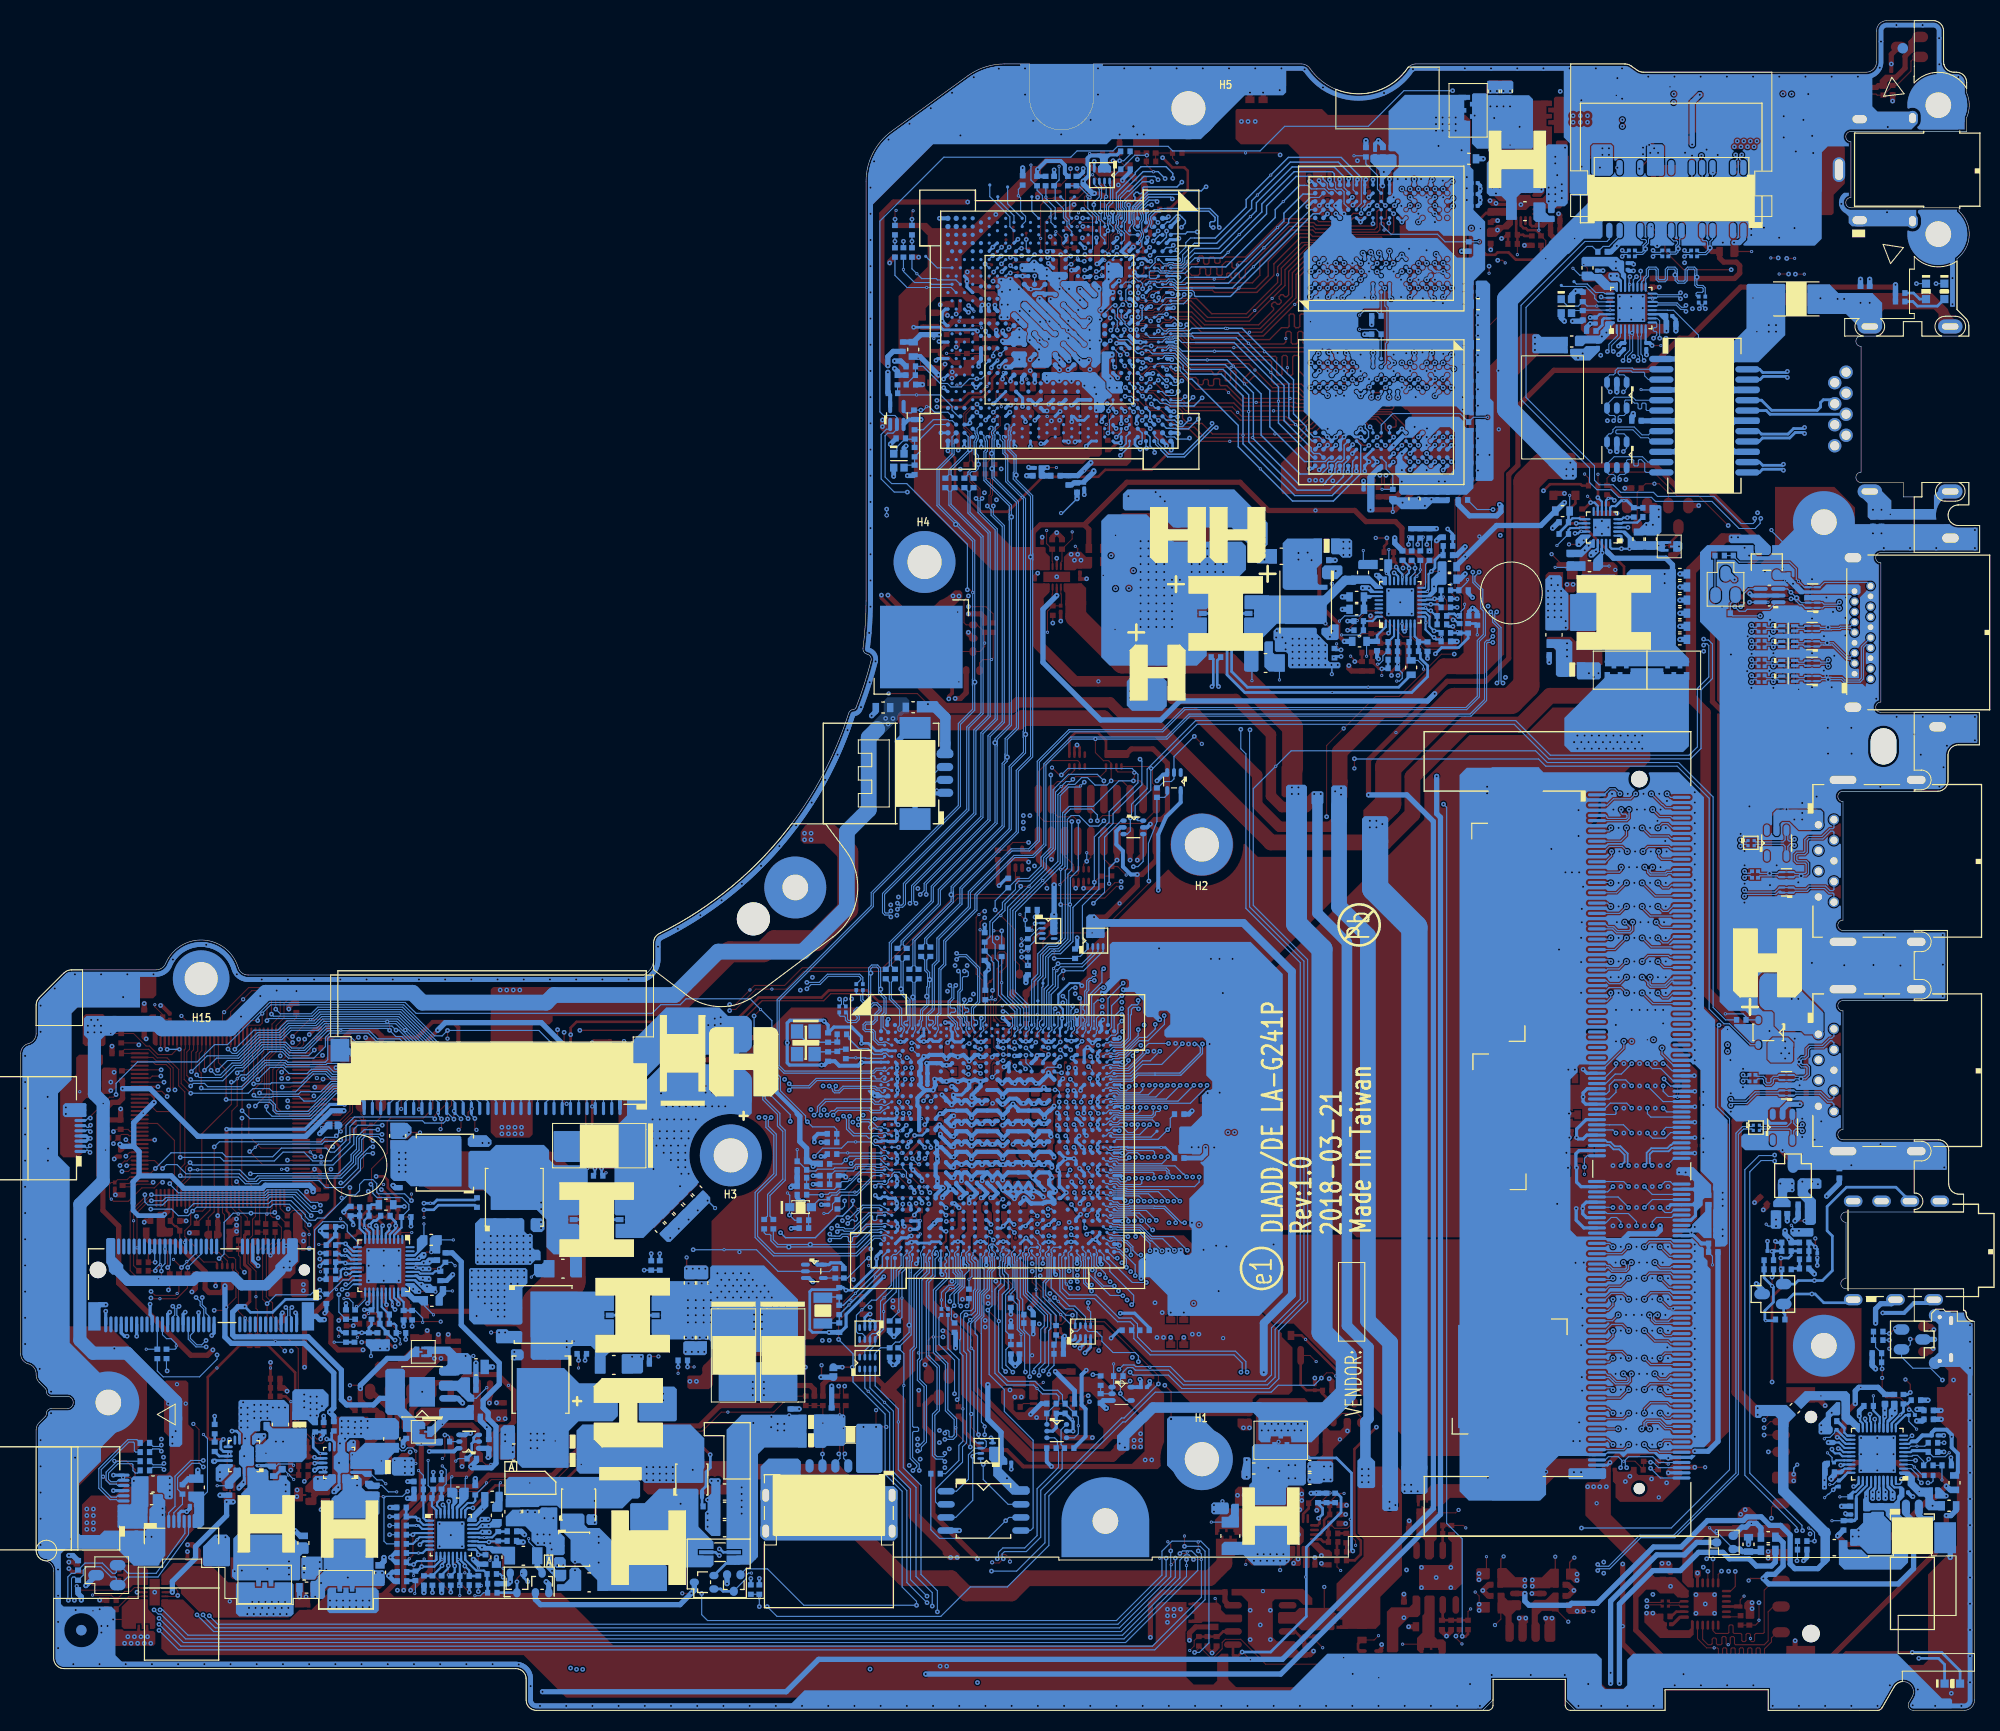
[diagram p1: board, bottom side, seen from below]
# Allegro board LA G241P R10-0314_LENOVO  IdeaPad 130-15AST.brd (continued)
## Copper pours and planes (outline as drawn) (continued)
GND on TOP (solid shape): 184.96,71.61 185.26,71.55 185.52,71.37 187.93,68.96 188.11,68.7 188.17,68.4 188.17,65.63 188.42,64.89 189.07,64.46 189.5,64.18 189.67,63.69 189.67,34.57 189.5,34.08 189.07,33.8 188.42,33.37 188.17,32.63 188.17,32.52 188.11,32.22 187.93,31.96 187.36,31.39 187.21,31.17 187.17,30.91 187.1,30.74 186.92,30.66 185.37,30.66 184.57,29.86 185.37,29.06 186.92,29.06 187.1,28.98 187.17,28.81 187.21,28.55 187.36,28.33 187.93,27.76 188.11,27.5 188.17,27.2 188.17,15.5 187.97,14.98 186.76,14.31 186.47,13.52 186.47,13.17 186.08,13.17 186.08,15.08 184.69,16.48 184.69,21.3 181,24.99 178.91,24.99 177.7,26.19 177.7,33.69 181.26,37.24 185.88,37.24 186.29,37.65 186.29,60.47 184.94,61.82 184.94,67.59 184.37,68.17 179.22,68.17 178.34,69.05 177.01,69.05 176.72,69.34 176.72,71.58 176.75,71.61
GND on TOP (solid shape): outline of 227 points within 84.43,130.51 89.99,139.96
GND on TOP (solid shape): outline of 492 points within 61.69,63.45 87.82,84.04
GND on TOP (solid shape): outline of 309 points within 0.67,0.2 189.67,163.66
GND on TOP (solid shape): outline of 3334 points within 0.2,52.42 25.43,117
GND on TOP (solid shape): outline of 3968 points within 24.28,24.67 75.61,89.25
GND on BOTTOM (solid shape): 48.52,51.08 44.52,51.08 44.52,63.08 48.52,63.08
GND on BOTTOM (solid shape): 48.62,65.46 44.62,65.46 44.62,85.46 48.62,85.46
GND on BOTTOM (solid shape): 50.53,27.38 40.53,27.38 40.53,37.38 50.53,37.38
GND on BOTTOM (solid shape): 143.35,27.34 143.35,24.35 142.14,24.35 141.95,24.54 141.95,27.53 142.08,27.65 143.03,27.65
GND on BOTTOM (solid shape): 4.28,21.56 4.28,20.6 4.22,20.54 3.27,20.54 3.14,20.67 3.14,20.92 3.84,21.62 4.22,21.62
GND on BOTTOM (solid shape): 70.2,112.43 70.2,111.41 70,111.22 68.1,111.22 68.1,112.62 70,112.62
GND on BOTTOM (solid shape): 78.75,28.26 78.75,23.76 76.9,21.91 74.78,21.91 73.88,22.81 73.88,26.85 75.54,28.51 78.49,28.51
GND on BOTTOM (solid shape): 82.64,99.79 82.64,97.44 82.13,96.93 79.21,96.93 78.77,97.38 78.77,99.79 79.15,100.17 82.26,100.17
GND on BOTTOM (solid shape): 92.97,152.36 84.97,152.36 84.97,159.66 92.97,159.66
GND on BOTTOM (solid shape): 93.86,135.38 93.86,135.18 92.71,134.04 92.43,134.04 92.3,134.17 92.3,134.43 93.45,135.58 93.65,135.58
GND on BOTTOM (solid shape): 122.2,33.37 122.2,30.07 122.14,30 114.65,30 114.58,30.07 114.58,33.37 114.96,33.75 121.82,33.75
GND on BOTTOM (solid shape): 127.92,46.26 127.92,46.13 127.22,45.43 126.9,45.43 123.03,49.31 123.03,49.75 123.66,50.39 123.79,50.39
GND on BOTTOM (solid shape): 129.95,31.21 129.95,28.16 129.82,28.03 126.39,28.03 126.27,28.16 126.27,31.15 126.52,31.4 129.76,31.4
GND on BOTTOM (solid shape): 125.63,35.65 125.63,34.64 125.44,34.45 123.54,34.45 123.34,34.64 123.34,35.78 125.5,35.78
GND on BOTTOM (solid shape): 42.06,109.69 42.06,104.81 42,104.74 39.97,104.74 39.84,104.87 39.84,108.3 40.48,108.93 40.48,109.89 40.67,110.08 41.68,110.08
GND on BOTTOM (solid shape): 125.57,42.96 125.57,41.94 125.44,41.81 123.34,41.81 123.22,41.94 123.22,42.96 123.41,43.15 125.38,43.15
GND on BOTTOM (solid shape): 156.41,35.95 156.41,35.38 155.86,34.83 154.21,34.83 154.08,34.96 154.08,35.91 154.14,35.97 156.39,35.97
GND on BOTTOM (solid shape): 31.97,115.35 32.1,115.22 32.35,115.22 32.98,114.58 33.49,114.58 33.49,113.95 31.14,113.95 30.83,114.27 30.83,116.74 30.95,116.87 31.97,116.87
GND on BOTTOM (solid shape): 74.45,19.97 74.45,19.21 74.26,19.02 72.91,19.02 72.76,19.17 72.76,20.03 72.88,20.15 73.3,20.15 73.31,20.16 74.26,20.16
GND on BOTTOM (solid shape): 154.02,55.53 153.89,55.4 152.55,55.4 151.98,55.97 151.98,56.55 152.4,56.96 154.02,56.96
GND on BOTTOM (solid shape): 47.72,157.95 47.72,156.94 47.59,156.81 45.3,156.81 45.18,156.94 45.18,157.89 45.3,158.02 47.65,158.02
GND on BOTTOM (solid shape): 65.12,23.97 65.12,22.13 64.99,22 63.78,22 63.65,22.13 62.77,22.13 62.64,22.26 62.64,23.97 62.83,24.16 64.92,24.16
GND on BOTTOM (solid shape): 118.14,23.65 118.14,16.86 117.76,16.48 105.18,16.48 104.87,16.79 104.87,21.37 105.25,21.75 113.18,21.75 114.26,22.83 114.26,24.16 114.52,24.41 117.38,24.41
GND on BOTTOM (solid shape): 138.2,56.1 138.2,53.43 137.95,53.18 133,53.18 132.68,53.5 132.68,55.47 133.12,55.91 134.77,55.91 135.03,56.16 138.14,56.16
GND on BOTTOM (solid shape): 162.65,14.73 162.65,12.84 162.5,12.69 161.37,12.69 161.22,12.84 161.22,12.94 160.63,13.54 160.63,14.75 160.78,14.91 162.47,14.91
GND on BOTTOM (solid shape): 171.8,16.29 171.8,16.28 172.19,15.88 172.19,14.12 172.04,13.97 169.68,13.97 169.57,14.08 169.57,16.73 169.89,17.05 171.03,17.05
GND on BOTTOM (solid shape): 38.38,132.05 39.59,132.05 39.65,131.98 39.65,131.35 39.21,130.9 37.75,130.9 36.79,131.86 36.79,132.3 38.13,132.3
GND on BOTTOM (solid shape): 83.02,117.95 83.02,116.55 82.83,116.36 79.78,116.36 78.13,114.71 72.48,114.71 70.64,112.87 69.18,112.87 68.99,113.06 68.99,115.16 72.23,118.39 82.58,118.39
GND on BOTTOM (solid shape): 130.65,64.8 130.65,61.65 130.47,61.47 129.18,61.47 127.05,63.59 120.37,63.59 120.16,63.8 119.52,63.8 119.03,64.29 119.03,66.9 119.47,67.34 121.31,67.34 122.14,68.17 127.28,68.17
GND on BOTTOM (solid shape): 15.24,24 15.24,21.49 15.17,21.42 14.86,21.42 14.78,21.51 14.78,21.75 14.79,21.76 14.79,22.73 14.71,22.8 14.71,23.49 14.48,23.72 14.48,24.2 15.04,24.2
GND on BOTTOM (solid shape): 71.34,24.48 71.34,23.97 71.38,23.93 71.43,23.55 71.53,23.18 71.53,22.57 71.34,22.38 70.83,22.38 70.64,22.57 70.64,24.41 70.77,24.54 71.27,24.54
GND on BOTTOM (solid shape): 146.4,42.77 146.4,37.88 145.95,37.43 141.37,37.43 141.24,37.57 141.24,40.94 140.74,41.43 140.74,42.7 140.93,42.89 146.27,42.89
GND on BOTTOM (solid shape): 57.22,117.68 57.22,117.19 56.97,116.94 56.5,116.94 56.05,116.49 53.62,116.49 53.05,117.06 51.46,117.06 51.34,117.19 51.34,117.57 51.4,117.63 56.42,117.63 56.54,117.76 57.14,117.76
GND on BOTTOM (solid shape): 123.15,22.39 123.15,22.12 122.9,21.87 122.9,21.05 123.47,20.48 123.47,20.35 123.28,20.16 123.28,19.4 123.54,19.14 123.54,17.56 122.9,16.92 122.07,16.92 122.03,16.96 122.03,22.39 122.15,22.51 123.03,22.51
GND on BOTTOM (solid shape): 10.53,19.15 11.2,19.15 11.2,19.14 11.27,19.08 11.27,18.2 11.88,17.59 12.44,17.59 12.53,17.5 12.53,16.03 12.47,15.97 11.6,15.97 10.82,15.19 8.64,15.19 8.6,15.23 8.6,18.23 9.25,18.88 9.25,19.21 9.32,19.27 10.41,19.27
GND on BOTTOM (solid shape): 42,151.67 42,146.25 41.82,146.07 41.82,145.3 41.71,145.19 41.27,145.19 41.17,145.29 41.17,145.64 40.95,145.86 40.19,145.86 39.91,146.15 39.91,151.73 40.03,151.86 41.81,151.86
GND on BOTTOM (solid shape): 145.82,47.21 145.82,43.4 145.63,43.21 140.43,43.21 139.98,43.65 139.47,43.65 139.47,44.48 139.66,44.67 140.05,44.67 140.24,44.86 140.24,46.07 140.36,46.19 140.79,46.19 141.05,46.46 141.05,47.51 141.25,47.72 145.32,47.72
GND on BOTTOM (solid shape): 68.42,104.68 68.42,103.85 68.29,103.73 68.29,102.77 68.16,102.65 67.21,102.65 67.02,102.46 67.02,101.25 66.83,101.06 62.07,101.06 61.94,101.19 61.94,101.5 62.07,101.63 62.96,101.63 63.15,101.82 63.15,103.34 64.23,104.42 64.23,104.87 64.35,105 68.1,105
GND on BOTTOM (solid shape): 4.44,38.35 4.44,37.91 3.96,37.43 3.96,34.7 4.41,34.26 4.41,33.56 4.16,33.3 1.87,33.3 1.04,32.48 0.67,32.48 0.67,37.55 1.25,37.89 1.48,38.52 1.49,38.55 1.5,38.57 4.22,38.57
GND on BOTTOM (solid shape): 107.72,60.14 107.75,60.07 107.72,59.99 107.16,59.43 107.04,59.43 107.02,59.43 107.01,59.41 106.94,59.35 106.61,59.35 106.53,59.43 106.15,59.43 106.07,59.35 105.65,59.35 105.55,59.45 105.55,59.66 105.7,59.81 105.9,59.81 106.06,59.65 106.08,59.64 106.1,59.64 106.35,59.64 106.37,59.64 106.39,59.65 106.44,59.7 106.71,59.97 107.01,59.97 107.17,60.14
GND on BOTTOM (solid shape): 139.59,19.46 142.18,19.46 142.83,18.81 142.83,17.87 142.8,17.85 140.95,17.85 140.34,17.25 140.34,16.46 139.85,15.97 139.09,15.97 138.92,15.79 138.92,13.76 137.99,12.84 137.99,12.61 137.91,12.52 137.2,12.52 136.99,12.74 136.99,13.62 137,13.63 137.98,13.63 138.39,14.05 138.39,14.91 138.25,15.05 137.29,15.05 137.14,15.21 137.14,16.78 137.85,17.49 137.85,19.63 137.9,19.68 139.37,19.68
GND on BOTTOM (solid shape): 48.8,138.52 48.8,125.57 47.88,125.57 47.39,125.39 47.88,125.21 48.8,125.21 48.8,119.22 47.27,119.22 47.1,119.39 47.1,126.89 47.42,127.21 47.42,138.3 47.78,138.65 48.67,138.65
GND on BOTTOM (solid shape): 92.87,136.4 92.87,136.1 90.64,133.87 90.44,133.87 90.43,133.87 89.86,133.3 89.76,133.3 89.72,133.27 89.33,133.45 89.65,133.73 89.73,133.71 90.33,134.3 90.33,134.34 90.38,134.45 90.48,134.52 90.5,134.53 90.53,134.56 90.53,134.7 92.41,136.58 92.69,136.58
GND on BOTTOM (solid shape): 89.33,131.47 89.64,131.74 89.8,131.35 89.8,131.19 89.4,130.8 89.3,130.7 89.24,130.57 88.89,130.22 88.67,130.22 88.53,130.36 88.54,130.39 88.53,130.43 88.53,130.53 88.57,130.62 88.6,130.68 88.95,131.03 88.97,131.06 89.02,131.15 89.11,131.2 89.14,131.22 89.33,131.41
GND on BOTTOM (solid shape): 159.01,28.31 159.01,26.73 159.13,26.6 159.13,25.01 159.51,24.63 159.51,23.42 159.13,23.04 159.13,21.96 159.73,21.37 159.73,21.06 159.64,20.97 159.3,20.97 158.84,21.43 158.84,21.94 158.88,21.98 158.88,22.92 158.75,23.04 158.18,23.04 158.05,23.17 158.05,24.83 158.17,24.95 158.24,24.95 158.42,25.13 158.42,25.98 157.99,26.41 156.64,26.41 156.49,26.26 153.41,26.26 153.19,26.47 153.19,27.97 153.57,28.35 156.49,28.35 156.62,28.48 158.84,28.48
GND on BOTTOM (solid shape): 88.33,138.6 88.9,138.6 89.06,138.44 89.06,138.21 88.85,138.04 88.79,137.98 88.79,137.91 87.07,136.18 86.91,136.02 86.64,136.02 86.64,136.02 86.48,136.18 86.48,136.18 86.48,136.45 87.57,137.54 87.57,137.97 87.4,138.14 87.35,138.14 87.04,138.14 86.93,138.04 86.88,137.98 85.92,137.02 85.66,137.02 85.52,137.16 85.51,137.18 85.51,137.4 85.52,137.42 86.2,138.09 86.2,138.26 86.54,138.6 88.32,138.6
GND on BOTTOM (solid shape): 168.75,29.94 168.75,27.27 168.56,27.08 168.56,27.08 168.33,26.85 168.33,25.8 168.52,25.61 168.52,25.33 168.71,25.14 168.71,23.89 168.33,23.51 168.33,22.34 168.94,21.73 168.94,21.43 168.81,21.3 168.63,21.3 168.04,21.9 168.04,22.6 168.07,22.64 168.07,23.58 167.95,23.7 167.38,23.7 167.25,23.83 167.25,25.49 167.36,25.61 167.44,25.61 167.62,25.79 167.62,26.64 167.19,27.07 166.72,27.07 166.65,27.13 166.65,27.97 166.52,28.1 165.64,28.1 165.57,28.03 165.57,27.72 165.37,27.51 163.98,27.51 163.86,27.64 163.86,29.62 164.34,30.11 168.58,30.11
GND on BOTTOM (solid shape): 13.11,147.16 13.61,146.12 12.96,145.17 12.66,144.87 12.66,144.24 12.35,143.92 6.38,143.92 6.12,144.18 6.12,145.51 12.45,145.51 13.15,146.11 12.65,146.88 12.65,147.16
GND on BOTTOM (solid shape): 91.33,133.48 91.65,133.73 91.8,133.35 91.74,133.29 91.33,132.89 91.33,132.84 91.26,132.72 91.14,132.65 91.1,132.65 90.79,132.34 90.72,132.27 90.34,132.42 90.59,132.74 90.65,132.74 90.9,132.99 90.94,133.04 90.99,133.08 91.33,133.42
GND on BOTTOM (solid shape): 91.35,136.99 91.35,136.98 91.43,136.9 91.43,136.67 89.04,134.28 89.03,134.23 88.93,134.08 88.76,134.04 88.6,133.99 88.53,133.84 88.47,133.7 88.33,133.63 88.27,133.62 87.94,133.29 87.92,133.27 87.88,133.25 87.84,133.24 87.79,133.23 87.04,132.48 87.03,132.43 86.6,132.31 86.73,132.74 86.77,132.75 87.53,133.5 87.53,133.54 87.63,133.69 87.79,133.74 89.18,135.13 89.18,135.32 91.01,137.15 91.18,137.15
GND on BOTTOM (solid shape): 88.53,132.54 88.96,132.67 88.84,132.24 88.79,132.23 88.04,131.48 88.03,131.43 87.98,131.33 87.89,131.26 87.89,131.13 86.97,130.21 86.64,130.21 86.23,130.63 86.23,130.72 86.16,131.09 86.53,131.02 86.54,131 87.02,131 87.07,131.1 87.17,131.16 87.2,131.18 87.53,131.5 87.53,131.54 87.6,131.67 87.73,131.74 87.77,131.75 88.53,132.5
GND on BOTTOM (solid shape): 88.53,136.34 88.96,136.47 88.84,136.04 88.79,136.03 88.04,135.28 88.03,135.23 87.96,135.11 87.84,135.04 87.79,135.03 87.04,134.28 87.03,134.23 86.78,134.03 86.53,134.23 86.53,134.28 86.11,134.7 86.11,134.8 86.09,134.83 86.26,135.16 86.52,134.9 87.13,134.9 87.53,135.3 87.53,135.34 87.6,135.47 87.73,135.54 87.77,135.55 88.53,136.3
GND on BOTTOM (solid shape): 34.13,4.92 34.13,2.44 34.51,2.06 36.29,2.06 36.6,2.38 36.6,4.98 37.11,5.49 63.21,5.49 66.77,1.94 113.88,1.94 115.28,0.54 115.28,0.2 48.23,0.2 47.35,1.08 47.35,3.2 39.94,3.2 39.94,1.08 39.06,0.2 30.67,0.2 30.67,2.2 20.27,2.2 20.27,0.2 9.87,0.2 9.72,0.24 9.61,0.35 9.44,0.65 8.43,2.4 6.78,2.84 6.34,1.2 6.66,0.65 6.66,0.35 6.4,0.2 2.74,0.2 2.65,0.3 2.65,1 2.8,1.16 3.64,1.16 7.98,5.49 33.56,5.49
GND on BOTTOM (solid shape): 5.68,145.05 2.6,145.05 1.66,143.45 2.17,141.68 2.27,141.57 2.46,141.38 2.57,141.3 2.81,141.11 2.83,141.09 2.83,141.07 2.83,136.16 2.82,136.13 2.78,136.11 2.42,136.11 2.39,136.13 2.37,136.16 2.37,140.87 2.11,141.08 1.87,141.32 1.85,141.36 1.85,141.35 1.19,143.35 2.11,145.24 2.17,145.3 2.17,145.51 5.68,145.51
GND on BOTTOM (solid shape): 85.67,156.36 88.97,153.06 92.27,156.36 92.27,159.46 94.52,159.46 96.31,159.17 97.93,158.35 105.33,152.96 107.09,150.91 107.72,148.28 107.72,145.83 107.47,145.83 101.42,151.88 84.59,151.88 84.1,152.37 75.47,152.37 71.21,156.62 67.49,156.62 67.2,156.91 67.2,159.46 85.67,159.46
GND on BOTTOM (solid shape): outline of 355 points within 175.85,4.25 189.67,71.61
GND on BOTTOM (solid shape): outline of 427 points within 67.53,38.26 85.22,74.52
GND on BOTTOM (solid shape): outline of 97 points within 1.18,107.52 107.72,163.66
GND on BOTTOM (solid shape): outline of 195 points within 0.67,0.2 189.67,96.56
GND on BOTTOM (solid shape): outline of 184 points within 25.47,0.2 189.67,159.46
GND on BOTTOM (solid shape): outline of 1823 points within 6,141.66 40.29,159.29
GND on BOTTOM (solid shape): outline of 3837 points within 0.17,52.42 27.08,116.79
GND on BOTTOM (solid shape): outline of 7949 points within 24.41,20.35 50.38,91.41
GND on IN1 (solid shape): 4.66,38.13 4.66,33.81 4.16,33.3 1.87,33.3 1.04,32.48 0.67,32.48 0.67,37.55 1.25,37.89 1.48,38.52 1.49,38.55 1.5,38.57 4.22,38.57
GND on IN1 (solid shape): outline of 105 points within 39.87,145.76 47.64,151.73
GND on IN1 (solid shape): 85.67,156.36 88.97,153.06 92.27,156.36 92.27,159.46 94.52,159.46 96.31,159.17 97.93,158.35 105.33,152.96 107.09,150.91 107.72,148.28 107.72,145.83 107.47,145.83 101.37,151.92 87.4,151.92 86.83,152.49 76.86,152.49 72.74,156.62 67.46,156.62 67.2,156.89 67.2,159.46 85.67,159.46
GND on IN1 (solid shape): outline of 384 points within 178.59,4.25 189.67,71.61
GND on IN1 (solid shape): outline of 334 points within 0.67,0.2 189.67,163.66
GND on IN1 (solid shape): outline of 1974 points within 0.17,52.42 17.62,116.68
GND on IN2 (solid shape): 4.66,38.13 4.66,33.81 4.16,33.3 1.87,33.3 1.04,32.48 0.67,32.48 0.67,37.55 1.25,37.89 1.48,38.52 1.49,38.55 1.5,38.57 4.22,38.57
GND on IN2 (solid shape): 85.67,156.36 88.97,153.06 92.27,156.36 92.27,159.46 94.52,159.46 96.31,159.17 97.93,158.35 105.33,152.96 107.09,150.91 107.72,148.28 107.72,145.83 107.47,145.83 101.37,151.92 87.53,151.92 86.83,152.62 76.74,152.62 72.74,156.62 67.44,156.62 67.2,156.86 67.2,159.46 85.67,159.46
GND on IN2 (solid shape): outline of 316 points within 178.3,4.25 189.67,71.61
GND on IN2 (solid shape): outline of 1503 points within 0.17,52.42 17.62,116.68
GND on IN2 (solid shape): outline of 342 points within 0.67,0.2 189.67,163.66
GND on VCC: outline of 331 points within 0.17,4.25 189.67,163.66
GND on VCC: outline of 81 points within 0.67,0.2 48.86,38.57
GND on VCC: 36.39,101.31 36.1,101.61 36.1,109.15 36.39,109.44 40.12,109.44 40.48,109.08 40.48,101.99 39.8,101.31
GND on GND: outline of 288 points within 0.2,0.2 189.67,163.66 ; 2 cut-outs
GNDA on TOP (solid shape): 18.72,31.71 11.42,31.71 11.42,39.01 18.72,39.01
GNDA on BOTTOM (solid shape): 14.89,28.86 14.89,28.48 15.59,27.78 15.59,26.89 15.46,26.76 14.44,26.76 14.25,26.95 14.25,27.46 14.38,27.59 14.38,28.41 14.19,28.61 13.62,28.61 13.49,28.73 13.49,29.88 13.87,29.88
GNDA on VCC: 12.07,18.13 11.78,18.42 11.78,20.9 11.65,21.03 11.65,21.04 10.82,21.86 10.82,22.7 11.8,22.7 12.73,21.77 12.73,21.07 13.19,20.6 14.99,20.6 15.78,21.39 15.78,24.27 15.31,24.73 13.58,24.73 13.43,24.58 13.43,24.54 12.16,24.54 12.16,26.74 11.69,27.21 7.88,27.21 7.25,27.84 5.28,27.84 5.11,28.01 5.11,29.14 5.28,29.3 6.04,29.3 6.38,29.64 6.38,30.79 6.67,31.08 8.52,31.08 9.17,31.74 9.17,34.79 10,35.61 10,37.09 8.77,38.32 7.25,38.32 6.48,39.08 3.84,39.08 3.84,39.08 1.73,39.08 1.73,40.68 12.93,40.68 13.63,41.28 13.13,42.05 13.13,47.16 13.63,47.93 12.93,48.53 1.73,48.53 1.73,49.86 1.97,49.86 2.82,50.21 3.17,51.06 3.17,51.91 19.4,51.91 19.65,51.66 19.65,50.34 21.17,48.82 21.17,42.05 20.22,41.09 20.22,39.74 20.98,38.98 20.98,30.13 18.4,30.13 17.05,28.77 17.05,21.09 14.08,18.13
GNDA on GND: 12.07,18.13 11.78,18.42 11.78,20.9 11.65,21.03 11.65,21.04 10.82,21.86 10.82,22.7 11.8,22.7 12.73,21.77 12.73,21.07 13.19,20.6 14.99,20.6 15.78,21.39 15.78,24.27 15.31,24.73 13.58,24.73 13.43,24.58 13.43,24.54 12.16,24.54 12.16,26.74 11.69,27.21 7.88,27.21 7.25,27.84 5.28,27.84 5.11,28.01 5.11,29.14 5.28,29.3 6.04,29.3 6.38,29.64 6.38,30.79 6.67,31.08 8.52,31.08 9.17,31.74 9.17,34.79 10,35.61 10,37.09 8.77,38.32 7.25,38.32 6.48,39.08 1.73,39.08 1.73,40.68 3.65,40.68 12.93,40.68 13.63,41.28 13.13,42.05 13.13,47.16 13.63,47.93 12.93,48.53 4.93,48.53 1.73,48.53 1.73,49.86 1.97,49.86 2.82,50.21 3.17,51.06 3.17,51.5 3.17,51.91 19.4,51.91 19.65,51.66 19.65,50.34 21.17,48.82 21.17,42.05 20.22,41.09 20.22,39.74 20.98,38.98 20.98,30.13 18.4,30.13 17.05,28.77 17.05,21.09 14.08,18.13
VCC_5V on BOTTOM (solid shape): 169.22,23.45 169.22,23.07 170.09,22.2 170.09,21.63 169.95,21.49 169.76,21.49 169.75,21.49 169.38,21.49 169.25,21.63 169.25,22 168.52,22.73 168.52,23.47 168.58,23.54 169.13,23.54
VCC_VGA on BOTTOM (solid shape): 52.52,111.31 52.52,110.34 53.14,109.72 53.14,108.55 53.52,108.17 54.43,108.17 54.49,108.12 54.49,107.99 54.43,107.94 53.13,107.94 53.13,107.95 53.06,108.04 52.97,108.11 52.97,108.11 52.58,108.5 52.58,109.03 52.47,109.15 51.77,109.15 51.65,109.26 51.65,111.35 51.74,111.43 52.39,111.43
VIN_0.775VALW on BOTTOM (solid shape): 146.78,29.3 149.13,29.3 149.3,29.13 149.3,28.3 150.08,27.53 150.46,27.53 150.46,26.51 150.01,26.51 148.36,28.16 145.95,28.16 145.95,29.62 146.46,29.62
+APU_CORE on TOP (solid shape): 131.92,59.15 131.92,49.18 129.5,46.77 128.42,46.77 124.23,50.96 124.23,51.39 124.24,51.41 124.87,54.99 122.35,57.61 122.34,57.61 122.27,57.69 122.09,57.69 121.78,57.76 121.46,57.81 121.45,57.81 121.19,58.07 121.19,60.8 121.63,61.24 129.82,61.24
+APU_CORE on TOP (solid shape): outline of 246 points within 89.66,53.34 95.03,62.93
+APU_CORE on BOTTOM (solid shape): 131.09,59.21 131.09,57.69 132.3,56.48 132.3,48.16 132.17,48.04 131.28,48.04 131.22,47.97 131.22,47.15 132.17,47.15 132.17,45.81 129.5,45.81 124.1,51.22 124.13,51.26 124.32,56.12 119.69,57.6 119.68,57.6 119.31,57.6 119,57.91 119,60.29 119.01,60.3 119.01,60.99 119.32,61.3 119.32,61.78 119.69,62.15 119.69,62.23 120.11,62.64 127.66,62.64
+APU_CORE on IN1 (solid shape): outline of 6353 points within 89.1,47.85 131.73,74.18
+APU_CORE on IN2 (solid shape): outline of 1670 points within 89.92,54.01 101.44,62.27
+APU_CORE on VCC: 118.69,46.45 107.53,57.6 107.53,59.64 102.88,64.29 96.76,64.29 95.91,63.45 95.91,58.17 94.96,57.22 94.96,56.59 93.88,55.51 93.88,54.75 93.71,54.58 90.13,54.58 90.13,61.54 87.95,63.72 87.13,63.72 83.34,67.51 83.34,72.95 84.59,74.2 102.07,74.2 102.54,73.73 104.88,73.73 109.91,68.7 110.65,68.7 113.18,66.16 116.98,66.16 117.89,65.25 118.7,65.25 123.41,60.55 127.7,60.55 128.58,59.66 131.11,59.66 131.85,58.92 131.85,47.82 130.48,46.45
+APU_CORE_NB on TOP (solid shape): 146.01,31.97 146.01,29.75 146.4,29.37 151.03,29.37 151.54,28.86 151.54,27.91 151.22,27.59 150.46,27.59 149.82,28.22 146.01,28.22 145.76,27.97 142.97,27.97 142.71,28.22 142.71,29.18 144.74,29.18 145.25,29.68 145.25,31.97 145.38,32.1 145.89,32.1
+APU_CORE_NB on TOP (solid shape): outline of 3562 points within 89.64,35.97 125.63,68.17
+APU_CORE_NB on BOTTOM (solid shape): 123.03,42.96 123.03,41.88 123.28,41.62 128.42,41.62 128.68,41.37 128.68,38.77 127.73,38.77 127.73,37.88 128.68,37.88 128.68,36.35 128.3,35.97 123.15,35.97 122.96,35.78 122.96,35.21 122.52,34.76 115.22,34.76 114.52,35.46 114.52,39.84 117.82,43.15 122.84,43.15
+APU_CORE_NB on IN1 (solid shape): 143.79,28.61 143.79,28.03 143.6,27.84 142.11,27.84 142.11,28.86 143.54,28.86
+APU_CORE_NB on IN1 (solid shape): 123.15,42.32 125.31,42.32 125.63,42 125.63,36.03 125.5,35.91 122.9,35.91 122.71,35.72 121.69,35.72 121.69,36.16 121.25,36.61 115.79,36.61 115.34,37.05 115.34,40.8 117.25,42.7 122.77,42.7
+APU_CORE_NB on VCC: 111.45,35.65 109.61,37.5 95.4,37.5 95.4,51 94.75,51.66 90.13,51.66 90.13,54.07 93.92,54.07 94.39,54.54 94.39,55.3 95.47,56.38 95.47,57.01 96.42,57.96 96.42,63.23 96.97,63.78 102.67,63.78 107.03,59.42 107.03,57.39 118.48,45.94 125.69,45.94 125.69,36.14 125.46,35.91 112.76,35.91 112.51,35.65
+BIF_VDDC on TOP (solid shape): 89,125.65 89.11,125.63 89.22,125.65 90.95,125.65 91.21,125.39 91.21,123.22 90.39,123.22 90.02,123.59 89.32,123.59 89.32,123.6 89.2,123.6 89.08,123.72 89.08,124.66 88.8,124.93 88.8,125.51 88.94,125.65
+BIF_VDDC on TOP (solid shape): 87.98,130.61 88.19,130.5 88.42,130.54 88.76,130.54 88.98,130.32 89.91,130.32 89.97,130.26 89.97,129.77 89.9,129.7 87.92,129.7 87.71,129.9 87.58,129.9 87.45,130.03 87.45,130.62 87.54,130.7 87.89,130.7
+BIF_VDDC on IN2 (solid shape): outline of 186 points within 86.13,124.17 90.26,130.4
+CARD_3V3 on TOP (solid shape): 28.81,12.49 28.25,11.93 27.76,11.93 27.69,12.01 27.69,12.77 27.78,12.86 27.78,13.68 28.81,13.68
+CARD_3V3 on TOP (solid shape): 20.62,17.98 23.91,17.98 24.05,17.84 24.05,16.95 23.89,16.79 18.7,16.79 18.32,17.18 18.32,17.87 18.57,18.13 20.47,18.13
+EC_VCCA on TOP (solid shape): 160.23,63.34 160.28,63.34 160.28,63.26 160.43,63.11 161.57,63.11 161.65,63.04 161.65,62.81 161.57,62.73 159.77,62.73 159.59,62.91 159.59,63.3 159.7,63.41 160.16,63.41
+FBA_VREFC0 on BOTTOM (solid shape): 59.04,150.75 59.04,150.17 58.15,149.28 58.15,149.09 58.1,149.04 58.1,148.72 58.09,148.72 58.09,148.15 58.1,148.14 58.1,147.77 58.02,147.7 57.77,147.7 57.7,147.76 57.7,148.46 57.49,148.67 57.43,148.75 57.36,148.81 57.07,149.09 57.07,149.2 56.5,149.77 56.5,150.72 56.65,150.87 58.91,150.87
+FBA_VREFC0 on BOTTOM (solid shape): 58.08,120.87 58.17,120.78 58.28,120.73 58.29,120.73 59.27,119.75 59.27,119.74 59.34,119.68 59.34,116.3 59.21,116.17 58.77,116.17 58.64,116.3 58.64,119.56 58.46,119.73 58.36,120.02 58.07,120.12 57.79,120.4 57.79,120.77 57.89,120.87
+LAN_SROUT1.05 on BOTTOM (solid shape): 38.55,139.44 38.55,138.84 38.35,138.65 37.28,138.65 36.37,137.74 35.36,137.74 35.18,137.56 35.11,137.56 35.03,137.63 35.03,138.4 35.09,138.46 35.79,138.46 36.62,139.29 36.64,139.3 37.22,139.3 37.34,139.3 37.57,139.52 38.46,139.52
+LAN_VDD on BOTTOM (solid shape): 38.57,140.8 38.57,140.16 38.44,140.03 35.97,140.03 35.56,139.62 35.05,139.62 34.75,139.31 34.75,139.03 34.44,138.73 34.44,137.61 34.39,137.56 34.29,137.56 34.24,137.61 34.24,139.29 34.44,139.48 34.44,140.49 34.56,140.61 34.77,140.61 35.11,140.95 35.38,140.95 35.38,140.95 38.42,140.95
+LAN_VDD on IN1 (solid shape): outline of 311 points within 31.46,131.95 38.06,140.83
+LAN_VDDREG on TOP (solid shape): 36.31,139.24 38.45,139.24 38.55,139.13 38.55,138.65 38.46,138.56 35.06,138.56 34.89,138.73 34.89,139.32 35.05,139.49 36.06,139.49
+LAN_VDDREG on BOTTOM (solid shape): 35.94,139.31 35.94,138.88 35.69,138.63 35.05,138.63 34.85,138.42 34.85,137.61 34.8,137.56 34.7,137.56 34.65,137.61 34.65,138.7 34.9,138.96 34.9,139.26 35.05,139.41 35.84,139.41
+LCDVDD on TOP (solid shape): 31.08,149.76 31.08,147.6 30.95,147.48 29.76,147.48 29.38,147.85 29.38,148.23 29.24,148.38 29.24,149.76 29.33,149.86 30.99,149.86
+LCDVDD_CONN on TOP (solid shape): 32.22,152 32.22,150.34 31.97,150.08 31.27,150.08 30.83,150.52 30.83,150.64 30.75,150.72 29.36,150.72 29.36,151.73 29.49,151.86 31.44,151.86 31.71,152.14 32.08,152.14
+LCDVDD_CONN on BOTTOM (solid shape): 32.22,151.61 32.22,148.94 32.1,148.81 30.7,148.81 30.57,148.94 30.57,151.67 30.76,151.86 31.97,151.86
+LEDVDD on TOP (solid shape): 37.75,152.3 37.75,150.78 37.37,150.4 34.89,150.4 34.7,150.59 34.7,152.24 34.83,152.37 37.68,152.37
+LEDVDD on BOTTOM (solid shape): 37.62,151.67 37.62,149.07 37.37,148.81 35.78,148.81 35.52,149.07 35.52,151.67 35.71,151.86 37.43,151.86
+MPLL_PVDD on TOP (solid shape): 85.44,143.39 85.22,143.17 85.22,142.55 85.82,141.95 85.82,140.17 85.69,140.05 85.44,140.05 85.24,140.24 85.24,141.76 84.86,142.14 84.58,142.14 84.58,143.18 84.61,143.19 84.79,143.42 84.73,143.7 84.7,143.73 84.89,143.92 85.44,143.92
+MVREFDA on BOTTOM (solid shape): 91.19,120.69 91.19,119.55 91.09,119.45 89.77,119.45 89.77,120.01 90.53,120.01 90.63,120.11 90.63,120.19 90.53,120.29 90.2,120.29 90.12,120.36 90.12,120.67 90.2,120.74 91.14,120.74
+MVREFSA on BOTTOM (solid shape): 87,119.3 87.86,119.3 88.06,119.09 88.57,119.09 88.57,118.58 87.89,118.58 87.68,118.79 87.2,118.79 87.12,118.86 86.59,118.86 86.59,119.02 86.11,119.5 86.08,119.5 86.11,119.52 86.11,119.78 86.16,119.83 86.46,119.83
+SPLL_PVDD on TOP (solid shape): 81.24,147.99 81.24,147.1 81.63,146.72 81.82,146.72 81.82,146.14 82.01,145.95 82.01,145.64 81.88,145.51 81.75,145.51 80.61,146.65 80.61,147.92 80.8,148.11 81.12,148.11
+SPLL_PVDD on TOP (solid shape): 82.85,143.33 82.85,142.46 82.93,142.38 82.93,142.04 82.87,141.98 82.49,141.98 82.17,141.66 81.79,141.66 81.72,141.73 81.72,142.2 81.84,142.32 82.09,142.32 82.34,142.56 82.34,142.66 82.34,142.7 82.34,142.75 82.34,142.9 82.21,143.03 82.21,143.34 82.24,143.38 82.8,143.38
+TP_VCC on BOTTOM (solid shape): 173.62,21.18 173.62,20.39 173.48,20.25 173.25,20.25 173.05,20.05 173.05,19.09 173.19,18.95 173.19,17.75 173.13,17.68 172.4,17.68 172.08,18 172.08,21.17 172.13,21.22 173.58,21.22
+TSVDD on TOP (solid shape): 96.87,134.46 96.29,134.46 95.47,133.63 95.21,133.63 95.09,133.76 95.09,134.08 95.34,134.33 95.34,134.97 96.87,134.97
+USB3_VCCA on TOP (solid shape): outline of 151 points within 15.14,64.78 19.84,87.6
+USB3_VCCA on BOTTOM (solid shape): 19.97,87.03 19.97,84.99 19.78,84.8 19.52,84.8 19.4,84.93 19.4,86.01 19.14,86.26 18.38,86.26 17.49,85.37 15.46,85.37 15.14,85.69 15.14,87.09 15.39,87.34 19.65,87.34
+USB3_VCCA on BOTTOM (solid shape): 21.24,71.09 21.24,68.36 20.79,67.91 20.09,67.91 19.84,67.66 19.84,66.39 19.33,65.88 17.24,65.88 16.92,65.56 16.29,65.56 16.29,65.56 16.11,65.56 16.02,65.32 15.94,65.22 15.43,65.22 15.12,65.53 15.12,65.69 15.16,65.83 15.12,65.88 15.12,67.63 18.95,71.47 20.86,71.47
+VGA_CORE on TOP (solid shape): 83.21,115.98 83.21,114.77 81.56,113.12 81.56,107.22 81.88,106.9 82.7,106.9 82.7,105.25 82.26,104.81 76.67,104.81 73.05,108.42 73.05,115.41 73.56,115.92 80.1,115.92 80.29,116.11 83.09,116.11
+VGA_CORE on TOP (solid shape): 86.04,134.51 86.4,134.51 86.56,134.68 87.12,134.68 87.25,134.55 87.25,131.42 87.06,131.23 86.57,131.23 85.91,131.88 85.34,131.88 85.28,131.95 85.28,132.48 85.01,132.74 85.01,132.91 85.1,133 85.17,133 85.17,133.07 85.28,133.18 85.28,134.56 85.14,134.7 85.08,134.7 85.01,134.78 85.01,134.97 85.13,135.1 85.46,135.1
+VGA_CORE on TOP (solid shape): 89.98,141.68 89.98,141.03 89.93,140.98 89.21,140.98 89.11,140.88 89.11,139.34 89.27,139.18 89.82,139.18 89.89,139.18 89.97,139.26 89.97,139.8 90.14,139.98 90.56,139.98 90.74,139.79 90.74,139.21 90.32,138.79 90.32,134.84 90.74,134.43 90.74,132.87 90.74,132.73 91.39,132.08 91.39,130.94 91.68,130.64 91.68,130.15 91.62,130.08 90.53,130.08 90.17,130.45 90.17,131.02 89.99,131.2 89.43,131.2 89.36,131.27 89.35,131.27 89.29,131.34 89.29,132.9 89.49,133.1 89.49,134.29 89.32,134.47 88.26,134.47 88.1,134.63 88.1,134.85 88.23,134.98 88.39,134.98 88.6,135.19 88.6,138.51 88.35,138.76 88.35,140.15 88.36,140.24 88.35,140.32 88.35,140.85 88.4,140.95 88.4,141.06 88.4,141.08 89.04,141.73 89.93,141.73
+VGA_CORE on TOP (solid shape): outline of 89 points within 91.77,132.62 95.84,139.06
+VGA_CORE on BOTTOM (solid shape): outline of 195 points within 71.1,101.31 85.12,115.98
+VGA_CORE on BOTTOM (solid shape): outline of 604 points within 85.01,130.2 95.16,140.67
+VGA_CORE on IN1 (solid shape): outline of 2416 points within 85.05,129.38 97.25,143.6
+VGA_CORE on IN2 (solid shape): outline of 4421 points within 72.99,102.9 100.93,141.7
+VGA_CORE on VCC: 77.16,102.33 70.96,108.59 70.96,113.08 71.51,113.63 75.76,113.63 84.99,122.86 84.99,143.41 98.6,143.41 99.15,142.86 99.15,118.82 82.66,102.33
+VL on TOP (solid shape): 170.18,21.04 170.18,20.11 170.06,19.98 169.17,19.98 169.04,20.11 169.04,21.09 169.08,21.13 170.09,21.13
APDIN on TOP (solid shape): 17.87,154.61 17.87,154.14 16.71,152.98 16.71,150.95 16.14,150.38 16.14,147.72 16.4,147.46 17.42,147.46 17.57,147.31 17.57,145.3 17.28,145.01 14.31,145.01 14.13,145.19 14.13,146.97 13.05,148.05 13.05,151.57 14.75,153.27 14.77,153.26 16.09,153.63 16.68,154.87 16.68,154.92 17.55,154.92
B+ on TOP (solid shape): 144.3,69.9 144.3,66.71 144.11,66.51 138.62,66.51 138.3,66.84 138.3,70.01 138.43,70.14 144.06,70.14
B+ on TOP (solid shape): 74.01,15.02 73.94,14.95 72.23,14.95 71.97,15.21 71.97,16.66 74.01,16.66
B+ on TOP (solid shape): 144.3,56.04 143.79,55.53 140.55,55.53 140.24,55.85 140.24,59.21 144.3,59.21
B+ on TOP (solid shape): 41.24,156.32 41.24,155.41 41.8,155.41 41.8,154.96 41.26,154.96 41.26,154.21 41.8,154.21 41.8,153.77 41.24,153.77 41.24,153 41.19,152.95 39.97,152.95 39.66,152.64 39.66,150.93 39.43,150.71 38.77,150.71 38.61,150.87 38.61,152.33 38.23,152.71 35.52,152.71 35.26,152.97 35.26,153.55 36.95,153.55 36.95,154.44 35.26,154.44 35.26,156.06 35.7,156.49 41.07,156.49
B+ on TOP (solid shape): outline of 85 points within 120.45,20.94 129.5,24.16
B+ on BOTTOM (solid shape): 153.89,24.35 153.89,22.95 153.7,22.76 151.79,22.76 151.67,22.89 151.67,24.31 151.91,24.55 153.69,24.55
B+ on BOTTOM (solid shape): 39.02,100.11 38.89,99.98 36.86,99.98 36.69,100.14 36.69,101.45 36.87,101.63 39.02,101.63
B+ on BOTTOM (solid shape): 62.83,112.23 62.7,112.11 62.07,112.11 61.75,111.79 60.99,111.79 60.8,111.98 60.8,113.38 61.05,113.63 62.83,113.63
B+ on BOTTOM (solid shape): 135.98,27.14 135.98,23.27 135.66,22.95 130.27,22.95 129.38,22.06 123.85,22.06 123.82,22.1 123.82,23.27 123.63,23.46 123.62,23.52 123.6,23.59 123.6,26.38 124.93,27.72 135.41,27.72
B+ on BOTTOM (solid shape): 163.54,30.89 163.54,28.16 162.08,28.16 161.57,27.65 161.06,27.65 161.06,28.29 161.03,28.33 161.03,28.44 160.99,28.48 160.98,28.53 160.81,28.91 160.42,29.02 160.37,29.16 160.28,29.28 160.02,29.54 160.02,30.61 160.56,31.15 163.29,31.15
B+ on VCC: 127.77,68.48 123.58,72.67 117.04,72.67 114.43,75.28 112.78,75.28 110.2,77.86 110.2,83.57 96.34,97.44 72.44,97.44 69.01,94.01 40.07,94.01 37.09,96.99 33.92,96.99 31.4,99.51 31.4,109.91 33.66,112.17 40.52,112.17 42.76,114.42 42.76,135.9 37.36,141.3 37.36,155.05 37.73,155.41 39.8,155.41 39.91,155.31 39.91,143.25 46.07,137.09 46.07,111.96 43.97,109.86 43.97,98.79 45.45,97.31 65.41,97.31 67.53,99.43 67.53,104.72 60.8,111.45 60.8,113.4 61.09,113.7 67.23,113.7 67.78,113.15 67.78,110.92 68.5,110.2 70.45,110.2 70.45,108.38 76.95,101.82 97.71,101.82 111.81,87.72 112.51,87.72 118.91,80.11 127.09,74.46 127.35,74.33 127.35,72.81 127.89,71.15 129.32,70.14 132.27,70.14 132.27,70.14 143.66,70.14 143.66,68.78 143.37,68.48 ; 1 cut-out
B+ on VCC: 126.27,20.6 126.27,25.2 126.69,25.62 134.25,25.62 136.87,28.25 136.87,50.85 140.3,54.28 140.3,56.31 140.85,56.86 146.67,56.86 149.76,53.77 149.76,34.91 150.86,33.81 160.26,33.81 163.41,30.66 163.41,26.87 163.05,26.51 157.21,26.51 156.49,25.79 156.49,20.6
B+_1.35V on TOP (solid shape): 44.73,155.67 44.73,154.97 45.03,154.67 45.03,151.24 45.03,151.24 45.03,149.73 45.03,149.73 45.03,147.2 44.95,147.12 43.49,147.12 43.43,147.19 43.43,147.99 42.86,148.56 42.26,148.56 42.26,149.06 41.81,149.51 41.62,149.51 41.62,151.08 41.43,151.27 41.43,153.61 41.97,153.61 41.97,154.36 41.43,154.36 41.43,154.82 41.97,154.82 41.97,155.57 41.43,155.57 41.43,156.07 41.47,156.11 44.29,156.11
BST1_APU on BOTTOM (solid shape): 151.46,45.69 151.46,44.49 151.72,44.24 152.53,44.24 152.58,44.19 152.58,44.06 152.53,44.01 151.62,44.01 150.45,45.18 150.45,46.07 151.08,46.07
BST1_APU_R on BOTTOM (solid shape): 150.22,45.79 150.22,44.42 150.11,44.31 149.24,44.31 149.19,44.36 149.19,45.06 149.08,45.18 149.08,46.07 149.94,46.07
BST1_VGA on BOTTOM (solid shape): 57.69,111.57 57.69,110.39 57.25,109.96 57.25,109.15 57.22,109.11 57.06,109.11 57.03,109.15 57.03,110.09 57.12,110.4 56.92,110.66 56.92,111.56 56.99,111.63 57.64,111.63
BST1_VGA_R on BOTTOM (solid shape): 60.19,111.45 60.19,110.75 60.11,110.67 58.35,110.67 58.35,111.56 60.07,111.56
BST_1.35V on TOP (solid shape): 45.93,149.18 45.93,147.65 45.42,147.13 45.27,147.13 45.21,147.19 45.21,148.46 45.35,148.6 45.35,149.18 45.37,149.19 45.93,149.19
BST_1.35V_R on TOP (solid shape): 45.74,151.19 45.74,150.29 45.94,150.09 45.94,149.59 45.93,149.57 45.35,149.57 45.21,149.72 45.21,149.73 45.15,149.78 45.15,151.19 45.19,151.22 45.71,151.22
BST_1V on TOP (solid shape): 69.18,16.22 69.18,15.59 69.12,15.52 68.61,15.52 68.29,15.84 67.79,15.84 67.79,15.85 67.34,15.85 67.11,16.08 67.11,16.2 67.19,16.29 69.12,16.29
BST_1V_R on TOP (solid shape): 70.93,16.29 70.93,16.19 70.93,16.19 70.93,15.72 70.89,15.67 70.22,15.67 70.07,15.52 69.62,15.52 69.56,15.59 69.56,16.16 69.71,16.31 70.91,16.31
BST_3V on BOTTOM (solid shape): 157.9,23.15 157.9,23.02 157.8,22.92 156.78,22.92 156.52,22.65 155.88,22.65 155.86,22.67 155.86,23.18 155.91,23.23 157.82,23.23
BST_3V_R on BOTTOM (solid shape): 156.47,22.24 156.47,21.74 156.19,21.46 155.22,21.46 155.08,21.6 155.08,22.05 155.09,22.07 155.61,22.07 155.81,22.27 156.45,22.27
BST_5V on BOTTOM (solid shape): 166.17,23.89 167.03,23.89 167.1,23.82 167.1,23.68 166.99,23.58 165.98,23.58 165.78,23.38 165.16,23.38 165.13,23.42 165.13,23.91 165.15,23.93 166.13,23.93
BST_5V_R on BOTTOM (solid shape): 164.87,23.61 164.87,23.26 165.16,22.98 165.68,22.98 165.7,22.96 165.7,22.47 165.68,22.45 165,22.45 164.95,22.5 164.95,22.82 164.71,23.06 164.29,23.06 164.19,23.15 164.19,23.68 164.22,23.71 164.77,23.71
BST_CHG on BOTTOM (solid shape): 145.21,21.15 145.21,19.94 146.57,18.59 146.57,18.34 146.52,18.29 145.74,18.29 145.67,18.36 145.67,18.65 144.53,19.79 144.53,19.9 144.53,19.91 144.53,21.15 144.55,21.18 145.19,21.18
BST_CHG_R on BOTTOM (solid shape): 143.86,21.11 143.86,20.27 144.15,19.98 144.15,19.3 144.12,19.27 143.28,19.27 143.16,19.4 143.16,21.18 143.18,21.2 143.77,21.2
BST_DDR on BOTTOM (solid shape): 36.71,113.56 36.71,112.74 36.76,112.69 36.76,112.23 37.42,111.57 37.42,110.53 36.78,110.53 36.48,110.84 36.48,113.56 36.53,113.61 36.65,113.61
BST_DDR_R on BOTTOM (solid shape): 40.03,111.32 40.03,110.51 38.23,110.51 38.2,110.53 38.2,111.42 39.93,111.42
BST_NB on BOTTOM (solid shape): 152.99,40.94 152.99,40.2 152.91,40.12 152.38,40.12 151.82,39.57 151.31,39.57 151.03,39.29 150.4,39.29 150.4,40.18 151.69,40.18 152.53,41.01 152.91,41.01
BST_NB_R on BOTTOM (solid shape): 149.24,41.09 149.24,40.56 149.63,40.18 149.63,39.29 149.61,39.26 149,39.26 148.95,39.31 148.95,40.03 148.62,40.36 148.62,41.08 148.69,41.15 149.18,41.15
DP_VSSR on IN2 (solid shape): outline of 479 points within 96.74,127.98 102.83,137.49
ECAGND on TOP (solid shape): 161.5,62.22 161.67,62.22 161.67,62.02 161.6,61.94 158.46,61.94 158.4,62.01 158.4,62.45 158.5,62.55 161.17,62.55
EXT_MIC_RING2 on BOTTOM (solid shape): 20.22,48.42 20.22,46.83 20.09,46.7 19.33,46.7 19.2,46.83 19.2,48.42 19.26,48.48 20.16,48.48
EXT_MIC_RING2 on BOTTOM (solid shape): 8.57,29.97 8.57,29.36 8.79,29.14 8.79,28.34 9.02,28.11 9.02,26.98 8.97,26.93 8.83,26.93 8.79,26.97 8.79,27.18 8.79,27.89 7.94,28.73 7.94,29.97 8,30.03 8.51,30.03
EXT_MIC_RING2 on IN1 (solid shape): 20.22,47.91 20.22,46.83 20.09,46.7 19.33,46.7 19.2,46.83 19.2,47.53 18.82,47.91 18.82,48.61 18.95,48.73 19.4,48.73
EXT_MIC_RING2 on IN1 (solid shape): 9.4,30.49 9.4,30.22 8.66,29.48 8.66,28.44 8.56,28.33 7.99,28.33 7.78,28.55 7.78,30.12 8.61,30.95 8.93,30.95
EXT_MIC_SLEEVE on BOTTOM (solid shape): 18.32,46.64 18.32,46.19 18.06,45.94 16.22,45.94 16.09,46.07 16.09,46.7 16.16,46.77 18.19,46.77
EXT_MIC_SLEEVE on BOTTOM (solid shape): 9.47,29.95 9.47,29.46 9.4,29.39 9.4,27.19 9.4,27.19 9.4,26.99 9.36,26.95 9.24,26.95 9.19,27 9.19,27.91 9.16,27.94 9.16,28.17 8.94,28.39 8.94,29.35 8.83,29.47 8.83,29.97 8.89,30.03 9.4,30.03
EXT_MIC_SLEEVE on IN1 (solid shape): 18.32,46.7 18.32,46.39 18.82,45.88 18.82,45.37 17.81,45.37 17.81,45.5 17.3,46 17.3,46.7 17.43,46.83 18.19,46.83
EXT_MIC_SLEEVE on IN1 (solid shape): 10.57,29.3 10.07,28.81 9.91,28.81 9.58,28.48 9.58,28.32 9.53,28.26 9.07,28.26 8.97,28.36 8.97,29.24 9.03,29.3 9.17,29.3 10,30.13 10.57,30.13
HGNDA on BOTTOM (solid shape): 19.52,51.4 19.52,49.81 19.97,49.37 19.97,48.86 19.9,48.8 18.38,48.8 18.32,48.86 18.32,49.37 18.63,49.69 18.63,50.2 18.57,50.26 18.06,50.26 17.93,50.39 17.93,51.4 18.13,51.59 19.33,51.59
HGNDA on IN1 (solid shape): 18.38,51.21 18.38,50.39 18.25,50.26 17.11,50.26 16.92,50.45 16.92,50.96 17.3,51.34 18.25,51.34
HGNDB on BOTTOM (solid shape): 17.62,51.34 17.62,49.94 16.92,49.24 16.92,47.21 16.79,47.08 16.03,47.08 15.84,47.27 15.84,49.5 16.6,50.26 16.6,50.45 16.47,50.58 15.44,50.58 15.32,50.7 15.32,51.39 15.52,51.59 17.36,51.59
HGNDB on IN1 (solid shape): 16.47,51.52 16.47,51.21 15.59,50.32 15.08,50.32 14.76,50.64 14.76,51.15 15.27,51.66 16.34,51.66
HGNDB on IN1 (solid shape): 5.87,50.45 5.74,50.32 5.17,50.32 4.73,49.88 4.73,49.31 3.01,49.31 3.01,49.66 3.67,50.22 4.06,50.99 4.41,51.34 5.87,51.34
LANGAN on TOP (solid shape): 17.55,136.36 17.36,136.17 13.68,136.17 11.78,134.27 11.78,134.14 11.58,133.95 9.68,133.95 9.43,134.21 9.43,135.67 9.24,135.86 4.41,135.86 3.96,135.41 3.96,134.08 3.9,134.02 2.31,134.02 2.19,134.14 2.19,134.46 2.19,134.46 2.19,134.7 2.73,135.23 3.05,135.9 4.6,137.44 17.55,137.44
LANGAN on BOTTOM (solid shape): 16.66,138.21 16.66,135.48 16.6,135.41 12.92,135.41 11.78,134.27 11.78,134.08 11.65,133.95 9.55,133.95 9.43,134.08 9.43,136.49 10.38,137.44 13.68,137.44 14.51,138.27 16.6,138.27
LANGAN1 on TOP (solid shape): 11.71,118.33 11.71,117.95 10.82,117.06 10.82,115.73 10.57,115.47 4.17,115.47 4.02,116.78 3.14,117.77 2.96,117.95 2.57,117.95 2.57,118.33 3.9,118.33 4.4,117.83 4.4,116.5 8.54,116.5 8.54,117.32 9.62,118.39 11.65,118.39
LANGAN1 on BOTTOM (solid shape): 11.71,118.33 11.71,117.95 10.82,117.06 10.82,115.73 10.57,115.47 4.17,115.47 4.02,116.78 3.14,117.77 2.96,117.95 2.57,117.95 2.57,118.33 3.9,118.33 4.4,117.83 4.4,116.5 8.54,116.5 8.54,117.32 9.62,118.39 11.65,118.39
LDO_3V on TOP (solid shape): 65.61,15.95 65.69,15.87 65.69,14.85 65.56,14.72 65.56,13.89 65.48,13.81 64.99,13.81 64.92,13.87 64.92,15.82 65.05,15.95 65.58,15.95
LDO_3V_1.35V on TOP (solid shape): 47.68,145.57 47.68,145 47.62,144.94 45.72,144.94 45.53,145.13 45.53,145.57 45.65,145.7 47.56,145.7
LG1_APU on BOTTOM (solid shape): 140.43,47.59 140.43,46.64 140.17,46.39 139.35,46.39 139.09,46.64 139.09,47.4 139.41,47.72 140.3,47.72
LG1_APU on BOTTOM (solid shape): 152.58,42.98 152.58,42.85 152.53,42.8 151.67,42.8 151.63,42.77 151.21,42.77 151.03,42.59 150.14,42.59 150.07,42.66 150.07,42.94 150.15,43.03 152.53,43.03
LG1_APU on IN1 (solid shape): 140.46,47.52 140.46,46.63 140.39,46.55 139.35,46.55 139.22,46.68 139.22,47.44 139.37,47.59 140.39,47.59
LG1_APU on IN1 (solid shape): 149.56,43.05 150.98,43.05 151.11,42.92 151.11,42.66 151.01,42.56 149.89,42.56 149.68,42.36 148.8,42.36 148.44,42.72 148.44,43.35 148.47,43.38 149.23,43.38
LG1_VGA on BOTTOM (solid shape): 63.15,105 63.65,105 63.78,104.87 63.78,104.36 63.21,103.79 62.26,103.79 62.11,103.94 62.11,105.24 62.18,105.31 62.83,105.31
LG1_VGA on BOTTOM (solid shape): 60.02,109.01 60.02,108.7 59.92,108.6 59.29,108.6 59.03,108.35 57.84,108.35 57.79,108.4 57.79,108.53 57.84,108.58 58.65,108.58 59.18,109.11 59.92,109.11
LG1_VGA on IN2 (solid shape): 63.48,105.55 63.48,104.06 63.3,103.88 62.56,103.88 62.46,103.98 62.46,105.55 62.49,105.58 63.45,105.58
LG1_VGA on IN2 (solid shape): 60.73,109.29 60.81,109.21 60.81,108.6 60.78,108.58 59.06,108.58 58.93,108.7 58.93,109.44 59.08,109.59 60.73,109.59
LG_CHG on BOTTOM (solid shape): 138.15,14.72 138.15,14.04 137.95,13.84 137.13,13.84 137.04,13.93 137.04,14.6 137.29,14.85 138.03,14.85
LG_CHG on BOTTOM (solid shape): 145.42,17.32 146.48,17.32 146.59,17.21 146.59,17.14 146.54,17.09 145.24,17.09 145.19,17.04 144.3,17.04 144.22,17.11 144.22,17.39 144.35,17.52 145.21,17.52
LG_CHG on IN2 (solid shape): 138.76,14.67 138.76,13.91 138.75,13.9 138.01,13.9 137.92,13.81 137.11,13.81 137.01,13.91 137.01,14.19 137.52,14.7 138.74,14.7
LG_CHG on IN2 (solid shape): 145.34,17.39 145.34,17.19 144.86,16.71 144.06,16.71 143.6,16.25 143.23,16.25 143.21,16.27 143.21,16.93 143.28,17.01 143.66,17.01 144.17,17.52 145.21,17.52
LG_DDR on TOP (solid shape): 40.22,109.31 40.22,109.06 40.16,109 40.16,108.55 40.03,108.42 39.27,108.42 39.14,108.55 39.14,109.31 39.27,109.44 40.1,109.44
LG_DDR on BOTTOM (solid shape): 39.14,113.5 39.14,112.97 38.99,112.82 38.69,112.82 37.7,113.81 37.7,113.96 37.75,114.01 38.64,114.01
LG_DDR on IN2 (solid shape): 40.22,109.06 40.1,108.93 39.27,108.93 39.14,109.06 39.14,109.95 39.21,110.01 40.22,110.01
LG_DDR on IN2 (solid shape): 39.02,113.7 39.21,113.7 40.22,112.68 40.22,112.3 39.21,112.3 38.13,113.38 38.13,113.7 38.25,113.82 38.89,113.82
LG_NB on BOTTOM (solid shape): 143.8,36.81 143.8,35.73 143.66,35.59 141.38,35.59 141.25,35.72 141.25,36.67 141.38,36.8 142.57,36.8 142.7,36.92 142.71,36.92 142.75,36.97 143.64,36.97
LG_NB on BOTTOM (solid shape): 151.72,42.23 152.53,42.23 152.58,42.18 152.58,42.05 152.53,42 151.54,42 151.21,41.67 150.83,41.67 150.73,41.57 150.14,41.57 150.07,41.65 150.07,41.98 150.22,42.13 151.23,42.13 151.39,42.28 151.67,42.28
LG_NB on IN2 (solid shape): 144.63,37.38 144.63,36.8 144.17,36.34 142.78,36.34 142.65,36.47 142.65,37 142.83,37.18 143.56,37.18 143.87,37.48 144.53,37.48
LG_NB on IN2 (solid shape): 151.13,42.18 151.13,41.78 151.03,41.67 150.65,41.67 150.5,41.52 148.49,41.52 148.47,41.55 148.47,42.05 148.69,42.28 151.03,42.28
LX1_APU on BOTTOM (solid shape): 150.65,43.63 150.93,43.63 151.08,43.48 151.64,43.48 151.69,43.43 152.53,43.43 152.58,43.38 152.58,43.27 152.53,43.22 151.69,43.22 151.64,43.17 150.22,43.17 150.01,43.38 149.27,43.38 149.21,43.44 149.21,43.91 149.22,43.92 150.36,43.92
LX1_APU on BOTTOM (solid shape): 144.36,54.26 146.27,54.26 146.46,54.07 146.46,50.77 146.2,50.51 145,50.51 144.3,49.81 144.3,48.54 139.85,48.54 138.9,47.59 138.9,44.92 138.2,44.23 136.93,44.23 136.62,43.91 136.62,42.13 136.49,42 135.47,42 135.47,46.77 135.85,47.15 136.81,47.15 136.81,48.04 135.28,48.04 134.9,48.42 134.9,52.48 135.28,52.86 138.08,52.86 138.65,53.43 138.65,54.32 139.16,54.83 143.79,54.83
LX1_APU on IN2 (solid shape): 140.45,49.42 140.45,48.43 140.4,48.38 139.28,48.38 139.16,48.51 139.16,49.32 139.28,49.45 140.43,49.45
LX1_APU on IN2 (solid shape): 150.47,43.73 150.83,43.73 151.03,43.53 151.03,43.27 150.93,43.17 149.58,43.17 149.02,43.73 149.02,44.09 149.35,44.42 149.79,44.42
LX1_VGA on BOTTOM (solid shape): 60.89,109.19 60.86,109.16 60.45,109.16 60.38,109.24 59.04,109.24 58.55,108.74 57.88,108.74 57.81,108.81 57.81,108.91 58.04,109.14 58.22,109.14 59.13,110.05 60.89,110.05
LX1_VGA on BOTTOM (solid shape): 71.21,108.04 71.21,106.84 70.26,106.84 70.26,106.01 70.32,105.95 71.21,105.95 71.27,105.88 71.27,100.87 71.15,100.74 70,100.74 69.88,100.87 69.88,103.6 68.1,105.38 63.34,105.38 63.27,105.44 63.27,107.98 63.4,108.11 71.15,108.11
LX_1.35V on TOP (solid shape): 43.24,147.92 43.24,147.1 43.3,147.03 43.3,146.84 43.24,146.78 42.54,146.78 42.16,147.16 42.16,148.11 42.35,148.3 42.86,148.3
LX_1.35V on TOP (solid shape): 47.75,150.08 47.75,147.54 46.54,146.33 45.65,146.33 45.59,146.4 45.59,147.03 45.72,147.16 45.84,147.16 46.1,147.41 46.1,150.14 45.87,150.37 45.87,151.07 46.01,151.21 46.62,151.21
LX_1.35V on BOTTOM (solid shape): 47.75,150.05 47.75,147.13 47.46,146.84 46.32,146.84 45.87,146.4 45.87,144.56 44.86,144.56 44.86,146.72 44.41,147.16 42.38,147.16 42.19,147.35 42.19,150.02 42.57,150.4 47.4,150.4
LX_1V on TOP (solid shape): 68.29,19.14 68.29,18.64 67.91,18.25 67.11,18.25 67.01,18.15 66.84,18.15 66.77,18.22 66.77,18.95 67.15,19.33 68.1,19.33
LX_1V on TOP (solid shape): 67.21,15.71 68.23,15.71 68.54,15.4 70.77,15.4 70.94,15.22 70.94,14.49 70.51,14.06 67.21,14.06 66.32,14.95 66.32,15.87 66.41,15.95 66.97,15.95
LX_1V on BOTTOM (solid shape): 70.7,18.95 70.7,16.79 71.15,16.35 73.18,16.35 73.43,16.1 73.43,15.08 71.34,15.08 70.32,14.06 67.34,14.06 66.83,14.57 66.83,18.89 67.21,19.27 70.39,19.27
LX_3V on TOP (solid shape): 158.08,26.07 158.08,25.12 158.08,24.35 157.63,23.91 157.63,21.68 157.51,21.56 156.94,21.56 155.79,22.7 155.79,23.88 157,25.09 157,26.07 157.19,26.26 157.89,26.26
LX_3V on BOTTOM (solid shape): 158.69,22.83 158.69,22.04 158.65,22 158.65,21.37 159.2,20.82 159.44,20.82 159.73,20.53 159.73,18.8 159.54,18.61 155.56,18.61 155.09,19.08 155.09,21.11 155.22,21.24 156.43,21.24 156.81,21.62 156.81,22.45 157.13,22.76 157.89,22.76 158.02,22.89 158.62,22.89
LX_5V on TOP (solid shape): 167.1,26.51 167.1,25.11 165.45,23.46 165.45,21.68 165.57,21.56 165.57,19.91 164.11,19.91 163.86,20.16 163.86,22.06 164.62,22.83 164.62,23.97 166.08,25.43 166.08,26.76 166.21,26.89 166.72,26.89
LX_5V on BOTTOM (solid shape): 167.43,26.59 167.43,25.84 167.36,25.77 167.24,25.77 167.02,25.99 166.56,25.99 166.07,26.48 166.07,26.79 166.16,26.88 167.13,26.88
LX_5V on BOTTOM (solid shape): 167.88,23.47 167.88,21.62 168.49,21.01 168.49,18.83 168.23,18.56 164.44,18.56 163.73,19.27 163.73,22.11 164.05,22.43 164.05,22.43 164.05,22.69 164.13,22.77 164.78,22.77 164.79,22.75 164.79,22.43 164.93,22.29 165.6,22.29 165.6,22.3 165.79,22.3 165.86,22.37 165.86,23.2 166.04,23.39 167.08,23.39 167.24,23.54 167.82,23.54
LX_CHG on BOTTOM (solid shape): 137.57,18.89 137.57,17.56 136.55,16.54 136.55,14.51 136.31,14.27 135.62,14.27 133.95,12.6 133.95,11.59 127.22,11.59 127.22,13.94 128.23,14.95 131.03,14.95 133.76,17.68 134.9,17.68 135.22,18 135.22,18.89 135.41,19.08 137.38,19.08
LX_CHG on BOTTOM (solid shape): 144.15,18.53 144.15,18.41 144.43,18.13 145.19,18.13 145.62,17.7 146.51,17.7 146.57,17.63 146.57,17.56 146.51,17.49 145.52,17.49 145.34,17.67 144.3,17.67 144.25,17.72 143.44,17.72 143.26,17.9 143.26,18.53 143.28,18.56 144.12,18.56
LX_CHG on IN2 (solid shape): 134.77,16.78 134.77,16.27 134.5,15.99 133.68,15.99 133.61,16.07 133.61,16.96 133.73,17.09 134.47,17.09
LX_CHG on IN2 (solid shape): 144.22,18.13 145.19,18.13 145.32,18 145.32,17.77 145.21,17.67 143.74,17.67 143.61,17.54 143.18,17.54 143.16,17.57 143.16,18.28 143.18,18.31 144.05,18.31
LX_DDR on TOP (solid shape): 38.76,112.43 38.76,111.47 38.51,111.22 38.51,106.58 39.02,106.08 39.02,104.36 38.89,104.23 37.37,104.23 37.24,104.36 37.24,105.31 37.05,105.5 35.33,105.5 35.08,105.76 35.08,110.96 35.46,111.35 37.56,111.35 38,111.79 38,112.23 37.62,112.62 37.62,113.06 37.75,113.19 38,113.19
LX_DDR on BOTTOM (solid shape): 37.61,113.44 37.75,113.44 38.64,112.55 40.03,112.55 40.03,111.92 39.95,111.83 38.53,111.83 37.62,112.74 37.37,112.74 37.3,112.81 37.3,113.54 37.37,113.61 37.44,113.61
LX_DDR on BOTTOM (solid shape): 38.83,109.89 38.83,108.55 39.14,108.23 39.65,108.23 39.65,104.74 39.59,104.68 37.24,104.68 36.54,105.38 35.4,105.38 35.08,105.69 35.08,109.89 35.33,110.14 38.57,110.14
LX_NB on BOTTOM (solid shape): 140.43,34.19 140.24,34 136.81,34 136.55,34.26 136.55,35.15 136.36,35.34 134.58,35.34 134.2,34.96 134.2,32.67 133.19,32.67 133.19,34.32 132.36,35.15 132.36,37.88 133.31,37.88 133.31,38.77 132.36,38.77 132.36,40.35 132.62,40.61 140.43,40.61
LX_NB on BOTTOM (solid shape): 152.58,41.78 152.58,41.67 152.53,41.62 151.74,41.62 150.6,40.48 149.61,40.48 149.56,40.53 149.56,41.11 149.56,41.11 149.88,41.11 150.14,41.37 150.73,41.37 150.9,41.55 151.28,41.55 151.56,41.83 152.53,41.83
LX_NB on IN1 (solid shape): 137.98,36.14 137.98,35.15 137.47,35.15 137.29,34.97 136.81,34.97 136.65,35.12 136.65,35.98 136.83,36.16 137.95,36.16
LX_NB on IN1 (solid shape): 151.26,41.45 151.26,41.11 151.16,41.01 150.95,41.01 150.75,40.81 150.35,40.81 149.86,40.33 149.58,40.33 149.1,40.81 149.1,40.99 149.53,41.42 150.62,41.42 150.75,41.55 151.16,41.55
MCT on TOP (solid shape): 20.86,135.54 20.86,133.57 20.67,133.38 19.4,133.38 19.2,133.57 19.2,135.54 19.33,135.67 20.73,135.67
MCT on BOTTOM (solid shape): 22.57,138.21 22.57,134.02 24.98,131.6 24.98,122.27 24.48,121.76 21.43,121.76 21.3,121.89 21.3,122.2 21.43,122.33 23.65,122.33 23.9,122.59 23.9,124.49 23.65,124.74 21.43,124.74 21.3,124.87 21.3,125.25 21.43,125.38 23.71,125.38 23.9,125.57 23.9,127.54 23.71,127.73 21.49,127.73 21.3,127.92 21.3,128.24 21.43,128.36 23.71,128.36 23.9,128.55 23.9,130.52 23.69,130.74 21.45,130.74 18.82,133.37 18.82,138.25 18.9,138.33 22.45,138.33
Net_1 on BOTTOM (solid shape): 106.57,99.12 98.57,99.12 98.57,107.12 106.57,107.12
OPCN_CHG on BOTTOM (solid shape): 148.49,21.56 148.49,20.69 148.47,20.67 148.16,20.67 148.01,20.52 148.01,20.08 148.14,19.96 148.14,19.55 148.08,19.5 148.08,18.66 148.03,18.61 147.91,18.61 147.86,18.66 147.86,19.8 147.53,20.13 147.53,21.4 147.7,21.58 148.47,21.58
OPCP_CHG on BOTTOM (solid shape): 147.37,21.43 147.37,20.08 147.7,19.75 147.7,19.47 147.68,19.45 147.68,18.66 147.63,18.61 147.5,18.61 147.45,18.66 147.45,19.55 146.46,20.54 146.46,21.58 147.22,21.58
SNB_APU on BOTTOM (solid shape): 139.16,43.46 139.35,43.27 140.11,43.27 140.11,42.26 139.85,42 138.14,42 138.14,43.65 139.16,43.65
SNB_APU_NB on BOTTOM (solid shape): 131.6,34.45 131.6,32.73 131.54,32.66 129.7,32.66 129.54,32.83 129.54,33.96 129.48,34.02 129.48,34.47 129.56,34.55 131.5,34.55
SNB_VGA1 on BOTTOM (solid shape): 69.31,103.54 69.31,101.19 68.86,100.74 67.34,100.74 67.34,102.39 68.29,102.39 68.48,102.58 68.48,103.66 69.18,103.66
SNUB_1.35V on BOTTOM (solid shape): 43.21,144.56 42.98,144.33 41.24,144.33 41.18,144.39 41.18,144.88 41.24,144.94 41.72,144.94 42.05,145.27 42.05,146.07 42.19,146.21 43.21,146.21
SNUB_1V on BOTTOM (solid shape): 72.54,19.91 72.54,19.02 72.8,18.76 73.43,18.76 73.43,17.75 71.85,17.75 71.78,17.81 71.78,20.03 72.42,20.03
SPK_L1- on TOP (solid shape): 40.06,13.7 40.06,12.67 39.59,12.67 39.26,12.35 38.87,12.35 38.76,12.46 38.76,13.38 39.14,13.76 40,13.76
